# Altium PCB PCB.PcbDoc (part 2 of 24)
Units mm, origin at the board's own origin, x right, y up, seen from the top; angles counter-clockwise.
Board outline 100 x 160 mm, 10 copper layers (TOP_L1, L2, L3, L4, L5, L6, L7, L8, L9, BOTTOM_L10), stack 1.946 mm thick; 1358 components, 1149 nets, 6777 pads, 10914 vias.

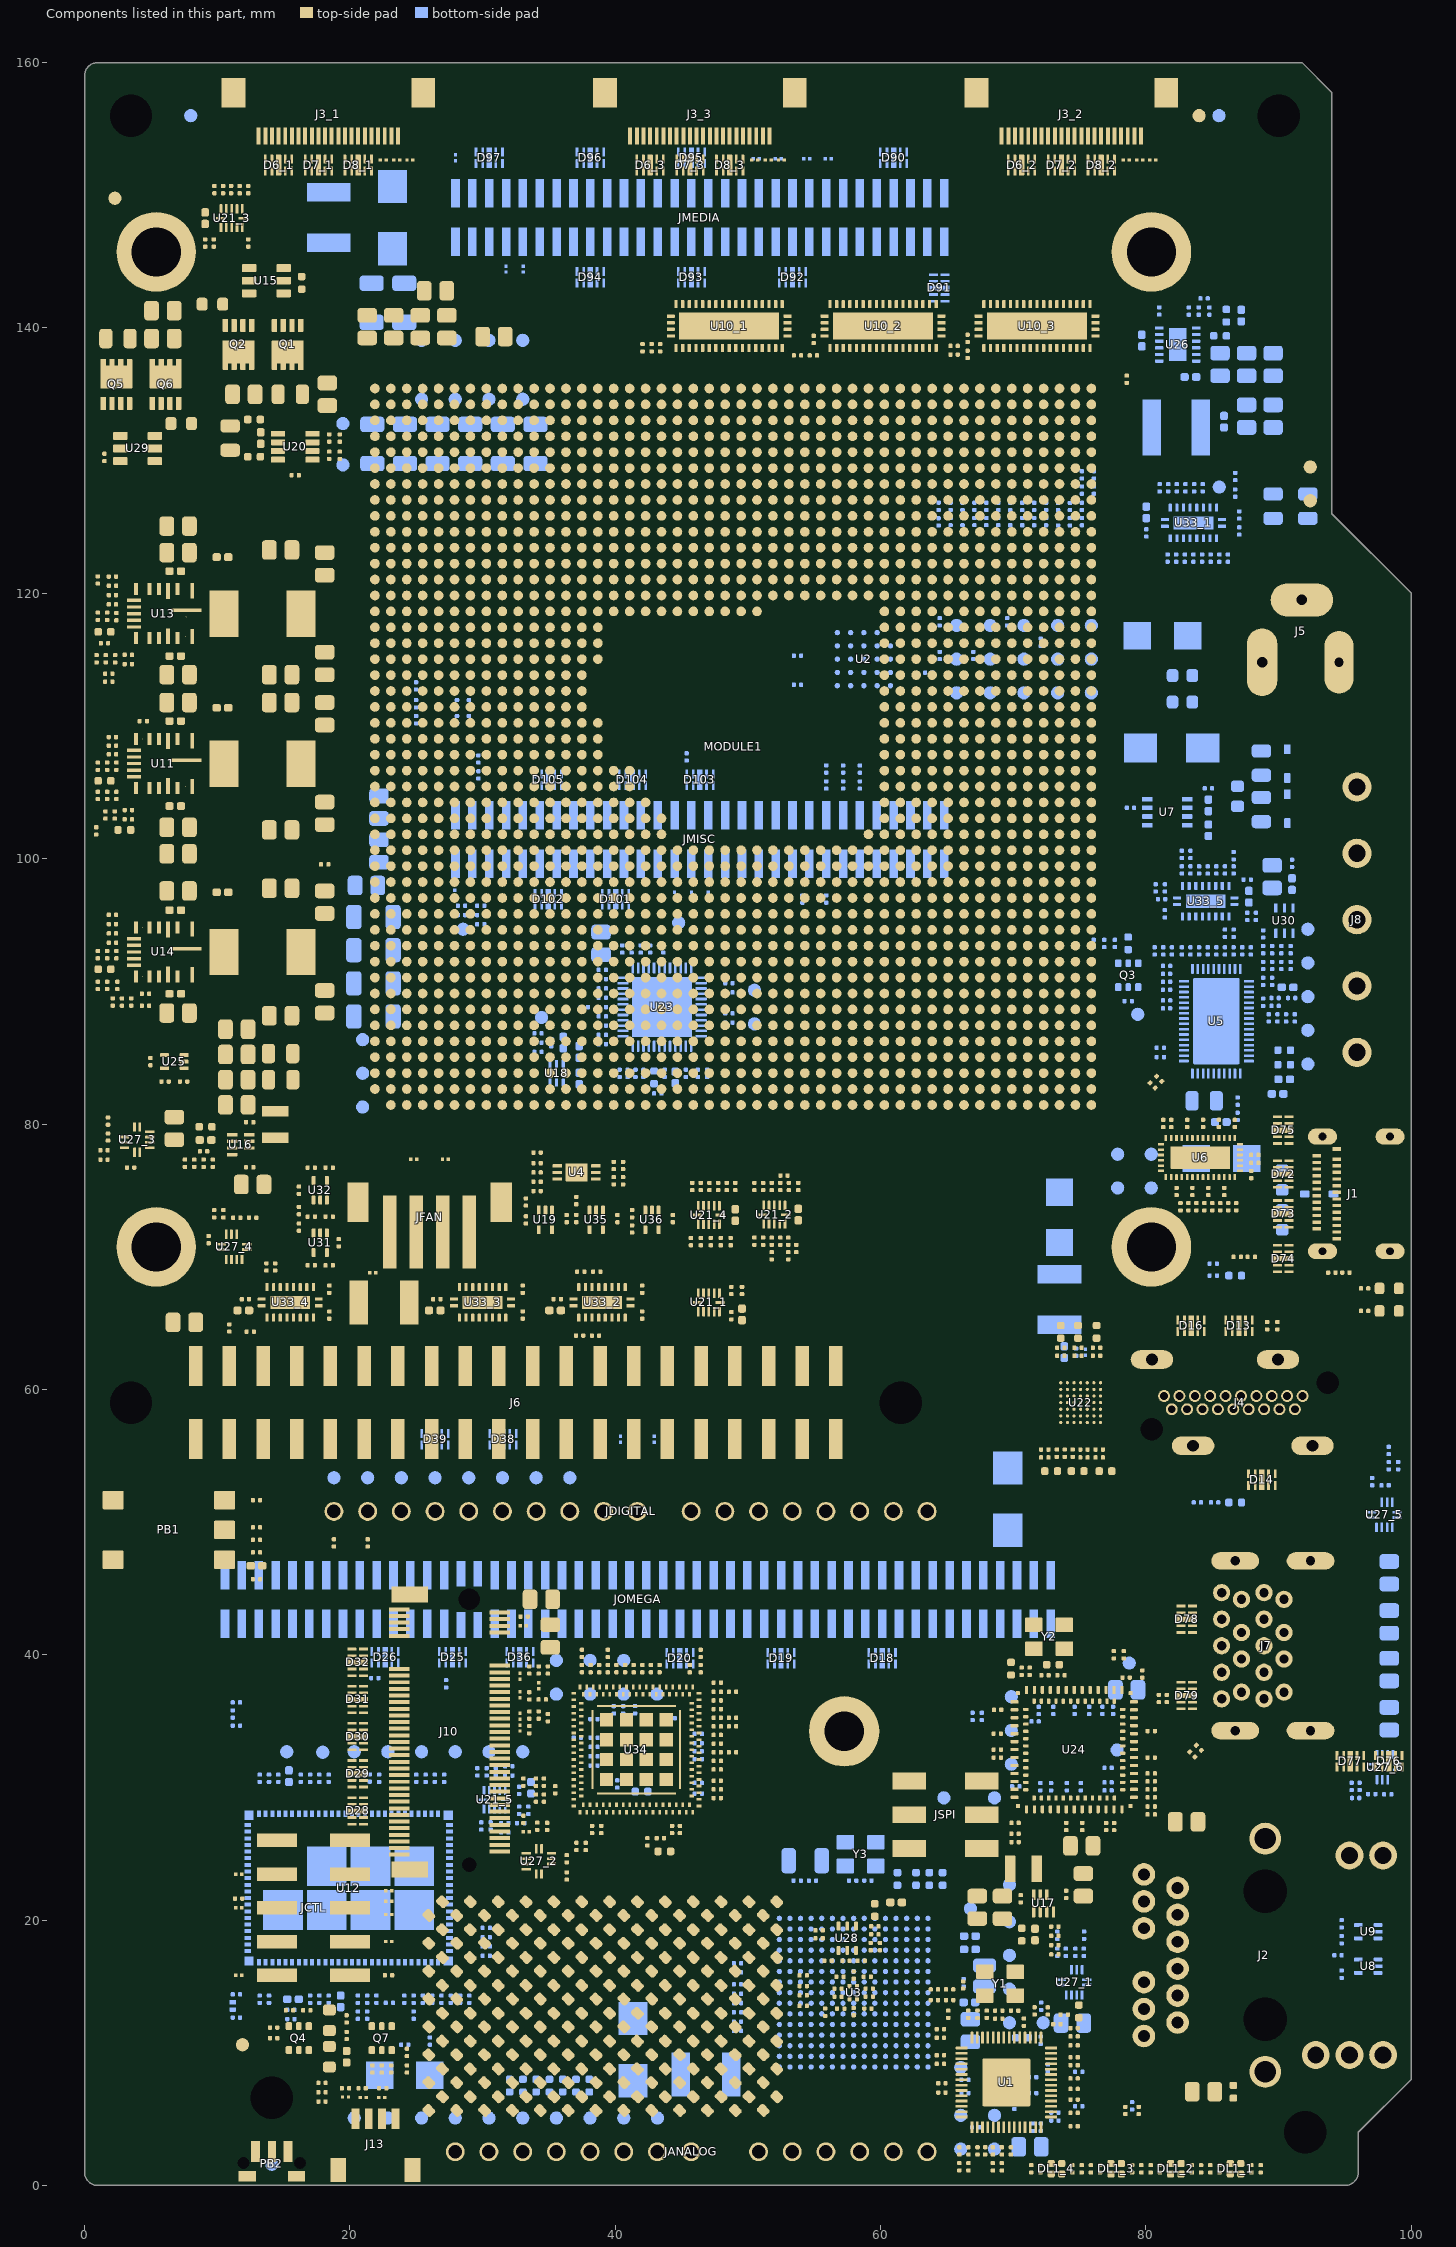
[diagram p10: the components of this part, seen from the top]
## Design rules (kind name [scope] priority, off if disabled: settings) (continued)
PolygonConnect [All] p14: thpad.connectstyle=Relief thpad.reliefconductorwidth=0.2 thpad.reliefentries=4 thpad.polygonreliefangle="90 Angle" thpad.airgapwidth=0.254 smdpad.connectstyle=Relief smdpad.reliefconductorwidth=0.15 smdpad.reliefentries=4 smdpad.polygonreliefangle="90 Angle" smdpad.airgapwidth=0.254 via.connectstyle=Direct via.reliefconductorwidth=0.254 via.reliefentries=4 via.polygonreliefangle="90 Angle" via.airgapwidth=0.254
ReturnPath ReturnPath_90Diff [All] p1: impedanceprofileid={E6B00C31-4C8E-439C-824F-D2B2CDC26F9C} _gaplimit=0
ReturnPath ReturnPath_100Diff [All] p2: impedanceprofileid={72B7EF18-E108-4503-8DFF-05138B0E1A69} _gaplimit=0
ReturnPath ReturnPath_85Diff [All] p3: impedanceprofileid={49CC0F8D-1F3C-4D86-8ACD-DA3CEB1E83F8} _gaplimit=0
ReturnPath ReturnPath_50R [All] p4: impedanceprofileid={A847A021-53BE-4886-9860-E88B412D36CD} _gaplimit=0
RoomDefinition TOP [InComponentClass('TOP')] p1: confinementstyle=ConfineIn formatcopy=TRUE lockcomponents=FALSE outline 96.248,1.5 98,1.5 98,5.9 96.248,5.9
RoomDefinition ADV7535BCBZ-RL [False vs False] p2: confinementstyle=ConfineIn formatcopy=TRUE lockcomponents=FALSE outline 72.676,61 77.075,61 77.075,57 72.676,57
RoutingVias uVIA_TOP-L1 [InDrillLayerPair('TOP_L1 - L2')] p1: holewidth=0.1 width=0.25 viastyle="Through Hole" minholewidth=0.1 minwidth=0.25 maxholewidth=0.1 maxwidth=0.25
RoutingVias uVIA_L9-BOTTOM [InDrillLayerPair('L9 - BOTTOM_L10')] p2: holewidth=0.1 width=0.25 viastyle="Through Hole" minholewidth=0.1 minwidth=0.25 maxholewidth=0.1 maxwidth=0.25
RoutingVias uVIA_L2-L3 [InDrillLayerPair('L2 - L3')] p3: holewidth=0.1 width=0.25 viastyle="Through Hole" minholewidth=0.1 minwidth=0.25 maxholewidth=0.1 maxwidth=0.25
RoutingVias uVIA_L8-L9 [InDrillLayerPair('L8 - L9')] p4: holewidth=0.1 width=0.25 viastyle="Through Hole" minholewidth=0.1 minwidth=0.25 maxholewidth=0.1 maxwidth=0.25
RoutingVias VIA_L3-L8 [InDrillLayerPair('L3 - L8')] p5: holewidth=0.2 width=0.4 viastyle="Through Hole" minholewidth=0.2 minwidth=0.4 maxholewidth=0.2 maxwidth=0.4
RoutingVias VIA_TOP-BOTTOM [InDrillLayerPair('TOP_L1 - BOTTOM_L10')] p6: holewidth=0.3 width=0.6 viastyle="Through Hole" minholewidth=0.3 minwidth=0.6 maxholewidth=0.3 maxwidth=0.6
SMDToCorner [All] p1: distance=39370
ShortCircuit ShortCircuit_ant [InNet('ANT0_29') vs InNet('GND')] p1: allowed=TRUE
ShortCircuit [All] p2: allowed=FALSE
SilkToSilkClearance [All] p1: silktosilkclearance=0.2
SilkToSolderMaskClearance [IsPad] p1: minsilkscreentomaskgap=0.15 clearancetoexposedcopper=FALSE
SolderMaskExpansion VIAtented [IsVia] p1: expansion=0.102 istentingtop=TRUE
SolderMaskExpansion [All] p2: expansion=0.05 istentingtop=FALSE
SupplyNets "Schematic Supply Nets_11" [InNet('CYPD_VDDIO')] p1: voltage=0.000
SupplyNets "Schematic Supply Nets_13" [InNet('+3V3_LIMITED')] p2: voltage=0.000
SupplyNets "Schematic Supply Nets_3" [InNet('+5V_LIMITED')] p3: voltage=0.000
SupplyNets "Schematic Supply Nets_12" [InNet('7V-24V')] p4: voltage=0.000
SupplyNets "Schematic Supply Nets_10" [InNet('+1.28V')] p5: voltage=0.000
SupplyNets "Schematic Supply Nets_9" [InNet('VBAT')] p6: voltage=0.000
SupplyNets "Schematic Supply Nets_8" [InNet('+5V')] p7: voltage=0.000
SupplyNets "Schematic Supply Nets_7" [InNet('SOM_VREG_MDPX3_1P8')] p8: voltage=0.000
SupplyNets "Schematic Supply Nets_6" [InNet('SOM_VCOIN')] p9: voltage=0.000
SupplyNets "Schematic Supply Nets_5" [InNet('+1V8')] p10: voltage=0.000
SupplyNets "Schematic Supply Nets_4" [InNet('SOM_VREG_S5S_SPX3_1P8')] p11: voltage=0.000
SupplyNets "Schematic Supply Nets_2" [InNet('+1V1')] p12: voltage=0.000
SupplyNets "Schematic Supply Nets_1" [InNet('+3V3')] p13: voltage=0.000
SupplyNets "Schematic Supply Nets" [InNet('GND')] p14: voltage=0.000
UnConnectedPin [All] p1:
UnRoutedNet [All] p1: checkbadconnections=TRUE
ViasUnderSMD [All] p1: allowed=TRUE
Width Width_50R [InNetClass('50R')] p1: maxlimit=0.254 minlimit=0.09 preferedwidth=0.254 toplayer_maxwidth=0.09 toplayer_prefwidth=0.09 bottomlayer_maxwidth=0.09 bottomlayer_prefwidth=0.09 impedanceprofiledriven=TRUE impedanceprofileid={A847A021-53BE-4886-9860-E88B412D36CD} impedanceprofilevalue=50.000000 minimp=50.000000 maximp=50.000000 favimp=50.000000
Width Width_ADV7535 [WithinRoom('ADV7535BCBZ-RL')] p2: maxlimit=20 minlimit=0.064 preferedwidth=0.127 midlayer1_minwidth=0.084 midlayer2_minwidth=0.084 midlayer3_minwidth=0.084 midlayer4_minwidth=0.084 midlayer5_minwidth=0.084 midlayer6_minwidth=0.084 midlayer7_minwidth=0.084 midlayer8_minwidth=0.084 bottomlayer_minwidth=0.084 minimp=50.000000 maximp=50.000000 favimp=50.000000
Width WIDTH_TMUX646ZECR [All] p3: maxlimit=5 minlimit=0.076 preferedwidth=0.127 midlayer1_minwidth=0.084 midlayer2_minwidth=0.084 midlayer3_minwidth=0.084 midlayer4_minwidth=0.084 midlayer5_minwidth=0.084 midlayer6_minwidth=0.084 midlayer7_minwidth=0.084 midlayer8_minwidth=0.084 bottomlayer_minwidth=0.084 minimp=50.000000 maximp=50.000000 favimp=50.000000
Width WIDTH_MIN [All] p4: maxlimit=5 minlimit=0.084 preferedwidth=0.127
20 further rules are at their usual default settings.

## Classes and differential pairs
differential pair class DIFF_MUXCAPS_USBC: USBC_SSRX1 USBC_SSRX2 USBC_SSTX1 USBC_SSTX2
net class HIGH_CLEARANCE: 7V-24V NetC76_1 NetC256_1 NetC256_2 NetC293_1 NetC302_2 NetC342_1 NetC351_1 NetC361_1 NetD4_C PA_VBUS
differential pair class TUSB_USB4_CAP: USB4_CAP_SSTX
differential pair class TUSB_USB3_CAP: USB3_CAP_SSTX
differential pair class TUSB_USB2_CAP: USB2_CAP_SSTX
differential pair class TUSB_USB1_CAP: USB1_CAP_SSTX
differential pair class TUSB_USB4: USB4_D USB4_SSRX USB4_SSTX_26
differential pair class TUSB_USB3: USB3_D USB3_SSRX USB3_SSTX_26
differential pair class TUSB_USB2: USB2_D USB2_SSRX USB2_SSTX_26
differential pair class TUSB_USB1: USB1_D USB1_SSRX USB1_SSTX_26
component class U_TRANSLATOR_4CH5: C172_5 C175_5 C220_5 R326_5 U21_5
net class 50R: ANT0_29 ANT0_PI_29 ANT1_29 ANT1_PI_29
differential pair class PCIE_USB_CAPS: TUSB_CAP_TX_26
differential pair class DIFF_PCIE_PET: PET_CAP_25
component class MODULE: TP32 TP93
net class MICROCONTROLLER_RGB: PC6 PD10 PD11 PG2 PG3 PG4 PG5 PG6 PG8 PK0 PK1 PK2
net class MICROCONTROLLER_MATRIX: PH2 PH3 PH4 PH5 PH6 PH7 PH9 PH10 PH13 PH14 PH15
component class MODULE_SAIL: TP1 TP30 TP61 TP62 TP63 TP64 TP65 TP66
component class U_LOAD_SWITCH_5V6: C179_6 C246_6 U27_6
component class U_LOAD_SWITCH_5V5: C179_5 C246_5 U27_5
component class U_TRANSLATOR_4CH4: C172_4 C175_4 C220_4 R326_4 U21_4
differential pair class DIFF_MUX_USBC: MUX_SSRX1_30 MUX_SSRX2_30 MUX_TX1_30 MUX_TX2_30
channel class TRANSLATOR_4CH: U_TRANSLATOR_4CH1 U_TRANSLATOR_4CH2 U_TRANSLATOR_4CH3 U_TRANSLATOR_4CH4 U_TRANSLATOR_4CH5
component class U_TRANSLATOR_4CH3: C172_3 C175_3 C220_3 R326_3 U21_3
component class U_TRANSLATOR_4CH2: C172_2 C175_2 C220_2 R326_2 U21_2
component class U_TRANSLATOR_4CH1: C172_1 C175_1 C220_1 R326_1 U21_1
differential pair class DIFF_PCIE_DOWN1: PCIE1_REFCLK0 PCIE1_RX0 PCIE1_TX0 PCIE1_TX0_25 PCIE1_TX0_CAP
differential pair class DIFF_MUX2_OUTA: A_CLK_3 A_LN0_3 A_LN1_3 A_LN2_3 A_LN3_3
differential pair class DIFF_PCIE_DOWN2: PCIE2_REFCLK0 PCIE2_RX0 PCIE2_TX0 PCIE2_TX0_25 PCIE2_TX0_CAP
differential pair class DIFF_MUX2_OUTB: B_CLK_3 B_LN0_3 B_LN1_3 B_LN2_3 B_LN3_3
differential pair class DIFF_MUX1_OUTB: B_CLK_1 B_LN0_1 B_LN1_1 B_LN2_1 B_LN3_1
differential pair class DIFF_MUX0_OUTB: B_CLK_2 B_LN0_2 B_LN1_2 B_LN2_2 B_LN3_2
differential pair class DIFF_MUX0_OUTA: A_CLK_2 A_LN0_2 A_LN1_2 A_LN2_2 A_LN3_2
differential pair class DIFF_MD_USB1: MD_USB1_2.0.HS_D_1
differential pair class DIFF_MD_USB0: MD_USB0_3.1.HS_D_1 MD_USB0_3.1.SS_RX_1 MD_USB0_3.1.SS_TX_1
differential pair class DIFF_MD_PCIE0: MD_PCIE0_2LANES.REFCLK_1 MD_PCIE0_2LANES.RX0_1 MD_PCIE0_2LANES.RX1_1 MD_PCIE0_2LANES.TX0_1 MD_PCIE0_2LANES.TX1_1
differential pair class DIFF_MD_DSI0: DSI0_CK DSI0_L0 DSI0_L1 DSI0_L2 DSI0_L3
differential pair class DIFF_MD_CSI2: CSI2_CK CSI2_L0 CSI2_L1 CSI2_L2 CSI2_L3
differential pair class DIFF_MD_CSI1: CSI1_CK CSI1_L0 CSI1_L1 CSI1_L2 CSI1_L3
differential pair class DIFF_MD_CSI0: CSI0_CK CSI0_L0 CSI0_L1 CSI0_L2 CSI0_L3
differential pair class DIFF_ETHPHY: ETH_PHY_TRX0 ETH_PHY_TRX1 ETH_PHY_TRX2 ETH_PHY_TRX3
net class NET_DIFF_USB: USBC_SSRX1_N USBC_SSRX1_P USBC_SSRX2_N USBC_SSRX2_P USBC_SSTX1_N USBC_SSTX1_P USBC_SSTX2_N USBC_SSTX2_P
net class NET_DIFF_USBC: MUX_SSRX1_30_N MUX_SSRX1_30_P MUX_SSRX2_30_N MUX_SSRX2_30_P MUX_TX1_30_N MUX_TX1_30_P MUX_TX2_30_N MUX_TX2_30_P
net class NET_DIFF_SGMII: MD_SGMII0.RX_1_N MD_SGMII0.RX_1_P MD_SGMII0.TX_1_N MD_SGMII0.TX_1_P
net class NET_DIFF_PCIE: MD_PCIE0_2LANES.REFCLK_1_N MD_PCIE0_2LANES.REFCLK_1_P MD_PCIE0_2LANES.RX0_1_N MD_PCIE0_2LANES.RX0_1_P MD_PCIE0_2LANES.RX1_1_N MD_PCIE0_2LANES.RX1_1_P MD_PCIE0_2LANES.TX0_1_N MD_PCIE0_2LANES.TX0_1_P MD_PCIE0_2LANES.TX1_1_N MD_PCIE0_2LANES.TX1_1_P MD_PCIE1_4LANES.REFCLK_1_N MD_PCIE1_4LANES.REFCLK_1_P MD_PCIE1_4LANES.RX0_1_N MD_PCIE1_4LANES.RX0_1_P MD_PCIE1_4LANES.RX1_1_N MD_PCIE1_4LANES.RX1_1_P MD_PCIE1_4LANES.RX2_1_N MD_PCIE1_4LANES.RX2_1_P MD_PCIE1_4LANES.RX3_1_N MD_PCIE1_4LANES.RX3_1_P MD_PCIE1_4LANES.TX0_1_N MD_PCIE1_4LANES.TX0_1_P MD_PCIE1_4LANES.TX1_1_N MD_PCIE1_4LANES.TX1_1_P MD_PCIE1_4LANES.TX2_1_N MD_PCIE1_4LANES.TX2_1_P MD_PCIE1_4LANES.TX3_1_N MD_PCIE1_4LANES.TX3_1_P
net class NET_DIFF_MD: EDP0_AUX_N EDP0_AUX_P EDP0_TX0_N EDP0_TX0_P EDP0_TX1_N EDP0_TX1_P EDP0_TX2_N EDP0_TX2_P EDP0_TX3_N EDP0_TX3_P
net class NET_DIFF_HDMI: HDMI_CLK_N HDMI_CLK_P HDMI_TX0_N HDMI_TX0_P HDMI_TX1_N HDMI_TX1_P HDMI_TX2_N HDMI_TX2_P
net class NET_DIFF_CSI_DSI: A_CLK_1_N A_CLK_1_P A_CLK_2_N A_CLK_2_P A_CLK_3_N A_CLK_3_P A_LN0_1_N A_LN0_1_P A_LN0_2_N A_LN0_2_P A_LN0_3_N A_LN0_3_P A_LN1_1_N A_LN1_1_P A_LN1_2_N A_LN1_2_P A_LN1_3_N A_LN1_3_P A_LN2_1_N A_LN2_1_P A_LN2_2_N A_LN2_2_P A_LN2_3_N A_LN2_3_P A_LN3_1_N A_LN3_1_P A_LN3_2_N A_LN3_2_P A_LN3_3_N A_LN3_3_P B_CLK_1_N B_CLK_1_P B_CLK_2_N B_CLK_2_P B_CLK_3_N B_CLK_3_P B_LN0_1_N B_LN0_1_P B_LN0_2_N B_LN0_2_P B_LN0_3_N B_LN0_3_P B_LN1_1_N B_LN1_1_P B_LN1_2_N B_LN1_2_P B_LN1_3_N B_LN1_3_P B_LN2_1_N B_LN2_1_P B_LN2_2_N B_LN2_2_P B_LN2_3_N B_LN2_3_P B_LN3_1_N B_LN3_1_P B_LN3_2_N B_LN3_2_P B_LN3_3_N B_LN3_3_P CSI0_CK_N CSI0_CK_P CSI0_L0_N CSI0_L0_P CSI0_L1_N CSI0_L1_P CSI0_L2_N CSI0_L2_P CSI0_L3_N CSI0_L3_P CSI1_CK_N CSI1_CK_P CSI1_L0_N CSI1_L0_P CSI1_L1_N CSI1_L1_P CSI1_L2_N CSI1_L2_P CSI1_L3_N CSI1_L3_P CSI2_CK_N CSI2_CK_P CSI2_L0_N CSI2_L0_P CSI2_L1_N CSI2_L1_P CSI2_L2_N CSI2_L2_P CSI2_L3_N CSI2_L3_P DSI0_CK_N DSI0_CK_P DSI0_L0_N DSI0_L0_P DSI0_L1_N DSI0_L1_P DSI0_L2_N DSI0_L2_P DSI0_L3_N DSI0_L3_P
net class DIFF_USB: MD_USB0_3.1.HS_D_1_N MD_USB0_3.1.HS_D_1_P MD_USB0_3.1.SS_RX_1_N MD_USB0_3.1.SS_RX_1_P MD_USB0_3.1.SS_TX_1_N MD_USB0_3.1.SS_TX_1_P MD_USB1_2.0.HS_D_1_N MD_USB1_2.0.HS_D_1_P
net class DIFF_ETHPHY: ETH_PHY_TRX0_N ETH_PHY_TRX0_P ETH_PHY_TRX1_N ETH_PHY_TRX1_P ETH_PHY_TRX2_N ETH_PHY_TRX2_P ETH_PHY_TRX3_N ETH_PHY_TRX3_P
net class NET_PCIE_UP: CLKREQ_N_3V3_24 MD_PCIE0_2LANES.REFCLK_1_N MD_PCIE0_2LANES.REFCLK_1_P MD_PCIE0_2LANES.RX0_1_N MD_PCIE0_2LANES.RX0_1_P MD_PCIE0_2LANES.RX1_1_N MD_PCIE0_2LANES.RX1_1_P MD_PCIE0_2LANES.TX0_1_N MD_PCIE0_2LANES.TX0_1_P MD_PCIE0_2LANES.TX1_1_N MD_PCIE0_2LANES.TX1_1_P RST_N_3V3_24
net class NET_3V3: +3V3
net class NET_1V8_SOM: SOM_VREG_MDPX3_1P8
net class NET_I2C_SYSTEM_3V3: MD_QUP1_SE4_I2C_3V3.SCL_1 MD_QUP1_SE4_I2C_3V3.SDA_1
net class NET_I2C_SYSTEM_1V8: MD_GPIO_45 MD_GPIO_46
component class T8CH_3: C173_3 C174_3 C176_3 R168_3 U33_3
component class T8CH_5: C173_5 C174_5 C176_5 R168_5 U33_5
component class T8CH_1: C173_1 C174_1 C176_1 R168_1 U33_1
differential pair class DIFF_HDMI: HDMI_CLK HDMI_TX0 HDMI_TX1 HDMI_TX2
differential pair class DIFF_MD_SGMII: MD_SGMII0.RX_1 MD_SGMII0.TX_1
differential pair class DIFF_MD_PCIE1: MD_PCIE1_4LANES.REFCLK_1 MD_PCIE1_4LANES.RX0_1 MD_PCIE1_4LANES.RX1_1 MD_PCIE1_4LANES.RX2_1 MD_PCIE1_4LANES.RX3_1 MD_PCIE1_4LANES.TX0_1 MD_PCIE1_4LANES.TX1_1 MD_PCIE1_4LANES.TX2_1 MD_PCIE1_4LANES.TX3_1
differential pair class DIFF_MD_EDP: EDP0_AUX EDP0_TX0 EDP0_TX1 EDP0_TX2 EDP0_TX3
channel class TRANSLATOR_8CH: T8CH_1 T8CH_2 T8CH_3 T8CH_4 T8CH_5
channel class MIPI_MUX: U_MIPI_MUX1 U_MIPI_MUX2 U_MIPI_MUX3
channel class MIPI_FLAT_22PIN: U_MIPI_FLAT_22PIN1 U_MIPI_FLAT_22PIN2 U_MIPI_FLAT_22PIN3
channel class LOAD_SWITCH_5V: U_LOAD_SWITCH_5V1 U_LOAD_SWITCH_5V2 U_LOAD_SWITCH_5V3 U_LOAD_SWITCH_5V4 U_LOAD_SWITCH_5V5 U_LOAD_SWITCH_5V6
channel class LED_RGB: U_LED_RGB1 U_LED_RGB2 U_LED_RGB3 U_LED_RGB4
net class NET_SOM_MD_GPIO_LPASS: I2S_DATA0 I2S_DATA1 I2S_SCK I2S_WS MD_LPASS_GPIO_110 MD_LPASS_GPIO_111 MD_LPASS_GPIO_112 MD_LPASS_GPIO_113 MD_LPASS_GPIO_115 MD_LPASS_GPIO_120 MD_LPASS_GPIO_121 MD_LPASS_GPIO_122 MD_LPASS_GPIO_123 MD_LPASS_GPIO_125 MD_LPASS_GPIO_126 MD_LPASS_GPIO_127 MD_LPASS_GPIO_129 MD_LPASS_GPIO_130 MD_LPASS_GPIO_131 MD_LPASS_GPIO_132 NetMODULE1_B31 NetMODULE1_D32 NetMODULE1_E29
net class NET_SOM_SAIL_QSPI0: NetMODULE1_BA29 NetMODULE1_BB28 NetMODULE1_BB29 NetMODULE1_BC28 NetMODULE1_BC29 NetMODULE1_BD28 NetMODULE1_BD29 NetMODULE1_BE28 NetMODULE1_BE29 NetMODULE1_BF28 NetMODULE1_BF29
net class NET_SOM_SAIL_IO: NetMODULE1_AK40 NetMODULE1_AK41 NetMODULE1_AL40 NetMODULE1_AT44 NetMODULE1_AT46 NetMODULE1_AU45 NetMODULE1_AV46 NetMODULE1_AY34 NetMODULE1_BA33 NetMODULE1_BA35 NetMODULE1_BA45 NetMODULE1_BA46 NetMODULE1_BB33 NetMODULE1_BB39 NetMODULE1_BC33 NetMODULE1_BC40 NetMODULE1_BD33 NetMODULE1_BD35 NetMODULE1_BD37 NetMODULE1_BD38 NetMODULE1_BD40 NetMODULE1_BE33 NetMODULE1_BE35 NetMODULE1_BE36 NetMODULE1_BE38 NetMODULE1_BF33 NetMODULE1_BF35 NetMODULE1_BF36 NetMODULE1_BF38 NetMODULE1_BF39 RTSS_IO_4 RTSS_IO_6 RTSS_IO_7 RTSS_IO_10 RTSS_IO_11 RTSS_IO_12 RTSS_IO_14 RTSS_IO_15 RTSS_IO_16 RTSS_IO_17 RTSS_IO_18 RTSS_IO_21 RTSS_IO_51 RTSS_IO_58_FORCE_USB_BOOT_SPX3_1P8_1
net class NET_SOM_SAIL_BOOT: RTSS_IO_4 RTSS_IO_6 RTSS_IO_7 RTSS_IO_10 RTSS_IO_11 RTSS_IO_12 RTSS_IO_14 RTSS_IO_15 RTSS_IO_16 RTSS_IO_17 RTSS_IO_18 RTSS_IO_21 RTSS_IO_51
net class NET_SOM_MD_USB1: MD_USB1_2.0.HS_D_1_N MD_USB1_2.0.HS_D_1_P
net class NET_SOM_MD_USB0: MD_USB0_3.1.HS_D_1_N MD_USB0_3.1.HS_D_1_P MD_USB0_3.1.SS_RX_1_N MD_USB0_3.1.SS_RX_1_P MD_USB0_3.1.SS_TX_1_N MD_USB0_3.1.SS_TX_1_P
net class NET_SOM_MD_SGMII0: GPIO_4 GPIO_5 GPIO_6 GPIO_50 MD_SGMII0.RX_1_N MD_SGMII0.RX_1_P MD_SGMII0.TX_1_N MD_SGMII0.TX_1_P
net class NET_SOM_MD_PCIE1: GPIO_21 GPIO_22 GPIO_23 MD_PCIE1_4LANES.REFCLK_1_N MD_PCIE1_4LANES.REFCLK_1_P MD_PCIE1_4LANES.RX0_1_N MD_PCIE1_4LANES.RX0_1_P MD_PCIE1_4LANES.RX1_1_N MD_PCIE1_4LANES.RX1_1_P MD_PCIE1_4LANES.RX2_1_N MD_PCIE1_4LANES.RX2_1_P MD_PCIE1_4LANES.RX3_1_N MD_PCIE1_4LANES.RX3_1_P MD_PCIE1_4LANES.TX0_1_N MD_PCIE1_4LANES.TX0_1_P MD_PCIE1_4LANES.TX1_1_N MD_PCIE1_4LANES.TX1_1_P MD_PCIE1_4LANES.TX2_1_N MD_PCIE1_4LANES.TX2_1_P MD_PCIE1_4LANES.TX3_1_N MD_PCIE1_4LANES.TX3_1_P
net class NET_SOM_MD_PCIE0: CLKREQ_N_1V8 GPIO_0 GPIO_2 MD_PCIE0_2LANES.REFCLK_1_N MD_PCIE0_2LANES.REFCLK_1_P MD_PCIE0_2LANES.RX0_1_N MD_PCIE0_2LANES.RX0_1_P MD_PCIE0_2LANES.RX1_1_N MD_PCIE0_2LANES.RX1_1_P MD_PCIE0_2LANES.TX0_1_N MD_PCIE0_2LANES.TX0_1_P MD_PCIE0_2LANES.TX1_1_N MD_PCIE0_2LANES.TX1_1_P
net class NET_SOM_MD_GPIO: CLKREQ_N_1V8 CTS_1V8 GPIO_0 GPIO_2 GPIO_4 GPIO_5 GPIO_6 GPIO_7 GPIO_8 GPIO_21 GPIO_22 GPIO_23 GPIO_50 GPIO_53 GPIO_66 GPIO_76 GPIO_91 GPIO_97 GPIO_98 GPIO_102 I2S_DATA0 I2S_DATA1 I2S_SCK I2S_WS MD_CCI_I2C0.SCL_1 MD_CCI_I2C0.SDA_1 MD_CCI_I2C2.SCL_1 MD_CCI_I2C2.SDA_1 MD_CCI_I2C3.SCL_1 MD_CCI_I2C3.SDA_1 MD_CCI_I2C4.SCL_1 MD_CCI_I2C4.SDA_1 MD_GPIO_3_1 MD_GPIO_10 MD_GPIO_11 MD_GPIO_12 MD_GPIO_13 MD_GPIO_14 MD_GPIO_15 MD_GPIO_16_1 MD_GPIO_17 MD_GPIO_18 MD_GPIO_19 MD_GPIO_20 MD_GPIO_24_1 MD_GPIO_25 MD_GPIO_26 MD_GPIO_27 MD_GPIO_28 MD_GPIO_29 MD_GPIO_30 MD_GPIO_33 MD_GPIO_34 MD_GPIO_35 MD_GPIO_36 MD_GPIO_37 MD_GPIO_38 MD_GPIO_39 MD_GPIO_40 MD_GPIO_41_1 MD_GPIO_42_1 MD_GPIO_43 MD_GPIO_44 MD_GPIO_45 MD_GPIO_46 MD_GPIO_47_1 MD_GPIO_48_1 MD_GPIO_49_1 MD_GPIO_51_1 MD_GPIO_52 MD_GPIO_54_1 MD_GPIO_55_1 MD_GPIO_56_1 MD_GPIO_63_1 MD_GPIO_64_1 MD_GPIO_65_1 MD_GPIO_67_1 MD_GPIO_68_1 MD_GPIO_69_1 MD_GPIO_70_1 MD_GPIO_71_1 MD_GPIO_73_1 MD_GPIO_74_1 MD_GPIO_75_1 MD_GPIO_77_1 MD_GPIO_78_1 MD_GPIO_79_1 MD_GPIO_80_1 MD_GPIO_81_1 MD_GPIO_82_1 MD_GPIO_83_1 MD_GPIO_85 MD_GPIO_86 MD_GPIO_87 MD_GPIO_88_1 MD_GPIO_89_1 MD_GPIO_90_1 MD_GPIO_92_1 MD_GPIO_93_1 MD_GPIO_94_1 MD_GPIO_95_1 MD_GPIO_96_1 MD_GPIO_99_2 MD_GPIO_100_1 MD_GPIO_101_1 MD_GPIO_103_1 MD_GPIO_104_1 MD_GPIO_105_1 MD_GPIO_106_1 MD_GPIO_107_1 MD_GPIO_108_1 MD_GPIO_109_1 MD_LPASS_GPIO_110 MD_LPASS_GPIO_111 MD_LPASS_GPIO_112 MD_LPASS_GPIO_113 MD_LPASS_GPIO_115 MD_LPASS_GPIO_120 MD_LPASS_GPIO_121 MD_LPASS_GPIO_122 MD_LPASS_GPIO_123 MD_LPASS_GPIO_125 MD_LPASS_GPIO_126 MD_LPASS_GPIO_127 MD_LPASS_GPIO_129 MD_LPASS_GPIO_130 MD_LPASS_GPIO_131 MD_LPASS_GPIO_132 NetMODULE1_B31 NetMODULE1_D32 NetMODULE1_E29
net class NET_SOM_MD_EDP0: EDP0_AUX_N EDP0_AUX_P EDP0_TX0_N EDP0_TX0_P EDP0_TX1_N EDP0_TX1_P EDP0_TX2_N EDP0_TX2_P EDP0_TX3_N EDP0_TX3_P
net class NET_SOM_MD_BOOT: GPIO_7 GPIO_8 GPIO_53 GPIO_66 GPIO_76 GPIO_91 GPIO_97 GPIO_98 GPIO_102
net class NET_HDMI: HDMI_CLK_N HDMI_CLK_P HDMI_TX0_N HDMI_TX0_P HDMI_TX1_N HDMI_TX1_P HDMI_TX2_N HDMI_TX2_P NetD16_1 NetD16_2 NetD16_4 NetD16_5
net class MICROCONTROLLER: BOOT0 MD_CCI_I2C3.SCL_1 MD_CCI_I2C3.SDA_1 MD_GPIO_42_1 MD_GPIO_47_1 MD_GPIO_63_1 MD_GPIO_69_1 MD_GPIO_70_1 MD_GPIO_71_1 MD_GPIO_78_1 MD_GPIO_92_1 MD_GPIO_95_1 MD_GPIO_96_1 NetC97_1 NetC105_1 NetC261_1 NetC264_1 NetR140_2 NetR151_2 NetR152_2 NetR153_2 NetR382_2 NetR383_2 NetR384_2 NetR385_2 NRST PA0 PA1 PA2 PA4 PA5 PA6 PA7 PA8 PA9 PA10 PA11 PA12 PA13 PA14 PA15_12 PB0 PB1 PB2 PB3 PB4 PB5 PB6 PB7 PB10 PB11 PB12 PB13 PB14 PB15 PC0 PC1 PC2 PC3 PC6 PC7 PC8 PC9 PC10 PC11 PC12 PD0 PD1 PD3 PD5 PD9 PD10 PD11 PD12 PD13 PD14 PD15 PE1 PE2 PE3 PE4 PE5 PE6 PE7 PE8 PE12 PE13 PE14 PE15 PF0 PF1 PF4 PF6 PF7 PF14 PG2 PG3 PG4 PG5 PG6 PG8 PG9 PG10 PG11 PG12 PG13 PG14 PG15 PH2 PH3 PH4 PH5 PH6 PH7 PH8 PH9 PH10 PH11 PH12 PH13 PH14 PH15 PI2 PI5 PI7 PI8 PI9 PI11 PK0 PK1 PK2 PK10 PK11 PK13
component class U_WIFI_BLE: C128 C129 C130 C131 C132 C133 C314 C328 C329 C330 C331 C332 C349 L9 R23 R24 R312 R313 R314 R316 R343 R344 R345 R347 R348 R353 R377 R378 R379 R380 R381 R388 R427 R428 R429 R438 R439 R440 R441 R442 R443 R444 R445 R446 R447 R448 R461 R462 R463 R464 R465 R466 R467 R469 R470 R471 U12
component class U_USB: C35 C37 C50 C51 C52 C53 C147 C171 R25 R26 R154 R182 R436 R437 R449 R450 R451 R452 R453 R454 R473 R474 TP2 TP3 TP4 TP5
component class U_USB_USBC: C343 C344 D1 D72 D73 D74 D75 J1
component class U_USB_USBA: D76 D77 D78 D79 J7
component class U_USB_PD_CONTROLLER: C40 C41 C42 C43 C44 C45 C46 C47 C48 C49 C84 C302 C303 C304 C308 C350 C351 C352 C353 C354 C355 C356 C357 C358 C359 C360 D4 D9 DL2 L10 R86 R87 R88 R89 R90 R91 R92 R99 R100 R101 R102 R103 R104 R106 R113 R114 R161 R172 R173 R178 R186 R187 R234 R235 R236 R237 R244 R246 R247 R271 R274 R275 R276 R324 R325 R330 R331 R332 R333 R334 R335 R367 R368 R369 R370 R398 R460 R498 R499 R500 R501 R502 R503 R504 R505 TP29 TP36 TP37 TP38 TP39 U5 U26 U30
component class U_USB_MUX: C54 C55 C56 C57 C58 C59 C60 R93 R94 R95 R96 R97 R98 R406 R407 R475 R476 U6
component class T8CH_2: C173_2 C174_2 C176_2 R168_2 U33_2
component class T8CH_4: C173_4 C174_4 C176_4 R168_4 U33_4
component class U_STM32: C63 C64 C65 C97 C105 C106 C107 C108 C259 C260 C261 C262 C263 C264 C265 C266 C267 C268 C269 C270 C272 C273 C275 C277 C279 C281 C282 C285 C286 C287 C288 C291 L6 L21 LOVE R181 R218 R351 R352 R371 R372 R373 R374 R375 R376 R382 R383 R384 R385 R434 R435 TP35 TP67 TP68 TP70 TP71 TP90 TP91 TP92 U3 Y3 Y4
component class MODULE_STRAPS_SAIL: R31 R32 R33 R34 R35 R36 R37 R38 R39 R40 R41 R42 R43 R44 R45 R46 R47 R48 R49 R50 R51 R52 R53 R54 R55 R56
component class MODULE_STRAPS_MD: R1 R2 R3 R4 R5 R12 R13 R14 R15 R16 R17 R18 R19 R20 R27 R28 R29 R30 R115 R116
component class MODULE_PWR: C38 C39 C83 C111 C115 C177 C178 C249 C250 C251 C252 R399 R400 TP33 TP34 TP88
component class MODULE_CONTROL: C94 C101 C257 C258 C278 R156 R157 R163 R180 R220 R222 R223 R402 R430 R431 R432 R489 TP69 U4 U19 U35 U36
component class MODULE_SAIL_FLASH: C1 C2 C3 R57 R58 R59 R60 R61 TP25 TP26 TP27 TP28 TP31 TP50 TP51 TP52 TP53 TP54 TP55 TP56 TP57 TP_FLASH_SAIL_1V8 TP_FLASH_SAIL_GND U2
component class U_QWIIC: C271 D80 D81 D82 J13 TP72 TP73
component class U_PUSHBUTTONS: C205 PB1 PB2 R401
component class U_POWER: C221 C222 C256 C292 C293 C294 C300 C301 C339 C340 D5 D22 D23 DL3 J5 J8 Q1 Q2 Q3 Q5 Q6 R21 R22 R105 R150 R212 R213 R214 R215 R229 R230 R231 R232 R233 R245 R248 R249 R265 R272 R273 R336 R337 R338 R339 R340 R341 R397 R472 R496 R497 TP60 TP74 TP75 TP76 TP77 TP78 TP79 TP80 TP81 TP82 TP84 U15 U20 U29
component class U_POWER_SOM: C75 C76 C77 C78 C79 C80 C81 C82 C85 C86 C87 C88 C89 C90 C91 C92 C93 C95 C140 C141 C142 C143 C144 C145 C148 C149 C312 C313 C315 C316 C317 C318 C319 C320 L3 L4 R117 R118 R119 R120 R121 R123 R124 R126 R127 R128 R132 R133 R238 R239 R240 R241 R354 R355 R357 R359 R360 R403 R404 R420 R421 R426 R480 U11 U13
component class U_POWER_DCDC_CARRIER: C96 C98 C99 C100 C102 C103 C104 C114 C116 C117 C118 C119 C120 C121 C122 C123 C124 C125 C126 C127 C137 C138 C139 C187 C201 C223 C255 C276 C311 C321 C334 C335 C336 C337 C345 L5 L7 L8 R107 R129 R130 R131 R134 R135 R137 R139 R141 R142 R144 R145 R146 R147 R148 R149 R217 R221 R242 R243 R356 R358 R405 TP83 TP85 TP86 U14 U16 U17 U18
component class U_PCIE: R315 R319 R320 R321 R322 R323 R327 R328 R329 R468
component class U_PCIE_USB: C113 C180 C181 C182 C183 C184 C185 C186 C188 C189 C190 C191 C192 C193 C194 C195 C196 C197 C198 C199 C200 C202 C203 C204 C206 C207 C208 C210 C211 C212 C213 C214 C215 C216 C218 C219 C280 C283 C284 C289 C290 C297 C298 C324 C325 L18 R189 R190 R191 R192 R193 R194 R318 TP6 TP7 TP8 TP9 TP10 TP11 TP12 U24 Y2
component class U_PCIE_PACKET_SWITCH: C228 C229 C230 C231 C232 C233 C234 C235 C236 C237 C238 C239 C240 C241 C242 C243 C244 C245 C299 C307 C309 C310 C322 C323 C326 C327 L19 L20 R6 R7 R8 R9 R10 R11 R136 R138 R143 R185 R209 R210 R211 R286 R287 R288 R289 R290 R291 R292 R293 R294 R295 R296 R297 R298 R299 R300 R301 R302 R303 R304 R305 R306 R307 R308 R309 R310 R311 TP13 TP14 TP15 TP16 TP17 TP18 TP19 TP20 TP21 TP22 TP23 TP24 U34
component class U_PCIE_NVME: C224 C225 C226 C227 D27 D28 D29 D30 D31 D32 D33 D34 D35 D40 D41 D42 H5 J10 R179 R183 R224 R225 R226 R414 R415 R416 R417 R418 R419 TP87
component class U_MIPI: R162 R165 R268 R386 R387 R389 R390 R391 R392 R393 R394 R395 R396
component class U_MIPI_MUX3: C69_3 U10_3
component class U_MIPI_MUX2: C69_2 U10_2
component class U_MIPI_MUX1: C69_1 U10_1
component class U_MIPI_FLAT_22PIN3: D6_3 D7_3 D8_3 D10_3 D11_3 D15_3 J3_3
component class U_MIPI_FLAT_22PIN2: D6_2 D7_2 D8_2 D10_2 D11_2 D15_2 J3_2
component class U_MIPI_FLAT_22PIN1: D6_1 D7_1 D8_1 D10_1 D11_1 D15_1 J3_1
component class U_MICROCONTROLLER: R140 R151 R152 R153 R184 R361 R362 R363 R364 R365 R366 R408 R409 R410 R411 R412
component class U_LOAD_SWITCH_5V4: C179_4 C246_4 U27_4
component class U_LOAD_SWITCH_5V3: C179_3 C246_3 U27_3
component class U_LOAD_SWITCH_5V2: C179_2 C246_2 U27_2
component class U_LOAD_SWITCH_5V1: C179_1 C246_1 U27_1
component class U_LED_RGB4: DL1_4 R205_4 R206_4 R207_4 R208_4
component class U_LED_RGB3: DL1_3 R205_3 R206_3 R207_3 R208_3
component class U_LED_RGB2: DL1_2 R205_2 R206_2 R207_2 R208_2
component class U_LED_RGB1: DL1_1 R205_1 R206_1 R207_1 R208_1
component class U_LED_MATRIX: LED1 LED2 LED3 LED4 LED5 LED6 LED7 LED8 LED9 LED10 LED11 LED12 LED13 LED14 LED15 LED16 LED17 LED18 LED19 LED20 LED21 LED22 LED23 LED24 LED25 LED26 LED27 LED28 LED29 LED30 LED31 LED32 LED33 LED34 LED35 LED36 LED37 LED38 LED39 LED40 LED41 LED42 LED43 LED44 LED45 LED46 LED47 LED48 LED49 LED50 LED51 LED52 LED53 LED54 LED55 LED56 LED57 LED58 LED59 LED60 LED61 LED62 LED63 LED64 LED65 LED66 LED67 LED68 LED69 LED70 LED71 LED72 LED73 LED74 LED75 LED76 LED77 LED78 LED79 LED80 LED81 LED82 LED83 LED84 LED85 LED86 LED87 LED88 LED89 LED90 LED91 LED92 LED93 LED94 LED95 LED96 LED97 LED98 LED99 LED100 LED101 LED102 LED103 LED104 R108 R195 R196 R197 R198 R199 R200 R201 R202 R203 R204
component class U_HEATSINK_FAN: C305 C306 D69 D70 D71 F1 H1 H2 H3 H4 JFAN R259 R260 R261 R262 R263 R264 R455 R456 U31 U32
component class U_HEADERS_UNO: D2 F2 JANALOG JDIGITAL JSPI
component class U_HEADERS_JMEDIA_JMISC: D43 D83 D84 D85 D86 D87 D88 D89 D90 D91 D92 D93 D94 D95 D96 D97 D98 D99 D100 D101 D102 D103 D104 D105 D106 F3 JMEDIA JMISC R508 R509
component class U_HEADERS_JHAT: J6 R122 R169 R170 R171 R422 R423 R424 R425
component class U_HEADERS_JCTL: C70 D61 D62 D63 D64 D65 D66 D67 JCTL Q4 R166 R317 R457 R458 R459 R486 TP58 TP59
component class U_HEADERS_JALFA_JBETA: D17 D18 D19 D20 D21 D24 D25 D26 D36 D37 D38 D39 JOMEGA
component class U_HDMI: R112 R269
component class U_HDMI_CONVERTER: C150 C151 C152 C153 C154 C155 C156 C157 C158 C159 C163 C164 L11 L12 L13 L14 L15 L16 R167 R227 R228 U22
component class U_HDMI_CONNECTOR: C71 C72 D3 D12 D13 D14 D16 F4 J4 R490 R491 R492 R493 R494 R495
component class U_ETH: C67 C68 R110 R111 TP43 TP44 TP45 TP46 TP47 TP48 TP49 U8 U9
component class U_ETH_RJ45: C66 J2 R109
component class U_ETH_PHY: C4 C5 C6 C7 C8 C9 C10 C11 C12 C13 C14 C15 C16 C17 C18 C19 C20 C21 C22 C23 C24 C25 C26 C27 C28 C29 C30 C31 C32 C33 C34 C36 C73 C74 C112 C247 L1 L2 R62 R63 R64 R65 R66 R67 R68 R69 R70 R71 R72 R73 R74 R75 R76 R77 R78 R79 R80 R81 R82 R83 R84 R85 R266 R267 R284 R285 R342 R413 U1 Y1
component class U_CAN_PHY: C61 C62 C341 C342 C361 R506 R507 U7
component class U_AUDIO_CODEC: C109 C110 C134 C135 C136 C146 C160 C161 C162 C165 C166 C167 C168 C169 C170 C209 C217 C248 C253 C254 C295 C296 L17 R270 R277 R278 R279 R280 R281 R282 R283 R481 TP89 TP94 TP95 U23
component class U_ANALOG_SWITCH: C274 U28
differential pair class DIFF_MUX1_OUTA: A_CLK_1 A_LN0_1 A_LN1_1 A_LN2_1 A_LN3_1
net class NET_SOM_MD_DSI0: DSI0_CK_N DSI0_CK_P DSI0_L0_N DSI0_L0_P DSI0_L1_N DSI0_L1_P DSI0_L2_N DSI0_L2_P DSI0_L3_N DSI0_L3_P
net class NET_SOM_MD_CSI2: CSI2_CK_N CSI2_CK_P CSI2_L0_N CSI2_L0_P CSI2_L1_N CSI2_L1_P CSI2_L2_N CSI2_L2_P CSI2_L3_N CSI2_L3_P
net class NET_SOM_MD_CSI1: CSI1_CK_N CSI1_CK_P CSI1_L0_N CSI1_L0_P CSI1_L1_N CSI1_L1_P CSI1_L2_N CSI1_L2_P CSI1_L3_N CSI1_L3_P
net class NET_SOM_MD_CSI0: CSI0_CK_N CSI0_CK_P CSI0_L0_N CSI0_L0_P CSI0_L1_N CSI0_L1_P CSI0_L2_N CSI0_L2_P CSI0_L3_N CSI0_L3_P
component class MODULE_GND: MODULE1 SOM1
component class TOP: C333 C338 C346 C347 C348 D44 Fiducial_1 Fiducial_2 Fiducial_3 Fiducial_4 Fiducial_5 Fiducial_6 Q7 R125 R155 R158 R159 R160 R164 R174 R175 R176 R177 R188 R216 R219 R250 R251 R252 R253 R254 R255 R256 R257 R258 R346 R349 R350 R433 R477 R478 R479 R482 R483 R484 R485 R487 R488 R510 R511 TP40 TP41 TP42 U25
differential pair USBC_SSTX2: +USBC_SSTX2_P -USBC_SSTX2_N
differential pair USBC_SSTX1: +USBC_SSTX1_P -USBC_SSTX1_N
differential pair USBC_SSRX2: +USBC_SSRX2_P -USBC_SSRX2_N
differential pair USBC_SSRX1: +USBC_SSRX1_P -USBC_SSRX1_N
differential pair USB4_CAP_SSTX: +USB4_CAP_SSTX_P -USB4_CAP_SSTX_N
differential pair USB3_CAP_SSTX: +USB3_CAP_SSTX_P -USB3_CAP_SSTX_N
differential pair USB2_CAP_SSTX: +USB2_CAP_SSTX_P -USB2_CAP_SSTX_N
differential pair USB1_CAP_SSTX: +USB1_CAP_SSTX_P -USB1_CAP_SSTX_N
differential pair USB4_SSTX_26: +USB4_SSTX_26_P -USB4_SSTX_26_N
differential pair USB4_SSRX: +USB4_SSRX_P -USB4_SSRX_N
differential pair USB4_D: +USB4_D_P -USB4_D_N
differential pair USB3_SSTX_26: +USB3_SSTX_26_P -USB3_SSTX_26_N
differential pair USB3_SSRX: +USB3_SSRX_P -USB3_SSRX_N
differential pair USB3_D: +USB3_D_P -USB3_D_N
differential pair USB2_SSTX_26: +USB2_SSTX_26_P -USB2_SSTX_26_N
differential pair USB2_SSRX: +USB2_SSRX_P -USB2_SSRX_N
differential pair USB2_D: +USB2_D_P -USB2_D_N
differential pair USB1_SSTX_26: +USB1_SSTX_26_P -USB1_SSTX_26_N
differential pair USB1_SSRX: +USB1_SSRX_P -USB1_SSRX_N
differential pair USB1_D: +USB1_D_P -USB1_D_N
differential pair TUSB_CAP_TX_26: +TUSB_CAP_TX_26_P -TUSB_CAP_TX_26_N
differential pair PET_CAP_25: +PET_CAP_25_P -PET_CAP_25_N
differential pair PCIE2_TX0_CAP: +PCIE2_TX0_CAP_P -PCIE2_TX0_CAP_N
differential pair PCIE2_TX0_25: +PCIE2_TX0_25_P -PCIE2_TX0_25_N
differential pair PCIE1_TX0_CAP: +PCIE1_TX0_CAP_P -PCIE1_TX0_CAP_N
differential pair PCIE1_TX0_25: +PCIE1_TX0_25_P -PCIE1_TX0_25_N
differential pair MUX_TX2_30: +MUX_TX2_30_P -MUX_TX2_30_N
differential pair MUX_TX1_30: +MUX_TX1_30_P -MUX_TX1_30_N
differential pair MUX_SSRX2_30: +MUX_SSRX2_30_P -MUX_SSRX2_30_N
differential pair MUX_SSRX1_30: +MUX_SSRX1_30_P -MUX_SSRX1_30_N
differential pair A_LN3_3: +A_LN3_3_P -A_LN3_3_N
differential pair A_LN2_3: +A_LN2_3_P -A_LN2_3_N
differential pair A_LN1_3: +A_LN1_3_P -A_LN1_3_N
differential pair A_LN0_3: +A_LN0_3_P -A_LN0_3_N
differential pair A_CLK_3: +A_CLK_3_P -A_CLK_3_N
differential pair B_LN3_3: +B_LN3_3_P -B_LN3_3_N
differential pair B_LN2_3: +B_LN2_3_P -B_LN2_3_N
differential pair B_LN1_3: +B_LN1_3_P -B_LN1_3_N
differential pair B_LN0_3: +B_LN0_3_P -B_LN0_3_N
differential pair B_CLK_3: +B_CLK_3_P -B_CLK_3_N
differential pair ETH_PHY_TRX0: +ETH_PHY_TRX0_P -ETH_PHY_TRX0_N
differential pair ETH_PHY_TRX3: +ETH_PHY_TRX3_P -ETH_PHY_TRX3_N
differential pair ETH_PHY_TRX2: +ETH_PHY_TRX2_P -ETH_PHY_TRX2_N
differential pair ETH_PHY_TRX1: +ETH_PHY_TRX1_P -ETH_PHY_TRX1_N
differential pair B_LN3_2: +A_LN3_2_P -A_LN3_2_N
differential pair B_LN3_1: +A_LN3_1_P -A_LN3_1_N
differential pair B_LN2_2: +A_LN2_2_P -A_LN2_2_N
differential pair B_LN2_1: +A_LN2_1_P -A_LN2_1_N
differential pair B_CLK_2: +A_CLK_2_P -A_CLK_2_N
differential pair B_CLK_1: +A_CLK_1_P -A_CLK_1_N
differential pair A_LN3_2: +B_LN2_1_P -B_LN2_1_N
differential pair A_LN3_1: +B_LN2_2_P -B_LN2_2_N
differential pair A_LN2_2: +B_CLK_1_P -B_CLK_1_N
differential pair A_LN2_1: +B_CLK_2_P -B_CLK_2_N
differential pair A_CLK_2: +B_LN3_1_P -B_LN3_1_N
differential pair A_CLK_1: +B_LN3_2_P -B_LN3_2_N
differential pair PCIE2_RX0: +PCIE2_RX0_P -PCIE2_RX0_N
differential pair PCIE2_REFCLK0: +PCIE2_REFCLK0_P -PCIE2_REFCLK0_N
differential pair PCIE1_RX0: +PCIE1_RX0_P -PCIE1_RX0_N
differential pair PCIE1_REFCLK0: +PCIE1_REFCLK0_P -PCIE1_REFCLK0_N
differential pair MD_USB1_2.0.HS_D_1: +MD_USB1_2.0.HS_D_1_P -MD_USB1_2.0.HS_D_1_N
differential pair MD_USB0_3.1.SS_TX_1: +MD_USB0_3.1.SS_TX_1_P -MD_USB0_3.1.SS_TX_1_N
differential pair MD_USB0_3.1.SS_RX_1: +MD_USB0_3.1.SS_RX_1_P -MD_USB0_3.1.SS_RX_1_N
differential pair MD_USB0_3.1.HS_D_1: +MD_USB0_3.1.HS_D_1_P -MD_USB0_3.1.HS_D_1_N
differential pair MD_SGMII0.TX_1: +MD_SGMII0.TX_1_P -MD_SGMII0.TX_1_N
differential pair MD_SGMII0.RX_1: +MD_SGMII0.RX_1_P -MD_SGMII0.RX_1_N
differential pair MD_PCIE1_4LANES.TX3_1: +MD_PCIE1_4LANES.TX3_1_P -MD_PCIE1_4LANES.TX3_1_N
differential pair MD_PCIE1_4LANES.TX2_1: +MD_PCIE1_4LANES.TX2_1_P -MD_PCIE1_4LANES.TX2_1_N
differential pair MD_PCIE1_4LANES.TX1_1: +MD_PCIE1_4LANES.TX1_1_P -MD_PCIE1_4LANES.TX1_1_N
differential pair MD_PCIE1_4LANES.TX0_1: +MD_PCIE1_4LANES.TX0_1_P -MD_PCIE1_4LANES.TX0_1_N
differential pair MD_PCIE1_4LANES.RX3_1: +MD_PCIE1_4LANES.RX3_1_P -MD_PCIE1_4LANES.RX3_1_N
differential pair MD_PCIE1_4LANES.RX2_1: +MD_PCIE1_4LANES.RX2_1_P -MD_PCIE1_4LANES.RX2_1_N
differential pair MD_PCIE1_4LANES.RX1_1: +MD_PCIE1_4LANES.RX1_1_P -MD_PCIE1_4LANES.RX1_1_N
differential pair MD_PCIE1_4LANES.RX0_1: +MD_PCIE1_4LANES.RX0_1_P -MD_PCIE1_4LANES.RX0_1_N
differential pair MD_PCIE1_4LANES.REFCLK_1: +MD_PCIE1_4LANES.REFCLK_1_P -MD_PCIE1_4LANES.REFCLK_1_N
differential pair MD_PCIE0_2LANES.TX1_1: +MD_PCIE0_2LANES.TX1_1_P -MD_PCIE0_2LANES.TX1_1_N
differential pair MD_PCIE0_2LANES.TX0_1: +MD_PCIE0_2LANES.TX0_1_P -MD_PCIE0_2LANES.TX0_1_N
differential pair MD_PCIE0_2LANES.RX1_1: +MD_PCIE0_2LANES.RX1_1_P -MD_PCIE0_2LANES.RX1_1_N
differential pair MD_PCIE0_2LANES.RX0_1: +MD_PCIE0_2LANES.RX0_1_P -MD_PCIE0_2LANES.RX0_1_N
differential pair MD_PCIE0_2LANES.REFCLK_1: +MD_PCIE0_2LANES.REFCLK_1_P -MD_PCIE0_2LANES.REFCLK_1_N
differential pair HDMI_TX2: +HDMI_TX2_P -HDMI_TX2_N
differential pair HDMI_TX1: +HDMI_TX1_P -HDMI_TX1_N
differential pair HDMI_TX0: +HDMI_TX0_P -HDMI_TX0_N
differential pair HDMI_CLK: +HDMI_CLK_P -HDMI_CLK_N
differential pair EDP0_TX3: +EDP0_TX3_P -EDP0_TX3_N
differential pair EDP0_TX2: +EDP0_TX2_P -EDP0_TX2_N
differential pair EDP0_TX1: +EDP0_TX1_P -EDP0_TX1_N
differential pair EDP0_TX0: +EDP0_TX0_P -EDP0_TX0_N
differential pair EDP0_AUX: +EDP0_AUX_P -EDP0_AUX_N
differential pair B_LN1_2: +A_LN1_2_P -A_LN1_2_N
differential pair B_LN1_1: +A_LN1_1_P -A_LN1_1_N
differential pair B_LN0_2: +A_LN0_2_P -A_LN0_2_N
differential pair B_LN0_1: +A_LN0_1_P -A_LN0_1_N
differential pair A_LN1_2: +B_LN1_1_P -B_LN1_1_N
differential pair A_LN1_1: +B_LN1_2_P -B_LN1_2_N
differential pair A_LN0_2: +B_LN0_1_P -B_LN0_1_N
differential pair A_LN0_1: +B_LN0_2_P -B_LN0_2_N
differential pair DSI0_L3: +DSI0_L3_P -DSI0_L3_N
differential pair DSI0_L2: +DSI0_L2_P -DSI0_L2_N
differential pair DSI0_L1: +DSI0_L1_P -DSI0_L1_N
differential pair DSI0_L0: +DSI0_L0_P -DSI0_L0_N
differential pair DSI0_CK: +DSI0_CK_P -DSI0_CK_N
differential pair CSI2_L3: +CSI2_L2_P -CSI2_L2_N
differential pair CSI2_L2: +CSI2_CK_P -CSI2_CK_N
differential pair CSI2_L1: +CSI2_L1_P -CSI2_L1_N
differential pair CSI2_L0: +CSI2_L0_P -CSI2_L0_N
differential pair CSI2_CK: +CSI2_L3_P -CSI2_L3_N
differential pair CSI1_L3: +CSI1_L3_P -CSI1_L3_N
differential pair CSI1_L2: +CSI1_L2_P -CSI1_L2_N
differential pair CSI1_L1: +CSI1_L1_P -CSI1_L1_N
differential pair CSI1_L0: +CSI1_L0_P -CSI1_L0_N
differential pair CSI1_CK: +CSI1_CK_P -CSI1_CK_N
differential pair CSI0_L3: +CSI0_L3_P -CSI0_L3_N
differential pair CSI0_L2: +CSI0_L2_P -CSI0_L2_N
differential pair CSI0_L1: +CSI0_L1_P -CSI0_L1_N
differential pair CSI0_L0: +CSI0_L0_P -CSI0_L0_N
differential pair CSI0_CK: +CSI0_CK_P -CSI0_CK_N

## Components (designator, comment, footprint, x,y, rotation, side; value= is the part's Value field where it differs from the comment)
C1 "CL03A104KP3NNNC" CAP-0201 53.731,113.101 r0 bottom value=100nF
C2 "CL03A104KP3NNNC" CAP-0201 63.628,114.024 r180 bottom value=100nF
C3 "CL03A104KP3NNNC" CAP-0201 53.731,115.301 r0 bottom value=100nF
C4 "CL03A104KP3NNNC" CAP-0201 78.948,5.999 r90 bottom value=100nF
C5 "CL03A104KP3NNNC" CAP-0201 74.931,5.97 r0 bottom value=100nF
C6 "CL03A104KP3NNNC" CAP-0201 74.931,8.559 r0 bottom value=100nF
C7 "CL03A104KP3NNNC" CAP-0201 72.1,13.5 r90 bottom value=100nF
C8 "CL03A104KP3NNNC" CAP-0201 74.582,7.274 r180 top value=100nF
C9 "GRM033R60J105MEA2D" CAP-0201 67.3,2.605 r90 top value=1µF
C10 "CL03A104KP3NNNC" CAP-0201 65.1,12.9 r270 top value=100nF
C11 "CL03A104KP3NNNC" CAP-0201 67.88,2.605 r90 top value=100nF
C12 "CL03A104KP3NNNC" CAP-0201 74.581,9.659 r180 top value=100nF
C13 "CL03A104KP3NNNC" CAP-0201 74.581,4.459 r180 top value=100nF
C14 "CL03A104KP3NNNC" CAP-0201 71.456,8.159 r0 bottom value=100nF
C15 "GRM033R60J105MEA2D" CAP-0201 71.456,6.959 r0 bottom value=1µF
C16 "CL03A104KP3NNNC" CAP-0201 74.581,11.859 r180 top value=100nF
C17 "CL03A104KP3NNNC" CAP-0201 74.581,10.559 r180 top value=100nF
C18 "CL03A104KP3NNNC" CAP-0201 73.131,4.892 r180 bottom value=100nF
C19 "CL03A104KP3NNNC" CAP-0201 74.581,11.234 r180 top value=100nF
C20 "CL03A104KP3NNNC" CAP-0201 70.8,12.3 r270 top value=100nF
C21 "CL03A104KP3NNNC" CAP-0201 73.281,12.159 r180 top value=100nF
C22 "CL03A104KP3NNNC" CAP-0201 73.838,12.877 r0 top value=100nF
C23 "GRM0335C1E120JA01J" CAP-0201 68.9,13.17 r180 top value=12pF
C24 "GRM0335C1E120JA01J" CAP-0201 70.1,13.17 r0 top value=12pF
C25 "CL03A104KP3NNNC" CAP-0201 72.054,10.938 r270 bottom value=100nF
C26 "CL03A104KP3NNNC" CAP-0201 66.356,6.963 r0 bottom value=100nF
C27 "CL03A104KP3NNNC" CAP-0201 72.604,8.838 r90 bottom value=100nF
C28 "CL03A104KP3NNNC" CAP-0201 73.131,5.492 r180 bottom value=100nF
C29 "CL03A104KP3NNNC" CAP-0201 71.481,4.389 r90 bottom value=100nF
C30 "CL03A104KP3NNNC" CAP-0201 72.081,4.389 r90 bottom value=100nF
C31 "CL03A104KP3NNNC" CAP-0201 67.156,4.384 r180 bottom value=100nF
C32 "CL03A104KP3NNNC" CAP-0201 70.081,6.034 r270 bottom value=100nF
C33 "CL03A104KP3NNNC" CAP-0201 68.9,12.57 r0 top value=100nF
C34 "CL03A104KP3NNNC" CAP-0201 66.356,7.959 r0 bottom value=100nF
C35 "C0805C476M9PAC7800" CAP-0805 98.336,38.875 r90 bottom value=47µF
C36 "CL03A104KP3NNNC" CAP-0201 73.321,17.568 r270 bottom value=100nF
C37 "C0805C476M9PAC7800" CAP-0805 98.336,35.175 r90 bottom value=47µF
C38 "C0805C476M9PAC7800" CAP-0805 25.3,140.1 r270 top value=47µF
C39 "C0805C476M9PAC7800" CAP-0805 23.3,140.1 r270 top value=47µF
C40 "CL05B391KB5NNNC" CAP-0402 89.918,82.267 r180 bottom value=390pF
C41 "CL05B391KB5NNNC" CAP-0402 90.418,83.367 r180 bottom value=390pF
C42 "GRM033R60J105MEA2D" CAP-0201 88.828,91.947 r90 bottom value=1µF
C43 "CL03A104KP3NNNC" CAP-0201 88.828,90.747 r270 bottom value=100nF
C44 "C1005A475M6R3NT" CAP-0402 90.668,90.297 r0 bottom value=4.7µF
C45 "CL03A104KP3NNNC" CAP-0201 89.503,90.747 r270 bottom value=100nF
C46 "CL03A104KP3NNNC" CAP-0201 89.728,88.897 r180 bottom value=100nF
C47 "CL03A104KP3NNNC" CAP-0201 91.213,87.997 r270 bottom value=100nF
C48 "GRM033R60J105MEA2D" CAP-0201 89.903,87.997 r270 bottom value=1µF
C49 "CL03A104KP3NNNC" CAP-0201 90.978,89.497 r180 bottom value=100nF
C50 "CL03A334KA3NRNC" CAP-0201 83.2,73.767 r270 top value=330nF
C51 "CL03A334KA3NRNC" CAP-0201 82.6,73.767 r270 top value=330nF
C52 "CL03A334KA3NRNC" CAP-0201 86.8,73.767 r270 top value=330nF
C53 "CL03A334KA3NRNC" CAP-0201 86.2,73.767 r270 top value=330nF
C54 "CL03A104KP3NNNC" CAP-0201 84.3,80.041 r270 top value=100nF
C55 "CL03A104KP3NNNC" CAP-0201 85.9,74.912 r90 top value=100nF
C56 "CL03A104KP3NNNC" CAP-0201 85.5,80.041 r270 top value=100nF
C57 "CL03A104KP3NNNC" CAP-0201 84.7,74.912 r90 top value=100nF
C58 "CL03A104KP3NNNC" CAP-0201 82.3,74.912 r90 top value=100nF
C59 "CL03A104KP3NNNC" CAP-0201 83.5,74.912 r90 top value=100nF
C60 "CL03A104KP3NNNC" CAP-0201 83.1,80.041 r270 top value=100nF
C61 "CL03A104KP3NNNC" CAP-0201 78.828,103.828 r0 bottom value=100nF
C62 "CL03A104KP3NNNC" CAP-0201 84.703,105.3 r180 bottom value=100nF
C63 "GRM033R60J105MEA2D" CAP-0201 55.363,18.629 r180 top value=1µF
C64 "C1005A475M6R3NT" CAP-0402 66.69,13.791 r0 bottom value=4.7µF
C65 "GRM033R60J105MEA2D" CAP-0201 54.163,15.029 r0 top value=1µF
C66 "FV21X472K102ECG" CAP-0805 84.334,7.06 r180 top value=4.7nF
C67 "CL03A104KP3NNNC" CAP-0201 94.466,17.344 r0 bottom value=100nF
C68 "CL03A104KP3NNNC" CAP-0201 94.741,19.719 r270 bottom value=100nF
C69_1 "CL03A104KP3NNNC" CAP-0201 43.382,138.511 r270 top value=100nF (schematic designator C69)
C69_2 "CL03A104KP3NNNC" CAP-0201 54.951,139.134 r270 top value=100nF (schematic designator C69)
C69_3 "CL03A104KP3NNNC" CAP-0201 66.551,139.209 r270 top value=100nF (schematic designator C69)
C70 "C1005A475M6R3NT" CAP-0402 19.75,9.7 r270 top value=4.7µF
C71 "CL03A104KP3NNNC" CAP-0201 74.737,62.804 r90 bottom value=100nF
C72 "C1005A475M6R3NT" CAP-0402 73.837,62.804 r90 bottom value=4.7µF
C73 "GRM21BR61H106ME43L" CAP-0805 71.254,2.913 r0 bottom value=10µF
C74 "GRM21BR61H106ME43L" CAP-0805 74.451,12.236 r0 bottom value=10µF
C75 "GRM155R61H104KE19D" CAP-0402 10.394,111.365 r0 top value=100nF
C76 "GRM21BR61H106ME43L" CAP-0805 7.05,100.365 r0 top value=10µF
C77 "GRM21BR61H106ME43L" CAP-0805 7.05,125.065 r0 top value=10µF
C78 "GRM21BR61H106ME43L" CAP-0805 7.05,123.065 r0 top value=10µF
C79 "GRM155R61H104KE19D" CAP-0402 6.835,121.665 r0 top value=100nF
C80 "GJM0335C0J330JB01J" CAP-0201 1,106.965 r270 top value=33pF
C81 "C0805C476M9PAC7800" CAP-0805 18.1,122.215 r270 top value=47µF
C82 "C0805C476M9PAC7800" CAP-0805 18.1,114.715 r90 top value=47µF
C83 "C0805C476M9PAC7800" CAP-0805 21.3,140.1 r270 top value=47µF
C84 "GRM155R61H104KE19D" CAP-0402 85.638,80.147 r180 bottom value=100nF
C85 "GRM033R60J105MEA2D" CAP-0201 2.1,107.865 r0 top value=1µF
C86 "GRM155R61H104KE19D" CAP-0402 10.394,122.731 r0 top value=100nF
C87 "GRM21BR61H106ME43L" CAP-0805 7.05,102.365 r0 top value=10µF
C88 "GRM21BR61H106ME43L" CAP-0805 7.05,111.765 r0 top value=10µF
C89 "GRM21BR61H106ME43L" CAP-0805 7.05,113.865 r0 top value=10µF
C90 "GRM155R61H104KE19D" CAP-0402 6.835,110.365 r0 top value=100nF
C91 "GJM0335C0J330JB01J" CAP-0201 1,118.265 r270 top value=33pF
C92 "GRM31CR61A107MEA8L" CAP-1206 24.094,141.892 r90 bottom value=100µF
C93 "GRM31CR61A107MEA8L" CAP-1206 21.635,141.892 r90 bottom value=100µF
C94 "CL03A104KP3NNNC" CAP-0201 36.332,72.873 r270 top value=100nF
C95 "GRM033R60J105MEA2D" CAP-0201 2.1,119.165 r0 top value=1µF
C96 "GRM155R61H104KE19D" CAP-0402 10.394,97.466 r0 top value=100nF
C97 "GRM0335C1E120JA01J" CAP-0201 53.713,22.975 r180 bottom locked value=12pF
C98 "GRM21BR61H106ME43L" CAP-0805 7.05,97.566 r0 top value=10µF
C99 "GRM21BR61H106ME43L" CAP-0805 7.05,88.366 r0 top value=10µF
C100 "GRM155R61H104KE19D" CAP-0402 6.835,96.116 r0 top value=100nF
C101 "CL03A104KP3NNNC" CAP-0201 40.162,72.873 r270 top value=100nF
C102 "GJM0335C0J330JB01J" CAP-0201 1,92.766 r270 top value=33pF
C103 "C0805C476M9PAC7800" CAP-0805 18.1,96.716 r270 top value=47µF
C104 "C0805C476M9PAC7800" CAP-0805 18.1,89.216 r90 top value=47µF
C105 "GRM0335C1E120JA01J" CAP-0201 54.863,22.975 r0 bottom locked value=12pF
C106 "GRM033R60J105MEA2D" CAP-0201 59.563,18.929 r0 top value=1µF
C107 "GRM033R60J105MEA2D" CAP-0201 59.25,18 r270 top value=1µF
C108 "GRM033R60J105MEA2D" CAP-0201 57.938,14.029 r180 top value=1µF
C109 "GRM033R60J105MEA2D" CAP-0201 43.723,83.816 r90 bottom value=1µF
C110 "GRM033R60J105MEA2D" CAP-0201 45.323,83.816 r90 bottom value=1µF
C111 "CL03A104KP3NNNC" CAP-0201 28.408,96.451 r0 bottom value=100nF
C112 "CL03A104KP3NNNC" CAP-0201 64.616,7 r180 top value=100nF
C113 "CL03A104KP3NNNC" CAP-0201 77.575,40 r90 top value=100nF
C114 "GRM033R60J105MEA2D" CAP-0201 2.1,93.666 r0 top value=1µF
C115 "C0805C476M9PAC7800" CAP-0805 30.85,139.35 r180 top value=47µF
C116 "C1005B103K500NT" CAP-0402 9.118,78.791 r180 top value=10nF
C117 "GRM21BR61H106ME43L" CAP-0805 12.668,75.441 r0 top value=10µF
C118 "CL03A104KP3NNNC" CAP-0201 12.443,76.741 r0 top value=100nF
C119 "CL03A104KP3NNNC" CAP-0201 12.443,80.141 r0 top value=100nF
C120 "C0805C476M9PAC7800" CAP-0805 11.468,83.341 r0 top value=47µF
C121 "GJM0335C0J330JB01J" CAP-0201 9.668,77.041 r90 top value=33pF
C122 "GRM21BR61H106ME43L" CAP-0805 75.281,22.659 r90 top value=10µF
C123 "CL03A104KP3NNNC" CAP-0201 73.981,21.934 r90 top value=100nF
C124 "CL03A104KP3NNNC" CAP-0201 70.556,21.609 r90 top value=100nF
C125 "C0805C476M9PAC7800" CAP-0805 67.281,20.959 r90 top value=47µF
C126 "GJM0335C0J330JB01J" CAP-0201 73.131,19.509 r180 top value=33pF
C127 "C1005B103K500NT" CAP-0402 71.631,18.909 r270 top value=10nF
C128 "CL03A104KP3NNNC" CAP-0201 14.6,30.685 r270 bottom value=100nF
C129 "CL03A104KP3NNNC" CAP-0201 15.55,13.234 r180 bottom value=100nF
C130 "CL03A104KP3NNNC" CAP-0201 13.9,30.685 r270 bottom value=100nF
C131 "CL03A104KP3NNNC" CAP-0201 15.55,12.534 r180 bottom value=100nF
C132 "C1005A475M6R3NT" CAP-0402 15.4,30.845 r90 bottom value=4.7µF
C133 "C1005A475M6R3NT" CAP-0402 15.71,14.034 r0 bottom value=4.7µF
C134 "CL03A104KP3NNNC" CAP-0201 43.201,82.3 r180 bottom value=100nF
C135 "GRM21BR61H106ME43L" CAP-0805 38.923,93.616 r90 bottom value=10µF
C136 "GRM033R60J105MEA2D" CAP-0201 40.323,83.816 r90 bottom value=1µF
C137 "C1005A475M6R3NT" CAP-0402 37.275,83.431 r270 bottom value=4.7µF
C138 "C1005B103K500NT" CAP-0402 36.075,86.131 r270 bottom value=10nF
C139 "C1005A475M6R3NT" CAP-0402 37.275,85.431 r90 bottom value=4.7µF
C140 "GRM31CR61A107MEA8L" CAP-1206 26.604,131.254 r270 bottom value=100µF
C141 "GRM31CR61A107MEA8L" CAP-1206 24.145,131.254 r270 bottom value=100µF
C142 "GRM31CR61A107MEA8L" CAP-1206 21.685,131.254 r270 bottom value=100µF
C143 "GRM31CR61A107MEA8L" CAP-1206 33.983,131.254 r270 bottom value=100µF
C144 "GRM0335C1H181JA01D" CAP-0201 2.1,109.165 r0 top value=180pF
C145 "GRM0335C1H181JA01D" CAP-0201 2.1,120.565 r0 top value=180pF
C146 "CL03A104KP3NNNC" CAP-0201 40.923,83.816 r90 bottom value=100nF
C147 "C0805C476M9PAC7800" CAP-0805 98.336,42.475 r270 bottom value=47µF
C148 "GRM31CR61A107MEA8L" CAP-1206 31.523,131.254 r270 bottom value=100µF
C149 "GRM31CR61A107MEA8L" CAP-1206 29.064,131.254 r270 bottom value=100µF
C150 "CL03A104KP3NNNC" CAP-0201 75.324,54.865 r0 top value=100nF
C151 "GRM033R60J105MEA2D" CAP-0201 75.324,55.465 r0 top value=1µF
C152 "CL03A104KP3NNNC" CAP-0201 74.875,62.535 r0 top value=100nF
C153 "GRM033R60J105MEA2D" CAP-0201 74.875,63.135 r0 top value=1µF
C154 "CL03A104KP3NNNC" CAP-0201 73.575,62.535 r180 top value=100nF
C155 "GRM033R60J105MEA2D" CAP-0201 73.575,63.135 r180 top value=1µF
C156 "CL03A104KP3NNNC" CAP-0201 76.474,54.865 r180 top value=100nF
C157 "GRM033R60J105MEA2D" CAP-0201 76.474,55.465 r180 top value=1µF
C158 "CL03A104KP3NNNC" CAP-0201 72.374,54.865 r180 top value=100nF
C159 "GRM033R60J105MEA2D" CAP-0201 72.374,55.465 r180 top value=1µF
C160 "GRM033R60J105MEA2D" CAP-0201 41.923,93.191 r270 bottom value=1µF
C161 "GRM033R60J105MEA2D" CAP-0201 41.223,93.191 r270 bottom value=1µF
C162 "GRM033R60J105MEA2D" CAP-0201 40.523,93.191 r90 bottom value=1µF
C163 "CL03A104KP3NNNC" CAP-0201 76.275,62.535 r0 top value=100nF
C164 "GRM033R60J105MEA2D" CAP-0201 76.275,63.135 r0 top value=1µF
C165 "CL03A104KP3NNNC" CAP-0201 48.563,90.616 r180 bottom value=100nF
C166 "CL03A104KP3NNNC" CAP-0201 48.563,89.916 r180 bottom value=100nF
C167 "GRM033R60J105MEA2D" CAP-0201 42.123,83.816 r90 bottom value=1µF
C168 "CL03A104KP3NNNC" CAP-0201 41.523,83.816 r90 bottom value=100nF
C169 "GRM033R60J105MEA2D" CAP-0201 39.023,86.016 r0 bottom value=1µF
C170 "CL03A104KP3NNNC" CAP-0201 39.023,91.616 r0 bottom value=100nF
C171 "C0805C476M9PAC7800" CAP-0805 98.336,46.175 r270 bottom value=47µF
C172_1 "CL03A104KP3NNNC" CAP-0201 48.75,67.45 r90 top value=100nF (schematic designator C172)
C172_2 "CL03A104KP3NNNC" CAP-0201 53.089,75.291 r270 top value=100nF (schematic designator C172)
C172_3 "CL03A104KP3NNNC" CAP-0201 9.736,146.398 r90 top value=100nF (schematic designator C172)
C172_4 "CL03A104KP3NNNC" CAP-0201 48.4,75.291 r270 top value=100nF (schematic designator C172)
C172_5 "CL03A104KP3NNNC" CAP-0201 32.75,28.27 r270 bottom value=100nF (schematic designator C172)
C173_1 "CL03A104KP3NNNC" CAP-0201 86.175,122.65 r90 bottom value=100nF (schematic designator C173)
C173_2 "CL03A104KP3NNNC" CAP-0201 42.026,67.55 r90 top value=100nF (schematic designator C173)
C173_3 "CL03A104KP3NNNC" CAP-0201 33.026,67.55 r90 top value=100nF (schematic designator C173)
C173_4 "CL03A104KP3NNNC" CAP-0201 18.45,67.55 r90 top value=100nF (schematic designator C173)
C173_5 "CL03A104KP3NNNC" CAP-0201 81.426,97.795 r90 bottom value=100nF (schematic designator C173)
C174_1 "CL03A104KP3NNNC" CAP-0201 86.725,128.8 r270 bottom value=100nF (schematic designator C174)
C174_2 "CL03A104KP3NNNC" CAP-0201 42.026,65.6 r270 top value=100nF (schematic designator C174)
C174_3 "CL03A104KP3NNNC" CAP-0201 33.026,65.6 r270 top value=100nF (schematic designator C174)
C174_4 "CL03A104KP3NNNC" CAP-0201 18.45,65.6 r270 top value=100nF (schematic designator C174)
C174_5 "CL03A104KP3NNNC" CAP-0201 81.426,95.845 r270 bottom value=100nF (schematic designator C174)
C175_1 "CL03A104KP3NNNC" CAP-0201 48.75,65.55 r270 top value=100nF (schematic designator C175)
C175_2 "CL03A104KP3NNNC" CAP-0201 53.039,71.165 r90 top value=100nF (schematic designator C175)
C175_3 "CL03A104KP3NNNC" CAP-0201 9.786,150.425 r270 top value=100nF (schematic designator C175)
C175_4 "CL03A104KP3NNNC" CAP-0201 48.7,71.137 r90 top value=100nF (schematic designator C175)
C175_5 "CL03A104KP3NNNC" CAP-0201 32.75,29.77 r90 bottom value=100nF (schematic designator C175)
C176_1 "C1005A475M6R3NT" CAP-0402 80.025,126.1 r90 bottom value=4.7µF (schematic designator C176)
C176_2 "C1005A475M6R3NT" CAP-0402 35.465,65.95 r180 top value=4.7µF (schematic designator C176)
C176_3 "C1005A475M6R3NT" CAP-0402 26.389,65.95 r180 top value=4.7µF (schematic designator C176)
C176_4 "C1005A475M6R3NT" CAP-0402 11.965,65.95 r180 top value=4.7µF (schematic designator C176)
C176_5 "C1005A475M6R3NT" CAP-0402 87.753,97.134 r270 bottom value=4.7µF (schematic designator C176)
C177 "C0805C476M9PAC7800" CAP-0805 26.45,142.8 r0 top value=47µF
C178 "C0805C476M9PAC7800" CAP-0805 27.3,140.1 r270 top value=47µF
C179_1 "CL03A104KP3NNNC" CAP-0201 74.681,17.568 r270 bottom value=100nF (schematic designator C179)
C179_2 "CL03A104KP3NNNC" CAP-0201 36.341,24.624 r90 top value=100nF (schematic designator C179)
C179_3 "CL03A104KP3NNNC" CAP-0201 1.765,79.019 r270 top value=100nF (schematic designator C179)
C179_4 "CL03A104KP3NNNC" CAP-0201 11.468,72.936 r180 top value=100nF (schematic designator C179)
C179_5 "CL03A104KP3NNNC" CAP-0201 98.023,52.771 r0 bottom value=100nF (schematic designator C179)
C179_6 "CL03A104KP3NNNC" CAP-0201 97.015,29.5 r0 bottom value=100nF (schematic designator C179)
C180 "CL03A104KP3NNNC" CAP-0201 76.991,27.049 r90 top value=100nF
C181 "CL03A104KP3NNNC" CAP-0201 77.141,29.774 r0 bottom value=100nF
C182 "CL03A104KP3NNNC" CAP-0201 74.041,30.049 r270 bottom value=100nF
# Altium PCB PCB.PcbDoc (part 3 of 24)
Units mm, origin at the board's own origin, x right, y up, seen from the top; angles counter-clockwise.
Board outline 100 x 160 mm, 10 copper layers (TOP_L1, L2, L3, L4, L5, L6, L7, L8, L9, BOTTOM_L10), stack 1.946 mm thick; 1358 components, 1149 nets, 6777 pads, 10914 vias.

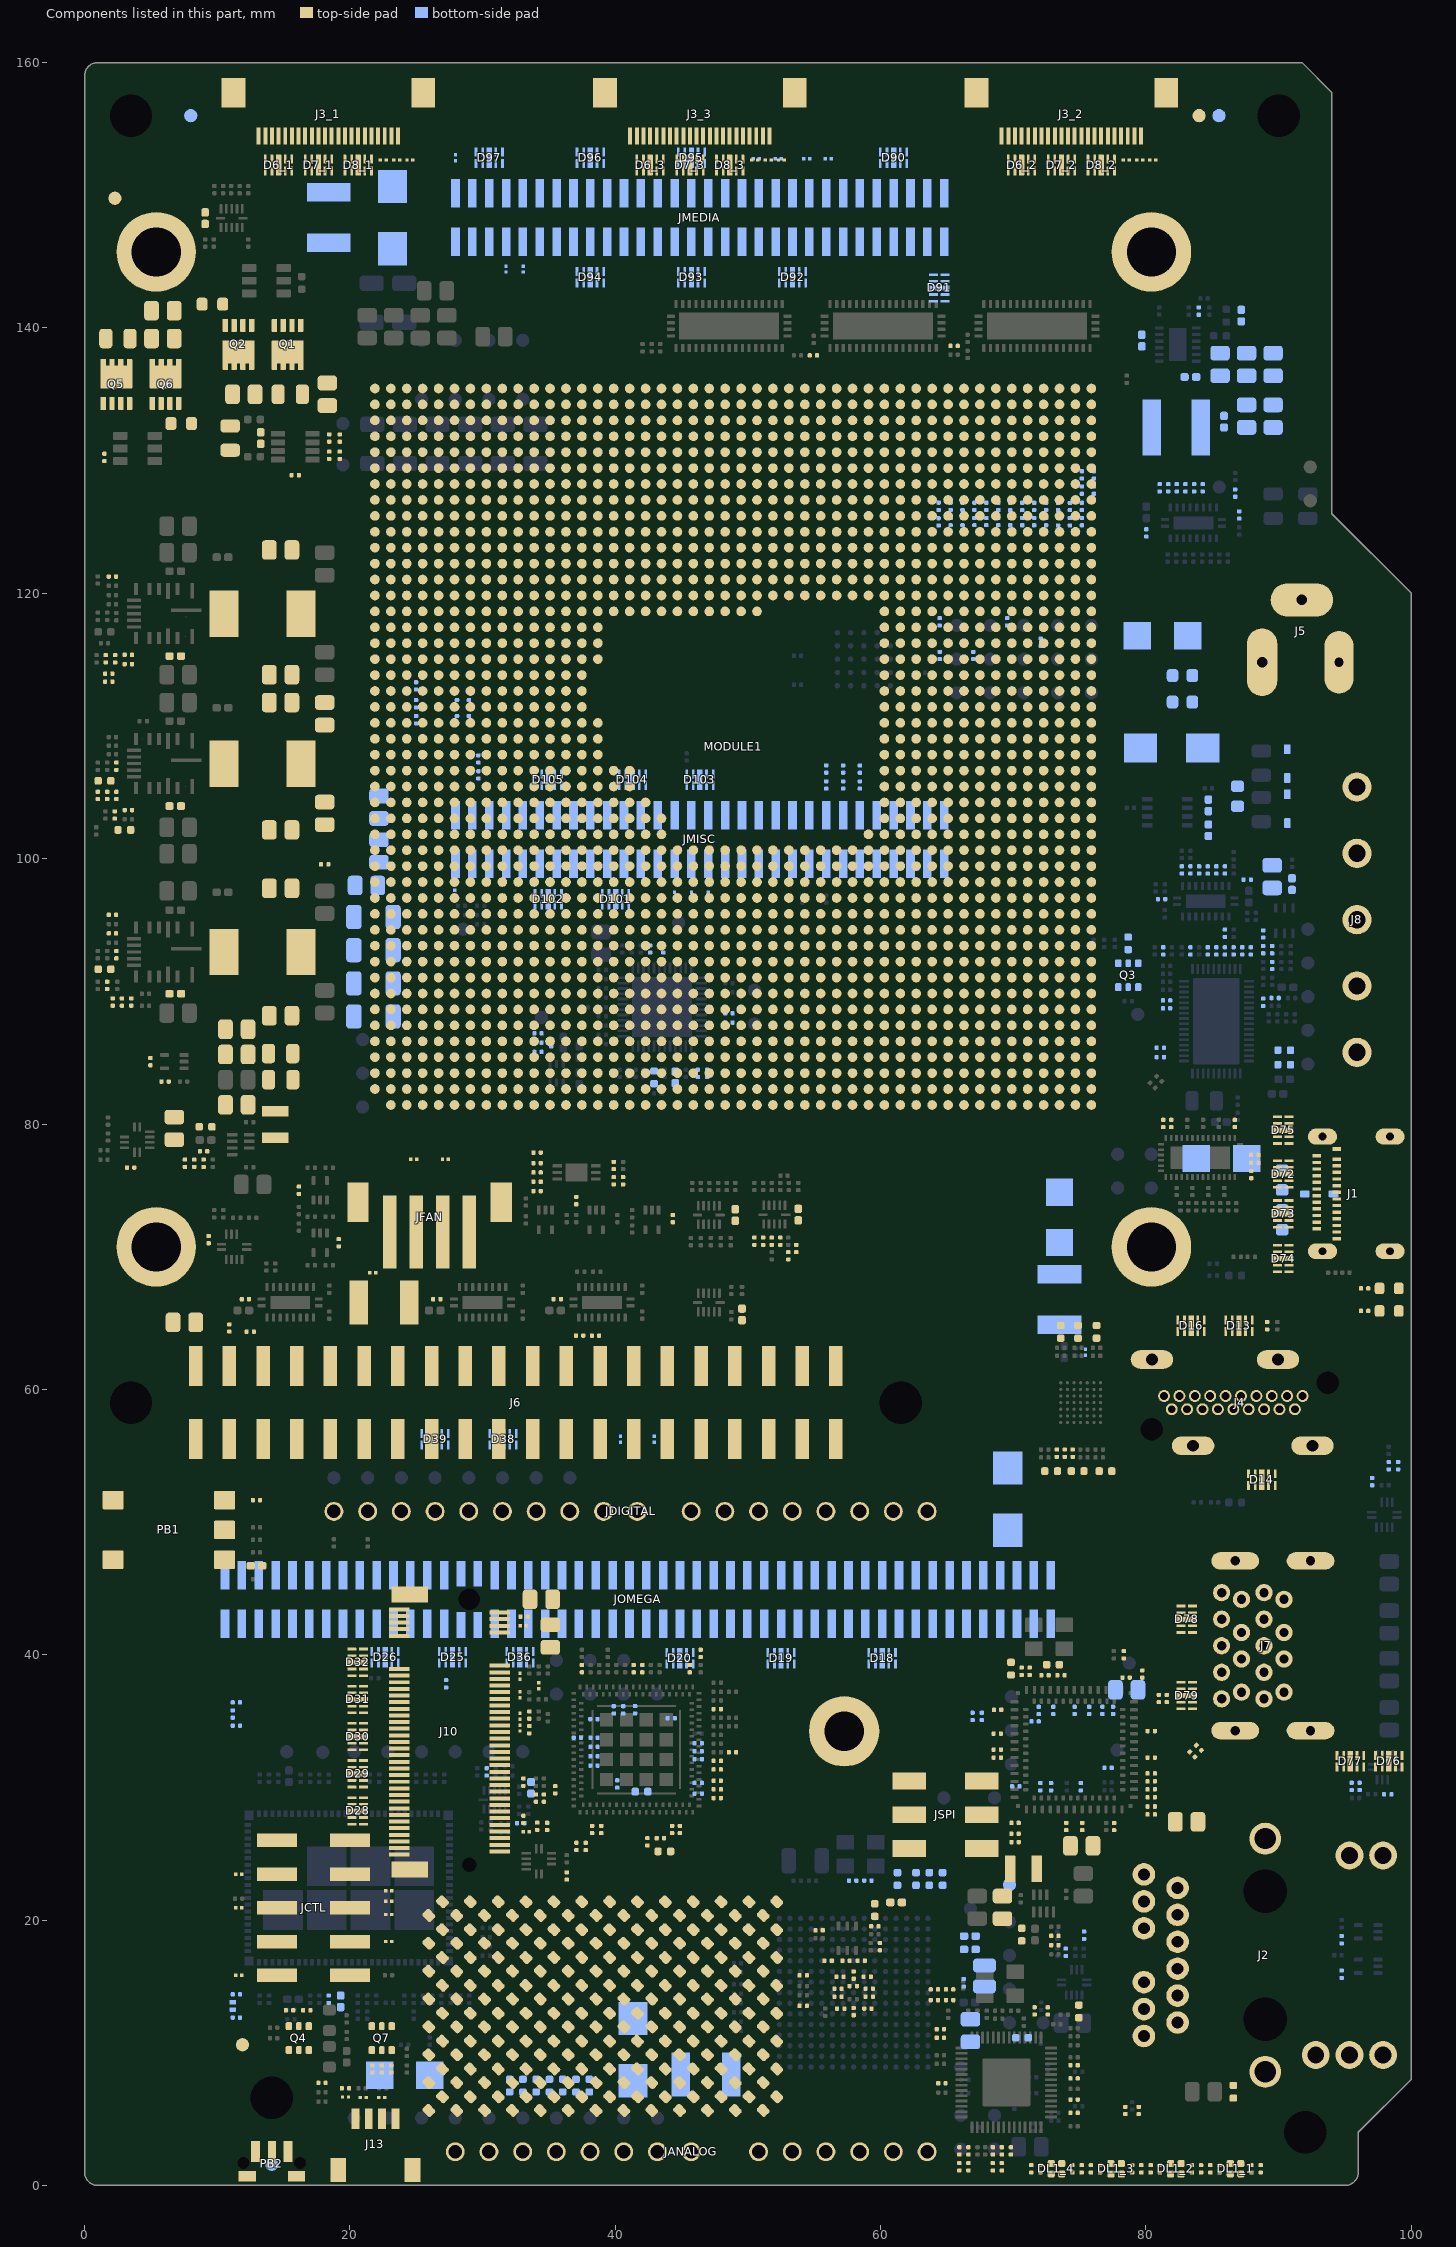
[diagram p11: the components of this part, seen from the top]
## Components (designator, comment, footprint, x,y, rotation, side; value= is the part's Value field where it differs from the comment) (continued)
C183 "CL03A104KP3NNNC" CAP-0201 75.091,30.049 r270 bottom value=100nF
C184 "CL03A104KP3NNNC" CAP-0201 80.391,29.249 r180 top value=100nF
C185 "CL03A104KP3NNNC" CAP-0201 80.391,34.249 r180 top value=100nF
C186 "CL03A104KP3NNNC" CAP-0201 79.724,38.542 r270 top value=100nF
C187 "C0805C476M9PAC7800" CAP-0805 11.468,81.441 r0 top value=47µF
C188 "CL03A104KP3NNNC" CAP-0201 80.391,31.049 r180 top value=100nF
C189 "CL03A104KP3NNNC" CAP-0201 80.391,32.249 r180 top value=100nF
C190 "CL03A104KP3NNNC" CAP-0201 72.841,30.049 r270 bottom value=100nF
C191 "CL03A104KP3NNNC" CAP-0201 74.616,35.799 r90 bottom value=100nF
C192 "CL03A104KP3NNNC" CAP-0201 71.916,35.799 r90 bottom value=100nF
C193 "CL03A104KP3NNNC" CAP-0201 78.5,38.275 r180 top value=100nF
C194 "CL03A104KP3NNNC" CAP-0201 75.716,35.799 r90 bottom value=100nF
C195 "CL03A104KP3NNNC" CAP-0201 68.816,35.849 r0 top value=100nF
C196 "CL03A104KP3NNNC" CAP-0201 70.191,30.074 r180 bottom value=100nF
C197 "CL03A104KP3NNNC" CAP-0201 72.041,30.049 r270 bottom value=100nF
C198 "CL03A104KP3NNNC" CAP-0201 68.791,34.049 r0 top value=100nF
C199 "CL03A104KP3NNNC" CAP-0201 68.791,32.849 r0 top value=100nF
C200 "GRM21BR61H106ME43L" CAP-0805 83.061,27.409 r180 top value=10µF
C201 "C0805C476M9PAC7800" CAP-0805 11.468,85.241 r0 top value=47µF
C202 "CL03A104KP3NNNC" CAP-0201 77.591,27.049 r90 top value=100nF
C203 "CL03A104KP3NNNC" CAP-0201 70.131,27.324 r180 top value=100nF
C204 "CL03A104KP3NNNC" CAP-0201 68.791,32.249 r0 top value=100nF
C205 "GRM033R60J105MEA2D" CAP-0201 17.892,7.724 r0 top value=1µF
C206 "CL03A104KP3NNNC" CAP-0201 80.391,30.449 r180 top value=100nF
C207 "CL03A104KP3NNNC" CAP-0201 75.191,27.049 r90 top value=100nF
C208 "GRM21BR61H106ME43L" CAP-0805 75.153,25.597 r0 top value=10µF
C209 "GRM033R60J105MEA2D" CAP-0201 48.563,87.649 r0 bottom value=1µF
C210 "CL03A104KP3NNNC" CAP-0201 73.991,27.049 r90 top value=100nF
C211 "CL03A104KP3NNNC" CAP-0201 77.141,31.474 r0 bottom value=100nF
C212 "CL03A104KP3NNNC" CAP-0201 77.516,35.799 r270 bottom value=100nF
C213 "CL03A104KP3NNNC" CAP-0201 70.626,38.749 r270 top value=100nF
C214 "CL03A104KP3NNNC" CAP-0201 71.641,34.974 r180 bottom value=100nF
C215 "CL03A104KP3NNNC" CAP-0201 73.016,35.799 r90 bottom value=100nF
C216 "GRM21BR61H106ME43L" CAP-0805 78.546,37.357 r180 bottom value=10µF
C217 "GRM033R60J105MEA2D" CAP-0201 48.563,88.343 r0 bottom value=1µF
C218 "GRM0335C1E120JA01J" CAP-0201 72.391,38.449 r0 top value=12pF
C219 "GRM0335C1E120JA01J" CAP-0201 73.591,38.449 r180 top value=12pF
C220_1 "C1005A475M6R3NT" CAP-0402 49.55,65.65 r270 top value=4.7µF (schematic designator C220)
C220_2 "C1005A475M6R3NT" CAP-0402 53.789,73.169 r270 top value=4.7µF (schematic designator C220)
C220_3 "C1005A475M6R3NT" CAP-0402 9.086,148.275 r90 top value=4.7µF (schematic designator C220)
C220_4 "C1005A475M6R3NT" CAP-0402 49.05,73.141 r270 top value=4.7µF (schematic designator C220)
C220_5 "C1005A475M6R3NT" CAP-0402 33.65,29.97 r90 bottom value=4.7µF (schematic designator C220)
C221 "C0805C476M9PAC7800" CAP-0805 7.52,65.05 r0 top value=47µF
C222 "C0805C476M9PAC7800" CAP-0805 6.765,79.669 r270 top value=47µF
C223 "C0805C476M9PAC7800" CAP-0805 14.775,88.166 r180 top value=47µF
C224 "CL03A104KP3NNNC" CAP-0201 33.127,42.875 r180 top value=100nF
C225 "CL03A104KP3NNNC" CAP-0201 33.078,27.59 r270 top value=100nF
C226 "C0805C476M9PAC7800" CAP-0805 34.426,44.175 r180 top value=47µF
C227 "C0805C476M9PAC7800" CAP-0805 35.103,41.405 r270 top value=47µF
C228 "CL03A104KP3NNNC" CAP-0201 40.591,35.844 r90 bottom value=100nF
C229 "CL03A104KP3NNNC" CAP-0201 39.891,35.844 r90 bottom value=100nF
C230 "CL03A104KP3NNNC" CAP-0201 37.145,33.755 r0 bottom value=100nF
C231 "CL03A104KP3NNNC" CAP-0201 45.614,38.949 r270 top value=100nF
C232 "CL03A104KP3NNNC" CAP-0201 46.255,29.532 r180 bottom value=100nF
C233 "CL03A104KP3NNNC" CAP-0201 46.255,30.332 r180 bottom value=100nF
C234 "CL03A104KP3NNNC" CAP-0201 46.255,32.132 r180 bottom value=100nF
C235 "CL03A104KP3NNNC" CAP-0201 38.396,32.349 r180 bottom value=100nF
C236 "CL03A104KP3NNNC" CAP-0201 38.396,31.649 r180 bottom value=100nF
C237 "CL03A104KP3NNNC" CAP-0201 38.396,33.749 r180 bottom value=100nF
C238 "CL03A104KP3NNNC" CAP-0201 38.396,33.049 r180 bottom value=100nF
C239 "CL03A104KP3NNNC" CAP-0201 42.423,25.9 r90 top value=100nF
C240 "CL03A104KP3NNNC" CAP-0201 44.217,35.218 r0 bottom value=100nF
C241 "CL03A104KP3NNNC" CAP-0201 47.686,30.499 r180 top value=100nF
C242 "CL03A104KP3NNNC" CAP-0201 38.386,35.149 r180 bottom value=100nF
C243 "CL03A104KP3NNNC" CAP-0201 41.486,35.849 r90 bottom value=100nF
C244 "CL03A104KP3NNNC" CAP-0201 47.686,31.349 r180 top value=100nF
C245 "CL03A104KP3NNNC" CAP-0201 40.144,30.259 r270 bottom value=100nF
C246_1 "GRM033R70J103KA01D" CAP-0201 75.328,18.852 r270 bottom value=10nF (schematic designator C246)
C246_2 "GRM033R70J103KA01D" CAP-0201 34.114,27.066 r270 top value=10nF (schematic designator C246)
C246_3 "GRM033R70J103KA01D" CAP-0201 3.465,76.719 r0 top value=10nF (schematic designator C246)
C246_4 "GRM033R70J103KA01D" CAP-0201 9.35,71.286 r270 top value=10nF (schematic designator C246)
C246_5 "GRM033R70J103KA01D" CAP-0201 98.998,54.246 r270 bottom value=10nF (schematic designator C246)
C246_6 "GRM033R70J103KA01D" CAP-0201 95.5,30.075 r90 bottom value=10nF (schematic designator C246)
C247 "CL03A104KP3NNNC" CAP-0201 64.616,7.7 r180 top value=100nF
C248 "CC0201GRNPO9BN100" CAP-0201 42.623,93.191 r270 bottom value=10pF
C249 "C0805C476M9PAC7800" CAP-0805 22.189,103.878 r90 bottom value=47µF
C250 "C0805C476M9PAC7800" CAP-0805 22.189,100.578 r90 bottom value=47µF
C251 "CL03A104KP3NNNC" CAP-0201 18.1,99.566 r0 top value=100nF
C252 "C0805C476M9PAC7800" CAP-0805 21.239,97.978 r180 bottom value=47µF
C253 "GRM033R60J105MEA2D" CAP-0201 46.923,83.816 r270 bottom value=1µF
C254 "GRM033R60J105MEA2D" CAP-0201 46.223,83.816 r270 bottom value=1µF
C255 "C0805C476M9PAC7800" CAP-0805 11.468,87.141 r0 top value=47µF
C256 "GRM21BR72E103KW03L" CAP-0805 12,135 r180 top value=10nF
C257 "CL03A104KP3NNNC" CAP-0201 40.582,75.724 r270 top value=100nF
C258 "CL03A104KP3NNNC" CAP-0201 34.107,77.849 r0 top value=100nF
C259 "C1005A475M6R3NT" CAP-0402 61.163,21.329 r0 top value=4.7µF
C260 "CL03A104KP3NNNC" CAP-0201 56.788,14.229 r180 top value=100nF
C261 "GRM0335C1E6R0CA01D" CAP-0201 59.038,22.974 r0 bottom locked value=6pF
C262 "CL03A104KP3NNNC" CAP-0201 59.138,14.229 r0 top value=100nF
C263 "CL03A104KP3NNNC" CAP-0201 56.988,13.329 r180 top value=100nF
C264 "GRM0335C1E6R0CA01D" CAP-0201 57.888,22.974 r180 bottom locked value=6pF
C265 "CL03A104KP3NNNC" CAP-0201 56.038,16.929 r0 top value=100nF
C266 "CL03A104KP3NNNC" CAP-0201 56.938,15.729 r180 top value=100nF
C267 "CL03A104KP3NNNC" CAP-0201 57.963,15.854 r90 top value=100nF
C268 "CL03A104KP3NNNC" CAP-0201 56.788,14.829 r180 top value=100nF
C269 "CL03A104KP3NNNC" CAP-0201 57.938,15.029 r180 top value=100nF
C270 "CL03A104KP3NNNC" CAP-0201 53.039,70.065 r90 top value=100nF
C271 "CL03A104KP3NNNC" CAP-0201 19.665,7.324 r0 top value=100nF
C272 "CL03A104KP3NNNC" CAP-0201 59.038,13.329 r0 top value=100nF
C273 "CL03A104KP3NNNC" CAP-0201 59.138,14.829 r0 top value=100nF
C274 "CL03A104KP3NNNC" CAP-0201 57.388,16.929 r0 top value=100nF
C275 "CL03A104KP3NNNC" CAP-0201 58.988,15.729 r0 top value=100nF
C276 "C0805C476M9PAC7800" CAP-0805 14.775,97.766 r180 top value=47µF
C277 "CL03A104KP3NNNC" CAP-0201 54.163,15.829 r0 top value=100nF
C278 "CL03A104KP3NNNC" CAP-0201 44.342,72.873 r270 top value=100nF
C279 "CL03A104KP3NNNC" CAP-0201 57.963,13.104 r270 top value=100nF
C280 "CL03A104KP3NNNC" CAP-0201 78.325,40 r90 top value=100nF
C281 "CL03A104KP3NNNC" CAP-0201 59.563,19.529 r0 top value=100nF
C282 "CL03A104KP3NNNC" CAP-0201 55.363,19.229 r180 top value=100nF
C283 "CL03A104KP3NNNC" CAP-0201 81.575,36.7 r90 top value=100nF
C284 "CL03A104KP3NNNC" CAP-0201 80.975,36.7 r90 top value=100nF
C285 "GRM033R71H221KA12D" CAP-0201 66.25,15.275 r270 bottom value=220pF
C286 "C1005A475M6R3NT" CAP-0402 66.725,17.791 r0 bottom value=4.7µF
C287 "C1005A475M6R3NT" CAP-0402 66.725,18.791 r0 bottom value=4.7µF
C288 "GRM21BR61H106ME43L" CAP-0805 66.768,11.671 r270 bottom value=10µF
C289 "CL03A104KP3NNNC" CAP-0201 67.625,35.347 r90 bottom value=100nF
C290 "CL03A104KP3NNNC" CAP-0201 66.925,35.347 r90 bottom value=100nF
C291 "CL03A104KP3NNNC" CAP-0201 59.95,18 r270 top value=100nF
C292 "GRM21BR61H106ME43L" CAP-0805 18.3,135 r90 top value=10µF
C293 "GRM21BR72E103KW03L" CAP-0805 5.9,139.2 r0 top value=10nF
C294 "GRM21BR61H106ME43L" CAP-0805 5.9,141.3 r180 top value=10µF
C295 "CC0201GRNPO9BN100" CAP-0201 43.623,93.191 r270 bottom value=10pF
C296 "C1005A475M6R3NT" CAP-0402 44.523,83.516 r270 bottom value=4.7µF
C297 "CL03A104KP3NNNC" CAP-0201 83.491,32.484 r315 top value=100nF
C298 "CL03A104KP3NNNC" CAP-0201 83.986,32.979 r315 top value=100nF
C299 "GRM033R60J224ME15D" CAP-0201 38.246,26.827 r90 top value=220nF
C300 "CL03A104KP3NNNC" CAP-0201 15.874,128.899 r180 top value=100nF
C301 "GRM155R61H104KE19D" CAP-0402 13.274,131.699 r270 top value=100nF
C302 "GRM21BR61H106ME43L" CAP-0805 89.505,98.645 r270 bottom value=10µF
C303 "GRM155R61H104KE19D" CAP-0402 91.005,98.08 r270 bottom value=100nF
C304 "GRM033R60J105MEA2D" CAP-0201 88.828,93.142 r90 bottom value=1µF
C305 "CL03A104KP3NNNC" CAP-0201 19.16,71.05 r270 top value=100nF
C306 "CL03A104KP3NNNC" CAP-0201 16.16,75.01 r90 top value=100nF
C307 "GRM033R60J224ME15D" CAP-0201 38.946,26.827 r90 top value=220nF
C308 "GRM033R60J105MEA2D" CAP-0201 88.828,94.322 r270 bottom value=1µF
C309 "CL03A104KP3NNNC" CAP-0201 34.623,29.191 r90 top value=100nF
C310 "CL03A104KP3NNNC" CAP-0201 34.023,29.191 r90 top value=100nF
C311 "C0805C476M9PAC7800" CAP-0805 69.181,20.959 r90 top value=47µF
C312 "C0805C476M9PAC7800" CAP-0805 18.1,103.415 r90 top value=47µF
C313 "C0805C476M9PAC7800" CAP-0805 14.775,102.165 r180 top value=47µF
C314 "CL03A104KP3NNNC" CAP-0201 11.442,34.651 r180 bottom value=100nF
C315 "C0805C476M9PAC7800" CAP-0805 14.775,113.865 r180 top value=47µF
C316 "C0805C476M9PAC7800" CAP-0805 14.775,123.265 r180 top value=47µF
C317 "C0805C476M9PAC7800" CAP-0805 14.775,111.765 r180 top value=47µF
C318 "C0805C476M9PAC7800" CAP-0805 18.1,110.915 r270 top value=47µF
C319 "GRM155R61H104KE19D" CAP-0402 6.835,115.265 r0 top value=100nF
C320 "GRM155R61H104KE19D" CAP-0402 6.835,103.965 r0 top value=100nF
C321 "GRM155R61H104KE19D" CAP-0402 6.835,89.816 r0 top value=100nF
C322 "GRM033R60J224ME15D" CAP-0201 70.135,25.881 r180 top value=220nF
C323 "GRM033R60J224ME15D" CAP-0201 70.131,26.51 r180 top value=220nF
C324 "CL03A104KP3NNNC" CAP-0201 37.775,25.55 r270 top value=100nF
C325 "CL03A104KP3NNNC" CAP-0201 37.075,25.55 r270 top value=100nF
C326 "GRM033R60J224ME15D" CAP-0201 44.875,26.827 r270 top value=220nF
C327 "GRM033R60J224ME15D" CAP-0201 44.275,26.827 r270 top value=220nF
C328 "CL03A104KP3NNNC" CAP-0201 11.442,36.401 r180 bottom value=100nF
C329 "CL03A104KP3NNNC" CAP-0201 11.442,14.401 r180 bottom value=100nF
C330 "CL03A104KP3NNNC" CAP-0201 11.442,12.651 r180 bottom value=100nF
C331 "CL03A104KP3NNNC" CAP-0201 18.4,14.035 r90 bottom value=100nF
C332 "C1005A475M6R3NT" CAP-0402 19.3,13.875 r270 bottom value=4.7µF
C333 "GRM155R61H104KE19D" CAP-0402 12.957,46.7 r0 top value=100nF
C334 "GRM31CR61A107MEA8L" CAP-1206 21.775,88.1 r0 bottom value=100µF
C335 "GRM31CR61A107MEA8L" CAP-1206 21.775,90.6 r0 bottom value=100µF
C336 "GRM31CR61A107MEA8L" CAP-1206 21.775,93.1 r0 bottom value=100µF
C337 "GRM31CR61A107MEA8L" CAP-1206 21.775,95.6 r0 bottom value=100µF
C338 "CL03A104KP3NNNC" CAP-0201 6.065,83.202 r0 top value=100nF
C339 "CL10B102KB8WPNC" CAP-0603 82.748,113.8 r180 bottom value=1nF
C340 "0603B103K500CT" CAP-0603 82.748,111.8 r180 bottom value=10nF
C341 "0603B104K500CT" CAP-0603 86.9,104.7 r270 bottom value=100nF
C342 "04025A4R7DAT2A" CAP-0402 84.703,102.143 r270 bottom value=4.7pF
C343 "CL10B102KB8WPNC" CAP-0603 90.265,72.779 r90 bottom value=1nF
C344 "0603B103K500CT" CAP-0603 90.265,75.779 r270 bottom value=10nF
C345 "GRM033R60J105MEA2D" CAP-0201 3.519,89.191 r90 top value=1µF
C346 "GRM033R60J105MEA2D" CAP-0201 21.7,8.775 r90 top value=1µF
C347 "GRM033R60J105MEA2D" CAP-0201 22.4,8.775 r90 top value=1µF
C348 "GRM033R60J105MEA2D" CAP-0201 23.1,8.775 r90 top value=1µF
C349 "GRM0335C1H4R0BA01D" CAP-0201 11.167,35.526 r270 bottom value=4pF
C350 "GRM155R61H104KE19D" CAP-0402 79.69,139.05 r270 bottom value=100nF
C351 "GRM155R61H104KE19D" CAP-0402 83.345,136.3 r180 bottom value=100nF
C352 "GRM21BR61H106ME43L" CAP-0805 85.58,137.25 r270 bottom value=10µF
C353 "GRM155R61H104KE19D" CAP-0402 87.18,140.925 r90 bottom value=100nF
C354 "GRM155R61H104KE19D" CAP-0402 85.88,132.935 r90 bottom value=100nF
C355 "C0805C476M9PAC7800" CAP-0805 87.58,133.35 r270 bottom value=47µF
C356 "GRM21BR61H106ME43L" CAP-0805 87.58,137.25 r270 bottom value=10µF
C357 "GRM21BR61H106ME43L" CAP-0805 89.58,137.25 r270 bottom value=10µF
C358 "CC0201JPNPO8BN220" CAP-0201 83.98,141.27 r270 bottom value=22pF
C359 "C0805C476M9PAC7800" CAP-0805 89.58,133.35 r270 bottom value=47µF
C360 "GRM033R60J105MEA2D" CAP-0201 88.828,89.175 r90 bottom value=1µF
C361 "04025A4R7DAT2A" CAP-0402 84.703,104.013 r90 bottom value=4.7pF
D1 "PJGBLC24C-AU_R1_000A1" "SOD323 NO POLARITY" 93.05,74.729 r0 bottom
D2 "SMBJ24CA" SMB_NOPOLARITY 41.332,10.236 r270 bottom
D3 "SX34_R1_00001" "SMA DO214AC" 73.484,72.969 r270 bottom
D4 "SX34_R1_00001" "SMA DO214AC" 85.7,77.4 r180 bottom
D5 "SMBJ24CA" SMB_NOPOLARITY 81.932,108.336 r0 bottom
D6_1 "RCLAMP0524PATCT" SLP2510P8 14.624,152.279 r90 top (schematic designator D6)
D6_2 "RCLAMP0524PATCT" SLP2510P8 70.624,152.279 r90 top (schematic designator D6)
D6_3 "RCLAMP0524PATCT" SLP2510P8 42.624,152.279 r90 top (schematic designator D6)
D7_1 "RCLAMP0524PATCT" SLP2510P8 17.624,152.279 r90 top (schematic designator D7)
D7_2 "RCLAMP0524PATCT" SLP2510P8 73.624,152.279 r90 top (schematic designator D7)
D7_3 "RCLAMP0524PATCT" SLP2510P8 45.624,152.279 r90 top (schematic designator D7)
D8_1 "RCLAMP0524PATCT" SLP2510P8 20.624,152.279 r90 top (schematic designator D8)
D8_2 "RCLAMP0524PATCT" SLP2510P8 76.624,152.279 r90 top (schematic designator D8)
D8_3 "RCLAMP0524PATCT" SLP2510P8 48.624,152.279 r90 top (schematic designator D8)
D9 "SX34_R1_00001" "SMA DO214AC" 81.232,116.8 r180 bottom
D10_1 "DF2B7ASL,L3F" DF2B7ASL,L3F 22.524,152.66 r0 top (schematic designator D10)
D10_2 "DF2B7ASL,L3F" DF2B7ASL,L3F 78.524,152.66 r0 top (schematic designator D10)
D10_3 "DF2B7ASL,L3F" DF2B7ASL,L3F 50.524,152.66 r0 top (schematic designator D10)
D11_1 "DF2B7ASL,L3F" DF2B7ASL,L3F 23.524,152.66 r180 top (schematic designator D11)
D11_2 "DF2B7ASL,L3F" DF2B7ASL,L3F 79.524,152.66 r180 top (schematic designator D11)
D11_3 "DF2B7ASL,L3F" DF2B7ASL,L3F 51.524,152.66 r180 top (schematic designator D11)
D12 "DF2B7ASL,L3F" DF2B7ASL,L3F 75.437,62.804 r90 bottom
D13 "RCLAMP0524PATCT" SLP2510P8 87.002,64.8 r270 top
D14 "RCLAMP0524PATCT" SLP2510P8 88.73,53.2 r270 top
D15_1 "DF2B7ASL,L3F" DF2B7ASL,L3F 24.524,152.66 r0 top (schematic designator D15)
D15_2 "DF2B7ASL,L3F" DF2B7ASL,L3F 80.524,152.66 r0 top (schematic designator D15)
D15_3 "DF2B7ASL,L3F" DF2B7ASL,L3F 52.524,152.66 r0 top (schematic designator D15)
D16 "RCLAMP0524PATCT" SLP2510P8 83.402,64.8 r270 top
D17 "DF2B7ASL,L3F" DF2B7ASL,L3F 42.926,56.238 r270 bottom
D18 "RCLAMP0524PATCT" SLP2510P8 60.116,39.725 r90 bottom
D19 "RCLAMP0524PATCT" SLP2510P8 52.496,39.725 r90 bottom
D20 "RCLAMP0524PATCT" SLP2510P8 44.866,39.725 r90 bottom
D21 "DF2B7ASL,L3F" DF2B7ASL,L3F 41.656,56.238 r270 bottom
D22 "PJGBLC24C-AU_R1_000A1" "SOD323 NO POLARITY" 90.65,103.765 r90 bottom
D23 "PJGBLC24C-AU_R1_000A1" "SOD323 NO POLARITY" 90.65,107.165 r270 bottom
D24 "DF2B7ASL,L3F" DF2B7ASL,L3F 40.386,56.238 r270 bottom
D25 "RCLAMP0524PATCT" SLP2510P8 27.731,39.811 r90 bottom
D26 "RCLAMP0524PATCT" SLP2510P8 22.651,39.811 r90 bottom
D27 "DF2B7ASL,L3F" DF2B7ASL,L3F 33.052,42.175 r180 top
D28 "RCLAMP0524PATCT" SLP2510P8 20.579,28.225 r180 top
D29 "RCLAMP0524PATCT" SLP2510P8 20.579,31.025 r180 top
D30 "RCLAMP0524PATCT" SLP2510P8 20.579,33.825 r180 top
D31 "RCLAMP0524PATCT" SLP2510P8 20.579,36.625 r180 top
D32 "RCLAMP0524PATCT" SLP2510P8 20.579,39.425 r180 top
D33 "DF2B7ASL,L3F" DF2B7ASL,L3F 32.824,38.375 r270 top
D34 "DF2B7ASL,L3F" DF2B7ASL,L3F 34.223,37.675 r90 top
D35 "DF2B7ASL,L3F" DF2B7ASL,L3F 32.824,36.975 r90 top
D36 "RCLAMP0524PATCT" SLP2510P8 32.806,39.812 r90 bottom
D37 "SMBJ24CA" SMB_NOPOLARITY 69.576,51.732 r270 bottom
D38 "RCLAMP0524PATCT" SLP2510P8 31.541,56.238 r90 bottom
D39 "RCLAMP0524PATCT" SLP2510P8 26.416,56.238 r90 bottom
D40 "DF2B7ASL,L3F" DF2B7ASL,L3F 33.276,26.664 r180 top
D41 "DF2B7ASL,L3F" DF2B7ASL,L3F 32.824,34.475 r90 top
D42 "DF2B7ASL,L3F" DF2B7ASL,L3F 32.824,35.375 r270 top
D43 "SMBJ24CA" SMB_NOPOLARITY 23.2,148.316 r270 bottom
D44 "SX34_R1_00001" "SMA DO214AC" 24.13,8.3 r180 bottom
D61 "DF2B7ASL,L3F" DF2B7ASL,L3F 11.61,23.461 r0 top
D62 "DF2B7ASL,L3F" DF2B7ASL,L3F 11.61,20.921 r0 top
D63 "DF2B7ASL,L3F" DF2B7ASL,L3F 11.61,15.841 r0 top
D64 "DF2B7ASL,L3F" DF2B7ASL,L3F 22.91,22.221 r180 top
D65 "DF2B7ASL,L3F" DF2B7ASL,L3F 22.91,21.421 r180 top
D66 "DF2B7ASL,L3F" DF2B7ASL,L3F 22.91,20.421 r180 top
D67 "DF2B7ASL,L3F" DF2B7ASL,L3F 22.91,18.381 r180 top
D69 "DF2B7ASL,L3F" DF2B7ASL,L3F 21.711,68.799 r180 top
D70 "DF2B7ASL,L3F" DF2B7ASL,L3F 24.8,77.35 r0 top
D71 "DF2B7ASL,L3F" DF2B7ASL,L3F 27.2,77.35 r180 top
D72 "RCLAMP0524PATCT" SLP2510P8 90.344,76.229 r180 top
D73 "RCLAMP0524PATCT" SLP2510P8 90.344,73.229 r180 top
D74 "RCLAMP0524PATCT" SLP2510P8 90.345,69.859 r180 top
D75 "RCLAMP0524PATCT" SLP2510P8 90.345,79.536 r180 top
D76 "RCLAMP0524PATCT" SLP2510P8 98.3,31.975 r90 top
D77 "RCLAMP0524PATCT" SLP2510P8 95.4,31.975 r90 top
D78 "RCLAMP0524PATCT" SLP2510P8 83.076,42.675 r180 top
D79 "RCLAMP0524PATCT" SLP2510P8 83.076,36.925 r180 top
D80 "DF2B7ASL,L3F" DF2B7ASL,L3F 22.391,6.624 r180 top
D81 "DF2B7ASL,L3F" DF2B7ASL,L3F 20.991,6.624 r0 top
D82 "DF2B7ASL,L3F" DF2B7ASL,L3F 19.665,6.669 r0 top
D83 "DF2B7ASL,L3F" DF2B7ASL,L3F 33.059,144.441 r90 bottom
D84 "DF2B7ASL,L3F" DF2B7ASL,L3F 31.759,144.441 r90 bottom
D85 "DF2B7ASL,L3F" DF2B7ASL,L3F 27.959,152.817 r270 bottom
D86 "DF2B7ASL,L3F" DF2B7ASL,L3F 56.049,152.752 r180 bottom
D87 "DF2B7ASL,L3F" DF2B7ASL,L3F 54.429,152.752 r0 bottom
D88 "DF2B7ASL,L3F" DF2B7ASL,L3F 52.289,152.752 r180 bottom
D89 "DF2B7ASL,L3F" DF2B7ASL,L3F 50.619,152.752 r0 bottom
D90 "RCLAMP0524PATCT" SLP2510P8 60.979,152.817 r270 bottom
D91 "RCLAMP0524PATCT" SLP2510P8 64.428,143.015 r180 bottom
D92 "RCLAMP0524PATCT" SLP2510P8 53.359,143.816 r90 bottom
D93 "RCLAMP0524PATCT" SLP2510P8 45.739,143.816 r90 bottom
D94 "RCLAMP0524PATCT" SLP2510P8 38.119,143.816 r90 bottom
D95 "RCLAMP0524PATCT" SLP2510P8 45.739,152.817 r90 bottom
D96 "RCLAMP0524PATCT" SLP2510P8 38.119,152.817 r90 bottom
D97 "RCLAMP0524PATCT" SLP2510P8 30.499,152.817 r90 bottom
D98 "DF2B7ASL,L3F" DF2B7ASL,L3F 47.009,97.229 r90 bottom
D99 "DF2B7ASL,L3F" DF2B7ASL,L3F 45.739,97.229 r90 bottom
D100 "DF2B7ASL,L3F" DF2B7ASL,L3F 44.469,97.229 r90 bottom
D101 "RCLAMP0524PATCT" SLP2510P8 40.024,96.953 r90 bottom
D102 "RCLAMP0524PATCT" SLP2510P8 34.944,96.953 r90 bottom
D103 "RCLAMP0524PATCT" SLP2510P8 46.374,105.954 r90 bottom
D104 "RCLAMP0524PATCT" SLP2510P8 41.294,105.954 r90 bottom
D105 "RCLAMP0524PATCT" SLP2510P8 34.944,105.954 r90 bottom
D106 "DF2B7ASL,L3F" DF2B7ASL,L3F 27.91,97.401 r90 bottom
DL1_1 "LTST-C28NBEGK-2A" SMLP34RGB2W 86.75,1.25 r90 top (schematic designator DL1)
DL1_2 "LTST-C28NBEGK-2A" SMLP34RGB2W 82.25,1.25 r90 top (schematic designator DL1)
DL1_3 "LTST-C28NBEGK-2A" SMLP34RGB2W 77.75,1.25 r90 top (schematic designator DL1)
DL1_4 "LTST-C28NBEGK-2A" SMLP34RGB2W 73.25,1.25 r90 top (schematic designator DL1)
DL2 "XHY-STB0603SR" LEDC1608X80N-AK 98.326,65.909 r180 top
DL3 "LTST-C190KGKT" LEDC1608X80N-AK 98.326,67.609 r180 top
F1 "MF-MSMF050-2-W2" 1812 22.56,66.55 r180 top
F2 "0ZCG0110CF2B" 1812 46.839,8.353 r180 bottom
F3 "MF-MSMF150/24X" 1812 18.4,148.316 r90 bottom
F4 "MF-MSMF050-2-W2" 1812 73.484,66.779 r90 bottom
Fiducial_1 "Fiducial mark 1mm with 2mm solder" "Fiducial mark 1mm with circle-Footprint-1" 11.9,10.6 r90 top
Fiducial_2 "Fiducial mark 1mm with 2mm solder" "Fiducial mark 1mm with circle-Footprint-1" 85.5,156 r90 bottom
Fiducial_3 "Fiducial mark 1mm with 2mm solder" "Fiducial mark 1mm with circle-Footprint-1" 2.286,149.775 r90 top
Fiducial_4 "Fiducial mark 1mm with 2mm solder" "Fiducial mark 1mm with circle-Footprint-1" 84,156 r90 top
Fiducial_5 "Fiducial mark 1mm with 2mm solder" "Fiducial mark 1mm with circle-Footprint-1" 8,156 r90 bottom
Fiducial_6 "Fiducial mark 1mm with 2mm solder" "Fiducial mark 1mm with circle-Footprint-1" 14.117,1.6 r90 bottom
H1 "9774050151R" 9774050151R 5.401,70.736 r0 top locked
H2 "9774050151R" 9774050151R 80.401,70.736 r0 top locked
H3 "9774050151R" 9774050151R 80.401,145.736 r0 top locked
H4 "9774050151R" 9774050151R 5.401,145.736 r0 top locked
H5 "9774040243R" 9774040243R 57.251,34.225 r0 top locked
J1 "CX90B2-24P" CX90B2-24P 95.302,74.729 r90 top
J2 "TRJT9010A98NL" TRJT9010A98NL 88.859,17.35 r270 top locked
J3_1 "TF31-22S-0.5SH(800)" TF31-22S-0.5SH(800) 18.374,156.1 r180 top (schematic designator J3)
J3_2 "TF31-22S-0.5SH(800)" TF31-22S-0.5SH(800) 74.374,156.1 r180 top (schematic designator J3)
J3_3 "TF31-22S-0.5SH(800)" TF31-22S-0.5SH(800) 46.374,156.1 r180 top (schematic designator J3)
J4 "19PF-P3-S297" 19PF-P3-S297 87.075,59 r90 top locked
J5 "SHDT-2014-TS" SHDT-2014-TS 94.548,114.8 r180 top locked
J6 "23TW-018" 23TW-018 32.5,59 r0 top locked
J7 "209B-DA12" 209B-DA12 92.4,40.675 r90 top locked
J8 "DG127-5.0-05P-13-00Z(H)" DG127-5.0-05P-13-00Z(H) 95.9,95.4 r270 top locked
J10 "MDT580M01001" MDT580M01001 27.505,34.175 r90 top locked
J13 "SM04B-SRSS-TB(LF)(SN)" SM04B-SRSS-TB(LF)(SN)-Footprint-1 21.917,3.087 r180 top
JANALOG "20TW-995" 1X14-CUSTOM 45.72,2.54 r0 top locked
JCTL "20TW-638" 20TW-638 17.26,20.921 r270 top locked
JDIGITAL "20TW-994" 1X18-CUSTOM 45.72,50.8 r180 top locked
JFAN "B4B-PH-SM4-TB(LF)(SN)" B4B-PH-SM4-TB(LF)(SN) 26,74.1 r180 top locked
JMEDIA "CSEC202-3002A001C1AF" CSEC202-3002A001C1AF 46.374,148.316 r180 bottom locked
JMISC "CSEC202-3002A001C1AF" CSEC202-3002A001C1AF 46.374,101.453 r180 bottom locked
JOMEGA "CSEC202-5002A001C1AF" CSEC202-5002A001C1AF 41.701,44.175 r180 bottom locked
JSPI "23TW-025" 23TW-025 64.897,27.94 r270 top locked
L1 "BLM15PX121SN1D" L-0402 74.94,13.115 r90 top value=120µH
L2 "BLM15PX121SN1D" L-0402 70.656,11.134 r180 bottom value=120µH
L3 "PMF63-561MT" PMF63 13.4,107.165 r0 top
L4 "PMF63-561MT" PMF63 13.4,118.465 r0 top
L5 "PMF63-561MT" PMF63 13.4,92.966 r0 top
L6 "BLM15PX121SN1D" L-0402 59.563,20.754 r270 top value=120µH
L7 "MPL-AT252012-1R0" "INDUCTOR 2520" 14.368,79.966 r90 top
L8 "MPL-AT252012-1R0" "INDUCTOR 2520" 70.756,23.859 r180 top
L9 "0201DS-0N6XKEW" "0201DS Coilcraft" 11.167,13.526 r270 bottom
L10 "SMNR5030-4R7MT" "Inductor 5030" 82.28,132.5 r90 bottom
L11 "BLM15PX121SN1D" L-0402 74.849,53.84 r0 top value=120µH
L12 "BLM15PX121SN1D" L-0402 74.875,64.335 r270 top value=120µH
L13 "BLM15PX121SN1D" L-0402 73.575,64.335 r270 top value=120µH
L14 "BLM15PX121SN1D" L-0402 76.949,53.84 r180 top value=120µH
L15 "BLM15PX121SN1D" L-0402 72.849,53.84 r180 top value=120µH
L16 "BLM15PX121SN1D" L-0402 76.275,64.335 r270 top value=120µH
L17 "BLM15PX121SN1D" L-0402 42.923,83.516 r90 bottom value=120µH
L18 "BLM15PX121SN1D" L-0402 69.826,38.949 r90 top value=120µH
L19 "BLM15PX121SN1D" L-0402 43.698,25.175 r180 top value=120µH
L20 "BLM15PX121SN1D" L-0402 41.979,29.686 r180 bottom value=120µH
L21 "LQM2MPN2R2NG0L" LQM2MPN2R2NG0L 67.825,15.791 r270 bottom
LED1 "LTST-C191TBKT-5A" LEDC1608X80N-AK 26.46,20.863 r225 top locked
LED2 "LTST-C191TBKT-5A" LEDC1608X80N-AK 28.56,20.863 r225 top locked
LED3 "LTST-C191TBKT-5A" LEDC1608X80N-AK 30.66,20.863 r225 top locked
LED4 "LTST-C191TBKT-5A" LEDC1608X80N-AK 32.76,20.863 r225 top locked
LED5 "LTST-C191TBKT-5A" LEDC1608X80N-AK 34.86,20.863 r225 top locked
LED6 "LTST-C191TBKT-5A" LEDC1608X80N-AK 36.96,20.863 r225 top locked
LED7 "LTST-C191TBKT-5A" LEDC1608X80N-AK 39.06,20.863 r225 top locked
LED8 "LTST-C191TBKT-5A" LEDC1608X80N-AK 41.16,20.863 r225 top locked
LED9 "LTST-C191TBKT-5A" LEDC1608X80N-AK 43.26,20.863 r225 top locked
LED10 "LTST-C191TBKT-5A" LEDC1608X80N-AK 45.36,20.863 r225 top locked
LED11 "LTST-C191TBKT-5A" LEDC1608X80N-AK 47.46,20.863 r225 top locked
LED12 "LTST-C191TBKT-5A" LEDC1608X80N-AK 49.56,20.863 r225 top locked
LED13 "LTST-C191TBKT-5A" LEDC1608X80N-AK 51.66,20.863 r225 top locked
LED14 "LTST-C191TBKT-5A" LEDC1608X80N-AK 26.46,18.763 r225 top locked
LED15 "LTST-C191TBKT-5A" LEDC1608X80N-AK 28.56,18.763 r225 top locked
LED16 "LTST-C191TBKT-5A" LEDC1608X80N-AK 30.66,18.763 r225 top locked
LED17 "LTST-C191TBKT-5A" LEDC1608X80N-AK 32.76,18.763 r225 top locked
LED18 "LTST-C191TBKT-5A" LEDC1608X80N-AK 34.86,18.763 r225 top locked
LED19 "LTST-C191TBKT-5A" LEDC1608X80N-AK 36.96,18.763 r225 top locked
LED20 "LTST-C191TBKT-5A" LEDC1608X80N-AK 39.06,18.763 r225 top locked
LED21 "LTST-C191TBKT-5A" LEDC1608X80N-AK 41.16,18.763 r225 top locked
LED22 "LTST-C191TBKT-5A" LEDC1608X80N-AK 43.26,18.763 r225 top locked
LED23 "LTST-C191TBKT-5A" LEDC1608X80N-AK 45.36,18.763 r225 top locked
LED24 "LTST-C191TBKT-5A" LEDC1608X80N-AK 47.46,18.763 r225 top locked
LED25 "LTST-C191TBKT-5A" LEDC1608X80N-AK 49.56,18.763 r225 top locked
LED26 "LTST-C191TBKT-5A" LEDC1608X80N-AK 51.66,18.763 r225 top locked
LED27 "LTST-C191TBKT-5A" LEDC1608X80N-AK 26.46,16.663 r225 top locked
LED28 "LTST-C191TBKT-5A" LEDC1608X80N-AK 28.56,16.663 r225 top locked
LED29 "LTST-C191TBKT-5A" LEDC1608X80N-AK 30.66,16.663 r225 top locked
LED30 "LTST-C191TBKT-5A" LEDC1608X80N-AK 32.76,16.663 r225 top locked
LED31 "LTST-C191TBKT-5A" LEDC1608X80N-AK 34.86,16.663 r225 top locked
LED32 "LTST-C191TBKT-5A" LEDC1608X80N-AK 36.96,16.663 r225 top locked
LED33 "LTST-C191TBKT-5A" LEDC1608X80N-AK 39.06,16.663 r225 top locked
LED34 "LTST-C191TBKT-5A" LEDC1608X80N-AK 41.16,16.663 r225 top locked
LED35 "LTST-C191TBKT-5A" LEDC1608X80N-AK 43.26,16.663 r225 top locked
LED36 "LTST-C191TBKT-5A" LEDC1608X80N-AK 45.36,16.663 r225 top locked
LED37 "LTST-C191TBKT-5A" LEDC1608X80N-AK 47.46,16.663 r225 top locked
LED38 "LTST-C191TBKT-5A" LEDC1608X80N-AK 49.56,16.663 r225 top locked
LED39 "LTST-C191TBKT-5A" LEDC1608X80N-AK 51.66,16.663 r225 top locked
LED40 "LTST-C191TBKT-5A" LEDC1608X80N-AK 26.46,14.563 r225 top locked
LED41 "LTST-C191TBKT-5A" LEDC1608X80N-AK 28.56,14.563 r225 top locked
LED42 "LTST-C191TBKT-5A" LEDC1608X80N-AK 30.66,14.563 r225 top locked
LED43 "LTST-C191TBKT-5A" LEDC1608X80N-AK 32.76,14.563 r225 top locked
LED44 "LTST-C191TBKT-5A" LEDC1608X80N-AK 34.86,14.563 r225 top locked
LED45 "LTST-C191TBKT-5A" LEDC1608X80N-AK 36.96,14.563 r225 top locked
LED46 "LTST-C191TBKT-5A" LEDC1608X80N-AK 39.06,14.563 r225 top locked
LED47 "LTST-C191TBKT-5A" LEDC1608X80N-AK 41.16,14.563 r225 top locked
LED48 "LTST-C191TBKT-5A" LEDC1608X80N-AK 43.26,14.563 r225 top locked
LED49 "LTST-C191TBKT-5A" LEDC1608X80N-AK 45.36,14.563 r225 top locked
LED50 "LTST-C191TBKT-5A" LEDC1608X80N-AK 47.46,14.563 r225 top locked
LED51 "LTST-C191TBKT-5A" LEDC1608X80N-AK 49.56,14.563 r225 top locked
LED52 "LTST-C191TBKT-5A" LEDC1608X80N-AK 51.66,14.563 r225 top locked
LED53 "LTST-C191TBKT-5A" LEDC1608X80N-AK 26.46,12.463 r225 top locked
LED54 "LTST-C191TBKT-5A" LEDC1608X80N-AK 28.56,12.463 r225 top locked
LED55 "LTST-C191TBKT-5A" LEDC1608X80N-AK 30.66,12.463 r225 top locked
LED56 "LTST-C191TBKT-5A" LEDC1608X80N-AK 32.76,12.463 r225 top locked
LED57 "LTST-C191TBKT-5A" LEDC1608X80N-AK 34.86,12.463 r225 top locked
LED58 "LTST-C191TBKT-5A" LEDC1608X80N-AK 36.96,12.463 r225 top locked
LED59 "LTST-C191TBKT-5A" LEDC1608X80N-AK 39.06,12.463 r225 top locked
LED60 "LTST-C191TBKT-5A" LEDC1608X80N-AK 41.16,12.463 r225 top locked
LED61 "LTST-C191TBKT-5A" LEDC1608X80N-AK 43.26,12.463 r225 top locked
LED62 "LTST-C191TBKT-5A" LEDC1608X80N-AK 45.36,12.463 r225 top locked
LED63 "LTST-C191TBKT-5A" LEDC1608X80N-AK 47.46,12.463 r225 top locked
LED64 "LTST-C191TBKT-5A" LEDC1608X80N-AK 49.56,12.463 r225 top locked
LED65 "LTST-C191TBKT-5A" LEDC1608X80N-AK 51.66,12.463 r225 top locked
LED66 "LTST-C191TBKT-5A" LEDC1608X80N-AK 26.46,10.363 r225 top locked
LED67 "LTST-C191TBKT-5A" LEDC1608X80N-AK 28.56,10.363 r225 top locked
LED68 "LTST-C191TBKT-5A" LEDC1608X80N-AK 30.66,10.363 r225 top locked
LED69 "LTST-C191TBKT-5A" LEDC1608X80N-AK 32.76,10.363 r225 top locked
LED70 "LTST-C191TBKT-5A" LEDC1608X80N-AK 34.86,10.363 r225 top locked
LED71 "LTST-C191TBKT-5A" LEDC1608X80N-AK 36.96,10.363 r225 top locked
LED72 "LTST-C191TBKT-5A" LEDC1608X80N-AK 39.06,10.363 r225 top locked
LED73 "LTST-C191TBKT-5A" LEDC1608X80N-AK 41.16,10.363 r225 top locked
LED74 "LTST-C191TBKT-5A" LEDC1608X80N-AK 43.26,10.363 r225 top locked
LED75 "LTST-C191TBKT-5A" LEDC1608X80N-AK 45.36,10.363 r225 top locked
LED76 "LTST-C191TBKT-5A" LEDC1608X80N-AK 47.46,10.363 r225 top locked
LED77 "LTST-C191TBKT-5A" LEDC1608X80N-AK 49.56,10.363 r225 top locked
LED78 "LTST-C191TBKT-5A" LEDC1608X80N-AK 51.66,10.363 r225 top locked
LED79 "LTST-C191TBKT-5A" LEDC1608X80N-AK 26.46,8.263 r225 top locked
LED80 "LTST-C191TBKT-5A" LEDC1608X80N-AK 28.56,8.263 r225 top locked
LED81 "LTST-C191TBKT-5A" LEDC1608X80N-AK 30.66,8.263 r225 top locked
LED82 "LTST-C191TBKT-5A" LEDC1608X80N-AK 32.76,8.263 r225 top locked
LED83 "LTST-C191TBKT-5A" LEDC1608X80N-AK 34.86,8.263 r225 top locked
LED84 "LTST-C191TBKT-5A" LEDC1608X80N-AK 36.96,8.263 r225 top locked
LED85 "LTST-C191TBKT-5A" LEDC1608X80N-AK 39.06,8.263 r225 top locked
LED86 "LTST-C191TBKT-5A" LEDC1608X80N-AK 41.16,8.263 r225 top locked
LED87 "LTST-C191TBKT-5A" LEDC1608X80N-AK 43.26,8.263 r225 top locked
LED88 "LTST-C191TBKT-5A" LEDC1608X80N-AK 45.36,8.263 r225 top locked
LED89 "LTST-C191TBKT-5A" LEDC1608X80N-AK 47.46,8.263 r225 top locked
LED90 "LTST-C191TBKT-5A" LEDC1608X80N-AK 49.56,8.263 r225 top locked
LED91 "LTST-C191TBKT-5A" LEDC1608X80N-AK 51.66,8.263 r225 top locked
LED92 "LTST-C191TBKT-5A" LEDC1608X80N-AK 26.46,6.163 r225 top locked
LED93 "LTST-C191TBKT-5A" LEDC1608X80N-AK 28.56,6.163 r225 top locked
LED94 "LTST-C191TBKT-5A" LEDC1608X80N-AK 30.66,6.163 r225 top locked
LED95 "LTST-C191TBKT-5A" LEDC1608X80N-AK 32.76,6.163 r225 top locked
LED96 "LTST-C191TBKT-5A" LEDC1608X80N-AK 34.86,6.163 r225 top locked
LED97 "LTST-C191TBKT-5A" LEDC1608X80N-AK 36.96,6.163 r225 top locked
LED98 "LTST-C191TBKT-5A" LEDC1608X80N-AK 39.06,6.163 r225 top locked
LED99 "LTST-C191TBKT-5A" LEDC1608X80N-AK 41.16,6.163 r225 top locked
LED100 "LTST-C191TBKT-5A" LEDC1608X80N-AK 43.26,6.163 r225 top locked
LED101 "LTST-C191TBKT-5A" LEDC1608X80N-AK 45.36,6.163 r225 top locked
LED102 "LTST-C191TBKT-5A" LEDC1608X80N-AK 47.46,6.163 r225 top locked
LED103 "LTST-C191TBKT-5A" LEDC1608X80N-AK 49.56,6.163 r225 top locked
LED104 "LTST-C191TBKT-5A" LEDC1608X80N-AK 51.66,6.163 r225 top locked
LOVE "Test point 1.00mm" TP-1.00MM 69.71,22.663 r90 bottom
MODULE1 "MODULE" MODULE 48.882,108.436 r180 top locked
PB1 "TS42031-160WWS027260" TS42 6.35,49.403 r0 top
PB2 "TL3340AF160QG" TL3340AF160QG-Footprint-1 14.117,1.624 r0 top
Q1 "SQS414CENW-T1_GE3" SQS414CENW-T1_GE3 15.3,138.758 r270 top
Q2 "SQS414CENW-T1_GE3" SQS414CENW-T1_GE3 11.6,138.758 r270 top
Q3 "2N7002DW-7-F" SOT363 78.657,91.215 r180 bottom
Q4 "2N7002DW-7-F" SOT363 16.15,11.1 r180 top
Q5 "SQS414CENW-T1_GE3" SQS414CENW-T1_GE3 2.4,135.742 r90 top
Q6 "SQS414CENW-T1_GE3" SQS414CENW-T1_GE3 6.1,135.742 r90 top
Q7 "2N7002DW-7-F" SOT363 22.4,11.1 r180 top
R1 "RC0201FR-07100RL" RES-0201 75.169,127.776 r90 bottom value=100
R2 "RC0201FR-07100RL" RES-0201 64.369,126.553 r270 bottom value=100
R3 "RC0201FR-07100RL" RES-0201 28.969,110.474 r90 bottom value=100
R4 "RC0201FR-07100RL" RES-0201 29.682,106.311 r90 bottom value=100
R5 "RC0201FR-07100RL" RES-0201 24.982,110.474 r90 bottom value=100
R6 "ERJ-1GNF5101C" RES-0201 47.686,29.199 r0 top value=5.1k
R7 "ERJ-1GNF5101C" RES-0201 47.686,31.999 r0 top value=5.1k
R8 "AC0201FR-07330RL" RES-0201 35.473,29.824 r90 top value=330
R9 "AC0201FR-07330RL" RES-0201 41.386,38.949 r270 top value=330
R10 "AC0201FR-07330RL" RES-0201 47.686,35.899 r180 top value=330
R11 "AC0201FR-07330RL" RES-0201 46.255,32.732 r180 bottom value=330
R12 "RC0201FR-07100RL" RES-0201 55.899,105.553 r90 bottom value=100
R13 "RC0201FR-07100RL" RES-0201 58.439,105.553 r90 bottom value=100
R14 "RC0201FR-07100RL" RES-0201 19.239,131.699 r270 top value=100
R15 "RC0201FR-07100RL" RES-0201 57.169,105.553 r90 bottom value=100
R16 "RC0201FR-0710KL" RES-0201 75.169,128.926 r270 bottom value=10k
R17 "RC0201FR-0710KL" RES-0201 64.369,125.381 r90 bottom value=10k
R18 "RC0201FR-0710KL" RES-0201 28.969,111.674 r270 bottom value=10k
R19 "RC0201FR-0710KL" RES-0201 29.682,107.511 r270 bottom value=10k
R20 "RC0201FR-0710KL" RES-0201 24.982,111.674 r270 bottom value=10k
R21 "RC0805FR-070RL" RES-0805 14.775,85.309 r0 top value=0
R22 "RC0805FR-070RL" RES-0805 14.783,83.341 r0 top value=0
R23 "RC0201FR-074K7L" RES-0201 32.875,27.307 r180 bottom value=4.7k
R24 "RC0201FR-0710KL" RES-0201 30.3,31.17 r270 bottom value=10k
R25 "RC0201FR-0724KL" RES-0201 96.1,30.075 r90 bottom value=24k
R26 "RC0201FR-0724KL" RES-0201 98.298,54.246 r270 bottom value=24k
R27 "RC0201FR-0710KL" RES-0201 55.899,106.753 r270 bottom value=10k
R28 "RC0201FR-0710KL" RES-0201 58.439,106.753 r270 bottom value=10k
R29 "RC0201FR-0710KL" RES-0201 19.239,130.399 r90 top value=10k
R30 "RC0201FR-0710KL" RES-0201 57.169,106.753 r270 bottom value=10k
R31 "RC0201FR-07100RL" RES-0201 76.069,128.926 r270 bottom value=100
R32 "RC0201FR-07100RL" RES-0201 67.069,126.553 r270 bottom value=100
R33 "RC0201FR-07100RL" RES-0201 67.969,126.553 r270 bottom value=100
R34 "RC0201FR-07100RL" RES-0201 72.469,126.548 r270 bottom value=100
R35 "RC0201FR-07100RL" RES-0201 71.569,126.548 r270 bottom value=100
R36 "RC0201FR-07100RL" RES-0201 69.769,126.548 r270 bottom value=100
R37 "RC0201FR-07100RL" RES-0201 65.269,126.553 r270 bottom value=100
R38 "RC0201FR-07100RL" RES-0201 68.869,126.553 r270 bottom value=100
R39 "RC0201FR-07100RL" RES-0201 70.669,126.548 r270 bottom value=100
R40 "RC0201FR-07100RL" RES-0201 75.169,126.548 r270 bottom value=100
R41 "RC0201FR-07100RL" RES-0201 73.369,126.543 r270 bottom value=100
R42 "RC0201FR-07100RL" RES-0201 66.169,126.553 r270 bottom value=100
R43 "RC0201FR-07100RL" RES-0201 74.269,126.543 r270 bottom value=100
R44 "RC0201FR-0710KL" RES-0201 76.069,127.776 r90 bottom value=10k
R45 "RC0201FR-0710KL" RES-0201 67.069,125.408 r90 bottom value=10k
R46 "RC0201FR-0710KL" RES-0201 67.969,125.408 r90 bottom value=10k
R47 "RC0201FR-0710KL" RES-0201 72.469,125.403 r90 bottom value=10k
R48 "RC0201FR-0710KL" RES-0201 71.569,125.403 r90 bottom value=10k
R49 "RC0201FR-0710KL" RES-0201 69.769,125.403 r90 bottom value=10k
R50 "RC0201FR-0710KL" RES-0201 65.269,125.408 r90 bottom value=10k
R51 "RC0201FR-0710KL" RES-0201 68.869,125.408 r90 bottom value=10k
R52 "RC0201FR-0710KL" RES-0201 70.669,125.403 r90 bottom value=10k
R53 "RC0201FR-0710KL" RES-0201 75.169,125.403 r90 bottom value=10k
R54 "RC0201FR-0710KL" RES-0201 73.369,125.398 r90 bottom value=10k
R55 "RC0201FR-0710KL" RES-0201 66.169,125.408 r90 bottom value=10k
R56 "RC0201FR-0710KL" RES-0201 74.269,125.398 r90 bottom value=10k
R57 "RC0201FR-074K7L" RES-0201 72.072,116.306 r90 bottom value=4.7k
R58 "RC0201FR-074K7L" RES-0201 69.532,117.851 r90 bottom value=4.7k
R59 "RC0201FR-074K7L" RES-0201 66.992,115.311 r90 bottom value=4.7k
R60 "RC0201FR-074K7L" RES-0201 64.452,117.851 r90 bottom value=4.7k
R61 "RC0201FR-074K7L" RES-0201 64.452,115.311 r90 bottom value=4.7k
R62 "RC0201FR-074K7L" RES-0201 64.05,14.77 r180 top value=4.7k
R63 "RC0201FR-074K7L" RES-0201 64.05,13.97 r180 top value=4.7k
R64 "RC0201FR-074K7L" RES-0201 65.94,2.605 r90 top value=4.7k
R65 "RC0201FR-074K7L" RES-0201 64.504,11.129 r180 top value=4.7k
R66 "RC0201FR-074K7L" RES-0201 69.14,1.405 r270 top value=4.7k
R67 "RC0201FR-074K7L" RES-0201 68.46,1.405 r270 top value=4.7k
R68 "RC0201FR-074K7L" RES-0201 66.62,1.405 r270 top value=4.7k
R69 "AC0201FR-0749R9L" RES-0201 79.448,5.649 r270 top value=49.9
R70 "AC0201FR-0749R9L" RES-0201 78.448,5.649 r270 top value=49.9
R71 "AC0201FR-0749R9L" RES-0201 74.581,5.47 r180 top value=49.9
R72 "AC0201FR-0749R9L" RES-0201 74.581,6.47 r180 top value=49.9
R73 "AC0201FR-0749R9L" RES-0201 74.581,8.059 r180 top value=49.9
R74 "AC0201FR-0749R9L" RES-0201 74.581,9.059 r180 top value=49.9
R75 "AC0201FR-0749R9L" RES-0201 72.6,13.15 r270 top value=49.9
R76 "AC0201FR-0749R9L" RES-0201 71.6,13.15 r270 top value=49.9
R77 "RC0201FR-074K7L" RES-0201 65.2,14.77 r180 top value=4.7k
R78 "RC0201FR-074K7L" RES-0201 65.2,13.97 r180 top value=4.7k
R79 "RC0201FR-074K7L" RES-0201 65.93,1.405 r90 top value=4.7k
R80 "RC0201FR-074K7L" RES-0201 64.504,11.775 r0 top value=4.7k
R81 "RC0201FR-074K7L" RES-0201 69.14,2.605 r270 top value=4.7k
R82 "RC0201FR-074K7L" RES-0201 68.46,2.605 r270 top value=4.7k
R83 "RC0201FR-074K7L" RES-0201 66.62,2.605 r270 top value=4.7k
R84 "RC0201FR-074K7L" RES-0201 69.82,2.605 r270 top value=4.7k
R85 "AC0201FR-07220KL" RES-0201 73.956,17.568 r270 bottom value=220k
R86 "CRCW02010000Z0ED" RES-0201 85.303,93.047 r270 bottom value=0
R87 "CRCW02010000Z0ED" RES-0201 85.953,93.047 r270 bottom value=0
R88 "RC0402FR-072ML" RES-0402 90.418,84.467 r180 bottom value=2M
R89 "RC0402FR-072ML" RES-0402 90.418,85.567 r180 bottom value=2M
R90 "RC0201FR-074K7L" RES-0201 89.728,89.497 r0 bottom value=4.7k
R91 "RC0201FR-071KL" RES-0201 81.078,85.047 r0 bottom value=1k
R92 "RC0201FR-071KL" RES-0201 81.078,85.747 r180 bottom value=1k
R93 "RC0201FR-074K7L" RES-0201 86.7,80.041 r270 top value=4.7k
R94 "CRCW02010000Z0ED" RES-0201 81.3,80.041 r270 top value=0
R95 "CRCW02010000Z0ED" RES-0201 87.925,76.19 r90 top value=0
R96 "RC0201FR-074K7L" RES-0201 81.9,80.041 r270 top value=4.7k
R97 "CRCW02010000Z0ED" RES-0201 88.2,77.065 r180 top value=0
R98 "CRCW02010000Z0ED" RES-0201 88.2,77.665 r180 top value=0
R99 "CRCW02010000Z0ED" RES-0201 81.303,93.047 r270 bottom value=0
R100 "CRCW02010000Z0ED" RES-0201 83.353,93.047 r270 bottom value=0
R101 "CRCW02010000Z0ED" RES-0201 84.653,93.047 r270 bottom value=0
R102 "CRCW02010000Z0ED" RES-0201 87.253,93.047 r270 bottom value=0
R103 "CRCW02010000Z0ED" RES-0201 87.903,93.047 r270 bottom value=0
R104 "CRCW02010000Z0ED" RES-0201 86.603,93.047 r270 bottom value=0
R105 "AC0201FR-07330RL" RES-0201 96.476,67.609 r180 top value=330
R106 "AC0201FR-07330RL" RES-0201 96.476,65.909 r180 top value=330
R107 "RC0201FR-0724KL" RES-0201 8.968,77.041 r90 top value=24k
R108 "RC0402FR-0710RL" RES-0402 63.665,23.1 r270 bottom value=10
R109 "RC0402FR-072ML" RES-0402 86.584,7.06 r90 top value=2M
R110 "AC0201FR-07330RL" RES-0201 94.741,15.919 r90 bottom value=330
R111 "AC0201FR-07330RL" RES-0201 94.741,18.519 r90 bottom value=330
R112 "RC0201FR-0710KL" RES-0201 89.127,64.8 r90 top value=10k
R113 "CRCW02010000Z0ED" RES-0201 81.549,88.712 r0 bottom value=0
R114 "CRCW02010000Z0ED" RES-0201 81.549,89.312 r0 bottom value=0
R115 "RC0201FR-07100RL" RES-0201 28.069,110.474 r90 bottom value=100
R116 "RC0201FR-0710KL" RES-0201 28.069,111.674 r270 bottom value=10k
R117 "CRCW0402100KFKEDC" RES-0402 3,102.165 r0 top value=100k
R118 "CRCW0402100KFKEDC" RES-0402 1.5,105.865 r0 top value=100k
R119 "RC0201FR-0724KL" RES-0201 3.3,103.665 r0 top value=24k
R120 "RC0201FR-0722K1L" RES-0201 2.4,106.965 r270 top value=22.1k
R121 "RC0201FR-0710KL" RES-0201 1.7,104.765 r90 top value=10k
R122 "RC0201FR-0710KL" RES-0201 38.51,64.05 r0 top value=10k
R123 "RC0201FR-0724KL" RES-0201 3.3,115.365 r0 top value=24k
R124 "RC0201FR-071KL" RES-0201 1.825,113.34 r0 top value=1k
R125 "CRCW02010000Z0ED" RES-0201 24.982,113.024 r90 bottom value=0
R126 "CRCW02010000Z0ED" RES-0201 2.1,121.265 r0 top value=0
R127 "RC0201FR-0710KL" RES-0201 2.4,104.765 r90 top value=10k
R128 "RC0201FR-07100RL" RES-0201 1.825,113.94 r180 top value=100
R129 "CRCW0402100KFKEDC" RES-0402 1.5,91.666 r0 top value=100k
R130 "RC0201FR-07100KL" RES-0201 2.819,89.191 r270 top value=100k
R131 "RC0201FR-0713K7L" RES-0201 2.4,92.766 r270 top value=13.7k
R132 "RC0201FR-0724KL" RES-0201 3.3,114.665 r0 top value=24k
R133 "CRCW02010000Z0ED" RES-0201 2.275,103.291 r270 top value=0
R134 "RC0201FR-0724KL" RES-0201 35.175,86.131 r270 bottom value=24k
R135 "RC0201FR-0710KL" RES-0201 1.7,90.447 r90 top value=10k
R136 "ERJ-1GNF5101C" RES-0201 42.036,38.949 r270 top value=5.1k
R137 "CRCW02010000Z0ED" RES-0201 2.119,89.191 r90 top value=0
R138 "ERJ-1GNF5101C" RES-0201 46.255,33.332 r0 bottom value=5.1k
R139 "RC0201FR-0724KL" RES-0201 34.175,86.831 r0 bottom value=24k
R140 "CRCW02010000Z0ED" RES-0201 52.439,71.165 r90 top value=0
R141 "RC0201FR-0724KL" RES-0201 8.268,77.041 r270 top value=24k
R142 "RC0201FR-0724KL" RES-0201 7.568,77.041 r270 top value=24k
R143 "CRCW02010000Z0ED" RES-0201 47.686,29.849 r0 top value=0
R144 "RC0201FR-0724KL" RES-0201 73.131,18.809 r180 top value=24k
R145 "RC0201FR-0718KL" RES-0201 73.131,18.109 r0 top value=18k
R146 "CRCW0402100KFKEDC" RES-0402 9.118,79.791 r180 top value=100k
R147 "CRCW0402100KFKEDC" RES-0402 70.631,18.909 r270 top value=100k
R148 "RC0201FR-0724KL" RES-0201 34.175,86.131 r0 bottom value=24k
R149 "RC0201FR-071KL" RES-0201 34.175,85.431 r0 bottom value=1k
R150 "RC0201FR-0710KL" RES-0201 8.968,77.941 r180 top value=10k
R151 "CRCW02010000Z0ED" RES-0201 51.789,71.165 r90 top value=0
R152 "CRCW02010000Z0ED" RES-0201 51.139,71.165 r90 top value=0
R153 "CRCW02010000Z0ED" RES-0201 50.489,71.165 r90 top value=0
R154 "RC0201FR-0710KL" RES-0201 97.048,53.046 r270 bottom value=10k
R155 "RC0201FR-0710KL" RES-0201 87.025,125.9 r270 bottom value=10k
R156 "RC0201FR-07100KL" RES-0201 34.107,74.949 r0 top value=100k
R157 "RC0201FR-07100KL" RES-0201 34.107,76.349 r0 top value=100k
R158 "RC0201FR-0710KL" RES-0201 86.725,127.55 r270 bottom value=10k
R159 "RC0201FR-0710KL" RES-0201 84.275,127.95 r270 bottom value=10k
R160 "RC0201FR-0710KL" RES-0201 83.625,127.95 r270 bottom value=10k
R161 "CRCW02010000Z0ED" RES-0201 84.003,99.149 r270 bottom value=0
R162 "RC0201FR-071KL" RES-0201 54.931,137.926 r0 top value=1k
R163 "CRCW02010000Z0ED" RES-0201 37.062,74.227 r90 top value=0
R164 "RC0201FR-0710KL" RES-0201 82.975,127.95 r270 bottom value=10k
R165 "RC0201FR-071KL" RES-0201 65.537,138.641 r0 top value=1k
R166 "RC0201FR-071KL" RES-0201 16.75,13.2 r180 top value=1k
R167 "RC0201FR-071KL" RES-0201 74.475,55.19 r90 top value=1k
R168_1 "RC0201FR-0710KL" RES-0201 80.025,124.55 r270 bottom value=10k (schematic designator R168)
R168_2 "RC0201FR-0710KL" RES-0201 35.625,66.8 r180 top value=10k (schematic designator R168)
R168_3 "RC0201FR-0710KL" RES-0201 26.549,66.8 r180 top value=10k (schematic designator R168)
R168_4 "RC0201FR-0710KL" RES-0201 12.125,66.8 r180 top value=10k (schematic designator R168)
R168_5 "RC0201FR-0710KL" RES-0201 87.628,98.419 r0 bottom value=10k (schematic designator R168)
R169 "RC0201FR-0710KL" RES-0201 12.485,64.35 r0 top value=10k
R170 "RC0201FR-0710KL" RES-0201 10.91,64.625 r90 top value=10k
R171 "RC0201FR-0710KL" RES-0201 37.31,64.05 r180 top value=10k
R172 "RC0201FR-0710KL" RES-0201 85.953,99.149 r270 bottom value=10k
R173 "RC0201FR-0710KL" RES-0201 85.953,94.372 r270 bottom value=10k
R174 "CRCW02010000Z0ED" RES-0201 15.45,13.2 r0 top value=0
R175 "RC0201FR-0710KL" RES-0201 82.325,127.95 r270 bottom value=10k
R176 "RC0201FR-0710KL" RES-0201 81.675,127.95 r270 bottom value=10k
R177 "RC0201FR-0710KL" RES-0201 81.025,127.95 r270 bottom value=10k
R178 "CRCW02010000Z0ED" RES-0201 84.653,99.149 r270 bottom value=0
R179 "RC0201FR-0710KL" RES-0201 36.341,23.324 r270 top value=10k
R180 "RC0201FR-07100KL" RES-0201 34.107,75.649 r0 top value=100k
R181 "RC0201FR-07100KL" RES-0201 53.639,70.615 r90 top value=100k
R182 "RC0201FR-0710KL" RES-0201 98.225,29.475 r0 bottom value=10k
R183 "RC0201FR-0718KL" RES-0201 34.86,27.056 r270 top value=18k
R184 "RC0201FR-0710KL" RES-0201 58.538,16.929 r0 top value=10k
R185 "RC0201FR-071K43L" RES-0201 43.398,26.175 r180 top value=1.43k
R186 "CRCW02010000Z0ED" RES-0201 81.176,96.947 r0 bottom value=0
R187 "CRCW02010000Z0ED" RES-0201 85.303,99.149 r270 bottom value=0
R188 "CRCW02010000Z0ED" RES-0201 12.957,51.649 r0 top value=0
R189 "CRCW02010000Z0ED" RES-0201 80.391,29.849 r180 top value=0
R190 "RC0201FR-079K09L" RES-0201 71.226,38.749 r270 top value=9.09k
R191 "RC0201FR-0710KL" RES-0201 80.391,27.959 r0 top value=10k
R192 "CRCW02010000Z0ED" RES-0201 80.391,28.559 r0 top value=0
R193 "RC0201FR-074K7L" RES-0201 76.716,35.799 r270 bottom value=4.7k
R194 "RC0402FR-072ML" RES-0402 72.991,39.249 r180 top value=2M
R195 "RC0402FR-0710RL" RES-0402 62.665,23.1 r270 bottom value=10
R196 "RC0402FR-0710RL" RES-0402 64.665,23.1 r270 bottom value=10
R197 "RC0402FR-0710RL" RES-0402 61.265,23.1 r270 bottom value=10
R198 "RC0402FR-0710RL" RES-0402 37.039,7.523 r270 bottom value=10
R199 "RC0402FR-0710RL" RES-0402 36.039,7.523 r270 bottom value=10
R200 "RC0402FR-0710RL" RES-0402 32.039,7.523 r270 bottom value=10
R201 "RC0402FR-0710RL" RES-0402 38.039,7.523 r270 bottom value=10
R202 "RC0402FR-0710RL" RES-0402 35.039,7.523 r270 bottom value=10
R203 "RC0402FR-0710RL" RES-0402 34.039,7.523 r270 bottom value=10
R204 "RC0402FR-0710RL" RES-0402 33.039,7.523 r90 bottom value=10
R205_1 "RC0201FR-071KL" RES-0201 84.85,1.25 r90 top value=1k (schematic designator R205)
R205_2 "RC0201FR-071KL" RES-0201 80.35,1.25 r90 top value=1k (schematic designator R205)
R205_3 "RC0201FR-071KL" RES-0201 75.85,1.25 r90 top value=1k (schematic designator R205)
R205_4 "RC0201FR-071KL" RES-0201 71.35,1.25 r90 top value=1k (schematic designator R205)
R206_1 "RC0201FR-071KL" RES-0201 87.95,1.25 r90 top value=1k (schematic designator R206)
R206_2 "RC0201FR-071KL" RES-0201 83.45,1.25 r90 top value=1k (schematic designator R206)
R206_3 "RC0201FR-071KL" RES-0201 78.95,1.25 r90 top value=1k (schematic designator R206)
R206_4 "RC0201FR-071KL" RES-0201 74.45,1.25 r90 top value=1k (schematic designator R206)
R207_1 "AC0201FR-07330RL" RES-0201 85.55,1.25 r270 top value=330 (schematic designator R207)
R207_2 "AC0201FR-07330RL" RES-0201 81.05,1.25 r270 top value=330 (schematic designator R207)
R207_3 "AC0201FR-07330RL" RES-0201 76.55,1.25 r270 top value=330 (schematic designator R207)
R207_4 "AC0201FR-07330RL" RES-0201 72.05,1.25 r270 top value=330 (schematic designator R207)
R208_1 "AC0201FR-07330RL" RES-0201 88.65,1.25 r270 top value=330 (schematic designator R208)
R208_2 "AC0201FR-07330RL" RES-0201 84.15,1.25 r270 top value=330 (schematic designator R208)
R208_3 "AC0201FR-07330RL" RES-0201 79.65,1.25 r270 top value=330 (schematic designator R208)
R208_4 "AC0201FR-07330RL" RES-0201 75.15,1.25 r270 top value=330 (schematic designator R208)
R209 "AC0201FR-07330RL" RES-0201 37.486,38.949 r90 top value=330
R210 "ERJ-1GNF5101C" RES-0201 46.436,40.099 r90 top value=5.1k
R211 "ERJ-1GNF5101C" RES-0201 48.836,32.649 r0 top value=5.1k
R212 "RC0805FR-07100RL" RES-0805 15.5,135 r0 top value=100
R213 "RC0805FR-07100RL" RES-0805 2.515,139.2 r180 top value=100
R214 "CRCW060310R0FKEAC" RES-0603 7.283,132.793 r0 top value=10
R215 "RC0201FR-074K7L" RES-0201 1.5,130.24 r90 top value=4.7k
R216 "CRCW02010000Z0ED" RES-0201 4.965,84.702 r270 top value=0
R217 "RC0201FR-0710KL" RES-0201 2.1,94.366 r180 top value=10k
R218 "CRCW02010000Z0ED" RES-0201 54.163,13.529 r0 top value=0
R219 "CRCW02010000Z0ED" RES-0201 27.244,37.81 r90 bottom value=0
R220 "RC0201FR-07100KL" RES-0201 34.107,77.049 r0 top value=100k
R221 "CRCW02010000Z0ED" RES-0201 2.1,95.766 r0 top value=0
R222 "AC0201FR-07220KL" RES-0201 39.882,76.874 r90 top value=220k
R223 "AC0201FR-07220KL" RES-0201 39.882,75.724 r90 top value=220k
R224 "CRCW02010000Z0ED" RES-0201 33.078,30.391 r270 top value=0
R225 "CRCW02010000Z0ED" RES-0201 33.523,34.35 r90 top value=0
R226 "CRCW02010000Z0ED" RES-0201 33.523,35.45 r270 top value=0
R227 "CRCW02010000Z0ED" RES-0201 73.275,55.19 r270 top value=0
R228 "CRCW02010000Z0ED" RES-0201 73.875,55.19 r270 top value=0
R229 "PMR10EZPFV2L00" RES-0805 10.974,131.699 r270 top value=2m
R230 "CRCW0402100KFKEDC" RES-0402 78.657,93.615 r270 bottom value=100k
R231 "CRCW060310R0FKEAC" RES-0603 9.633,141.793 r180 top value=10
R232 "CRCW02010000Z0ED" RES-0201 18.439,130.399 r90 top value=0
R233 "RC0201FR-074K7L" RES-0201 18.439,131.699 r270 top value=4.7k
R234 "RC0201FR-0724KL" RES-0201 89.503,93.142 r90 bottom value=24k
R235 "CRCW02010000Z0ED" RES-0201 82.703,99.149 r270 bottom value=0
R236 "RC0201FR-0724KL" RES-0201 89.503,91.947 r90 bottom value=24k
R237 "CRCW02010000Z0ED" RES-0201 83.353,99.149 r270 bottom value=0
R238 "RC0201FR-0710KL" RES-0201 1,104.765 r270 top value=10k
R239 "RC0201FR-0710KL" RES-0201 2.3,115.065 r90 top value=10k
R240 "RC0201FR-0710KL" RES-0201 1.6,115.065 r90 top value=10k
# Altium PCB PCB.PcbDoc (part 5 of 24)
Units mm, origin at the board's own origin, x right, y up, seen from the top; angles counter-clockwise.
Board outline 100 x 160 mm, 10 copper layers (TOP_L1, L2, L3, L4, L5, L6, L7, L8, L9, BOTTOM_L10), stack 1.946 mm thick; 1358 components, 1149 nets, 6777 pads, 10914 vias.

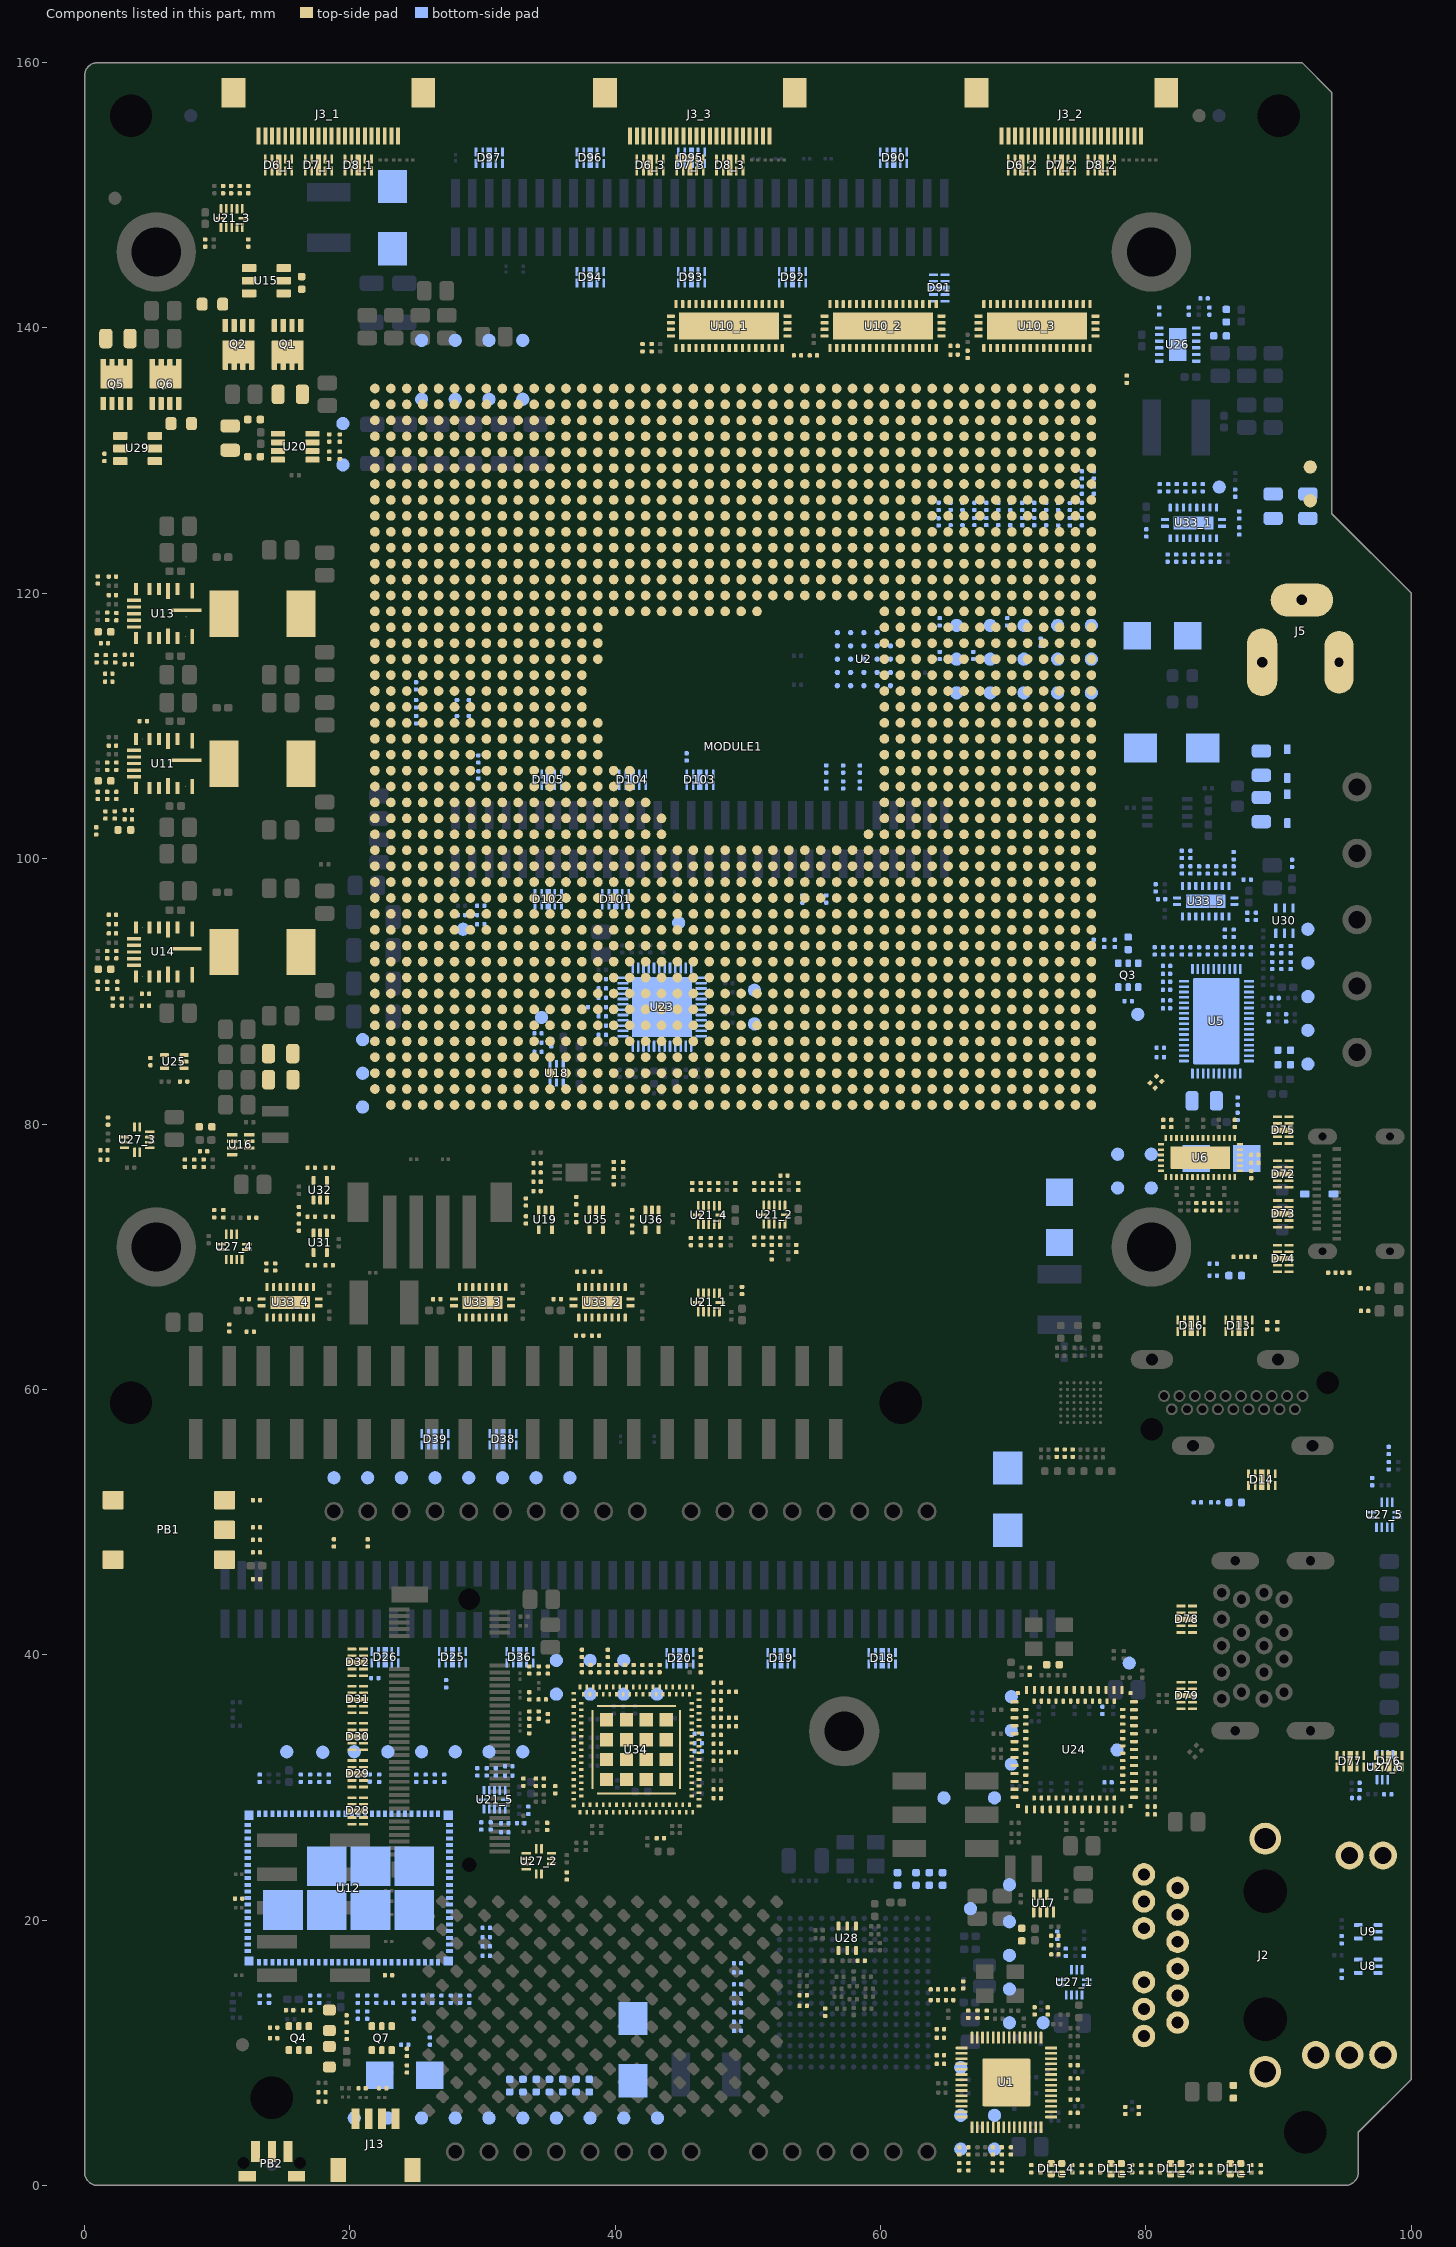
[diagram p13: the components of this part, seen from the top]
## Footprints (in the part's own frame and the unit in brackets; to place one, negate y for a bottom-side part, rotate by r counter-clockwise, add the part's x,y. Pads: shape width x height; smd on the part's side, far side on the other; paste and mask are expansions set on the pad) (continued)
MODULE [mm] "BGA, 57,50x57,50mmx0,50mm, Pitch 1,20mm"
  round 0.73 smd paste-0.1 mask-0.1: A2(27,25.8) A3(27,24.6) A4(27,23.4) A5(27,22.2) A6(27,21) A7(27,19.8) A8(27,18.6) A9(27,17.4) A10(27,16.2) A11(27,15) A12(27,13.8) A13(27,12.6) A14(27,11.4) A15(27,10.2) A16(27,9) A17(27,7.8) A18(27,6.6) A19(27,5.4) A20(27,4.2) A21(27,3) A22(27,1.8) A23(27,0.6) A24(27,-0.6) A25(27,-1.8) A26(27,-3) A27(27,-4.2) A28(27,-5.4) A29(27,-6.6) A30(27,-7.8) A31(27,-9) A32(27,-10.2) A33(27,-11.4) A34(27,-12.6) A35(27,-13.8) A36(27,-15) A37(27,-16.2) A38(27,-17.4) A39(27,-18.6) A40(27,-19.8) A41(27,-21) A42(27,-22.2) A43(27,-23.4) A44(27,-24.6) A45(27,-25.8) A46(27,-27) AA1(3,27) AA2(3,25.8) AA3(3,24.6) AA4(3,23.4) AA5(3,22.2) AA6(3,21) AA7(3,19.8) AA8(3,18.6) AA9(3,17.4) AA10(3,16.2) AA11(3,15) AA12(3,13.8) AA13(3,12.6) AA14(3,11.4) AA15(3,10.2) AA16(3,9) AA17(3,7.8) AA32(3,-10.2) AA33(3,-11.4) AA34(3,-12.6) AA35(3,-13.8) AA36(3,-15) AA37(3,-16.2) AA38(3,-17.4) AA39(3,-18.6) AA40(3,-19.8) AA41(3,-21) AA42(3,-22.2) AA43(3,-23.4) AA44(3,-24.6) AA45(3,-25.8) AA46(3,-27) AB1(1.8,27) AB2(1.8,25.8) AB3(1.8,24.6) AB4(1.8,23.4) AB5(1.8,22.2) AB6(1.8,21) AB7(1.8,19.8) AB8(1.8,18.6) AB9(1.8,17.4) AB10(1.8,16.2) AB11(1.8,15) AB12(1.8,13.8) AB13(1.8,12.6) AB14(1.8,11.4) AB15(1.8,10.2) AB16(1.8,9) AB17(1.8,7.8) AB32(1.8,-10.2) AB33(1.8,-11.4) AB34(1.8,-12.6) AB35(1.8,-13.8) AB36(1.8,-15) AB37(1.8,-16.2) AB38(1.8,-17.4) AB39(1.8,-18.6) AB40(1.8,-19.8) AB41(1.8,-21) AB42(1.8,-22.2) AB43(1.8,-23.4) AB44(1.8,-24.6) AB45(1.8,-25.8) AB46(1.8,-27) AC1(0.6,27) AC2(0.6,25.8) AC3(0.6,24.6) AC4(0.6,23.4) AC5(0.6,22.2) AC6(0.6,21) AC7(0.6,19.8) AC8(0.6,18.6) AC9(0.6,17.4) AC10(0.6,16.2) AC11(0.6,15) AC12(0.6,13.8) AC13(0.6,12.6) AC14(0.6,11.4) AC15(0.6,10.2) AC16(0.6,9) AC17(0.6,7.8) AC32(0.6,-10.2) AC33(0.6,-11.4) AC34(0.6,-12.6) AC35(0.6,-13.8) AC36(0.6,-15) AC37(0.6,-16.2) AC38(0.6,-17.4) AC39(0.6,-18.6) AC40(0.6,-19.8) AC41(0.6,-21) AC42(0.6,-22.2) AC43(0.6,-23.4) AC44(0.6,-24.6) AC45(0.6,-25.8) AC46(0.6,-27) AD1(-0.6,27) AD2(-0.6,25.8) AD3(-0.6,24.6) AD4(-0.6,23.4) AD5(-0.6,22.2) AD6(-0.6,21) AD7(-0.6,19.8) AD8(-0.6,18.6) AD9(-0.6,17.4) AD10(-0.6,16.2) AD11(-0.6,15) AD12(-0.6,13.8) AD13(-0.6,12.6) AD14(-0.6,11.4) AD15(-0.6,10.2) AD16(-0.6,9) AD17(-0.6,7.8) AD32(-0.6,-10.2) AD33(-0.6,-11.4) AD34(-0.6,-12.6) AD35(-0.6,-13.8) AD36(-0.6,-15) AD37(-0.6,-16.2) AD38(-0.6,-17.4) AD39(-0.6,-18.6) AD40(-0.6,-19.8) AD41(-0.6,-21) AD42(-0.6,-22.2) AD43(-0.6,-23.4) AD44(-0.6,-24.6) AD45(-0.6,-25.8) AD46(-0.6,-27) AE1(-1.8,27) AE2(-1.8,25.8) AE3(-1.8,24.6) AE4(-1.8,23.4) AE5(-1.8,22.2) AE6(-1.8,21) AE7(-1.8,19.8) AE8(-1.8,18.6) AE9(-1.8,17.4) AE10(-1.8,16.2) AE11(-1.8,15) AE12(-1.8,13.8) AE13(-1.8,12.6) AE14(-1.8,11.4) AE15(-1.8,10.2) AE16(-1.8,9) AE17(-1.8,7.8) AE32(-1.8,-10.2) AE33(-1.8,-11.4) AE34(-1.8,-12.6) AE35(-1.8,-13.8) AE36(-1.8,-15) AE37(-1.8,-16.2) AE38(-1.8,-17.4) AE39(-1.8,-18.6) AE40(-1.8,-19.8) AE41(-1.8,-21) AE42(-1.8,-22.2) AE43(-1.8,-23.4) AE44(-1.8,-24.6) AE45(-1.8,-25.8) AE46(-1.8,-27) AF1(-3,27) AF2(-3,25.8) AF3(-3,24.6) AF4(-3,23.4) AF5(-3,22.2) AF6(-3,21) AF7(-3,19.8) AF8(-3,18.6) AF9(-3,17.4) AF10(-3,16.2) AF11(-3,15) AF12(-3,13.8) AF13(-3,12.6) AF14(-3,11.4) AF15(-3,10.2) AF16(-3,9) AF17(-3,7.8) AF33(-3,-11.4) AF34(-3,-12.6) AF35(-3,-13.8) AF36(-3,-15) AF37(-3,-16.2) AF38(-3,-17.4) AF39(-3,-18.6) AF40(-3,-19.8) AF41(-3,-21) AF42(-3,-22.2) AF43(-3,-23.4) AF44(-3,-24.6) AF45(-3,-25.8) AF46(-3,-27) AG1(-4.2,27) AG2(-4.2,25.8) AG3(-4.2,24.6) AG4(-4.2,23.4) AG5(-4.2,22.2) AG6(-4.2,21) AG7(-4.2,19.8) AG8(-4.2,18.6) AG9(-4.2,17.4) AG10(-4.2,16.2) AG11(-4.2,15) AG12(-4.2,13.8) AG13(-4.2,12.6) AG14(-4.2,11.4) AG15(-4.2,10.2) AG16(-4.2,9) AG17(-4.2,7.8) AG33(-4.2,-11.4) AG34(-4.2,-12.6) AG35(-4.2,-13.8) AG36(-4.2,-15) AG37(-4.2,-16.2) AG38(-4.2,-17.4) AG39(-4.2,-18.6) AG40(-4.2,-19.8) AG41(-4.2,-21) AG42(-4.2,-22.2) AG43(-4.2,-23.4) AG44(-4.2,-24.6) AG45(-4.2,-25.8) AG46(-4.2,-27) AH1(-5.4,27) AH2(-5.4,25.8) AH3(-5.4,24.6) AH4(-5.4,23.4) AH5(-5.4,22.2) AH6(-5.4,21) AH7(-5.4,19.8) AH8(-5.4,18.6) AH9(-5.4,17.4) AH10(-5.4,16.2) AH11(-5.4,15) AH12(-5.4,13.8) AH13(-5.4,12.6) AH14(-5.4,11.4) AH15(-5.4,10.2) AH16(-5.4,9) AH17(-5.4,7.8) AH33(-5.4,-11.4) AH34(-5.4,-12.6) AH35(-5.4,-13.8) AH36(-5.4,-15) AH37(-5.4,-16.2) AH38(-5.4,-17.4) AH39(-5.4,-18.6) AH40(-5.4,-19.8) AH41(-5.4,-21) AH42(-5.4,-22.2) AH43(-5.4,-23.4) AH44(-5.4,-24.6) AH45(-5.4,-25.8) AH46(-5.4,-27) AJ1(-6.6,27) AJ2(-6.6,25.8) AJ3(-6.6,24.6) AJ4(-6.6,23.4) AJ5(-6.6,22.2) AJ6(-6.6,21) AJ7(-6.6,19.8) AJ8(-6.6,18.6) AJ9(-6.6,17.4) AJ10(-6.6,16.2) AJ11(-6.6,15) AJ12(-6.6,13.8) AJ13(-6.6,12.6) AJ14(-6.6,11.4) AJ15(-6.6,10.2) AJ16(-6.6,9) AJ17(-6.6,7.8) AJ33(-6.6,-11.4) AJ34(-6.6,-12.6) AJ35(-6.6,-13.8) AJ36(-6.6,-15) AJ37(-6.6,-16.2) AJ38(-6.6,-17.4) AJ39(-6.6,-18.6) AJ40(-6.6,-19.8) AJ41(-6.6,-21) AJ42(-6.6,-22.2) AJ43(-6.6,-23.4) AJ44(-6.6,-24.6) AJ45(-6.6,-25.8) AJ46(-6.6,-27) AK1(-7.8,27) AK2(-7.8,25.8) AK3(-7.8,24.6) AK4(-7.8,23.4) AK5(-7.8,22.2) AK6(-7.8,21) AK7(-7.8,19.8) AK8(-7.8,18.6) AK9(-7.8,17.4) AK10(-7.8,16.2) AK11(-7.8,15) AK12(-7.8,13.8) AK13(-7.8,12.6) AK14(-7.8,11.4) AK15(-7.8,10.2) AK16(-7.8,9) AK17(-7.8,7.8) AK33(-7.8,-11.4) AK34(-7.8,-12.6) AK35(-7.8,-13.8) AK36(-7.8,-15) AK37(-7.8,-16.2) AK38(-7.8,-17.4) AK39(-7.8,-18.6) AK40(-7.8,-19.8) AK41(-7.8,-21) AK42(-7.8,-22.2) AK43(-7.8,-23.4) AK44(-7.8,-24.6) AK45(-7.8,-25.8) AK46(-7.8,-27) AL1(-9,27) AL2(-9,25.8) AL3(-9,24.6) AL4(-9,23.4) AL5(-9,22.2) AL6(-9,21) AL7(-9,19.8) AL8(-9,18.6) AL9(-9,17.4) AL10(-9,16.2) AL11(-9,15) AL12(-9,13.8) AL13(-9,12.6) AL14(-9,11.4) AL15(-9,10.2) AL16(-9,9) AL17(-9,7.8) AL33(-9,-11.4) AL34(-9,-12.6) AL35(-9,-13.8) AL36(-9,-15) AL37(-9,-16.2) AL38(-9,-17.4) AL39(-9,-18.6) AL40(-9,-19.8) AL41(-9,-21) AL42(-9,-22.2) AL43(-9,-23.4) AL44(-9,-24.6) AL45(-9,-25.8) AL46(-9,-27) AM1(-10.2,27) AM2(-10.2,25.8) AM3(-10.2,24.6) AM4(-10.2,23.4) AM5(-10.2,22.2) AM6(-10.2,21) AM7(-10.2,19.8) AM8(-10.2,18.6) AM9(-10.2,17.4) AM10(-10.2,16.2) AM11(-10.2,15) AM12(-10.2,13.8) AM13(-10.2,12.6) AM14(-10.2,11.4) AM15(-10.2,10.2) AM16(-10.2,9) AM17(-10.2,7.8) AM18(-10.2,6.6) AM33(-10.2,-11.4) AM34(-10.2,-12.6) AM35(-10.2,-13.8) AM36(-10.2,-15) AM37(-10.2,-16.2) AM38(-10.2,-17.4) AM39(-10.2,-18.6) AM40(-10.2,-19.8) AM41(-10.2,-21) AM42(-10.2,-22.2) AM43(-10.2,-23.4) AM44(-10.2,-24.6) AM45(-10.2,-25.8) AM46(-10.2,-27) AN1(-11.4,27) AN2(-11.4,25.8) AN3(-11.4,24.6) AN4(-11.4,23.4) AN5(-11.4,22.2) AN6(-11.4,21) AN7(-11.4,19.8) AN8(-11.4,18.6) AN9(-11.4,17.4) AN10(-11.4,16.2) AN11(-11.4,15) AN12(-11.4,13.8) AN13(-11.4,12.6) AN14(-11.4,11.4) AN15(-11.4,10.2) AN16(-11.4,9) AN17(-11.4,7.8) AN18(-11.4,6.6) AN19(-11.4,5.4) AN20(-11.4,4.2) AN21(-11.4,3) AN22(-11.4,1.8) AN23(-11.4,0.6) AN24(-11.4,-0.6) AN25(-11.4,-1.8) AN26(-11.4,-3) AN27(-11.4,-4.2) AN28(-11.4,-5.4) AN29(-11.4,-6.6) AN30(-11.4,-7.8) AN31(-11.4,-9) AN32(-11.4,-10.2) AN33(-11.4,-11.4) AN34(-11.4,-12.6) AN35(-11.4,-13.8) AN36(-11.4,-15) AN37(-11.4,-16.2) AN38(-11.4,-17.4) AN39(-11.4,-18.6) AN40(-11.4,-19.8) AN41(-11.4,-21) AN42(-11.4,-22.2) AN43(-11.4,-23.4) AN44(-11.4,-24.6) AN45(-11.4,-25.8) AN46(-11.4,-27) AP1(-12.6,27) AP2(-12.6,25.8) AP3(-12.6,24.6) AP4(-12.6,23.4) AP5(-12.6,22.2) AP6(-12.6,21) AP7(-12.6,19.8) AP8(-12.6,18.6) AP9(-12.6,17.4) AP10(-12.6,16.2) AP11(-12.6,15) AP12(-12.6,13.8) AP13(-12.6,12.6) AP14(-12.6,11.4) AP15(-12.6,10.2) AP16(-12.6,9) AP17(-12.6,7.8) AP18(-12.6,6.6) AP19(-12.6,5.4) AP20(-12.6,4.2) AP21(-12.6,3) AP22(-12.6,1.8) AP23(-12.6,0.6) AP24(-12.6,-0.6) AP25(-12.6,-1.8) AP26(-12.6,-3) AP27(-12.6,-4.2) AP28(-12.6,-5.4) AP29(-12.6,-6.6) AP30(-12.6,-7.8) AP31(-12.6,-9) AP32(-12.6,-10.2) AP33(-12.6,-11.4) AP34(-12.6,-12.6) AP35(-12.6,-13.8) AP36(-12.6,-15) AP37(-12.6,-16.2) AP38(-12.6,-17.4) AP39(-12.6,-18.6) AP40(-12.6,-19.8) AP41(-12.6,-21) AP42(-12.6,-22.2) AP43(-12.6,-23.4) AP44(-12.6,-24.6) AP45(-12.6,-25.8) AP46(-12.6,-27) AR1(-13.8,27) AR2(-13.8,25.8) AR3(-13.8,24.6) AR4(-13.8,23.4) AR5(-13.8,22.2) AR6(-13.8,21) AR7(-13.8,19.8) AR8(-13.8,18.6) AR9(-13.8,17.4) AR10(-13.8,16.2) AR11(-13.8,15) AR12(-13.8,13.8) AR13(-13.8,12.6) AR14(-13.8,11.4) AR15(-13.8,10.2) AR16(-13.8,9) AR17(-13.8,7.8) AR18(-13.8,6.6) AR19(-13.8,5.4) AR20(-13.8,4.2) AR21(-13.8,3) AR22(-13.8,1.8) AR23(-13.8,0.6) AR24(-13.8,-0.6) AR25(-13.8,-1.8) AR26(-13.8,-3) AR27(-13.8,-4.2) AR28(-13.8,-5.4) AR29(-13.8,-6.6) AR30(-13.8,-7.8) AR31(-13.8,-9) AR32(-13.8,-10.2) AR33(-13.8,-11.4) AR34(-13.8,-12.6) AR35(-13.8,-13.8) AR36(-13.8,-15) AR37(-13.8,-16.2) AR38(-13.8,-17.4) AR39(-13.8,-18.6) AR40(-13.8,-19.8) AR41(-13.8,-21) AR42(-13.8,-22.2) AR43(-13.8,-23.4) AR44(-13.8,-24.6) AR45(-13.8,-25.8) AR46(-13.8,-27) AT1(-15,27) AT2(-15,25.8) AT3(-15,24.6) AT4(-15,23.4) AT5(-15,22.2) AT6(-15,21) AT7(-15,19.8) AT8(-15,18.6) AT9(-15,17.4) AT10(-15,16.2) AT11(-15,15) AT12(-15,13.8) AT13(-15,12.6) AT14(-15,11.4) AT15(-15,10.2) AT16(-15,9) AT17(-15,7.8) AT18(-15,6.6) AT19(-15,5.4) AT20(-15,4.2) AT21(-15,3) AT22(-15,1.8) AT23(-15,0.6) AT24(-15,-0.6) AT25(-15,-1.8) AT26(-15,-3) AT27(-15,-4.2) AT28(-15,-5.4) AT29(-15,-6.6) AT30(-15,-7.8) AT31(-15,-9) AT32(-15,-10.2) AT33(-15,-11.4) AT34(-15,-12.6) AT35(-15,-13.8) AT36(-15,-15) AT37(-15,-16.2) AT38(-15,-17.4) AT39(-15,-18.6) AT40(-15,-19.8) AT41(-15,-21) AT42(-15,-22.2) AT43(-15,-23.4) AT44(-15,-24.6) AT45(-15,-25.8) AT46(-15,-27) AU1(-16.2,27) AU2(-16.2,25.8) AU3(-16.2,24.6) AU4(-16.2,23.4) AU5(-16.2,22.2) AU6(-16.2,21) AU7(-16.2,19.8) AU8(-16.2,18.6) AU9(-16.2,17.4) AU10(-16.2,16.2) AU11(-16.2,15) AU12(-16.2,13.8) AU13(-16.2,12.6) AU14(-16.2,11.4) AU15(-16.2,10.2) AU16(-16.2,9) AU17(-16.2,7.8) AU18(-16.2,6.6) AU19(-16.2,5.4) AU20(-16.2,4.2) AU21(-16.2,3) AU22(-16.2,1.8) AU23(-16.2,0.6) AU24(-16.2,-0.6) AU25(-16.2,-1.8) AU26(-16.2,-3) AU27(-16.2,-4.2) AU28(-16.2,-5.4) AU29(-16.2,-6.6) AU30(-16.2,-7.8) AU31(-16.2,-9) AU32(-16.2,-10.2) AU33(-16.2,-11.4) AU34(-16.2,-12.6) AU35(-16.2,-13.8) AU36(-16.2,-15) AU37(-16.2,-16.2) AU38(-16.2,-17.4) AU39(-16.2,-18.6) AU40(-16.2,-19.8) AU41(-16.2,-21) AU42(-16.2,-22.2) AU43(-16.2,-23.4) AU44(-16.2,-24.6) AU45(-16.2,-25.8) AU46(-16.2,-27) AV1(-17.4,27) AV2(-17.4,25.8) AV3(-17.4,24.6) AV4(-17.4,23.4) AV5(-17.4,22.2) AV6(-17.4,21) AV7(-17.4,19.8) AV8(-17.4,18.6) AV9(-17.4,17.4) AV10(-17.4,16.2) AV11(-17.4,15) AV12(-17.4,13.8) AV13(-17.4,12.6) AV14(-17.4,11.4) AV15(-17.4,10.2) AV16(-17.4,9) AV17(-17.4,7.8) AV18(-17.4,6.6) AV19(-17.4,5.4) AV20(-17.4,4.2) AV21(-17.4,3) AV22(-17.4,1.8) AV23(-17.4,0.6) AV24(-17.4,-0.6) AV25(-17.4,-1.8) AV26(-17.4,-3) AV27(-17.4,-4.2) AV28(-17.4,-5.4) AV29(-17.4,-6.6) AV30(-17.4,-7.8) AV31(-17.4,-9) AV32(-17.4,-10.2) AV33(-17.4,-11.4) AV34(-17.4,-12.6) AV35(-17.4,-13.8) AV36(-17.4,-15) AV37(-17.4,-16.2) AV38(-17.4,-17.4) AV39(-17.4,-18.6) AV40(-17.4,-19.8) AV41(-17.4,-21) AV42(-17.4,-22.2) AV43(-17.4,-23.4) AV44(-17.4,-24.6) AV45(-17.4,-25.8) AV46(-17.4,-27) AW1(-18.6,27) AW2(-18.6,25.8) AW3(-18.6,24.6) AW4(-18.6,23.4) AW5(-18.6,22.2) AW6(-18.6,21) AW7(-18.6,19.8) AW8(-18.6,18.6) AW9(-18.6,17.4) AW10(-18.6,16.2) AW11(-18.6,15) AW12(-18.6,13.8) AW13(-18.6,12.6) AW14(-18.6,11.4) AW15(-18.6,10.2) AW16(-18.6,9) AW17(-18.6,7.8) AW18(-18.6,6.6) AW19(-18.6,5.4) AW20(-18.6,4.2) AW21(-18.6,3) AW22(-18.6,1.8) AW23(-18.6,0.6) AW24(-18.6,-0.6) AW25(-18.6,-1.8) AW26(-18.6,-3) AW27(-18.6,-4.2) AW28(-18.6,-5.4) AW29(-18.6,-6.6) AW30(-18.6,-7.8) AW31(-18.6,-9) AW32(-18.6,-10.2) AW33(-18.6,-11.4) AW34(-18.6,-12.6) AW35(-18.6,-13.8) AW36(-18.6,-15) AW37(-18.6,-16.2) AW38(-18.6,-17.4) AW39(-18.6,-18.6) AW40(-18.6,-19.8) AW41(-18.6,-21) AW42(-18.6,-22.2) AW43(-18.6,-23.4) AW44(-18.6,-24.6) AW45(-18.6,-25.8) AW46(-18.6,-27) AY1(-19.8,27) AY2(-19.8,25.8) AY3(-19.8,24.6) AY4(-19.8,23.4) AY5(-19.8,22.2) AY6(-19.8,21) AY7(-19.8,19.8) AY8(-19.8,18.6) AY9(-19.8,17.4) AY10(-19.8,16.2) AY11(-19.8,15) AY12(-19.8,13.8) AY13(-19.8,12.6) AY14(-19.8,11.4) AY15(-19.8,10.2) AY16(-19.8,9) AY17(-19.8,7.8) AY18(-19.8,6.6) AY19(-19.8,5.4) AY20(-19.8,4.2) AY21(-19.8,3) AY22(-19.8,1.8) AY23(-19.8,0.6) AY24(-19.8,-0.6) AY25(-19.8,-1.8) AY26(-19.8,-3) AY27(-19.8,-4.2) AY28(-19.8,-5.4) AY29(-19.8,-6.6) AY30(-19.8,-7.8) AY31(-19.8,-9) AY32(-19.8,-10.2) AY33(-19.8,-11.4) AY34(-19.8,-12.6) AY35(-19.8,-13.8) AY36(-19.8,-15) AY37(-19.8,-16.2) AY38(-19.8,-17.4) AY39(-19.8,-18.6) AY40(-19.8,-19.8) AY41(-19.8,-21) AY42(-19.8,-22.2) AY43(-19.8,-23.4) AY44(-19.8,-24.6) AY45(-19.8,-25.8) AY46(-19.8,-27) B1(25.8,27) B2(25.8,25.8) B3(25.8,24.6) B4(25.8,23.4) B5(25.8,22.2) B6(25.8,21) B7(25.8,19.8) B8(25.8,18.6) B9(25.8,17.4) B10(25.8,16.2) B11(25.8,15) B12(25.8,13.8) B13(25.8,12.6) B14(25.8,11.4) B15(25.8,10.2) B16(25.8,9) B17(25.8,7.8) B18(25.8,6.6) B19(25.8,5.4) B20(25.8,4.2) B21(25.8,3) B22(25.8,1.8) B23(25.8,0.6) B24(25.8,-0.6) B25(25.8,-1.8) B26(25.8,-3) B27(25.8,-4.2) B28(25.8,-5.4) B29(25.8,-6.6) B30(25.8,-7.8) B31(25.8,-9) B32(25.8,-10.2) B33(25.8,-11.4) B34(25.8,-12.6) B35(25.8,-13.8) B36(25.8,-15) B37(25.8,-16.2) B38(25.8,-17.4) B39(25.8,-18.6) B40(25.8,-19.8) B41(25.8,-21) B42(25.8,-22.2) B43(25.8,-23.4) B44(25.8,-24.6) B45(25.8,-25.8) B46(25.8,-27) BA1(-21,27) BA2(-21,25.8) BA3(-21,24.6) BA4(-21,23.4) BA5(-21,22.2) BA6(-21,21) BA7(-21,19.8) BA8(-21,18.6) BA9(-21,17.4) BA10(-21,16.2) BA11(-21,15) BA12(-21,13.8) BA13(-21,12.6) BA14(-21,11.4) BA15(-21,10.2) BA16(-21,9) BA17(-21,7.8) BA18(-21,6.6) BA19(-21,5.4) BA20(-21,4.2) BA21(-21,3) BA22(-21,1.8) BA23(-21,0.6) BA24(-21,-0.6) BA25(-21,-1.8) BA26(-21,-3) BA27(-21,-4.2) BA28(-21,-5.4) BA29(-21,-6.6) BA30(-21,-7.8) BA31(-21,-9) BA32(-21,-10.2) BA33(-21,-11.4) BA34(-21,-12.6) BA35(-21,-13.8) BA36(-21,-15) BA37(-21,-16.2) BA38(-21,-17.4) BA39(-21,-18.6) BA40(-21,-19.8) BA41(-21,-21) BA42(-21,-22.2) BA43(-21,-23.4) BA44(-21,-24.6) BA45(-21,-25.8) BA46(-21,-27) BB1(-22.2,27) BB2(-22.2,25.8) BB3(-22.2,24.6) BB4(-22.2,23.4) BB5(-22.2,22.2) BB6(-22.2,21) BB7(-22.2,19.8) BB8(-22.2,18.6) BB9(-22.2,17.4) BB10(-22.2,16.2) BB11(-22.2,15) BB12(-22.2,13.8) BB13(-22.2,12.6) BB14(-22.2,11.4) BB15(-22.2,10.2) BB16(-22.2,9) BB17(-22.2,7.8) BB18(-22.2,6.6) BB19(-22.2,5.4) BB20(-22.2,4.2) BB21(-22.2,3) BB22(-22.2,1.8) BB23(-22.2,0.6) BB24(-22.2,-0.6) BB25(-22.2,-1.8) BB26(-22.2,-3) BB27(-22.2,-4.2) BB28(-22.2,-5.4) BB29(-22.2,-6.6) BB30(-22.2,-7.8) BB31(-22.2,-9) BB32(-22.2,-10.2) BB33(-22.2,-11.4) BB34(-22.2,-12.6) BB35(-22.2,-13.8) BB36(-22.2,-15) BB37(-22.2,-16.2) BB38(-22.2,-17.4) BB39(-22.2,-18.6) BB40(-22.2,-19.8) BB41(-22.2,-21) BB42(-22.2,-22.2) BB43(-22.2,-23.4) BB44(-22.2,-24.6) BB45(-22.2,-25.8) BB46(-22.2,-27) BC1(-23.4,27) BC2(-23.4,25.8) BC3(-23.4,24.6) BC4(-23.4,23.4) BC5(-23.4,22.2) BC6(-23.4,21) BC7(-23.4,19.8) BC8(-23.4,18.6) BC9(-23.4,17.4) BC10(-23.4,16.2) BC11(-23.4,15) BC12(-23.4,13.8) BC13(-23.4,12.6) BC14(-23.4,11.4) BC15(-23.4,10.2) BC16(-23.4,9) BC17(-23.4,7.8) BC18(-23.4,6.6) BC19(-23.4,5.4) BC20(-23.4,4.2) BC21(-23.4,3) BC22(-23.4,1.8) BC23(-23.4,0.6) BC24(-23.4,-0.6) BC25(-23.4,-1.8) BC26(-23.4,-3) BC27(-23.4,-4.2) BC28(-23.4,-5.4) BC29(-23.4,-6.6) BC30(-23.4,-7.8) BC31(-23.4,-9) BC32(-23.4,-10.2) BC33(-23.4,-11.4) BC34(-23.4,-12.6) BC35(-23.4,-13.8) BC36(-23.4,-15) BC37(-23.4,-16.2) BC38(-23.4,-17.4) BC39(-23.4,-18.6) BC40(-23.4,-19.8) BC41(-23.4,-21) BC42(-23.4,-22.2) BC43(-23.4,-23.4) BC44(-23.4,-24.6) BC45(-23.4,-25.8) BC46(-23.4,-27) BD1(-24.6,27) BD2(-24.6,25.8) BD3(-24.6,24.6) BD4(-24.6,23.4) BD5(-24.6,22.2) BD6(-24.6,21) BD7(-24.6,19.8) BD8(-24.6,18.6) BD9(-24.6,17.4) BD10(-24.6,16.2) BD11(-24.6,15) BD12(-24.6,13.8) BD13(-24.6,12.6) BD14(-24.6,11.4) BD15(-24.6,10.2) BD16(-24.6,9) BD17(-24.6,7.8) BD18(-24.6,6.6) BD19(-24.6,5.4) BD20(-24.6,4.2) BD21(-24.6,3) BD22(-24.6,1.8) BD23(-24.6,0.6) BD24(-24.6,-0.6) BD25(-24.6,-1.8) BD26(-24.6,-3) BD27(-24.6,-4.2) BD28(-24.6,-5.4) BD29(-24.6,-6.6) BD30(-24.6,-7.8) BD31(-24.6,-9) BD32(-24.6,-10.2) BD33(-24.6,-11.4) BD34(-24.6,-12.6) BD35(-24.6,-13.8) BD36(-24.6,-15) BD37(-24.6,-16.2) BD38(-24.6,-17.4) BD39(-24.6,-18.6) BD40(-24.6,-19.8) BD41(-24.6,-21) BD42(-24.6,-22.2) BD43(-24.6,-23.4) BD44(-24.6,-24.6) BD45(-24.6,-25.8) BD46(-24.6,-27) BE1(-25.8,27) BE2(-25.8,25.8) BE3(-25.8,24.6) BE4(-25.8,23.4) BE5(-25.8,22.2) BE6(-25.8,21) BE7(-25.8,19.8) BE8(-25.8,18.6) BE9(-25.8,17.4) BE10(-25.8,16.2) BE11(-25.8,15) BE12(-25.8,13.8) BE13(-25.8,12.6) BE14(-25.8,11.4) BE15(-25.8,10.2) BE16(-25.8,9) BE17(-25.8,7.8) BE18(-25.8,6.6) BE19(-25.8,5.4) BE20(-25.8,4.2) BE21(-25.8,3) BE22(-25.8,1.8) BE23(-25.8,0.6) BE24(-25.8,-0.6) BE25(-25.8,-1.8) BE26(-25.8,-3) BE27(-25.8,-4.2) BE28(-25.8,-5.4) BE29(-25.8,-6.6) BE30(-25.8,-7.8) BE31(-25.8,-9) BE32(-25.8,-10.2) BE33(-25.8,-11.4) BE34(-25.8,-12.6) BE35(-25.8,-13.8) BE36(-25.8,-15) BE37(-25.8,-16.2) BE38(-25.8,-17.4) BE39(-25.8,-18.6) BE40(-25.8,-19.8) BE41(-25.8,-21) BE42(-25.8,-22.2) BE43(-25.8,-23.4) BE44(-25.8,-24.6) BE45(-25.8,-25.8) BE46(-25.8,-27) BF1(-27,27) BF2(-27,25.8) BF3(-27,24.6) BF4(-27,23.4) BF5(-27,22.2) BF6(-27,21) BF7(-27,19.8) BF8(-27,18.6) BF9(-27,17.4) BF10(-27,16.2) BF11(-27,15) BF12(-27,13.8) BF13(-27,12.6) BF14(-27,11.4) BF15(-27,10.2) BF16(-27,9) BF17(-27,7.8) BF18(-27,6.6) BF19(-27,5.4) BF20(-27,4.2) BF21(-27,3) BF22(-27,1.8) BF23(-27,0.6) BF24(-27,-0.6) BF25(-27,-1.8) BF26(-27,-3) BF27(-27,-4.2) BF28(-27,-5.4) BF29(-27,-6.6) BF30(-27,-7.8) BF31(-27,-9) BF32(-27,-10.2) BF33(-27,-11.4) BF34(-27,-12.6) BF35(-27,-13.8) BF36(-27,-15) BF37(-27,-16.2) BF38(-27,-17.4) BF39(-27,-18.6) BF40(-27,-19.8) BF41(-27,-21) BF42(-27,-22.2) BF43(-27,-23.4) BF44(-27,-24.6) BF45(-27,-25.8) BF46(-27,-27) C1(24.6,27) C2(24.6,25.8) C3(24.6,24.6) C4(24.6,23.4) C5(24.6,22.2) C6(24.6,21) C7(24.6,19.8) C8(24.6,18.6) C9(24.6,17.4) C10(24.6,16.2) C11(24.6,15) C12(24.6,13.8) C13(24.6,12.6) C14(24.6,11.4) C15(24.6,10.2) C16(24.6,9) C17(24.6,7.8) C18(24.6,6.6) C19(24.6,5.4) C20(24.6,4.2) C21(24.6,3) C22(24.6,1.8) C23(24.6,0.6) C24(24.6,-0.6) C25(24.6,-1.8) C26(24.6,-3) C27(24.6,-4.2) C28(24.6,-5.4) C29(24.6,-6.6) C30(24.6,-7.8) C31(24.6,-9) C32(24.6,-10.2) C33(24.6,-11.4) C34(24.6,-12.6) C35(24.6,-13.8) C36(24.6,-15) C37(24.6,-16.2) C38(24.6,-17.4) C39(24.6,-18.6) C40(24.6,-19.8) C41(24.6,-21) C42(24.6,-22.2) C43(24.6,-23.4) C44(24.6,-24.6) C45(24.6,-25.8) C46(24.6,-27) D1(23.4,27) D2(23.4,25.8) D3(23.4,24.6) D4(23.4,23.4) D5(23.4,22.2) D6(23.4,21) D7(23.4,19.8) D8(23.4,18.6) D9(23.4,17.4) D10(23.4,16.2) D11(23.4,15) D12(23.4,13.8) D13(23.4,12.6) D14(23.4,11.4) D15(23.4,10.2) D16(23.4,9) D17(23.4,7.8) D18(23.4,6.6) D19(23.4,5.4) D20(23.4,4.2) D21(23.4,3) D22(23.4,1.8) D23(23.4,0.6) D24(23.4,-0.6) D25(23.4,-1.8) D26(23.4,-3) D27(23.4,-4.2) D28(23.4,-5.4) D29(23.4,-6.6) D30(23.4,-7.8) D31(23.4,-9) D32(23.4,-10.2) D33(23.4,-11.4) D34(23.4,-12.6) D35(23.4,-13.8) D36(23.4,-15) D37(23.4,-16.2) D38(23.4,-17.4) D39(23.4,-18.6) D40(23.4,-19.8) D41(23.4,-21) D42(23.4,-22.2) D43(23.4,-23.4) D44(23.4,-24.6) D45(23.4,-25.8) D46(23.4,-27) E1(22.2,27) E2(22.2,25.8) E3(22.2,24.6) E4(22.2,23.4) E5(22.2,22.2) E6(22.2,21) E7(22.2,19.8) E8(22.2,18.6) E9(22.2,17.4) E10(22.2,16.2) E11(22.2,15) E12(22.2,13.8) E13(22.2,12.6) E14(22.2,11.4) E15(22.2,10.2) E16(22.2,9) E17(22.2,7.8) E18(22.2,6.6) E19(22.2,5.4) E20(22.2,4.2) E21(22.2,3) E22(22.2,1.8) E23(22.2,0.6) E24(22.2,-0.6) E25(22.2,-1.8) E26(22.2,-3) E27(22.2,-4.2) E28(22.2,-5.4) E29(22.2,-6.6) E30(22.2,-7.8) E31(22.2,-9) E32(22.2,-10.2) E33(22.2,-11.4) E34(22.2,-12.6) E35(22.2,-13.8) E36(22.2,-15) E37(22.2,-16.2) E38(22.2,-17.4) E39(22.2,-18.6) E40(22.2,-19.8) E41(22.2,-21) E42(22.2,-22.2) E43(22.2,-23.4) E44(22.2,-24.6) E45(22.2,-25.8) E46(22.2,-27) F1(21,27) F2(21,25.8) F3(21,24.6) F4(21,23.4) F5(21,22.2) F6(21,21) F7(21,19.8) F8(21,18.6) F9(21,17.4) F10(21,16.2) F11(21,15) F12(21,13.8) F13(21,12.6) F14(21,11.4) F15(21,10.2) F16(21,9) F17(21,7.8) F18(21,6.6) F19(21,5.4) F20(21,4.2) F21(21,3) F22(21,1.8) F23(21,0.6) F24(21,-0.6) F25(21,-1.8) F26(21,-3) F27(21,-4.2) F28(21,-5.4) F29(21,-6.6) F30(21,-7.8) F31(21,-9) F32(21,-10.2) F33(21,-11.4) F34(21,-12.6) F35(21,-13.8) F36(21,-15) F37(21,-16.2) F38(21,-17.4) F39(21,-18.6) F40(21,-19.8) F41(21,-21) F42(21,-22.2) F43(21,-23.4) F44(21,-24.6) F45(21,-25.8) F46(21,-27) G1(19.8,27) G2(19.8,25.8) G3(19.8,24.6) G4(19.8,23.4) G5(19.8,22.2) G6(19.8,21) G7(19.8,19.8) G8(19.8,18.6) G9(19.8,17.4) G10(19.8,16.2) G11(19.8,15) G12(19.8,13.8) G13(19.8,12.6) G14(19.8,11.4) G15(19.8,10.2) G16(19.8,9) G17(19.8,7.8) G18(19.8,6.6) G19(19.8,5.4) G20(19.8,4.2) G21(19.8,3) G22(19.8,1.8) G23(19.8,0.6) G24(19.8,-0.6) G25(19.8,-1.8) G26(19.8,-3) G27(19.8,-4.2) G28(19.8,-5.4) G29(19.8,-6.6) G30(19.8,-7.8) G31(19.8,-9) G32(19.8,-10.2) G33(19.8,-11.4) G34(19.8,-12.6) G35(19.8,-13.8) G36(19.8,-15) G37(19.8,-16.2) G38(19.8,-17.4) G39(19.8,-18.6) G40(19.8,-19.8) G41(19.8,-21) G42(19.8,-22.2) G43(19.8,-23.4) G44(19.8,-24.6) G45(19.8,-25.8) G46(19.8,-27) H1(18.6,27) H2(18.6,25.8) H3(18.6,24.6) H4(18.6,23.4) H5(18.6,22.2) H6(18.6,21) H7(18.6,19.8) H8(18.6,18.6) H9(18.6,17.4) H10(18.6,16.2) H11(18.6,15) H12(18.6,13.8) H13(18.6,12.6) H14(18.6,11.4) H15(18.6,10.2) H16(18.6,9) H17(18.6,7.8) H18(18.6,6.6) H19(18.6,5.4) H20(18.6,4.2) H21(18.6,3) H22(18.6,1.8) H23(18.6,0.6) H24(18.6,-0.6) H25(18.6,-1.8) H26(18.6,-3) H27(18.6,-4.2) H28(18.6,-5.4) H29(18.6,-6.6) H30(18.6,-7.8) H31(18.6,-9) H32(18.6,-10.2) H33(18.6,-11.4) H34(18.6,-12.6) H35(18.6,-13.8) H36(18.6,-15) H37(18.6,-16.2) H38(18.6,-17.4) H39(18.6,-18.6) H40(18.6,-19.8) H41(18.6,-21) H42(18.6,-22.2) H43(18.6,-23.4) H44(18.6,-24.6) H45(18.6,-25.8) H46(18.6,-27) J1(17.4,27) J2(17.4,25.8) J3(17.4,24.6) J4(17.4,23.4) J5(17.4,22.2) J6(17.4,21) J7(17.4,19.8) J8(17.4,18.6) J9(17.4,17.4) J10(17.4,16.2) J11(17.4,15) J12(17.4,13.8) J13(17.4,12.6) J14(17.4,11.4) J15(17.4,10.2) J16(17.4,9) J17(17.4,7.8) J18(17.4,6.6) J19(17.4,5.4) J20(17.4,4.2) J21(17.4,3) J22(17.4,1.8) J23(17.4,0.6) J24(17.4,-0.6) J25(17.4,-1.8) J26(17.4,-3) J27(17.4,-4.2) J28(17.4,-5.4) J29(17.4,-6.6) J30(17.4,-7.8) J31(17.4,-9) J32(17.4,-10.2) J33(17.4,-11.4) J34(17.4,-12.6) J35(17.4,-13.8) J36(17.4,-15) J37(17.4,-16.2) J38(17.4,-17.4) J39(17.4,-18.6) J40(17.4,-19.8) J41(17.4,-21) J42(17.4,-22.2) J43(17.4,-23.4) J44(17.4,-24.6) J45(17.4,-25.8) J46(17.4,-27) K1(16.2,27) K2(16.2,25.8) K3(16.2,24.6) K4(16.2,23.4) K5(16.2,22.2) K6(16.2,21) K7(16.2,19.8) K8(16.2,18.6) K9(16.2,17.4) K10(16.2,16.2) K11(16.2,15) K12(16.2,13.8) K13(16.2,12.6) K14(16.2,11.4) K15(16.2,10.2) K16(16.2,9) K17(16.2,7.8) K18(16.2,6.6) K19(16.2,5.4) K20(16.2,4.2) K21(16.2,3) K22(16.2,1.8) K23(16.2,0.6) K24(16.2,-0.6) K25(16.2,-1.8) K26(16.2,-3) K27(16.2,-4.2) K28(16.2,-5.4) K29(16.2,-6.6) K30(16.2,-7.8) K31(16.2,-9) K32(16.2,-10.2) K33(16.2,-11.4) K34(16.2,-12.6) K35(16.2,-13.8) K36(16.2,-15) K37(16.2,-16.2) K38(16.2,-17.4) K39(16.2,-18.6) K40(16.2,-19.8) K41(16.2,-21) K42(16.2,-22.2) K43(16.2,-23.4) K44(16.2,-24.6) K45(16.2,-25.8) K46(16.2,-27) L1(15,27) L2(15,25.8) L3(15,24.6) L4(15,23.4) L5(15,22.2) L6(15,21) L7(15,19.8) L8(15,18.6) L9(15,17.4) L10(15,16.2) L11(15,15) L12(15,13.8) L13(15,12.6) L14(15,11.4) L15(15,10.2) L16(15,9) L17(15,7.8) L18(15,6.6) L19(15,5.4) L20(15,4.2) L21(15,3) L22(15,1.8) L23(15,0.6) L24(15,-0.6) L25(15,-1.8) L26(15,-3) L27(15,-4.2) L28(15,-5.4) L29(15,-6.6) L30(15,-7.8) L31(15,-9) L32(15,-10.2) L33(15,-11.4) L34(15,-12.6) L35(15,-13.8) L36(15,-15) L37(15,-16.2) L38(15,-17.4) L39(15,-18.6) L40(15,-19.8) L41(15,-21) L42(15,-22.2) L43(15,-23.4) L44(15,-24.6) L45(15,-25.8) L46(15,-27) M1(13.8,27) M2(13.8,25.8) M3(13.8,24.6) M4(13.8,23.4) M5(13.8,22.2) M6(13.8,21) M7(13.8,19.8) M8(13.8,18.6) M9(13.8,17.4) M10(13.8,16.2) M11(13.8,15) M12(13.8,13.8) M13(13.8,12.6) M14(13.8,11.4) M15(13.8,10.2) M16(13.8,9) M17(13.8,7.8) M18(13.8,6.6) M19(13.8,5.4) M20(13.8,4.2) M21(13.8,3) M22(13.8,1.8) M23(13.8,0.6) M24(13.8,-0.6) M25(13.8,-1.8) M26(13.8,-3) M27(13.8,-4.2) M28(13.8,-5.4) M29(13.8,-6.6) M30(13.8,-7.8) M31(13.8,-9) M32(13.8,-10.2) M33(13.8,-11.4) M34(13.8,-12.6) M35(13.8,-13.8) M36(13.8,-15) M37(13.8,-16.2) M38(13.8,-17.4) M39(13.8,-18.6) M40(13.8,-19.8) M41(13.8,-21) M42(13.8,-22.2) M43(13.8,-23.4) M44(13.8,-24.6) M45(13.8,-25.8) M46(13.8,-27) N1(12.6,27) N2(12.6,25.8) N3(12.6,24.6) N4(12.6,23.4) N5(12.6,22.2) N6(12.6,21) N7(12.6,19.8) N8(12.6,18.6) N9(12.6,17.4) N10(12.6,16.2) N11(12.6,15) N12(12.6,13.8) N13(12.6,12.6) N14(12.6,11.4) N15(12.6,10.2) N16(12.6,9) N17(12.6,7.8) N18(12.6,6.6) N19(12.6,5.4) N20(12.6,4.2) N21(12.6,3) N22(12.6,1.8) N23(12.6,0.6) N24(12.6,-0.6) N25(12.6,-1.8) N26(12.6,-3) N27(12.6,-4.2) N28(12.6,-5.4) N29(12.6,-6.6) N30(12.6,-7.8) N31(12.6,-9) N32(12.6,-10.2) N33(12.6,-11.4) N34(12.6,-12.6) N35(12.6,-13.8) N36(12.6,-15) N37(12.6,-16.2) N38(12.6,-17.4) N39(12.6,-18.6) N40(12.6,-19.8) N41(12.6,-21) N42(12.6,-22.2) N43(12.6,-23.4) N44(12.6,-24.6) N45(12.6,-25.8) N46(12.6,-27) P1(11.4,27) P2(11.4,25.8) P3(11.4,24.6) P4(11.4,23.4) P5(11.4,22.2) P6(11.4,21) P7(11.4,19.8) P8(11.4,18.6) P9(11.4,17.4) P10(11.4,16.2) P11(11.4,15) P12(11.4,13.8) P13(11.4,12.6) P14(11.4,11.4) P15(11.4,10.2) P16(11.4,9) P17(11.4,7.8) P18(11.4,6.6) P19(11.4,5.4) P20(11.4,4.2) P21(11.4,3) P22(11.4,1.8) P23(11.4,0.6) P24(11.4,-0.6) P25(11.4,-1.8) P26(11.4,-3) P27(11.4,-4.2) P28(11.4,-5.4) P29(11.4,-6.6) P30(11.4,-7.8) P31(11.4,-9) P32(11.4,-10.2) P33(11.4,-11.4) P34(11.4,-12.6) P35(11.4,-13.8) P36(11.4,-15) P37(11.4,-16.2) P38(11.4,-17.4) P39(11.4,-18.6) P40(11.4,-19.8) P41(11.4,-21) P42(11.4,-22.2) P43(11.4,-23.4) P44(11.4,-24.6) P45(11.4,-25.8) P46(11.4,-27) R1(10.2,27) R2(10.2,25.8) R3(10.2,24.6) R4(10.2,23.4) R5(10.2,22.2) R6(10.2,21) R7(10.2,19.8) R8(10.2,18.6) R9(10.2,17.4) R10(10.2,16.2) R11(10.2,15) R12(10.2,13.8) R13(10.2,12.6) R14(10.2,11.4) R15(10.2,10.2) R16(10.2,9) R17(10.2,7.8) R18(10.2,6.6) R19(10.2,5.4) R20(10.2,4.2) R21(10.2,3) R22(10.2,1.8) R23(10.2,0.6) R24(10.2,-0.6) R25(10.2,-1.8) R29(10.2,-6.6) R30(10.2,-7.8) R31(10.2,-9) R32(10.2,-10.2) R33(10.2,-11.4) R34(10.2,-12.6) R35(10.2,-13.8) R36(10.2,-15) R37(10.2,-16.2) R38(10.2,-17.4) R39(10.2,-18.6) R40(10.2,-19.8) R41(10.2,-21) R42(10.2,-22.2) R43(10.2,-23.4) R44(10.2,-24.6) R45(10.2,-25.8) R46(10.2,-27) T1(9,27) T2(9,25.8) T3(9,24.6) T4(9,23.4) T5(9,22.2) T6(9,21) T7(9,19.8) T8(9,18.6) T9(9,17.4) T10(9,16.2) T11(9,15) T12(9,13.8) T13(9,12.6) T14(9,11.4) T15(9,10.2) T16(9,9) T17(9,7.8) T18(9,6.6) T19(9,5.4) T20(9,4.2) T21(9,3) T22(9,1.8) T32(9,-10.2) T33(9,-11.4) T34(9,-12.6) T35(9,-13.8) T36(9,-15) T37(9,-16.2) T38(9,-17.4) T39(9,-18.6) T40(9,-19.8) T41(9,-21) T42(9,-22.2) T43(9,-23.4) T44(9,-24.6) T45(9,-25.8) T46(9,-27) U1(7.8,27) U2(7.8,25.8) U3(7.8,24.6) U4(7.8,23.4) U5(7.8,22.2) U6(7.8,21) U7(7.8,19.8) U8(7.8,18.6) U9(7.8,17.4) U10(7.8,16.2) U11(7.8,15) U12(7.8,13.8) U13(7.8,12.6) U14(7.8,11.4) U15(7.8,10.2) U16(7.8,9) U17(7.8,7.8) U18(7.8,6.6) U19(7.8,5.4) U20(7.8,4.2) U21(7.8,3) U22(7.8,1.8) U32(7.8,-10.2) U33(7.8,-11.4) U34(7.8,-12.6) U35(7.8,-13.8) U36(7.8,-15) U37(7.8,-16.2) U38(7.8,-17.4) U39(7.8,-18.6) U40(7.8,-19.8) U41(7.8,-21) U42(7.8,-22.2) U43(7.8,-23.4) U44(7.8,-24.6) U45(7.8,-25.8) U46(7.8,-27) V1(6.6,27) V2(6.6,25.8) V3(6.6,24.6) V4(6.6,23.4) V5(6.6,22.2) V6(6.6,21) V7(6.6,19.8) V8(6.6,18.6) V9(6.6,17.4) V10(6.6,16.2) V11(6.6,15) V12(6.6,13.8) V13(6.6,12.6) V14(6.6,11.4) V15(6.6,10.2) V16(6.6,9) V17(6.6,7.8) V18(6.6,6.6) V19(6.6,5.4) V20(6.6,4.2) V32(6.6,-10.2) V33(6.6,-11.4) V34(6.6,-12.6) V35(6.6,-13.8) V36(6.6,-15) V37(6.6,-16.2) V38(6.6,-17.4) V39(6.6,-18.6) V40(6.6,-19.8) V41(6.6,-21) V42(6.6,-22.2) V43(6.6,-23.4) V44(6.6,-24.6) V45(6.6,-25.8) V46(6.6,-27) W1(5.4,27) W2(5.4,25.8) W3(5.4,24.6) W4(5.4,23.4) W5(5.4,22.2) W6(5.4,21) W7(5.4,19.8) W8(5.4,18.6) W9(5.4,17.4) W10(5.4,16.2) W11(5.4,15) W12(5.4,13.8) W13(5.4,12.6) W14(5.4,11.4) W15(5.4,10.2) W16(5.4,9) W17(5.4,7.8) W18(5.4,6.6) W19(5.4,5.4) W32(5.4,-10.2) W33(5.4,-11.4) W34(5.4,-12.6) W35(5.4,-13.8) W36(5.4,-15) W37(5.4,-16.2) W38(5.4,-17.4) W39(5.4,-18.6) W40(5.4,-19.8) W41(5.4,-21) W42(5.4,-22.2) W43(5.4,-23.4) W44(5.4,-24.6) W45(5.4,-25.8) W46(5.4,-27) Y1(4.2,27) Y2(4.2,25.8) Y3(4.2,24.6) Y4(4.2,23.4) Y5(4.2,22.2) Y6(4.2,21) Y7(4.2,19.8) Y8(4.2,18.6) Y9(4.2,17.4) Y10(4.2,16.2) Y11(4.2,15) Y12(4.2,13.8) Y13(4.2,12.6) Y14(4.2,11.4) Y15(4.2,10.2) Y16(4.2,9) Y17(4.2,7.8) Y32(4.2,-10.2) Y33(4.2,-11.4) Y34(4.2,-12.6) Y35(4.2,-13.8) Y36(4.2,-15) Y37(4.2,-16.2) Y38(4.2,-17.4) Y39(4.2,-18.6) Y40(4.2,-19.8) Y41(4.2,-21) Y42(4.2,-22.2) Y43(4.2,-23.4) Y44(4.2,-24.6) Y45(4.2,-25.8) Y46(4.2,-27)
  silkscreen extent -28.75,-28.75 29.36,29.36, body extent -28.75,-28.75 28.75,28.75, height 1.5
MPQ4371GVE-1001-AECC901-Z [mm]
  rect 0.9x0.3 smd paste-2539.97 mask+0.05: 1(-1.85,2.125) 18(1.85,2.125)
  round 0.025 smd paste-2539.97 mask+0.05: 2(-1.85,1.625) 7(-1.725,-1.625) 9(-0.25,-1.65) 12(1.725,-1.625) 17(1.85,1.625)
  rect 0.9x0.3 smd paste-0.036 mask+0.05: 3(-1.85,1.1) 4(-1.85,0.4) 6(-1.85,-1) 13(1.85,-1) 15(1.85,0.4) 16(1.85,1.1)
  rect 1.2x0.3 smd paste-0.038 mask+0.05: 5(-1.7,-0.3) 14(1.7,-0.3)
  rect 1.15x0.25 smd paste-2539.97 mask+0.05: 8(-1.725,-2.125) 11(1.725,-2.125)
  rect 0.25x2.3 smd paste-2539.97 mask+0.05: 10(0.25,-1.65)
  rect 0.25x1.05 smd paste-0.032 mask+0.05: 19(1,2.275) 20(0.5,2.275) 21(0,2.275) 22(-0.5,2.275) 23(-1,2.275)
  silkscreen extent -2.21,2.62 -2.11,2.72, body extent -2,-2.5 2,2.5, height 1.02
"MPS QFN8 pitch 0.5mm 1.5x2x1mm" [mm]
  round 0.025 smd mask+0.05: 1(-0.6,0.75)
  rrect25% 0.8x0.25 smd mask+0.05: 2(-0.65,0.25) 3(-0.65,-0.25) 4(-0.65,-0.75) 5(0.65,-0.75) 6(0.65,-0.25) 7(0.65,0.25) 8(0.65,0.75)
  silkscreen extent -1.07,1.22 -0.97,1.32, body extent -0.8,-1.05 0.8,1.05, height 1
"MPS QFN12 2x2mm pitch 0.4mm" [mm]
  round 0.025 smd mask+0.05: 1(-0.95,0.6)
  rrect25% 0.7x0.2 smd mask+0.05: 2(-0.95,0.2) 3(-0.95,-0.2) 4(-0.95,-0.6) 7(0.95,-0.6) 8(0.95,-0.2) 9(0.95,0.2) 10(0.95,0.6)
  rrect25% 0.2x0.7 smd mask+0.05: 5(-0.2,-0.95) 6(0.2,-0.95) 11(0.2,0.95) 12(-0.2,0.95)
  silkscreen extent -1.19,1.09 -1.09,1.19, body extent -1,-1 1,1, height 1
"MPS QNF6 2x2mm 6pin pitch 0.65mm thermal pad" [mm]
  rrect25% 0.7x0.25 smd mask+0.05: 1(-0.95,0.65) 2(-0.95,0) 3(-0.95,-0.65) 4(0.95,-0.65) 5(0.95,0) 6(0.95,0.65)
  round 0.025 smd paste-10 mask+0.05: 7(0,0)
  silkscreen extent -1.73,0.81 -1.63,0.91, body extent -1,-1 1,1, height 0.8
MX25UW25345GXDI00-TR [mm]
  round 0.4 smd mask+0.05: A2(-1,2) A3(0,2) A4(1,2) A5(2,2) B1(-2,1) B2(-1,1) B3(0,1) B4(1,1) B5(2,1) C1(-2,0) C2(-1,0) C3(0,0) C4(1,0) C5(2,0) D1(-2,-1) D2(-1,-1) D3(0,-1) D4(1,-1) D5(2,-1) E1(-2,-2) E2(-1,-2) E3(0,-2) E4(1,-2) E5(2,-2)
  silkscreen extent -3.48,-4 3,4.49, body extent -3,-4 3,4, height 1.2
NFA725B [mm]
  rect 0.5x0.3 smd mask+0.05: 1(-5.6,6.75) 2(-5.6,6.25) 3(-5.6,5.75) 4(-5.6,5.25) 5(-5.6,4.75) 6(-5.6,4.25) 7(-5.6,3.75) 8(-5.6,3.25) 9(-5.6,2.75) 10(-5.6,2.25) 11(-5.6,1.75) 12(-5.6,1.25) 13(-5.6,0.75) 14(-5.6,0.25) 15(-5.6,-0.25) 16(-5.6,-0.75) 17(-5.6,-1.25) 18(-5.6,-1.75) 19(-5.6,-2.25) 20(-5.6,-2.75) 21(-5.6,-3.25) 22(-5.6,-3.75) 23(-5.6,-4.25) 24(-5.6,-4.75) 25(-5.6,-5.25) 26(-5.6,-5.75) 27(-5.6,-6.25) 28(-5.6,-6.75) 49(5.6,-6.75) 50(5.6,-6.25) 51(5.6,-5.75) 52(5.6,-5.25) 53(5.6,-4.75) 54(5.6,-4.25) 55(5.6,-3.75) 56(5.6,-3.25) 57(5.6,-2.75) 58(5.6,-2.25) 59(5.6,-1.75) 60(5.6,-1.25) 61(5.6,-0.75) 62(5.6,-0.25) 63(5.6,0.25) 64(5.6,0.75) 65(5.6,1.25) 66(5.6,1.75) 67(5.6,2.25) 68(5.6,2.75) 69(5.6,3.25) 70(5.6,3.75) 71(5.6,4.25) 72(5.6,4.75) 73(5.6,5.25) 74(5.6,5.75) 75(5.6,6.25) 76(5.6,6.75)
  rect 0.3x0.5 smd mask+0.05: 29(-4.75,-7.6) 30(-4.25,-7.6) 31(-3.75,-7.6) 32(-3.25,-7.6) 33(-2.75,-7.6) 34(-2.25,-7.6) 35(-1.75,-7.6) 36(-1.25,-7.6) 37(-0.75,-7.6) 38(-0.25,-7.6) 39(0.25,-7.6) 40(0.75,-7.6) 41(1.25,-7.6) 42(1.75,-7.6) 43(2.25,-7.6) 44(2.75,-7.6) 45(3.25,-7.6) 46(3.75,-7.6) 47(4.25,-7.6) 48(4.75,-7.6) 77(4.75,7.6) 78(4.25,7.6) 79(3.75,7.6) 80(3.25,7.6) 81(2.75,7.6) 82(2.25,7.6) 83(1.75,7.6) 84(1.25,7.6) 85(0.75,7.6) 86(0.25,7.6) 87(-0.25,7.6) 88(-0.75,7.6) 89(-1.25,7.6) 90(-1.75,7.6) 91(-2.25,7.6) 92(-2.75,7.6) 93(-3.25,7.6) 94(-3.75,7.6) 95(-4.25,7.6) 96(-4.75,7.6)
  round 0.025 smd paste-2539.97 mask+0.05: 97(-1.65,4.95)
  rect 3x3 smd paste-2539.97 mask+0.05: 98(-1.65,1.65) 99(-1.65,-1.65) 100(-1.65,-4.95) 101(1.65,-4.95) 102(1.65,-1.65) 103(1.65,1.65) 104(1.65,4.95)
  rect 0.7x0.7 smd mask+0.05: 105(-5.5,7.5) 106(-5.5,-7.5) 107(5.5,-7.5) 108(5.5,7.5)
  body extent -7.07,-8.88 7.07,8.88, height 1.8
PI7C9X2G304EV-Footprint-1 [mm]
  rect 0.2x0.35 smd mask+0.05: A1(-4.25,4.72) A3(-3.75,4.72) A5(-3.25,4.72) A7(-2.75,4.72) A9(-2.25,4.72) A11(-1.75,4.72) A13(-1.25,4.72) A15(-0.75,4.72) A17(-0.25,4.72) A19(0.25,4.72) A21(0.75,4.72) A23(1.25,4.72) A25(1.75,4.72) A27(2.25,4.72) A29(2.75,4.72) A31(3.25,4.72) A33(3.75,4.72) A35(4.25,4.72) AP2(-4,-4.17) AP4(-3.5,-4.17) AP6(-3,-4.17) AP8(-2.5,-4.17) AP10(-2,-4.17) AP12(-1.5,-4.17) AP14(-1,-4.17) AP16(-0.5,-4.17) AP18(0,-4.17) AP20(0.5,-4.17) AP22(1,-4.17) AP24(1.5,-4.17) AP26(2,-4.17) AP28(2.5,-4.17) AP30(3,-4.17) AP32(3.5,-4.17) AP34(4,-4.17) AR1(4.25,-4.72) AR3(3.75,-4.72) AR5(3.25,-4.72) AR7(2.75,-4.72) AR9(2.25,-4.72) AR11(1.75,-4.72) AR13(1.25,-4.72) AR15(0.75,-4.72) AR17(0.25,-4.72) AR19(-0.25,-4.72) AR21(-0.75,-4.72) AR23(-1.25,-4.72) AR25(-1.75,-4.72) AR27(-2.25,-4.72) AR29(-2.75,-4.72) AR31(-3.25,-4.72) AR33(-3.75,-4.72) AR35(-4.25,-4.72) B2(-4,4.17) B4(-3.5,4.17) B6(-3,4.17) B8(-2.5,4.17) B10(-2,4.17) B12(-1.5,4.17) B14(-1,4.17) B16(-0.5,4.17) B18(0,4.17) B20(0.5,4.17) B22(1,4.17) B24(1.5,4.17) B26(2,4.17) B28(2.5,4.17) B30(3,4.17) B32(3.5,4.17) B34(4,4.17)
  rect 0.35x0.2 smd mask+0.05: AA1(-4.72,-0.75) AA35(4.72,-0.75) AB2(-4.17,-1) AB34(4.17,-1) AC1(-4.72,-1.25) AC35(4.72,-1.25) AD2(-4.17,-1.5) AD34(4.17,-1.5) AE1(-4.72,-1.75) AE35(4.72,-1.75) AF2(-4.17,-2) AF34(4.17,-2) AG1(-4.72,-2.25) AG35(4.72,-2.25) AH2(-4.17,-2.5) AH34(4.17,-2.5) AJ1(-4.72,-2.75) AJ35(4.72,-2.75) AK2(-4.17,-3) AK34(4.17,-3) AL1(-4.72,-3.25) AL35(4.72,-3.25) AM2(-4.17,-3.5) AM34(4.17,-3.5) AN1(-4.72,-3.75) AN35(4.72,-3.75) AP1(-4.72,-4.25) AP35(4.72,-4.25) B1(-4.72,4.25) B35(4.72,4.25) C1(-4.72,3.75) C35(4.72,3.75) D2(-4.17,3.5) D34(4.17,3.5) E1(-4.72,3.25) E35(4.72,3.25) F2(-4.17,3) F34(4.17,3) G1(-4.72,2.75) G35(4.72,2.75) H2(-4.17,2.5) H34(4.17,2.5) J1(-4.72,2.25) J35(4.72,2.25) K2(-4.17,2) K34(4.17,2) L1(-4.72,1.75) L35(4.72,1.75) M2(-4.17,1.5) M34(4.17,1.5) N1(-4.72,1.25) N35(4.72,1.25) P2(-4.17,1) P34(4.17,1) R1(-4.72,0.75) R35(4.72,0.75) T2(-4.17,0.5) T34(4.17,0.5) U1(-4.72,0.25) U35(4.72,0.25) V2(-4.17,0) V34(4.17,0) W1(-4.72,-0.25) W35(4.72,-0.25) Y2(-4.17,-0.5) Y34(4.17,-0.5)
  rect 5.95x0.15 smd mask+0.05: B(0,-3.3) T(0,3.3)
  rect 1x1 smd paste-0.113 mask+0.05: GND(-2.25,2.25) GND(-2.25,-0.75) GND(-2.25,0.75) GND(-2.25,-2.25) GND(-0.75,2.25) GND(-0.75,0.75) GND(-0.75,-0.75) GND(-0.75,-2.25) GND(0.75,2.25) GND(0.75,0.75) GND(0.75,-0.75) GND(0.75,-2.25) GND(2.25,2.25) GND(2.25,-0.75) GND(2.25,0.75) GND(2.25,-2.25)
  rect 0.15x5.95 smd mask+0.05: L(-3.3,0) R(3.3,0)
  silkscreen extent -5.05,4.95 -4.95,5.05, body extent -5,-5 5,5, height 0.87
PMF63 [mm] "PMF63 K-WELL"
  rect 2.2x3.5 smd paste-0.142 mask+0.05: 1(-2.9,0) 2(2.9,0)
  body extent -3.45,-3.45 3.45,3.45, height 3.05
QFN50P250X450X100_HS-21N [mm] "QFN, 20-Leads, Body 2,50x4,50mm, Pitch 0,50mm, Thermal Pad 1,00x3,00mm, IPC Medium Density"
  rrect25% 0.24x0.6 smd mask+0.05: 1(-0.25,2.15) 10(-0.25,-2.15) 11(0.25,-2.15) 20(0.25,2.15)
  rrect25% 0.6x0.24 smd mask+0.05: 2(-1.15,1.75) 3(-1.15,1.25) 4(-1.15,0.75) 5(-1.15,0.25) 6(-1.15,-0.25) 7(-1.15,-0.75) 8(-1.15,-1.25) 9(-1.15,-1.75) 12(1.15,-1.75) 13(1.15,-1.25) 14(1.15,-0.75) 15(1.15,-0.25) 16(1.15,0.25) 17(1.15,0.75) 18(1.15,1.25) 19(1.15,1.75)
  rrect5% 1x3 smd paste-1 mask+0.05: 21(0,0)
  silkscreen extent -1.61,2.25 -1.51,2.35, body extent -1.35,-2.35 1.35,2.35, height 1
"QFN52 pitch 0.4mm, 5x8mm" [mm]
  rrect25% 0.75x0.2 smd mask+0.05: 1(-2.45,3) 2(-2.45,2.6) 3(-2.45,2.2) 4(-2.45,1.8) 5(-2.45,1.4) 6(-2.45,1) 7(-2.45,0.6) 8(-2.45,0.2) 9(-2.45,-0.2) 10(-2.45,-0.6) 11(-2.45,-1) 12(-2.45,-1.4) 13(-2.45,-1.8) 14(-2.45,-2.2) 15(-2.45,-2.6) 16(-2.45,-3) 27(2.45,-3) 28(2.45,-2.6) 29(2.45,-2.2) 30(2.45,-1.8) 31(2.45,-1.4) 32(2.45,-1) 33(2.45,-0.6) 34(2.45,-0.2) 35(2.45,0.2) 36(2.45,0.6) 37(2.45,1) 38(2.45,1.4) 39(2.45,1.8) 40(2.45,2.2) 41(2.45,2.6) 42(2.45,3)
  rrect25% 0.2x0.75 smd mask+0.05: 17(-1.8,-3.95) 18(-1.4,-3.95) 19(-1,-3.95) 20(-0.6,-3.95) 21(-0.2,-3.95) 22(0.2,-3.95) 23(0.6,-3.95) 24(1,-3.95) 25(1.4,-3.95) 26(1.8,-3.95) 43(1.8,3.95) 44(1.4,3.95) 45(1,3.95) 46(0.6,3.95) 47(0.2,3.95) 48(-0.2,3.95) 49(-0.6,3.95) 50(-1,3.95) 51(-1.4,3.95) 52(-1.8,3.95)
  rrect5% 3.5x6.5 smd paste-1.75 mask+0.05: 53(0,0)
  silkscreen extent -2.84,4.27 -2.74,4.37, body extent -2.5,-4 2.5,4, height 0.9
QFN127P600-8N [mm]
  rrect50% 0.85x0.2 smd mask+0.05: 1(-2.95,2.2) 2(-2.95,1.8) 3(-2.95,1.4) 4(-2.95,1) 5(-2.95,0.6) 6(-2.95,0.2) 7(-2.95,-0.2) 8(-2.95,-0.6) 9(-2.95,-1) 10(-2.95,-1.4) 11(-2.95,-1.8) 12(-2.95,-2.2) 25(2.95,-2.2) 26(2.95,-1.8) 27(2.95,-1.4) 28(2.95,-1) 29(2.95,-0.6) 30(2.95,-0.2) 31(2.95,0.2) 32(2.95,0.6) 33(2.95,1) 34(2.95,1.4) 35(2.95,1.8) 36(2.95,2.2)
  rrect50% 0.2x0.85 smd mask+0.05: 13(-2.2,-2.95) 14(-1.8,-2.95) 15(-1.4,-2.95) 16(-1,-2.95) 17(-0.6,-2.95) 18(-0.2,-2.95) 19(0.2,-2.95) 20(0.6,-2.95) 21(1,-2.95) 22(1.4,-2.95) 23(1.8,-2.95) 24(2.2,-2.95) 37(2.2,2.95) 38(1.8,2.95) 39(1.4,2.95) 40(1,2.95) 41(0.6,2.95) 42(0.2,2.95) 43(-0.2,2.95) 44(-0.6,2.95) 45(-1,2.95) 46(-1.4,2.95) 47(-1.8,2.95) 48(-2.2,2.95)
  rect 4.5x4.5 smd paste-2539.97 mask+0.05: 49(0,0)
  silkscreen extent -3.1,3 -3,3.1, body extent -3.05,-3.05 3.05,3.05, height 0.75
"Qualcomm QCA8081 56 MQFN 7x7mm pitch 0.4mm" [mm]
  rrect25% 0.9x0.2 smd mask+0.05: 1(-3.375,2.6) 2(-3.375,2.2) 3(-3.375,1.8) 4(-3.375,1.4) 5(-3.375,1) 6(-3.375,0.6) 7(-3.375,0.2) 8(-3.375,-0.2) 9(-3.375,-0.6) 10(-3.375,-1) 11(-3.375,-1.4) 12(-3.375,-1.8) 13(-3.375,-2.2) 14(-3.375,-2.6) 29(3.375,-2.6) 30(3.375,-2.2) 31(3.375,-1.8) 32(3.375,-1.4) 33(3.375,-1) 34(3.375,-0.6) 35(3.375,-0.2) 36(3.375,0.2) 37(3.375,0.6) 38(3.375,1) 39(3.375,1.4) 40(3.375,1.8) 41(3.375,2.2) 42(3.375,2.6)
  rrect25% 0.2x0.9 smd mask+0.05: 15(-2.6,-3.375) 16(-2.2,-3.375) 17(-1.8,-3.375) 18(-1.4,-3.375) 19(-1,-3.375) 20(-0.6,-3.375) 21(-0.2,-3.375) 22(0.2,-3.375) 23(0.6,-3.375) 24(1,-3.375) 25(1.4,-3.375) 26(1.8,-3.375) 27(2.2,-3.375) 28(2.6,-3.375) 43(2.6,3.375) 44(2.2,3.375) 45(1.8,3.375) 46(1.4,3.375) 47(1,3.375) 48(0.6,3.375) 49(0.2,3.375) 50(-0.2,3.375) 51(-0.6,3.375) 52(-1,3.375) 53(-1.4,3.375) 54(-1.8,3.375) 55(-2.2,3.375) 56(-2.6,3.375)
  rrect5% 3.6x3.6 smd paste-1.8 mask+0.05: 57(0,0)
  silkscreen extent -3.73,3.63 -3.63,3.73, body extent -3.5,-3.5 3.5,3.5, height 0.9
RES-0201 [mm] "Chip Resistor, 2-Leads, Body 0201 (in) 0603 (mm) IPC Medium Density"
  rrect52% 0.31x0.34 smd mask+0.05: 1(-0.275,0) 2(0.275,0)
  body extent -0.3,-0.15 0.3,0.15, height 0.24
RES-0402 [mm] "Chip Resistor, 2-Leads, Body  0402 (in) 1005 (mm), IPC Medium Density"
  rrect51% 0.55x0.58 smd mask+0.05: 1(-0.475,0) 2(0.475,0)
  body extent -0.5,-0.25 0.5,0.25, height 0.34
RES-0603 [mm] "Chip Resistor - Body 0603 imperial,1.6x0.8mm, IPC High Density"
  rrect51% 0.82x0.97 smd mask+0.05: 1(-0.775,0) 2(0.775,0)
  body extent -0.8,-0.4 0.8,0.4, height 0.43
RES-0805 [mm] "Chip Resistor - Body 0805 imperial, 2.0x1.2mm, IPC Medium Density"
  rrect51% 0.99x1.47 smd mask+0.05: 1(-0.915,0) 2(0.915,0)
  body extent -1,-0.62 1,0.63, height 0.58
SHDT-2014-TS [mm]
  oval 2.3x5.1 hole 0.8 slot 3.6 at 90 deg: 1(5.8,0)
  oval 4.7x2.5 hole 0.8 slot 3.2 at 0 deg: 2(2.8,-4.7)
  oval 2.2x4.7 hole 0.7 slot 3.2 at 90 deg: 3(0,0)
  body extent -7.8,-4.85 6.6,4.55, height 1.4
SLP2510P8 [mm]
  rrect10% 0.675x0.2 smd paste+0 mask+0.05: 1(-0.437,1) 2(-0.437,0.5) 4(-0.437,-0.5) 5(-0.437,-1) 6(0.437,-1) 7(0.437,-0.5) 9(0.437,0.5) 10(0.437,1)
  rrect10% 0.904x0.4 smd paste-0.061 mask+0.05: 3(-0.323,0) 8(0.324,0)
  silkscreen extent -0.68,1.35 -0.59,1.45, body extent -0.5,-1.25 0.5,1.25, height 0.65
SM04B-SRSS-TB(LF)(SN)-Footprint-1 [mm]
  rect 0.6x1.55 smd mask+0.05: 1(1.5,-1.937) 2(0.5,-1.937) 3(-0.5,-1.937) 4(-1.5,-1.937)
  rect 1.2x1.8 smd mask+0.05: FIX(-2.8,1.938) FIX(2.8,1.938)
  body extent -3,-2.15 3,2.8, height 2.98
"SMA DO214AC" [mm]
  rect 2.07x2.06 smd mask+0: A(-1.9,0) C(1.9,0)
  silkscreen extent -0.46,-0.76 0.46,0.76, body extent -2.6,-1.3 2.6,1.3, height 2.4
SMB_NOPOLARITY [mm]
  rect 2.5x2.2 smd: 1(-2.35,0) 2(2.35,0)
  body extent -2.55,-1.97 2.55,1.97, height 2.62
SMLP34RGB2W [mm]
  rrect52% 0.54x0.54 smd mask+0.05: 1(-0.395,-0.395) 2(-0.395,0.395) 3(0.395,0.395) 4(0.395,-0.395)
  silkscreen extent -1.08,-0.45 -0.98,-0.35, body extent -0.5,-0.5 0.5,0.5, height 0.2
"SOD323 NO POLARITY" [mm] "Molded Diode, 2-Leads, Body 1,70x1,25mm, IPC High Density"
  rrect25% 0.73x0.5 smd mask+0.05: 1(-1.085,0) 2(1.085,0)
  body extent -1.12,-0.67 1.12,0.67, height 1.1
"SOT23-6 PITCH 0.95" [mm] "SOT23, 6-Leads, Body 2,90x2,80mm, Pitch 0,95mm, IPC Medium Density"
  rrect25% 1.1x0.6 smd mask+0.05: 1(-1.3,0.95) 2(-1.3,0) 3(-1.3,-0.95) 4(1.3,-0.95) 5(1.3,0) 6(1.3,0.95)
  silkscreen extent -1.7,1.6 -1.6,1.7, body extent -1.39,-1.55 1.39,1.55, height 1.45
SOT363 [mm]
  rrect50% 0.5x0.6 smd mask+0.05: 1(-0.75,-0.9) 3(0.75,-0.9) 4(0.75,0.9) 6(-0.75,0.9)
  rrect50% 0.4x0.6 smd mask+0.05: 2(0,-0.9) 5(0,0.9)
  silkscreen extent -1.39,-0.95 -1.29,-0.85, body extent -1.05,-1.15 1.05,1.15, height 1
SOT563 [mm] "SOT 6-Pin FL DRL0006A SOT563"
  rrect50% 0.6x0.25 smd mask+0.05: 1(-0.7,0.5) 2(-0.7,0) 3(-0.7,-0.5) 4(0.7,-0.5) 5(0.7,0) 6(0.7,0.5)
  silkscreen extent -0.94,0.97 -0.84,1.07, body extent -0.8,-0.85 0.8,0.85, height 0.6
SQS414CENW-T1_GE3 [mm]
  rrect5% 1.725x2.389 smd paste-0.163 mask+0.05: D(0.558,0)
  rrect25% 0.99x0.405 smd paste-0.063 mask+0.05: D(1.435,0.992) D(1.435,-0.992) D(1.435,-0.332) D(1.435,0.332)
  rrect25% 0.99x0.405 smd paste-0.015 mask+0.05: G(-1.435,-0.992) S(-1.435,-0.332) S(-1.435,0.332) S(-1.435,0.992)
  silkscreen extent -1.95,1.6 -1.86,1.7, body extent -1.65,-1.65 1.65,1.65, height 1.06
TF31-22S-0.5SH(800) [mm]
  rect 0.3x1.3 smd mask+0.05: 1(5.25,1.625) 2(4.75,1.625) 3(4.25,1.625) 4(3.75,1.625) 5(3.25,1.625) 6(2.75,1.625) 7(2.25,1.625) 8(1.75,1.625) 9(1.25,1.625) 10(0.75,1.625) 11(0.25,1.625) 12(-0.25,1.625) 13(-0.75,1.625) 14(-1.25,1.625) 15(-1.75,1.625) 16(-2.25,1.625) 17(-2.75,1.625) 18(-3.25,1.625) 19(-3.75,1.625) 20(-4.25,1.625) 21(-4.75,1.625) 22(-5.25,1.625)
  rect 1.8x2.2 smd mask+0.05: FIX(-7.15,-1.625) FIX(7.15,-1.625)
  body extent -7.65,-3.83 7.65,1.92, height 2
"TI DDF SOT23-THIN 8 pin 1.6x2.9x1.1 mm heigth" [mm] "SOT23, 8-Leads, Body 2,95x1.65mm, Pitch 0,65mm, IPC Medium Density"
  rrect25% 1.05x0.45 smd mask+0.05: 1(-1.3,0.975) 2(-1.3,0.325) 3(-1.3,-0.325) 4(-1.3,-0.975) 5(1.3,-0.975) 6(1.3,-0.325) 7(1.3,0.325) 8(1.3,0.975)
  silkscreen extent -1.45,1.47 -1.35,1.57, body extent -1.4,-1.45 1.4,1.45, height 1.1
"TI DRL DRL0005A" [mm]
  rrect50% 0.67x0.3 smd mask+0.05: 1(-0.74,0.5) 2(-0.74,0) 3(-0.74,-0.5) 4(0.74,-0.5) 5(0.74,0.5)
  silkscreen extent -0.96,0.9 -0.86,1, body extent -0.8,-0.85 0.8,0.85, height 0.6
"TI QWFN40 RET0040A Pitch 0.4mm 3x6mm" [mm]
  rrect25% 0.45x0.2 smd mask+0.05: 1(-1.475,2.6) 2(-1.475,2.2) 3(-1.475,1.8) 4(-1.475,1.4) 5(-1.475,1) 6(-1.475,0.6) 7(-1.475,0.2) 8(-1.475,-0.2) 9(-1.475,-0.6) 10(-1.475,-1) 11(-1.475,-1.4) 12(-1.475,-1.8) 13(-1.475,-2.2) 14(-1.475,-2.6) 21(1.475,-2.6) 22(1.475,-2.2) 23(1.475,-1.8) 24(1.475,-1.4) 25(1.475,-1) 26(1.475,-0.6) 27(1.475,-0.2) 28(1.475,0.2) 29(1.475,0.6) 30(1.475,1) 31(1.475,1.4) 32(1.475,1.8) 33(1.475,2.2) 34(1.475,2.6)
  rrect25% 0.2x0.45 smd mask+0.05: 15(-1,-2.975) 16(-0.6,-2.975) 17(-0.2,-2.975) 18(0.2,-2.975) 19(0.6,-2.975) 20(1,-2.975) 35(1,2.975) 36(0.6,2.975) 37(0.2,2.975) 38(-0.2,2.975) 39(-0.6,2.975) 40(-1,2.975)
  rrect5% 1.7x4.5 smd paste-0.85 mask+0.05: 41(0,0)
  silkscreen extent -1.7,3.13 -1.6,3.22, body extent -1.55,-3.05 1.55,3.05, height 0.8
"TI RKM S-PWQFN-N100 Double row 9x9mm pitch 0.6mm" [mm] "Double Row QFN, 100-Leads, Body 9,00x9,00mm, Pitch 0,60mm, Thermal Pad 5,60x5,60mm, IPC Medium Density"
  rrect50% 0.25x0.6 smd mask+0.05: A1(3.6,4.5) A2(3,4.5) A3(2.4,4.5) A4(1.8,4.5) A5(1.2,4.5) A6(0.6,4.5) A7(0,4.5) A8(-0.6,4.5) A9(-1.2,4.5) A10(-1.8,4.5) A11(-2.4,4.5) A12(-3,4.5) A13(-3.6,4.5) A27(-3.6,-4.5) A28(-3,-4.5) A29(-2.4,-4.5) A30(-1.8,-4.5) A31(-1.2,-4.5) A32(-0.6,-4.5) A33(0,-4.5) A34(0.6,-4.5) A35(1.2,-4.5) A36(1.8,-4.5) A37(2.4,-4.5) A38(3,-4.5) A39(3.6,-4.5)
  rrect50% 0.6x0.25 smd mask+0.05: A14(-4.5,3.6) A15(-4.5,3) A16(-4.5,2.4) A17(-4.5,1.8) A18(-4.5,1.2) A19(-4.5,0.6) A20(-4.5,0) A21(-4.5,-0.6) A22(-4.5,-1.2) A23(-4.5,-1.8) A24(-4.5,-2.4) A25(-4.5,-3) A26(-4.5,-3.6) A40(4.5,-3.6) A41(4.5,-3) A42(4.5,-2.4) A43(4.5,-1.8) A44(4.5,-1.2) A45(4.5,-0.6) A46(4.5,0) A47(4.5,0.6) A48(4.5,1.2) A49(4.5,1.8) A50(4.5,2.4) A51(4.5,3) A52(4.5,3.6)
  round 0.025 smd paste-2539.97 mask+0.05: A53(0,0)
  rrect50% 0.25x0.4 smd mask+0.05: B1(3.025,3.65) B2(2.475,3.65) B3(1.925,3.65) B4(1.375,3.65) B5(0.825,3.65) B6(0.275,3.65) B7(-0.275,3.65) B8(-0.825,3.65) B9(-1.375,3.65) B10(-1.925,3.65) B11(-2.475,3.65) B12(-3.025,3.65) B25(-3.025,-3.65) B26(-2.475,-3.65) B27(-1.925,-3.65) B28(-1.375,-3.65) B29(-0.825,-3.65) B30(-0.275,-3.65) B31(0.275,-3.65) B32(0.825,-3.65) B33(1.375,-3.65) B34(1.925,-3.65) B35(2.475,-3.65) B36(3.025,-3.65)
  rrect50% 0.4x0.25 smd mask+0.05: B13(-3.65,3.025) B14(-3.65,2.475) B15(-3.65,1.925) B16(-3.65,1.375) B17(-3.65,0.825) B18(-3.65,0.275) B19(-3.65,-0.275) B20(-3.65,-0.825) B21(-3.65,-1.375) B22(-3.65,-1.925) B23(-3.65,-2.475) B24(-3.65,-3.025) B37(3.65,-3.025) B38(3.65,-2.475) B39(3.65,-1.925) B40(3.65,-1.375) B41(3.65,-0.825) B42(3.65,-0.275) B43(3.65,0.275) B44(3.65,0.825) B45(3.65,1.375) B46(3.65,1.925) B47(3.65,2.475) B48(3.65,3.025)
  rrect25% 0.3x0.3 smd mask+0.05: C1(4.25,4.25) C2(-4.25,4.25) C3(-4.25,-4.25) C4(4.25,-4.25)
  silkscreen extent 4.45,4.45 4.55,4.55, body extent -4.58,-4.57 4.57,4.57, height 0.83
"TI RUA0042A WQFN 42 pin pitch 0.5mm 3.5x9mm" [mm]
  rrect25% 0.6x0.25 smd mask+0.05: 1(-1.65,4) 2(-1.65,3.5) 3(-1.65,3) 4(-1.65,2.5) 5(-1.65,2) 6(-1.65,1.5) 7(-1.65,1) 8(-1.65,0.5) 9(-1.65,0) 10(-1.65,-0.5) 11(-1.65,-1) 12(-1.65,-1.5) 13(-1.65,-2) 14(-1.65,-2.5) 15(-1.65,-3) 16(-1.65,-3.5) 17(-1.65,-4) 22(1.65,-4) 23(1.65,-3.5) 24(1.65,-3) 25(1.65,-2.5) 26(1.65,-2) 27(1.65,-1.5) 28(1.65,-1) 29(1.65,-0.5) 30(1.65,0) 31(1.65,0.5) 32(1.65,1) 33(1.65,1.5) 34(1.65,2) 35(1.65,2.5) 36(1.65,3) 37(1.65,3.5) 38(1.65,4)
  rrect25% 0.25x0.6 smd mask+0.05: 18(-0.75,-4.4) 19(-0.25,-4.4) 20(0.25,-4.4) 21(0.75,-4.4) 39(0.75,4.4) 40(0.25,4.4) 41(-0.25,4.4) 42(-0.75,4.4)
  rrect5% 2.05x7.55 smd paste-2539.97 mask+0.05: 43(0,0)
  silkscreen extent -1.95,4.65 -1.86,4.75, body extent -1.75,-4.5 1.75,4.5, height 0.8
"TI RUT RUT0012A UQFN 2x1.7x0.55mm 12 pins 0.4mm pitch" [mm]
  rrect25% 0.7x0.2 smd mask+0.05: 1(-0.7,0.8) 2(-0.7,0.4) 3(-0.7,0) 4(-0.7,-0.4) 5(-0.7,-0.8) 7(0.7,-0.8) 8(0.7,-0.4) 9(0.7,0) 10(0.7,0.4) 11(0.7,0.8)
  rrect25% 0.2x0.7 smd mask+0.05: 6(0,-0.85) 12(0,0.85)
  silkscreen extent -1.32,1.1 -1.22,1.2, body extent -0.9,-1.05 0.9,1.05, height 0.55
TL3340AF160QG-Footprint-1 [mm]
  rect 0.68x1.6 smd mask+0.05: 1(-1.225,0.925) 3(1.225,0.925)
  rect 0.6x1.6 smd mask+0.05: 2(0,0.925)
  rect 1.3x0.8 smd mask+0.05: MNT(-1.85,-0.925) MNT(1.85,-0.925)
  round 0.5 hole 0.9 unplated: NC1(-2.125,0.075) NC2(2.125,0.075)
  body extent -2.25,-1.98 2.25,1.69, height 3.3
TP-1.00MM [mm]
  rrect100% 1x1 smd paste-2.54: X(0,0)
TRJT9010A98NL [mm]
  round 1.7 hole 0.89 mask+0.1: 1(-5.075,-6.475) 2(-3.045,-6.475) 3(-1.015,-6.475) 4(1.015,-6.475) 5(3.045,-6.475) 6(5.075,-6.475) 7(-6.09,-9.015) 8(-4.06,-9.015) 9(-2.03,-9.015) 10(2.03,-9.015) 11(4.06,-9.015) 12(6.09,-9.015)
  round 2.1 hole 1.27 mask+0.1: 13(-7.52,6.475) 14(-7.52,9.015) 15(7.52,3.935) 16(7.52,6.475) 17(7.52,9.015)
  round 2 hole 3.25 unplated mask+0.1: NC(-4.825,0.125) NC(4.825,0.125)
  round 2.4 hole 1.6 mask+0.1: SH1(-8.79,0.125) SH2(8.79,0.125)
  body extent -11.31,-10.86 11.29,13.34, height 13.9
TS42 [mm]
  rrect15% 1.6x1.4 smd: 1(4.2,-2.25) 2(-4.2,-2.25) 3(4.2,2.25) 4(-4.2,2.25)
  rrect15% 1.6x1.4 smd paste+0: 5(4.2,0)
  body extent -4.1,-3.25 4.1,3.25, height 2.6
TSOP65P210X110-6N [mm] "TSOP, 6-Leads, Body 2,00x1,25mm, Pitch 0,65mm, IPC Medium Density"
  rrect50% 0.66x0.3 smd mask+0.05: 1(-0.92,0.65) 2(-0.92,0) 3(-0.92,-0.65) 4(0.92,-0.65) 5(0.92,0) 6(0.92,0.65)
  silkscreen extent -1.19,1.09 -1.09,1.19, body extent -1.05,-1.1 1.05,1.1, height 1.1
"WSON8 TI DDR 3x3mm 12 pins pitch 0.5mm" [mm]
  rrect25% 0.62x0.25 smd mask+0.05: 1(-1.39,1.25) 2(-1.39,0.75) 3(-1.39,0.25) 4(-1.39,-0.25) 5(-1.39,-0.75) 6(-1.39,-1.25) 7(1.39,-1.25) 8(1.39,-0.75) 9(1.39,-0.25) 10(1.39,0.25) 11(1.39,0.75) 12(1.39,1.25)
  rect 1.3x2.5 smd paste-2539.97 mask+0.05: 13(0,0)
  silkscreen extent -1.7,1.73 -1.6,1.83, body extent -1.51,-1.5 1.51,1.5, height 0.8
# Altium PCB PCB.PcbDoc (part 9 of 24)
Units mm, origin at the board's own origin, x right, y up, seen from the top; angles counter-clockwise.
Board outline 100 x 160 mm, 10 copper layers (TOP_L1, L2, L3, L4, L5, L6, L7, L8, L9, BOTTOM_L10), stack 1.946 mm thick; 1358 components, 1149 nets, 6777 pads, 10914 vias.

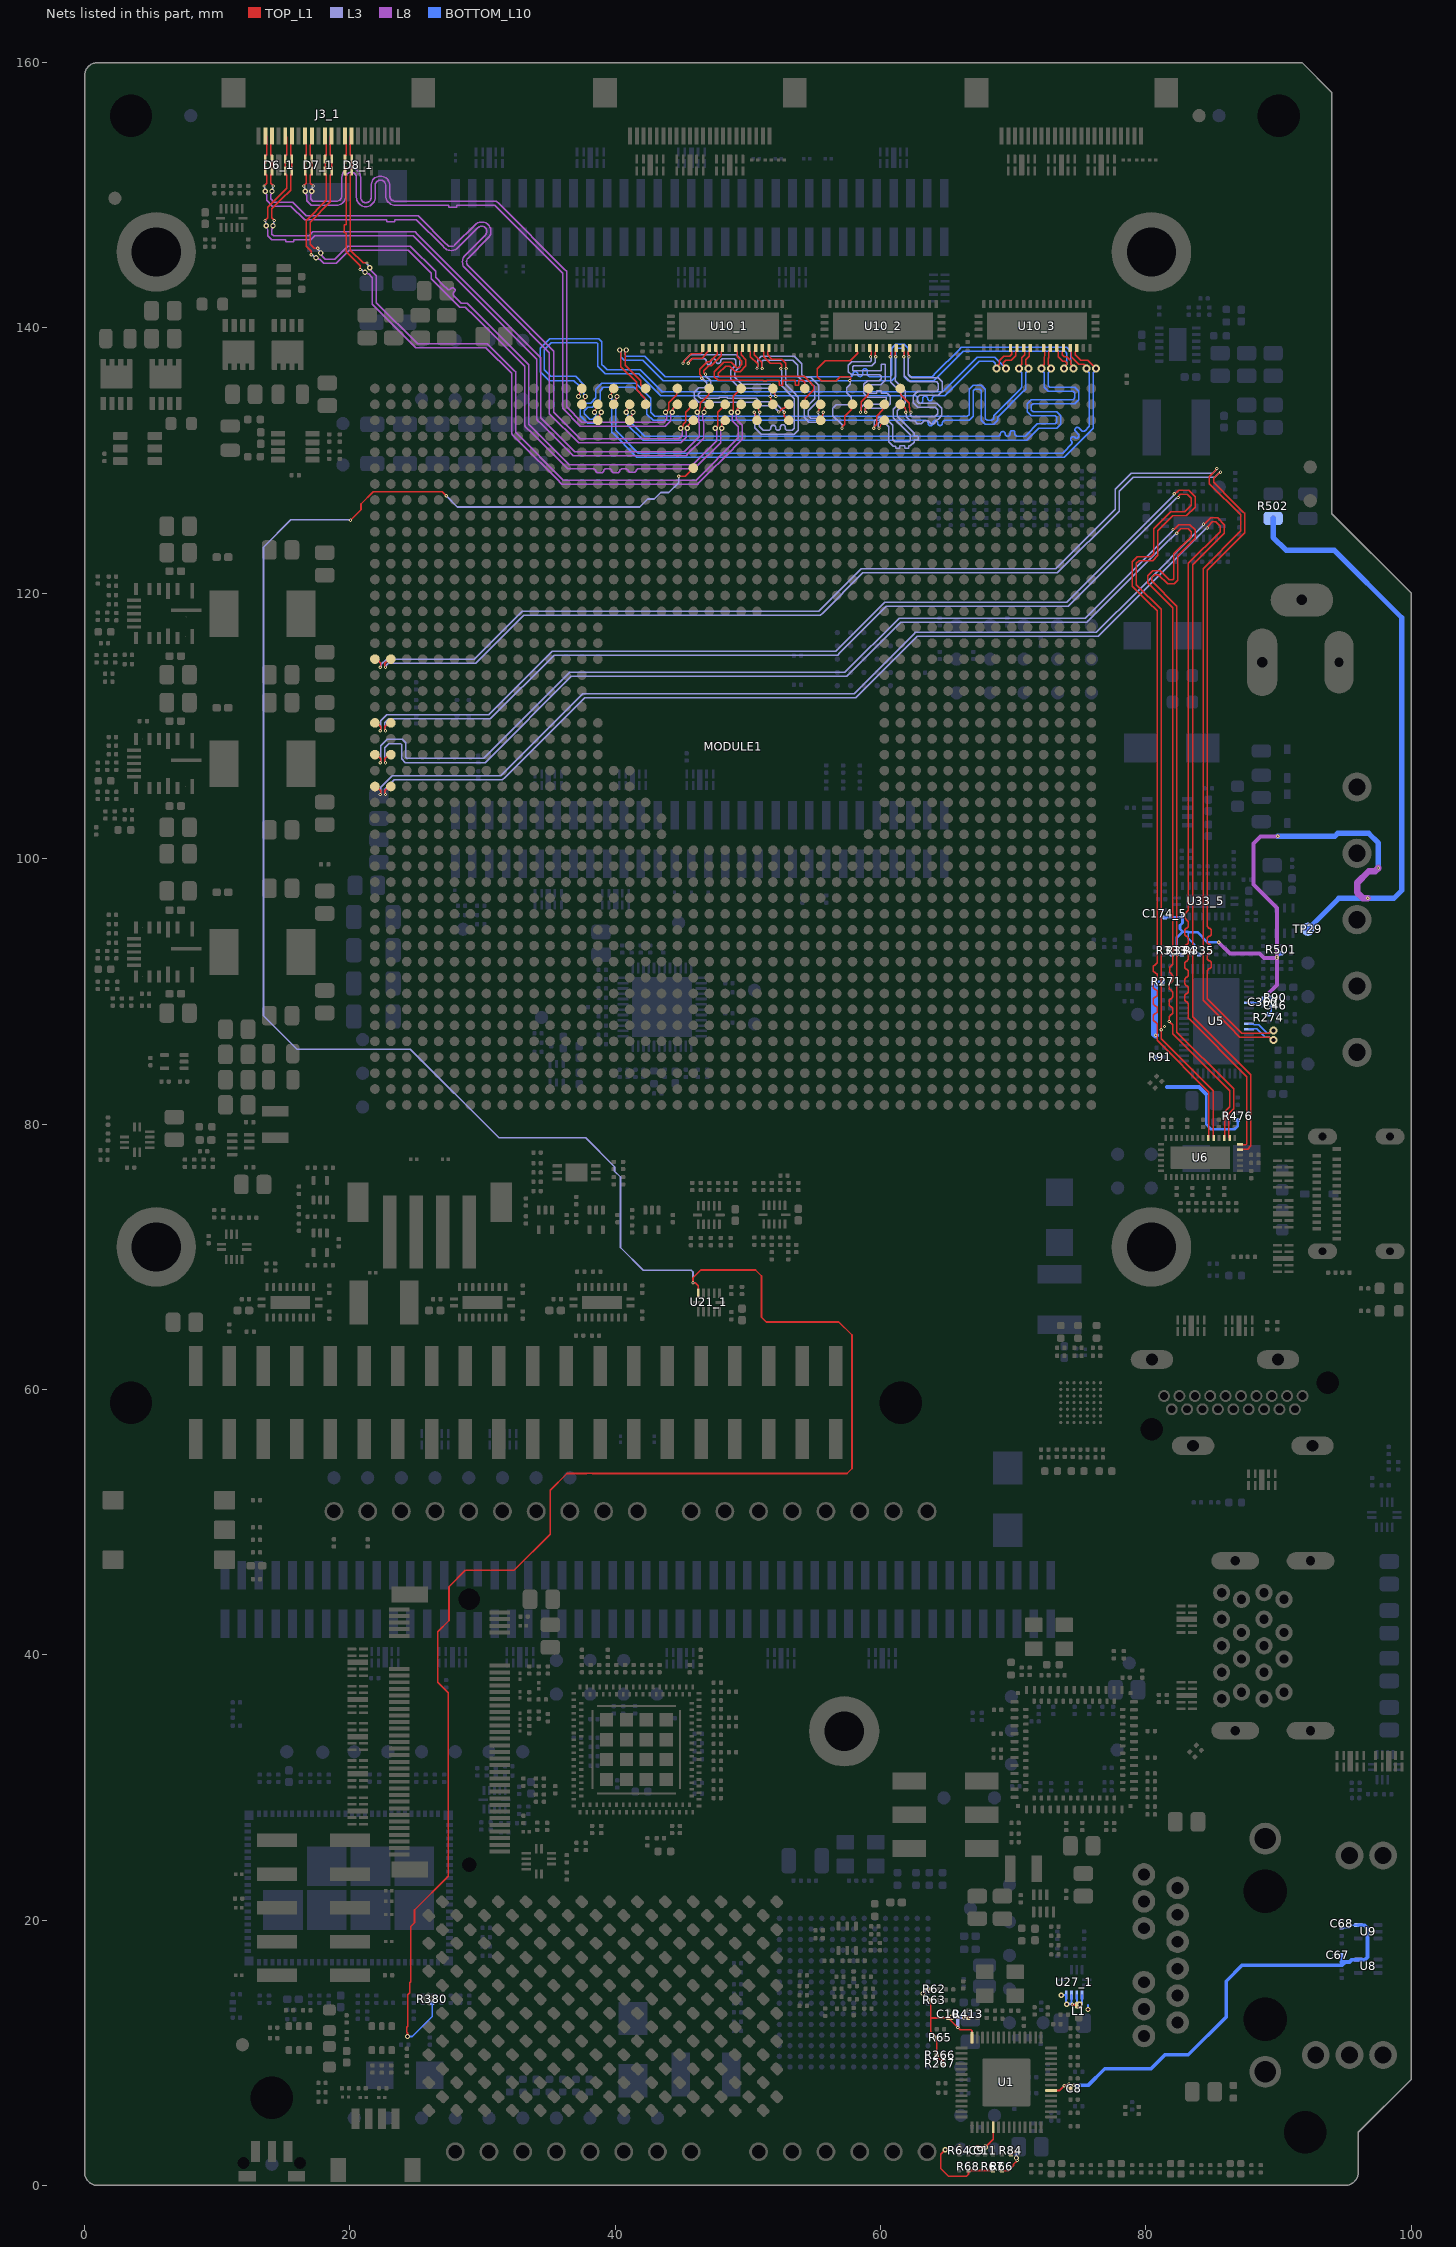
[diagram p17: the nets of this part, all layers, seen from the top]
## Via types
v1: diameter 0.25, hole 0.1, TOP_L1 to L2, tented both sides, 3439 vias
v2: diameter 0.25, hole 0.1, L2 to L3, tented both sides, 2256 vias
v3: diameter 0.25, hole 0.1, L9 to BOTTOM_L10, tented both sides, 1685 vias
v4: diameter 0.25, hole 0.1, L8 to L9, tented both sides, 1675 vias
v5: diameter 0.4, hole 0.2, L3 to L8, tented both sides, 1251 vias
v6: diameter 0.6, hole 0.3, TOP_L1 to BOTTOM_L10, tented both sides, 600 vias
v7: diameter 0.24, hole 0.1, TOP_L1 to L2, tented both sides, 8 vias

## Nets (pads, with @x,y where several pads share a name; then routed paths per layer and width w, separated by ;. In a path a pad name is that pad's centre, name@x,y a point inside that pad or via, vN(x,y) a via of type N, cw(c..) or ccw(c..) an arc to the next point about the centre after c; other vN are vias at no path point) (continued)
CSI0_L0_P: MODULE1.AL45 U10_2.5 | length 15
  TOP_L1 w0.109: v2(57.082,132.436) 57.109,132.463 57.109,132.548 57.288,132.726 57.288,133.333 57.772,133.817 57.772,134.126 MODULE1.AL45@57.882,134.236 ; v2(57.682,136.036) 57.709,136.063 57.709,136.15 57.73,136.17 57.73,136.273 57.666,136.337 56.943,136.337 56.637,136.031 55.509,136.031 55.234,136.306 55.234,136.927 55.831,137.524 57.694,137.524 58.261,138.091 58.261,138.182 58.253,138.19 58.253,138.421 U10_2.5@58.182,138.491
  L3 w0.104: v2(57.082,132.436) 57.099,132.453 57.099,132.685 56.401,133.383 56.401,133.945 56.671,134.215 57.638,134.215 57.73,134.307 57.755,134.332 57.766,134.343 57.766,134.791 57.452,135.105 57.452,135.487 57.722,135.757 57.722,135.893 57.71,135.905 57.71,136.008 v2(57.682,136.036)
  other v1: 57.082,132.436 57.682,136.036
CSI0_L1_N: MODULE1.AM45 U10_2.8 | length 14.9
  TOP_L1 w0.109: v1(58.882,133.636) 58.882,133.674 58.834,133.722 58.834,133.925 59.082,134.172 MODULE1.AM45@59.082,134.236 ; v2(59.632,137.836) 59.605,137.863 59.605,137.95 59.585,137.97 59.585,138.218 59.639,138.273 U10_2.8@59.674,138.273
  L3 w0.104: v1(58.882,133.636) 58.85,133.668 58.85,133.752 58.834,133.768 58.834,133.9 58.884,133.949 60.334,133.949 60.337,133.952 60.395,133.952 60.729,134.286 60.729,134.344 60.729,134.775 60.729,134.851 60.499,135.081 60.047,135.081 60.047,135.258 59.723,135.258 59.723,135.081 59.156,135.081 59.049,135.189 59.049,135.629 59.145,135.725 60.022,135.725 60.337,136.041 60.337,136.482 60.337,137.217 60.293,137.261 60.085,137.261 60.038,137.214 60.038,136.759 57.931,136.759 57.881,136.81 57.881,137.057 57.966,137.142 59.326,137.142 59.591,137.407 59.591,137.704 59.6,137.713 59.6,137.804 v2(59.632,137.836)
  other v1: 59.632,137.836
  other v2: 58.882,133.636
CSI0_L1_P: MODULE1.AM46 U10_2.7 | length 15
  TOP_L1 w0.109: v1(58.482,133.636) 58.509,133.663 58.509,133.75 58.53,133.77 58.53,134.418 59.082,134.971 MODULE1.AM46@59.082,135.436 ; U10_2.7@59.182,138.491 59.182,138.316 59.28,138.218 59.28,137.97 59.259,137.95 59.259,137.863 v1(59.232,137.836)
  L3 w0.104: v1(58.482,133.636) 58.514,133.668 58.514,133.752 58.53,133.768 58.53,134.026 58.757,134.254 60.266,134.254 60.425,134.413 60.425,134.725 60.376,134.773 59.033,134.773 58.744,135.062 58.744,135.756 59.018,136.03 59.895,136.03 60.032,136.167 60.032,136.356 59.934,136.454 57.805,136.454 57.576,136.684 57.576,137.183 57.84,137.447 59.2,137.447 59.287,137.533 59.287,137.737 59.232,137.791 v1(59.232,137.836)
  other v2: 58.482,133.636 59.232,137.836
CSI0_L2_N: MODULE1.AN44 U10_2.11 | length 14.9
  TOP_L1 w0.086: v1(59.882,132.436) 59.882,132.48 59.949,132.547 59.949,132.557 59.992,132.6 59.992,132.698 60.282,132.988 MODULE1.AN44@60.282,133.036
  TOP_L1 w0.109: v1(61.132,137.836) 61.105,137.863 61.105,137.95 61.085,137.97 61.085,138.218 61.139,138.273 U10_2.11@61.174,138.273
  L3 w0.104: v1(59.882,132.436) 59.85,132.468 59.85,132.552 59.834,132.568 59.834,132.827 59.933,132.926 60.246,132.926 60.62,132.552 60.62,131.438 60.96,131.098 61.134,131.098 61.134,130.917 61.429,130.917 61.429,131.107 61.814,131.107 61.814,130.931 62.109,130.931 62.109,131.107 62.249,131.107 62.529,131.388 62.529,131.528 62.845,131.528 62.845,131.823 62.529,131.823 62.529,132.069 61.711,132.887 61.252,133.346 61.252,133.749 61.674,134.171 ; v1(61.132,137.836) 61.1,137.804 61.1,137.72 61.085,137.704 61.085,136.018 61.625,135.478 61.853,135.25 61.853,134.35 61.674,134.171
  other v2: 59.882,132.436 61.132,137.836
CSI0_L2_P: MODULE1.AN45 U10_2.10 | length 15.1
  TOP_L1 w0.109: v1(59.482,132.436) 59.509,132.463 59.509,132.548 59.688,132.726 59.688,133.333 60.172,133.817 60.172,134.126 MODULE1.AN45@60.282,134.236 ; U10_2.10@60.682,138.491 60.682,138.316 60.78,138.218 60.78,137.97 60.759,137.95 60.759,137.863 v2(60.732,137.836)
  L3 w0.104: v1(59.482,132.436) 59.514,132.468 59.514,132.552 59.53,132.568 59.53,132.953 59.807,133.231 60.372,133.231 60.924,132.678 60.924,131.565 61.077,131.412 62.123,131.412 62.224,131.514 62.224,131.942 61.388,132.779 60.97,133.197 60.947,133.22 60.947,133.875 60.97,133.897 61.548,134.476 61.548,135.124 61.499,135.173 60.78,135.892 60.78,137.704 60.764,137.72 60.764,137.804 v2(60.732,137.836)
  other v1: 60.732,137.836
  other v2: 59.482,132.436
CSI0_L3_N: MODULE1.AP45 U10_2.13 | length 14.9
  TOP_L1 w0.109: MODULE1.AP45@61.482,134.236 61.576,134.236 61.858,133.954 61.858,133.895 61.904,133.848 61.904,133.658 v2(61.882,133.636) ; v2(62.132,137.836) 62.105,137.863 62.105,137.95 62.085,137.97 62.085,138.218 62.139,138.273 U10_2.13@62.174,138.273
  L3 w0.104: v2(61.882,133.636) 61.914,133.604 61.914,133.52 61.93,133.504 61.93,133.288 62.229,132.989 62.564,132.989 62.761,132.791 63.072,132.791 63.27,132.989 63.605,132.989 63.798,132.796 64.001,132.796 64.194,132.989 64.373,133.167 64.618,133.413 64.618,133.945 64.422,134.141 ; v2(62.132,137.836) 62.1,137.804 62.1,137.72 62.085,137.704 62.085,136.513 62.357,136.241 64.354,136.241 64.533,136.062 64.661,135.934 64.661,135.238 64.561,135.138 64.359,134.936 62.932,134.936 62.775,134.779 62.775,134.472 62.926,134.322 64.241,134.322 64.422,134.141
  other v1: 61.882,133.636 62.132,137.836
CSI0_L3_P: MODULE1.AP46 U10_2.12 | length 15
  TOP_L1 w0.109: MODULE1.AP46@61.482,135.436 61.526,135.393 61.526,134.971 62.162,134.334 62.162,134.021 62.209,133.974 62.209,133.747 62.282,133.674 v1(62.282,133.636) ; U10_2.12@61.682,138.491 61.682,138.316 61.78,138.218 61.78,137.97 61.759,137.95 61.759,137.863 v1(61.732,137.836)
  L3 w0.104: v1(61.732,137.836) 61.764,137.804 61.764,137.72 61.78,137.704 61.78,136.387 62.23,135.936 64.228,135.936 64.356,135.807 64.356,135.365 64.256,135.264 64.233,135.241 62.806,135.241 62.47,134.905 62.47,134.346 62.799,134.017 64.115,134.017 64.118,134.014 64.314,133.818 64.314,133.539 64.068,133.294 62.355,133.294 62.234,133.414 62.234,133.504 62.25,133.52 62.25,133.604 v1(62.282,133.636)
  other v2: 62.282,133.636 61.732,137.836
CSI1_CK_N: MODULE1.AE44 U10_1.15 | length 13.1
  TOP_L1 w0.109: v1(50.482,133.636) 50.534,133.48 MODULE1.AE44@50.682,133.036 ; U10_1.15@51.582,138.491 51.582,138.316 51.485,138.218 51.485,137.963 51.807,137.641 52.545,137.641 52.834,137.351 52.834,137.07 52.855,137.05 52.855,136.963 v2(52.882,136.936)
  L3 w0.104: v1(50.482,133.636) 50.51,133.608 50.51,133.505 50.53,133.485 50.53,132.469 50.708,132.291 51.018,131.981 53.487,131.981 53.808,132.302 53.808,134.776 53.719,134.866 53.481,135.103 52.834,135.75 52.834,136.785 52.854,136.805 52.854,136.908 v2(52.882,136.936)
  other v1: 52.882,136.936
  other v2: 50.482,133.636
CSI1_CK_P: MODULE1.AE45 U10_1.14 | length 13
  TOP_L1 w0.109: MODULE1.AE45@50.682,134.236 50.83,133.792 v1(50.882,133.636) ; U10_1.14@51.082,138.491 51.082,138.316 51.18,138.218 51.18,137.837 51.68,137.336 52.419,137.336 52.53,137.225 52.53,137.07 52.509,137.05 52.509,136.963 v2(52.482,136.936)
  L3 w0.104: v1(50.882,133.636) 50.854,133.608 50.854,133.505 50.834,133.485 50.834,132.596 51.144,132.286 51.213,132.286 51.548,132.286 ccw(c51.548,132.465) 51.727,132.465 51.727,132.478 cw(c51.907,132.478) 52.086,132.478 52.086,132.465 ccw(c52.265,132.465) 52.444,132.465 52.444,132.522 cw(c52.623,132.522) 52.802,132.522 52.802,132.465 ccw(c52.981,132.465) 52.981,132.286 53.361,132.286 53.391,132.316 53.503,132.428 53.503,134.65 52.53,135.624 52.53,136.785 52.51,136.805 52.51,136.908 v2(52.482,136.936)
  other v1: 52.482,136.936
  other v2: 50.882,133.636
CSI1_L0_N: MODULE1.AF45 U10_1.6 | length 13.1
  TOP_L1 w0.109: v1(45.508,137.328) 45.508,137.366 45.578,137.436 45.578,137.467 45.843,137.731 46.542,137.731 46.817,138.006 46.817,138.05 47.082,138.316 U10_1.6@47.082,138.491 ; v1(51.682,134.836) 51.734,134.68 MODULE1.AF45@51.882,134.236
  L3 w0.104: v1(45.508,137.328) 45.508,137.367 45.581,137.44 45.581,137.473 45.781,137.673 46.278,137.673 46.688,137.673 cw(c46.688,137.494) 46.867,137.494 46.867,137.418 ccw(c47.046,137.418) 47.225,137.418 47.225,137.494 cw(c47.404,137.494) 47.583,137.494 ccw(c47.762,137.494) 47.942,137.494 cw(c48.121,137.494) 48.121,137.673 48.661,137.673 48.977,137.673 49.068,137.581 49.068,137.203 48.69,136.825 48.69,136.141 49.388,135.443 51.545,135.443 51.73,135.258 51.73,134.987 51.71,134.967 51.71,134.864 v1(51.682,134.836)
  other v2: 51.682,134.836 45.508,137.328
CSI1_L0_P: MODULE1.AF46 U10_1.5 | length 13.1
  TOP_L1 w0.109: v1(45.108,137.328) 45.108,137.366 45.203,137.461 45.203,137.522 45.717,138.036 46.416,138.036 46.512,138.132 46.512,138.42 U10_1.5@46.582,138.491 ; MODULE1.AF46@51.882,135.436 52.03,134.992 v2(52.082,134.836)
  L3 w0.104: v1(45.108,137.328) 45.108,137.367 45.203,137.462 45.203,137.526 45.655,137.978 49.103,137.978 49.373,137.708 49.373,137.077 48.994,136.699 48.994,136.267 49.514,135.747 51.671,135.747 52.034,135.384 52.034,134.987 52.054,134.967 52.054,134.864 v2(52.082,134.836)
  other v1: 52.082,134.836
  other v2: 45.108,137.328
CSI1_L1_N: MODULE1.AG44 U10_1.8 | length 13.1
  TOP_L1 w0.109: v2(46.798,136.502) 46.792,136.502 46.658,136.636 46.658,136.757 47.048,137.148 47.232,137.148 47.985,137.901 47.985,138.218 48.082,138.316 U10_1.8@48.082,138.491 ; v1(52.74,133.635) 52.74,133.357 MODULE1.AG44@53.082,133.015
  L3 w0.104: v2(46.798,136.502) 46.826,136.474 46.826,136.375 47.188,136.012 47.188,135.545 46.822,135.179 46.429,135.179 46.266,135.015 46.266,134.854 46.43,134.689 47.696,134.689 47.835,134.689 47.835,134.761 48.447,134.761 48.447,134.689 49.112,134.689 50.611,134.689 50.849,134.451 51.975,134.451 52.667,133.759 52.667,133.748 52.74,133.675 v1(52.74,133.635)
  other v1: 46.798,136.502
  other v2: 52.74,133.635
CSI1_L1_P: MODULE1.AG45 U10_1.7 | length 13.1
  TOP_L1 w0.109: v2(46.515,136.219) 46.488,136.246 46.488,136.375 46.353,136.51 46.353,136.884 46.922,137.453 47.105,137.453 47.68,138.027 47.68,138.218 47.582,138.316 U10_1.7@47.582,138.491 ; v2(52.325,133.658) 52.607,133.94 52.72,133.94 52.992,134.212 MODULE1.AG45@52.992,134.283
  L3 w0.104: v2(46.515,136.219) 46.551,136.219 46.883,135.886 46.883,135.672 46.696,135.484 46.303,135.484 45.961,135.142 45.961,134.728 46.304,134.384 50.484,134.384 50.723,134.146 51.849,134.146 52.325,133.67 v2(52.325,133.658)
  other v1: 52.325,133.658 46.515,136.219
CSI1_L2_N: MODULE1.AH45 U10_1.11 | length 13.5
  TOP_L1 w0.109: U10_1.11@49.582,138.491 49.582,138.316 49.485,138.218 49.485,137.963 49.85,137.597 49.85,137.139 49.42,136.709 49.032,136.709 48.853,136.888 48.631,137.11 48.307,137.11 47.775,136.578 47.775,136.442 47.871,136.346 54.247,136.346 54.605,135.988 54.605,135.98 54.962,135.622 54.962,135.338 54.326,134.701 54.326,134.279 MODULE1.AH45@54.282,134.236
CSI1_L2_P: MODULE1.AH46 U10_1.10 | length 13.5
  TOP_L1 w0.109: U10_1.10@49.082,138.491 49.082,138.316 49.18,138.218 49.18,137.837 49.546,137.471 49.546,137.266 49.294,137.014 49.158,137.014 48.757,137.415 48.181,137.415 47.47,136.704 47.47,136.316 47.745,136.041 51.161,136.041 51.161,136.027 51.432,136.027 51.432,136.041 52.363,136.041 52.363,135.673 52.611,135.673 52.611,136.041 53.561,136.041 53.561,135.673 53.832,135.673 53.832,136.041 54.121,136.041 54.261,135.901 54.261,135.551 54.376,135.436 MODULE1.AH46@54.282,135.436
CSI1_L3_N: MODULE1.AJ44 U10_1.13 | length 13.1
  TOP_L1 w0.109: U10_1.13@50.582,138.491 50.582,138.316 50.485,138.218 50.485,137.962 51.034,137.412 51.034,137.07 51.055,137.05 51.055,136.963 v2(51.082,136.936) ; MODULE1.AJ44@55.482,133.036 55.63,133.48 v2(55.682,133.636)
  L3 w0.104: v2(51.082,136.936) 51.054,136.964 51.054,137.067 51.034,137.087 51.034,137.449 51.144,137.559 53.377,137.559 53.758,137.178 53.758,136.356 54.143,135.971 54.614,135.971 54.784,135.801 55.028,135.557 55.028,134.659 54.235,133.866 54.235,133.265 54.416,133.084 54.595,132.906 55.364,132.906 55.634,133.176 55.634,133.485 55.654,133.505 55.654,133.608 v2(55.682,133.636)
  other v1: 55.682,133.636 51.082,136.936
CSI1_L3_P: MODULE1.AJ45 U10_1.12 | length 13.1
  TOP_L1 w0.109: U10_1.12@50.082,138.491 50.082,138.316 50.18,138.218 50.18,137.836 50.73,137.286 50.73,137.07 50.709,137.05 50.709,136.963 v2(50.682,136.936) ; v1(55.282,133.636) 55.334,133.792 MODULE1.AJ45@55.482,134.236
  L3 w0.104: v2(50.682,136.936) 50.71,136.964 50.71,137.067 50.73,137.087 50.73,137.575 51.018,137.864 53.503,137.864 54.062,137.304 54.062,136.483 54.269,136.276 54.74,136.276 55.333,135.683 55.333,134.533 54.54,133.74 54.54,133.392 54.721,133.211 55.238,133.211 55.33,133.302 55.33,133.485 55.31,133.505 55.31,133.608 v1(55.282,133.636)
  other v1: 50.682,136.936
  other v2: 55.282,133.636
CSI2_CK_N: D7_1.1 D7_1.10 J3_1.8 MODULE1.Y45 | length 54.6
  TOP_L1 w0.109: v2(16.524,150.7) 16.722,150.898 16.722,151.506 16.624,151.604 16.624,152.954 16.722,153.052 16.722,153.816 16.72,153.818 16.72,154.38 J3_1.8@16.624,154.475 ; v5(44.282,133.636) 44.282,133.674 44.336,133.728 44.336,133.925 44.647,134.236 MODULE1.Y45@44.682,134.236
  L3 w0.104: v2(16.524,150.7) 16.524,150.661 16.585,150.6 16.585,150.339 v5(16.624,150.3)
  L8 w0.104: v5(16.624,150.3) 16.681,150.243 16.681,150.071 16.738,150.014 16.738,149.598 17.078,149.257 18.791,149.257 18.995,149.257 ccw(c18.995,149.96) 19.698,149.96 19.698,151.343 cw(c20.096,151.343) 20.096,151.741 cw(c20.096,151.343) 20.494,151.343 20.494,149.847 ccw(c21.197,149.847) 21.197,149.144 ccw(c21.197,149.847) 21.9,149.847 21.9,150.738 cw(c22.298,150.738) 22.298,151.136 cw(c22.298,150.738) 22.696,150.738 22.696,149.96 ccw(c23.399,149.96) 23.399,149.257 26.391,149.257 26.772,149.257 27.436,149.257 27.436,149.1 28.048,149.1 28.048,149.257 29.2,149.257 30.905,149.257 36.028,144.134 36.028,133.932 37.363,132.597 43.775,132.597 44.184,133.007 44.184,133.458 44.282,133.556 v5(44.282,133.636)
  other v1: 44.282,133.636 16.524,150.7
  other v2: 44.282,133.636
CSI2_CK_P: D7_1.2 D7_1.9 J3_1.9 MODULE1.Y46 | length 54.7
  TOP_L1 w0.109: J3_1.9@17.124,154.475 17.029,154.38 17.029,153.818 17.027,153.816 17.027,153.052 17.124,152.954 17.124,151.604 17.027,151.506 17.027,150.898 v1(17.224,150.7) ; v5(43.782,133.636) 44.027,133.881 44.027,134.359 44.639,134.971 44.639,135.393 MODULE1.Y46@44.682,135.436
  L3 w0.104: v5(17.124,150.3) 17.164,150.339 17.164,150.6 17.224,150.661 v1(17.224,150.7)
  L8 w0.104: v5(17.124,150.3) 17.068,150.243 17.068,150.055 17.042,150.03 17.042,149.724 17.205,149.562 18.791,149.562 18.995,149.562 ccw(c18.995,149.96) 19.393,149.96 19.393,151.343 cw(c20.096,151.343) 20.096,152.046 cw(c20.096,151.343) 20.799,151.343 20.799,149.847 ccw(c21.197,149.847) 21.197,149.449 ccw(c21.197,149.847) 21.595,149.847 21.595,150.738 cw(c22.298,150.738) 22.298,151.441 cw(c22.298,150.738) 23.001,150.738 23.001,149.96 ccw(c23.399,149.96) 23.399,149.562 26.391,149.562 31.031,149.562 31.21,149.383 36.155,144.439 36.333,144.26 36.333,134.058 37.489,132.902 43.648,132.902 43.88,133.134 43.88,133.458 43.782,133.556 v5(43.782,133.636)
  other v1: 43.782,133.636
  other v2: 43.782,133.636 17.224,150.7
CSI2_L0_N: D6_1.1 D6_1.10 J3_1.2 MODULE1.AA44 | length 54.6
  TOP_L1 w0.109: v1(13.524,150.7) 13.722,150.898 13.722,151.506 13.624,151.604 D6_1.1@13.624,151.842 D6_1.10@13.624,152.717 13.624,152.954 13.722,153.052 13.722,153.661 13.722,153.768 13.72,153.77 13.72,154.38 J3_1.2@13.624,154.475 ; v1(45.432,132.436) 45.443,132.447 45.443,132.615 45.864,133.036 MODULE1.AA44@45.882,133.036
  L3 w0.104: v1(13.524,150.7) 13.524,150.661 13.585,150.6 13.585,150.339 v5(13.624,150.3)
  L8 w0.104: v5(13.624,150.3) 13.681,150.243 13.681,150.071 13.722,150.03 13.722,149.611 14.149,149.184 15.556,149.184 16.578,148.162 22.104,148.162 22.768,148.162 22.768,147.993 23.38,147.993 23.38,148.162 23.87,148.162 25.005,148.162 26.983,146.183 27.127,146.039 ccw(c27.625,146.536) 28.122,146.039 29.646,147.563 cw(c29.928,147.282) 30.209,147.563 cw(c29.928,147.282) 30.209,147 28.686,145.477 ccw(c29.182,144.979) 28.686,144.481 32.028,141.139 35.038,138.128 35.038,133.522 37.23,131.331 44.711,131.331 44.918,131.331 45.334,131.747 45.334,132.258 45.432,132.356 v1(45.432,132.436)
  other v2: 45.432,132.436 13.524,150.7
  other v5: 45.432,132.436
CSI2_L0_P: D6_1.2 D6_1.9 J3_1.3 MODULE1.AA45 | length 54.7
  TOP_L1 w0.109: J3_1.3@14.124,154.475 14.029,154.38 14.029,153.818 14.027,153.816 14.027,153.673 14.027,153.052 14.124,152.954 D6_1.9@14.124,152.717 D6_1.2@14.124,151.842 14.124,151.604 14.027,151.506 14.027,150.898 v1(14.224,150.7) ; v1(44.932,132.436) 45.138,132.642 45.138,132.742 45.309,132.912 45.309,133.663 MODULE1.AA45@45.882,134.236
  L3 w0.104: v5(14.124,150.3) 14.164,150.339 14.164,150.6 14.224,150.661 v1(14.224,150.7)
  L8 w0.104: v5(14.124,150.3) 14.068,150.243 14.068,150.071 14.027,150.03 14.027,149.738 14.275,149.489 15.682,149.489 16.705,148.466 25.131,148.466 25.31,148.288 27.199,146.399 27.343,146.254 ccw(c27.625,146.536) 27.906,146.254 29.431,147.779 cw(c29.928,147.282) 30.425,147.779 cw(c29.928,147.282) 30.425,146.785 28.9,145.26 ccw(c29.182,144.979) 28.9,144.697 32.243,141.354 35.165,138.433 35.343,138.254 35.343,133.649 37.356,131.636 44.792,131.636 45.03,131.874 45.03,132.258 44.932,132.356 v1(44.932,132.436)
  other v2: 44.932,132.436 14.224,150.7
  other v5: 44.932,132.436
CSI2_L1_N: D6_1.4 D6_1.7 J3_1.5 MODULE1.AB45 | length 54.7
  TOP_L1 w0.109: v1(13.602,148.102) 13.8,148.3 13.8,149.1 15.222,150.522 15.222,151.506 15.124,151.604 D6_1.4@15.124,151.842 D6_1.7@15.124,152.717 15.124,152.954 15.222,153.052 15.222,153.816 15.22,153.818 15.22,154.38 J3_1.5@15.124,154.475 ; v2(46.682,133.636) 46.66,133.658 46.66,133.848 46.706,133.895 46.706,133.954 46.988,134.236 MODULE1.AB45@47.082,134.236
  L3 w0.104: v1(13.602,148.102) 13.602,148.062 13.663,148.002 13.663,147.741 v5(13.702,147.702)
  L8 w0.104: v5(13.702,147.702) 13.759,147.645 13.759,147.473 13.816,147.416 13.816,146.934 14.116,146.633 14.502,146.633 15.167,146.633 15.167,146.503 15.779,146.503 15.779,146.633 16.243,146.633 17.044,146.633 17.34,146.93 24.782,146.93 34.077,137.634 34.077,133.11 34.167,133.021 34.42,132.767 36.647,130.54 36.826,130.361 45.338,130.361 45.517,130.54 46.651,131.674 46.651,132.967 46.584,133.034 46.584,133.458 46.682,133.556 v2(46.682,133.636)
  other v1: 46.682,133.636
  other v2: 13.602,148.102
  other v5: 46.682,133.636
CSI2_L1_P: D6_1.5 D6_1.6 J3_1.6 MODULE1.AB46 | length 54.7
  TOP_L1 w0.109: v1(14.302,148.102) 14.105,148.3 14.105,148.974 14.816,149.684 15.527,150.396 15.527,151.506 15.624,151.604 15.624,152.954 15.527,153.052 15.527,153.816 15.529,153.818 15.529,154.38 J3_1.6@15.624,154.475 ; v1(46.182,133.636) 46.355,133.809 46.355,133.974 46.402,134.021 46.402,134.334 47.039,134.971 47.039,135.393 MODULE1.AB46@47.082,135.436
  L3 w0.104: v5(14.202,147.702) 14.242,147.741 14.242,148.002 14.302,148.062 v1(14.302,148.102)
  L8 w0.104: v5(14.202,147.702) 14.146,147.645 14.146,147.457 14.12,147.432 14.12,147.06 14.242,146.938 16.917,146.938 17.214,147.235 24.908,147.235 25.087,147.056 34.204,137.939 34.382,137.761 34.382,133.236 36.952,130.666 45.212,130.666 46.346,131.8 46.346,132.841 46.28,132.907 46.28,133.458 46.182,133.556 v1(46.182,133.636)
  other v2: 46.182,133.636 14.302,148.102
  other v5: 46.182,133.636
CSI2_L2_N: D7_1.4 D7_1.7 J3_1.11 MODULE1.AC44 | length 54.7
  TOP_L1 w0.109: v1(17.085,145.504) 17.084,145.784 16.695,146.174 16.695,148.095 18.222,149.622 18.222,151.506 18.124,151.604 D7_1.4@18.124,151.842 D7_1.7@18.124,152.717 18.124,152.954 18.222,153.052 18.222,153.816 18.22,153.818 18.22,154.38 J3_1.11@18.124,154.475 ; v1(48.032,132.436) 48.01,132.458 48.01,132.725 48.282,132.997 MODULE1.AC44@48.282,133.036
  L3 w0.104: v1(17.085,145.504) 17.113,145.477 17.199,145.477 17.383,145.292 v5(17.439,145.292)
  L8 w0.104: v5(17.439,145.292) 17.519,145.292 17.64,145.171 17.721,145.171 18.015,144.876 18.976,144.876 19.964,145.864 24.41,145.864 26.145,144.129 26.145,143.695 28.266,141.575 28.7,141.575 29.437,140.837 33.177,137.097 33.177,132.61 33.267,132.521 33.7,132.087 36.227,129.56 36.405,129.382 37.729,129.382 38.393,129.382 38.516,129.259 38.516,129.196 38.638,129.074 39.005,129.074 39.128,129.196 39.128,129.259 39.25,129.382 39.618,129.382 39.74,129.259 39.74,129.196 39.862,129.074 40.23,129.074 40.352,129.196 40.352,129.259 40.475,129.382 40.842,129.382 40.964,129.259 40.964,129.235 41.087,129.112 41.454,129.112 41.576,129.235 41.576,129.259 41.699,129.382 44.336,129.382 45.959,129.382 46.137,129.56 47.745,131.168 47.934,131.357 47.934,132.258 48.032,132.356 v1(48.032,132.436)
  other v2: 48.032,132.436 17.085,145.504
  other v5: 48.032,132.436
CSI2_L2_P: D7_1.5 D7_1.6 J3_1.12 MODULE1.AC45 | length 54.6
  TOP_L1 w0.109: v1(17.58,145.999) 17.3,146 17,146.3 17,147.969 18.527,149.496 18.527,151.506 18.624,151.604 D7_1.5@18.624,151.842 D7_1.6@18.624,152.717 18.624,152.954 18.527,153.052 18.527,153.816 18.529,153.818 18.529,154.38 J3_1.12@18.624,154.475 ; v1(47.532,132.436) 47.705,132.609 47.705,133.659 MODULE1.AC45@48.282,134.236
  L3 w0.104: v1(17.58,145.999) 17.608,145.972 17.608,145.886 17.792,145.702 v5(17.792,145.646)
  L8 w0.104: v5(17.792,145.646) 17.792,145.566 17.925,145.433 17.925,145.397 18.141,145.181 18.85,145.181 19.838,146.169 24.536,146.169 26.45,144.255 26.45,143.822 27.002,143.27 27.038,143.233 27.332,142.94 ccw(c27.459,143.066) 27.585,142.94 27.616,142.97 cw(c27.743,142.844) 27.869,142.97 cw(c27.743,142.844) 27.869,142.717 27.839,142.686 ccw(c27.965,142.56) 27.839,142.433 28.092,142.18 28.129,142.143 28.392,141.879 28.826,141.879 33.304,137.402 33.482,137.223 33.482,132.736 36.531,129.687 45.833,129.687 47.44,131.294 47.63,131.484 47.63,132.258 47.532,132.356 v1(47.532,132.436)
  other v2: 47.532,132.436 17.58,145.999
  other v5: 47.532,132.436
CSI2_L3_N: D8_1.1 D8_1.10 J3_1.14 MODULE1.AD45 | length 54.7
  TOP_L1 w0.109: J3_1.14@19.624,154.475 19.72,154.38 19.72,153.818 19.722,153.816 19.722,153.052 19.624,152.954 19.624,151.604 19.722,151.506 19.722,148.466 19.722,147.794 19.564,147.794 19.564,147.177 19.722,147.177 19.722,146.358 19.722,145.747 20.784,144.684 v1(20.785,144.404) ; v2(49.232,133.636) 49.21,133.658 49.21,133.925 49.482,134.197 MODULE1.AD45@49.482,134.236
  L3 w0.104: v1(20.785,144.404) 20.813,144.377 20.899,144.377 21.083,144.192 v5(21.139,144.192)
  L8 w0.104: v5(21.139,144.192) 21.219,144.192 21.34,144.071 21.421,144.071 21.695,143.796 21.695,141.79 24.974,138.511 27.1,138.511 30.237,138.511 32.177,136.57 32.177,132.01 32.267,131.921 32.863,131.324 35.686,128.501 35.867,128.321 35.956,128.231 46.213,128.231 46.302,128.321 46.483,128.501 48.856,130.874 48.945,130.964 49.587,131.605 49.587,132.662 49.134,133.115 49.134,133.458 49.232,133.556 v2(49.232,133.636)
  other v1: 49.232,133.636
  other v2: 20.785,144.404
  other v5: 49.232,133.636
CSI2_L3_P: D8_1.2 D8_1.9 J3_1.15 MODULE1.AD46 | length 54.7
  TOP_L1 w0.109: J3_1.15@20.124,154.475 20.029,154.38 20.029,153.818 20.027,153.816 20.027,153.052 20.124,152.954 D8_1.9@20.124,152.717 D8_1.2@20.124,151.842 20.124,151.604 20.027,151.506 20.027,145.873 21,144.9 v2(21.28,144.899) ; v5(48.732,133.636) 48.905,133.809 48.905,134.859 MODULE1.AD46@49.482,135.436
  L3 w0.104: v2(21.28,144.899) 21.308,144.872 21.308,144.786 21.492,144.602 v5(21.492,144.546)
  L8 w0.104: v5(21.492,144.546) 21.492,144.466 21.625,144.333 21.625,144.297 22,143.922 22,141.916 25.1,138.816 27.1,138.816 30.363,138.816 32.393,136.786 32.482,136.697 32.482,132.136 36.082,128.536 46.086,128.536 49.282,131.732 49.282,132.536 48.83,132.988 48.83,133.458 48.732,133.556 v5(48.732,133.636)
  other v1: 48.732,133.636 21.28,144.899
  other v2: 48.732,133.636
CTS_1V8: MODULE1.AA41 R380.1 U21_1.5 | length 219.2
  TOP_L1 w0.127: v1(20.045,125.502) 20.83,126.287 20.83,126.731 21.755,127.657 26.948,127.657 v1(27.258,127.347) ; v3(24.335,11.224) 24.335,11.51 24.277,11.569 24.277,11.914 24.347,11.984 24.347,14.375 24.506,14.534 24.506,15.264 24.59,15.348 24.59,19.52 24.864,19.794 24.864,20.759 27.4,23.295 27.4,37.126 26.61,37.916 26.61,41.724 27.462,42.576 27.462,45.126 28.698,46.362 32.369,46.362 35.09,49.083 35.09,52.391 36.354,53.656 37.842,53.656 37.863,53.677 38.247,53.677 38.269,53.656 57.459,53.656 57.841,54.037 57.841,64.092 56.854,65.079 51.382,65.079 51.014,65.447 51.014,68.544 50.564,68.994 46.432,68.994 45.851,68.413 v2(45.851,68.03) 45.855,68.025 46.039,68.025 46.25,67.814 U21_1.5@46.25,67.25 ; v2(44.778,128.822) 45.268,128.822 MODULE1.AA41@45.882,129.436
  L3 w0.127: v1(20.045,125.502) 20.022,125.525 19.935,125.525 19.923,125.537 15.541,125.537 13.481,123.477 13.481,88.164 16.008,85.638 24.558,85.638 31.237,78.958 37.761,78.958 39.942,76.778 39.942,76.451 40.393,76 40.393,70.693 42.112,68.974 45.719,68.974 45.851,68.841 v2(45.851,68.03) ; v1(27.258,127.347) 28.096,126.508 41.855,126.508 42.457,127.111 42.942,127.111 43.429,127.598 44.041,127.598 44.778,128.335 v2(44.778,128.822)
  BOTTOM_L10 w0.127: v3(24.335,11.224) 24.692,11.224 26.2,12.732 R380.1@26.2,13.76
  other v1: 24.335,11.224 45.851,68.03 44.778,128.822
  other v2: 24.335,11.224 20.045,125.502 27.258,127.347
  other v4: 24.335,11.224
  other v5: 24.335,11.224
CYPD_VDDIO: C46.2 C174_5.2 C360.2 R90.1 R91.1 R271.2 R274.2 R333.1 R334.1 R335.1 R476.2 R501.1 R502.2 TP29.X U5.31 U33_5.19 | length 102.8
  L8 w0.3: v4(85.483,93.688) 86.316,92.855 88.545,92.855 88.898,92.502 v4(89.867,92.502) ; v3(89.102,89.723) 89.867,90.488 v4(89.867,92.502) ; v4(89.931,101.69) 89.895,101.654 88.632,101.654 88.105,101.127 88.105,98.036 89.867,96.274 v4(89.867,92.502)
  L8 w0.5: v4(96.702,97.019) 96.351,97.019 95.911,97.458 95.911,98.172 96.789,99.05 97.261,99.05 v4(97.511,99.3)
  BOTTOM_L10 w0.1: R333.1@81.962,92.772 v4(82.053,92.772) 82.071,92.79 82.099,92.762 v3(82.373,92.762) 82.657,92.762 82.685,92.79 R334.1@82.703,92.772 ; 83.173,94.462 83.173,94.013 83.673,93.512 83.673,93.102 R335.1@84.003,92.772
  BOTTOM_L10 w0.127: U5.31@87.753,89.147 87.756,89.15 88.528,89.15 v3(89.102,89.723) 89.171,89.723 R90.1@89.447,89.447 ; R274.2@89.253,88.272 89.451,88.471 C46.2@89.451,88.823 ; C46.2@89.447,88.853 R90.1@89.447,89.441 ; C46.2@89.453,88.823 89.453,88.847 C46.2@89.453,88.853
  BOTTOM_L10 w0.15: v3(89.867,92.602) 89.886,92.621 89.942,92.621 90.188,92.867 R501.1@90.203,92.867
  BOTTOM_L10 w0.2: 80.644,90.632 80.723,90.712 R271.2@81.274,90.712 ; C174_5.2@81.426,95.57 U33_5.19@82.696,95.57 ; v3(82.373,92.762) 82.377,92.766 82.329,92.814 82.329,94.055 82.751,94.477 82.78,94.477 ; U33_5.19@82.753,95.645 82.753,95.161 82.559,94.967 82.559,94.698 82.78,94.477 ; 84.533,82.251 84.533,79.984 84.914,79.604 86.685,79.604 86.903,79.822 R476.2@86.903,80.297 ; v4(85.483,93.688) 84.642,93.688 83.868,94.462 83.173,94.462 83.157,94.477 82.78,94.477
  BOTTOM_L10 w0.3: 81.581,82.779 84.006,82.779 84.533,82.251
  BOTTOM_L10 w0.4: R502.2@89.58,125.65 89.58,124.22 90.55,123.25 94.18,123.25 99.274,118.156 99.274,97.614 98.679,97.019 v4(96.702,97.019) 94.539,97.019 TP29.X@92.2,94.68 ; v4(89.931,101.69) 94.23,101.69 94.445,101.904 96.788,101.904 97.511,101.181 v4(97.511,99.3)
  BOTTOM_L10 w0.5: 80.644,90.632 80.644,86.77 v4(80.731,86.683)
  other v3: 80.731,86.683 81.144,87.097 81.396,87.348 81.758,87.727 82.053,92.772 85.483,93.688 96.702,97.019 97.511,99.3 89.931,101.69
  other v4: 81.144,87.097 81.396,87.348 81.758,87.727 89.102,89.723 82.373,92.762
DSI0_CK_N: MODULE1.T46 U10_3.15 | length 48.5
  TOP_L1 w0.109: v4(39.632,134.836) 39.684,134.992 MODULE1.T46@39.832,135.436 ; U10_3.15@74.782,138.491 74.782,138.316 74.685,138.218 74.685,137.963 75.075,137.573 75.595,137.573 76.12,137.048 76.232,137.048 v6(76.232,136.936)
  BOTTOM_L10 w0.109: v4(39.632,134.836) 39.632,134.799 39.73,134.702 39.73,132.149 39.908,131.971 41.443,130.436 41.622,130.257 73.834,130.257 76.035,132.457 76.035,133.977 76.035,136.627 76.232,136.824 v6(76.232,136.936)
  other v1: 39.632,134.836
  other v2: 39.632,134.836
  other v3: 39.632,134.836
  other v5: 39.632,134.836
DSI0_CK_P: MODULE1.T45 U10_3.14 | length 48.6
  TOP_L1 w0.109: MODULE1.T45@39.932,134.236 40.08,134.68 v2(40.132,134.836) ; U10_3.14@74.282,138.491 74.282,138.316 74.38,138.218 74.38,137.837 74.949,137.268 75.299,137.268 75.532,137.034 v6(75.532,136.936)
  BOTTOM_L10 w0.109: v2(40.132,134.836) 40.132,134.799 40.034,134.702 40.034,132.275 41.748,130.562 73.708,130.562 73.821,130.675 74.378,131.232 ccw(c74.249,131.36) 74.378,131.489 cw(c74.506,131.617) 74.378,131.745 cw(c74.506,131.617) 74.635,131.745 ccw(c74.763,131.874) 74.891,131.745 ccw(c74.763,131.874) 74.891,132.002 74.698,132.196 cw(c74.826,132.324) 74.698,132.453 cw(c74.826,132.324) 74.955,132.453 75.148,132.259 ccw(c75.277,132.387) 75.405,132.259 75.701,132.555 75.73,132.584 75.73,136.627 75.532,136.824 v6(75.532,136.936)
  other v1: 40.132,134.836
  other v3: 40.132,134.836
  other v4: 40.132,134.836
  other v5: 40.132,134.836
DSI0_L0_N: MODULE1.P46 U10_3.6 | length 48.5
  TOP_L1 w0.109: v2(37.232,134.836) 37.284,134.992 MODULE1.P46@37.432,135.436 ; v6(69.432,136.936) 69.432,137.048 69.235,137.245 69.235,137.394 69.417,137.577 69.86,137.577 70.185,137.901 70.185,138.218 70.282,138.316 U10_3.6@70.282,138.491
  BOTTOM_L10 w0.109: v2(37.232,134.836) 37.232,134.873 37.33,134.97 37.33,135.588 37.282,135.636 36.882,136.036 35.011,136.036 34.833,136.215 34.336,136.711 34.336,138.486 34.855,139.005 35.05,139.2 38.74,139.2 38.982,138.957 38.982,137.236 39.082,137.136 39.377,136.841 41.877,136.841 42.056,136.662 43.539,135.179 64.69,135.179 67.293,137.782 68.616,137.782 69.432,136.966 v6(69.432,136.936)
  other v1: 37.232,134.836
  other v3: 37.232,134.836
  other v4: 37.232,134.836
  other v5: 37.232,134.836
DSI0_L0_P: MODULE1.P45 U10_3.5 | length 48.5
  TOP_L1 w0.109: MODULE1.P45@37.532,134.236 37.68,134.68 v4(37.732,134.836) ; v6(68.732,136.936) 68.732,137.048 68.93,137.245 68.93,137.521 69.291,137.882 69.734,137.882 69.88,138.027 69.88,138.218 69.782,138.316 U10_3.5@69.782,138.491
  BOTTOM_L10 w0.109: v4(37.732,134.836) 37.732,134.873 37.634,134.97 37.634,135.715 37.008,136.341 35.138,136.341 34.641,136.837 34.641,138.359 35.16,138.878 35.177,138.895 38.613,138.895 38.677,138.831 38.677,137.11 38.856,136.931 39.251,136.536 41.751,136.536 43.413,134.874 62.209,134.874 62.627,134.874 cw(c62.627,134.693) 62.809,134.693 62.809,134.498 ccw(c62.991,134.498) 63.172,134.498 63.172,134.693 cw(c63.354,134.693) 63.535,134.693 ccw(c63.717,134.693) 63.899,134.693 cw(c64.08,134.693) 64.08,134.874 64.806,134.874 64.816,134.874 67.419,137.477 68.489,137.477 68.638,137.329 68.638,137.03 v6(68.732,136.936)
  other v1: 37.732,134.836
  other v2: 37.732,134.836
  other v3: 37.732,134.836
  other v5: 37.732,134.836
DSI0_L1_N: MODULE1.R45 U10_3.8 | length 48.5
  TOP_L1 w0.109: v4(38.432,133.636) 38.484,133.792 MODULE1.R45@38.632,134.236 ; v6(71.132,136.936) 71.132,137.048 70.935,137.245 70.935,137.615 71.185,137.865 71.185,138.218 71.282,138.316 U10_3.8@71.282,138.491
  BOTTOM_L10 w0.109: v4(38.432,133.636) 38.432,133.599 38.53,133.502 38.53,133.338 38.298,133.106 38.066,133.106 37.652,133.52 37.652,133.752 37.935,134.034 38.267,134.034 38.848,134.615 38.848,135.267 39.109,135.528 41.413,135.528 42.377,134.563 42.377,133.51 42.856,133.031 62.971,133.031 63.389,133.031 cw(c63.389,132.85) 63.571,132.85 63.571,132.81 ccw(c63.752,132.81) 63.934,132.81 63.934,132.85 cw(c64.116,132.85) 64.297,132.85 64.297,132.824 ccw(c64.479,132.824) 64.66,132.824 64.66,132.85 cw(c64.842,132.85) 64.842,133.031 65.943,133.031 66.399,133.031 66.669,133.031 66.971,133.333 66.971,135.248 67.094,135.371 67.465,135.371 67.588,135.248 67.588,133.025 67.89,132.723 68.513,132.723 68.815,133.025 68.815,133.269 70.727,135.181 70.756,135.21 70.782,135.236 70.935,135.388 70.935,136.281 70.935,136.627 71.132,136.824 v6(71.132,136.936)
  other v1: 38.432,133.636
  other v2: 38.432,133.636
  other v3: 38.432,133.636
  other v5: 38.432,133.636
DSI0_L1_P: MODULE1.R44 U10_3.7 | length 48.6
  TOP_L1 w0.109: MODULE1.R44@38.732,133.036 38.88,133.48 v2(38.932,133.636) ; v6(70.432,136.936) 70.432,137.048 70.63,137.245 70.63,137.741 70.88,137.991 70.88,138.218 70.782,138.316 U10_3.7@70.782,138.491
  BOTTOM_L10 w0.109: v2(38.932,133.636) 38.932,133.599 38.834,133.502 38.834,133.212 38.424,132.801 37.94,132.801 37.348,133.394 37.348,133.878 37.808,134.339 38.141,134.339 38.544,134.741 38.544,135.393 38.983,135.832 41.539,135.832 42.682,134.69 42.682,133.636 42.782,133.536 42.982,133.336 66.399,133.336 66.542,133.336 66.666,133.46 66.666,135.374 66.968,135.676 67.591,135.676 67.893,135.374 67.893,133.151 68.016,133.028 68.387,133.028 68.51,133.151 68.51,133.395 70.512,135.397 70.63,135.515 70.63,135.731 70.63,136.627 70.432,136.824 v6(70.432,136.936)
  other v1: 38.932,133.636
  other v3: 38.932,133.636
  other v4: 38.932,133.636
  other v5: 38.932,133.636
DSI0_L2_N: MODULE1.U45 U10_3.11 | length 48.6
  TOP_L1 w0.109: v4(40.832,133.636) 40.884,133.792 MODULE1.U45@41.032,134.236 ; U10_3.11@72.782,138.491 72.782,138.316 72.685,138.218 72.685,137.765 72.635,137.715 72.635,137.245 72.832,137.048 v6(72.832,136.936)
  BOTTOM_L10 w0.109: v4(40.832,133.636) 40.832,133.599 40.93,133.502 40.93,132.708 41.108,132.529 41.928,131.71 42.106,131.531 71.008,131.531 71.403,131.926 71.932,132.455 73.282,132.455 73.584,132.757 73.584,133.38 73.282,133.682 71.491,133.682 71.368,133.806 71.368,134.176 71.491,134.299 74.645,134.299 74.947,134.601 74.947,135.224 74.645,135.526 72.758,135.526 72.635,135.65 72.635,135.793 72.635,136.627 72.832,136.824 v6(72.832,136.936)
  other v1: 40.832,133.636
  other v2: 40.832,133.636
  other v3: 40.832,133.636
  other v5: 40.832,133.636
DSI0_L2_P: MODULE1.U44 U10_3.10 | length 48.5
  TOP_L1 w0.109: MODULE1.U44@41.132,133.036 41.28,133.48 v2(41.332,133.636) ; v6(72.132,136.936) 72.132,137.048 72.33,137.245 72.33,137.841 72.38,137.891 72.38,138.218 72.282,138.316 U10_3.10@72.282,138.491
  BOTTOM_L10 w0.109: v2(41.332,133.636) 41.332,133.599 41.234,133.502 41.234,132.834 42.233,131.836 68.526,131.836 68.843,131.836 ccw(c68.843,132.018) 69.025,132.018 cw(c69.207,132.018) 69.388,132.018 ccw(c69.57,132.018) 69.751,132.018 69.751,132.083 cw(c69.933,132.083) 70.115,132.083 70.115,132.018 ccw(c70.296,132.018) 70.296,131.836 70.714,131.836 70.882,131.836 71.009,131.962 71.806,132.76 73.156,132.76 73.279,132.884 73.279,133.254 73.156,133.377 71.365,133.377 71.063,133.679 71.063,134.302 71.365,134.604 74.519,134.604 74.643,134.728 74.643,135.098 74.519,135.221 72.632,135.221 72.33,135.523 72.33,135.793 72.33,136.627 72.132,136.824 v6(72.132,136.936)
  other v1: 41.332,133.636
  other v3: 41.332,133.636
  other v4: 41.332,133.636
  other v5: 41.332,133.636
DSI0_L3_N: MODULE1.V46 U10_3.13 | length 48.4
  TOP_L1 w0.109: v1@40.824,138.293 40.824,138.291 40.735,138.202 40.735,137.197 41.906,136.025 41.906,135.718 42.188,135.436 MODULE1.V46@42.282,135.436 ; U10_3.13@73.782,138.491 73.782,138.316 73.685,138.218 73.685,137.963 73.835,137.813 74.042,137.813 74.335,137.521 74.335,137.245 74.532,137.048 v6(74.532,136.936)
  BOTTOM_L10 w0.109: v2(40.832,138.336) 40.832,138.299 40.735,138.202 40.735,137.943 40.798,137.879 42.208,137.879 42.386,137.7 43.75,136.336 57.015,136.336 57.727,136.336 ccw(c57.727,136.518) 57.909,136.518 cw(c58.09,136.518) 58.272,136.518 ccw(c58.454,136.518) 58.635,136.518 58.635,136.743 cw(c58.817,136.743) 58.998,136.743 58.998,136.518 ccw(c59.18,136.518) 59.18,136.336 59.598,136.336 60.578,136.336 60.722,136.336 60.845,136.46 60.845,138.485 61.147,138.787 61.77,138.787 62.072,138.485 62.072,136.46 62.195,136.336 62.984,136.336 63.895,136.336 64.204,136.645 65.843,138.285 66.089,138.531 74.028,138.531 74.335,138.224 74.335,137.245 74.532,137.048 v6(74.532,136.936)
  other v1: 40.832,138.336
  other v3: 40.832,138.336
  other v4: 40.832,138.336
  other v5: 40.832,138.336
DSI0_L3_P: MODULE1.V45 U10_3.12 | length 48.5
  TOP_L1 w0.109: v4(40.332,138.336) 40.332,138.299 40.43,138.202 40.43,137.07 41.602,135.898 41.602,135.338 42.239,134.701 42.239,134.279 MODULE1.V45@42.282,134.236 ; U10_3.12@73.282,138.491 73.282,138.316 73.38,138.218 73.38,137.837 73.709,137.508 73.916,137.508 74.03,137.394 74.03,137.245 73.832,137.048 v6(73.832,136.936)
  BOTTOM_L10 w0.109: v4(40.332,138.336) 40.332,138.299 40.43,138.202 40.43,137.816 40.672,137.574 42.081,137.574 43.624,136.031 60.578,136.031 60.848,136.031 61.15,136.333 61.15,138.359 61.273,138.482 61.644,138.482 61.767,138.359 61.767,136.333 62.069,136.031 62.984,136.031 64.021,136.031 66.216,138.226 73.902,138.226 74.03,138.098 74.03,137.245 73.832,137.048 v6(73.832,136.936)
  other v1: 40.332,138.336
  other v2: 40.332,138.336
  other v3: 40.332,138.336
  other v5: 40.332,138.336
DVDD18: C8.2 C9.2 C10.2 C11.2 C67.2 C68.2 L1.2 R62.2 R63.2 R64.2 R65.2 R66.2 R67.2 R68.2 R84.2 R266.2 R267.2 R413.2 U1.6 U1.28 U1.47 U8.5 U9.5 U27_1.7 U27_1.8 U27_1.9 U27_1.10 | length 63.5
  TOP_L1 w0.127: v1(63.469,14.789) 63.487,14.77 R62.2@63.775,14.77 ; R63.2@63.775,13.97 63.775,12.626 ; R267.2@64.779,9.163 64.728,9.214 64.728,9.405 64.654,9.48 64.469,9.48 64.31,9.639 64.31,9.732 R266.2@64.229,9.813 R65.2@64.229,11.129 64.229,11.144 63.775,11.598 63.775,12.626 ; v5(64.864,2.698) 64.525,2.359 64.525,1.279 65.115,0.689 66.465,0.689 66.62,0.843 R68.2@66.62,1.13 R67.2@68.46,1.13 ; C10.2@65.1,12.616 65.115,12.616 65.242,12.489 65.242,12.474 v1(65.814,11.902) 65.992,11.724 66.807,11.724 66.881,11.649 U1.28@66.881,11.134 ; C10.2@65.1,12.625 63.776,12.625 63.775,12.626 ; v2(66.258,12.64) 66.273,12.625 R413.2@66.6,12.625 ; C9.2@67.3,2.88 v1(67.88,2.88) ; v5(67.886,2.88) 67.986,2.981 67.986,2.987 68.481,3.481 U1.47@68.481,4.384 ; R66.2@69.14,1.13 69.657,1.13 70.016,1.489 70.016,1.591 70.291,1.865 v2(70.291,1.884) ; R84.2@69.82,2.33 69.844,2.33 70.039,2.524 70.127,2.524 v1(70.15,2.548)
  TOP_L1 w0.15: U1.6@72.856,7.159 73.485,7.159 v1(73.844,7.518) 74.03,7.518 74.182,7.366 74.227,7.366 74.307,7.286 C8.2@74.307,7.274 ; v1(74.439,13.651) 74.466,13.651 74.527,13.59 L1.2@74.94,13.59
  L3 w0.127: v5(63.196,14.464) 63.196,14.49 63.469,14.763 v1(63.469,14.789) ; v1(70.15,2.548) 70.15,2.515 70.234,2.431 v5(70.234,2.072) 70.267,2.038 70.267,1.907 v2(70.291,1.884) ; v1(67.88,2.88) v5(67.886,2.88) v1(67.88,2.88)
  L3 w0.15: v1(73.844,7.518) 74.178,7.518 v5(74.199,7.539) ; v1(74.439,13.651) 74.446,13.644 75.008,13.644 v4(75.015,13.637)
  L3 w0.25: v5(65.369,12.673) 65.814,12.673 ; v1(65.814,11.902) 65.814,12.673 ; v2(66.258,12.64) 66.225,12.673 65.814,12.673
  L8 w0.15: v5(74.199,7.539) v4(74.564,7.539)
  BOTTOM_L10 w0.127: 94.718,16.844 94.741,16.867 C67.2@94.741,17.344 ; C68.2@94.741,19.444 95.346,19.444 95.521,19.619 U9.5@96.001,19.619
  BOTTOM_L10 w0.15: v4(73.617,14.343) 73.965,14.343 U27_1.10@73.981,14.359 ; U27_1.10@73.981,14.359 73.98,13.72 74.019,13.681 v4(74.019,13.654) 74.09,13.726 74.281,13.726 ; 74.281,13.636 74.289,13.628 ; 74.381,13.636 U27_1.9@74.381,14.359 ; 74.781,13.636 U27_1.8@74.781,14.359 ; v3@74.981,13.637 v4(75.015,13.637) ; 75.181,13.636 U27_1.7@75.181,14.359 ; v5(75.625,13.256) 75.625,13.262 75.629,13.266 75.629,13.594
  BOTTOM_L10 w0.28: v4(74.564,7.539) 75.636,7.539 76.891,8.794 80.383,8.794 81.433,9.844 83.191,9.844 86.041,12.694 86.041,15.394 87.236,16.589 94.777,16.589 95.032,16.844 ; 94.718,16.844 95.032,16.844 ; U9.5@96.001,19.619 96.442,19.619 96.688,19.373 96.688,17.203 96.504,17.019 U8.5@96.001,17.019 95.521,17.019 95.346,16.844 95.032,16.844
  other v1: 70.291,1.884 64.864,2.698 65.94,2.88 66.258,12.64
  other v2: 70.15,2.548 64.864,2.698 65.94,2.88 67.88,2.88 73.844,7.518 65.814,11.902 74.439,13.651 63.469,14.789
  other v3: 74.564,7.539 75.625,13.256 75.015,13.637 74.019,13.654 73.617,14.343
  other v4: 75.625,13.256
  other v5: 65.94,2.88 75.015,13.637 74.019,13.654 73.617,14.343
EDP0_AUX_N: MODULE1.B29 U5.35 | length 122.3
  TOP_L1 w0.109: v2(22.682,114.436) 22.655,114.463 22.655,114.55 22.634,114.57 22.634,114.725 22.946,115.036 MODULE1.B29@23.082,115.036 ; v2(85.619,129.119) 85.581,129.119 85.52,129.058 85.491,129.058 85.09,128.657 85.09,128.377 86.628,126.839 87.347,126.12 87.436,126.031 87.436,124.57 84.607,121.741 84.607,95.59 84.607,94.894 84.73,94.771 84.798,94.771 84.922,94.647 84.922,94.277 84.798,94.153 84.73,94.153 84.607,94.03 84.607,93.66 84.73,93.536 84.798,93.536 84.922,93.413 84.922,93.042 84.798,92.919 84.73,92.919 84.607,92.795 84.607,92.425 84.73,92.302 84.798,92.302 84.922,92.178 84.922,91.808 84.798,91.684 84.73,91.684 84.607,91.561 84.607,90.889 84.607,89.453 87.211,86.849 89.304,86.849 89.501,87.047 v6(89.613,87.047)
  L3 w0.104: v2(22.682,114.436) 22.682,114.476 22.741,114.534 22.741,114.567 22.887,114.713 29.49,114.713 33.108,118.331 55.451,118.331 55.63,118.51 58.65,121.529 73.327,121.529 77.995,126.198 77.995,127.703 79.029,128.736 85.169,128.736 85.491,129.058 85.519,129.058 85.58,129.119 v2(85.619,129.119)
  BOTTOM_L10 w0.109: U5.35@87.753,87.547 87.798,87.502 88.135,87.502 88.137,87.499 88.483,87.499 88.572,87.41 88.721,87.261 89.133,86.849 89.304,86.849 89.501,87.047 v6(89.613,87.047)
  other v1: 22.682,114.436 85.619,129.119
EDP0_AUX_P: MODULE1.A29 U5.36 | length 122.3
  TOP_L1 w0.109: MODULE1.A29@21.882,115.036 22.019,115.036 22.33,114.725 22.33,114.57 22.309,114.55 22.309,114.463 v1(22.282,114.436) ; v1(85.336,129.402) 85.336,129.364 85.275,129.302 85.275,129.273 84.785,128.783 84.785,128.251 87.132,125.905 87.132,124.697 84.302,121.867 84.302,89.327 86.297,87.331 87.084,86.545 89.304,86.545 89.501,86.347 v6(89.613,86.347)
  L3 w0.104: v1(22.282,114.436) 22.282,114.476 22.377,114.571 22.377,114.634 22.761,115.018 29.364,115.018 32.982,118.636 55.325,118.636 58.523,121.834 73.2,121.834 77.69,126.324 77.69,127.829 78.903,129.041 85.043,129.041 85.275,129.273 85.275,129.301 85.336,129.362 v1(85.336,129.402)
  BOTTOM_L10 w0.109: U5.36@87.753,87.147 87.798,87.192 88.135,87.192 88.137,87.195 88.356,87.195 89.006,86.545 89.304,86.545 89.501,86.347 v6(89.613,86.347)
  other v2: 22.282,114.436 85.336,129.402
EDP0_TX0_N: MODULE1.B21 U6.40 | length 124.2
  TOP_L1 w0.109: v1(22.682,104.836) 22.655,104.863 22.655,104.95 22.634,104.97 22.634,105.125 22.946,105.436 MODULE1.B21@23.082,105.436 ; v2(84.619,124.919) 84.619,124.957 84.681,125.018 84.681,125.048 85.012,125.379 85.268,125.379 85.592,125.055 85.592,124.657 83.202,122.267 83.202,100.087 83.202,96.108 83.079,95.985 83.076,95.985 82.953,95.861 82.953,95.491 83.076,95.368 83.079,95.368 83.202,95.244 83.202,94.874 83.079,94.75 83.052,94.75 82.928,94.627 82.928,94.257 83.052,94.133 83.079,94.133 83.202,94.01 83.202,93.639 83.079,93.516 83.052,93.516 82.928,93.392 82.928,93.022 83.052,92.899 83.079,92.899 83.202,92.775 83.202,92.405 83.079,92.281 83.052,92.281 82.928,92.158 82.928,91.788 83.052,91.664 83.079,91.664 83.202,91.541 83.202,91.17 83.079,91.047 83.052,91.047 82.928,90.924 82.928,90.553 83.052,90.43 83.079,90.43 83.202,90.306 83.202,89.936 83.079,89.813 83.052,89.813 82.928,89.689 82.928,89.319 83.052,89.195 83.079,89.195 83.202,89.072 83.202,89.017 83.202,87.966 83.291,87.877 87.595,83.573 87.595,78.481 87.531,78.417 87.309,78.417 87.307,78.42 87.12,78.42 U6.40@87.075,78.465
  L3 w0.104: v1(22.682,104.836) 22.654,104.864 22.654,104.95 22.634,104.97 22.634,105.245 23.325,105.936 31.488,105.936 31.666,106.115 37.688,112.136 58.133,112.136 58.222,112.225 62.75,116.753 76.386,116.753 79.564,119.931 84.491,124.858 84.519,124.858 84.58,124.919 v2(84.619,124.919)
  other v1: 84.619,124.919
  other v2: 22.682,104.836
EDP0_TX0_P: MODULE1.A21 U6.39 | length 124.2
  TOP_L1 w0.109: MODULE1.A21@21.882,105.436 22.019,105.436 22.33,105.125 22.33,104.97 22.309,104.95 22.309,104.863 v1(22.282,104.836) ; v2(84.336,125.202) 84.374,125.202 84.436,125.263 84.465,125.263 84.885,125.683 85.394,125.683 85.897,125.181 85.897,124.531 83.507,122.141 83.507,88.093 87.9,83.699 87.9,78.355 87.658,78.113 87.309,78.113 87.307,78.11 87.12,78.11 U6.39@87.075,78.065
  L3 w0.104: v1(22.282,104.836) 22.31,104.864 22.31,104.95 22.33,104.97 22.33,105.372 23.199,106.241 31.362,106.241 37.562,112.441 58.007,112.441 62.534,116.968 62.624,117.058 76.26,117.058 79.437,120.235 84.275,125.073 84.275,125.101 84.336,125.162 v2(84.336,125.202)
  other v1: 84.336,125.202
  other v2: 22.282,104.836
EDP0_TX1_N: MODULE1.B23 U6.3 | length 124.2
  TOP_L1 w0.109: v1(22.682,107.236) 22.655,107.263 22.655,107.35 22.634,107.37 22.634,107.525 22.946,107.836 MODULE1.B23@23.082,107.836 ; v2(82.319,124.519) 82.319,124.557 82.381,124.618 82.381,124.648 82.601,124.868 83.19,124.868 83.412,124.645 83.412,124.277 82.102,122.967 82.102,121.113 82.02,121.032 81.748,121.032 81.068,121.712 80.515,121.712 80.137,121.333 80.137,120.801 81.602,119.336 82.032,118.907 82.032,96.512 82.032,92.047 81.908,91.924 81.785,91.8 81.785,91.43 81.908,91.307 82.032,91.183 82.032,90.813 81.908,90.689 81.89,90.689 81.767,90.566 81.767,90.196 81.89,90.072 81.908,90.072 82.032,89.949 82.032,89.578 81.908,89.455 81.882,89.455 81.758,89.331 81.758,88.961 81.882,88.838 81.908,88.838 82.032,88.714 82.032,88.344 81.908,88.22 81.882,88.22 81.758,88.097 81.758,87.727 81.882,87.603 81.908,87.603 82.032,87.48 82.032,87.425 82.032,86.807 86.321,82.517 86.321,81.286 85.946,80.911 85.946,79.173 85.945,79.172 85.945,78.985 U6.3@85.9,78.94
  L3 w0.104: v1(22.682,107.236) 22.654,107.264 22.654,107.35 22.634,107.37 22.634,108.373 22.938,108.677 23.827,108.677 23.888,108.616 23.888,107.512 24.156,107.244 30.195,107.244 30.373,107.422 36.682,113.731 57.432,113.731 57.611,113.91 61.515,117.813 75.547,117.813 81.469,123.736 82.191,124.458 82.219,124.458 82.28,124.519 v2(82.319,124.519)
  other v1: 82.319,124.519
  other v2: 22.682,107.236
EDP0_TX1_P: MODULE1.A23 U6.2 | length 124.3
  TOP_L1 w0.109: MODULE1.A23@21.882,107.836 22.019,107.836 22.33,107.525 22.33,107.37 22.309,107.35 22.309,107.263 v2(22.282,107.236) ; v2(82.036,124.802) 82.074,124.802 82.136,124.863 82.165,124.863 82.475,125.173 83.316,125.173 83.717,124.771 83.717,124.151 82.407,122.841 82.407,120.987 82.146,120.727 81.622,120.727 80.941,121.407 80.641,121.407 80.441,121.207 80.441,120.928 82.336,119.033 82.336,86.933 86.252,83.017 86.626,82.643 86.626,81.16 86.251,80.785 86.251,79.175 86.255,79.172 86.255,78.985 U6.2@86.3,78.94
  L3 w0.104: v2(22.282,107.236) 22.31,107.264 22.31,107.35 22.33,107.37 22.33,108.5 22.812,108.982 23.953,108.982 24.193,108.742 24.193,107.638 24.283,107.548 30.069,107.548 36.556,114.036 57.306,114.036 61.388,118.118 75.42,118.118 81.343,124.041 81.975,124.673 81.975,124.701 82.036,124.762 v2(82.036,124.802)
  other v1: 22.282,107.236 82.036,124.802
EDP0_TX2_N: MODULE1.B25 U6.6 | length 124.3
  TOP_L1 w0.109: v2(22.682,109.636) 22.655,109.663 22.655,109.75 22.634,109.77 22.634,109.925 22.946,110.236 MODULE1.B25@23.082,110.236 ; v2(82.419,127.219) 82.419,127.257 82.481,127.318 82.481,127.348 82.59,127.457 83.095,127.457 83.394,127.157 83.394,126.628 82.907,126.141 81.876,126.141 80.588,124.853 80.588,122.982 80.369,122.763 79.356,122.763 78.978,122.385 78.978,120.529 80.187,119.321 80.832,118.676 80.832,96.049 80.832,92.138 80.708,92.015 80.68,92.015 80.557,91.892 80.557,91.521 80.68,91.398 80.708,91.398 80.832,91.274 80.832,90.904 80.708,90.781 80.678,90.781 80.555,90.657 80.555,90.287 80.678,90.163 80.708,90.163 80.832,90.04 80.832,89.67 80.708,89.546 80.678,89.546 80.555,89.423 80.555,89.052 80.678,88.929 80.708,88.929 80.832,88.805 80.832,88.435 80.708,88.312 80.678,88.312 80.555,88.188 80.555,87.818 80.678,87.694 80.708,87.694 80.832,87.571 80.832,87.516 80.832,86.31 84.748,82.394 84.748,79.908 84.748,79.174 84.745,79.172 84.745,78.985 U6.6@84.7,78.94
  L3 w0.104: v2(22.682,109.636) 22.654,109.664 22.654,109.75 22.634,109.77 22.634,110.26 22.911,110.536 30.582,110.536 35.382,115.336 56.756,115.336 56.935,115.515 60.436,119.016 74.149,119.016 79.869,124.736 82.291,127.158 82.319,127.158 82.38,127.219 v2(82.419,127.219)
  other v1: 22.682,109.636 82.419,127.219
EDP0_TX2_P: MODULE1.A25 U6.5 | length 124.2
  TOP_L1 w0.109: MODULE1.A25@21.882,110.236 22.019,110.236 22.33,109.925 22.33,109.77 22.309,109.75 22.309,109.663 v2(22.282,109.636) ; v2(82.136,127.502) 82.174,127.502 82.236,127.563 82.265,127.563 82.464,127.762 83.221,127.762 83.699,127.283 83.699,126.502 83.033,125.836 82.002,125.836 80.892,124.726 80.892,122.855 80.495,122.458 79.482,122.458 79.282,122.258 79.282,120.656 81.136,118.802 81.136,86.436 85.052,82.52 85.052,79.782 85.052,79.174 85.055,79.172 85.055,78.985 U6.5@85.1,78.94
  L3 w0.104: v2(22.282,109.636) 22.31,109.664 22.31,109.75 22.33,109.77 22.33,110.386 22.784,110.841 30.456,110.841 35.256,115.641 56.63,115.641 60.31,119.32 74.022,119.32 79.743,125.041 82.075,127.373 82.075,127.401 82.136,127.462 v2(82.136,127.502)
  other v1: 22.282,109.636 82.136,127.502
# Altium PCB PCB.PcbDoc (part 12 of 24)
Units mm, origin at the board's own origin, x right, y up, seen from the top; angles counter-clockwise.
Board outline 100 x 160 mm, 10 copper layers (TOP_L1, L2, L3, L4, L5, L6, L7, L8, L9, BOTTOM_L10), stack 1.946 mm thick; 1358 components, 1149 nets, 6777 pads, 10914 vias.

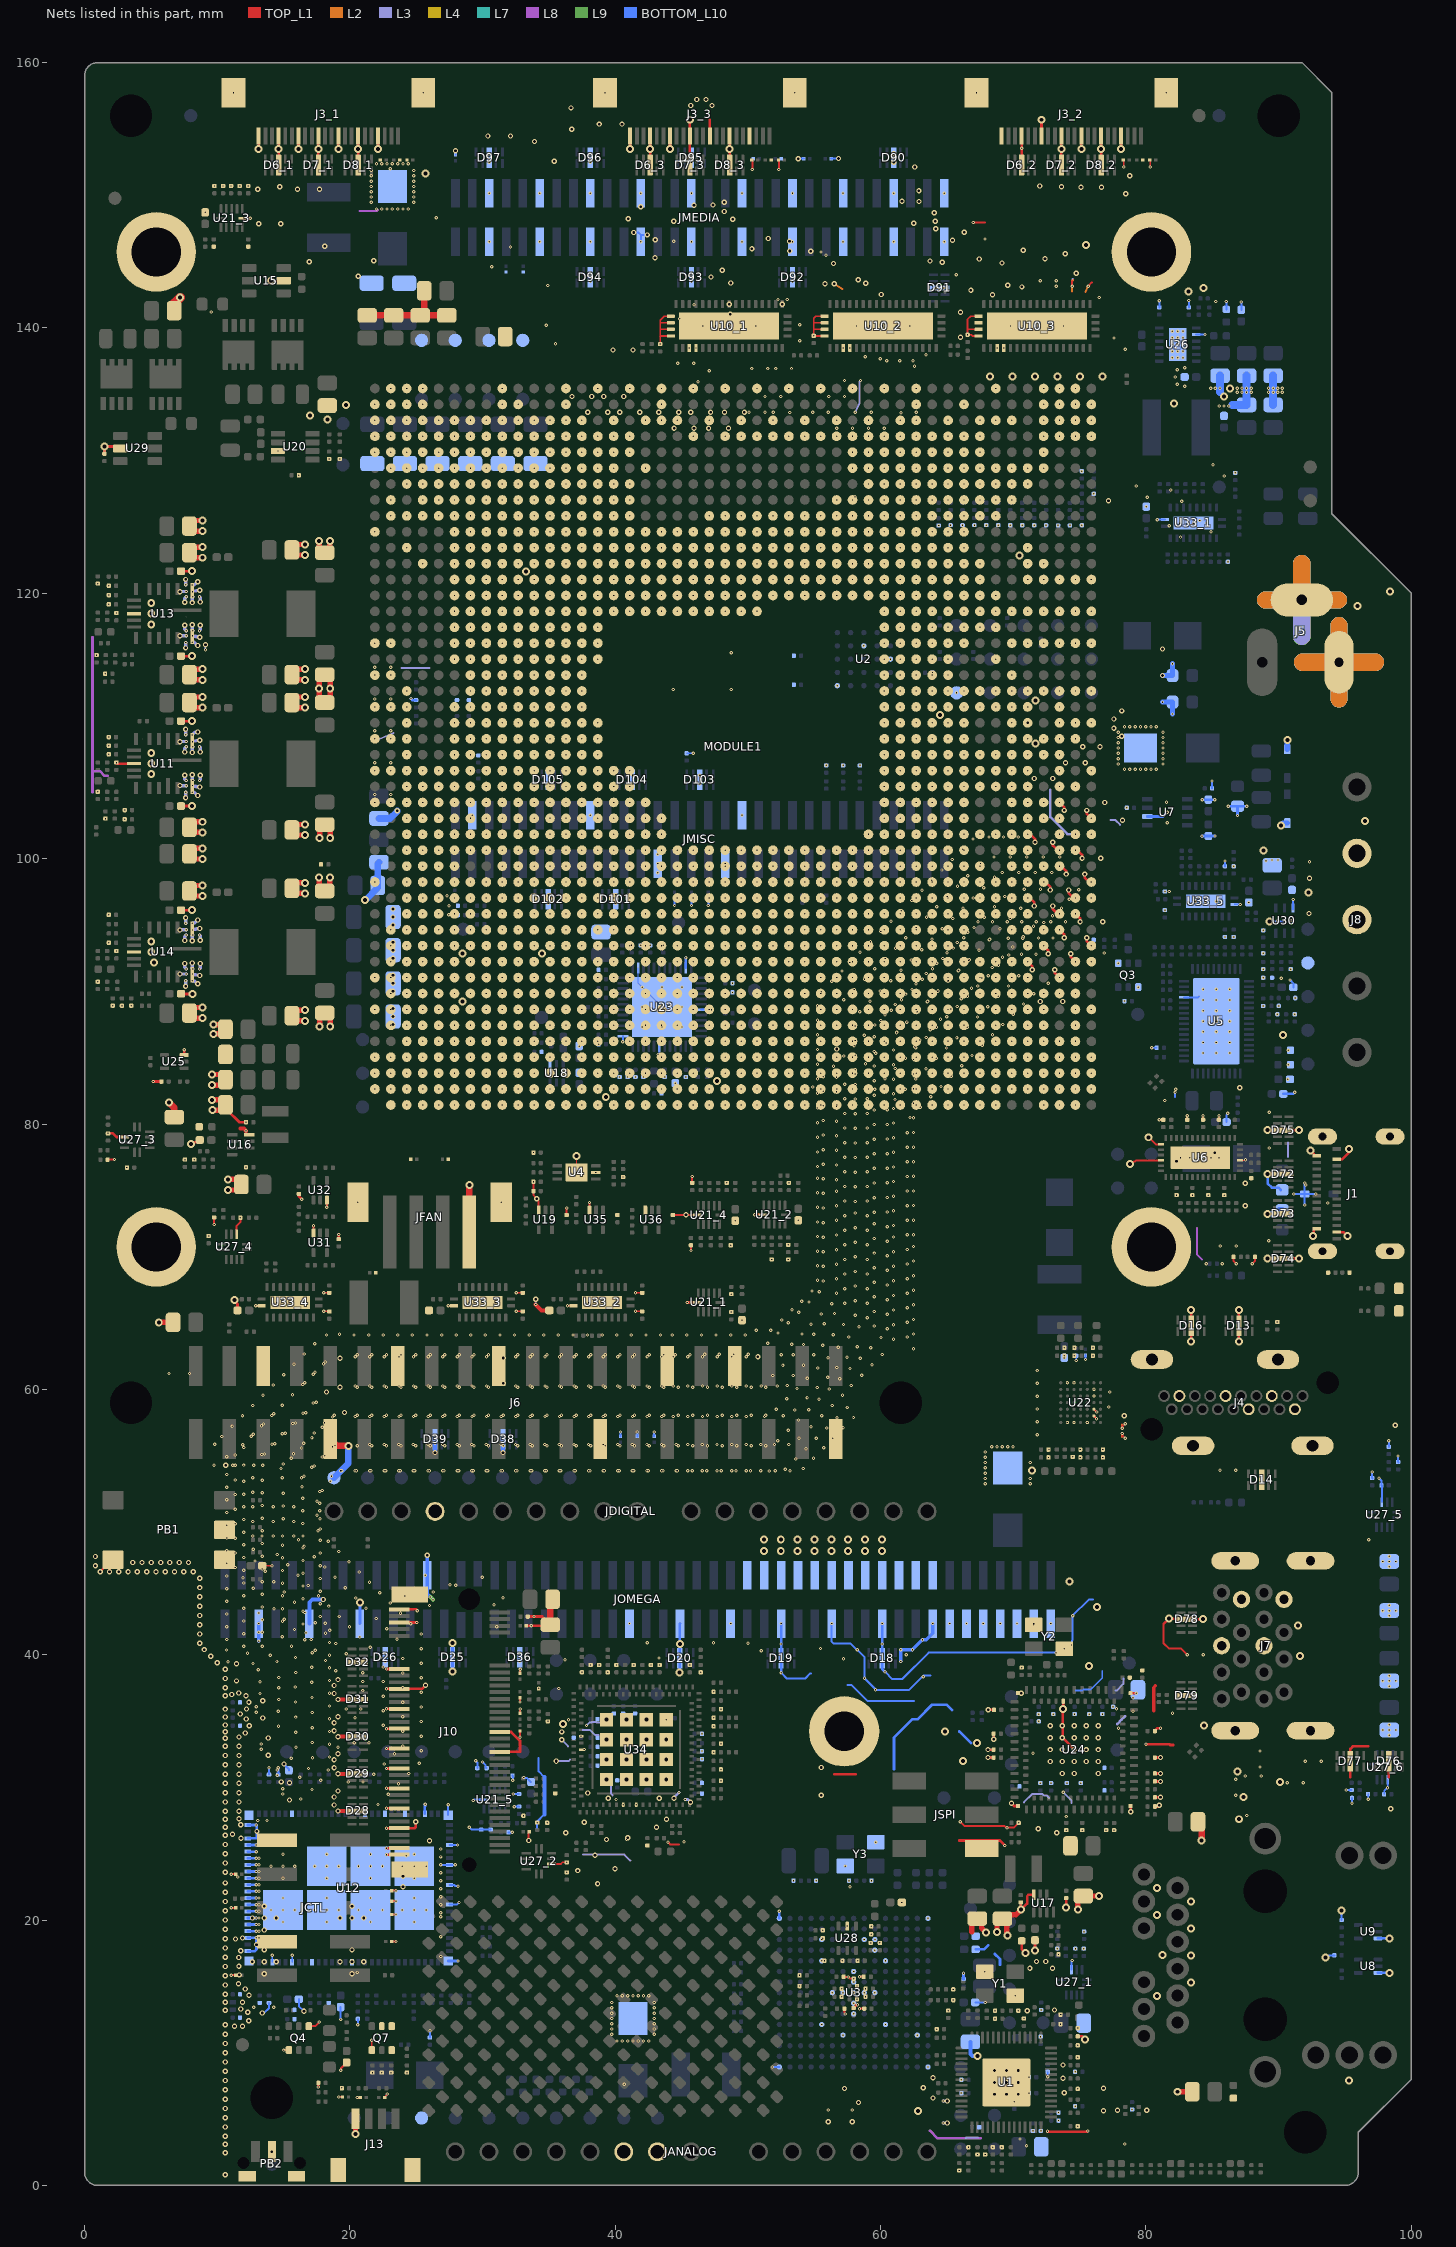
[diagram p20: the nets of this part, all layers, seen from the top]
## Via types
v1: diameter 0.25, hole 0.1, TOP_L1 to L2, tented both sides, 3439 vias
v2: diameter 0.25, hole 0.1, L2 to L3, tented both sides, 2256 vias
v3: diameter 0.25, hole 0.1, L9 to BOTTOM_L10, tented both sides, 1685 vias
v4: diameter 0.25, hole 0.1, L8 to L9, tented both sides, 1675 vias
v5: diameter 0.4, hole 0.2, L3 to L8, tented both sides, 1251 vias
v6: diameter 0.6, hole 0.3, TOP_L1 to BOTTOM_L10, tented both sides, 600 vias
v7: diameter 0.24, hole 0.1, TOP_L1 to L2, tented both sides, 8 vias

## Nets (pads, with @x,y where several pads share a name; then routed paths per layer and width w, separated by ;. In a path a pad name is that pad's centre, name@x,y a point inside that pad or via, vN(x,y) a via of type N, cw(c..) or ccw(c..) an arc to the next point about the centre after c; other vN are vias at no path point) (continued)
GND: (continued)
  BOTTOM_L10 w0.15: v5(13.4,13) 13.419,13.019 13.554,13.019 13.9,13.365 R316.1@13.9,13.76 ; C130.1@13.9,30.96 v3(13.9,31.476) ; C128.1@14.6,30.96 v3(14.6,31.476) ; v3(15.025,31.763) 15.4,31.387 C132.2@15.4,31.28 ; C133.2@16.145,14.034 16.145,13.514 v5(16.54,13.119) ; v3(19.3,12.512) C332.2@19.3,13.44 ; v3(20.6,12.108) R468.1@20.6,12.56 ; R511.1@26.03,11.15 v3(26.03,11.65) ; v3(26.849,24.16) U12.35@27.5,24.16 v3(27.94,24.16) ; U12.106@27.4,27.91 v3(27.4,28.695) ; U12.41@27.5,21.16 28.065,21.16 v3(28.227,21.322) ; U12.38@27.5,22.66 27.85,22.66 27.931,22.579 28.13,22.579 v3(28.149,22.56) ; U12.32@27.5,25.66 v3(28.11,25.66) ; v3(29,26.995) 29.175,26.82 R429.1@29.9,26.82 R461.1@30.6,26.82 ; v3(29.283,29.015) 29.338,29.07 U21_5.6@30.05,29.07 ; v3(29.489,32.009) 29.489,31.982 29.6,31.871 R428.1@29.6,31.445 ; v3(29.997,31.913) 30.211,31.7 30.211,31.525 30.291,31.445 R24.1@30.3,31.445 ; R466.1@31.95,26.607 v3(32.245,26.607) ; R467.1@32.25,30.895 32.275,30.87 v3(32.275,30.542) ; v3(32.3,29.495) C175_5.1@32.75,29.495 ; v3(32.393,28.539) 32.396,28.542 32.747,28.542 C172_5.1@32.75,28.545 ; v3(33.111,30.744) 33.13,30.725 33.314,30.725 33.634,30.405 C220_5.2@33.65,30.405 ; 34.098,26.974 34.098,27.412 34.647,27.96 ; 34.215,32.234 34.215,31.21 34.647,30.778 ; D24.1@40.386,56.438 D24.1@40.386,56.463 v3(40.386,56.791) ; v3(40.573,86.192) U23.37@40.573,86.616 ; v2(41.403,147.193) 41.747,147.193 JMEDIA.37@41.929,147.011 ; D21.1@41.656,56.438 D21.1@41.656,56.463 v3(41.656,56.791) ; v3(41.929,146.492) JMEDIA.37@41.929,147.011 ; v2(42.409,147.011) JMEDIA.37@41.929,147.011 ; D17.1@42.926,56.438 v3(42.926,56.791) ; v3(44.469,96.473) D100.1@44.469,97.004 D100.1@44.469,97.029 ; v3(45.739,96.473) D99.1@45.739,97.004 D99.1@45.739,97.029 ; U23.19@46.473,88.616 v3(47.251,88.616) ; v3(47.009,96.473) D98.1@47.009,97.004 D98.1@47.009,97.029 ; v3(51.839,8.929) U3.A15@52.363,8.929 ; v3(52.496,38.649) 52.942,38.203 54.3,38.203 54.697,38.6 54.763,38.6 ; v3(53.782,152.752) D87.1@54.204,152.752 D87.1@54.229,152.752 ; D86.1@56.249,152.752 56.812,152.752 v3(56.825,152.765) ; v3(56.306,42.35) 56.306,40.994 56.441,40.859 57.712,40.859 58.211,40.36 58.239,40.36 58.789,39.811 v3(58.789,38.218) 58.789,38.206 59.615,37.379 v4(59.615,37.367) 59.634,37.348 62.146,37.348 63.248,38.45 63.75,38.45 ; 57.5,37.7 57.818,37.7 59.012,36.506 62.527,36.506 ; v3(60.333,38.705) 60.879,38.159 61.611,38.159 63.616,40.164 73.82,40.164 v4(74.384,40.727) 74.403,40.747 74.403,40.817 74.417,40.832 74.417,41.057 74.477,41.116 v4(74.477,42.931) ; U27_1.2@74.381,16.259 74.381,16.888 v3(74.444,16.951) ; v3@74.458,42.921 75.687,44.15 76,44.15 ; v3(80.429,85.747) R92.2@80.803,85.747 ; v3(80.85,125.55) U33_1.11@81.425,125.55 ; R499.1@81,141.55 v3(81,142.047) ; v3(82.193,82.383) 82.193,82.032 82.203,82.022 ; U5.13@82.853,89.547 83.935,89.547 U5.53@84.003,89.615 ; R500.1@83.23,141.545 v3(83.23,142.07) ; U26.8@83.78,139.5 v3(84.45,139.5) ; C62.1@84.978,105.3 v4(84.978,105.852) ; R172.1@85.953,99.424 v3(85.953,99.824) ; R460.1@86.05,141.4 v4(86.05,141.998) ; C84.1@86.073,80.147 86.073,80.69 86.173,80.79 v3(86.173,80.817) ; C353.2@87.18,141.36 v3(87.18,141.958) ; v6(89.3,95.25) 90.359,95.25 U30.7@90.433,95.323 ; v3(90.853,90.853) 91.103,90.603 C44.2@91.103,90.297 ; U30.3@91.083,96.168 91.083,96.919 v3(91.088,96.924) ; v3(91.135,74.729) D1.1@91.965,74.729 ; v3(91.965,73.899) D1.1@91.965,74.729 ; v3(91.965,75.559) D1.1@91.965,74.729 ; v3(92.795,74.729) D1.1@91.965,74.729 ; v6(93.521,17.18) 93.643,17.18 93.806,17.344 C67.1@94.191,17.344 ; C68.1@94.741,19.994 v6(94.741,20.726) ; v3(97.048,53.773) R154.1@97.048,53.321 R154.1@97.071,53.298 ; v3(97.563,53.289) 97.748,53.104 C179_5.1@97.748,52.771 97.771,52.748 U27_5.2@97.771,51.496 ; v3(98.298,56.123) R474.1@98.298,55.671 R474.1@98.321,55.648 ; v3(98.998,54.973) C246_5.1@98.998,54.521 C246_5.1@99.021,54.498
  BOTTOM_L10 w0.2: U12.77@12.3,17.66 12.837,17.66 12.958,17.781 v3(12.958,18.152) 12.954,18.156 12.954,18.656 v3(12.95,18.66) U12.79@12.3,18.66 ; U12.80@12.3,19.16 v3(12.95,19.16) ; U12.81@12.3,19.66 v3(12.95,19.66) ; U12.82@12.3,20.16 v3(12.95,20.16) ; U12.83@12.3,20.66 v3(12.95,20.66) ; U12.84@12.3,21.16 v3(12.95,21.16) ; U12.85@12.3,21.66 v3(12.95,21.66) ; U12.86@12.3,22.16 v3(12.95,22.16) ; U12.87@12.3,22.66 v3(12.95,22.66) ; U12.88@12.3,23.16 v3(12.95,23.16) ; U12.89@12.3,23.66 v3(12.95,23.66) ; U12.90@12.3,24.16 v3(12.95,24.16) ; U12.91@12.3,24.66 v3(12.95,24.66) ; U12.92@12.3,25.16 v3(12.95,25.16) ; U12.93@12.3,25.66 v3(12.95,25.66) ; U12.94@12.3,26.16 12.95,26.16 12.988,26.198 v3(12.988,26.682) 12.988,27.108 12.95,27.146 v3(12.95,27.16) U12.96@12.3,27.16 ; JOMEGA.84@20.746,42.35 20.754,42.358 v6(20.754,43.931) ; v4(24.6,112.065) 24.6,112.054 24.705,111.949 R20.1@24.982,111.949 ; U12.26@25.65,28.01 25.65,28.559 25.662,28.571 25.662,28.733 25.682,28.733 v3(25.685,28.735) ; U12.107@27.4,16.91 v3(28.147,16.91) ; v6(27.731,38.735) D25.3@27.731,39.488 ; D25.8@27.731,40.135 v6(27.731,40.888) ; v6(44.853,38.662) 44.86,38.669 44.86,39.395 D20.3@44.866,39.402 ; D20.8@44.866,40.049 v6(44.866,40.802) 44.866,42.34 JOMEGA.46@44.876,42.35 ; U23.11@45.323,91.766 v3(45.323,92.523) ; U3.A1@52.363,20.129 v3(52.363,20.659) ; v3(52.496,38.649) D19.3@52.496,39.402 ; D19.8@52.496,40.049 v3(52.496,40.802) v3(52.496,42.35) ; v3(57.338,24.068) Y3.2@57.338,24.074 ; v3(59.626,25.874) Y3.4@59.638,25.874 ; D18.3@60.116,39.402 60.116,38.921 v3(60.333,38.705) ; D18.8@60.116,40.049 v3(60.116,40.802) v3(60.116,42.35) ; 61.003,31.356 61.003,33.753 62.377,35.127 62.777,35.127 63.89,36.24 64.967,36.24 65.38,35.827 ; 65.931,34.217 66.806,33.342 ; C285.1@66.25,15.55 v3(66.25,16) ; C286.2@67.16,17.791 67.791,17.791 68.1,18.1 ; 68.6,17.457 68.995,17.062 68.995,16.625 ; U7.2@80.103,103.178 81.278,103.178 v3(81.603,103.503) ; v4(84.223,101.699) 84.227,101.704 84.694,101.704 C342.2@84.7,101.71 ; v3(84.233,104.448) C361.2@84.703,104.448 ; C342.2@84.703,101.708 84.706,101.705 85.201,101.705 v4(85.204,101.702) ; C361.2@84.709,104.444 v3(85.179,104.444) ; v4(86.2,103.95) C341.2@86.9,103.95 ; v3(86.9,103.25) C341.2@86.9,103.95 ; v4(87.6,103.95) C341.2@86.9,103.95 ; v6(89.167,76.229) 89.167,75.533 89.5,75.2 89.994,75.2 C344.2@90.165,75.029 ; C40.1@90.353,82.267 91.067,82.267 v3(91.2,82.4) ; U8.3@97.481,16.019 v6(98.341,16.019) ; U9.3@97.481,18.619 v6(98.341,18.619)
  BOTTOM_L10 w0.25: v3(61.521,39.494) 61.521,40.37 v4(61.526,40.375) v3(62.399,40.375) v4(63.148,41.124) 63.45,41.124 63.926,41.6 v3(63.926,42.35)
  BOTTOM_L10 w0.3: v3(13.126,41.026) v3(13.126,41.688) v3(13.126,42.35) ; JOMEGA.90@16.936,42.35 16.936,43.936 17.16,44.16 v3(17.978,44.16) ; v2(25.826,47.498) JOMEGA.75@25.826,46 25.826,44.584 v3(26.062,44.349) ; v4(26.416,55.234) v3(26.416,55.915) ; v4(31.541,55.234) v3(31.541,55.915) ; 34.647,27.96 34.647,30.778 ; C288.2@66.768,10.821 66.768,9.898 66.907,9.759 v6(67.311,9.759)
  BOTTOM_L10 w0.4: v3(81.248,111.8) C340.2@81.998,111.8 v3(81.998,110.902) ; v5(81.248,113.8) C339.2@81.998,113.8 v3(81.998,114.698) ; v6(89.167,73.229) 89.735,73.229 90.035,73.529 C343.2@90.265,73.529 ; v6(90.159,102.506) 90.333,102.68 D22.1@90.65,102.68 ; D23.1@90.65,108.25 v6@90.65,108.95
  BOTTOM_L10 w0.5: TP30.X@18.796,53.34 19.882,54.426 v6(19.882,55.741) ; v6(21.135,96.87) 21.162,96.87 22.089,97.798 C252.1@22.089,97.978 22.089,99.628 C250.1@22.189,99.728 ; C249.1@22.189,103.028 23.029,103.028 23.573,103.572 v5(23.573,103.603)
  BOTTOM_L10 w0.6: 85.58,135.17 v3(85.58,135.45) C352.2@85.58,136.4 ; 86.5,134.2 C355.1@87.58,134.2 v3(87.58,135.15) v4(87.58,135.45) C356.2@87.58,136.4 ; C359.1@89.58,134.2 v3(89.58,135.15) v4(89.58,135.45) C357.2@89.58,136.4
  BOTTOM_L10 w1.3: 89,119.5 J5.2@91.748,119.5 ; J5.2@91.748,120.534 J5.2@91.748,119.5 ; 94.496,119.5 J5.2@91.748,119.5 ; 94.548,117.548 J5.3@94.548,114.8 96.337,114.8
  other v1: 10.6,0.8 65.93,1.13 67.3,2.33 67.88,2.33 10.6,2.452 14.117,2.549 66.62,2.88 68.46,2.88 69.14,2.88 71,3 10.6,3.102 78.406,3.118 70.5,3.5 10.6,3.702 72.581,4.077 75.61,4.098 10.6,4.402 74.856,4.459 10.6,5.102 76.798,5.62 77.848,5.674 80.048,5.674 56.062,5.679 57.862,5.679 10.6,5.802 10.6,6.502 68.581,6.859 69.481,6.859 70.381,6.859 73.848,6.974 10.6,7.202 74.857,7.274 76.798,7.32 19.39,7.369 17.617,7.423 68.581,7.759 69.481,7.759 70.381,7.759 10.6,7.902 73.748,8.074 21.7,8.5 22.4,8.5 23.1,8.5 24.3,8.5 10.6,8.602 68.581,8.659 69.481,8.659 70.381,8.659 73.748,9.074 10.6,9.302 74.856,9.659 10.6,10.002 74.856,10.559 10.6,10.702 10.6,11.402 64.229,11.775 74.856,11.859 11.3,12 11.9,12 10.6,12.102 73.556,12.159 12.367,12.413 68.625,12.57 70.8,12.575 73.563,12.877 12.293,13.052 65.1,13.175 68.625,13.17 70.375,13.17 71.048,13.174 10.6,13.2 73.1,13.225 11.762,13.3 10.6,13.8 11.901,13.801 65.475,13.97 58.213,14.029 57.063,14.229 58.863,14.229 70.15,14.3 12.397,14.327 10.6,14.4 65.475,14.77 12.1,14.8 57.063,14.829 58.863,14.829 53.888,15.029 58.213,15.029 10.6,15.1 11.6,15.2 10.6,15.8 53.888,15.829 67.85,16.1 71.25,16.375 72.95,16.375 10.6,16.5 11.632,16.525 71.75,16.875 72.45,16.875 55.763,16.929 57.113,16.929 58.263,16.929 11.628,17.175 10.6,17.2 73.406,17.409 11.776,17.689 10.6,17.9 59.25,18.275 59.935,18.295 11.373,18.578 10.6,18.6 55.638,18.629 11.902,18.65 59.288,18.929 55.638,19.229 10.6,19.3 59.288,19.529 57.483,19.549 10.6,20 10.6,20.7 61.598,21.329 10.6,21.4 10.6,22.1 38.665,22.744 10.6,22.8 10.6,23.601 36.341,23.599 37.179,23.729 39.975,23.875 10.6,24.301 38.465,24.889 10.6,25.001 10.6,25.701 43.972,25.867 45.173,25.913 26,25.98 33.469,26 39.341,26.074 11.789,26.167 40.94,26.203 10.6,26.401 11.144,26.459 36.275,26.575 73.269,26.575 73.991,26.774 75.191,26.774 76.991,26.774 77.591,26.774 71.875,26.875 69.53,26.961 10.6,27.001 11.777,27.176 34.114,27.341 34.86,27.331 37.67,27.373 24.961,27.403 66,27.415 10.6,27.6 11.64,27.634 73.991,27.799 33.078,27.865 87.6,27.875 78.841,28.174 10.6,28.201 11.64,28.201 19.106,28.225 81.009,28.643 18.806,28.675 40.591,28.679 41.591,28.679 69.862,28.795 10.6,28.901 11.64,28.901 15.443,29.052 40.06,29.081 45.27,29.089 81.091,29.249 18.806,29.275 55.52,29.403 86.766,29.408 14.943,29.502 10.6,29.601 11.64,29.601 44.802,29.611 19.106,29.725 14.943,29.902 10.6,30.301 11.64,30.301 15.443,30.352 90.64,30.349 91.84,30.349 14.825,30.413 81.091,30.449 47.961,30.499 86.766,30.608 87.482,30.86 88.682,30.86 14.525,30.913 10.6,31.001 11.64,31.001 19.106,31.025 73.691,31.049 74.591,31.049 76.391,31.049 81.091,31.049 14.525,31.313 47.961,31.349 18.806,31.475 55.52,31.503 88.597,31.542 10.6,31.701 11.64,31.701 15.025,31.763 35.56,31.881 72.791,31.949 73.691,31.949 74.591,31.949 75.491,31.949 76.391,31.949 92,31.975 93.2,31.975 18.806,32.075 81.091,32.249 98.3,32.299 10.6,32.401 11.64,32.401 13.849,32.425 19.106,32.525 47.411,32.649 88.597,32.742 68.091,32.849 72.791,32.849 73.691,32.849 74.591,32.849 75.491,32.849 76.391,32.849 13.327,32.875 10.6,33.101 11.64,33.101 13.327,33.275 47.961,33.299 10.6,33.701 13.849,33.725 72.791,33.749 73.691,33.749 74.591,33.749 75.491,33.749 76.391,33.749 11.64,33.801 19.106,33.825 37.421,33.849 12.1,34.101 10.6,34.201 35.96,34.181 18.806,34.275 47.411,34.599 12.417,34.651 72.791,34.649 73.691,34.649 74.591,34.649 75.491,34.649 76.391,34.649 10.6,34.701 18.806,34.875 34.923,34.975 36.471,35.099 43.841,35.099 12.185,35.149 13.427,35.225 47.411,35.249 10.6,35.301 19.106,35.325 11.733,35.535 12.927,35.675 68.116,35.849 10.6,35.901 47.961,35.899 12.202,35.909 12.927,36.075 12.386,36.422 13.427,36.525 19.106,36.625 10.6,36.901 12.165,36.901 82.752,36.925 83.399,36.925 11.097,37.004 18.806,37.075 70.605,37.085 11.613,37.11 47.411,37.199 34.223,37.475 10.6,37.501 18.806,37.675 25.7,37.7 11.45,38.024 19.106,38.125 10.6,38.201 37.486,38.674 39.436,38.674 46.436,38.674 10.6,38.901 70.626,39.024 38.136,39.224 38.786,39.224 40.086,39.224 41.386,39.224 42.686,39.224 43.336,39.224 45.614,39.224 11.45,39.324 10.005,39.396 9.51,39.891 83.104,40.004 84.304,40.004 9.015,40.386 73.842,40.449 8.674,40.859 8.674,41.559 71.541,42.249 8.674,42.259 25.025,42.425 8.674,42.959 25.082,43.323 8.674,43.659 8.674,44.359 8.674,45.059 8.674,45.759 1.179,46.254 1.879,46.254 2.579,46.254 3.279,46.254 3.979,46.254 4.679,46.254 5.379,46.254 6.079,46.254 6.779,46.254 7.479,46.254 8.179,46.254 0.817,46.7 3.629,46.954 4.329,46.954 5.029,46.954 5.729,46.954 6.429,46.954 7.129,46.954 7.829,46.954 0.817,47.4 14.223,48.946 15.766,48.946 16.391,52.649 14.891,53.349 85.575,53.9 86.775,53.9 9.75,54.269 11.16,54.269 12.74,54.269 72.649,54.865 75.049,54.865 76.749,54.865 74.475,54.915 72.694,55.465 75.049,55.465 76.749,55.465 71.8,56.586 78.201,56.669 78.201,57.069 75.575,57.5 71.8,57.552 19.596,58.25 71.8,58.517 77.199,58.671 71.8,59.483 76.075,59.5 18.23,59.796 77.275,59.8 76.075,60 71.8,60.449 31.557,60.467 71.8,61.414 31.557,62.365 73.85,62.535 74.6,62.535 76,62.535 73.85,63.135 74.6,63.135 76,63.135 89.902,65.075 49.55,65.215 48.75,65.825 14.5,66.55 15.5,66.55 16.5,66.55 29,66.55 30,66.55 31,66.55 38,66.55 39,66.55 40,66.55 45.431,66.551 48.75,67.175 84.552,69.463 85.752,69.463 86.804,69.463 51.789,69.79 53.039,69.79 85.604,70.799 86.805,70.799 48.7,70.862 53.039,70.89 89.255,71.199 9.35,71.561 49.05,72.706 53.789,72.734 45.325,73.165 87.482,73.836 93.705,74.045 20.6,74.1 31.4,74.1 34.086,74.376 82.3,74.637 83.5,74.637 84.7,74.637 85.9,74.637 92.04,75.405 87.482,75.536 48.4,75.566 53.089,75.566 40.582,75.999 38.532,76.349 3.19,76.719 12.168,76.741 7.568,77.316 8.268,77.316 82.6,77.465 83.3,77.465 84.1,77.465 84.9,77.465 85.5,77.465 33.832,77.849 89.283,78.186 89.283,80.88 24.282,81.436 25.482,81.436 26.682,81.436 27.882,81.436 29.082,81.436 30.282,81.436 31.482,81.436 32.682,81.436 33.882,81.436 35.082,81.436 36.282,81.436 37.482,81.436 38.682,81.436 39.882,81.436 41.082,81.436 42.282,81.436 43.482,81.436 44.682,81.436 45.882,81.436 47.082,81.436 48.282,81.436 49.482,81.436 50.682,81.436 51.882,81.436 53.082,81.436 54.282,81.436 55.482,81.436 56.682,81.436 57.882,81.436 59.082,81.436 60.282,81.436 61.482,81.436 62.682,81.436 63.882,81.436 65.082,81.436 66.282,81.436 67.482,81.436 68.682,81.436 72.282,81.436 73.482,81.436 74.682,81.436 81.402,81.767 21.882,82.636 23.082,82.636 24.282,82.636 25.482,82.636 26.682,82.636 27.882,82.636 29.082,82.636 30.282,82.636 31.482,82.636 32.682,82.636 33.882,82.636 35.082,82.636 36.282,82.636 37.482,82.636 38.682,82.636 39.882,82.636 41.082,82.636 42.282,82.636 43.482,82.636 44.682,82.636 45.882,82.636 47.082,82.636 48.282,82.636 49.482,82.636 50.682,82.636 51.882,82.636 53.082,82.636 54.282,82.636 55.482,82.636 56.682,82.636 57.882,82.636 59.082,82.636 60.282,82.636 61.482,82.636 62.682,82.636 63.882,82.636 65.082,82.636 66.282,82.636 67.482,82.636 68.682,82.636 69.882,82.636 71.082,82.636 72.282,82.636 73.482,82.636 74.682,82.636 75.882,82.636 82.25,82.615 5.184,83.202 21.882,83.836 23.082,83.836 24.282,83.836 25.482,83.836 26.682,83.836 27.882,83.836 29.082,83.836 30.282,83.836 31.482,83.836 32.682,83.836 33.882,83.836 35.082,83.836 36.282,83.836 37.482,83.836 38.682,83.836 39.882,83.836 41.082,83.836 42.282,83.836 43.482,83.836 44.682,83.836 45.882,83.836 47.082,83.836 48.282,83.836 49.482,83.836 50.682,83.836 51.882,83.836 53.082,83.836 54.282,83.836 55.482,83.836 56.682,83.836 57.882,83.836 59.082,83.836 60.282,83.836 61.482,83.836 62.682,83.836 63.882,83.836 65.082,83.836 66.282,83.836 67.482,83.836 68.682,83.836 69.882,83.836 71.082,83.836 72.282,83.836 73.482,83.836 74.682,83.836 75.882,83.836 21.882,85.036 23.082,85.036 24.282,85.036 25.482,85.036 26.682,85.036 27.882,85.036 29.082,85.036 30.282,85.036 31.482,85.036 32.682,85.036 33.882,85.036 35.082,85.036 36.282,85.036 37.482,85.036 38.682,85.036 39.882,85.036 41.082,85.036 42.282,85.036 43.482,85.036 44.682,85.036 45.882,85.036 47.082,85.036 48.282,85.036 49.482,85.036 50.682,85.036 51.882,85.036 53.082,85.036 54.282,85.036 55.482,85.036 56.682,85.036 57.882,85.036 59.082,85.036 60.282,85.036 61.482,85.036 62.682,85.036 63.882,85.036 65.082,85.036 66.282,85.036 67.482,85.036 68.682,85.036 69.882,85.036 71.082,85.036 72.282,85.036 73.482,85.036 74.682,85.036 75.882,85.036 24.282,86.236 25.482,86.236 26.682,86.236 27.882,86.236 29.082,86.236 30.282,86.236 31.482,86.236 32.682,86.236 33.882,86.236 35.082,86.236 36.282,86.236 37.482,86.236 38.682,86.236 39.882,86.236 41.082,86.236 42.282,86.236 43.482,86.236 44.682,86.236 45.882,86.236 47.082,86.236 48.282,86.236 49.482,86.236 50.682,86.236 51.882,86.236 53.082,86.236 54.282,86.236 55.482,86.236 56.682,86.236 57.882,86.236 59.082,86.236 60.282,86.236 61.482,86.236 62.682,86.236 63.882,86.236 65.082,86.236 66.282,86.236 67.482,86.236 68.682,86.236 69.882,86.236 71.082,86.236 72.282,86.236 73.482,86.236 74.682,86.236 23.082,87.436 24.282,87.436 25.482,87.436 26.682,87.436 27.882,87.436 29.082,87.436 30.282,87.436 31.482,87.436 32.682,87.436 33.882,87.436 35.082,87.436 36.282,87.436 37.482,87.436 38.682,87.436 39.882,87.436 41.082,87.436 42.282,87.436 43.482,87.436 44.682,87.436 45.882,87.436 47.082,87.436 48.282,87.436 49.482,87.436 50.682,87.436 51.882,87.436 53.082,87.436 54.282,87.436 55.482,87.436 56.682,87.436 57.882,87.436 59.082,87.436 60.282,87.436 61.482,87.436 62.682,87.436 63.882,87.436 65.082,87.436 66.282,87.436 67.482,87.436 68.682,87.436 69.882,87.436 71.082,87.436 72.282,87.436 74.682,87.436 21.882,88.636 23.082,88.636 24.282,88.636 25.482,88.636 26.682,88.636 27.882,88.636 29.082,88.636 30.282,88.636 31.482,88.636 32.682,88.636 33.882,88.636 35.082,88.636 36.282,88.636 37.482,88.636 38.682,88.636 39.882,88.636 41.082,88.636 42.282,88.636 43.482,88.636 44.682,88.636 45.882,88.636 47.082,88.636 48.282,88.636 49.482,88.636 50.682,88.636 51.882,88.636 53.082,88.636 54.282,88.636 55.482,88.636 56.682,88.636 57.882,88.636 59.082,88.636 60.282,88.636 61.482,88.636 62.682,88.636 63.882,88.636 65.082,88.636 66.282,88.636 67.482,88.636 68.682,88.636 69.882,88.636 71.082,88.636 72.282,88.636 74.682,88.636 75.882,88.636 2.119,88.916 2.819,88.916 3.519,88.916 72.032,89.236 73.732,89.236 23.082,89.836 24.282,89.836 25.482,89.836 26.682,89.836 27.882,89.836 29.082,89.836 30.282,89.836 31.482,89.836 32.682,89.836 33.882,89.836 35.082,89.836 36.282,89.836 37.482,89.836 38.682,89.836 39.882,89.836 41.082,89.836 42.282,89.836 43.482,89.836 44.682,89.836 45.882,89.836 47.082,89.836 48.282,89.836 49.482,89.836 50.682,89.836 51.882,89.836 53.082,89.836 54.282,89.836 55.482,89.836 56.682,89.836 57.882,89.836 59.082,89.836 60.282,89.836 61.482,89.836 62.682,89.836 63.882,89.836 65.082,89.836 66.282,89.836 67.482,89.836 68.682,89.836 69.882,89.836 71.082,89.836 72.282,89.836 73.482,89.836 74.682,89.836 1,90.722 21.882,91.036 23.082,91.036 24.282,91.036 25.482,91.036 26.682,91.036 27.882,91.036 29.082,91.036 30.282,91.036 31.482,91.036 32.682,91.036 33.882,91.036 35.082,91.036 36.282,91.036 37.482,91.036 38.682,91.036 39.882,91.036 41.082,91.036 42.282,91.036 43.482,91.036 44.682,91.036 45.882,91.036 47.082,91.036 48.282,91.036 49.482,91.036 50.682,91.036 51.882,91.036 53.082,91.036 54.282,91.036 55.482,91.036 56.682,91.036 57.882,91.036 59.082,91.036 60.282,91.036 61.482,91.036 62.682,91.036 63.882,91.036 65.082,91.036 66.282,91.036 67.482,91.036 68.682,91.036 69.882,91.036 71.082,91.036 74.682,91.036 7.651,91.299 71.432,91.636 73.132,91.636 8.662,91.685 23.082,92.236 24.282,92.236 25.482,92.236 26.682,92.236 27.882,92.236 29.082,92.236 30.282,92.236 31.482,92.236 32.682,92.236 33.882,92.236 35.082,92.236 36.282,92.236 37.482,92.236 38.682,92.236 39.882,92.236 41.082,92.236 42.282,92.236 43.482,92.236 44.682,92.236 45.882,92.236 47.082,92.236 48.282,92.236 49.482,92.236 50.682,92.236 51.882,92.236 53.082,92.236 54.282,92.236 55.482,92.236 56.682,92.236 57.882,92.236 59.082,92.236 60.282,92.236 61.482,92.236 62.682,92.236 63.882,92.236 65.082,92.236 66.282,92.236 67.482,92.236 68.682,92.236 69.882,92.236 75.882,92.236 72.632,92.836 2.4,93.041 23.082,93.436 24.282,93.436 25.482,93.436 26.682,93.436 27.882,93.436 29.082,93.436 30.282,93.436 31.482,93.436 32.682,93.436 33.882,93.436 35.082,93.436 36.282,93.436 37.482,93.436 38.682,93.436 39.882,93.436 41.082,93.436 42.282,93.436 43.482,93.436 44.682,93.436 45.882,93.436 47.082,93.436 48.282,93.436 49.482,93.436 50.682,93.436 51.882,93.436 53.082,93.436 54.282,93.436 55.482,93.436 56.682,93.436 57.882,93.436 59.082,93.436 60.282,93.436 61.482,93.436 62.682,93.436 63.882,93.436 65.082,93.436 66.282,93.436 71.082,93.436 1.825,93.666 75.532,94.036 8.162,94.246 23.082,94.636 24.282,94.636 25.482,94.636 26.682,94.636 27.882,94.636 29.082,94.636 30.282,94.636 31.482,94.636 32.682,94.636 33.882,94.636 35.082,94.636 36.282,94.636 37.482,94.636 38.682,94.636 39.882,94.636 41.082,94.636 42.282,94.636 43.482,94.636 44.682,94.636 45.882,94.636 47.082,94.636 48.282,94.636 49.482,94.636 50.682,94.636 51.882,94.636 53.082,94.636 54.282,94.636 55.482,94.636 56.682,94.636 57.882,94.636 59.082,94.636 60.282,94.636 61.482,94.636 62.682,94.636 63.882,94.636 65.082,94.636 66.282,94.636 69.882,94.636 71.082,94.636 72.282,94.636 7.614,95.134 75.032,95.236 76.732,95.236 1.825,95.766 24.282,95.836 25.482,95.836 26.682,95.836 27.882,95.836 29.082,95.836 30.282,95.836 31.482,95.836 32.682,95.836 33.882,95.836 35.082,95.836 36.282,95.836 37.482,95.836 38.682,95.836 39.882,95.836 41.082,95.836 42.282,95.836 43.482,95.836 44.682,95.836 45.882,95.836 47.082,95.836 48.282,95.836 49.482,95.836 50.682,95.836 51.882,95.836 53.082,95.836 54.282,95.836 55.482,95.836 56.682,95.836 57.882,95.836 59.082,95.836 60.282,95.836 61.482,95.836 62.682,95.836 63.882,95.836 65.082,95.836 66.282,95.836 67.482,95.836 68.682,95.836 69.882,95.836 71.082,95.836 73.482,95.836 92.289,95.868 71.582,96.436 72.982,96.436 24.282,97.036 25.482,97.036 26.682,97.036 27.882,97.036 29.082,97.036 30.282,97.036 31.482,97.036 32.682,97.036 33.882,97.036 35.082,97.036 36.282,97.036 37.482,97.036 38.682,97.036 39.882,97.036 41.082,97.036 42.282,97.036 43.482,97.036 44.682,97.036 45.882,97.036 47.082,97.036 48.282,97.036 49.482,97.036 50.682,97.036 51.882,97.036 53.082,97.036 54.282,97.036 55.482,97.036 56.682,97.036 57.882,97.036 59.082,97.036 60.282,97.036 61.482,97.036 62.682,97.036 63.882,97.036 65.082,97.036 66.282,97.036 67.482,97.036 68.682,97.036 69.882,97.036 71.082,97.036 74.682,97.036 75.882,97.036 72.782,97.636 74.182,97.636 21.882,98.236 24.282,98.236 25.482,98.236 26.682,98.236 27.882,98.236 29.082,98.236 30.282,98.236 31.482,98.236 32.682,98.236 33.882,98.236 35.082,98.236 36.282,98.236 37.482,98.236 38.682,98.236 39.882,98.236 41.082,98.236 42.282,98.236 43.482,98.236 44.682,98.236 45.882,98.236 47.082,98.236 48.282,98.236 49.482,98.236 50.682,98.236 51.882,98.236 53.082,98.236 54.282,98.236 55.482,98.236 56.682,98.236 57.882,98.236 59.082,98.236 60.282,98.236 61.482,98.236 62.682,98.236 63.882,98.236 65.082,98.236 66.282,98.236 67.482,98.236 68.682,98.236 69.882,98.236 71.082,98.236 72.282,98.236 75.882,98.236 92.328,98.528 73.982,98.836 24.282,99.436 25.482,99.436 26.682,99.436 27.882,99.436 31.482,99.436 32.682,99.436 33.882,99.436 35.082,99.436 36.282,99.436 37.482,99.436 38.682,99.436 39.882,99.436 41.082,99.436 42.282,99.436 43.482,99.436 44.682,99.436 45.882,99.436 47.082,99.436 48.282,99.436 49.482,99.436 50.682,99.436 51.882,99.436 53.082,99.436 54.282,99.436 55.482,99.436 56.682,99.436 57.882,99.436 59.082,99.436 60.282,99.436 61.482,99.436 62.682,99.436 63.882,99.436 65.082,99.436 66.282,99.436 67.482,99.436 69.882,99.436 71.082,99.436 72.282,99.436 73.482,99.436 75.182,100.036 76.582,100.036 24.282,100.636 25.482,100.636 26.682,100.636 27.882,100.636 29.082,100.636 30.282,100.636 31.482,100.636 32.682,100.636 33.882,100.636 35.082,100.636 36.282,100.636 37.482,100.636 38.682,100.636 39.882,100.636 41.082,100.636 42.282,100.636 43.482,100.636 44.682,100.636 45.882,100.636 47.082,100.636 48.282,100.636 49.482,100.636 50.682,100.636 51.882,100.636 53.082,100.636 54.282,100.636 55.482,100.636 56.682,100.636 57.882,100.636 59.082,100.636 60.282,100.636 61.482,100.636 62.682,100.636 63.882,100.636 65.082,100.636 66.282,100.636 69.882,100.636 71.082,100.636 73.482,100.636 74.682,100.636 71.632,101.236 72.982,101.236 24.282,101.836 25.482,101.836 26.682,101.836 27.882,101.836 29.082,101.836 30.282,101.836 31.482,101.836 32.682,101.836 33.882,101.836 35.082,101.836 36.282,101.836 37.482,101.836 38.682,101.836 39.882,101.836 41.082,101.836 42.282,101.836 43.482,101.836 59.082,101.836 60.282,101.836 61.482,101.836 62.682,101.836 63.882,101.836 65.082,101.836 66.282,101.836 67.482,101.836 68.682,101.836 69.882,101.836 71.082,101.836 73.482,101.836 74.682,101.836 75.882,101.836 78.226,102.892 3.025,102.965 1.575,103.016 24.282,103.036 25.482,103.036 26.682,103.036 27.882,103.036 29.082,103.036 30.282,103.036 31.482,103.036 32.682,103.036 33.882,103.036 35.082,103.036 36.282,103.036 37.482,103.036 38.682,103.036 39.882,103.036 41.082,103.036 42.282,103.036 43.482,103.036 60.282,103.036 61.482,103.036 62.682,103.036 63.882,103.036 65.082,103.036 66.282,103.036 69.882,103.036 71.082,103.036 72.282,103.036 73.482,103.036 23.573,103.603 73.832,103.636 3.025,103.665 21.882,104.236 23.082,104.236 24.282,104.236 25.482,104.236 26.682,104.236 27.882,104.236 29.082,104.236 30.282,104.236 31.482,104.236 32.682,104.236 33.882,104.236 35.082,104.236 36.282,104.236 37.482,104.236 38.682,104.236 39.882,104.236 41.082,104.236 42.282,104.236 60.282,104.236 61.482,104.236 62.682,104.236 63.882,104.236 65.082,104.236 66.282,104.236 69.882,104.236 71.082,104.236 72.282,104.236 76.882,104.235 21.882,104.836 23.082,104.836 7.614,104.996 8.127,105.005 1,105.04 24.282,105.436 25.482,105.436 26.682,105.436 27.882,105.436 29.082,105.436 30.282,105.436 31.482,105.436 32.682,105.436 33.882,105.436 35.082,105.436 36.282,105.436 37.482,105.436 38.682,105.436 39.882,105.436 41.082,105.436 60.282,105.436 61.482,105.436 62.682,105.436 63.882,105.436 65.082,105.436 66.282,105.436 67.482,105.436 68.682,105.436 69.882,105.436 71.082,105.436 73.482,105.436 74.682,105.436 7.651,105.499 8.129,105.507 8.162,105.885 71.582,106.036 72.982,106.036 21.882,106.636 23.082,106.636 24.282,106.636 25.482,106.636 26.682,106.636 27.882,106.636 29.082,106.636 30.282,106.636 31.482,106.636 32.682,106.636 33.882,106.636 35.082,106.636 36.282,106.636 37.482,106.636 38.682,106.636 39.882,106.636 41.082,106.636 60.282,106.636 61.482,106.636 62.682,106.636 63.882,106.636 65.082,106.636 66.282,106.636 67.482,106.636 68.682,106.636 69.882,106.636 71.082,106.636 73.482,106.636 75.882,106.636 21.882,107.236 23.082,107.236 73.932,107.236 75.432,107.236 24.282,107.836 27.882,107.836 29.082,107.836 30.282,107.836 31.482,107.836 32.682,107.836 33.882,107.836 35.082,107.836 36.282,107.836 37.482,107.836 38.682,107.836 60.282,107.836 61.482,107.836 62.682,107.836 63.882,107.836 65.082,107.836 66.282,107.836 67.482,107.836 68.682,107.836 69.882,107.836 71.082,107.836 72.282,107.836 73.482,107.836 1.825,107.865 8.162,108.445 75.232,108.436 76.532,108.436 1.825,108.515 8.129,108.823 21.882,109.036 23.082,109.036 24.282,109.036 27.882,109.036 29.082,109.036 30.282,109.036 31.482,109.036 32.682,109.036 33.882,109.036 35.082,109.036 36.282,109.036 37.482,109.036 38.682,109.036 60.282,109.036 61.482,109.036 62.682,109.036 63.882,109.036 65.082,109.036 66.282,109.036 69.882,109.036 71.082,109.036 72.282,109.036 73.482,109.036 74.682,109.036 1.825,109.165 78.182,109.235 7.614,109.334 21.882,109.636 23.082,109.636 24.282,110.236 27.882,110.236 29.082,110.236 30.282,110.236 31.482,110.236 32.682,110.236 33.882,110.236 35.082,110.236 36.282,110.236 37.482,110.236 38.682,110.236 60.282,110.236 61.482,110.236 62.682,110.236 63.882,110.236 65.082,110.236 66.282,110.236 69.882,110.236 71.082,110.236 73.482,110.236 74.682,110.236 75.882,110.236 78.182,111.135 21.882,111.436 23.082,111.436 24.282,111.436 27.882,111.436 29.082,111.436 30.282,111.436 31.482,111.436 32.682,111.436 33.882,111.436 35.082,111.436 36.282,111.436 37.482,111.436 60.282,111.436 61.482,111.436 62.682,111.436 63.882,111.436 65.082,111.436 66.282,111.436 67.482,111.436 68.682,111.436 69.882,111.436 71.082,111.436 73.482,111.436 21.882,112.036 23.082,112.036 24.282,112.636 29.082,112.636 30.282,112.636 31.482,112.636 32.682,112.636 33.882,112.636 35.082,112.636 36.282,112.636 37.482,112.636 60.282,112.636 61.482,112.636 62.682,112.636 63.882,112.636 65.082,112.636 66.282,112.636 67.482,112.636 68.682,112.636 69.882,112.636 71.082,112.636 72.282,112.636 73.482,112.636 74.682,112.636 75.882,112.636 21.882,113.836 23.082,113.836 29.082,113.836 30.282,113.836 31.482,113.836 32.682,113.836 33.882,113.836 35.082,113.836 36.282,113.836 37.482,113.836 60.282,113.836 61.482,113.836 62.682,113.836 63.882,113.836 65.082,113.836 69.882,113.836 1.55,113.94 21.882,114.436 23.082,114.436 27.882,115.036 29.082,115.036 30.282,115.036 31.482,115.036 32.682,115.036 33.882,115.036 35.082,115.036 36.282,115.036 37.482,115.036 38.682,115.036 60.282,115.036 61.482,115.036 62.682,115.036 63.882,115.036 65.082,115.036 68.682,115.036 0.9,115.34 9.11,115.75 21.882,116.236 23.082,116.236 27.882,116.236 29.082,116.236 30.282,116.236 31.482,116.236 32.682,116.236 33.882,116.236 35.082,116.236 36.282,116.236 37.482,116.236 38.682,116.236 60.282,116.236 61.482,116.236 62.682,116.236 63.882,116.236 65.082,116.236 66.282,116.236 69.882,116.236 71.082,116.236 72.282,116.236 73.482,116.236 74.682,116.236 75.882,116.236 8.129,116.807 8.162,117.185 27.882,117.436 29.082,117.436 30.282,117.436 31.482,117.436 32.682,117.436 33.882,117.436 35.082,117.436 36.282,117.436 37.482,117.436 38.682,117.436 60.282,117.436 61.482,117.436 62.682,117.436 63.882,117.436 65.082,117.436 66.282,117.436 67.482,117.436 68.682,117.436 2.4,118.515 27.882,118.636 29.082,118.636 30.282,118.636 31.482,118.636 32.682,118.636 33.882,118.636 35.082,118.636 36.282,118.636 37.482,118.636 38.682,118.636 39.882,118.636 41.082,118.636 42.282,118.636 43.482,118.636 44.682,118.636 45.882,118.636 47.082,118.636 48.282,118.636 49.482,118.636 50.682,118.636 60.282,118.636 61.482,118.636 62.682,118.636 63.882,118.636 65.082,118.636 66.282,118.636 67.482,118.636 68.682,118.636 69.882,118.636 71.082,118.636 72.282,118.636 73.482,118.636 74.682,118.636 75.882,118.636 1.825,119.165 7.662,119.745 8.162,119.745 27.882,119.836 29.082,119.836 30.282,119.836 31.482,119.836 32.682,119.836 33.882,119.836 35.082,119.836 36.282,119.836 37.482,119.836 38.682,119.836 39.882,119.836 41.082,119.836 42.282,119.836 43.482,119.836 44.682,119.836 45.882,119.836 47.082,119.836 48.282,119.836 49.482,119.836 50.682,119.836 51.882,119.836 53.082,119.836 54.282,119.836 55.482,119.836 56.682,119.836 57.882,119.836 59.082,119.836 60.282,119.836 61.482,119.836 62.682,119.836 63.882,119.836 65.082,119.836 66.282,119.836 67.482,119.836 68.682,119.836 1.825,119.865 7.651,120.131 1.825,120.565 7.614,120.634 1,120.728 27.882,121.036 29.082,121.036 30.282,121.036 31.482,121.036 32.682,121.036 33.882,121.036 35.082,121.036 36.282,121.036 37.482,121.036 38.682,121.036 39.882,121.036 41.082,121.036 42.282,121.036 43.482,121.036 44.682,121.036 45.882,121.036 47.082,121.036 48.282,121.036 49.482,121.036 50.682,121.036 51.882,121.036 53.082,121.036 54.282,121.036 55.482,121.036 56.682,121.036 57.882,121.036 59.082,121.036 60.282,121.036 61.482,121.036 62.682,121.036 63.882,121.036 65.082,121.036 66.282,121.036 67.482,121.036 71.082,121.036 72.282,121.036 73.482,121.036 74.682,121.036 75.882,121.036 25.482,122.236 27.882,122.236 29.082,122.236 30.282,122.236 31.482,122.236 32.682,122.236 33.882,122.236 35.082,122.236 36.282,122.236 37.482,122.236 38.682,122.236 39.882,122.236 41.082,122.236 42.282,122.236 43.482,122.236 44.682,122.236 45.882,122.236 47.082,122.236 48.282,122.236 49.482,122.236 50.682,122.236 51.882,122.236 53.082,122.236 54.282,122.236 55.482,122.236 56.682,122.236 57.882,122.236 59.082,122.236 60.282,122.236 61.482,122.236 62.682,122.236 63.882,122.236 65.082,122.236 66.282,122.236 67.482,122.236 71.082,122.236 72.282,122.236 24.282,123.436 27.882,123.436 29.082,123.436 30.282,123.436 31.482,123.436 32.682,123.436 33.882,123.436 35.082,123.436 36.282,123.436 37.482,123.436 38.682,123.436 39.882,123.436 41.082,123.436 42.282,123.436 43.482,123.436 44.682,123.436 45.882,123.436 47.082,123.436 48.282,123.436 49.482,123.436 50.682,123.436 51.882,123.436 53.082,123.436 54.282,123.436 55.482,123.436 56.682,123.436 57.882,123.436 59.082,123.436 60.282,123.436 61.482,123.436 62.682,123.436 63.882,123.436 65.082,123.436 66.282,123.436 71.082,123.436 82.602,124.236 21.882,124.636 27.882,124.636 29.082,124.636 30.282,124.636 31.482,124.636 32.682,124.636 33.882,124.636 35.082,124.636 36.282,124.636 37.482,124.636 38.682,124.636 39.882,124.636 41.082,124.636 42.282,124.636 43.482,124.636 44.682,124.636 45.882,124.636 47.082,124.636 48.282,124.636 49.482,124.636 50.682,124.636 51.882,124.636 53.082,124.636 54.282,124.636 55.482,124.636 56.682,124.636 57.882,124.636 59.082,124.636 60.282,124.636 61.482,124.636 62.682,124.636 63.882,124.636 65.082,124.636 66.282,124.636 84.902,124.636 81.754,125.085 84.054,125.485 23.082,125.836 24.282,125.836 25.482,125.836 26.682,125.836 27.882,125.836 29.082,125.836 30.282,125.836 31.482,125.836 32.682,125.836 33.882,125.836 35.082,125.836 36.282,125.836 37.482,125.836 38.682,125.836 39.882,125.836 41.082,125.836 47.082,125.836 48.282,125.836 49.482,125.836 50.682,125.836 51.882,125.836 53.082,125.836 54.282,125.836 55.482,125.836 56.682,125.836 57.882,125.836 59.082,125.836 60.282,125.836 61.482,125.836 62.682,125.836 63.882,125.836 65.082,125.836 66.282,125.836 67.482,125.836 68.682,125.836 82.702,126.936 23.082,127.036 25.482,127.036 26.682,127.036 27.882,127.036 29.082,127.036 30.282,127.036 31.482,127.036 32.682,127.036 33.882,127.036 35.082,127.036 36.282,127.036 37.482,127.036 38.682,127.036 39.882,127.036 41.082,127.036 56.682,127.036 57.882,127.036 59.082,127.036 60.282,127.036 61.482,127.036 62.682,127.036 63.882,127.036 65.082,127.036 66.282,127.036 67.482,127.036 68.682,127.036 69.882,127.036 80.102,127.236 81.854,127.785 79.254,128.085 24.282,128.236 25.482,128.236 26.682,128.236 27.882,128.236 29.082,128.236 30.282,128.236 31.482,128.236 32.682,128.236 33.882,128.236 35.082,128.236 36.282,128.236 37.482,128.236 38.682,128.236 39.882,128.236 41.082,128.236 59.082,128.236 60.282,128.236 61.482,128.236 62.682,128.236 63.882,128.236 65.082,128.236 66.282,128.236 67.482,128.236 68.682,128.236 69.882,128.236 71.082,128.236 85.902,128.836 16.149,128.899 23.082,129.436 24.282,129.436 25.482,129.436 26.682,129.436 27.882,129.436 29.082,129.436 30.282,129.436 31.482,129.436 32.682,129.436 33.882,129.436 35.082,129.436 36.282,129.436 37.482,129.436 38.682,129.436 39.882,129.436 42.282,129.436 57.882,129.436 59.082,129.436 60.282,129.436 61.482,129.436 62.682,129.436 63.882,129.436 65.082,129.436 66.282,129.436 67.482,129.436 68.682,129.436 69.882,129.436 71.082,129.436 72.282,129.436 85.054,129.685 18.439,130.124 19.239,130.124 21.882,130.636 23.082,130.636 24.282,130.636 25.482,130.636 26.682,130.636 27.882,130.636 29.082,130.636 30.282,130.636 31.482,130.636 32.682,130.636 33.882,130.636 35.082,130.636 36.282,130.636 37.482,130.636 38.682,130.636 39.882,130.636 41.082,130.636 57.882,130.636 59.082,130.636 60.282,130.636 61.482,130.636 62.682,130.636 63.882,130.636 65.082,130.636 66.282,130.636 67.482,130.636 72.282,130.636 14.574,130.724 21.882,131.836 23.082,131.836 24.282,131.836 25.482,131.836 26.682,131.836 27.882,131.836 29.082,131.836 30.282,131.836 31.482,131.836 32.682,131.836 33.882,131.836 35.082,131.836 36.282,131.836 37.482,131.836 38.682,131.836 39.882,131.836 41.082,131.836 45.882,131.836 48.282,131.836 49.482,131.836 50.682,131.836 51.882,131.836 53.082,131.836 54.282,131.836 55.482,131.836 56.682,131.836 57.882,131.836 59.082,131.836 60.282,131.836 61.482,131.836 62.682,131.836 63.882,131.836 65.082,131.836 66.282,131.836 67.482,131.836 72.282,131.836 73.482,131.836 74.682,131.836 75.882,131.836 44.432,132.436 45.932,132.436 47.032,132.436 48.532,132.436 56.682,132.436 57.882,132.436 59.082,132.436 60.282,132.436 21.882,133.036 23.082,133.036 24.282,133.036 25.482,133.036 26.682,133.036 27.882,133.036 29.082,133.036 30.282,133.036 31.482,133.036 32.682,133.036 33.882,133.036 35.082,133.036 36.282,133.036 37.482,133.036 39.882,133.036 42.282,133.036 43.482,133.036 44.682,133.036 47.082,133.036 49.482,133.036 51.882,133.036 54.282,133.036 56.682,133.036 59.082,133.036 61.482,133.036 62.682,133.036 65.082,133.036 67.482,133.036 68.682,133.036 69.882,133.036 72.282,133.036 73.482,133.036 74.682,133.036 75.882,133.036 37.932,133.636 39.432,133.636 40.332,133.636 41.832,133.636 43.282,133.636 44.782,133.636 45.682,133.636 47.182,133.636 48.232,133.636 49.732,133.636 50.082,133.636 51.282,133.636 53.156,133.627 54.882,133.636 56.059,133.636 59.282,133.636 61.531,133.619 51.91,133.642 62.681,133.654 21.882,134.236 23.082,134.236 24.282,134.236 25.482,134.236 31.482,134.236 32.682,134.236 36.282,134.236 43.482,134.236 62.682,134.236 66.282,134.236 72.282,134.236 73.482,134.236 74.682,134.236 75.882,134.236 36.732,134.836 38.232,134.836 39.132,134.836 40.632,134.836 51.282,134.836 52.482,134.836 56.082,134.836 57.282,134.836 23.082,135.436 24.282,135.436 25.482,135.436 31.482,135.436 36.282,135.436 38.682,135.436 41.082,135.436 43.482,135.436 45.882,135.436 48.282,135.436 50.682,135.436 53.082,135.436 55.482,135.436 57.882,135.436 60.282,135.436 62.682,135.436 68.682,135.436 72.282,135.436 73.482,135.436 74.682,135.436 46.232,135.936 57.282,136.036 58.482,136.036 47.081,136.785 50.282,136.936 51.482,136.936 52.082,136.936 53.282,136.936 62.556,137.113 44.708,137.328 45.906,137.33 60.449,137.523 61.432,137.536 62.432,137.536 59.982,137.686 58.832,137.836 63.422,137.979 39.832,138.336 41.332,138.336 78.442,138.392 45.582,138.491 46.082,138.491 68.782,138.491 69.282,138.491 53.904,139.041 77.593,139.241 66.021,139.291 46.582,140.141 47.582,140.141 48.582,140.141 49.582,140.141 50.582,140.141 58.182,140.141 59.182,140.141 60.182,140.141 61.182,140.141 62.182,140.141 69.782,140.141 70.782,140.141 71.782,140.141 72.782,140.141 73.782,140.141 53.904,140.24 9.553,141.203 66.021,141.191 76.485,142.3 68.43,142.504 60.05,142.515 64.845,142.713 66.804,142.84 70.648,143.092 73.236,143.149 74.436,143.149 75.636,143.149 69.572,143.21 55.804,143.34 56.504,143.34 58.873,143.359 48.703,143.383 72.036,143.549 73.236,143.549 58.304,143.64 47.21,143.844 20.625,143.891 65.7,144 74.74,144.117 48.061,144.35 56.446,144.859 69.143,144.897 64.648,144.95 16.925,144.991 63.716,145.04 21.794,145.06 67.443,145.197 72.393,145.206 42.995,145.282 55.887,145.469 73.908,145.58 55.505,145.726 54.741,145.783 53.158,145.797 70.747,145.858 50.297,145.969 18.094,146.16 44.394,146.526 53.13,146.526 65.413,146.608 43.023,146.643 67.861,146.701 51.538,146.738 42.409,147.011 41.403,147.193 66.312,147.201 64.143,147.482 13.126,147.852 14.779,147.852 62.506,147.89 44.398,148.032 64.121,148.036 48.855,148.201 40.985,148.228 64.035,148.679 9.086,148.71 48.215,148.775 41.926,149.131 45.938,149.258 47.363,149.261 48.215,149.471 62.889,149.526 61.611,149.544 78.463,150.113 62.884,150.343 13.048,150.45 16.048,150.45 17.701,150.45 75.1,150.6 76.649,150.6 14.701,150.65 73.628,150.651 9.786,150.7 10.436,150.7 11.036,150.7 11.686,150.7 12.336,150.7 72,150.7 78.768,151.474 23.031,151.987 62.567,152.133 35.395,152.57 53.782,152.752 27.959,153.366 33.911,154.056 30.4,154.465 32.1,154.465 36.728,154.977 38.8,155.365 40.5,155.365 36.659,156.584 45.689,156.765 47.289,156.765 46.139,157.215 46.839,157.215 11.224,157.725 25.524,157.725 39.224,157.725 53.524,157.725 67.224,157.725 81.524,157.725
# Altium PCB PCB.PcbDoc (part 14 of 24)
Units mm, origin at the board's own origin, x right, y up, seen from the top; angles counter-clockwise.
Board outline 100 x 160 mm, 10 copper layers (TOP_L1, L2, L3, L4, L5, L6, L7, L8, L9, BOTTOM_L10), stack 1.946 mm thick; 1358 components, 1149 nets, 6777 pads, 10914 vias.

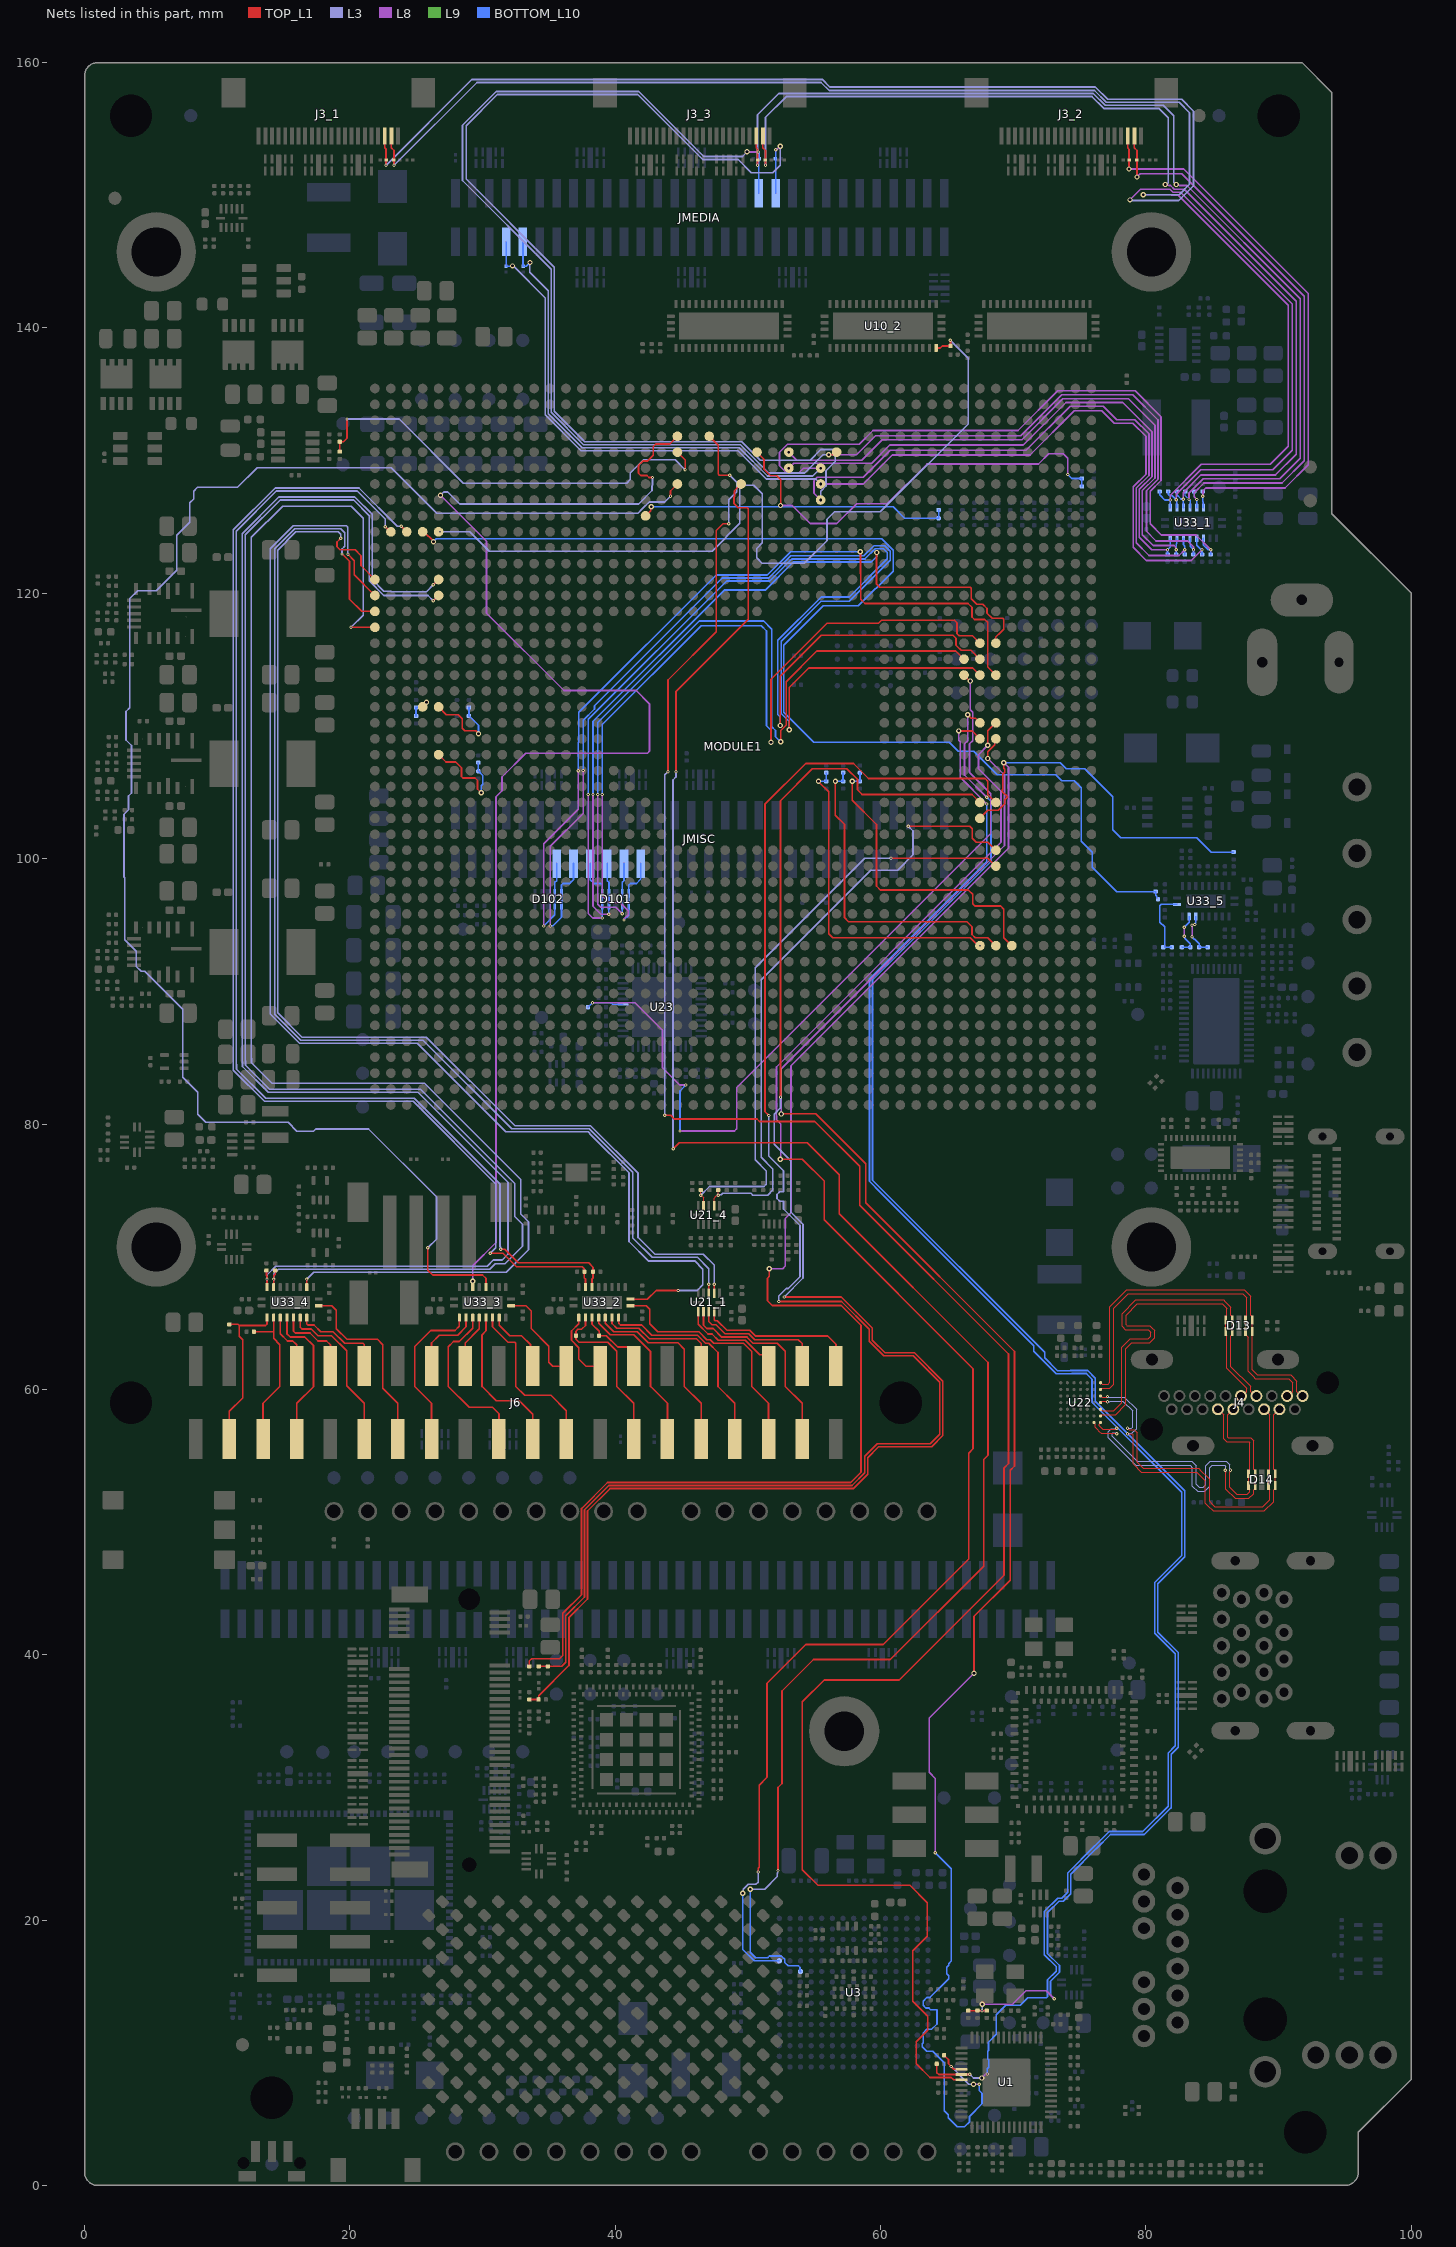
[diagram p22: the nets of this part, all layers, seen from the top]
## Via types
v1: diameter 0.25, hole 0.1, TOP_L1 to L2, tented both sides, 3439 vias
v2: diameter 0.25, hole 0.1, L2 to L3, tented both sides, 2256 vias
v3: diameter 0.25, hole 0.1, L9 to BOTTOM_L10, tented both sides, 1685 vias
v4: diameter 0.25, hole 0.1, L8 to L9, tented both sides, 1675 vias
v5: diameter 0.4, hole 0.2, L3 to L8, tented both sides, 1251 vias
v6: diameter 0.6, hole 0.3, TOP_L1 to BOTTOM_L10, tented both sides, 600 vias
v7: diameter 0.24, hole 0.1, TOP_L1 to L2, tented both sides, 8 vias

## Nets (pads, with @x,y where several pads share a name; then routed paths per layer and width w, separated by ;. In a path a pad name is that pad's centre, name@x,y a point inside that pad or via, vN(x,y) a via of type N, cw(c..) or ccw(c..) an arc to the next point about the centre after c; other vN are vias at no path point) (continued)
GPIO_0: MODULE1.AY17 R319.2 U21_4.2 | length 47.3
  TOP_L1 w0.084: U21_4.2@47.45,73.841 47.45,74.399 47.628,74.577 47.64,74.577 47.705,74.641 v1(47.75,74.641) R319.2@47.75,75.016
  TOP_L1 w0.127: v2(62.082,102.436) 66.728,102.436 66.91,102.253 66.91,101.544 67.217,101.237 68.081,101.237 MODULE1.AY17@68.682,100.636
  L3 w0.127: v1(47.75,74.641) 47.774,74.665 47.974,74.665 48.092,74.784 50.224,74.784 50.366,74.641 51.484,74.641 51.868,75.026 51.868,76.609 50.995,77.482 50.995,90.882 59.249,99.136 61.282,99.136 62.435,100.289 62.435,102.083 v2(62.082,102.436)
  other v1: 62.082,102.436
  other v2: 47.75,74.641
GPIO_2: MODULE1.AY16 R321.2 U21_4.4 | length 45
  TOP_L1 w0.084: R321.2@46.45,75.016 v2(46.45,74.641) 46.65,74.441 U21_4.4@46.65,73.841
  TOP_L1 w0.127: v1(60.782,100.036) 68.082,100.036 MODULE1.AY16@68.682,99.436
  L3 w0.127: v2(46.45,74.641) 47.1,75.291 51.214,75.291 51.373,75.45 51.373,76.462 50.541,77.294 50.541,91.777 58.8,100.036 v1(60.782,100.036)
  other v1: 46.45,74.641
  other v2: 60.782,100.036
GPIO_4: MODULE1.AW25 R284.1 R285.1 R413.1 | length 129.6
  TOP_L1 w0.127: v5(66.569,110.836) 66.835,110.57 67.148,110.57 MODULE1.AW25@67.482,110.236 ; R413.1@66.6,13.175 R284.1@67.3,13.175 v1(67.643,13.175) R285.1@68,13.175
  L3 w0.127: v1(67.643,13.175) 67.65,13.182 67.65,13.646 v5(67.657,13.653)
  L8 w0.127: v5(66.569,110.836) 66.569,108.895 66.322,108.649 66.322,106.308 v4(68.005,104.625) ; v5(67.657,13.653) 69.933,13.653 70.954,14.675 72.473,14.675 v4(73.073,14.075)
  BOTTOM_L10 w0.127: v4(68.005,104.625) 68.323,104.306 68.323,99.783 59.39,90.85 59.39,75.768 72.372,62.786 72.372,62.371 73.33,61.413 74.304,61.413 74.305,61.415 75.609,61.415 76.177,60.847 76.177,59.111 82.929,52.358 82.929,47.389 80.889,45.348 80.889,41.704 82.43,40.162 82.43,33.033 81.894,32.496 81.894,28.478 81.752,28.336 79.86,26.444 77.33,26.444 76.251,25.366 76.235,25.366 74.323,23.454 74.323,21.994 73.755,21.426 73.737,21.426 73.733,21.423 73.447,21.423 72.57,20.546 72.57,17.486 73.475,16.581 73.475,16.069 72.803,15.397 72.803,14.345 v4(73.073,14.075)
  other v1: 66.569,110.836
  other v2: 67.643,13.175 66.569,110.836
  other v3: 73.073,14.075 68.005,104.625
GPIO_5: MODULE1.AY24 R266.1 U1.33 | length 137.6
  TOP_L1 w0.127: v2(52.506,80.753) 52.521,80.768 55.101,80.768 58.874,76.996 58.874,74.065 70.086,62.853 70.086,54.219 69.758,53.892 69.758,45.616 67.035,42.892 v5(67.035,38.598) ; R266.1@64.779,9.813 64.779,9.807 64.88,9.707 64.885,9.707 65.034,9.558 ; 65.038,9.558 65.112,9.484 65.112,9.16 65.513,8.759 U1.33@66.106,8.759 ; v5(68.082,107.549) 68.082,108.055 68.607,108.58 68.607,108.961 MODULE1.AY24@68.682,109.036
  L3 w0.127: v1(65.313,8.959) 66.643,7.629 v5(66.995,7.629)
  L8 w0.127: v2(52.506,80.753) 52.506,84.16 69.333,100.987 69.333,106.299 v5(68.082,107.549) ; v3(64.123,25.075) 64.123,30.675 63.661,31.137 63.661,35.225 v5(67.035,38.598) ; v5(66.995,7.629) v3(67.441,7.629)
  BOTTOM_L10 w0.127: v3(64.123,25.075) 65.323,23.875 65.323,16.915 65.126,16.717 65.126,16.599 64.975,16.447 64.975,15.959 65.126,15.808 65.126,15.578 63.714,14.165 63.486,14.165 63.2,13.88 63.2,13.578 63.413,13.365 63.641,13.365 63.756,13.25 64.242,13.25 64.242,12.171 63.837,11.766 63.486,11.766 63.2,11.48 63.2,10.751 63.136,10.687 63.136,10.442 63.471,10.107 63.935,10.107 64.784,9.258 64.784,5.639 65.091,5.333 65.091,5.091 65.765,4.417 66.315,4.417 66.703,4.805 66.703,5.203 67.644,6.144 67.644,6.951 67.441,7.155 v3(67.441,7.629)
  other v1: 67.035,38.598 52.506,80.753 68.082,107.549
  other v2: 65.313,8.959 67.035,38.598 68.082,107.549
  other v4: 67.441,7.629 64.123,25.075
  other v5: 52.506,80.753
GPIO_6: MODULE1.AW24 R267.1 U1.34 | length 134.8
  TOP_L1 w0.127: R267.1@64.229,9.163 64.229,8.501 64.371,8.359 U1.34@66.106,8.359 66.111,8.364 66.702,8.364 v2(66.715,8.376) ; v5(65.876,109.628) 66.89,109.628 MODULE1.AW24@67.482,109.036
  L3 w0.127: v2(66.715,8.376) 67,8.091 v5(67.611,8.091)
  L8 w0.127: v5(65.876,109.628) 65.876,108.932 65.988,108.819 65.988,106.141 v3(68.005,104.125) ; v5(67.611,8.091) 67.611,8.143 67.679,8.143 67.928,8.392 v3(68.032,8.392)
  BOTTOM_L10 w0.127: v3(68.005,104.125) 68.005,99.786 59.163,90.944 59.163,75.674 59.972,74.865 71.543,63.294 71.543,62.879 73.236,61.186 74.398,61.186 74.4,61.188 75.515,61.188 75.93,60.773 75.93,59.026 82.702,52.254 82.702,47.483 80.662,45.442 80.662,41.61 82.203,40.068 82.203,33.127 81.667,32.59 81.667,28.572 79.766,26.671 77.236,26.671 76.157,25.593 76.141,25.593 74.096,23.548 74.096,22.088 73.661,21.653 73.356,21.653 72.343,20.64 72.343,17.392 73.239,16.496 73.239,16.154 72.576,15.491 72.576,14.209 72.501,14.134 71.08,14.134 70.532,13.586 69.435,13.586 68.723,12.874 68.723,11.395 68.123,10.796 68.123,10.168 68.082,10.127 68.082,9.532 68.144,9.469 68.144,8.918 68.032,8.806 v3(68.032,8.392)
  other v1: 66.715,8.376 65.876,109.628
  other v2: 65.876,109.628
  other v4: 68.032,8.392 68.005,104.125
GPIO_7: MODULE1.BA11 R13.2 R28.2 | length 23.6
  TOP_L1 w0.127: v3(57.861,105.835) 57.861,104.4 59.682,102.579 59.682,97.936 59.982,97.636 66.61,97.636 66.932,97.315 66.932,96.596 67.091,96.436 69.042,96.436 69.282,96.196 69.282,94.036 MODULE1.BA11@69.882,93.436
  BOTTOM_L10 w0.127: v3(57.861,105.835) 57.869,105.828 R13.2@58.439,105.828 R28.2@58.439,106.478
  other v1: 57.861,105.835
  other v2: 57.861,105.835
  other v4: 57.861,105.835
  other v5: 57.861,105.835
GPIO_8: MODULE1.AY11 R15.2 R30.2 | length 24.4
  TOP_L1 w0.127: v1@56.586,105.83 v4(56.591,105.835) ; v1@56.586,105.835 56.586,103.275 57.282,102.579 57.282,95.536 57.582,95.236 66.513,95.236 66.882,94.867 66.882,94.28 67.126,94.036 68.082,94.036 MODULE1.AY11@68.682,93.436
  BOTTOM_L10 w0.127: v4(56.591,105.835) 56.599,105.828 R15.2@57.169,105.828 R30.2@57.169,106.478
  other v1: 56.591,105.835
  other v2: 56.591,105.835
  other v3: 56.591,105.835
  other v5: 56.591,105.835
GPIO_21: MODULE1.AW19 R414.1 R417.2 | length 132
  TOP_L1 w0.1: MODULE1.AW19@67.482,103.036 68.081,103.635 68.882,103.635 69.367,104.12 69.367,104.449 69.567,104.65 69.182,105.035 69.182,105.208 69.197,105.223 69.197,106.35 69.367,106.52 69.367,106.735 69.282,106.82 v4(69.282,107.235)
  TOP_L1 w0.127: R417.2@33.523,39.125 33.523,39.521 33.698,39.696 35.801,39.696 36.05,39.946 36.05,43.114 37.451,44.515 37.451,51.014 39.411,52.975 57.741,52.975 58.522,53.755 58.522,64.833 57.031,66.325 51.831,66.325 51.468,66.688 51.468,68.376 51.612,68.52 v5(51.612,69.097)
  L8 w0.127: v5(51.612,69.097) 52.609,69.097 52.814,69.303 52.814,72.875 53.239,73.3 53.239,84.393 69.633,100.787 69.633,106.884 v4(69.282,107.235)
  BOTTOM_L10 w0.1: v4(69.282,107.235) 73.544,107.235 73.994,106.785 75.396,106.785 77.503,104.678 77.503,102.178 78.089,101.592 83.807,101.592 84.901,100.497 R414.1@86.603,100.497
  other v1: 51.612,69.097 69.282,107.235
  other v2: 51.612,69.097 69.282,107.235
  other v3: 69.282,107.235
  other v5: 69.282,107.235
GPIO_22: MODULE1.AY20 R415.1 R418.2 | length 123.7
  TOP_L1 w0.127: R418.2@34.223,39.125 R415.1@34.923,39.125 35.959,39.125 36.277,39.443 36.277,42.947 37.678,44.347 37.678,50.92 39.505,52.748 57.835,52.748 58.795,53.707 58.795,54.947 59.746,55.898 63.746,55.898 64.465,56.617 64.465,60.525 62.463,62.527 60.236,62.527 59.145,63.618 59.145,64.531 57.052,66.625 v1(52.323,66.625) ; v2(51.573,80.647) 51.277,80.943 51.277,104.096 54.346,107.165 57.953,107.165 59.082,106.036 67.882,106.036 68.082,105.836 68.082,104.836 MODULE1.AY20@68.682,104.236
  L3 w0.127: v2(51.573,80.647) 51.573,77.593 52.68,76.486 52.68,74.896 52.405,74.896 52.192,74.683 52.192,74.382 52.405,74.169 52.68,74.169 52.68,73.589 53.924,72.345 53.924,68.485 53.038,67.598 52.889,67.598 52.323,67.033 v1(52.323,66.625)
  other v1: 51.573,80.647
  other v2: 52.323,66.625
GPIO_23: MODULE1.AW20 R416.1 R419.2 | length 122.2
  TOP_L1 w0.127: R419.2@33.523,36.625 R416.1@34.223,36.625 34.223,36.909 36.504,39.19 36.504,42.797 37.905,44.198 37.905,50.826 39.6,52.521 57.929,52.521 59.022,53.613 59.022,54.853 59.84,55.671 63.84,55.671 64.692,56.523 64.692,60.619 62.557,62.754 60.33,62.754 59.372,63.712 59.372,64.625 57.033,66.964 v1(52.725,66.964) ; v1(52.453,82.017) 52.453,104.372 54.853,106.772 57.453,106.772 58.253,105.972 58.253,105.184 58.601,104.836 66.882,104.836 MODULE1.AW20@67.482,104.236
  L3 w0.127: v1(52.453,82.017) 52.453,81.214 51.971,80.733 51.971,78.478 53.223,77.227 53.223,73.367 54.151,72.439 54.151,68.391 v1(52.725,66.964)
  other v2: 52.725,66.964 52.453,82.017
GPIO_50: MODULE1.AB43 U1.35 | length 166.5
  TOP_L1 w0.127: v1(43.736,80.656) 44.175,80.656 44.456,80.375 50.686,80.375 50.871,80.19 55.037,80.19 58.42,76.808 58.42,74.083 58.42,73.877 69.632,62.665 69.632,54.407 69.304,54.08 69.304,46.007 61.393,38.095 55.739,38.095 54.1,36.456 54.1,23.798 55.278,22.62 62.21,22.62 63.523,21.307 63.523,18.777 62.423,17.677 62.423,13.876 63.548,12.751 63.548,11.699 62.684,10.835 62.684,9.172 63.724,8.132 65.328,8.132 65.501,7.959 U1.35@66.106,7.959 ; v1(43.969,106.549) 43.969,113.469 47.611,117.111 47.611,124.736 48.116,125.241 v2(48.551,125.241) ; MODULE1.AB43@47.082,131.836 47.755,131.163 47.755,130.856 47.754,130.855 47.754,130.317 47.759,130.311 47.759,129.66 47.754,129.655 47.754,128.987 47.833,128.908 v1(48.625,128.908)
  L3 w0.127: v1(43.736,80.656) 43.736,106.316 v1(43.969,106.549) ; v2(48.551,125.241) 48.551,127.04 49.161,127.651 49.161,128.372 v1(48.625,128.908)
  other v1: 48.551,125.241
  other v2: 43.736,80.656 43.969,106.549 48.625,128.908
GPIO_53: MODULE1.AW11 R12.2 R27.2 | length 24.8
  TOP_L1 w0.127: v2(55.321,105.835) 55.321,105.804 56.082,105.043 56.082,94.336 56.382,94.036 66.744,94.036 67.344,93.436 v1(67.482,93.436)
  BOTTOM_L10 w0.127: v2(55.321,105.835) 55.329,105.828 R12.2@55.899,105.828 R27.2@55.899,106.478
  other v1: 55.321,105.835
  other v3: 55.321,105.835
  other v4: 55.321,105.835
  other v5: 55.321,105.835
GPIO_66: MODULE1.Y42 R14.2 R29.2 | length 33.2
  TOP_L1 w0.127: R29.2@19.239,130.674 R14.2@19.239,131.424 19.509,131.424 19.782,131.697 v1(19.782,133.136) ; MODULE1.Y42@44.682,130.636 45.271,130.047 45.271,129.33 v2(45.261,129.32)
  L3 w0.127: v1(19.782,133.136) 23.706,133.136 28.547,128.295 40.859,128.295 41.135,128.571 41.135,129.062 42.141,130.068 44.511,130.068 45.258,129.32 v2(45.261,129.32)
  other v1: 45.261,129.32
  other v2: 19.782,133.136
GPIO_76: MODULE1.V38 R2.2 R17.2 | length 23.6
  TOP_L1 w0.127: MODULE1.V38@42.286,125.775 42.286,125.84 42.666,126.22 42.666,126.485 v3(42.702,126.52)
  BOTTOM_L10 w0.127: v3(42.702,126.52) 60.938,126.52 61.802,125.656 R17.2@64.369,125.656 R2.2@64.369,126.278
  other v1: 42.702,126.52
  other v2: 42.702,126.52
  other v4: 42.702,126.52
  other v5: 42.702,126.52
GPIO_91: MODULE1.AE42 R1.2 R16.2 | length 32.6
  TOP_L1 w0.127: MODULE1.AE42@50.682,130.636 51.211,130.108 51.211,129.348 51.699,128.859 52.177,128.859 52.476,128.56 52.476,126.64 v5(52.454,126.619)
  L8 w0.127: v5(52.454,126.619) 53.34,126.619 54.702,125.256 56.702,125.256 58.202,126.756 60.502,126.756 63.488,129.742 71.902,129.742 72.675,130.515 73.755,130.515 74.102,130.168 v3(74.102,128.956)
  BOTTOM_L10 w0.127: v3(74.102,128.956) 74.407,128.651 R16.2@75.169,128.651 R1.2@75.169,128.051
  other v1: 52.454,126.619
  other v2: 52.454,126.619
  other v4: 74.102,128.956
GPIO_97: MODULE1.E26 R3.2 R18.2 | length 6.5
  TOP_L1 w0.127: MODULE1.E26@26.682,111.436 27.269,110.849 28.169,110.849 28.469,110.549 28.469,109.823 28.657,109.636 29.476,109.636 v5(29.687,109.425)
  BOTTOM_L10 w0.127: R3.2@28.969,110.749 R18.2@28.969,111.399 ; R3.2@28.984,110.749 29.687,110.046 v5(29.687,109.425)
  other v1: 29.687,109.425
  other v2: 29.687,109.425
  other v3: 29.687,109.425
  other v4: 29.687,109.425
GPIO_98: MODULE1.E23 R4.2 R19.2 | length 7.6
  TOP_L1 w0.127: MODULE1.E23@26.682,107.836 27.24,107.279 27.987,107.279 28.411,106.855 28.411,106.189 28.522,106.077 29.425,106.077 29.611,105.892 29.611,105.254 v4(29.9,104.965)
  BOTTOM_L10 w0.127: R19.2@29.656,107.209 29.682,107.183 R4.2@29.682,106.586 29.697,106.586 30.016,106.268 30.016,105.598 29.9,105.482 v4(29.9,104.965)
  other v1: 29.9,104.965
  other v2: 29.9,104.965
  other v3: 29.9,104.965
  other v5: 29.9,104.965
GPIO_102: MODULE1.D26 R5.2 R20.2 | length 2.1
  TOP_L1 w0.127: MODULE1.D26@25.482,111.436 25.475,111.443 25.766,111.734 v5(25.766,111.795)
  BOTTOM_L10 w0.127: R5.2@24.982,110.749 R20.2@24.982,111.399 25.401,111.399 25.766,111.764 v5(25.766,111.795)
  other v1: 25.766,111.795
  other v2: 25.766,111.795
  other v3: 25.766,111.795
  other v4: 25.766,111.795
HDMI_CLK_N: D14.5 D14.6 J4.12 U22.B7 | length 27.5
  TOP_L1 w0.086: U22.B7@76.075,57.5 76.075,57.47 76.173,57.373 76.173,57.139 76.311,57 76.45,56.861 76.629,56.682 77.787,56.682 v1@77.801,56.669 ; J4.12@85.42,58.5 85.848,58.072 85.848,56.274 86.077,56.045 87.777,56.045 87.828,55.995 87.828,53.973 87.73,53.875 D14.5@87.73,53.789 ; v2(86.375,53.9) 86.344,53.869 86.344,53.784 86.327,53.768 86.327,52.611 86.857,52.082 87.634,52.082 87.828,52.276 87.828,52.427 87.73,52.525 D14.6@87.73,52.763 D14.5@87.73,53.638
  L3 w0.084: v1(77.801,56.664) 77.769,56.696 77.684,56.696 77.669,56.711 77.504,56.711 77.455,56.662 77.455,56.479 79.35,54.583 83.448,54.583 83.8,54.231 83.8,52.833 84.013,52.62 84.308,52.62 84.495,52.807 84.495,54.226 84.852,54.583 86.048,54.583 86.327,54.304 86.327,54.032 86.343,54.016 86.343,53.932 v2(86.375,53.9)
  other v1: 86.375,53.9
  other v2: 77.801,56.664
HDMI_CLK_P: D14.4 D14.7 J4.10 U22.A7 | length 28.5
  TOP_L1 w0.086: U22.A7@76.575,57.5 76.575,57.47 76.477,57.373 76.477,57.265 76.742,57 76.755,56.987 77.675,56.987 77.757,57.069 v1@77.801,57.069 ; v2(85.975,53.9) 86.006,53.869 86.006,53.784 86.023,53.768 86.023,52.485 86.73,51.777 87.76,51.777 88.133,52.149 88.133,52.427 88.23,52.525 D14.7@88.23,52.763 D14.4@88.23,53.638 ; J4.10@86.58,58.5 86.152,58.072 86.152,56.401 86.203,56.35 87.904,56.35 88.133,56.121 88.133,53.973 88.191,53.915 D14.4@88.23,53.915
  L3 w0.084: v1(77.801,57.064) 77.769,57.032 77.684,57.032 77.669,57.016 77.378,57.016 77.15,56.789 77.15,56.353 79.224,54.278 83.322,54.278 83.495,54.105 83.495,52.706 83.887,52.315 84.434,52.315 84.8,52.681 84.8,54.1 84.978,54.278 85.922,54.278 86.023,54.177 86.023,54.032 86.007,54.016 86.007,53.932 v2(85.975,53.9)
  other v1: 85.975,53.9
  other v2: 77.801,57.064
HDMI_TX0_N: D13.5 D13.6 J4.9 U22.A6 | length 28.2
  TOP_L1 w0.086: U22.A6@76.575,58 76.605,58 76.702,58.098 77.701,58.098 78.48,58.876 78.48,63.055 78.925,63.5 80.27,63.5 80.465,63.695 80.655,63.884 80.655,64.446 80.481,64.619 80.295,64.805 78.561,64.805 78.5,64.866 78.5,65.58 79.359,66.439 85.736,66.439 86.075,66.1 86.1,66.075 86.1,65.572 86.002,65.475 D13.5@86.002,65.237 D13.6@86.002,64.362 86.002,64.125 86.1,64.027 86.1,61.588 87.588,60.1 87.588,60.018 87.588,59.82 87.267,59.5 J4.9@87.16,59.5
HDMI_TX0_P: D13.4 D13.7 J4.7 U22.A5 | length 28.7
  TOP_L1 w0.086: U22.A5@76.575,58.5 76.605,58.5 76.702,58.402 77.075,58.402 77.575,58.402 78.175,59.002 78.175,63.181 78.799,63.805 80.144,63.805 80.161,63.821 80.35,64.011 80.35,64.319 80.176,64.493 80.169,64.5 78.434,64.5 78.195,64.739 78.195,65.706 79.233,66.743 85.863,66.743 85.952,66.654 86.405,66.201 86.405,65.572 86.502,65.475 D13.4@86.502,65.237 D13.7@86.502,64.362 86.502,64.125 86.405,64.027 86.405,61.714 87.892,60.226 87.892,59.892 87.892,59.82 88.213,59.5 J4.7@88.32,59.5
HDMI_TX1_N: D14.2 D14.9 J4.6 U22.A4 | length 27.2
  TOP_L1 w0.086: U22.A4@76.575,59 76.605,59 76.702,59.098 76.966,59.098 76.982,59.081 77.067,59.081 v1@77.099,59.05 ; v1@78.601,57.069 78.638,57.069 78.733,56.974 79.108,56.974 79.337,56.745 79.337,54.505 79.787,54.055 83.963,54.055 84.141,53.876 84.61,53.407 84.789,53.228 84.789,51.55 84.989,51.35 85.2,51.139 88.802,51.139 89.328,51.666 89.328,52.427 89.23,52.525 D14.9@89.23,52.763 D14.2@89.23,53.638 89.23,53.875 89.328,53.973 89.328,55.971 89.328,58.072 J4.6@88.9,58.5
  L3 w0.084: v1(77.099,59.055) 77.111,59.067 77.259,59.067 77.295,59.103 78.253,59.103 78.983,58.373 78.983,57.155 78.891,57.064 v1(78.601,57.064)
  other v2: 78.601,57.064 77.099,59.055
HDMI_TX1_P: D14.1 D14.10 J4.4 U22.A3 | length 28.7
  TOP_L1 w0.086: U22.A3@76.575,59.5 76.605,59.5 76.702,59.402 76.966,59.402 76.982,59.419 77.067,59.419 v1@77.099,59.45 ; v1@78.601,56.669 78.981,56.669 79.032,56.618 79.032,54.379 79.661,53.75 83.836,53.75 84.484,53.102 84.484,51.424 84.663,51.245 85.074,50.834 88.928,50.834 89.633,51.539 89.633,52.427 89.73,52.525 D14.10@89.73,52.763 D14.1@89.73,53.638 89.73,53.875 89.633,53.973 89.633,55.988 89.632,58.072 J4.4@90.06,58.5
  L3 w0.084: v2(77.099,59.455) 77.13,59.423 77.215,59.423 77.231,59.408 78.379,59.408 79.288,58.499 79.288,57.029 78.934,56.676 78.601,56.676 v1(78.601,56.664)
  other v1: 77.099,59.455
  other v2: 78.601,56.664
HDMI_TX2_N: D13.2 D13.9 J4.3 U22.A2 | length 28.1
  TOP_L1 w0.086: U22.A2@76.575,60 76.605,60 76.702,60.098 77.075,60.098 77.276,60.098 77.575,60.396 77.575,66.102 78.679,67.206 87.297,67.206 87.6,66.903 87.6,65.572 87.502,65.475 D13.2@87.502,65.237 87.502,64.125 87.698,63.93 87.698,61.349 88.069,60.979 88.247,60.8 90.768,60.8 91.068,60.5 91.068,60.018 91.068,59.82 90.747,59.5 J4.3@90.64,59.5
HDMI_TX2_P: D13.1 D13.10 J4.1 U22.A1 | length 28.5
  TOP_L1 w0.086: U22.A1@76.575,60.5 76.605,60.5 76.702,60.402 77.075,60.402 77.15,60.402 77.27,60.523 77.27,66.228 78.553,67.511 87.423,67.511 87.905,67.029 87.905,65.572 88.002,65.475 D13.1@88.002,65.237 88.002,61.476 88.373,61.105 90.894,61.105 91.372,60.626 91.372,59.892 91.372,59.82 91.693,59.5 J4.1@91.8,59.5
I2C1_IRQ_33: R99.1 R333.2 U33_5.20 | length 5.2
  BOTTOM_L10 w0.1: R333.2@81.953,93.322 81.403,93.322 81.403,94.856 81.053,95.206 81.053,96.436 81.162,96.545 U33_5.20@82.353,96.545
I2C1_SCL_33: R100.1 R334.2 U33_5.18 | length 3.3
  L8 w0.1: v4(82.886,94.152) v4@82.885,94.832
  BOTTOM_L10 w0.1: R334.2@82.703,93.322 R100.1@83.353,93.322 83.325,93.35 83.325,93.577 82.915,93.987 82.915,94.124 v4(82.886,94.152) ; v4(82.884,94.833) 83.253,95.201 U33_5.18@83.253,95.645
  other v3: 82.886,94.152 82.884,94.833
I2C1_SDA_33: R101.1 R335.2 U33_5.17 | length 3.4
  L8 w0.1: v4(83.465,94.109) 83.469,94.113 v4(83.469,94.981)
  L9 w0.127: v4(83.469,94.981) 83.503,94.981 83.541,95.019 83.655,95.019 v3(83.679,95.043)
  BOTTOM_L10 w0.1: v4(83.465,94.109) 83.655,93.919 83.661,93.919 84.003,93.577 R335.2@84.003,93.322 R101.1@84.653,93.322 ; v3(83.679,95.043) 83.679,95.083 83.753,95.157 U33_5.17@83.753,95.645
  other v3: 83.465,94.109
I2S_DATA0: MODULE1.A32 U21_1.3 | length 94.1
  TOP_L1 w0.127: v2(19.402,122.956) 19.422,122.956 19.969,122.409 19.969,119.549 20.882,118.636 MODULE1.A32@21.882,118.636 ; U21_1.3@47.05,67.25 v1(47.05,67.92)
  L3 w0.127: v2(19.402,122.956) 19.402,123.337 19.602,123.537 19.602,124.557 19.302,124.856 15.834,124.856 14.326,123.348 14.326,88.283 16.29,86.319 25.512,86.319 32.191,79.639 38.043,79.639 38.293,79.39 41.326,76.357 41.326,71.412 42.788,69.95 46.2,69.95 47.05,69.099 v1(47.05,67.92)
  other v1: 19.402,122.956
  other v2: 47.05,67.92
I2S_DATA1: MODULE1.A34 U21_1.2 | length 91.4
  TOP_L1 w0.127: v1(19.313,124.156) 19.025,123.868 19.025,123.502 19.246,123.281 20.388,123.281 20.829,122.84 20.829,122.089 MODULE1.A34@21.882,121.036 ; U21_1.2@47.45,67.25 v2(47.45,67.92)
  L3 w0.127: v1(19.313,124.156) 19.313,124.441 19.125,124.629 15.928,124.629 14.553,123.254 14.553,88.377 16.384,86.546 25.757,86.546 32.436,79.866 38.137,79.866 38.28,79.724 41.718,76.285 41.718,71.451 42.993,70.177 46.641,70.177 47.45,69.368 v2(47.45,67.92)
  other v1: 47.45,67.92
  other v2: 19.313,124.156
I2S_SCK: MODULE1.A31 U33_4.3 | length 107.5
  TOP_L1 w0.127: U33_4.3@16.75,67.7 v1(16.75,68.311) ; v2(20.082,117.436) MODULE1.A31@21.882,117.436
  L3 w0.127: v1(16.75,68.311) 17.27,68.831 31.772,68.831 33.457,70.515 33.457,72.633 32.878,73.212 32.878,75.813 25.615,83.075 14.123,83.075 12.578,84.62 12.578,84.953 12.573,84.957 12.573,85.591 12.573,86.198 12.573,86.777 12.573,124.216 14.928,126.572 20.087,126.572 20.992,125.666 20.992,118.346 v2(20.082,117.436)
  other v1: 20.082,117.436
  other v2: 16.75,68.311
I2S_WS: MODULE1.A33 U33_2.1 | length 98.3
  TOP_L1 w0.127: v2(19.85,122.936) 20.33,122.456 20.33,121.388 MODULE1.A33@21.882,119.836 ; U33_2.1@41.15,66.8 42.42,66.8 43.076,67.456 44.727,67.456 v2(44.739,67.444)
  L3 w0.127: v2(19.85,122.936) 19.829,122.957 19.829,124.99 19.735,125.083 15.729,125.083 14.002,123.356 14.002,88.285 16.196,86.092 25.067,86.092 31.746,79.412 37.949,79.412 38.199,79.163 41.032,76.33 41.032,71.144 42.495,69.681 45.977,69.681 46.602,69.056 46.602,67.884 46.162,67.444 v2(44.739,67.444)
  other v1: 44.739,67.444 19.85,122.936
JHAT_GPIO_0_20: J6.27 R171.2 U33_2.13 | length 12.7
  TOP_L1 w0.127: U33_2.13@37.75,65.4 37.75,64.813 37.459,64.522 37.181,64.522 37.035,64.375 37.035,63.772 37.265,63.542 39.442,63.542 40.12,62.864 40.12,60.22 41.39,58.95 J6.27@41.39,56.25
JHAT_GPIO_1_20: J6.28 R122.2 U33_2.14 | length 5.7
  TOP_L1 w0.127: U33_2.14@38.25,65.4 38.25,64.91 38.785,64.375 R122.2@38.785,64.05 39.315,64.05 40.179,63.187 40.943,63.187 41.39,62.74 J6.28@41.39,61.75
JHAT_GPIO_2_20: J6.3 R170.2 U33_4.12 | length 12.5
  TOP_L1 w0.127: J6.3@10.91,56.25 10.91,58.35 11.91,59.35 11.91,63.73 11.647,63.993 11.647,64.813 ; R170.2@10.91,64.9 11.56,64.9 11.647,64.813 ; U33_4.12@13.75,65.4 13.75,64.93 13.633,64.813 11.647,64.813
JHAT_GPIO_3_20: J6.5 R169.2 U33_4.13 | length 11.4
  TOP_L1 w0.127: R169.2@12.76,64.35 14.22,64.35 14.249,64.379 ; J6.5@13.45,56.25 13.45,58.95 14.72,60.22 14.72,63.371 14.25,63.841 U33_4.13@14.25,65.4
JHAT_GPIO_4_20: J6.7 U33_4.15 | length 11.2
  TOP_L1 w0.127: U33_4.15@15.25,65.4 15.25,64.19 15.49,63.95 16.59,63.95 17.26,63.28 17.26,60.22 15.99,58.95 J6.7@15.99,56.25
JHAT_GPIO_5_20: J6.29 U33_2.15 | length 12
  TOP_L1 w0.127: U33_2.15@38.75,65.1 38.75,64.984 39.63,64.104 41.388,64.104 42.66,62.832 42.66,60.22 43.93,58.95 J6.29@43.93,56.25
JHAT_GPIO_6_20: J6.31 U33_2.16 | length 14.5
  TOP_L1 w0.127: U33_2.16@39.25,65.4 39.25,64.977 39.876,64.351 41.653,64.351 42.496,63.507 44.726,63.507 45.2,63.034 45.2,60.22 46.47,58.95 J6.31@46.47,56.25
JHAT_GPIO_7_20: J6.26 U33_2.12 | length 5.1
  TOP_L1 w0.127: U33_2.12@37.25,65.1 37.25,64.954 36.696,64.4 36.696,63.699 37.25,63.145 37.25,62.29 37.79,61.75 J6.26@38.85,61.75
JHAT_GPIO_8_20: J6.24 U33_3.20 | length 7.5
  TOP_L1 w0.127: U33_3.20@32.15,66.3 33.27,66.3 33.66,65.91 33.66,64.584 34.99,63.254 34.99,62.05 35.29,61.75 J6.24@36.31,61.75
JHAT_GPIO_9_20: J6.21 U33_3.16 | length 11.9
  TOP_L1 w0.127: U33_3.16@30.25,65.4 30.25,64.407 29.96,64.117 29.96,60.22 31.03,59.15 32.75,59.15 33.77,58.13 J6.21@33.77,56.25
JHAT_GPIO_10_20: J6.19 U33_3.14 | length 12.8
  TOP_L1 w0.127: U33_3.14@29.25,65.4 29.25,64.617 28.243,63.61 27.81,63.61 27.42,63.22 27.42,60.22 28.99,58.65 30.75,58.65 31.23,58.17 J6.19@31.23,56.25
JHAT_GPIO_11_20: J6.23 U33_3.17 | length 12.9
  TOP_L1 w0.127: U33_3.17@30.75,65.4 30.75,64.709 31.915,63.544 32.426,63.544 32.5,63.47 32.5,60.22 33.17,59.55 35.15,59.55 36.31,58.39 J6.23@36.31,56.25
JHAT_GPIO_12_20: J6.32 U33_2.17 | length 9.5
  TOP_L1 w0.127: U33_2.17@39.75,65.4 39.75,64.959 40.099,64.61 41.769,64.61 42.576,63.803 46.117,63.803 46.47,63.45 J6.32@46.47,61.75
JHAT_GPIO_13_20: J6.33 U33_2.18 | length 15.9
  TOP_L1 w0.127: U33_2.18@40.25,65.4 40.25,64.995 40.389,64.856 41.982,64.856 42.754,64.084 46.201,64.084 46.803,63.482 47.034,63.482 47.74,62.776 47.74,60.22 49.01,58.95 J6.33@49.01,56.25
JHAT_GPIO_14_20: J6.8 U33_4.14 | length 4.4
  TOP_L1 w0.127: U33_4.14@14.75,65.4 14.75,64.19 15.29,63.65 15.69,63.65 15.99,63.35 J6.8@15.99,61.75
JHAT_GPIO_15_20: J6.10 U33_4.16 | length 5.8
  TOP_L1 w0.127: U33_4.16@15.75,65.4 15.75,64.39 15.89,64.25 16.99,64.25 17.59,63.65 18.23,63.65 18.53,63.35 J6.10@18.53,61.75
JHAT_GPIO_16_20: J6.36 U21_1.7 | length 7.8
  TOP_L1 w0.127: U21_1.7@46.25,65.85 46.25,64.917 46.989,64.178 47.289,64.178 47.76,63.707 49.787,63.707 50.884,62.61 51.103,62.61 51.55,62.164 J6.36@51.55,61.75
JHAT_GPIO_17_20: J6.11 U33_4.17 | length 12.2
  TOP_L1 w0.127: U33_4.17@16.25,65.4 16.25,64.69 16.39,64.55 17.09,64.55 17.59,64.05 18.607,64.05 19.75,62.907 19.75,60.27 21.07,58.95 J6.11@21.07,56.25
JHAT_GPIO_18_20: J6.12 U33_4.18 | length 7.1
  TOP_L1 w0.127: U33_4.18@16.75,65.4 16.75,64.924 16.824,64.85 17.29,64.85 17.79,64.35 18.728,64.35 19.6,63.478 20.971,63.478 21.07,63.379 J6.12@21.07,61.75
JHAT_GPIO_19_20: J6.35 U33_2.20 | length 18.3
  TOP_L1 w0.127: U33_2.20@41.15,66.3 42.34,66.3 42.59,66.05 42.59,64.95 43.19,64.35 46.303,64.35 46.904,63.749 47.148,63.749 47.426,63.471 49.659,63.471 50.28,62.85 50.28,60.22 51.55,58.95 J6.35@51.55,56.25
JHAT_GPIO_20_20: J6.38 U21_1.9 | length 10.2
  TOP_L1 w0.127: U21_1.9@47.05,65.85 47.05,65.117 47.289,64.878 47.589,64.878 48.272,64.195 50.048,64.195 50.505,63.738 53.802,63.738 54.09,63.45 J6.38@54.09,61.75
JHAT_GPIO_21_20: J6.40 U21_1.10 | length 12.2
  TOP_L1 w0.127: U21_1.10@47.45,65.85 47.45,65.252 47.524,65.178 47.689,65.178 48.417,64.45 50.136,64.45 50.559,64.028 55.989,64.028 56.63,63.387 J6.40@56.63,61.75
JHAT_GPIO_22_20: J6.15 U33_3.12 | length 12.1
  TOP_L1 w0.127: J6.15@26.15,56.25 26.15,58.95 24.88,60.22 24.88,63.23 26.081,64.431 27.914,64.431 28.25,64.766 U33_3.12@28.25,65.4
JHAT_GPIO_23_20: J6.16 U33_3.13 | length 5.5
  TOP_L1 w0.127: J6.16@26.15,61.75 26.15,63.5 26.737,64.087 28.127,64.087 28.75,64.71 U33_3.13@28.75,65.4
JHAT_GPIO_24_20: J6.18 U33_3.15 | length 4.1
  TOP_L1 w0.127: J6.18@28.69,61.75 28.69,63.496 29.75,64.556 U33_3.15@29.75,65.4
JHAT_GPIO_25_20: J6.22 U33_3.18 | length 5.2
  TOP_L1 w0.127: U33_3.18@31.25,65.4 31.25,64.835 32.035,64.05 32.932,64.05 33.616,63.366 33.616,61.904 J6.22@33.77,61.75
JHAT_GPIO_26_20: J6.37 U21_1.8 | length 15.1
  TOP_L1 w0.127: U21_1.8@46.65,65.85 46.65,64.838 46.9,64.588 47.379,64.588 48.027,63.94 49.922,63.94 50.376,63.486 52.216,63.486 52.82,62.881 52.82,60.22 54.09,58.95 J6.37@54.09,56.25
JHAT_GPIO_27_20: J6.13 U33_4.20 | length 14.4
  TOP_L1 w0.127: U33_4.20@17.65,66.3 18.64,66.3 18.976,65.964 18.976,64.564 19.774,63.766 22.074,63.766 22.476,63.364 22.476,60.084 23.61,58.95 J6.13@23.61,56.25
MD_CCI_I2C0.SCL_1: D83.2 JMEDIA.51 MODULE1.AJ41 R252.2 U33_1.4 | length 88.5
  L3 w0.127: v3(33.573,144.933) 33.555,144.915 33.555,144.202 34.947,142.81 34.947,133.541 37.512,130.976 49.347,130.976 51.478,128.846 54.892,128.846 v1(55.482,129.436)
  L8 w0.127: v1(55.482,129.436) 54.182,129.436 53.819,129.073 52.932,129.073 52.382,129.622 52.382,130.636 52.982,131.236 58.382,131.236 59.418,132.272 70.353,132.272 73.337,135.256 79.184,135.256 81.13,133.31 81.13,128.506 80.321,127.698 80.321,125.23 81.158,124.393 83.77,124.393 v3(84.875,123.288)
  BOTTOM_L10 w0.127: JMEDIA.51@33.039,146.492 33.039,144.661 33.319,144.661 33.319,144.679 v3(33.573,144.933) ; U33_1.4@84.325,124.15 84.325,123.644 84.681,123.288 v3(84.875,123.288) R252.2@84.875,122.925
  other v2: 55.482,129.436
  other v4: 84.875,123.288 33.573,144.933
  other v5: 55.482,129.436 33.573,144.933
MD_CCI_I2C0.SDA_1: D84.2 JMEDIA.53 MODULE1.AJ40 R253.2 U33_1.5 | length 81.3
  L3 w0.127: v5(32.254,144.675) 32.299,144.675 34.72,142.255 34.72,133.447 37.418,130.749 49.253,130.749 51.384,128.619 54.986,128.619 54.99,128.623 55.095,128.623 v5(55.482,128.236)
  L8 w0.127: v5(55.482,128.236) 58.682,128.236 60.869,130.423 71.251,130.423 74.591,133.763 76.677,133.763 77.614,132.826 79.014,132.826 79.995,131.845 79.995,128.976 79.044,128.026 79.044,123.461 80.029,122.477 83.414,122.477 v3(84.225,123.288)
  BOTTOM_L10 w0.109: D84.2@31.759,144.641 31.776,144.658 32.237,144.658 v5(32.254,144.675) ; D84.2@31.769,144.651 JMEDIA.53@31.769,146.492
  BOTTOM_L10 w0.127: U33_1.5@83.825,124.15 83.825,123.624 84.099,123.35 84.13,123.35 84.192,123.288 v3(84.225,123.288) R253.2@84.225,122.925
  other v1: 55.482,128.236
  other v2: 55.482,128.236
  other v3: 32.254,144.675
  other v4: 84.225,123.288 32.254,144.675
MD_CCI_I2C0_3V3.SCL_1: D10_2.2 J3_2.20 R159.2 U33_1.17 | length 43.2
  TOP_L1 w0.127: J3_2.20@78.624,154.475 78.624,153.575 78.724,153.475 v5(78.724,151.982)
  L8 w0.127: v5(78.724,151.982) 82.835,151.982 92.226,142.591 92.226,129.686 90.474,127.934 84.505,127.934 84.299,127.727 84.299,127.335 v3(84.275,127.312)
  BOTTOM_L10 w0.086: v3(84.275,127.312) R159.2@84.275,127.675
  BOTTOM_L10 w0.127: v3(84.275,127.312) 84.275,126.902 84.325,126.852 U33_1.17@84.325,126.45
  other v1: 78.724,151.982
  other v2: 78.724,151.982
  other v4: 84.275,127.312
MD_CCI_I2C0_3V3.SDA_1: D11_2.2 J3_2.21 R160.2 U33_1.16 | length 43.3
  TOP_L1 w0.127: J3_2.21@79.124,154.475 79.124,153.575 79.324,153.375 v5(79.324,151.382)
  L8 w0.127: v5(79.324,151.382) 79.556,151.614 82.703,151.614 91.926,142.391 91.926,129.986 90.256,128.316 84.367,128.316 83.625,127.574 83.625,127.272 v3(83.831,127.066)
  BOTTOM_L10 w0.086: R160.2@83.625,127.675 83.625,127.272 v3(83.831,127.066)
  BOTTOM_L10 w0.127: U33_1.16@83.825,126.45 83.828,126.453 83.828,127.063 v3(83.831,127.066)
  other v1: 79.324,151.382
  other v2: 79.324,151.382
  other v4: 83.831,127.066
MD_CCI_I2C2.SCL_1: D89.2 JMEDIA.24 MODULE1.AK42 R254.2 U33_1.6 | length 118.9
  TOP_L1 w0.127: v2(56.082,130.435) 56.481,130.435 MODULE1.AK42@56.682,130.636
  L3 w0.127: v5(49.932,153.269) 49.583,152.92 46.68,152.92 41.776,157.824 31.022,157.824 28.487,155.289 28.487,151.113 35.174,144.426 35.174,133.635 37.606,131.203 49.441,131.203 51.572,129.073 54.29,129.073 55.652,130.435 v2(56.082,130.435)
  L8 w0.127: v5(49.932,153.269) 49.935,153.266 50.773,153.266 v4(50.776,153.263) ; v2(56.082,130.435) 58.181,130.435 59.618,131.872 70.553,131.872 73.637,134.956 79.007,134.956 80.903,133.061 80.903,128.6 80.035,127.732 80.035,124.665 80.754,123.946 83.146,123.946 83.575,123.516 v3(83.575,123.288)
  BOTTOM_L10 w0.127: v4(50.776,153.263) 50.776,153.23 50.826,153.18 50.826,152.759 50.819,152.752 JMEDIA.24@50.819,150.141 ; U33_1.6@83.325,124.15 83.325,123.538 v3(83.575,123.288) R254.2@83.575,122.925
  other v1: 56.082,130.435
  other v3: 50.776,153.263
  other v4: 83.575,123.288
  other v5: 56.082,130.435
MD_CCI_I2C2.SDA_1: D88.2 JMEDIA.22 MODULE1.AJ39 R255.2 U33_1.7 | length 128.2
  L3 w0.127: v5(52.43,153.699) 52.43,152.264 51.865,151.698 50.26,151.698 49.265,152.693 46.586,152.693 41.682,157.597 31.116,157.597 28.759,155.24 28.759,151.226 35.401,144.584 35.401,133.729 37.7,131.43 49.536,131.43 50.93,130.035 54.682,130.035 55.482,130.835 56.508,130.835 56.582,130.761 56.582,129.935 55.882,129.235 55.882,128.093 55.482,127.693 v1(55.482,127.036)
  L8 w0.127: v4(52.102,153.441) 52.172,153.441 v5(52.43,153.699) ; v1(55.482,127.036) 54.982,127.536 54.982,128.485 55.233,128.736 58.682,128.736 60.718,130.772 70.953,130.772 74.281,134.1 76.772,134.1 77.787,133.084 79.156,133.084 80.222,132.018 80.222,128.882 79.271,127.932 79.271,123.806 80.228,122.85 82.487,122.85 v3(82.925,123.288)
  BOTTOM_L10 w0.127: JMEDIA.22@52.089,150.141 52.089,152.752 52.102,152.765 v4(52.102,153.441) ; U33_1.7@82.825,124.15 82.825,123.651 82.925,123.551 v3(82.925,123.288) R255.2@82.925,122.925
  other v2: 55.482,127.036
  other v3: 52.102,153.441
  other v4: 82.925,123.288
  other v5: 55.482,127.036
MD_CCI_I2C2_3V3.SCL_1: D10_3.2 J3_3.20 R164.2 U33_1.15 | length 80.3
  TOP_L1 w0.127: J3_3.20@50.624,154.475 50.624,153.575 50.724,153.475 v1(50.724,152.262)
  L3 w0.127: v1(50.724,152.262) 50.724,156.077 52.311,157.664 76.025,157.664 76.917,156.772 81.311,156.772 82.082,156.001 82.082,150.959 82.229,150.813 v5(82.282,150.813)
  L8 w0.127: v5(82.282,150.813) 82.334,150.76 82.505,150.76 82.53,150.735 83.09,150.735 91.626,142.199 91.626,130.186 90.081,128.641 84.304,128.641 83.247,127.584 v3(83.247,127.076)
  BOTTOM_L10 w0.084: R164.2@82.975,127.675 82.975,127.348 v3(83.247,127.076)
  BOTTOM_L10 w0.127: v3(83.247,127.076) 83.247,127.043 83.325,126.965 U33_1.15@83.325,126.45
  other v2: 50.724,152.262
  other v4: 83.247,127.076
MD_CCI_I2C2_3V3.SDA_1: D11_3.2 J3_3.21 R175.2 U33_1.14 | length 79.5
  TOP_L1 w0.127: J3_3.21@51.124,154.475 51.124,153.575 51.324,153.375 v2(51.324,152.262)
  L3 w0.127: v2(51.324,152.262) 51.324,155.877 52.884,157.437 75.931,157.437 76.823,156.545 80.972,156.545 81.682,155.835 81.682,150.96 81.672,150.949 81.668,150.949 81.531,150.813 v5(81.458,150.813)
  L8 w0.127: v5(81.458,150.813) 81.51,150.76 81.681,150.76 81.706,150.735 81.845,150.735 82.132,150.449 82.876,150.449 91.326,141.999 91.326,130.486 89.762,128.922 84.151,128.922 82.8,127.572 v3(82.8,127.083)
  BOTTOM_L10 w0.127: R175.2@82.325,127.675 82.325,127.42 82.638,127.107 82.777,127.107 82.813,127.071 82.813,126.462 U33_1.14@82.825,126.45
  other v1: 51.324,152.262
  other v4: 82.8,127.083
MD_CCI_I2C3.SCL_1: MODULE1.AD40 U3.C6 | length 146.7
  TOP_L1 w0.127: v1(44.363,78.129) 44.819,78.585 54.472,78.585 56.885,76.172 56.885,73.448 56.885,73.241 68.097,62.029 68.097,55.043 67.769,54.716 67.769,46.673 60.73,39.634 54.937,39.634 52.565,37.262 52.565,30.289 52.264,29.987 v2(52.264,23.729) ; v1(44.569,106.549) 44.569,112.592 50.011,118.033 50.011,126.374 49.936,126.448 49.266,126.448 48.954,126.76 48.954,127.255 48.99,127.291 48.99,127.731 49.161,127.903 49.161,127.915 MODULE1.AD40@49.482,128.236
  L3 w0.127: v1(44.363,78.129) 44.353,78.139 44.353,105.933 44.569,106.149 v1(44.569,106.549) ; v4(50.163,22.329) 51.263,22.329 52.212,23.278 52.212,23.548 52.24,23.577 52.24,23.705 v2(52.264,23.729)
  BOTTOM_L10 w0.127: v4(50.163,22.329) 50.163,17.583 50.59,17.156 51.49,17.156 51.627,17.292 52.514,17.292 52.772,17.034 52.772,16.806 53.031,16.547 53.807,16.547 53.926,16.429 53.926,16.167 U3.C6@53.963,16.129
  other v1: 52.264,23.729
  other v2: 44.363,78.129 44.569,106.549
  other v3: 50.163,22.329
  other v5: 50.163,22.329
MD_CCI_I2C3.SDA_1: MODULE1.AY25 U3.A5 | length 121.9
  TOP_L1 w0.127: v1(50.763,23.629) 50.763,23.908 50.839,23.984 50.839,30.167 51.43,30.759 51.43,37.844 54.358,40.772 60.19,40.772 66.634,47.216 66.634,55.186 66.962,55.513 66.962,61.559 55.75,72.771 55.75,72.978 55.75,75.702 54.098,77.353 v5(52.444,77.353) ; v2(68.082,108.536) 68.082,109.636 MODULE1.AY25@68.682,110.236
  L3 w0.127: v5(49.608,22.026) 49.647,22.065 49.647,22.326 50.013,22.692 50.593,22.692 50.763,22.862 v1(50.763,23.629)
  L8 w0.127: v5(52.444,77.353) 52.471,77.381 52.471,80.001 52.144,80.328 52.144,80.6 52.142,80.603 52.142,80.904 52.144,80.906 52.144,84.298 69.075,101.229 69.075,105.079 67.372,106.783 67.372,107.825 v2(68.082,108.536)
  BOTTOM_L10 w0.127: v5(49.608,22.026) 49.608,17.785 50.463,16.929 U3.A5@52.363,16.929
  other v1: 52.444,77.353 68.082,108.536
  other v2: 50.763,23.629 52.444,77.353
  other v3: 49.608,22.026
  other v4: 49.608,22.026
  other v5: 68.082,108.536
MD_CCI_I2C4.SCL_1: MODULE1.AG42 R256.2 U33_1.8 | length 43.6
  L8 w0.127: v5(53.082,130.636) 53.682,130.036 58.582,130.036 60.118,131.572 70.653,131.572 73.737,134.656 78.684,134.656 80.676,132.664 80.676,128.694 79.725,127.743 79.725,124.413 80.539,123.599 82.112,123.599 82.251,123.46 82.251,123.312 v4(82.275,123.288)
  BOTTOM_L10 w0.127: R256.2@82.275,122.925 v4(82.275,123.288) 82.275,123.698 82.325,123.748 U33_1.8@82.325,124.15
  other v1: 53.082,130.636
  other v2: 53.082,130.636
  other v3: 82.275,123.288
MD_CCI_I2C4.SDA_1: MODULE1.AG41 R257.2 U33_1.9 | length 42.5
  L8 w0.127: v5(53.082,129.436) 53.455,129.809 59.321,129.809 60.684,131.172 70.753,131.172 73.964,134.383 78.241,134.383 80.449,132.175 80.449,128.788 79.498,127.838 79.498,124.216 80.426,123.288 v4(81.625,123.288)
  BOTTOM_L10 w0.127: R257.2@81.625,122.925 v4(81.625,123.288) 81.825,123.488 U33_1.9@81.825,124.15
  other v1: 53.082,129.436
  other v2: 53.082,129.436
  other v3: 81.625,123.288
MD_CCI_I2C4_3V3.SCL_1: D10_1.2 J3_1.20 R176.2 U33_1.13 | length 117
  TOP_L1 w0.127: J3_1.20@22.624,154.475 22.624,153.575 22.724,153.475 v2(22.724,152.257)
  L3 w0.127: v2(22.724,152.257) 29.199,158.732 55.598,158.732 56.166,158.163 76.168,158.163 77.105,157.226 82.691,157.226 83.582,156.335 83.582,150.711 82.474,149.602 78.838,149.602 v5(78.791,149.649)
  L8 w0.127: v5(78.791,149.649) 79.591,150.449 81.81,150.449 82.037,150.222 82.603,150.222 91.026,141.799 91.026,130.786 89.562,129.322 84.131,129.322 82.275,127.467 v3(82.275,127.05)
  BOTTOM_L10 w0.127: R176.2@81.675,127.675 81.675,127.463 81.787,127.351 81.974,127.351 v3(82.275,127.05) 82.275,127.017 82.325,126.967 U33_1.13@82.325,126.45
  other v1: 22.724,152.257
  other v4: 82.275,127.05
MD_CCI_I2C4_3V3.SDA_1: D11_1.2 J3_1.21 R177.2 U33_1.12 | length 112.6
  TOP_L1 w0.127: J3_1.21@23.124,154.475 23.124,153.575 23.324,153.375 v2(23.324,152.257)
  L3 w0.127: v2(23.324,152.257) 29.572,158.505 55.504,158.505 56.118,157.891 76.119,157.891 77.011,156.999 82.494,156.999 83.282,156.211 83.282,150.835 82.496,150.049 v5(79.791,150.049)
  L8 w0.127: v5(79.791,150.049) 81.889,150.049 81.943,149.995 82.43,149.995 90.726,141.699 90.726,131.086 89.362,129.722 84.176,129.722 81.823,127.37 v3(81.823,127.026)
  BOTTOM_L10 w0.127: R177.2@81.025,127.675 81.025,127.42 81.419,127.026 v3(81.823,127.026) U33_1.12@81.824,126.451
  other v1: 23.324,152.257
  other v4: 81.823,127.026
MD_GPIO_3_1: MODULE1.D37 R186.1 R330.2 | length 90.6
  TOP_L1 w0.1: MODULE1.D37@25.482,124.636 25.581,124.636 26.3,123.918 v5(26.3,123.885)
  BOTTOM_L10 w0.1: v5(26.3,123.885) 26.521,124.106 60.095,124.106 60.949,123.252 60.949,121.669 58.323,119.043 55.682,119.043 52.714,116.075 52.714,112.567 52.714,111.026 54.954,108.786 56.495,108.786 65.154,108.786 65.832,108.108 67,108.108 68.797,106.311 73.207,106.311 73.637,105.881 74.588,105.881 75.127,105.342 75.127,101.31 75.963,100.474 75.963,99.337 77.78,97.52 R330.2@80.726,97.52 80.726,97.249 80.82,97.155 80.82,97.065 R186.1@80.866,97.018
  other v1: 26.3,123.885
  other v2: 26.3,123.885
  other v3: 26.3,123.885
  other v4: 26.3,123.885
MD_GPIO_10: D101.1 D101.10 JMISC.37 MODULE1.AW30 | length 68.8
  TOP_L1 w0.127: v3(51.731,108.774) 51.731,113.512 55.955,117.736 59.835,117.736 60.063,117.965 65.563,117.965 65.754,117.774 65.754,116.96 65.913,116.801 66.918,116.801 MODULE1.AW30@67.482,116.236
  L8 w0.127: v4(39.026,104.829) 39.026,97.212 39.567,96.672 40.368,96.672 40.974,96.066 40.974,95.771 40.661,95.458 v3(40.661,95.382)
  BOTTOM_L10 w0.127: v4(39.026,104.829) 39.026,110.115 46.467,117.556 51.005,117.556 51.402,117.159 51.402,110.015 51.731,109.686 v3(51.731,108.774) ; v3(40.661,95.382) 41.024,95.745 D101.1@41.024,96.516 D101.10@41.024,97.391 41.024,98.009 41.144,98.129 41.597,98.129 41.929,98.462 JMISC.37@41.929,99.629
  other v1: 51.731,108.774
  other v2: 51.731,108.774
  other v3: 39.026,104.829
  other v4: 40.661,95.382 51.731,108.774
  other v5: 51.731,108.774
MD_GPIO_11: D101.2 D101.9 JMISC.39 MODULE1.AV29 | length 64.3
  TOP_L1 w0.127: v2(52.463,108.807) 52.463,109.655 52.875,110.068 52.875,113.329 55.195,115.649 65.669,115.649 MODULE1.AV29@66.282,115.036
  L8 w0.127: v4(38.673,104.829) 38.673,96.566 38.909,96.329 40.039,96.329 v4(40.527,95.842)
  BOTTOM_L10 w0.127: v4(38.673,104.829) 38.673,110.261 46.321,117.91 51.193,117.91 51.802,117.3 51.802,109.936 52.08,109.658 52.08,109.19 v2(52.463,108.807) ; v4(40.527,95.842) 40.527,96.513 D101.2@40.524,96.516 D101.9@40.524,97.391 40.524,98.209 40.659,98.344 JMISC.39@40.659,99.629
  other v1: 52.463,108.807
  other v3: 40.527,95.842 38.673,104.829 52.463,108.807
  other v4: 52.463,108.807
  other v5: 52.463,108.807
MD_GPIO_12: D101.4 D101.7 JMISC.41 MODULE1.AY30 | length 61.9
  TOP_L1 w0.127: v2(59.711,123.077) 59.694,123.06 59.694,120.671 59.921,120.444 66.758,120.444 66.832,120.369 66.832,119.586 67.254,119.165 67.701,119.165 68.011,118.855 68.011,118.508 68.411,118.108 68.901,118.108 68.904,118.11 69.208,118.11 69.282,118.036 69.282,117.289 68.901,116.908 68.881,116.908 68.682,116.708 MODULE1.AY30@68.682,116.236
  L8 w0.127: v4(38.323,104.829) 38.323,96.416 38.921,95.818 39.129,95.818 39.137,95.81 v3(39.518,95.81)
  BOTTOM_L10 w0.127: v4(38.323,104.829) 38.323,110.35 48.214,120.241 51.29,120.241 53.414,122.364 59.303,122.364 59.711,122.773 v2(59.711,123.077) ; JMISC.41@39.389,99.629 39.389,98.344 39.524,98.209 D101.4@39.524,96.516 39.518,96.509 v3(39.518,95.81)
  other v1: 59.711,123.077
  other v3: 38.323,104.829 59.711,123.077
  other v4: 39.518,95.81 59.711,123.077
  other v5: 59.711,123.077
MD_GPIO_13: D101.5 D101.6 JMISC.43 MODULE1.AW29 | length 87.4
  TOP_L1 w0.127: v1(52.433,110.034) 52.433,113.747 55.522,116.836 65.459,116.836 65.682,116.613 65.682,116.089 65.754,116.017 66.063,115.708 66.501,115.708 66.811,115.708 MODULE1.AW29@67.482,115.036
  L8 w0.127: v4(37.973,104.829) 37.973,95.866 38.309,95.529 v3(39.009,95.529)
  BOTTOM_L10 w0.127: v4(37.973,104.829) 37.973,110.5 48.397,120.924 51.652,120.924 53.319,122.591 58.818,122.591 59.592,123.366 60.212,123.366 60.509,123.069 60.509,122.593 57.634,119.718 55.513,119.718 52.256,116.461 52.256,110.861 52.433,110.684 v1(52.433,110.034) ; JMISC.43@38.119,99.629 38.119,98.409 38.237,98.292 38.242,98.292 38.404,98.129 38.904,98.129 39.024,98.009 D101.6@39.024,97.391 D101.5@39.024,96.516 39.024,95.544 v3(39.009,95.529)
  other v2: 52.433,110.034
  other v3: 37.973,104.829 52.433,110.034
  other v4: 39.009,95.529 52.433,110.034
  other v5: 52.433,110.034
MD_GPIO_14: D102.2 D102.9 JMISC.47 MODULE1.AY28 | length 67.1
  TOP_L1 w0.127: v2(58.466,123.138) 58.482,123.122 58.482,121.477 58.502,121.456 58.502,119.556 58.822,119.236 66.582,119.236 66.882,118.936 66.882,118.216 67.08,118.019 67.857,118.019 68.069,117.807 68.069,117.596 68.069,114.449 MODULE1.AY28@68.682,113.836
  L8 w0.127: v3(34.609,94.929) 34.609,101.129 37.209,103.729 v3(37.209,106.629)
  BOTTOM_L10 w0.127: v3(34.609,94.929) 35.444,95.764 D102.2@35.444,96.516 D102.9@35.444,97.391 35.444,98.209 35.579,98.344 JMISC.47@35.579,99.629 ; v3(37.209,106.629) 37.209,108.74 37.252,108.782 37.252,111.024 47.605,121.378 51.464,121.378 53.224,123.138 v2(58.466,123.138)
  other v1: 58.466,123.138
  other v3: 58.466,123.138
  other v4: 34.609,94.929 37.209,106.629 58.466,123.138
  other v5: 58.466,123.138
MD_GPIO_15: D102.1 D102.10 JMISC.45 MODULE1.AW28 | length 88
  TOP_L1 w0.127: v2(53.102,109.724) 53.102,112.899 54.576,114.373 66.945,114.373 MODULE1.AW28@67.482,113.836
  L8 w0.127: v3(35.109,94.929) 35.109,100.929 37.586,103.406 v3(37.586,106.637)
  BOTTOM_L10 w0.127: v3(35.109,94.929) 35.133,94.953 35.31,94.953 35.944,95.587 35.944,98.009 36.064,98.129 36.564,98.129 36.727,98.292 36.732,98.292 36.849,98.409 JMISC.45@36.849,99.629 ; v3(37.586,106.637) 37.586,110.434 38.433,111.281 38.433,111.526 48.058,121.151 51.558,121.151 53.225,122.818 58.724,122.818 59.498,123.593 60.306,123.593 60.736,123.164 60.736,122.489 57.639,119.393 55.509,119.393 52.501,116.385 52.501,110.938 53.102,110.336 v2(53.102,109.724)
  other v1: 53.102,109.724
  other v3: 53.102,109.724
  other v4: 35.109,94.929 37.586,106.637 53.102,109.724
  other v5: 53.102,109.724
MD_GPIO_16_1: MODULE1.AV28 R270.1 U23.43 | length 65.3
  TOP_L1 w0.127: MODULE1.AV28@66.282,113.836 66.728,113.39 v5(66.744,113.39)
  L8 w0.127: v4(38.284,89.15) 40.762,89.15 41.485,89.15 43.557,87.079 43.557,84.247 44.866,82.937 v4(45.322,82.937) ; v4(44.877,79.468) 48.98,79.468 49.147,79.635 49.147,82.752 68.294,101.899 68.294,104.898 66.691,106.501 66.691,108.646 66.932,108.887 66.932,111.032 66.744,111.221 v5(66.744,113.39)
  BOTTOM_L10 w0.127: R270.1@37.95,88.816 v4(38.284,89.15) 39.65,89.15 39.784,89.016 U23.43@40.573,89.016 ; v4(44.877,79.468) 44.877,82.492 v4(45.322,82.937)
  other v1: 66.744,113.39
  other v2: 66.744,113.39
  other v3: 44.877,79.468 45.322,82.937 38.284,89.15
MD_GPIO_17: MODULE1.E34 R423.2 U33_4.9 | length 111.7
  TOP_L1 w0.127: R423.2@13.71,68.95 13.71,68.587 13.75,68.547 v1(13.75,68.311) U33_4.9@13.75,67.7 ; v1(26.282,120.636) MODULE1.E34@26.682,121.036
  L3 w0.127: v1(13.75,68.311) 13.75,68.622 14.413,69.285 30.343,69.285 30.808,69.749 31.469,69.749 31.916,70.196 31.916,75.604 25.126,82.394 13.841,82.394 11.897,84.338 11.897,84.67 11.892,84.675 11.892,85.309 11.892,85.916 11.892,86.461 11.892,124.499 14.646,127.253 20.369,127.253 21.673,125.948 21.673,121.035 22.554,120.155 22.855,120.155 22.862,120.161 23.068,120.161 23.103,120.127 25.773,120.127 v1(26.282,120.636)
  other v2: 13.75,68.311 26.282,120.636
MD_GPIO_18: MODULE1.E33 R422.2 U33_4.8 | length 112.1
  TOP_L1 w0.127: U33_4.8@14.25,67.7 v1(14.25,68.311) 14.25,68.555 14.36,68.665 R422.2@14.36,68.95 ; v1(26.282,119.436) MODULE1.E33@26.682,119.836
  L3 w0.127: v1(14.25,68.311) 14.25,68.698 14.61,69.058 30.539,69.058 30.95,69.468 31.688,69.468 33.003,70.782 33.003,72.445 32.424,73.024 32.424,75.521 25.324,82.621 13.935,82.621 12.124,84.432 12.124,84.764 12.119,84.769 12.119,85.403 12.119,86.01 12.119,86.555 12.119,124.405 14.74,127.026 20.275,127.026 21.446,125.854 21.446,120.941 22.553,119.835 25.883,119.835 v1(26.282,119.436)
  other v2: 14.25,68.311 26.282,119.436
MD_GPIO_19: MODULE1.C37 R425.2 U33_2.8 | length 94.2
  TOP_L1 w0.127: v2(23.862,125.042) 23.869,125.042 24.275,124.636 MODULE1.C37@24.282,124.636 ; v2(30.569,70.249) 31.535,70.249 32.553,69.231 37.52,69.231 37.669,69.082 37.669,68.392 37.75,68.311 U33_2.8@37.75,67.7
  L3 w0.127: v2(23.862,125.042) 23.575,125.042 20.683,127.934 14.364,127.934 11.211,124.781 11.211,86.179 11.211,85.634 11.211,85.026 11.211,84.393 11.216,84.388 11.216,84.056 13.559,81.713 24.762,81.713 30.997,75.478 30.997,70.677 v2(30.569,70.249)
  other v1: 30.569,70.249 23.862,125.042
MD_GPIO_20: MODULE1.B37 R424.2 U33_2.7 | length 92.5
  TOP_L1 w0.127: v2(22.661,125.01) 22.684,125.01 23.058,124.636 MODULE1.B37@23.082,124.636 ; v1(31.369,70.549) 31.659,70.549 32.678,69.531 37.988,69.531 38.325,69.193 R424.2@38.325,68.87 38.325,68.386 38.25,68.311 U33_2.7@38.25,67.7
  L3 w0.127: v2(22.661,125.01) 22.661,125.603 20.557,127.707 14.458,127.707 11.438,124.687 11.438,86.273 11.438,85.728 11.438,85.121 11.438,84.487 11.443,84.482 11.443,84.15 13.653,81.94 24.856,81.94 31.304,75.493 31.304,70.794 31.346,70.752 31.346,70.572 v1(31.369,70.549)
  other v1: 22.661,125.01
  other v2: 31.369,70.549
MD_GPIO_24_1: MODULE1.E37 R165.1 U10_2.17 | length 64.3
  TOP_L1 w0.127: MODULE1.E37@26.682,124.636 26.777,124.636 v1(26.791,124.65) ; U10_2.17@64.182,138.491 64.498,138.491 64.648,138.641 65.255,138.641 v1(65.255,139.075) 65.259,139.071 65.259,138.645 R165.1@65.262,138.641
  L3 w0.127: v1(26.791,124.65) 29.034,124.65 30.504,123.18 47.3,123.18 49.388,125.268 49.388,128.061 49.462,128.135 50.447,128.135 51.082,127.5 51.082,123.801 50.653,123.372 50.653,122.672 51.053,122.272 54.253,122.272 55.953,123.972 55.953,125.572 56.516,126.135 59.982,126.135 66.611,132.764 66.611,137.719 v1(65.255,139.075)
  other v2: 26.791,124.65 65.255,139.075
MD_GPIO_25: MODULE1.Y40 U33_3.5 | length 124.3
  TOP_L1 w0.127: v2(25.876,70.672) 25.876,68.986 26.24,68.622 29.996,68.622 30.25,68.368 U33_3.5@30.25,67.7 ; v2(44.156,127.31) 44.156,127.71 MODULE1.Y40@44.682,128.236
  L3 w0.127: v2(25.876,70.672) 26.523,71.319 26.523,74.505 21.399,79.628 17.417,79.628 17.249,79.461 16.002,79.461 15.338,80.124 9.138,80.124 8.532,80.729 8.532,82.394 7.408,83.518 7.408,88.564 7.405,88.567 7.405,88.644 4.545,91.505 4.467,91.505 4.267,91.505 3.898,91.873 3.898,92.074 3.898,93.023 3.021,93.9 3.021,98.555 2.966,98.61 2.966,103.336 3.314,103.684 3.314,104.718 3.54,104.944 3.54,108.525 3.123,108.941 3.123,111.095 3.412,111.383 3.412,119.61 4.002,120.2 5.4,120.2 6.947,121.747 6.947,124.374 7.926,125.353 7.926,126.817 8.221,127.111 8.221,127.691 8.514,127.985 11.529,127.985 13.003,129.459 23.118,129.459 26.546,126.031 41.707,126.031 42.042,126.365 42.042,126.374 42.552,126.884 43.731,126.884 v2(44.156,127.31)
  other v1: 25.876,70.672 44.156,127.31
MD_GPIO_26: MODULE1.Y43 U33_3.7 | length 104.1
  TOP_L1 w0.127: U33_3.7@29.25,67.7 v5(29.25,68.147) ; v2(42.81,128.725) 42.54,128.725 42.393,128.873 41.93,128.873 41.754,129.049 41.754,129.655 42.063,129.965 42.414,129.965 42.86,130.411 42.86,131.06 43.05,131.25 44.096,131.25 MODULE1.Y43@44.682,131.836
  L3 w0.127: v5(26.825,127.391) 27.069,127.635 27.377,127.635 28.277,126.735 41.761,126.735 42.769,127.744 42.769,128.092 42.81,128.133 v2(42.81,128.725)
  L8 w0.127: v5(26.825,127.391) 30.288,123.927 ; v5(29.25,68.147) 29.25,69.309 31.01,71.068 31.01,104.658 31.463,105.112 31.463,106.157 33.256,107.949 42.423,107.949 42.572,108.098 42.572,111.67 41.572,112.67 36.133,112.67 30.295,118.508 30.295,123.934
  other v1: 29.25,68.147 42.81,128.725
  other v2: 29.25,68.147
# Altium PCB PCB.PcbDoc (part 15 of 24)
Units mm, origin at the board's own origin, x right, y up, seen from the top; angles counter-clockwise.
Board outline 100 x 160 mm, 10 copper layers (TOP_L1, L2, L3, L4, L5, L6, L7, L8, L9, BOTTOM_L10), stack 1.946 mm thick; 1358 components, 1149 nets, 6777 pads, 10914 vias.

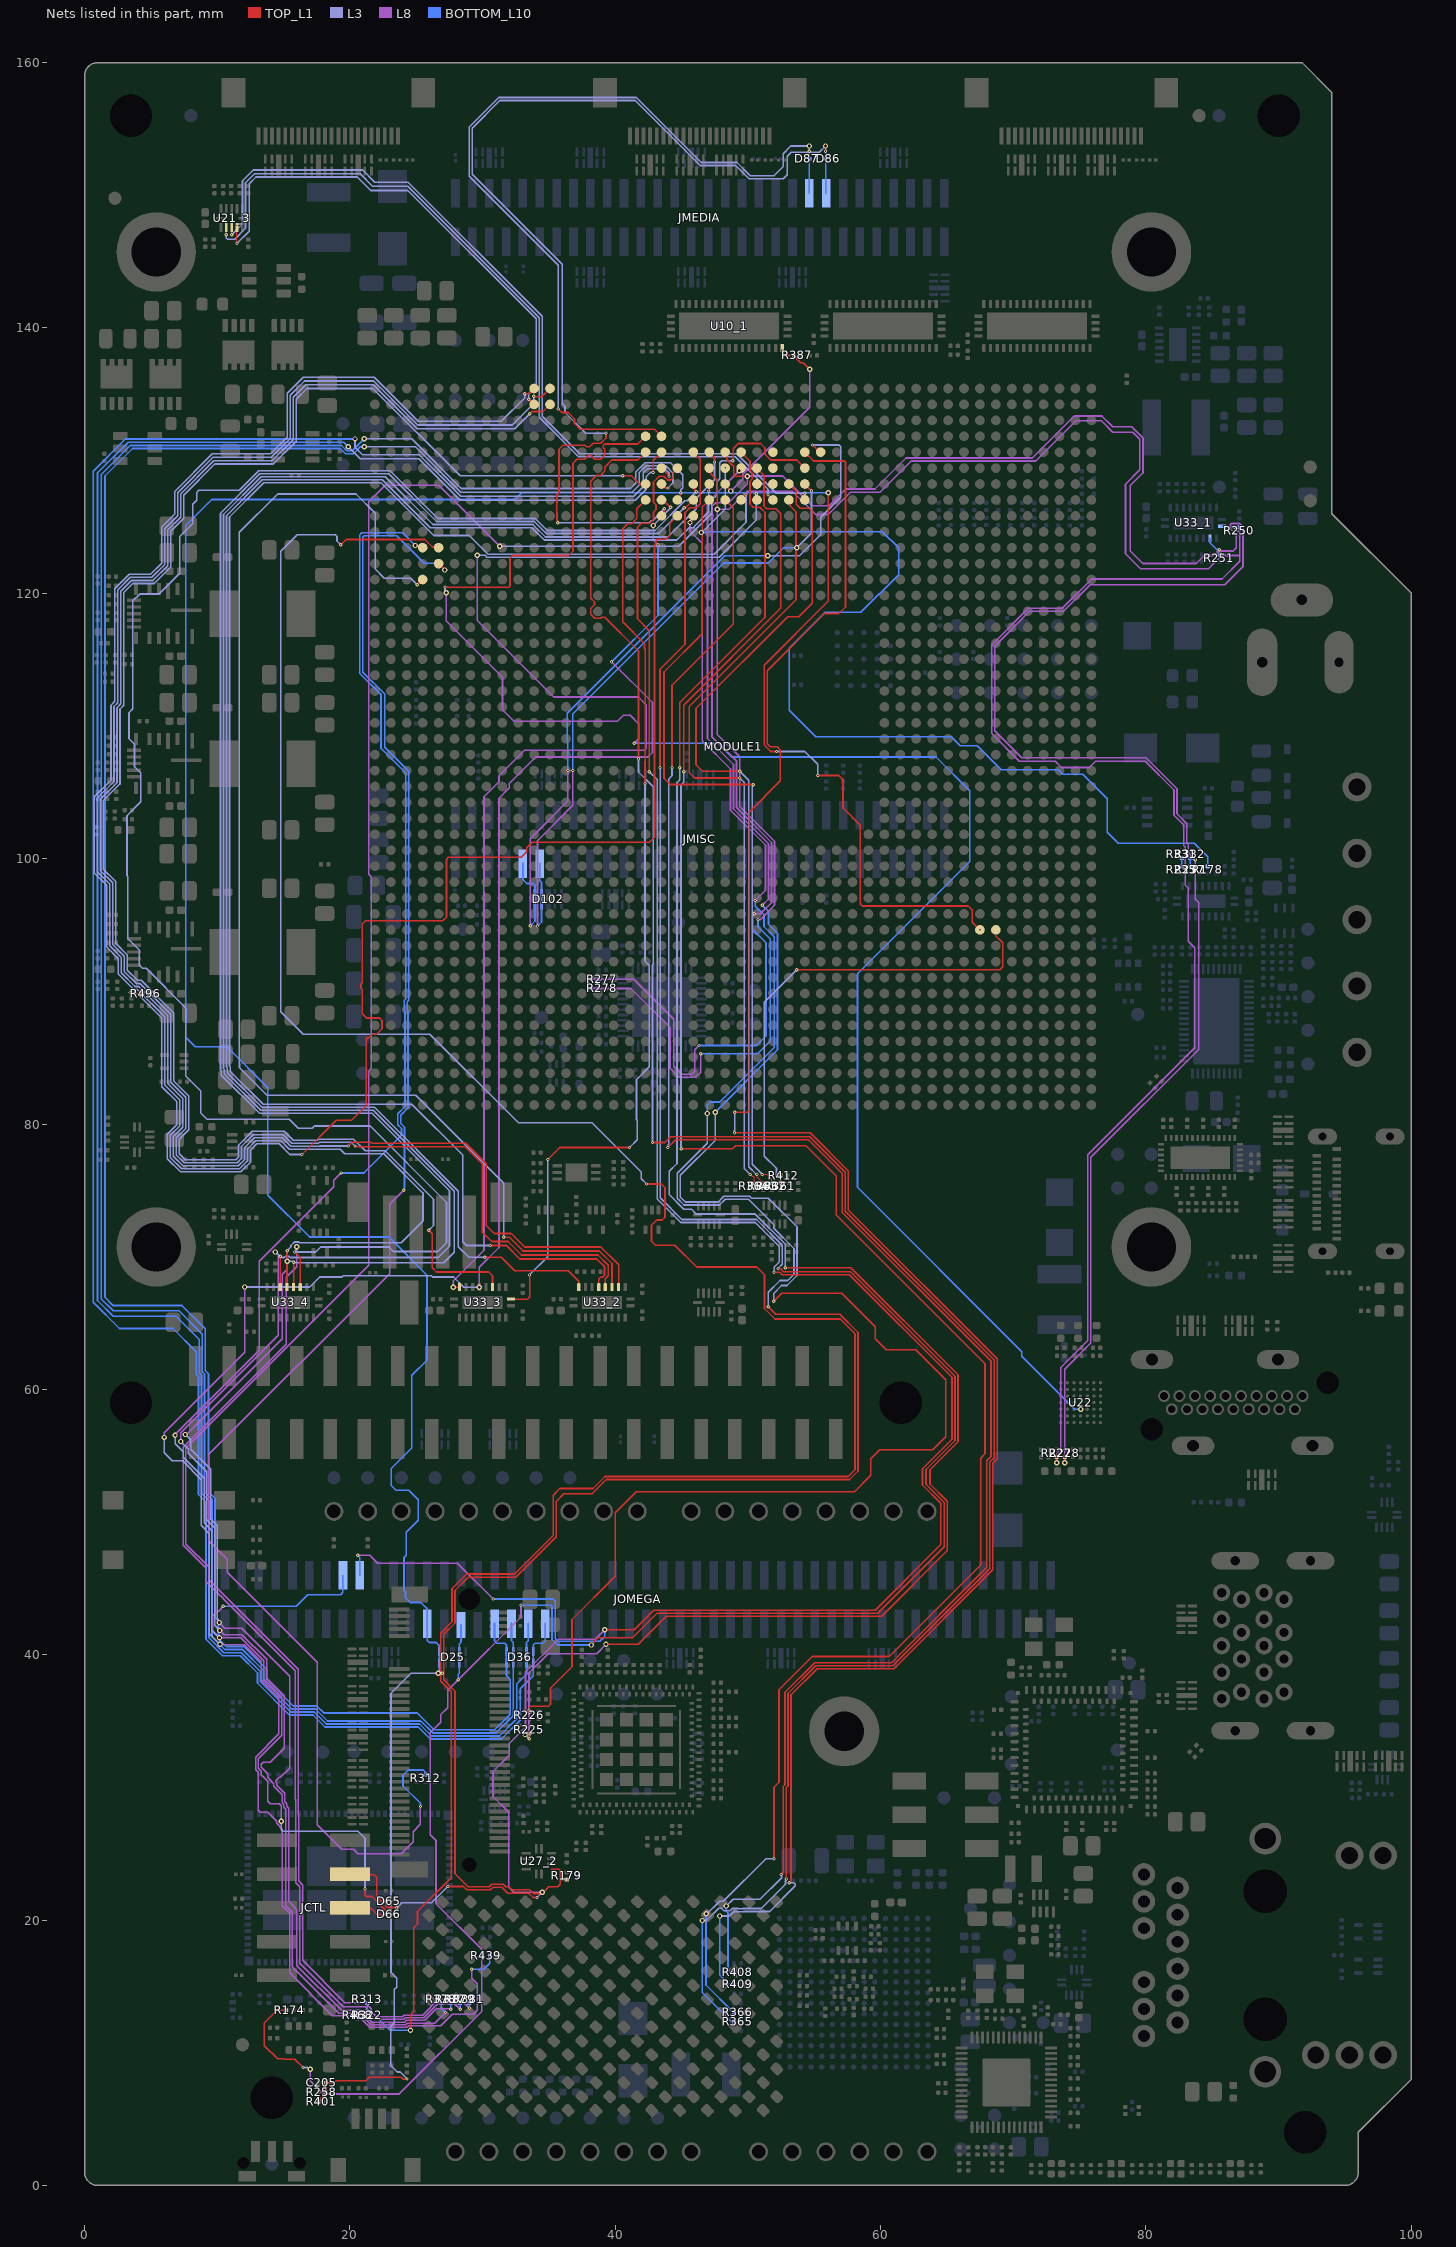
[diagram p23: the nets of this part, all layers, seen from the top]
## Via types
v1: diameter 0.25, hole 0.1, TOP_L1 to L2, tented both sides, 3439 vias
v2: diameter 0.25, hole 0.1, L2 to L3, tented both sides, 2256 vias
v3: diameter 0.25, hole 0.1, L9 to BOTTOM_L10, tented both sides, 1685 vias
v4: diameter 0.25, hole 0.1, L8 to L9, tented both sides, 1675 vias
v5: diameter 0.4, hole 0.2, L3 to L8, tented both sides, 1251 vias
v6: diameter 0.6, hole 0.3, TOP_L1 to BOTTOM_L10, tented both sides, 600 vias
v7: diameter 0.24, hole 0.1, TOP_L1 to L2, tented both sides, 8 vias

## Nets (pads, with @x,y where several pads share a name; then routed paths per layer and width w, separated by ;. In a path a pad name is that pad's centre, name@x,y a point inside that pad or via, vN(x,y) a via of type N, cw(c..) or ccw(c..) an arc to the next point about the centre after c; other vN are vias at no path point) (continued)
MD_GPIO_27: MODULE1.V40 U33_3.4 | length 133.2
  TOP_L1 w0.127: v2(25.944,71.981) 26.196,71.729 26.196,69.173 26.52,68.849 30.469,68.849 30.75,68.568 U33_3.4@30.75,67.7 ; v2(40.569,128.849) 41.217,128.849 41.611,128.455 41.611,128.435 41.81,128.236 MODULE1.V40@42.282,128.236
  L3 w0.127: v2@25.936,71.99 26.296,72.35 26.296,74.323 22.637,77.982 21.146,77.982 20.272,78.856 17.607,78.856 17.531,78.78 15.72,78.78 15.056,79.443 12.643,79.443 11.6,78.4 11.6,77.5 11.4,77.3 7.6,77.3 7.142,77.758 7.142,78.858 7.851,79.567 7.851,82.112 6.727,83.236 6.727,88.282 6.724,88.285 6.724,88.362 4.263,90.824 3.985,90.824 3.217,91.591 3.217,92.741 2.34,93.618 2.34,98.273 1.416,99.197 1.416,104.379 2.669,105.632 2.669,111.283 2.958,111.571 2.958,120.063 3.638,120.744 5.256,120.744 6.493,121.98 6.493,124.672 7.47,125.65 7.47,127.389 9.823,129.742 14.223,129.742 15.953,131.472 15.953,134.631 16.758,135.436 21.727,135.436 28.314,128.849 v2(40.569,128.849)
  other v1: 25.944,71.981 40.569,128.849
MD_GPIO_28: MODULE1.V39 U33_3.1 | length 70.1
  TOP_L1 w0.127: U33_3.1@32.15,66.8 33.381,66.8 33.553,66.972 33.553,68.608 v2(33.535,68.626) ; v2(34.898,77.32) 35.81,78.233 v2(41.066,78.233) ; v2(42.24,105.64) 42.24,107.279 42.27,107.309 42.27,115.772 42.202,115.84 42.202,116.198 40.554,117.846 40.554,124.855 40.942,125.243 41.236,125.243 41.625,125.631 41.625,126.379 MODULE1.V39@42.282,127.036
  L3 w0.127: v2(33.535,68.626) 34.898,69.988 v2(34.898,77.32) ; v2(41.066,78.233) 41.652,78.818 41.652,80.288 41.596,80.343 41.596,83.346 42.553,84.303 42.553,91.959 42.24,92.272 v2(42.24,105.64)
  other v1: 33.535,68.626 34.898,77.32 41.066,78.233 42.24,105.64
MD_GPIO_29: MODULE1.AD41 R226.1 | length 145.5
  TOP_L1 w0.127: R226.1@33.523,35.725 33.523,36.025 33.623,36.125 34.969,36.125 35.118,36.273 35.118,37.483 36.731,39.096 36.731,42.65 39.991,45.91 39.991,50.693 41.591,52.294 58.023,52.294 59.249,53.519 59.249,54.759 59.934,55.444 63.934,55.444 64.919,56.429 64.919,60.713 62.651,62.981 60.424,62.981 59.599,63.806 59.599,64.719 57.066,67.253 52.543,67.253 51.931,66.641 v2(51.931,66.633) ; v5(49.337,129.227) 49.482,129.372 MODULE1.AD41@49.482,129.436
  L3 w0.127: v4(47.523,80.891) 47.523,78.75 44.898,76.126 44.898,74.499 45.273,74.124 47.754,74.124 48.186,74.557 50.13,74.557 50.272,74.414 51.534,74.414 53.697,72.251 53.697,68.579 52.944,67.825 52.526,67.825 51.931,67.231 v2(51.931,66.633)
  L8 w0.127: v5(49.337,129.227) 46.953,126.843 46.953,109.055 48.915,107.092 48.915,103.746 51.542,101.119 51.542,96.953 v3(51.088,96.498)
  BOTTOM_L10 w0.127: v4(47.523,80.891) 52.225,85.593 52.225,94.383 51.548,95.06 51.548,96.038 v3(51.088,96.498)
  other v1: 51.931,66.633 49.337,129.227
  other v2: 49.337,129.227
  other v3: 47.523,80.891
  other v4: 51.088,96.498
  other v5: 47.523,80.891
MD_GPIO_30: MODULE1.AD42 R225.1 | length 144.2
  TOP_L1 w0.127: v1(33.523,33.658) R225.1@33.523,34.075 ; v2(39.3,40.78) 41.729,40.78 43.851,42.902 60.073,42.902 65.027,47.857 65.027,51.561 63.716,52.872 63.716,53.943 65.827,56.053 65.827,61.089 57.758,69.158 v2(52.801,69.158) ; v2(44.869,106.849) 44.869,111.773 51.282,118.186 51.282,125.983 51.282,126.086 51.003,126.365 50.88,126.488 50.393,126.488 50.154,126.727 50.154,128.455 50.318,128.62 50.318,129.052 50.154,129.217 50.154,129.965 MODULE1.AD42@49.482,130.636
  L3 w0.127: v5(33.2,33.98) v1(33.523,33.658) ; v2(44.869,106.849) 44.869,105.949 44.653,105.733 44.653,77.019 44.063,76.429 44.063,74.692 45.172,73.583 45.739,73.583 46.112,73.21 50.552,73.21 52.81,70.953 52.81,69.166 v2(52.801,69.158)
  L8 w0.127: v5(33.2,33.98) 33.5,34.28 33.5,38.637 34.943,40.08 38.6,40.08 v2(39.3,40.78)
  other v1: 39.3,40.78 52.801,69.158 44.869,106.849
  other v2: 33.523,33.658
  other v5: 39.3,40.78
MD_GPIO_33: MODULE1.AE40
MD_GPIO_34: MODULE1.AF42
MD_GPIO_35: MODULE1.AF41
MD_GPIO_36: MODULE1.AF40
MD_GPIO_37: D36.4 D36.7 JOMEGA.66 MODULE1.Y39 | length 178.2
  TOP_L1 w0.127: MODULE1.Y39@44.682,127.036 44.682,127.199 44.915,127.432 44.915,127.556 v2(44.938,127.58)
  L3 w0.127: v5(21.072,131.643) 24.654,131.643 28.401,127.895 41.147,127.895 41.535,128.283 41.535,129.141 42.235,129.841 44.167,129.841 45.082,128.925 45.082,127.959 44.938,127.815 v2(44.938,127.58)
  BOTTOM_L10 w0.127: v5(21.072,131.643) 20.176,130.748 19.763,130.748 19.367,131.143 3.439,131.143 1.255,128.958 1.255,66.814 2.155,65.914 7.112,65.914 8.865,64.161 8.865,61.328 9.039,61.153 9.039,52.263 9.606,51.696 9.606,41.361 10.581,40.386 11.405,40.386 11.911,40.386 13.482,38.815 13.482,38.309 13.482,38.058 15.626,35.913 17.402,35.913 18.309,35.006 25.336,35.006 26.237,34.105 31.009,34.105 32.306,35.402 D36.4@32.306,39.374 D36.7@32.306,40.249 32.306,40.924 32.171,41.059 JOMEGA.66@32.171,42.349
  other v1: 44.938,127.58
  other v3: 21.072,131.643
  other v4: 21.072,131.643
MD_GPIO_38: D36.5 D36.6 JOMEGA.68 MODULE1.W40 | length 176.6
  TOP_L1 w0.127: MODULE1.W40@43.482,128.236 43.777,127.942 v1(43.976,127.942)
  L3 w0.127: v5(21.082,131.036) 24.939,131.036 28.363,127.612 41.264,127.612 41.818,128.165 41.818,129.103 42.329,129.614 43.797,129.614 44.343,129.068 44.343,128.308 v1(43.976,127.942)
  BOTTOM_L10 w0.127: v5(21.082,131.036) 20.786,131.036 20.27,130.521 19.669,130.521 19.28,130.91 3.606,130.91 1.538,128.841 1.538,66.931 2.155,66.314 7.339,66.314 9.092,64.561 9.092,61.422 9.338,61.176 9.338,52.285 9.833,51.79 9.833,42.824 10.087,42.57 10.087,41.201 10.675,40.613 11.499,40.613 12.005,40.613 13.709,38.909 13.709,38.403 13.709,38.152 15.72,36.14 17.497,36.14 18.023,35.613 25.05,35.613 26.331,34.332 30.896,34.332 32.079,35.516 32.079,38.137 31.806,38.41 D36.5@31.806,39.374 D36.6@31.806,40.249 31.806,40.724 31.659,40.871 31.059,40.871 30.901,41.029 JOMEGA.68@30.901,42.349
  other v2: 43.976,127.942
  other v3: 21.082,131.036
  other v4: 21.082,131.036
MD_GPIO_39: D36.1 D36.10 JOMEGA.62 MODULE1.W41 | length 179.4
  TOP_L1 w0.127: MODULE1.W41@43.482,129.436 43.482,129.418 44.054,128.846 v1(44.054,128.828)
  L3 w0.127: v3(20.382,131.636) 20.382,131.002 20.941,130.443 25.211,130.443 28.342,127.312 41.389,127.312 42.118,128.041 42.118,129.082 42.423,129.387 43.703,129.387 44.054,129.035 v1(44.054,128.828)
  BOTTOM_L10 w0.127: v3(20.382,131.636) 3.081,131.636 0.653,129.208 0.653,66.565 2.631,64.587 6.658,64.587 8.411,62.834 8.411,61.14 8.585,60.965 8.585,52.075 9.152,51.508 9.152,41.173 10.393,39.932 11.723,39.932 13.028,38.627 13.028,37.87 15.438,35.459 17.214,35.459 18.121,34.552 25.148,34.552 26.049,33.651 31.419,33.651 32.83,35.062 32.83,37.433 33.806,38.41 D36.1@33.806,39.374 D36.10@33.806,40.249 33.806,40.724 33.954,40.871 34.554,40.871 34.711,41.029 JOMEGA.62@34.711,42.349
  other v2: 44.054,128.828
  other v4: 20.382,131.636
  other v5: 20.382,131.636
MD_GPIO_40: D36.2 D36.9 JOMEGA.64 MODULE1.W42 | length 176.7
  TOP_L1 w0.127: v2(42.868,129.098) 42.868,130.022 MODULE1.W42@43.482,130.636
  L3 w0.127: v3(19.882,131.036) 20.782,130.136 25.197,130.136 28.321,127.012 41.513,127.012 42.345,127.844 42.345,128.803 42.64,129.098 v2(42.868,129.098)
  BOTTOM_L10 w0.127: v3(19.882,131.036) 19.534,131.384 3.28,131.384 0.972,129.076 0.972,66.697 2.155,65.514 6.885,65.514 8.638,63.761 8.638,61.234 8.812,61.059 8.812,52.169 9.379,51.602 9.379,41.267 10.487,40.159 11.311,40.159 11.817,40.159 13.255,38.721 13.255,38.215 13.255,37.964 15.532,35.686 17.308,35.686 18.215,34.779 25.242,34.779 26.143,33.878 31.275,33.878 32.576,35.179 32.576,37.793 33.306,38.523 D36.2@33.306,39.374 D36.9@33.306,40.249 33.306,40.924 33.441,41.059 JOMEGA.64@33.441,42.349
  other v1: 42.868,129.098
  other v4: 19.882,131.036
  other v5: 19.882,131.036
MD_GPIO_41_1: MODULE1.AC40 R387.1 U10_1.17 | length 15.4
  TOP_L1 w0.109: MODULE1.AC40@48.282,128.236 48.282,128.162 48.701,127.743 v5(48.701,127.705) ; U10_1.17@52.582,138.491 52.582,138.02 52.646,137.956 53.427,137.956 R387.1@53.456,137.926 ; R387.1@53.456,137.911 53.99,137.378 54.166,137.378 v5(54.661,136.883)
  L8 w0.109: v5(48.701,127.705) 49.596,128.599 49.596,128.969 54.661,134.034 v5(54.661,136.883)
  other v1: 48.701,127.705 54.661,136.883
  other v2: 48.701,127.705 54.661,136.883
MD_GPIO_42_1: MODULE1.AC39 R408.2 | length 143.7
  TOP_L1 w0.127: v1(43.963,78.229) 44.546,78.812 54.566,78.812 57.112,76.266 57.112,73.542 57.112,73.335 68.324,62.123 68.324,54.949 67.996,54.622 67.996,46.579 60.82,39.403 55.027,39.403 52.792,37.168 52.792,30.195 52.667,30.069 52.667,23.596 v2(52.5,23.429) ; v1(44.269,106.849) 44.269,113.078 48.882,117.691 48.882,126.436 MODULE1.AC39@48.282,127.036
  L3 w0.127: v1(43.963,78.229) 43.987,78.253 43.987,78.432 44.025,78.47 44.025,106.004 44.269,106.249 v1(44.269,106.849) ; v5(48.375,21.055) 48.896,21.577 50.911,21.577 52.536,23.202 52.536,23.307 52.524,23.318 52.524,23.405 v2(52.5,23.429)
  BOTTOM_L10 w0.127: v5(48.375,21.055) 48.375,20.655 48.501,20.529 48.501,16.198 48.65,16.049 R408.2@48.936,16.049
  other v1: 52.5,23.429
  other v2: 43.963,78.229 44.269,106.849
  other v3: 48.375,21.055
  other v4: 48.375,21.055
MD_GPIO_43: D65.2 JCTL.4 JOMEGA.83 MODULE1.Y41 | length 200.7
  TOP_L1 w0.127: JCTL.4@20.01,23.461 20.05,23.421 21.81,23.421 22.01,23.221 22.01,21.808 22.397,21.421 22.71,21.421 22.71,21.05 22.812,20.948 23.512,20.948 v1(23.531,20.929) ; v1(27.373,22.525) 28.559,22.525 28.809,22.275 30.584,22.275 30.789,22.48 31.45,22.48 31.902,22.029 33.47,22.029 33.799,21.7 v2(34.1,21.7) ; v2(39.202,41.886) 41.424,41.886 42.895,43.356 59.584,43.356 64.529,48.302 64.529,51.417 63.152,52.794 63.152,54.02 65.373,56.241 65.373,60.901 57.631,68.642 52.588,68.642 52.413,68.817 51.978,68.817 v2(51.964,68.831) ; v2(42.569,106.549) 42.569,117.182 41.674,118.077 41.674,124.977 41.969,125.273 42.578,125.273 42.878,125.573 42.878,126.111 43.066,126.299 43.066,126.671 42.878,126.859 42.878,128.385 43.314,128.82 43.658,128.82 43.766,128.713 43.766,128.709 43.935,128.54 44.174,128.54 44.37,128.736 44.37,129.09 44.682,129.402 MODULE1.Y41@44.682,129.436
  L3 w0.127: v1(23.531,20.929) 23.905,21.302 26.151,21.302 v1(27.373,22.525) ; v2(34.1,21.7) 34.102,21.7 34.494,22.092 v5(34.496,22.092) ; v2(42.569,106.549) 43.153,105.965 43.153,74.346 44.925,72.575 50.546,72.575 52.356,70.765 52.356,69.604 51.976,69.223 51.976,68.843 v2(51.964,68.831)
  L8 w0.127: v3(20.6,47.5) 21.502,47.5 22.102,46.9 28.1,46.9 v4(30.8,44.2) ; v5(34.496,22.092) 32.358,22.092 31.971,22.479 31.971,28.122 30.783,29.31 30.783,31.195 32.009,32.42 32.009,33.303 33.234,34.528 33.234,38.692 35.717,41.175 38.491,41.175 v2(39.202,41.886)
  BOTTOM_L10 w0.127: v3(20.6,47.5) 20.6,47.475 20.746,47.328 JOMEGA.83@20.746,46 ; v4(30.8,44.2) 35.3,44.2 35.465,44.035 35.465,41.241 35.683,41.022 38.83,41.022 39.015,41.208 39.057,41.208 39.202,41.353 v2(39.202,41.886)
  other v1: 34.1,21.7 39.202,41.886 51.964,68.831 42.569,106.549
  other v2: 23.531,20.929 27.373,22.525
  other v3: 39.202,41.886 30.8,44.2
  other v4: 39.202,41.886 20.6,47.5
  other v5: 39.202,41.886
MD_GPIO_44: D66.2 JCTL.6 JOMEGA.85 MODULE1.D36 | length 148.7
  TOP_L1 w0.127: JCTL.6@20.01,20.921 20.054,20.877 21.602,20.877 22.058,20.421 22.71,20.421 22.71,20.695 21.635,21.77 21.23,21.77 21.137,21.863 v2(21.137,22.36) ; v2(24.925,123.607) 24.958,123.607 25.019,123.546 25.372,123.546 MODULE1.D36@25.482,123.436
  L3 w0.1: v5(6.821,56.543) 6.821,56.053 6.832,56.043 6.832,55.885 7.424,55.293 7.424,54.886 9.005,53.306 9.005,49.934 9.593,49.346 9.593,41.859 v5(10.167,41.285)
  L3 w0.127: v5(14.826,27.444) 14.826,26.815 14.946,26.695 20.605,26.695 21.137,26.163 v2(21.137,22.36)
  L8 w0.1: v5(6.821,56.543) 6.821,56.6 13.162,62.941 13.162,69.643 18.789,75.27 18.789,75.747 v4(19.355,76.314) ; v4(10.458,43.65) 10.45,43.65 10.275,43.475 10.275,43.431 10.129,43.285 10.034,43.285 9.679,42.93 9.679,41.774 v5(10.167,41.285) 11.788,41.285 13.516,39.557 13.516,38.147 14.852,36.812 14.852,33.923 13.172,32.243 13.172,32.241 13.1,32.168 13.1,31.428 13.303,31.225 13.303,30.95 13.803,30.45 13.803,28.96 14.008,28.754 14.679,28.754 14.826,28.608 v5(14.826,27.444)
  BOTTOM_L10 w0.1: v4(10.458,43.65) 15.945,43.65 16.822,44.527 19.292,44.527 19.476,44.712 JOMEGA.85@19.476,46
  BOTTOM_L10 w0.127: v4(19.355,76.314) 21.062,76.314 23.891,79.143 23.891,79.655 23.598,79.949 23.598,80.761 24.154,81.318 24.154,88.45 24.092,88.512 24.092,89.315 24.201,89.423 24.201,106.454 22.348,108.307 22.348,112.351 20.739,113.96 20.739,124.393 20.902,124.556 23.976,124.556 v2(24.925,123.607)
  other v1: 21.137,22.36 24.925,123.607
  other v3: 10.458,43.65 19.355,76.314 24.925,123.607
  other v4: 24.925,123.607
  other v5: 24.925,123.607
MD_GPIO_45: MODULE1.AC42 R228.2 R237.1 R251.2 R277.1 R332.2 U33_1.3 | length 230.9
  TOP_L1 w0.1: MODULE1.AC42@48.282,130.636 48.403,130.515 48.403,130.088 48.585,129.906 48.585,129.885 48.746,129.724 48.767,129.724 48.916,129.574 48.916,128.942 49.022,128.837 49.936,128.837 v5(49.95,128.822) ; v5(73.875,54.476) R228.2@73.875,54.915
  L8 w0.127: v3(38.146,90.916) 41.388,90.916 44.415,87.888 44.415,84.343 45.015,83.743 45.767,83.743 45.988,83.965 45.988,84.552 46.001,84.564 46.001,84.865 45.988,84.877 45.988,85.606 v4(46.306,85.923) ; v4(50.483,95.854) 50.501,95.836 50.929,95.836 51.769,96.677 51.769,101.213 49.142,103.84 49.142,107.331 47.282,109.191 47.282,126.536 47.582,126.836 48.535,126.836 49.939,128.241 49.939,128.811 v5(49.95,128.822) 49.965,128.836 52.622,128.836 54.854,126.604 56.13,126.604 57.382,127.856 59.575,127.856 61.915,130.196 71.424,130.196 74.592,133.363 76.677,133.363 77.483,132.557 78.929,132.557 79.768,131.718 79.768,129.07 78.817,128.119 78.817,123.189 79.756,122.25 83.79,122.25 84.39,122.85 85.087,122.85 v3(85.525,123.288) 85.558,123.288 85.654,123.193 86.566,123.193 86.796,123.423 86.796,124.424 86.373,124.847 86.373,125.212 86.425,125.264 87.076,125.264 87.317,125.023 87.317,122.036 85.927,120.646 75.794,120.646 73.784,118.635 71.221,118.635 68.59,116.004 68.59,109.645 70.627,107.608 79.996,107.608 82.335,105.269 82.335,103.377 83.08,102.632 83.08,101.2 83.185,101.096 83.185,100.454 v4(83.723,99.916) 83.723,96.941 83.968,96.696 83.968,85.62 75.837,77.49 75.837,63.49 73.875,61.528 v5(73.875,54.476)
  BOTTOM_L10 w0.1: R237.1@83.353,99.424 R332.2@83.353,99.916 ; R332.2@83.353,99.947 83.651,99.947 83.682,99.916 v4(83.723,99.916)
  BOTTOM_L10 w0.127: v3(38.146,90.916) R277.1@38.748,90.916 ; v4(46.306,85.923) 50.641,85.923 51.354,86.636 51.354,93.661 50.335,94.679 50.335,95.706 v4(50.483,95.854) ; U33_1.3@84.825,124.15 84.825,123.809 85.339,123.295 85.519,123.295 v3(85.525,123.288) R251.2@85.525,122.925
  other v1: 73.875,54.476 49.95,128.822
  other v2: 73.875,54.476 49.95,128.822
  other v3: 46.306,85.923 50.483,95.854 83.723,99.916
  other v4: 38.146,90.916 85.525,123.288
MD_GPIO_46: MODULE1.AB41 R227.2 R235.1 R250.2 R278.1 R331.2 U33_1.1 | length 226.9
  TOP_L1 w0.1: MODULE1.AB41@47.082,129.436 47.196,129.322 47.196,129.022 47.686,128.532 47.686,126.34 v2(47.682,126.336) ; v5(73.275,54.476) R227.2@73.275,54.915
  L8 w0.127: v3(38.146,90.216) 41.188,90.216 44.123,87.281 44.123,84.196 44.803,83.516 46.043,83.516 46.432,83.905 v4(46.432,85.295) ; v3(50.759,95.397) 50.915,95.397 51.996,96.479 51.996,101.307 49.369,103.934 49.369,107.669 47.682,109.357 v2(47.682,126.336) 48.567,126.336 49.905,127.675 53.36,127.675 55.102,125.933 56.055,125.933 57.727,127.605 59.951,127.605 62.315,129.969 71.697,129.969 74.726,132.998 76.642,132.998 77.495,132.145 78.995,132.145 79.541,131.599 79.541,129.301 78.457,128.217 78.457,122.982 79.589,121.85 84.716,121.85 85.717,122.851 87.07,122.851 ; v5(73.275,54.476) 73.275,55.111 73.582,55.418 73.582,61.649 75.61,63.678 75.61,77.678 83.669,85.736 83.669,93.282 83.181,93.771 83.181,93.985 83.177,93.989 83.177,97.792 82.958,98.011 v3(82.958,99.299) ; v4@82.957,99.301 82.958,99.302 82.958,100.883 82.853,100.988 82.853,102.538 82.108,103.283 82.108,105.175 79.947,107.336 76.195,107.336 75.731,106.873 73.629,106.873 73.15,107.351 70.442,107.351 68.363,109.43 68.363,116.098 71.127,118.862 73.69,118.862 75.906,121.078 85.725,121.078 87.07,122.423 87.07,122.851 ; v3(86.662,124.975) 87.07,124.567 87.07,122.851
  BOTTOM_L10 w0.1: R331.2@82.703,99.947 R235.1@82.703,99.424 82.789,99.338 82.879,99.338 82.917,99.299 v3(82.958,99.299)
  BOTTOM_L10 w0.127: v3(38.146,90.216) R278.1@38.748,90.216 ; v4(46.432,85.295) 50.716,85.295 51.672,86.251 51.672,93.946 50.759,94.859 v3(50.759,95.397) ; U33_1.1@85.725,125.05 86.334,125.05 86.409,124.975 v3(86.662,124.975) R250.2@87.025,124.975
  other v1: 73.275,54.476 47.682,126.336
  other v2: 73.275,54.476
  other v3: 46.432,85.295
  other v4: 38.146,90.216 50.759,95.397 82.958,99.299 86.662,124.975
  other v5: 47.682,126.336
MD_GPIO_47_1: MODULE1.AB39 R362.2 | length 60.2
  TOP_L1 w0.084: v1(51.071,76.199) 51.411,76.199 51.789,75.821 R362.2@51.789,75.566
  TOP_L1 w0.127: MODULE1.AB39@47.082,127.036 46.554,126.508 46.554,116.957 43.669,114.073 43.669,106.063 44.147,105.585 50.376,105.585 v2(50.386,105.575)
  L3 w0.127: v2(50.386,105.575) 50.386,105.541 50.314,105.469 50.314,76.964 51.071,76.207 v1(51.071,76.199)
  other v1: 50.386,105.575
  other v2: 51.071,76.199
MD_GPIO_48_1: MODULE1.AC41 R178.1 | length 76.6
  TOP_L1 w0.1: MODULE1.AC41@48.282,129.436 v1(48.282,129.459)
  L3 w0.127: v3(46.478,124.581) 46.512,124.581 48.282,126.352 v1(48.282,129.459)
  BOTTOM_L10 w0.1: v3(46.478,124.581) 46.739,124.581 46.803,124.645 60.122,124.645 61.349,123.418 61.349,121.416 58.489,118.556 55.819,118.556 53.114,115.851 53.114,111.192 55.12,109.186 65.319,109.186 65.997,108.508 67.29,108.508 69.087,106.711 73.373,106.711 73.726,106.358 75.219,106.358 77.076,104.501 77.076,102.001 77.912,101.165 83.63,101.165 84.653,100.142 R178.1@84.653,99.424
  other v2: 48.282,129.459
  other v4: 46.478,124.581
  other v5: 46.478,124.581
MD_GPIO_49_1: MODULE1.Y38 R496.2 | length 102.7
  TOP_L1 w0.127: v2(3.419,89.916) 3.519,89.816 R496.2@4.319,89.816 ; v1(16.376,77.707) 16.384,77.707 18.964,80.287 20.113,80.287 20.957,81.131 21.226,81.4 21.226,86.476 21.374,86.476 21.663,86.765 22.006,86.765 22.411,87.169 22.411,87.809 22.237,87.983 21.257,87.983 20.94,88.3 20.94,90.146 20.837,90.249 20.837,90.551 20.94,90.654 20.94,95.077 21.17,95.308 27.008,95.308 27.274,95.574 27.274,99.959 27.423,100.108 32.901,100.108 33.318,100.524 33.318,100.819 33.735,101.236 42.582,101.236 42.954,101.608 42.954,123.655 43.062,123.764 43.062,123.966 43.169,124.073 43.803,124.073 44.107,124.376 44.107,125.261 MODULE1.Y38@44.682,125.836
  L3 w0.127: v2(3.419,89.916) 3.887,89.916 5.816,87.986 5.816,86.818 5.819,86.816 5.819,82.816 6.943,81.691 6.943,79.943 6.234,79.234 6.234,77.382 7.224,76.392 11.776,76.392 12.508,77.124 12.508,78.024 12.984,78.5 14.678,78.5 15.471,77.707 v1(16.376,77.707)
  other v1: 3.419,89.916
  other v2: 16.376,77.707
MD_GPIO_51_1: MODULE1.AA38 R179.2 U27_2.1 | length 161.6
  TOP_L1 w0.127: 33.661,22.16 33.529,22.291 32.185,22.291 31.974,22.502 31.749,22.502 31.544,22.707 30.695,22.707 30.49,22.502 28.903,22.502 27.923,23.482 27.923,37.244 27.064,38.104 27.064,41.536 27.916,42.388 27.916,44.837 28.916,45.837 32.486,45.837 35.544,48.895 35.544,51.545 36.123,52.125 38.241,52.125 39.317,53.202 57.647,53.202 58.295,53.849 58.295,64.28 56.918,65.656 52.092,65.656 v2(51.529,66.219) ; 33.662,22.16 33.821,22.001 34.493,22.001 34.995,22.502 35.654,22.502 35.84,22.689 35.84,23.049 ; U27_2.1@35.191,23.824 35.728,23.824 35.84,23.712 35.84,23.049 ; R179.2@36.341,23.049 35.84,23.049 ; v2(45.629,125.336) 45.882,125.589 MODULE1.AA38@45.882,125.836
  L3 w0.127: v5(46.923,80.791) 46.923,78.55 44.671,76.299 44.671,74.405 45.179,73.897 47.848,73.897 48.281,74.33 50.036,74.33 51.943,72.423 51.943,72.141 53.47,70.613 53.47,68.673 53.004,68.207 52.419,68.207 51.523,67.311 51.523,66.225 v2(51.529,66.219)
  L8 w0.127: v2(45.629,125.336) 45.629,124.689 46.553,123.765 46.553,108.889 48.688,106.754 48.688,103.652 51.315,101.025 51.315,97.612 v3(50.546,96.842)
  BOTTOM_L10 w0.127: v5(46.923,80.791) 46.923,81.401 47.177,81.654 47.876,81.654 51.99,85.769 51.99,94.105 51.206,94.889 51.206,95.763 50.546,96.423 v3(50.546,96.842)
  other v1: 51.529,66.219 45.629,125.336
  other v3: 46.923,80.791
  other v4: 46.923,80.791 50.546,96.842
  other v5: 45.629,125.336
MD_GPIO_52: D25.2 D25.9 JOMEGA.72 MODULE1.AA42 R174.1 | length 203.2
  TOP_L1 w0.127: R174.1@15.175,13.2 14.508,13.2 13.551,12.244 13.551,10.539 14.55,9.541 15.03,9.541 15.061,9.51 15.844,9.51 v2(16.469,8.885) ; v2(38.196,40.728) 38.458,40.99 38.458,41.04 38.696,41.278 41.295,41.278 43.146,43.129 59.781,43.129 64.8,48.148 64.8,51.467 63.413,52.855 63.413,53.96 65.6,56.147 65.6,60.995 57.725,68.869 52.682,68.869 52.469,69.082 52.289,69.082 v1(52.266,69.105) ; v1(43.369,106.849) 43.369,114.273 45.25,116.154 45.25,126.082 45.604,126.436 46.109,126.436 46.411,126.738 46.411,130.108 MODULE1.AA42@45.882,130.636
  L3 w0.127: v2(16.469,8.885) 16.803,8.885 16.925,8.763 v5(16.999,8.763) ; v1(43.369,106.849) 43.38,106.838 43.38,74.44 45.019,72.802 50.64,72.802 52.583,70.859 52.583,69.423 v1(52.266,69.105)
  L8 w0.127: v5(16.999,8.763) 16.999,7.877 17.979,6.897 23.715,6.897 29.925,13.107 29.925,17.803 26.48,21.249 26.48,26.014 26.064,26.43 26.064,34.138 26.837,34.911 26.837,35.488 27.362,36.013 27.362,37.313 v4(28.162,38.113) 32.891,42.843 v3(32.891,43.72)
  BOTTOM_L10 w0.127: v4(28.162,38.113) 28.162,38.51 28.231,38.58 D25.2@28.231,39.374 D25.9@28.231,40.249 28.231,40.794 28.366,40.929 JOMEGA.72@28.366,42.251 ; v3(32.891,43.72) 35.151,43.72 35.236,43.636 35.236,41.149 35.656,40.728 v2(38.196,40.728)
  other v1: 16.469,8.885 38.196,40.728
  other v2: 52.266,69.105 43.369,106.849
  other v3: 28.162,38.113 38.196,40.728
  other v4: 38.196,40.728 32.891,43.72
  other v5: 38.196,40.728
MD_GPIO_54_1: MODULE1.E35 R312.1 | length 132.7
  TOP_L1 w0.127: MODULE1.E35@26.682,122.236 27.15,121.768 v1(27.15,121.75)
  L8 w0.1: v3(24.062,75.013) 22.995,73.946 22.995,68.727 9.377,55.109 9.377,48.575 10.759,47.194 10.759,46.229 17.54,39.448 17.54,27.18 19.394,25.326 20.271,25.326 20.584,25.013 23.863,25.013 24.762,25.912 24.762,26.662 25.315,27.215 v4(25.315,28.558)
  BOTTOM_L10 w0.127: v3(24.062,75.013) 24.085,75.037 24.085,75.216 24.118,75.249 24.118,79.749 23.825,80.043 23.825,80.667 24.381,81.224 24.381,88.544 24.319,88.606 24.319,89.221 24.428,89.329 24.428,106.58 22.612,108.396 22.612,112.408 20.966,114.054 20.966,124.22 21.075,124.329 23.53,124.329 25.593,122.266 26.635,122.266 v1(27.15,121.75) ; v4(25.315,28.558) 25.315,28.795 24,30.11 24,30.91 24.4,31.31 25.518,31.31 25.7,31.128 R312.1@25.7,30.96
  other v2: 27.15,121.75
  other v3: 25.315,28.558 27.15,121.75
  other v4: 24.062,75.013 27.15,121.75
  other v5: 27.15,121.75
MD_GPIO_55_1: MODULE1.E36 R313.1 R322.1 R468.2 | length 193.7
  TOP_L1 w0.127: v2(19.313,123.656) 19.713,124.056 25.647,124.056 26.217,123.486 26.632,123.486 MODULE1.E36@26.682,123.436 ; v3(24.565,11.688) 24.574,11.697 24.574,12.878 24.8,13.104 24.8,15.237 24.817,15.254 24.817,19.426 25.091,19.7 25.091,20.665 27.627,23.201 27.627,37.22 26.837,38.01 26.837,41.63 27.689,42.482 27.689,44.967 28.811,46.089 32.417,46.089 35.317,48.989 35.317,52.018 35.823,52.525 38.32,52.525 39.223,53.429 57.553,53.429 58.068,53.943 58.068,64.186 56.948,65.306 52.034,65.306 51.241,66.099 51.241,68.638 50.658,69.221 46.129,69.221 44.485,70.865 43.025,70.865 42.725,71.165 42.725,72.365 43.125,72.765 43.525,72.765 43.742,72.982 43.742,75.183 43.453,75.472 v2(42.353,75.472)
  L3 w0.127: v2(19.313,123.656) 19.025,123.945 19.025,124.276 18.898,124.402 16.022,124.402 14.78,123.16 14.78,88.471 16.478,86.773 26.021,86.773 32.7,80.093 38.231,80.093 38.254,80.071 41.945,76.379 41.945,75.88 v2(42.353,75.472)
  BOTTOM_L10 w0.127: R468.2@20.6,13.11 R322.1@21.3,13.11 ; R313.1@21.3,13.76 R322.1@21.3,13.11 ; v3(24.565,11.688) 23.022,11.688 21.6,13.11 R322.1@21.3,13.11
  other v1: 24.565,11.688 42.353,75.472 19.313,123.656
  other v2: 24.565,11.688
  other v4: 24.565,11.688
  other v5: 24.565,11.688
MD_GPIO_56_1: MODULE1.W39 R439.1 | length 175.1
  TOP_L1 w0.127: MODULE1.W39@43.482,127.036 43.55,126.968 43.65,126.968 44.138,126.48 v2(44.172,126.48)
  L3 w0.1: v5(6,56.378) 6,55.206 6.604,54.601 7.388,54.601 8.784,53.205 8.784,49.743 9.393,49.134 9.393,41.564 10.171,40.787 v5(10.207,40.787)
  L3 w0.127: v5(12.062,67.713) 16.962,67.713 17.723,68.474 19.402,68.474 19.498,68.57 26.126,68.57 26.222,68.474 27.801,68.474 28.575,67.7 v5(29.75,67.7) ; v5(42.862,125.113) 44.148,126.399 44.148,126.457 v2(44.172,126.48)
  L8 w0.1: v5(6,56.378) 6,56.736 12.062,62.798 v5(12.062,67.713) ; v5(10.207,40.787) 10.241,40.752 12.038,40.752 13.316,39.474 13.316,38.064 14.652,36.729 14.652,34.033 12.9,32.281 12.9,31.345 13.103,31.142 13.103,28.261 13.246,28.119 13.803,28.119 14.476,27.446 14.476,27.288 14.905,26.859 14.905,21.073 15.462,20.516 15.462,16.013 18.684,12.791 20.619,12.791 21.5,11.91 24.292,11.91 24.42,12.038 26.828,12.038 27.7,12.91 29.312,12.91 29.6,13.198 29.6,15.21 29.185,15.625 v4(29.185,16.294)
  L8 w0.127: v5(29.75,67.7) 29.75,69.201 31.237,70.688 31.237,104.563 32.014,105.34 32.014,105.662 34.016,107.664 42.46,107.664 42.799,108.004 42.799,111.767 v3(39.72,114.847) ; v5(42.862,125.113) 42.862,124.02 v4(43.217,123.665)
  BOTTOM_L10 w0.1: v4(29.185,16.294) 30.081,16.294 30.55,16.763 R439.1@30.55,17.31
  BOTTOM_L10 w0.127: v3(39.72,114.847) 39.74,114.847 43.217,118.323 v4(43.217,123.665)
  other v1: 44.172,126.48
  other v3: 29.185,16.294 43.217,123.665
  other v4: 39.72,114.847
MD_GPIO_63_1: MODULE1.AH42 R409.2 | length 150.7
  TOP_L1 w0.127: v2(48.985,79.337) 48.988,79.335 54.685,79.335 57.566,76.454 57.566,73.73 57.566,73.523 68.778,62.311 68.778,54.761 68.45,54.434 68.45,46.391 61.008,38.949 55.54,38.949 55.215,38.949 53.246,36.98 53.246,22.982 53.121,22.857 v1(53.121,22.824) ; v1@49.01,80.885 49.939,80.885 50.087,81.033 50.087,103.506 52.442,105.861 52.442,108.192 52.21,108.423 51.674,108.423 51.443,108.655 51.443,114.162 55.753,118.472 56.853,118.472 57.353,118.972 57.353,129.898 57.279,129.972 54.946,129.972 MODULE1.AH42@54.282,130.636
  L3 w0.127: v3(47.866,20.308) 48.598,20.308 48.928,20.639 49.174,20.639 49.189,20.623 49.678,20.623 49.694,20.639 51.625,20.639 53.569,22.583 53.569,22.688 53.433,22.824 v1(53.121,22.824) ; v2(48.985,79.337) 48.985,79.523 49.006,79.544 v1(49.006,80.881)
  BOTTOM_L10 w0.127: v3(47.866,20.308) 47.866,15.857 48.574,15.149 R409.2@48.936,15.149
  other v1: 48.985,79.337
  other v2: 53.121,22.824 49.006,80.881
  other v4: 47.866,20.308
  other v5: 47.866,20.308
MD_GPIO_64_1: MODULE1.AF39 U21_3.2 | length 60.9
  TOP_L1 w0.084: v1@10.686,147.009 U21_3.2@10.686,147.575
  TOP_L1 w0.127: v2(51.512,127.42) 51.512,127.406 MODULE1.AF39@51.882,127.036
  L3 w0.127: v2(10.686,147.019) 10.686,146.787 10.777,146.696 11.308,146.696 12.127,147.515 12.127,150.938 12.811,151.621 20.767,151.621 21.706,150.682 24.36,150.682 34.266,140.777 34.266,133.259 37.23,130.295 49.05,130.295 51.512,127.833 v2(51.512,127.42)
  other v1: 51.512,127.42 10.686,147.019
MD_GPIO_65_1: MODULE1.AH41 R381.1 | length 177.1
  TOP_L1 w0.127: v2(48.86,129.999) 48.882,130.021 48.882,130.901 49.266,131.285 50.946,131.285 51.282,130.949 51.282,130.489 51.722,130.049 53.669,130.049 MODULE1.AH41@54.282,129.436
  L3 w0.127: v5(31.292,123.545) 44.779,123.545 47.278,126.045 47.278,127.029 47.686,127.436 47.686,128.431 47.884,128.629 47.884,129.85 48.033,129.999 v2(48.86,129.999)
  L8 w0.1: v4(29.007,13.342) 28.314,14.035 26.675,14.035 25.478,12.838 24.089,12.838 23.961,12.71 21.99,12.71 21.595,13.105 21.595,13.315 21.2,13.71 21.13,13.78 19.624,13.78 16.447,16.957 16.447,22.636 16.124,22.959 16.124,27.981 16.105,28 16.105,38.903 9.359,45.649 9.359,46.614 7.631,48.341 7.631,55.572 21.406,69.347 21.406,83.99 21.623,84.207 21.623,98.622 21.406,98.839 21.406,115.157 21.406,126.885 22.67,128.149 26.688,128.149 v5(31.292,123.545)
  BOTTOM_L10 w0.1: R381.1@29,13.76 29.007,13.753 v4(29.007,13.342)
  other v1: 48.86,129.999
  other v3: 29.007,13.342
MD_GPIO_67_1: D86.2 JMEDIA.16 MODULE1.W38 | length 82.5
  TOP_L1 w0.127: v2(35.665,125.317) 35.665,125.468 35.593,125.54 35.593,125.6 35.611,125.617 35.611,126.055 35.593,126.072 35.593,126.8 35.611,126.817 35.611,127.255 35.593,127.272 35.593,127.415 35.754,127.576 35.754,130.855 36.063,131.165 37.701,131.165 37.825,131.04 38.059,131.04 38.327,131.308 38.901,131.308 39.301,131.708 v1(39.301,132.06) ; MODULE1.W38@43.482,125.836 43.698,126.051 v2(43.698,126.361)
  L3 w0.127: v2(35.665,125.317) 42.551,125.317 42.711,125.477 42.813,125.477 v2(43.698,126.361) ; v1(39.301,132.06) 37.767,132.06 36.204,133.624 36.204,134.095 36.01,134.289 36.01,144.789 29.213,151.586 29.213,155.052 31.304,157.143 41.494,157.143 46.397,152.239 49.077,152.239 50.072,151.244 52.663,151.244 52.959,151.54 52.959,152.94 53.259,153.24 55.379,153.24 v5(55.849,153.71)
  L8 w0.109: v3(55.849,153.31) v5(55.849,153.71)
  BOTTOM_L10 w0.109: v3(55.849,153.31) 55.849,152.752 55.849,150.191 JMEDIA.16@55.899,150.141
  other v1: 35.665,125.317 43.698,126.361
  other v2: 39.301,132.06
  other v4: 55.849,153.31
MD_GPIO_68_1: D87.2 JMEDIA.18 MODULE1.W43 | length 66.9
  TOP_L1 w0.127: v1(35.699,133.89) 35.966,133.624 36.442,133.624 36.93,133.135 36.93,132.794 37.359,132.365 42.954,132.365 MODULE1.W43@43.482,131.836
  L3 w0.127: v1(35.699,133.89) 35.699,144.722 28.986,151.435 28.986,155.146 31.21,157.37 41.588,157.37 46.491,152.466 49.171,152.466 50.166,151.471 51.959,151.471 52.657,152.17 52.657,153.138 53.229,153.71 v5(54.629,153.71)
  L8 w0.109: v4(54.629,153.31) v5(54.629,153.71)
  BOTTOM_L10 w0.109: JMEDIA.18@54.629,150.141 54.629,151.865 54.629,152.752 v4(54.629,153.31)
  other v2: 35.699,133.89
  other v3: 54.629,153.31
MD_GPIO_69_1: MODULE1.V42 R365.2 | length 158.2
  TOP_L1 w0.127: v1(41.754,107.523) 41.754,115.646 39.202,118.198 38.992,118.198 38.901,118.108 38.463,118.108 38.154,118.417 38.154,118.855 38.429,119.131 38.429,119.341 38.154,119.617 38.154,128.455 38.606,128.908 38.901,128.908 39.211,129.217 39.211,129.512 39.743,130.045 41.691,130.045 MODULE1.V42@42.282,130.636 ; v1(42.8,78.6) 43.734,78.6 44.173,79.039 54.66,79.039 57.339,76.36 57.339,73.636 57.339,73.429 68.551,62.217 68.551,54.855 68.223,54.528 68.223,46.485 60.914,39.176 55.121,39.176 53.019,37.074 53.019,30.101 52.894,29.975 v1(52.894,23.096)
  L3 w0.127: v1(41.754,107.523) 41.754,106.534 42.863,105.425 42.863,92.061 42.8,91.997 v1(42.8,78.6) ; v5(46.547,19.969) 46.877,19.969 47.79,20.882 48.001,20.882 48.191,20.692 48.643,20.692 48.816,20.866 49.268,20.866 49.283,20.85 49.584,20.85 49.6,20.866 51,20.866 52.833,22.698 52.833,22.943 52.871,22.981 52.871,23.073 v1(52.894,23.096)
  BOTTOM_L10 w0.127: v5(46.547,19.969) 46.547,14.542 48.741,12.349 48.838,12.349 R365.2@48.936,12.349
  other v2: 52.894,23.096 42.8,78.6 41.754,107.523
  other v3: 46.547,19.969
  other v4: 46.547,19.969
MD_GPIO_70_1: MODULE1.AG40 R363.2 | length 61.7
  TOP_L1 w0.084: v1(50.671,76.199) 50.703,76.167 50.703,75.987 51.124,75.566 R363.2@51.139,75.566
  TOP_L1 w0.127: v2(49.374,106.589) 46.572,106.589 46.082,107.079 46.082,111.336 52.989,118.243 53.824,118.243 54.839,119.258 54.839,126.199 54.639,126.399 53.939,126.399 53.627,126.711 53.627,127.691 MODULE1.AG40@53.082,128.236
  L3 w0.127: v2(49.374,106.589) 50.053,105.911 50.053,76.79 50.644,76.199 v1(50.671,76.199)
  other v1: 49.374,106.589
  other v2: 50.671,76.199
MD_GPIO_71_1: MODULE1.AG39 R364.2 | length 59.1
  TOP_L1 w0.084: v1(50.171,76.199) 50.189,76.199 50.339,76.049 50.384,76.049 50.489,75.944 R364.2@50.489,75.566
  TOP_L1 w0.127: v1(49.386,106.075) 45.986,106.075 45.569,106.492 45.569,111.473 53.619,119.523 53.619,126.15 53.173,126.596 53.173,126.945 MODULE1.AG39@53.082,127.036
  L3 w0.127: v1(49.386,106.075) 49.719,105.742 49.719,76.651 v1(50.171,76.199)
  other v2: 50.171,76.199 49.386,106.075
MD_GPIO_73_1: D102.4 D102.7 JMISC.49 MODULE1.AH40 | length 49.5
  TOP_L1 w0.127: MODULE1.AH40@54.282,128.236 v1(54.782,127.736)
  L3 w0.127: v5(53.682,123.436) 54.782,124.536 v1(54.782,127.736)
  L8 w0.127: v3(34.136,94.917) 34.136,101.356 36.803,104.023 v4(36.803,106.643)
  BOTTOM_L10 w0.127: v3(34.136,94.917) 34.444,95.225 D102.4@34.444,96.516 D102.7@34.444,97.391 34.444,98.209 34.309,98.344 JMISC.49@34.309,99.629 ; v4(36.803,106.643) 36.803,110.897 48.184,122.278 51.524,122.278 52.682,123.436 v5(53.682,123.436)
  other v2: 54.782,127.736
  other v3: 36.803,106.643 53.682,123.436
  other v4: 34.136,94.917 53.682,123.436
MD_GPIO_74_1: D102.5 D102.6 JMISC.51 MODULE1.AJ42 | length 57.7
  TOP_L1 w0.127: v1(54.87,131.178) 55.412,130.636 MODULE1.AJ42@55.482,130.636
  L3 w0.127: v3(51.482,122.836) 53.882,122.836 55.482,124.436 55.482,125.736 56.982,127.236 56.982,131.036 56.835,131.183 54.876,131.183 v1(54.87,131.178)
  L8 w0.127: v4(33.588,94.939) 33.588,101.508 36.427,104.347 v4(36.427,106.649)
  BOTTOM_L10 w0.127: JMISC.51@33.039,99.629 33.039,98.409 33.157,98.292 33.162,98.292 33.324,98.129 33.824,98.129 33.944,98.009 D102.6@33.944,97.391 33.944,95.294 v4(33.588,94.939) ; v4(36.427,106.649) 36.427,108.802 36.377,108.851 36.377,110.97 48.243,122.836 v3(51.482,122.836)
  other v2: 54.87,131.178
  other v3: 33.588,94.939 36.427,106.649
  other v4: 51.482,122.836
  other v5: 51.482,122.836
MD_GPIO_75_1: MODULE1.AH39 U21_3.3 | length 62.7
  TOP_L1 w0.084: v1(11.086,147.019) U21_3.3@11.086,147.575
  TOP_L1 w0.127: MODULE1.AH39@54.282,127.036 v2(54.282,127.535)
  L3 w0.127: v1(11.086,147.019) 11.9,147.833 11.9,151.1 12.701,151.901 20.967,151.901 21.881,150.987 24.376,150.987 34.493,140.871 34.493,133.353 37.324,130.522 49.144,130.522 52.131,127.535 v2(54.282,127.535)
  other v1: 54.282,127.535
  other v2: 11.086,147.019
MD_GPIO_77_1: MODULE1.D34 U33_2.4 | length 99.2
  TOP_L1 w0.127: v2(25.082,120.636) MODULE1.D34@25.482,121.036 ; v2(31.592,71.453) 32.028,71.453 33.05,70.431 38.799,70.431 39.75,69.48 U33_2.4@39.75,67.7
  L3 w0.127: v2(25.082,120.636) 24.582,121.136 22.592,121.136 21.9,121.827 21.9,126.042 20.463,127.48 14.552,127.48 11.665,124.593 11.665,86.367 11.665,85.822 11.665,85.215 11.665,84.581 11.67,84.576 11.67,84.244 13.747,82.167 24.95,82.167 31.592,75.525 v2(31.592,71.453)
  other v1: 31.592,71.453 25.082,120.636
MD_GPIO_78_1: MODULE1.AY12 R361.2 R412.2 | length 36.4
  TOP_L1 w0.084: R361.2@52.439,75.566 R412.2@52.439,76.116
  TOP_L1 w0.127: v1(52.157,76.111) 52.159,76.114 52.437,76.114 R412.2@52.439,76.116 ; v2(53.682,91.636) 68.982,91.636 69.211,91.865 69.211,93.655 68.901,93.965 68.881,93.965 68.682,94.164 MODULE1.AY12@68.682,94.636
  L3 w0.127: v1(52.157,76.111) 52.157,76.641 51.222,77.576 51.222,89.176 v2(53.682,91.636)
  other v1: 53.682,91.636
  other v2: 52.157,76.111
MD_GPIO_79_1: C205.2 D25.5 D25.6 JOMEGA.76 MODULE1.AW12 R258.1 R401.1 | length 244.6
  TOP_L1 w0.127: R401.1@17.617,6.324 17.617,6.339 17.956,6.678 17.956,6.813 R258.1@18.167,7.024 C205.2@18.167,7.724 18.802,7.724 18.976,7.897 21.211,7.897 21.458,8.145 23.868,8.145 23.989,8.025 v1(24.307,8.025) ; v1(52.153,108.072) 51.704,108.072 51.216,108.561 51.216,114.585 56.045,119.414 v4(56.045,127.568) ; v1(55.253,106.272) 56.85,106.272 57.169,105.953 57.169,103.823 58.464,102.528 58.464,96.592 58.621,96.436 66.596,96.436 66.902,96.13 66.902,95.216 v1(67.482,94.636)
  L3 w0.127: v1(24.307,8.025) 23.786,8.546 23.568,8.546 23.07,9.043 23.07,11.968 23.35,12.248 23.35,14.775 23.523,14.948 23.523,15.625 23.093,16.054 23.093,37.095 24.599,38.6 v5(26.65,38.6) ; v1(52.153,108.072) 54.288,108.072 55.253,107.107 v1(55.253,106.272)
  L8 w0.127: v5(26.65,38.6) v4(26.95,38.6)
  BOTTOM_L10 w0.127: D25.5@26.731,39.374 26.731,38.819 v4(26.95,38.6) ; D25.5@26.734,39.374 26.734,40.246 D25.6@26.731,40.249 26.731,40.682 26.497,40.916 25.975,40.916 25.826,41.065 JOMEGA.76@25.826,42.35 25.826,43.456 25.342,43.94 24.547,43.94 24.192,44.296 24.192,44.733 24.068,44.857 24.068,47.306 24.25,47.489 24.25,49.231 25.15,50.131 25.15,51.677 24.42,52.407 23.47,52.407 23.119,52.758 23.119,54.035 24.661,55.577 24.661,61.061 25.806,62.206 25.806,68.599 22.915,71.49 16.951,71.49 13.806,74.635 13.806,82.739 10.732,85.813 8.351,85.813 7.628,86.536 7.628,125.108 9.587,127.067 32.451,127.067 32.951,127.568 v4(56.045,127.568)
  other v1: 56.045,127.568
  other v2: 24.307,8.025 55.253,106.272 52.153,108.072 56.045,127.568
  other v3: 26.95,38.6 56.045,127.568
  other v5: 56.045,127.568
MD_GPIO_80_1: MODULE1.M45 U33_2.5 | length 134.8
  TOP_L1 w0.127: v1(20.38,78.34) 20.404,78.316 20.493,78.316 20.516,78.294 28.67,78.294 29.98,76.985 29.98,71.849 30.68,71.149 31.908,71.149 32.926,70.131 38.699,70.131 39.469,69.361 39.469,68.568 39.25,68.349 U33_2.5@39.25,67.7 ; v1(33.559,133.54) 33.727,133.708 34.554,133.708 MODULE1.M45@35.082,134.236
  L3 w0.127: v1(20.38,78.34) 20.091,78.629 17.701,78.629 17.625,78.553 15.626,78.553 14.986,79.192 12.713,79.192 11.827,78.306 11.827,77.406 11.494,77.073 7.506,77.073 6.915,77.664 6.915,78.952 7.624,79.661 7.624,82.018 6.5,83.142 6.5,88.188 6.497,88.191 6.497,88.268 4.169,90.597 3.891,90.597 2.99,91.497 2.99,92.647 2.113,93.524 2.113,98.179 1.189,99.103 1.189,104.473 2.442,105.726 2.442,111.377 2.731,111.665 2.731,120.157 3.544,120.971 5.162,120.971 6.266,122.074 6.266,124.766 7.243,125.744 7.243,127.483 9.741,129.981 14.129,129.981 15.726,131.578 15.726,134.785 16.664,135.723 21.761,135.723 25.081,132.403 32.422,132.403 v1(33.559,133.54)
  other v2: 20.38,78.34 33.559,133.54
MD_GPIO_81_1: MODULE1.M46 U33_2.3 | length 136.8
  TOP_L1 w0.127: v1(19.88,78.34) 20.169,78.629 21.583,78.629 21.661,78.551 28.734,78.551 30.28,77.006 30.28,72.347 30.878,71.749 32.156,71.749 33.175,70.731 38.899,70.731 40.25,69.38 U33_2.3@40.25,67.7 ; v1(33.859,134.84) 33.876,134.823 34.469,134.823 MODULE1.M46@35.082,135.436
  L3 w0.127: v1(19.88,78.34) 17.734,78.34 17.719,78.326 15.531,78.326 14.902,78.956 12.798,78.956 12.054,78.212 12.054,77.312 11.588,76.846 7.412,76.846 6.688,77.57 6.688,79.046 7.397,79.755 7.397,81.924 6.273,83.048 6.273,88.094 6.27,88.096 6.27,88.174 4.075,90.37 3.797,90.37 2.763,91.403 2.763,92.553 1.886,93.43 1.886,98.085 0.962,99.009 0.962,104.567 2.215,105.821 2.215,111.471 2.504,111.759 2.504,120.251 3.45,121.198 5.068,121.198 6.039,122.168 6.039,124.86 7.016,125.838 7.016,127.577 9.683,130.244 14.071,130.244 15.499,131.672 15.499,134.93 16.57,136.002 21.803,136.002 25.124,132.681 32.233,132.681 33.859,134.307 v1(33.859,134.84)
  other v2: 19.88,78.34 33.859,134.84
MD_GPIO_82_1: MODULE1.L45 U21_3.4 | length 39.2
  TOP_L1 w0.084: v2(11.486,146.375) U21_3.4@11.486,147.575
  TOP_L1 w0.127: v2(33.477,134.623) 33.486,134.623 33.873,134.236 MODULE1.L45@33.882,134.236
  L3 w0.127: v2(11.486,146.375) 12.4,147.288 12.4,150.856 12.919,151.375 20.548,151.375 21.559,150.364 24.357,150.364 34.038,140.683 34.038,135.592 33.477,135.031 v2(33.477,134.623)
  other v1: 33.477,134.623 11.486,146.375
MD_GPIO_83_1: MODULE1.L46 U33_4.6 | length 130.5
  TOP_L1 w0.127: U33_4.6@15.25,67.7 15.26,67.71 15.26,70.439 v1(15.269,70.449) ; v2(33.171,135.036) 33.482,135.036 MODULE1.L46@33.882,135.436
  L3 w0.127: v1(15.269,70.449) 15.562,70.742 15.562,70.843 15.832,71.112 16.133,71.112 16.195,71.05 23.87,71.05 25.5,72.68 25.5,74.798 22.548,77.75 19.607,77.75 19.258,78.099 15.437,78.099 14.808,78.729 12.892,78.729 12.281,78.118 12.281,77.218 11.682,76.619 7.318,76.619 6.461,77.476 6.461,79.14 7.17,79.849 7.17,81.811 6.046,82.936 6.046,88 6.043,88.002 6.043,88.08 3.981,90.143 3.703,90.143 2.536,91.309 2.536,92.459 1.659,93.336 1.659,97.991 0.735,98.915 0.735,104.661 1.988,105.915 1.988,111.565 2.277,111.853 2.277,120.345 3.356,121.425 4.974,121.425 5.812,122.262 5.812,125.002 6.789,125.979 6.789,127.671 9.63,130.512 14.019,130.512 15.272,131.766 15.272,135.084 16.476,136.289 21.837,136.289 25.158,132.968 31.414,132.968 33.171,134.725 v2(33.171,135.036)
  other v1: 33.171,135.036
  other v2: 15.269,70.449
MD_GPIO_85: MODULE1.AA40 R379.1 U33_4.4 | length 211.2
  TOP_L1 w0.127: v2(15.842,70.347) 16.25,69.938 U33_4.4@16.25,67.7 ; MODULE1.AA40@45.882,128.236 45.997,128.121 45.997,127.774 46.091,127.68 v2(46.091,127.646)
  L3 w0.127: v5(15.982,70.749) 15.93,70.697 15.93,70.468 15.842,70.38 v2(15.842,70.347) 17.425,70.347 17.811,70.732 22.94,70.732 23.289,70.384 26.604,70.384 27.277,71.056 27.277,74.089 21.51,79.855 17.323,79.855 17.155,79.688 16.096,79.688 15.432,80.351 9.232,80.351 8.759,80.823 8.759,82.488 7.635,83.612 7.635,88.658 7.632,88.661 7.632,88.738 4.639,91.732 4.562,91.732 4.361,91.732 4.125,91.967 4.125,92.168 4.125,93.117 3.254,93.987 3.254,98.643 3.193,98.704 3.193,103.242 4.239,104.288 4.239,106.452 3.767,106.923 3.767,108.619 3.35,109.035 3.35,111 3.639,111.289 3.639,119.426 4.153,119.94 5.6,119.94 7.174,121.514 7.174,124.28 8.153,125.259 8.153,126.723 8.448,127.017 8.448,127.597 8.608,127.758 11.645,127.758 13.119,129.232 23.024,129.232 26.618,125.638 33.979,125.638 34.884,124.733 42.999,124.733 45.232,126.966 45.411,126.966 v2(46.091,127.646)
  L8 w0.1: v5(15.982,70.749) 15.982,69.249 15.182,68.449 15.182,63.406 7.431,55.655 7.431,48.259 9.137,46.552 9.137,45.546 10.259,44.424 10.297,44.424 10.458,44.263 10.458,44.225 15.876,38.807 15.876,29.114 15.905,29.085 15.905,27.917 15.924,27.898 15.924,22.821 16.22,22.525 16.22,16.76 19.5,13.48 21.147,13.48 21.269,13.359 21.269,13.092 21.851,12.51 24.044,12.51 24.172,12.638 25.561,12.638 26.633,13.71 27.88,13.71 v3(28.306,13.284)
  BOTTOM_L10 w0.1: R379.1@28.3,13.76 28.306,13.754 v3(28.306,13.284)
  other v1: 15.842,70.347 46.091,127.646
  other v4: 28.306,13.284
MD_GPIO_86: MODULE1.AA39 R378.1 U33_4.7 | length 200.8
  TOP_L1 w0.127: U33_4.7@14.75,67.7 v1(14.75,70.03) ; v1(45.205,126.446) 45.229,126.469 45.315,126.469 MODULE1.AA39@45.882,127.036
  L3 w0.1: v5(7.243,56.067) 7.8,55.51 7.8,55.2 9.223,53.777 9.223,50.155 9.793,49.585 9.793,42.216 v5(10.187,41.823)
  L3 w0.127: v5@14.406,70.349 14.726,70.03 14.783,70.03 14.878,69.935 15.055,69.935 15.132,70.012 15.433,70.012 15.509,69.935 26.655,69.935 27.504,70.783 27.504,74.965 21.664,80.805 13.183,80.805 10.308,83.68 10.308,84.012 10.24,84.081 10.24,126.032 13.213,129.005 22.93,129.005 26.524,125.411 33.885,125.411 34.79,124.506 43.266,124.506 v1(45.205,126.446)
  L8 w0.1: v5(7.243,56.067) 7.243,56.583 7.248,56.588 7.248,56.744 14.582,64.078 14.582,70.149 v5(14.382,70.349) ; v5(10.187,41.823) 10.51,41.5 11.856,41.5 13.716,39.64 13.716,38.23 15.052,36.894 15.052,32.94 14.011,31.9 13.461,31.9 13.3,31.739 13.3,31.511 13.787,31.023 13.787,30.748 14.275,30.261 14.275,30.078 14.893,29.46 14.893,28.824 15.026,28.691 15.026,28.489 15.176,28.339 15.176,21.085 15.662,20.599 15.662,16.469 19.14,12.991 20.719,12.991 21.6,12.11 24.209,12.11 24.338,12.238 26.41,12.238 v4(27.199,13.027)
  BOTTOM_L10 w0.1: R378.1@26.9,13.76 26.9,13.326 v4(27.199,13.027)
  other v2: 14.75,70.03 45.205,126.446
  other v3: 27.199,13.027
MD_GPIO_87: MODULE1.AB42 R377.1 U33_4.5 | length 202.9
  TOP_L1 w0.127: U33_4.5@15.75,67.7 15.756,67.706 15.756,69.559 15.762,69.565 v2(15.762,69.573) ; MODULE1.AB42@47.082,130.636 47.471,130.248 v1(47.471,129.892)
  L3 w0.1: v5(7.598,56.599) 8,56.198 8,55.5 9.507,53.993 9.507,50.22 9.993,49.734 9.993,42.749 10.092,42.65 10.092,42.479 v5(10.15,42.422)
  L3 w0.127: v5(15.282,69.648) 15.282,69.572 15.356,69.572 15.433,69.649 15.644,69.649 15.728,69.565 v2@15.762,69.565 ; v2(15.762,69.573) v2@15.762,69.565 ; v1(47.471,129.892) 47.471,128.537 46.097,127.163 46.097,126.374 43.963,124.24 34.735,124.24 33.791,125.184 26.255,125.184 22.662,128.778 13.307,128.778 10.467,125.938 10.467,84.175 10.535,84.106 10.535,83.774 13.277,81.032 21.758,81.032 27.854,74.936 27.854,70.334 27.069,69.549 15.777,69.549 v2@15.762,69.565
  L8 w0.1: v5@7.711,56.626 14.882,63.797 14.882,68.667 15.282,69.067 v5(15.282,69.648) ; v5(10.15,42.422) 10.572,42 11.832,42 15.452,38.381 15.452,31.456 14.758,30.763 14.68,30.763 14.409,30.492 14.409,30.409 14.475,30.344 14.475,30.161 15.093,29.543 15.093,28.907 15.226,28.774 15.226,28.571 15.376,28.421 15.376,21.401 15.993,20.784 15.993,16.562 19.364,13.191 20.802,13.191 21.683,12.31 24.126,12.31 24.255,12.438 25.644,12.438 26.516,13.31 27.562,13.31 v4(27.602,13.27)
  BOTTOM_L10 w0.1: R377.1@27.6,13.76 27.602,13.758 v4(27.602,13.27)
  other v1: 15.762,69.573
  other v2: 47.471,129.892
  other v3: 27.602,13.27
MD_GPIO_88_1: MODULE1.AB40 U33_2.9 | length 120.3
  TOP_L1 w0.127: v1(30.169,69.949) 31.411,69.949 32.429,68.931 36.46,68.931 37.25,68.14 U33_2.9@37.25,67.7 ; v1(47.051,127.71) 47.082,127.741 MODULE1.AB40@47.082,128.236
  L3 w0.127: v1(30.169,69.949) 28.969,69.949 28.172,70.747 28.172,74.939 21.852,81.259 13.371,81.259 10.762,83.868 10.762,84.2 10.694,84.269 10.694,125.844 13.401,128.551 22.44,128.551 26.052,124.939 33.715,124.939 34.641,124.013 44.644,124.013 45.569,124.939 45.851,124.939 47.051,126.139 v1(47.051,127.71)
  other v2: 30.169,69.949 47.051,127.71
MD_GPIO_89_1: MODULE1.AD39 U33_2.6 | length 127.7
  TOP_L1 w0.127: v2(30.569,70.849) 31.783,70.849 32.802,69.831 38.599,69.831 39.193,69.236 39.193,68.614 39.023,68.443 38.882,68.443 38.75,68.311 U33_2.6@38.75,67.7 ; MODULE1.AD39@49.482,127.036 49.829,127.383 49.829,127.448 v2(49.853,127.472)
  L3 w0.127: v2(30.569,70.849) 28.769,70.849 28.491,71.127 28.491,77.663 24.668,81.486 13.465,81.486 10.989,83.962 10.989,84.294 10.921,84.363 10.921,125.749 13.495,128.324 22.346,128.324 26.308,124.362 29.002,124.362 30.41,122.953 47.463,122.953 49.853,125.343 v2(49.853,127.472)
  other v1: 30.569,70.849 49.853,127.472
MD_GPIO_90_1: MODULE1.AE39 U33_3.9 | length 100.7
  TOP_L1 w0.127: v2(27.789,67.7) U33_3.9@28.25,67.7 ; v1(50.624,127.504) 50.648,127.48 50.648,127.07 MODULE1.AE39@50.682,127.036
  L3 w0.127: v5(29.602,122.856) 30.186,122.856 30.316,122.726 47.824,122.726 50.624,125.526 v1(50.624,127.504)
  L8 w0.127: v2(27.789,67.7) 27.789,68.169 30.104,70.484 30.104,97.482 30.086,97.5 30.086,98.262 30.104,98.281 30.104,104.655 31.236,105.787 31.236,106.251 33.162,108.176 42.196,108.176 42.345,108.325 42.345,111.576 41.744,112.177 35.368,112.177 29.602,117.943 v5(29.602,122.856)
  other v1: 27.789,67.7
  other v2: 50.624,127.504
  other v5: 27.789,67.7
MD_GPIO_92_1: MODULE1.AE41 R366.2 | length 149.5
  TOP_L1 w0.127: v1(44.963,78.129) 48.839,78.129 49.067,78.358 54.378,78.358 56.658,76.078 56.658,73.354 56.658,73.147 67.87,61.935 67.87,55.137 67.542,54.81 67.542,46.767 60.639,39.864 54.846,39.864 52.338,37.356 52.338,30.383 51.964,30.008 v2(51.964,24.629) ; v2(45.169,106.549) 45.169,111.573 52.482,118.886 52.482,125.983 52.087,126.378 51.412,126.378 51.211,126.58 51.211,128.908 MODULE1.AE41@50.682,129.436
  L3 w0.127: v1(44.963,78.129) 44.953,78.139 44.953,105.533 45.169,105.749 v2(45.169,106.549) ; v5(46.863,20.469) 46.917,20.469 47.867,21.419 48.145,21.419 51.355,24.629 v2(51.964,24.629)
  BOTTOM_L10 w0.127: v5(46.863,20.469) 46.84,20.446 46.84,15.108 48.9,13.049 R366.2@48.936,13.049
  other v1: 51.964,24.629 45.169,106.549
  other v2: 44.963,78.129
  other v3: 46.863,20.469
  other v4: 46.863,20.469
MD_GPIO_93_1: MODULE1.V43 U22.D5 | length 133.6
  TOP_L1 w0.127: v1(27.169,120.449) 31.995,120.449 32.069,120.523 32.069,122.649 32.269,122.849 36.468,122.849 36.811,123.192 36.811,129.811 37.108,130.108 37.701,130.108 38.003,130.41 38.161,130.41 38.463,130.108 38.901,130.108 39.211,130.417 39.211,130.855 39.085,130.981 39.085,131.138 39.196,131.25 41.696,131.25 MODULE1.V43@42.282,131.836
  L3 w0.127: v1(27.169,120.449) 27.169,120.225 27.27,120.124 v5(27.27,120.05)
  L8 w0.127: v5(27.27,120.05) 27.27,117.91 31.501,113.68 31.501,111.219 32.37,110.35 40.17,110.35 40.624,110.804 41.116,110.804 41.77,110.15 41.77,109.039 v3(41.423,108.692)
  BOTTOM_L10 w0.127: v3(41.423,108.692) 47.756,108.692 48.783,107.665 64.174,107.665 66.723,105.116 66.723,99.788 58.255,91.32 58.255,75.223 70.635,62.843 70.635,62.503 72.676,60.462 74.638,58.5 v4(75.075,58.5)
  other v1: 75.075,58.5
  other v2: 75.075,58.5 27.169,120.449
  other v3: 75.075,58.5
  other v4: 41.423,108.692
  other v5: 75.075,58.5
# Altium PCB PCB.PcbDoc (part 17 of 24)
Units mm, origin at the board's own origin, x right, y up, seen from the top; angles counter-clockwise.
Board outline 100 x 160 mm, 10 copper layers (TOP_L1, L2, L3, L4, L5, L6, L7, L8, L9, BOTTOM_L10), stack 1.946 mm thick; 1358 components, 1149 nets, 6777 pads, 10914 vias.

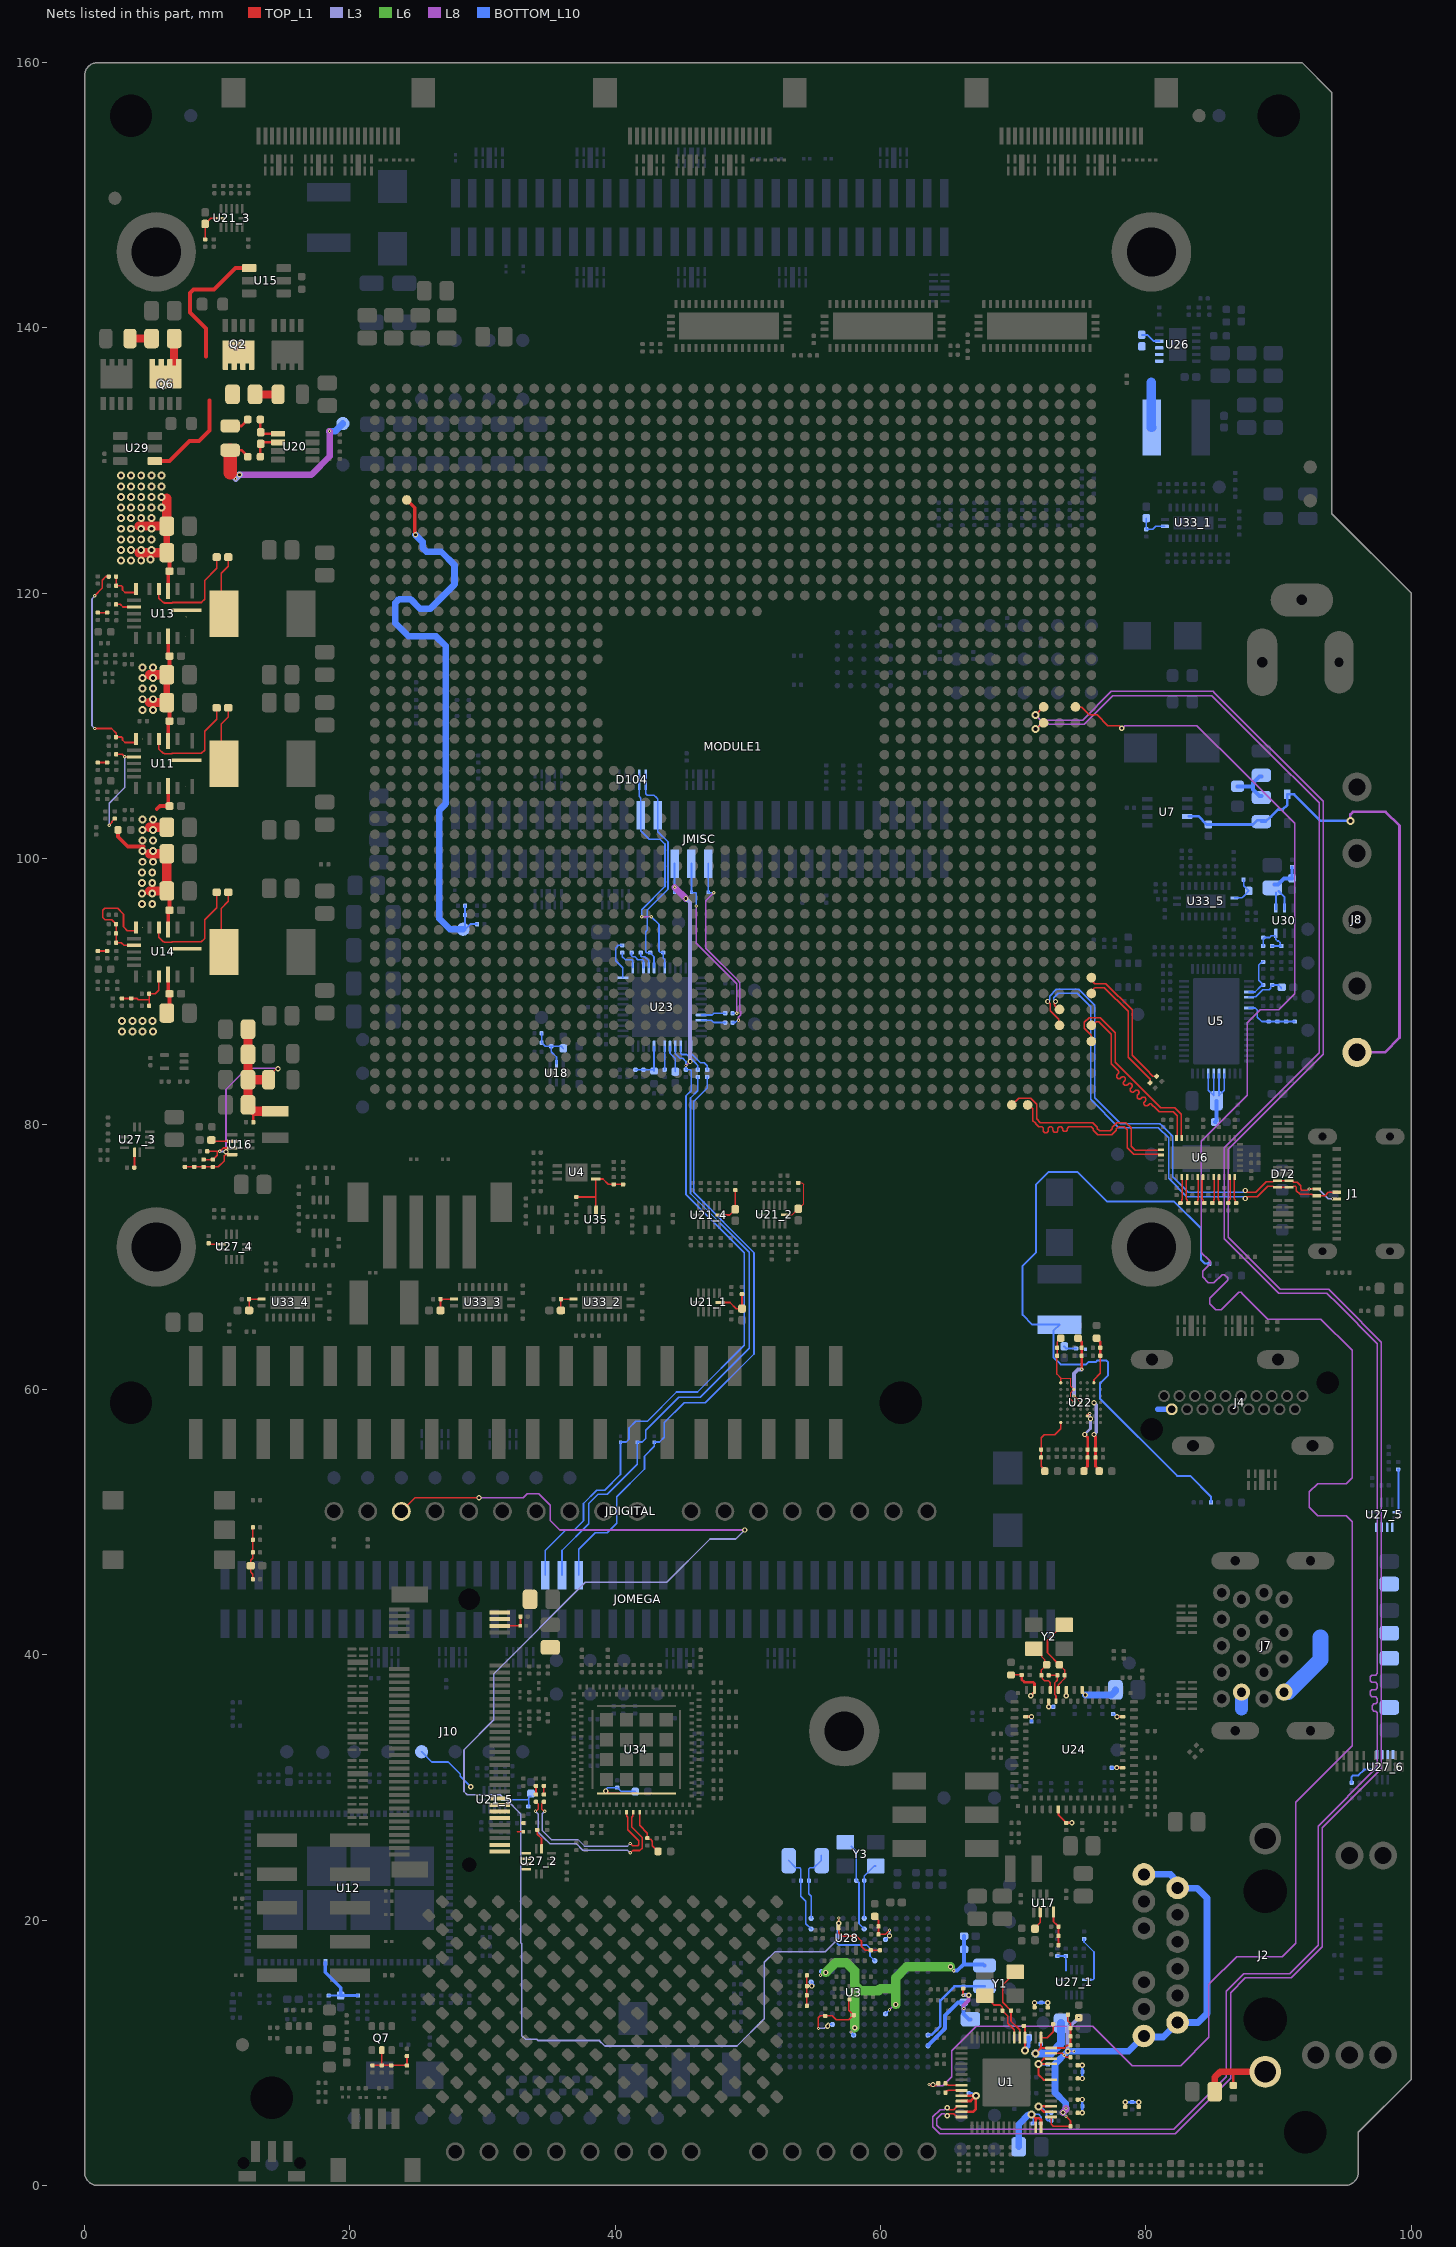
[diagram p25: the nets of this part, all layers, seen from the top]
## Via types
v1: diameter 0.25, hole 0.1, TOP_L1 to L2, tented both sides, 3439 vias
v2: diameter 0.25, hole 0.1, L2 to L3, tented both sides, 2256 vias
v3: diameter 0.25, hole 0.1, L9 to BOTTOM_L10, tented both sides, 1685 vias
v4: diameter 0.25, hole 0.1, L8 to L9, tented both sides, 1675 vias
v5: diameter 0.4, hole 0.2, L3 to L8, tented both sides, 1251 vias
v6: diameter 0.6, hole 0.3, TOP_L1 to BOTTOM_L10, tented both sides, 600 vias
v7: diameter 0.24, hole 0.1, TOP_L1 to L2, tented both sides, 8 vias

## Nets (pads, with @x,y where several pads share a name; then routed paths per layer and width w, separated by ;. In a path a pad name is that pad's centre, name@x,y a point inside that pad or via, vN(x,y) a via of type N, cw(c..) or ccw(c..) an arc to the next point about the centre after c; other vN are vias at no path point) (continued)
MD_SGMII0.RX_1_P: C247.2 MODULE1.BE26 | length 167.6
  TOP_L1 w0.109: v1(63.65,7.612) 63.688,7.612 63.791,7.508 64.151,7.508 64.327,7.685 64.341,7.685 C247.2@64.341,7.7 ; MODULE1.BE26@74.682,111.436 74.726,111.393 75.147,111.393 75.709,110.831 76.318,110.831 77.116,110.033 77.984,110.033 v5(78.182,109.835)
  L3 w0.104: v1(63.65,7.612) 63.656,7.606 63.936,7.606 v5(63.942,7.6)
  L8 w0.104: v5(63.942,7.6) 63.999,7.543 64.171,7.543 64.212,7.502 64.677,7.502 65.373,8.198 65.373,10.132 67.22,11.979 76.004,11.979 78.958,9.025 82.601,9.025 84.732,11.157 84.732,15.141 84.822,15.23 86.828,17.236 90.282,17.236 91.301,18.255 91.301,28.876 95.551,33.126 95.551,49.88 95.551,50.021 95.098,50.474 92.935,50.474 92.303,51.106 92.303,52.265 92.935,52.896 95.098,52.896 95.551,53.349 95.551,54.103 95.551,62.933 93.184,65.3 89.185,65.3 87.27,67.215 87.17,67.315 86.997,67.315 85.683,66.001 85.257,66.001 84.819,66.439 84.819,66.865 86.176,68.222 86.176,68.395 85.916,68.654 85.743,68.654 85.123,68.034 84.697,68.034 84.259,68.473 84.259,68.898 84.836,69.475 84.836,69.649 84.496,69.988 84.396,70.088 84.256,70.229 84.166,70.318 84.166,78.696 87.62,82.15 87.62,87.641 88.606,88.627 90.01,88.627 91.217,89.834 91.217,102.658 87.186,106.689 83.842,110.033 78.391,110.033 78.193,109.835 v5(78.182,109.835)
  other v1: 78.182,109.835
  other v2: 63.65,7.612 78.182,109.835
MD_SGMII0.TX_1_N: MODULE1.BC25 U1.42 | length 167.6
  TOP_L1 w0.109: v5(65.017,5.259) 65.165,5.407 65.504,5.407 65.607,5.304 65.611,5.304 65.756,5.159 U1.42@66.106,5.159 ; v6(71.682,109.756) 71.742,109.756 72.222,110.236 MODULE1.BC25@72.282,110.236
  L8 w0.104: v5(65.017,5.259) 64.937,5.259 64.79,5.407 64.607,5.407 64.24,5.04 64.24,4.54 64.34,4.44 64.564,4.216 82.092,4.216 86.066,8.191 86.066,14.651 87.362,15.947 90.816,15.947 92.977,18.108 92.977,27.08 97.442,31.545 97.442,33.928 97.442,35.611 97.307,35.747 97.175,35.747 97.039,35.883 97.039,36.154 97.175,36.289 97.307,36.289 97.442,36.425 97.442,36.696 97.307,36.831 97.032,36.831 96.897,36.967 96.897,37.238 97.032,37.373 97.307,37.373 97.442,37.509 97.442,37.78 97.307,37.916 97.032,37.916 96.897,38.051 96.897,38.322 97.032,38.458 97.307,38.458 97.442,38.593 97.442,39.187 97.442,63.442 94.48,66.404 93.633,67.251 89.993,67.251 85.981,71.263 85.892,71.352 85.892,78.224 86.071,78.403 93.044,85.376 93.044,104.197 88.958,108.283 84.945,112.296 77.5,112.296 75.526,110.322 75.348,110.144 72.07,110.144 v6(71.682,109.756)
  other v1: 65.017,5.259
  other v2: 65.017,5.259
MD_SGMII0.TX_1_P: MODULE1.BC26 U1.40 | length 167.6
  TOP_L1 w0.109: v1(65.017,5.859) 65.165,5.711 65.504,5.711 65.607,5.814 65.611,5.814 65.756,5.959 U1.40@66.106,5.959 ; v6(71.682,110.836) MODULE1.BC26@72.282,111.436
  L8 w0.104: v1(65.017,5.859) 64.937,5.859 64.79,5.711 64.48,5.711 63.935,5.166 63.935,4.414 64.114,4.235 64.438,3.911 82.218,3.911 86.371,8.064 86.371,14.525 87.488,15.642 90.942,15.642 93.282,17.982 93.282,26.954 97.747,31.419 97.747,63.568 94.785,66.53 93.759,67.556 90.119,67.556 86.197,71.478 86.197,78.098 93.349,85.25 93.349,104.323 85.16,112.512 85.071,112.601 77.374,112.601 75.221,110.448 72.07,110.448 v6(71.682,110.836)
  other v2: 65.017,5.859
  other v5: 65.017,5.859
MD_USB0_3.1.HS_D_1_N: D72.2 D72.9 J1.A7 J1.B7 MODULE1.BD6 | length 38.2
  TOP_L1 w0.109: v1(72.582,89.236) 72.595,89.236 72.768,89.063 72.768,88.885 72.802,88.851 72.802,88.538 73.439,87.901 73.439,87.479 MODULE1.BD6@73.482,87.436 ; v2(87.482,74.986) 87.63,74.838 88.265,74.838 89.058,75.631 89.572,75.631 89.669,75.729 D72.9@89.907,75.729 D72.2@90.782,75.729 91.019,75.729 91.153,75.596 91.409,75.596 91.648,75.357 91.648,75.102 91.744,75.006 92.165,75.006 92.263,75.104 J1.A7@92.876,75.104
  L3 w0.104: v2(92.301,75.104) 92.996,75.104 93.746,74.354 v2(94.051,74.354)
  BOTTOM_L10 w0.109: v1(72.582,89.236) 72.73,89.384 72.73,89.623 73.247,90.141 74.929,90.141 76.123,88.947 76.123,81.995 78.084,80.034 81.051,80.034 81.23,79.855 81.825,79.26 82.004,79.081 82.004,76.024 83.189,74.838 87.334,74.838 v2(87.482,74.986)
  other v1: 94.051,74.354 87.482,74.986 92.301,75.104
  other v2: 72.582,89.236
  other v3: 87.482,74.986 72.582,89.236
  other v4: 87.482,74.986 72.582,89.236
  other v5: 87.482,74.986 72.582,89.236
MD_USB0_3.1.HS_D_1_P: D72.1 D72.10 J1.A6 J1.B6 MODULE1.BD7 | length 35.6
  TOP_L1 w0.109: v5(73.182,89.236) 73.182,89.211 73.073,89.102 73.073,89.011 73.106,88.978 73.106,88.918 73.388,88.636 MODULE1.BD7@73.482,88.636 ; v2(87.482,74.386) 87.63,74.534 88.392,74.534 89.185,75.327 89.572,75.327 89.669,75.229 D72.10@89.907,75.229 ; D72.10@89.907,75.229 D72.1@90.782,75.229 ; D72.1@91.093,75.291 91.283,75.291 91.343,75.231 91.343,74.972 91.613,74.702 92.51,74.702 92.537,74.674 92.806,74.674 J1.A6@92.876,74.604 93.5,74.604 93.755,74.859 J1.B6@94.372,74.859
  BOTTOM_L10 w0.109: v5(73.182,89.236) 73.034,89.384 73.034,89.497 73.374,89.836 74.803,89.836 75.818,88.821 75.818,81.869 77.958,79.729 80.925,79.729 81.699,78.955 81.699,75.898 83.063,74.534 87.334,74.534 v2(87.482,74.386)
  other v1: 87.482,74.386 73.182,89.236
  other v2: 73.182,89.236
  other v3: 87.482,74.386 73.182,89.236
  other v4: 87.482,74.386 73.182,89.236
  other v5: 87.482,74.386
MD_USB0_3.1.SS_RX_1_N: MODULE1.BB1 U6.17 | length 15.2
  TOP_L1 w0.109: MODULE1.BB1@71.082,81.436 71.176,81.436 71.458,81.154 71.458,80.258 71.482,80.234 71.636,80.08 71.735,79.981 71.913,79.803 72.082,79.803 cw(c72.082,79.621) 72.263,79.621 72.263,79.518 ccw(c72.445,79.518) 72.627,79.518 72.627,79.621 cw(c72.808,79.621) 72.99,79.621 72.99,79.547 ccw(c73.171,79.547) 73.353,79.547 73.353,79.621 cw(c73.535,79.621) 73.716,79.621 ccw(c73.898,79.621) 74.079,79.621 cw(c74.261,79.621) 74.261,79.803 74.794,79.803 75.081,79.803 75.864,79.803 76.033,79.634 76.033,79.522 76.38,79.175 77.42,79.175 77.767,79.522 77.767,79.634 77.936,79.803 78.08,79.803 78.354,79.803 78.577,79.579 78.577,78.201 79.066,77.713 80.891,77.713 80.893,77.71 81.08,77.71 U6.17@81.125,77.665
MD_USB0_3.1.SS_RX_1_P: MODULE1.BA1 U6.16 | length 15.2
  TOP_L1 w0.109: MODULE1.BA1@69.882,81.436 70.402,81.956 71.297,81.956 71.762,81.49 71.762,80.384 72.039,80.107 75.081,80.107 75.99,80.107 76.337,79.76 76.337,79.649 76.506,79.48 77.294,79.48 77.463,79.649 77.463,79.76 77.81,80.107 78.08,80.107 78.48,80.107 78.882,79.705 78.882,78.328 79.192,78.017 80.891,78.017 80.893,78.02 81.08,78.02 U6.16@81.125,78.065
MD_USB0_3.1.SS_TX_1_N: MODULE1.BF6 U6.12 | length 15.2
  TOP_L1 w0.109: MODULE1.BF6@75.882,87.436 75.997,87.436 76.256,87.696 76.444,87.696 77.377,86.762 77.377,84.541 77.588,84.33 77.627,84.291 77.884,84.035 cw(c77.755,83.906) 77.884,83.778 77.836,83.73 ccw(c77.965,83.602) 77.836,83.473 ccw(c77.965,83.602) 78.093,83.473 78.14,83.521 cw(c78.269,83.392) 78.397,83.521 cw(c78.269,83.392) 78.397,83.264 78.35,83.217 ccw(c78.478,83.088) 78.35,82.96 ccw(c78.478,83.088) 78.607,82.96 78.654,83.007 cw(c78.783,82.879) 78.911,83.007 cw(c78.783,82.879) 78.911,82.75 78.864,82.703 ccw(c78.992,82.574) 78.864,82.446 ccw(c78.992,82.575) 79.12,82.446 79.168,82.493 cw(c79.296,82.365) 79.425,82.493 cw(c79.296,82.365) 79.425,82.237 79.377,82.189 ccw(c79.506,82.061) 79.377,81.932 ccw(c79.506,82.061) 79.634,81.932 79.681,81.98 cw(c79.81,81.851) 79.938,81.98 cw(c79.81,81.851) 79.938,81.723 79.895,81.679 ccw(c80.023,81.551) 79.895,81.422 ccw(c80.023,81.551) 80.151,81.422 80.195,81.466 cw(c80.324,81.338) 80.452,81.466 80.72,81.198 80.759,81.159 80.996,80.922 82.047,80.922 82.348,80.621 82.348,79.174 82.345,79.172 82.345,78.985 U6.12@82.3,78.94
MD_USB0_3.1.SS_TX_1_P: MODULE1.BF5 U6.11 | length 15.2
  TOP_L1 w0.109: MODULE1.BF5@75.882,86.236 75.882,86.701 75.362,87.221 75.362,87.651 75.712,88.001 76.57,88.001 77.682,86.889 77.682,84.667 81.122,81.227 82.173,81.227 82.652,80.748 82.652,79.174 82.655,79.172 82.655,78.985 U6.11@82.7,78.94
MD_USB1_2.0.HS_D_1_N: MODULE1.BF8 R383.1 | length 9.9
  TOP_L1 w0.109: MODULE1.BF8@75.882,89.836 75.882,90.004 76.059,90.181 76.059,90.22 76.123,90.284 76.34,90.284 76.85,90.284 78.65,88.484 78.65,85.04 79.704,83.986 80.306,83.384 R383.1@80.305,83.105
MD_USB1_2.0.HS_D_1_P: MODULE1.BF9 R382.1 | length 10.1
  TOP_L1 w0.109: MODULE1.BF9@75.882,91.036 75.882,90.868 76.059,90.691 76.059,90.652 76.123,90.588 76.214,90.588 76.976,90.588 78.955,88.61 78.955,85.166 80.009,84.112 80.521,83.599 R382.1@80.8,83.6
MIC_IN5_IN6.BIAS_1: C110.2 D24.2 D100.2 JMISC.33 JOMEGA.61 U23.28 | length 67.6
  L3 w0.3: v5(45.323,96.997) 45.637,96.683 v5(45.637,84.715)
  L8 w0.127: v3(45.323,84.403) 45.635,84.715 v5(45.637,84.715)
  L8 w0.5: v3(44.474,97.846) v5(45.323,96.997)
  BOTTOM_L10 w0.127: JOMEGA.61@34.716,46 34.716,47.86 36.256,49.4 36.9,49.4 37.6,50.1 37.6,51.4 38.6,52.4 39.2,52.4 40.386,53.586 40.386,56.038 40.825,56.038 41.034,56.247 41.034,57.086 41.554,57.606 42.424,57.606 44.618,59.8 46.199,59.8 49.723,63.325 49.723,70.304 45.323,74.705 45.323,82.116 45.723,82.516 45.723,84.016 45.648,84.091 C110.2@45.323,84.091 v3(45.323,84.403) 45.323,84.715 45.073,84.965 44.871,84.965 44.523,85.313 U23.28@44.523,85.866 ; D100.2@44.469,97.429 JMISC.33@44.469,99.629
  other v4: 45.323,84.403 44.474,97.846
MIC_IN5_IN6.INN_1: C254.2 D21.2 JOMEGA.59 | length 47
  BOTTOM_L10 w0.127: JOMEGA.59@35.986,46 35.986,47.854 38,49.867 38,51.4 38.7,52.1 39.4,52.1 41.656,54.356 41.656,56.038 42.038,56.038 42.3,56.3 42.3,56.91 44.79,59.4 46.4,59.4 50.089,63.089 50.089,70.343 45.669,74.763 45.669,81.962 46.223,82.516 C254.2@46.223,83.541
MIC_IN5_IN6.INP_1: C253.2 D17.2 JOMEGA.57 | length 47
  BOTTOM_L10 w0.127: JOMEGA.57@37.256,46 37.256,47.956 38.5,49.2 39.4,49.2 40.1,49.9 40.1,51.9 42.197,53.997 42.197,54.97 42.926,55.699 42.926,56.038 43.338,56.038 43.7,56.4 43.7,57.5 45.2,59 46.785,59 50.456,62.671 50.456,70.297 45.904,74.849 45.904,81.697 46.923,82.716 C253.2@46.923,83.541
MUX_SSRX1_30_N: C51.1 U6.24 | length 2
  TOP_L1 w0.109: C51.1@82.6,74.087 82.69,74.177 82.69,74.288 82.748,74.345 82.748,75.765 ; U6.24@82.7,75.99 82.745,75.945 82.745,75.758
MUX_SSRX1_30_P: C50.1 U6.25 | length 2
  TOP_L1 w0.109: U6.25@83.1,75.99 83.055,75.945 83.055,75.758 83.052,75.756 83.052,75.638 83.052,74.345 83.11,74.288 83.11,74.177 C50.1@83.2,74.087
MUX_SSRX2_30_N: C53.1 U6.33 | length 2
  TOP_L1 w0.109: C53.1@86.2,74.087 86.29,74.177 86.29,74.288 86.348,74.345 86.348,74.548 86.348,75.765 ; U6.33@86.3,75.99 86.345,75.945 86.345,75.758
MUX_SSRX2_30_P: C52.1 U6.34 | length 2
  TOP_L1 w0.109: U6.34@86.7,75.99 86.655,75.945 86.655,75.758 86.652,75.756 86.652,75.638 86.652,74.548 86.652,74.345 86.71,74.288 86.71,74.177 C52.1@86.8,74.087
MUX_TX1_30_N: R452.2 U6.27 | length 2
  TOP_L1 w0.109: R452.2@83.8,74.087 83.89,74.177 83.89,74.288 83.948,74.345 83.948,74.801 83.948,75.765 ; U6.27@83.9,75.99 83.945,75.945 83.945,75.758
MUX_TX1_30_P: R451.2 U6.28 | length 2
  TOP_L1 w0.109: U6.28@84.3,75.99 84.255,75.945 84.255,75.758 84.252,75.756 84.252,75.638 84.252,75.13 84.252,74.497 84.252,74.345 84.31,74.288 84.31,74.177 R451.2@84.4,74.087
MUX_TX2_30_N: R454.2 U6.30 | length 2
  TOP_L1 w0.109: R454.2@85,74.042 85.099,74.14 85.099,74.297 85.148,74.345 85.148,75.765 ; U6.30@85.1,75.99 85.145,75.945 85.145,75.758
MUX_TX2_30_P: R453.2 U6.31 | length 2
  TOP_L1 w0.109: U6.31@85.5,75.99 85.455,75.945 85.455,75.758 85.452,75.756 85.452,75.638 85.452,74.548 85.452,74.345 85.501,74.297 85.501,74.14 R453.2@85.599,74.042
NetC4_2: C4.2 R69.1 R70.1 | length 1.7
  TOP_L1 w0.15: R70.1@78.448,5.924 v3(78.448,6.274) ; R69.1@79.448,5.924 v1(79.448,6.274)
  BOTTOM_L10 w0.2: v3(78.448,6.274) C4.2@78.948,6.274 v1(79.448,6.274)
  other v1: 78.448,6.274
  other v2: 78.448,6.274 79.448,6.274
  other v3: 79.448,6.274
  other v4: 78.448,6.274 79.448,6.274
  other v5: 78.448,6.274 79.448,6.274
NetC5_2: C5.2 R71.1 R72.1 | length 1.7
  TOP_L1 w0.15: R71.1@74.856,5.47 v1(75.206,5.47) ; R72.1@74.856,6.47 v1(75.206,6.47)
  BOTTOM_L10 w0.2: v1(75.206,5.47) v1(75.206,6.47)
  other v2: 75.206,5.47 75.206,6.47
  other v3: 75.206,5.47 75.206,6.47
  other v4: 75.206,5.47 75.206,6.47
  other v5: 75.206,5.47 75.206,6.47
NetC6_2: C6.2 R73.1 R74.1 | length 1.7
  TOP_L1 w0.15: R73.1@74.856,8.059 v1(75.206,8.059) ; R74.1@74.856,9.059 v1(75.206,9.059)
  BOTTOM_L10 w0.2: v1(75.206,8.059) v1(75.206,9.059)
  other v2: 75.206,8.059 75.206,9.059
  other v3: 75.206,8.059 75.206,9.059
  other v4: 75.206,8.059 75.206,9.059
  other v5: 75.206,8.059 75.206,9.059
NetC7_2: C7.2 R75.1 R76.1 | length 1.7
  TOP_L1 w0.15: R76.1@71.6,13.425 v1(71.6,13.775) ; R75.1@72.6,13.425 v1(72.6,13.775)
  BOTTOM_L10 w0.2: v1(71.6,13.775) v1(72.6,13.775)
  other v2: 71.6,13.775 72.6,13.775
  other v3: 71.6,13.775 72.6,13.775
  other v4: 71.6,13.775 72.6,13.775
  other v5: 71.6,13.775 72.6,13.775
NetC12_2: C12.2 C13.2 J2.1 J2.6 J2.7 J2.12 L1.1 U1.1 U1.13 | length 40.4
  TOP_L1 w0.127: U1.1@72.856,5.159 72.856,4.624 73.021,4.459 C13.2@74.306,4.459 74.306,4.885 v2(73.973,5.218) ; U1.13@72.856,9.959 73.681,9.959 v1(73.831,9.809) 73.981,9.659 C12.2@74.306,9.659 ; L1.1@74.94,12.64 L1.1@74.949,12.631
  L3 w0.127: v5(73.74,5.491) 73.74,5.471 73.973,5.238 v2(73.973,5.218) ; v1(73.831,9.809) v5(74.1,10.108)
  L3 w0.3: v5(74.1,10.108) 74.1,11.808 v1(74.942,12.651)
  L8 w0.127: v5(74.1,10.108) v4@74.58,10.108
  L8 w0.5: v5(73.74,5.491) 73.973,5.725 v3(73.973,5.818)
  BOTTOM_L10 w0.5: v3(73.973,5.818) 73.948,5.843 73.948,6.189 73.145,6.992 73.145,9.152 74.101,10.108 v4(74.58,10.108) ; v3@74.55,10.108 78.692,10.108 J2.12@79.844,11.26 79.913,11.191 81.3,11.191 J2.6@82.384,12.275 83.917,12.275 84.6,12.958 84.6,21.658 83.85,22.408 82.401,22.408 J2.1@82.384,22.425 82.283,22.526 82.283,23.001 81.844,23.44 J2.7@79.844,23.44
  other v1: 73.973,5.218
  other v2: 73.831,9.809 74.942,12.651
  other v3: 74.58,10.108
  other v4: 73.973,5.818
NetC16_2: C16.2 C17.2 C18.2 C19.2 C20.2 C21.2 C22.2 C25.2 C26.2 C27.2 C28.2 C29.2 C30.2 C73.1 C74.1 L2.1 U1.2 U1.3 U1.8 U1.11 U1.12 U1.14 U1.15 U1.18 U1.38 U1.39 U1.41 U1.55 U1.56 | length 36.5
  TOP_L1 w0.127: C20.2@70.8,12.025 70.881,11.944 U1.18@70.881,11.134 ; v6(71.881,9.159) 72.281,9.559 U1.12@72.856,9.559 ; U1.15@72.081,11.134 72.556,11.134 73.006,11.584 C21.2@73.006,12.159 ; U1.14@72.856,10.359 73.859,10.359 74.059,10.559 C17.2@74.306,10.559 ; C22.2@74.113,12.877 74.113,12.396 74.306,12.203 C16.2@74.306,11.859 C19.2@74.306,11.234 C17.2@74.306,10.559 ; C17.2@74.306,10.553 C17.2@74.306,10.559
  TOP_L1 w0.15: v6(70.881,10.159) U1.18@70.881,11.134 ; v6(71.681,9.959) 72.081,10.359 ; U1.15@72.081,11.134 72.081,10.359 ; U1.8@72.856,7.959 72.281,7.959 71.881,8.359 v6(71.881,9.159) U1.11@72.856,9.159 ; U1.14@72.856,10.359 72.081,10.359
  TOP_L1 w0.2: U1.41@66.106,5.559 66.981,5.559 67.181,5.759 v6(67.181,6.759) ; U1.39@66.106,6.359 66.781,6.359 v6(67.181,6.759) ; U1.38@66.106,6.759 v6(67.181,6.759) ; v6(71.381,5.359) 71.681,5.059 ; U1.55@71.681,4.384 71.681,5.059 ; U1.56@72.081,4.384 72.081,4.944 71.966,5.059 71.681,5.059 ; U1.2@72.856,5.559 72.281,5.559 v6(71.881,5.959) U1.3@72.856,5.959
  BOTTOM_L10 w0.127: C26.2@66.631,6.963 66.893,6.963 67.097,6.759 v6(67.181,6.759) ; C29.2@71.481,4.664 71.501,4.684 71.501,5.193 71.467,5.226 71.467,5.273 v6(71.381,5.359) 71.905,5.359 72.081,5.183 C30.2@72.081,4.664 ; v6(71.881,5.959) 71.989,5.959 72.182,5.767 72.22,5.767 72.495,5.492 ; v6(71.881,9.159) 71.881,9.113 C27.2@72.604,9.113 ; C18.2@72.856,4.892 72.559,4.892 72.495,4.956 72.495,5.492 ; C28.2@72.856,5.492 72.495,5.492
  BOTTOM_L10 w0.15: C25.2@72.054,10.663 72.054,10.061 72.156,9.959
  BOTTOM_L10 w0.3: v6(70.881,10.159) 70.881,10.225 71.131,10.475 L2.1@71.131,11.134
  BOTTOM_L10 w0.5: C73.1@70.404,2.913 70.404,4.589 71.155,5.34 71.362,5.34 v6(71.381,5.359)
  BOTTOM_L10 w0.6: v6(71.681,9.959) 72.054,9.959 72.859,9.959 73.601,10.701 C74.1@73.601,12.236
NetC23_1: C23.1 U1.20 Y1.3 | length 4.4
  TOP_L1 w0.127: Y1.3@67.85,14.3 67.95,14.3 68.436,13.814 68.436,13.714 68.55,13.6 69.022,13.6 69.175,13.447 C23.1@69.175,13.17 69.581,12.764 69.581,12.222 70.081,11.723 U1.20@70.081,11.134
NetC24_1: C24.1 U1.19 Y1.1 | length 5.7
  TOP_L1 w0.127: C24.1@69.825,13.17 69.2,13.795 69.2,15.1 69.664,15.564 69.664,15.613 69.95,15.9 Y1.1@70,15.9 ; C24.1@69.825,13.176 69.825,12.378 70.481,11.722 U1.19@70.481,11.134
NetC35_2: C35.2 C37.2 J7.10 U27_6.7 U27_6.8 U27_6.9 U27_6.10 | length 1.3
  BOTTOM_L10 w1: 87.198,35.901 87.2,35.903 J7.10@87.2,37.175
NetC36_2: C36.2 R85.2 U27_1.1 | length 1.8
  BOTTOM_L10 w0.127: C36.2@73.321,17.293 R85.2@73.956,17.293 73.956,17.026 73.966,17.015 73.966,16.715 73.966,16.181
NetC42_2: C42.2 C43.2 U5.29 | length 3.3
  BOTTOM_L10 w0.127: U5.29@87.753,89.947 88.21,89.947 88.654,90.391 88.723,90.391 88.735,90.404 C43.2@88.735,90.472 ; C43.2@88.828,90.472 88.822,90.472 88.779,90.515 88.732,90.562 88.732,90.609 88.494,90.846 88.494,91.978 88.707,92.191 88.747,92.191 C42.2@88.828,92.272
NetC44_1: C44.1 C45.2 U5.30 | length 3.1
  BOTTOM_L10 w0.127: U5.30@87.753,89.547 87.789,89.584 88.263,89.584 88.791,90.112 89.29,90.112 89.407,90.228 89.407,90.382 89.497,90.472 89.986,90.472 90.183,90.275 C44.1@90.183,90.197
NetC47_2: C47.2 C48.2 R274.1 R275.2 U5.32 | length 4.2
  BOTTOM_L10 w0.127: U5.32@87.753,88.747 88.244,88.747 88.394,88.598 88.394,88.057 88.729,87.722 R274.1@89.253,87.722 C48.2@89.903,87.722 R275.2@90.553,87.722 C47.2@91.213,87.722
NetC64_1: C64.1 C288.1 R434.2 U3.R13 | length 8.2
  TOP_L1 w0.15: R434.2@66.213,14.829 66.213,14.364 v2(66.232,14.345)
  L3 w0.3: v2(66.232,14.345) 66.241,14.336 v5(66.644,14.336)
  L8 w0.3: v3(66.255,13.335) 66.255,13.571 66.613,13.929 66.613,14.304 v5(66.644,14.336)
  BOTTOM_L10 w0.3: U3.R13@63.563,10.529 63.563,10.547 64.855,11.84 64.855,12.806 65.84,13.791 C64.1@66.255,13.791 66.255,13.355 66.255,12.918 66.653,12.521 C288.1@66.768,12.521
  other v1: 66.232,14.345
  other v4: 66.255,13.335
NetC65_2: C65.2 C277.2 R218.2 R351.2 U3.D7 | length 3.2
  TOP_L1 w0.127: R218.2@54.438,13.529 R351.2@54.438,14.329 C65.2@54.438,15.029 C277.2@54.438,15.829 ; C65.2@54.439,15.028 v1@54.802,15.028
  BOTTOM_L10 w0.127: U3.D7@54.763,15.329 54.978,15.114 54.944,15.08 54.855,15.08 v3(54.803,15.027)
  other v1: 54.803,15.027
  other v2: 54.803,15.027
  other v4: 54.803,15.027
  other v5: 54.803,15.027
NetC66_1: C66.1 J2.SH2 R109.2 | length 6.1
  TOP_L1 w0.2: R109.2@86.584,7.535 86.584,8.56
  TOP_L1 w0.5: C66.1@85.184,7.06 85.184,8.16 85.584,8.56 86.584,8.56 J2.SH2@88.984,8.56
NetC71_2: C71.2 C72.2 D12.2 F4.1 J4.18 R493.2 R494.2 | length 55.1
  BOTTOM_L10 w0.15: C72.2@73.837,63.239 73.997,63.079 C71.2@74.737,63.079 ; R493.2@84.795,69.475 84.445,69.475 84.145,69.775 84.145,72.135 82.105,74.175 77.045,74.175 74.845,76.375 72.645,76.375 71.7,75.43 71.7,70.3 70.7,69.3 70.7,65.607 71.428,64.879 F4.1@73.484,64.879 73.045,64.44 73.045,62.397 73.563,61.879 74.111,61.879 74.113,61.881 75.486,61.881 75.681,62.075 76.245,62.075 76.345,62.175 77.013,62.175 77.145,62.043 77.145,61.075 76.545,60.475 76.545,59.275 82.345,53.475 83.345,53.475 84.895,51.925 R494.2@84.895,51.475
  BOTTOM_L10 w0.4: 80.886,58.5 J4.18@81.94,58.5
NetC75_1: C75.1 U11.15 | length 8
  TOP_L1 w0.127: U11.15@5.6,109.015 5.6,108.265 5.928,107.937 5.983,107.937 6.024,107.896 6.576,107.896 6.617,107.937 8.806,107.937 9.046,108.178 9.046,109.598 9.959,110.51 C75.1@9.959,111.365
NetC75_2: C75.2 L3.1 U11.9 U11.10 | length 4.5
  TOP_L1 w0.127: L3.1@10.5,107.165 10.294,107.372 10.294,110.145 10.829,110.68 C75.2@10.829,111.365
NetC76_1: C76.1 C77.1 C78.1 C79.1 C87.1 C88.1 C89.1 C90.1 C98.1 C99.1 C100.1 C319.1 C320.1 C321.1 R117.1 R229.2 R273.2 TP60.X U11.5 U11.14 U13.5 U13.14 U14.5 U14.14 | length 55.2
  TOP_L1 w0.2: R229.2@10.974,130.784 11.814,130.784 R273.2@12.299,130.299
  TOP_L1 w0.28: R117.1@2.525,102.165 2.525,101.644 3.255,100.914 4.455,100.914 ; 5.43,103.716 5.68,103.965 C320.1@6.4,103.965 6.3,103.965 U11.5@6.3,105.465 ; C99.1@6.2,88.366 6.4,88.366 C321.1@6.4,89.816 ; C98.1@6.2,97.566 6.4,97.566 C100.1@6.4,96.116 ; C88.1@6.2,111.765 6.4,111.765 C90.1@6.4,110.365 6.3,110.365 U11.14@6.3,108.865 ; C89.1@6.2,113.865 6.4,114.065 C319.1@6.4,115.265 6.3,115.265 U13.5@6.3,116.765 ; C78.1@6.2,123.065 6.4,123.065 6.4,121.665 6.3,121.665 U13.14@6.3,120.165 ; U14.5@6.3,91.266 6.3,89.766 C321.1@6.4,89.766 ; U14.14@6.3,94.666 6.3,96.166 C100.1@6.4,96.166
  TOP_L1 w0.5: C88.1@6.2,111.765 C89.1@6.2,113.865 ; C78.1@6.2,123.065 C77.1@6.2,125.165
  TOP_L1 w0.7: v6@4.1,123.065 C78.1@6.2,123.065 ; v6@4.1,125.065 C77.1@6.2,125.065 6.2,127.165 ; 4.9,111.765 C88.1@6.2,111.765 ; 4.9,113.865 C89.1@6.2,113.865 ; v6@4.9,97.566 C98.1@6.2,97.566 6.2,98.865 ; 4.901,100.365 C76.1@6.2,100.365 6.2,99.065 ; 4.901,102.365 C87.1@6.2,102.365
  TOP_L1 w1: 10.974,129.065 R229.2@10.974,130.784
  L3 w0.5: v2(11.38,128.64) v5(11.68,128.94)
  L8 w0.5: v5(11.68,128.94) 17.094,128.94 18.48,130.326 18.48,132.18 v4(18.459,132.202)
  BOTTOM_L10 w0.5: v4(18.459,132.202) 18.877,132.202 TP60.X@19.469,132.793
  other v1: 11.38,128.64
  other v3: 18.459,132.202
  other v6: 2.83,86.966 3.6,86.966 4.37,86.966 5.14,86.966 2.83,87.766 3.6,87.766 4.37,87.766 5.122,87.747 4.33,96.566 5.1,96.566 4.33,97.366 5.1,97.366 4.33,98.166 5.1,98.166 4.33,98.966 5.1,98.966 4.37,99.765 5.14,99.765 4.37,100.565 5.14,100.565 4.37,101.365 5.14,101.365 4.37,102.165 5.14,102.165 4.37,102.965 5.14,102.965 4.37,111.215 5.14,111.215 4.37,112.015 5.14,112.015 4.37,112.815 5.14,112.815 4.37,113.615 5.14,113.615 4.37,114.415 5.14,114.415 2.73,122.465 3.5,122.465 4.27,122.465 4.953,122.552 2.73,123.265 3.5,123.265 4.27,123.265 5.04,123.265 2.73,124.065 3.5,124.065 4.27,124.065 5.04,124.065 2.73,124.865 3.5,124.865 4.27,124.865 5.04,124.865 2.73,125.665 3.5,125.665 4.27,125.665 5.04,125.665 2.73,126.465 3.5,126.465 4.27,126.465 5.04,126.465 5.81,126.465 2.73,127.265 3.5,127.265 4.27,127.265 5.04,127.265 5.81,127.265 2.73,128.065 3.5,128.065 4.27,128.065 5.04,128.065 5.81,128.065 2.73,128.865 3.5,128.865 4.27,128.865 5.04,128.865 5.81,128.865
NetC80_1: C80.1 R403.2 | length 0.7
  TOP_L1 w0.127: C80.1@1,107.24 R403.2@1.7,107.24
NetC84_2: C84.2 R276.1 U5.46 U5.47 U5.48 U5.49 | length 8.6
  BOTTOM_L10 w0.127: U5.49@84.703,83.797 84.703,82.547 85.103,82.147 U5.48@85.103,83.797 ; C84.2@85.303,80.037 C84.2@85.303,80.147 ; R276.1@85.503,82.147 85.903,82.547 U5.46@85.903,83.797 ; R276.1@85.503,82.247 U5.47@85.503,83.797
  BOTTOM_L10 w0.3: C84.2@85.203,80.147 85.303,80.247 R276.1@85.303,81.747
NetC85_2: C85.2 R133.2 U11.20 | length 7.8
  TOP_L1 w0.127: v1(1.85,102.518) 2.064,102.732 2.064,102.804 R133.2@2.275,103.016 ; C85.2@2.375,107.865 2.834,107.865 v2(3.025,107.674) ; v1@3.028,107.677 3.036,107.669 3.721,107.669 U11.20@3.725,107.665
  L3 w0.127: v1(1.85,102.518) 1.85,104.186 3.032,105.367 3.032,107.667 v2(3.025,107.674)
  other v1: 3.025,107.674
  other v2: 1.85,102.518
NetC86_1: C86.1 U13.15 | length 8
  TOP_L1 w0.127: U13.15@5.6,120.381 5.6,119.631 5.928,119.303 5.983,119.303 6.024,119.262 6.576,119.262 6.617,119.303 8.806,119.303 9.046,119.544 9.046,120.964 9.959,121.876 C86.1@9.959,122.731
NetC86_2: C86.2 L4.1 U13.9 U13.10 | length 4.5
  TOP_L1 w0.127: L4.1@10.294,118.737 10.294,121.511 10.829,122.046 C86.2@10.829,122.731 ; L4.1@10.329,118.737 L4.1@10.535,118.531
NetC91_1: C91.1 R421.2 | length 0.7
  TOP_L1 w0.127: C91.1@1,118.54 R421.2@1.7,118.54
NetC95_2: C95.2 U13.20 | length 1.4
  TOP_L1 w0.127: C95.2@2.375,119.165 2.7,119.165 2.9,118.965 U13.20@3.725,118.965
NetC96_1: C96.1 U14.15 | length 8.3
  TOP_L1 w0.127: U14.15@5.6,94.816 5.6,94.066 5.928,93.738 5.983,93.738 6.024,93.696 6.576,93.696 6.617,93.738 8.806,93.738 9.046,93.978 9.046,95.398 9.959,96.311 C96.1@9.959,97.466
NetC96_2: C96.2 L5.1 U14.9 U14.10 | length 5
  TOP_L1 w0.127: L5.1@10.294,93.472 10.294,96.246 10.829,96.781 C96.2@10.829,97.466
  TOP_L1 w0.2: L5.1@10.5,92.966 L5.1@11.07,93.536
NetC97_1: C97.1 U3.D2 Y4.2 | length 6
  BOTTOM_L10 w0.127: Y4.2@53.063,24.486 53.609,23.94 53.893,23.94 53.988,23.845 53.988,23.375 C97.1@53.988,22.975 53.988,22.6 53.988,21.804 54.363,21.429 54.363,21.229 54.363,19.729 U3.D2@54.763,19.329
NetC102_1: C102.1 R405.2 | length 0.7
  TOP_L1 w0.127: C102.1@1,93.041 R405.2@1.7,93.041
NetC105_1: C105.1 U3.D1 Y4.1 | length 5.4
  BOTTOM_L10 w0.127: C105.1@54.625,23.012 C105.1@54.588,23.049 ; U3.D1@54.763,20.129 54.763,21.379 54.763,21.802 54.588,21.977 54.588,22.55 C105.1@54.588,22.975 C105.1@54.588,23.049 ; Y4.1@55.513,24.875 55.513,24.486 54.967,23.94 54.684,23.94 54.588,23.845 54.588,23.375 C105.1@54.588,23.049
NetC106_2: C106.2 C281.2 L6.2 U3.L3 | length 3.2
  TOP_L1 w0.127: L6.2@59.563,20.279 59.563,20.268 59.838,19.993 C281.2@59.838,19.529 C106.2@59.838,18.929 60.363,18.929 v1(60.663,19.229)
  L3 w0.127: v4(60.663,18.829) v1(60.663,19.229)
  BOTTOM_L10 w0.127: U3.L3@60.363,18.529 v4(60.663,18.829)
  other v2: 60.663,18.829 60.663,19.229
  other v3: 60.663,18.829
  other v5: 60.663,18.829
NetC107_2: C107.2 C291.2 JDIGITAL.16 U3.K5 U28.3 | length 125
  TOP_L1 w0.127: JDIGITAL.16@23.876,50.8 24.901,51.825 v5(29.723,51.825) ; v2(56.833,20.149) U28.3@56.833,19.549 56.833,19.042 57.083,18.792 58.183,18.792 58.55,18.425 58.55,18.025 58.85,17.725 C107.2@59.25,17.725 C291.2@59.95,17.725
  L3 w0.127: v5(49.764,49.405) 49.085,48.725 47.143,48.725 43.872,45.454 37.746,45.454 30.838,38.546 30.838,35.087 28.591,32.839 28.591,29.688 28.84,29.439 31.324,29.439 31.663,29.1 31.769,29.1 32.879,27.99 32.879,18.298 32.954,18.223 32.954,11.289 33.237,11.006 34.093,11.006 34.183,10.916 38.803,10.916 39.213,10.506 49.168,10.506 51.232,12.57 51.232,16.811 52.037,17.616 55.823,17.616 56.833,18.626 v4(56.833,19.749) v2(56.833,20.149)
  L8 w0.127: v5(29.723,51.825) 33.06,51.825 33.36,52.125 34.223,52.125 35.09,51.258 35.09,50.119 35.804,49.405 v5(49.764,49.405)
  BOTTOM_L10 w0.127: v4(56.833,19.749) 56.833,19.716 56.744,19.626 56.744,18.199 56.818,18.125 58.954,18.125 59.2,17.88 59.2,17.292 U3.K5@59.563,16.929
  other v1: 56.833,20.149 29.723,51.825
  other v2: 56.833,19.749 29.723,51.825
  other v3: 56.833,19.749
  other v5: 56.833,19.749
NetC108_2: C108.2 C279.2 R435.2 U3.F11 | length 6.4
  TOP_L1 w0.1: v2(55.313,11.829) 55.313,12.629 55.463,12.779 R435.2@55.813,12.779 56.363,12.779 56.662,12.48 57.599,12.48 57.948,12.829 C279.2@57.963,12.829 57.604,13.189 57.604,13.969 C108.2@57.663,14.029
  L3 w0.1: v2(55.313,11.829) 55.75,11.829 55.92,11.999 v5(56.001,11.999)
  L8 w0.1: v5@55.994,11.992 55.987,11.999 v5(56.001,11.999) 56.001,12.105 v3(56.053,12.157)
  BOTTOM_L10 w0.1: v3(56.053,12.157) 56.067,12.143 56.349,12.143 U3.F11@56.363,12.129
  other v1: 55.313,11.829
  other v4: 56.053,12.157
NetC109_2: C109.2 U23.30 | length 1.8
  BOTTOM_L10 w0.127: C109.2@43.723,84.091 U23.30@43.723,85.866
NetC111_2: C111.2 MODULE1.C39 R399.2 R400.2 TP34.X | length 46.1
  TOP_L1 w0.25: MODULE1.C39@24.282,127.036 24.882,126.436 24.882,124.461 v4(24.938,124.405)
  BOTTOM_L10 w0.15: C111.2@28.683,96.451 R400.2@28.683,95.751 28.683,94.829 TP34.X@28.529,94.676 28.701,94.676 29.081,95.057 R399.2@29.577,95.057
  BOTTOM_L10 w0.5: v4(24.938,124.405) 25.475,123.868 25.475,123.428 25.768,123.135 26.882,123.135 27.882,122.135 27.882,120.671 26.035,118.824 25.294,118.824 24.557,119.561 23.704,119.561 23.42,119.277 23.42,117.765 24.429,116.756 26.497,116.756 27.209,116.044 27.209,104.129 26.742,103.661 26.742,95.466 27.532,94.676 TP34.X@28.529,94.676
  other v1: 24.938,124.405
  other v2: 24.938,124.405
  other v3: 24.938,124.405
  other v5: 24.938,124.405
NetC112_1: C112.1 U1.37 | length 2.2
  TOP_L1 w0.109: C112.1@64.891,7.019 64.99,7.118 65.046,7.118 65.088,7.159 U1.37@66.106,7.159 65.155,7.159
NetC114_2: C114.2 R217.1 R358.2 U14.17 U14.18 U14.20 | length 8.6
  TOP_L1 w0.127: U14.20@3.725,93.466 2.976,93.466 2.776,93.666 C114.2@2.375,93.666 R217.1@2.375,94.366 R358.2@2.375,95.066 2.042,95.399 1.542,95.399 1.375,95.566 1.375,96.117 1.524,96.266 2.488,96.266 2.933,95.821 2.933,94.858 3.228,94.562 3.789,94.562 3.875,94.649 U14.18@3.875,94.816
NetC116_1: C116.1 U16.6 | length 1.7
  TOP_L1 w0.127: C116.1@9.553,78.791 9.553,78.691 U16.6@11.118,78.691
NetC119_2: C119.2 C120.2 C121.2 C187.2 C201.2 C255.2 L7.2 R22.1 R107.2 R150.1 U16.7 | length 25.4
  TOP_L1 w0.127: R107.2@8.968,77.316 C121.2@9.668,77.316 9.993,77.641 9.993,77.941 ; R150.1@9.243,77.941 9.993,77.941 ; U16.7@11.118,78.191 10.443,78.191 v2(10.193,77.941) 9.993,77.941 ; R22.1@13.868,83.341 13.868,83.581 14.432,84.145 14.555,84.145 v1(14.578,84.169)
  TOP_L1 w0.2: C187.2@12.318,81.441 12.718,81.041 C119.2@12.718,80.141
  TOP_L1 w0.7: C255.2@12.318,87.141 C120.2@12.318,83.341 ; R22.1@13.868,83.341 C120.2@12.318,83.341 ; L7.2@14.368,80.966 12.793,80.966 C187.2@12.318,81.441 C120.2@12.318,83.341
  L3 w0.127: v2(10.193,77.941) 10.207,77.927 10.641,77.927 v5(10.655,77.914)
  L8 w0.127: v5(10.655,77.914) 10.655,82.614 12.247,84.205 14.542,84.205 v1(14.578,84.169)
  other v1: 10.193,77.941
  other v2: 14.578,84.169
  other v5: 14.578,84.169
NetC121_1: C121.1 R107.1 R141.2 R142.2 U16.8 | length 4.1
  TOP_L1 w0.127: R142.2@7.607,76.766 R141.2@8.268,76.766 R107.1@8.968,76.766 10.081,76.766 10.532,77.217 10.532,77.606 10.618,77.691 U16.8@11.118,77.691
NetC126_1: C126.1 R144.1 R145.2 U17.8 | length 2.7
  TOP_L1 w0.127: U17.8@73.031,20.609 73.031,19.884 73.299,19.615 73.305,19.615 73.406,19.515 R144.1@73.406,18.809 R145.2@73.406,18.109
NetC127_1: C127.1 U17.6 | length 1.4
  TOP_L1 w0.127: C127.1@71.614,19.399 72.031,19.816 U17.6@72.031,20.609
NetC138_2: C138.2 R134.2 R139.2 R148.2 U18.2 | length 4
  BOTTOM_L10 w0.127: R139.2@34.45,86.831 R148.2@34.45,86.131 34.725,85.856 R134.2@35.175,85.856 ; U18.2@35.575,84.531 35.575,85.053 35.175,85.453 R134.2@35.175,85.856 ; C138.2@36.075,85.696 35.915,85.856 R134.2@35.175,85.856
NetC144_2: C144.2 R126.1 U11.17 U11.18 | length 16
  TOP_L1 w0.127: v1(0.762,119.807) 0.762,119.823 1.333,120.395 1.333,120.995 1.604,121.265 R126.1@1.825,121.265 ; v1(0.771,109.807) 2.028,109.807 2.375,109.46 C144.2@2.375,109.165 2.779,109.165 2.853,109.091 2.853,108.945 3.044,108.754 U11.18@3.875,108.754
  L3 w0.127: v2@0.766,119.802 0.564,119.6 0.564,110.014 v1(0.771,109.807)
  other v2: 0.771,109.807 0.762,119.807
NetC145_2: C145.2 R126.2 U13.17 U13.18 | length 2.6
  TOP_L1 w0.127: R126.2@2.375,121.265 C145.2@2.375,120.565 2.779,120.565 2.853,120.491 2.853,120.245 3.044,120.054 U13.18@3.875,120.054
NetC147_2: C147.2 C171.2 J7.1 U27_5.7 U27_5.8 U27_5.9 U27_5.10 | length 5.5
  BOTTOM_L10 w1.2: J7.1@90.4,37.175 90.419,37.194 90.714,37.194 93.161,39.641 93.161,41.313
NetC150_2: C150.2 C151.2 L11.2 U22.C6 | length 5
  TOP_L1 w0.2: L11.2@75.324,53.94 75.387,53.94 75.474,54.027 75.474,54.09 75.596,54.212 C150.2@75.596,54.862 ; v5(75.375,56.6) 75.608,56.367 C151.2@75.608,55.475 ; U22.C6@75.575,58 75.575,58.007 v7(75.753,58.184) ; C150.2@75.599,54.865 C151.2@75.599,55.465
  L3 w0.2: v2@75.375,56.593 75.816,57.035 75.816,57.84 75.753,57.904 v7(75.753,58.184)
  other v1: 75.375,56.6
  other v2: 75.375,56.6 75.753,58.184
  other v5: 75.816,57.786
NetC152_2: C152.2 C153.2 L12.2 U22.D4 U22.E3 | length 5.6
  TOP_L1 w0.064: v2(74.575,59.5) U22.D4@75.075,59
  TOP_L1 w0.2: L12.2@74.875,63.86 74.875,63.853 75.15,63.578 C153.2@75.15,63.135 C152.2@75.15,62.535 v2(75.15,61.508)
  L3 w0.3: v2(74.575,59.5) 74.575,61.2 74.883,61.508 v2(75.15,61.508)
  other v1: 75.15,61.508
  other v7: 74.575,59.5
NetC154_2: C154.2 C155.2 L13.2 U22.E2 U22.E4 U22.G1 | length 6.4
  TOP_L1 w0.064: 74.277,60.85 74.326,60.801 74.326,60.249 U22.E2@74.575,60 ; U22.E2@74.572,59.997 74.329,59.754 74.329,59.246 v7(74.575,59)
  TOP_L1 w0.084: 73.575,60.864 73.589,60.85 74.277,60.85
  TOP_L1 w0.117: C154.2@73.289,62.489 73.289,61.15 73.575,60.864 U22.G1@73.575,60.5 ; C154.2@73.3,62.535 C155.2@73.3,63.135 73.3,63.575 73.575,63.85 L13.2@73.575,63.86
NetC156_2: C156.2 C157.2 L14.2 U22.B4 | length 5.4
  TOP_L1 w0.2: v5(76.075,56.6) 76.075,56.546 76.199,56.422 C157.2@76.199,55.465 C156.2@76.199,54.865 76.199,54.215 76.324,54.09 76.324,54.027 76.41,53.94 L14.2@76.474,53.94
  L3 w0.3: v5(76.075,56.6) 76.25,56.775 76.25,57 76.25,58.825 v5(76.075,59)
  other v1: 76.075,56.6 76.075,59
  other v2: 76.075,56.6 76.075,59
NetC158_2: C158.2 C159.2 L15.2 U22.G7 | length 4.8
  TOP_L1 w0.127: L15.2@72.374,53.94 72.33,53.94 72.175,54.096 72.175,54.139 72.099,54.215 C158.2@72.099,54.865 C159.2@72.099,55.465 72.099,56.346 72.326,56.573 73.113,56.573 73.575,57.035 U22.G7@73.575,57.5
NetC160_2: C160.2 U23.4 | length 1.5
  BOTTOM_L10 w0.127: C160.2@41.923,92.916 41.923,92.69 41.997,92.616 42.229,92.616 42.523,92.322 U23.4@42.523,91.766
NetC161_2: C161.2 U23.3 | length 1.8
  BOTTOM_L10 w0.127: C161.2@41.223,92.916 41.223,92.672 41.297,92.597 41.491,92.597 41.698,92.391 41.866,92.391 41.867,92.389 42.046,92.389 42.123,92.312 U23.3@42.123,91.766
NetC162_1: C162.1 U23.1 | length 1.8
  BOTTOM_L10 w0.127: C162.1@40.523,92.916 40.523,92.616 40.766,92.372 41.248,92.372 41.323,92.298 U23.1@41.323,91.766
NetC162_2: C162.2 U23.48 | length 3.1
  BOTTOM_L10 w0.127: C162.2@40.523,93.466 40.221,93.466 40.023,93.267 40.023,92.316 40.573,91.766 U23.48@40.573,91.016
NetC163_2: C163.2 C164.2 L16.2 U22.B1 | length 3.8
  TOP_L1 w0.127: U22.B1@76.075,60.5 76.075,60.73 76.55,61.205 76.55,62.705
  TOP_L1 w0.2: L16.2@76.275,63.86 76.275,63.853 76.55,63.578 C164.2@76.55,63.135 76.55,62.705 C163.2@76.55,62.535
NetC167_2: C167.2 C168.2 L17.2 U23.32 | length 3.3
  BOTTOM_L10 w0.127: C168.2@41.523,84.091 42.823,84.091 L17.2@42.923,83.991 U23.32@42.923,85.866
NetC176_1_1: C176_1.1 R168_1.1 U33_1.10 | length 2.3
  BOTTOM_L10 w0.127: C176_1.1@80.025,125.665 R168_1.1@80.025,124.825 80.506,124.825 80.731,125.05 U33_1.10@81.425,125.05
NetC176_2_1: C176_2.1 R168_2.1 U33_2.10 | length 1.8
  TOP_L1 w0.127: C176_2.1@35.9,65.95 R168_2.1@35.9,66.8 U33_2.10@36.85,66.8
NetC176_3_1: C176_3.1 R168_3.1 U33_3.10 | length 1.8
  TOP_L1 w0.127: C176_3.1@26.824,65.95 R168_3.1@26.824,66.8 ; R168_3.1@26.9,66.8 U33_3.10@27.85,66.8
NetC176_4_1: C176_4.1 R168_4.1 U33_4.10 | length 1.8
  TOP_L1 w0.127: C176_4.1@12.4,65.95 R168_4.1@12.4,66.8 U33_4.10@13.35,66.8
NetC176_5_1: C176_5.1 R168_5.1 U33_5.10 | length 2.3
  BOTTOM_L10 w0.1: U33_5.10@86.653,97.045 87.224,97.045 87.313,97.134 ; 87.329,97.145 C176_5.1@87.753,97.569
  BOTTOM_L10 w0.127: R168_5.1@87.361,98.393 87.361,97.961 C176_5.1@87.753,97.569
NetC209_1: C209.1 U23.21 | length 1.9
  BOTTOM_L10 w0.127: U23.21@46.473,87.816 47.244,87.816 47.41,87.649 C209.1@48.288,87.649
NetC209_2: C209.2 D98.2 JMISC.29 | length 14.1
  L8 w0.127: v3(47.409,97.429) 46.81,96.83 46.81,93.258 49.282,90.785 49.282,90.765 49.39,90.657 49.39,88.527 49.451,88.466 49.451,88.227 49.282,88.058 v4(49.282,87.829)
  BOTTOM_L10 w0.127: JMISC.29@47.009,99.629 47.009,97.429 v3(47.409,97.429) ; C209.2@48.838,87.649 49.041,87.649 49.221,87.829 v4(49.282,87.829)
  other v3: 49.282,87.829
  other v4: 47.409,97.429
NetC210_2: C210.2 C211.2 C212.2 C213.2 C214.2 C215.2 C216.2 L18.1 U24.A19 U24.A21 U24.A25 U24.A44 U24.B4 U24.B11 U24.B22 U24.B26 | length 11.7
  TOP_L1 w0.1: L18.1@69.826,38.474 C213.2@70.626,38.474
  TOP_L1 w0.15: U24.A44@73.391,28.349 73.391,27.924 C210.2@73.991,27.324
  TOP_L1 w0.2: C213.2@70.626,38.474 70.626,38.135 70.83,37.932 71.474,37.932 71.591,37.815 U24.A25@71.591,37.349 U24.A25@71.591,37.255 ; U24.B26@70.941,35.324 v3(71.366,35.324) ; v2(71.317,36.905) 71.589,37.177 U24.A25@71.589,37.349 ; v2(72.666,36.074) U24.B22@72.666,36.499 ; v1(73.979,36.914) 73.985,36.92 73.985,37.343 U24.A21@73.991,37.349 ; C210.2@73.991,27.324 v1(74.416,27.324) ; U24.A19@75.191,37.349 75.191,37.174 75.398,36.968 75.425,36.968 v3(75.434,36.958) ; v5(77.801,31.493) 77.82,31.474 U24.B4@78.241,31.474 ; v1(77.816,35.324) U24.B11@78.241,35.324
  BOTTOM_L10 w0.15: C212.2@77.516,35.524 77.603,35.438 77.664,35.438 77.778,35.324 v1(77.816,35.324)
  BOTTOM_L10 w0.2: C214.2@71.366,34.974 v3(71.366,35.324) ; v2(72.666,36.074) C215.2@73.016,36.074 ; C211.2@77.416,31.474 77.783,31.474 v5(77.801,31.493)
  BOTTOM_L10 w0.5: v3(75.434,36.958) 77.391,36.958 77.696,37.263 C216.2@77.696,37.357
  other v1: 77.801,31.493 71.366,35.324 72.666,36.074 71.317,36.905 75.434,36.958
  other v2: 74.416,27.324 77.801,31.493 71.366,35.324 77.816,35.324 73.979,36.914 75.434,36.958
  other v3: 77.801,31.493 77.816,35.324 72.666,36.074
  other v4: 77.801,31.493 71.366,35.324 77.816,35.324 72.666,36.074 75.434,36.958
  other v5: 74.416,27.324 71.366,35.324 77.816,35.324 72.666,36.074 71.317,36.905 73.979,36.914 75.434,36.958
NetC217_1: C217.1 U23.20 | length 1.9
  BOTTOM_L10 w0.127: U23.20@46.473,88.216 47.305,88.216 47.43,88.342 48.286,88.342 C217.1@48.288,88.343
NetC217_2: C217.2 D99.2 JMISC.31 | length 13.2
  L8 w0.127: v4(46.109,96.429) 46.109,93.617 49.163,90.563 v4(49.163,88.346)
  BOTTOM_L10 w0.127: JMISC.31@45.739,99.629 45.739,97.429 46.109,97.429 v4(46.109,96.429) ; C217.2@48.838,88.343 49.16,88.343 v4(49.163,88.346)
  other v3: 49.163,88.346 46.109,96.429
NetC218_1: C218.1 R194.2 U24.A23 Y2.1 | length 4.2
  TOP_L1 w0.117: Y2.1@71.541,40.449 71.641,40.449 72.132,39.957 72.132,39.858 72.38,39.61 72.38,39.385 R194.2@72.516,39.249 72.116,38.849 C218.1@72.116,38.449 72.174,38.391 72.174,38.215 72.355,38.034 72.646,38.034 72.791,37.889 U24.A23@72.791,37.349
NetC218_2: C218.2 C219.2 U24.B21 | length 2.7
  TOP_L1 w0.117: C218.2@72.666,38.449 C219.2@73.316,38.449 73.316,38.067 73.108,37.859 73.108,37.02 73.216,36.912 U24.B21@73.216,36.499
NetC219_1: C219.1 R194.1 U24.A22 Y2.3 | length 6.2
  TOP_L1 w0.117: Y2.3@73.25,41.757 72.575,41.081 72.575,40.141 R194.1@73.466,39.249 73.866,38.849 73.866,38.198 73.391,37.723 U24.A22@73.391,37.349 ; Y2.3@73.25,41.757 73.742,42.249 Y2.3@73.842,42.249
NetC220_1_1: C220_1.1 R326_1.1 U21_1.12 | length 2.9
  TOP_L1 w0.127: U21_1.12@47.9,66.55 48.651,66.55 49.116,66.085 C220_1.1@49.55,66.085 R326_1.1@49.55,67.175
NetC220_2_1: C220_2.1 R326_2.1 U21_2.12 | length 3.6
  TOP_L1 w0.084: U21_2.12@52.839,73.169 53.354,73.169 C220_2.1@53.789,73.604 54.189,74.004 54.189,75.442 54.065,75.566 R326_2.1@53.789,75.566
NetC220_3_1: C220_3.1 R326_3.1 U21_3.12 | length 2.4
  TOP_L1 w0.127: R326_3.1@9.086,146.8 C220_3.1@9.086,147.84 9.521,148.275 U21_3.12@10.236,148.275
NetC220_4_1: C220_4.1 R326_4.1 U21_4.12 | length 2.8
  TOP_L1 w0.127: U21_4.12@47.9,73.141 48.615,73.141 C220_4.1@49.05,73.576 R326_4.1@49.05,75.016
NetC220_5_1: C220_5.1 R326_5.1 U21_5.12 | length 2.7
  BOTTOM_L10 w0.122: R326_5.1@33.45,28.545 33.477,28.572 33.477,29.162
  BOTTOM_L10 w0.127: U21_5.12@31.75,29.07 33.385,29.07 33.477,29.162 33.477,29.29 33.522,29.335 C220_5.1@33.65,29.335
NetC224_2: C224.2 C225.2 C226.2 C227.2 D27.2 D40.2 J10.2 J10.4 J10.12 J10.14 J10.16 J10.18 J10.70 J10.72 J10.74 TP87.X U27_2.7 U27_2.8 U27_2.9 U27_2.10 | length 7.6
  TOP_L1 w0.127: J10.70@31.276,42.175 32.852,42.175 C224.2@32.852,42.875 ; 32.622,26.664 D40.2@33.076,26.664
  BOTTOM_L10 w0.127: TP87.X@25.4,32.68 26.17,31.91 27.403,31.91 28.303,31.01 28.303,30.849 v3(29.11,30.042)
  other v1: 29.11,30.042
  other v2: 29.11,30.042
  other v4: 29.11,30.042
  other v5: 29.11,30.042
NetC239_2: C239.2 L19.2 U34.A17 | length 3.6
  TOP_L1 w0.1: U34.A17@41.841,28.129 41.841,27.136 42.423,26.553 C239.2@42.423,26.175 42.51,26.089 42.66,26.089 42.796,25.953 42.796,25.608 43.223,25.18 L19.2@43.223,25.175
NetC245_2: C245.2 L20.2 U34.T | length 5
  TOP_L1 w0.127: v5(39.289,29.729) 39.336,29.729 39.429,29.636 39.429,29.549 U34.T@41.591,29.549
  BOTTOM_L10 w0.127: v5(39.289,29.729) 39.336,29.729 39.336,29.891 39.429,29.984 40.15,29.984 40.25,29.883 40.25,29.878 40.442,29.686 L20.2@41.504,29.686
  other v1: 39.289,29.729
  other v2: 39.289,29.729
  other v3: 39.289,29.729
  other v4: 39.289,29.729
NetC246_1_2: C246_1.2 U27_1.5 | length 3.6
  BOTTOM_L10 w0.127: C246_1.2@75.328,18.577 75.328,18.348 76.079,17.597 76.079,15.583 76.004,15.509 U27_1.5@75.831,15.509
NetC246_2_2: C246_2.2 U27_2.5 | length 1.6
  TOP_L1 w0.127: C246_2.2@34.114,26.791 34.114,26.478 34.441,26.151 U27_2.5@34.441,25.374
NetC246_3_2: C246_3.2 U27_3.5 | length 1.2
  TOP_L1 w0.127: C246_3.2@3.74,76.719 3.765,76.744 U27_3.5@3.765,77.869
NetC246_4_2: C246_4.2 U27_4.5 | length 1
  TOP_L1 w0.127: C246_4.2@9.35,71.011 9.425,70.936 U27_4.5@10.318,70.936
NetC246_5_2: C246_5.2 U27_5.5 | length 3.3
  BOTTOM_L10 w0.15: U27_5.5@98.921,50.746 99.004,50.746 99.029,50.771 99.029,53.939 C246_5.2@98.998,53.971
NetC246_6_2: C246_6.2 U27_6.5 | length 2.2
  BOTTOM_L10 w0.15: C246_6.2@95.5,30.35 95.5,30.8 95.6,30.9 96,30.9 96.435,31.335 U27_6.5@97.065,31.335
NetC247_1: C247.1 U1.36 | length 1.3
  TOP_L1 w0.109: C247.1@64.891,7.7 64.99,7.6 65.046,7.6 65.088,7.559 U1.36@66.106,7.559
NetC248_2: C248.2 D104.1 D104.10 JMISC.36 U23.5 | length 16.7
  BOTTOM_L10 w0.127: D104.10@42.294,106.391 D104.1@42.294,105.516 42.294,104.898 42.414,104.778 42.914,104.778 43.077,104.615 43.082,104.615 43.199,104.498 43.199,103.278 43.199,102.039 43.967,101.272 43.967,97.687 42.409,96.129 42.409,94.622 42.285,94.498 42.285,92.99 42.359,92.916 C248.2@42.623,92.916 42.923,92.616 U23.5@42.923,91.766
NetC253_1: C253.1 U23.25 | length 2.4
  BOTTOM_L10 w0.127: U23.25@45.723,85.866 45.723,85.316 46.423,84.616 46.706,84.616 46.923,84.399 C253.1@46.923,84.091
NetC254_1: C254.1 U23.27 | length 2.5
  BOTTOM_L10 w0.127: U23.27@44.923,85.866 44.923,85.337 45.017,85.243 45.396,85.243 46.023,84.616 46.023,84.61 46.223,84.41 C254.1@46.223,84.091
NetC256_1: C256.1 R212.1 | length 1.7
  TOP_L1 w0.6: C256.1@12.95,135 R212.1@14.685,135
NetC256_2: C256.2 C293.2 Q2.D Q6.D R229.1 R272.2 U15.4 U29.4 | length 22.5
  TOP_L1 w0.2: R229.1@10.974,132.614 11.814,132.614 R272.2@12.299,133.099
  TOP_L1 w0.3: U29.4@5.3,129.965 6.4,129.965 7.9,131.465 8.614,131.465 9.415,132.266 9.415,134.52 ; 9.137,137.844 9.137,139.964 7.955,141.146 7.955,142.627 8.218,142.89 9.769,142.89 11.386,144.508 U15.4@12.4,144.508
  TOP_L1 w0.6: Q6.D@6.1,136.3 6.75,136.95 C293.2@6.75,139.2
NetC257_2: C257.2 R163.2 R223.1 U4.4 U35.2 | length 6
  TOP_L1 w0.127: R163.2@37.062,74.502 38.508,74.502 38.532,74.526 ; U35.2@38.562,73.513 38.532,73.543 38.532,74.526 ; C257.2@40.582,75.449 R223.1@39.882,75.449 39.471,75.449 39.071,75.849 U4.4@38.532,75.849 38.532,74.526
NetC261_1: C261.1 U3.J1 Y3.1 | length 4.4
  BOTTOM_L10 w0.127: U3.J1@58.763,20.129 58.763,21.679 58.763,23.324 59.513,24.074 Y3.1@59.638,24.074
NetC264_1: C264.1 U3.J2 Y3.3 | length 6.6
  BOTTOM_L10 w0.127: Y3.3@57.793,25.567 58.163,25.197 58.163,23.374 58.163,23.024 58.363,22.824 58.363,21.329 58.363,19.729 U3.J2@58.763,19.329
NetC285_2: C285.2 L21.2 U3.R12 | length 6.9
  BOTTOM_L10 w0.2: U3.R12@63.563,11.329 63.601,11.367 63.863,11.367 64.505,12.01 64.505,13.941 65.571,15.006 C285.2@66.244,15.006 ; C285.2@66.25,15 C285.2@66.244,15.006 ; L21.2@67.825,15.006 C285.2@66.244,15.006
NetC286_1: C286.1 C287.1 L21.1 U3.E6 U3.H12 U3.L10 | length 24.2
  L6 w0.7: v5(55.87,16.05) 56.599,16.779 57.432,16.779 58.048,16.163 58.048,15.125 58.494,14.679 59.832,14.679 59.98,14.827 61.129,14.827 ; v5(58.041,11.886) 58.041,14.779 ; v5(61.129,13.63) 61.129,14.827 ; v5(65.263,16.475) 61.977,16.475 61.129,15.627 61.129,14.827
  L8 w0.127: v3(60.67,13.236) 61.065,13.63 v5(61.129,13.63)
  L8 w0.2: v3(55.47,15.85) 55.632,16.012 55.832,16.012 v5(55.87,16.05) ; v3(57.763,11.558) 58.041,11.836 v5(58.041,11.886) ; v5(65.263,16.475) 65.263,16.449 65.516,16.197 v4(65.516,16.183)
  BOTTOM_L10 w0.127: U3.L10@60.363,12.929 v3(60.67,13.236)
  BOTTOM_L10 w0.2: v3(55.47,15.85) 55.47,15.864 55.525,15.919 55.525,16.091 U3.E6@55.563,16.129 ; v3@57.763,11.558 57.754,11.55 57.748,11.544 U3.H12@57.963,11.329
  BOTTOM_L10 w0.3: v4(65.516,16.183) 65.772,16.183 66.282,16.692 ; C286.1@66.282,17.782 66.282,16.692 ; C286.1@66.29,17.791 C287.1@66.29,18.791 ; L21.1@67.825,16.576 67.734,16.667 66.307,16.667 66.282,16.692
  other v3: 65.516,16.183
  other v4: 57.763,11.558 60.67,13.236 55.47,15.85
NetC293_1: C293.1 R213.1 | length 1.6
  TOP_L1 w0.6: R213.1@3.43,139.2 C293.1@5.05,139.2
NetC295_2: C295.2 D104.2 D104.9 JMISC.38 U23.7 | length 17.9
  L8 w0.127: v4@42,95.63 v4@42.711,95.63
  BOTTOM_L10 w0.127: D104.9@41.794,106.391 D104.2@41.794,105.516 41.794,104.698 41.929,104.563 41.929,103.278 41.929,102.103 42.561,101.471 43.373,101.471 43.74,101.104 43.74,97.903 41.998,96.161 41.998,95.631 v3(42,95.629) ; v3(42.712,95.631) 43.289,95.053 43.289,93.024 43.364,92.95 43.589,92.95 C295.2@43.623,92.916 43.623,92.516 43.723,92.416 U23.7@43.723,91.766
  other v4: 42,95.629 42.712,95.631
NetC296_1: C296.1 U23.29 | length 2.1
  BOTTOM_L10 w0.127: U23.29@44.123,85.866 44.123,85.337 44.523,84.937 C296.1@44.523,83.951
NetC301_1: C301.1 R272.1 U20.1 | length 2.3
  TOP_L1 w0.2: C301.1@13.249,132.134 R272.1@13.249,133.099 ; C301.1@13.274,132.024 U20.1@14.574,132.024
NetC301_2: C301.2 R273.1 U20.2 | length 2.4
  TOP_L1 w0.2: R273.1@13.249,130.299 13.249,131.264 C301.2@13.274,131.264 13.274,131.374 U20.2@14.574,131.374
NetC302_2: C302.2 C303.1 R504.1 U30.1 U30.2 | length 5.2
  BOTTOM_L10 w0.15: U30.1@89.783,96.168 C302.2@89.783,97.467 ; C302.2@89.988,97.562 90.433,97.117 U30.2@90.433,96.168
  BOTTOM_L10 w0.2: C303.1@91.005,98.515 R504.1@91.005,99.37
  BOTTOM_L10 w0.3: C302.2@89.692,98.045 89.945,98.045 90.415,98.515 C303.1@91.005,98.515
NetC304_2: C304.2 C308.2 R234.2 R501.2 U30.6 | length 3.3
  BOTTOM_L10 w0.127: C304.2@88.828,93.417 88.828,93.957 88.92,94.05 89.306,94.05 89.45,94.194 89.721,94.194 89.721,94.149 89.783,94.087 89.783,93.923 89.912,93.794 89.981,93.794 90.11,93.665 90.11,93.507 R501.2@90.2,93.417 ; R234.2@89.453,93.417 R234.2@89.503,93.417 R501.2@90.2,93.417 ; R501.2@90.203,93.417 R501.2@90.2,93.417
NetC309_1: C309.1 U34.A21 | length 13.2
  TOP_L1 w0.122: C309.1@34.623,28.916 34.618,28.916 34.514,28.811 34.514,28.8 34.464,28.75 34.464,28.377 34.645,28.196 v1(34.681,28.196) ; U34.A21@40.841,28.129 40.864,28.107 40.864,27.829 40.939,27.753 40.939,26.811 41.775,25.975 41.775,25.675 41.701,25.601 41.313,25.601 41.141,25.773 v2(41.132,25.773)
  L3 w0.117: 34.928,26.322 35.18,26.07 37.18,26.07 37.675,25.575 40.928,25.575 41.126,25.773 v2(41.132,25.773)
  L3 w0.122: v1(34.681,28.196) 34.498,28.013 34.498,26.752 34.928,26.322
  other v1: 41.132,25.773
  other v2: 34.681,28.196
NetC309_2: C309.2 R291.1 | length 0.6
  TOP_L1 w0.117: C309.2@34.623,29.466 R291.1@34.623,30.116
NetC310_1: C310.1 U34.A19 | length 14.3
  TOP_L1 w0.122: v1(33.981,28.196) 34.017,28.196 34.197,28.377 34.197,28.741 34.132,28.807 34.132,28.811 34.027,28.916 C310.1@34.023,28.916 ; v1(41.132,25.073) 41.141,25.073 41.313,25.244 41.848,25.244 42.027,25.423 42.027,26.227 41.244,27.01 41.244,27.753 41.319,27.829 41.319,28.107 U34.A19@41.341,28.129
  L3 w0.117: 34.647,26.172 35.054,25.765 37.054,25.765 37.549,25.27 40.928,25.27 41.126,25.073 v1(41.132,25.073)
  L3 w0.122: v1(33.981,28.196) 34.195,27.982 34.195,26.624 34.647,26.172
  other v2: 41.132,25.073 33.981,28.196
NetC310_2: C310.2 R292.1 | length 0.6
  TOP_L1 w0.117: C310.2@34.023,29.466 R292.1@34.023,30.116
NetC331_2: C331.2 C332.1 R314.2 U12.66 | length 5.2
  BOTTOM_L10 w0.15: C331.2@18.4,14.31 C332.1@19.3,14.31
  BOTTOM_L10 w0.2: C332.1@19.3,14.31 R314.2@20.6,14.31
  BOTTOM_L10 w0.25: U12.66@18.15,16.81 18.15,16.06 19.3,14.91 C332.1@19.3,14.31
NetC333_1: C333.1 R477.2 R478.1 R479.1 R482.1 | length 4
  TOP_L1 w0.127: R482.1@12.682,45.7 12.682,46.074 12.522,46.234 12.522,47.112 12.682,47.272 R478.1@12.682,47.709 R479.1@12.682,49.597
NetC341_1: C341.1 R506.1 R507.2 | length 3.3
  BOTTOM_L10 w0.3: C341.1@86.9,105.45 88.049,105.45 ; R506.1@88.7,104.715 88.543,104.715 88.049,105.208 88.049,105.45 ; R507.2@88.7,106.185 88.543,106.185 88.049,105.692 88.049,105.45
NetC342_1: C342.1 D22.2 J8.5 R506.2 U7.7 | length 39.3
  L8 w0.2: v6(95.4,102.85) 95.4,103.327 95.603,103.53 98.064,103.53 99.107,102.487 99.107,86.507 98,85.4 J8.5@95.9,85.4
  BOTTOM_L10 w0.2: U7.7@83.238,103.2 83.949,103.2 84.571,102.578 88.07,102.578 88.392,102.9 R506.2@88.7,102.9 ; R506.2@88.7,102.785 89.023,102.785 89.418,103.18 89.43,103.18 89.95,103.7 90.3,103.7 90.65,104.05 D22.2@90.65,104.85 91.15,104.85 93.15,102.85 v6(95.4,102.85) ; R506.2@88.7,102.885 R506.2@88.935,102.885
NetC345_2: C345.2 R130.1 R496.1 R497.1 U14.4 | length 4.9
  TOP_L1 w0.127: R130.1@2.819,89.466 3.939,89.466 4.039,89.366 4.869,89.366 ; R497.1@4.869,88.916 4.869,89.366 ; U14.4@5.6,91.116 5.6,90.081 5.335,89.816 R496.1@4.869,89.816 4.869,89.366
NetC346_2: C346.2 C347.2 C348.2 Q7.5 R483.2 R485.2 | length 4.3
  TOP_L1 w0.127: C346.2@21.7,9.05 C347.2@22.4,9.05 ; Q7.5@22.4,10.2 C347.2@22.4,9.05 ; R485.2@24.3,9.65 R483.2@24.3,9.05 C348.2@23.1,9.05 C347.2@22.4,9.05
NetC350_1: C350.1 U26.4 | length 1.5
  BOTTOM_L10 w0.15: C350.1@79.69,139.485 80.095,139.485 80.58,139 U26.4@81,139
NetC350_2: C350.2 L10.1 U26.1 U26.2 U26.3 | length 3.4
  BOTTOM_L10 w0.7: 80.4,135.9 80.4,132.5 L10.1@80.43,132.5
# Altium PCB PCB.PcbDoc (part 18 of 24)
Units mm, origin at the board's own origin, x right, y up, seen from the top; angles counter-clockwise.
Board outline 100 x 160 mm, 10 copper layers (TOP_L1, L2, L3, L4, L5, L6, L7, L8, L9, BOTTOM_L10), stack 1.946 mm thick; 1358 components, 1149 nets, 6777 pads, 10914 vias.

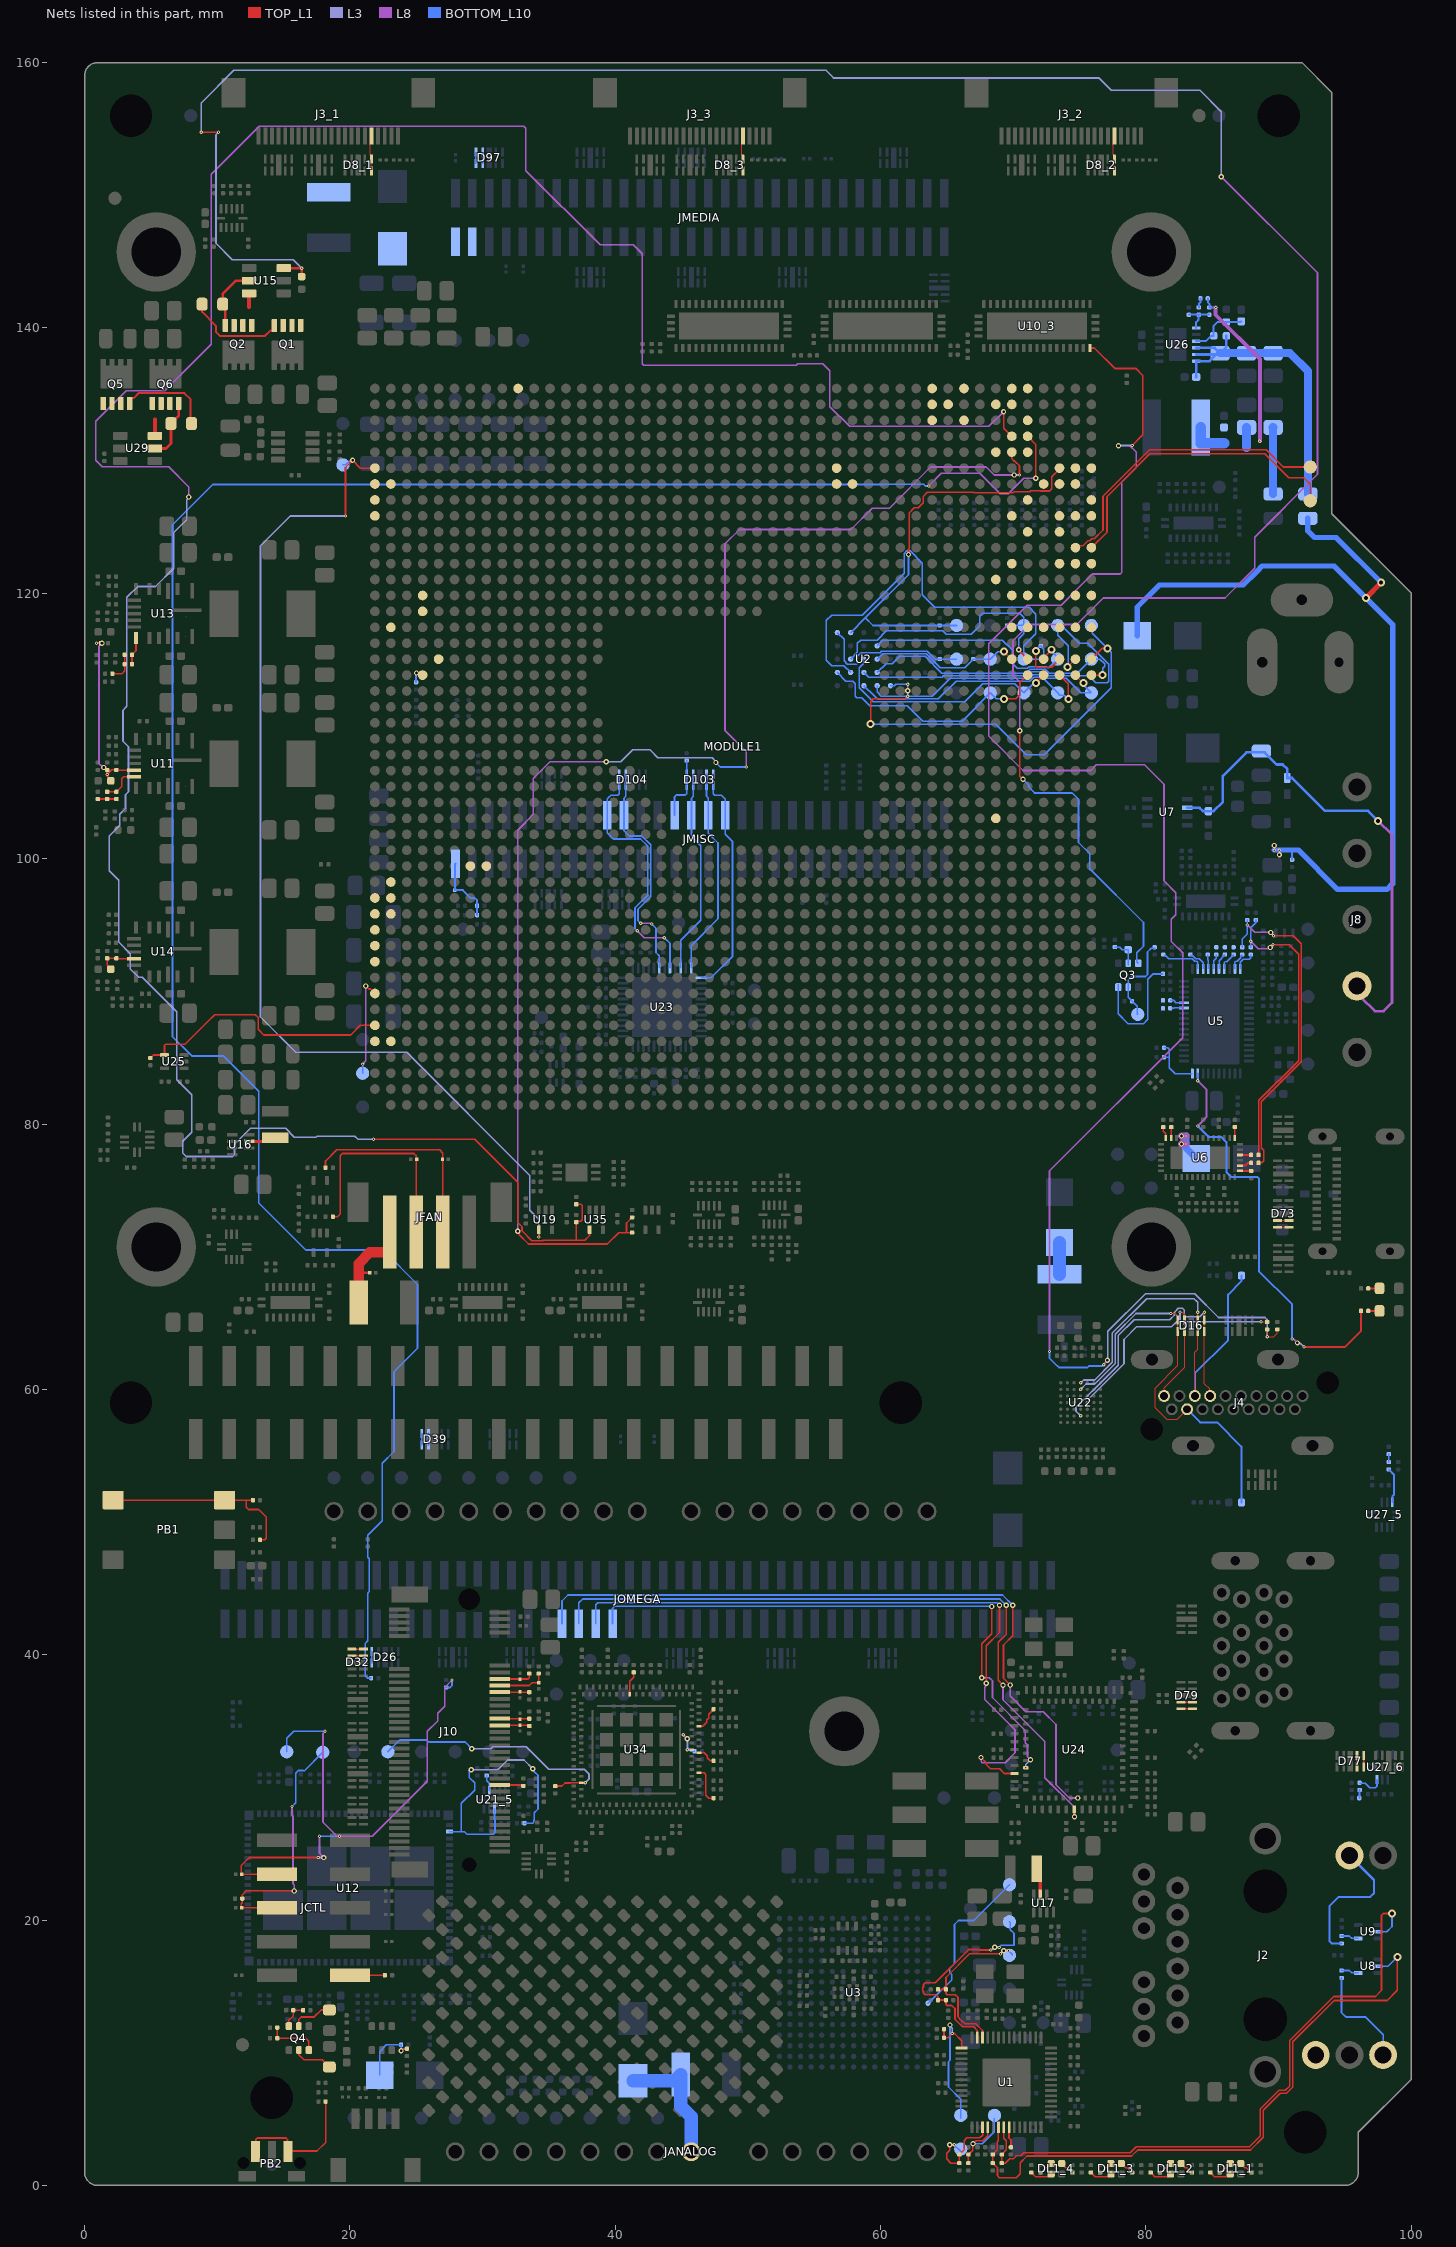
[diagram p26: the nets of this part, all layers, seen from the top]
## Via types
v1: diameter 0.25, hole 0.1, TOP_L1 to L2, tented both sides, 3439 vias
v2: diameter 0.25, hole 0.1, L2 to L3, tented both sides, 2256 vias
v3: diameter 0.25, hole 0.1, L9 to BOTTOM_L10, tented both sides, 1685 vias
v4: diameter 0.25, hole 0.1, L8 to L9, tented both sides, 1675 vias
v5: diameter 0.4, hole 0.2, L3 to L8, tented both sides, 1251 vias
v6: diameter 0.6, hole 0.3, TOP_L1 to BOTTOM_L10, tented both sides, 600 vias
v7: diameter 0.24, hole 0.1, TOP_L1 to L2, tented both sides, 8 vias

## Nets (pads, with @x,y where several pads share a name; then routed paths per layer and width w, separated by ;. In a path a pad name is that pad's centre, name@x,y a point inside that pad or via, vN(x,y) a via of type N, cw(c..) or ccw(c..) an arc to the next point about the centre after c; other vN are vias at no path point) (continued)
NetC351_1: C351.1 C352.1 C356.1 C357.1 R398.2 R505.1 U26.10 U26.11 U26.12 | length 24.6
  BOTTOM_L10 w0.2: C351.1@83.78,136.3 U26.12@83.78,137.5 84.8,137.5 C352.1@85.4,138.1 ; U26.11@83.78,138 C352.1@85.4,138 ; U26.10@83.78,138.5 85.18,138.5 C352.1@85.58,138.1 86.055,138.575 R398.2@86.055,139.4
  BOTTOM_L10 w0.6: C352.1@85.58,138.1 C356.1@87.58,138.1 90.85,138.1 92.2,136.75 R505.1@92.2,127.48
NetC353_1: C353.1 R398.1 R460.2 U26.9 | length 4.5
  BOTTOM_L10 w0.15: U26.9@83.78,139 84.506,139 84.906,139.4 R398.1@85.105,139.4 85.105,140.155 85.4,140.45 87.14,140.45 C353.1@87.18,140.49
NetC354_1: C354.1 C355.2 C359.2 L10.2 R498.2 R502.1 R503.2 | length 22.5
  L8 w0.3: v3(85.255,141.545) 85.255,140.995 88.58,137.67 v3(88.58,131.47)
  BOTTOM_L10 w0.15: R503.2@84.655,142.22 84.655,141.932 84.78,141.807 R498.2@84.78,141.545 v3(85.255,141.545)
  BOTTOM_L10 w0.6: R502.1@89.58,127.48 89.58,131.38 ; 89.58,131 C359.2@89.58,132.5
  BOTTOM_L10 w0.7: 87.58,131 C355.2@87.58,132.5
  BOTTOM_L10 w0.8: L10.2@84.13,132.5 84.13,131.3 85.88,131.3
  other v4: 88.58,131.47 85.255,141.545
NetC358_1: C358.1 R503.1 | length 0.7
  BOTTOM_L10 w0.15: C358.1@83.98,141.545 83.98,141.807 84.105,141.932 R503.1@84.105,142.22
NetC358_2: C358.2 R498.1 R500.2 U26.7 | length 2.6
  BOTTOM_L10 w0.15: R500.2@83.23,140.995 R498.1@84.755,140.995 ; U26.7@83.78,140 83.78,140.44 83.975,140.635 83.975,140.99 C358.2@83.98,140.995
NetC361_1: C361.1 D23.2 J8.4 R507.1 U7.6 | length 38.2
  L8 w0.2: J8.4@95.9,90.4 96.21,90.09 96.21,89.549 97.253,88.506 97.905,88.506 98.544,89.145 98.544,101.806 v6(97.5,102.85)
  BOTTOM_L10 w0.2: U7.6@83.103,103.828 84.041,103.828 84.291,103.578 85.092,103.578 85.795,104.282 85.795,106.231 87.579,108.015 88.935,108.015 89.85,107.1 90.3,107.1 90.65,106.75 D23.2@90.65,106.08 91.02,106.08 93.5,103.6 96.75,103.6 v6(97.5,102.85)
NetD2_2: D2.2 F2.2 JANALOG.8 | length 9.9
  BOTTOM_L10 w1: D2.2@41.332,7.886 44.472,7.886 F2.2@44.939,8.353 44.939,5.956 45.72,5.175 JANALOG.8@45.72,2.54
NetD3_C: D3.C F4.2 | length 2.4
  BOTTOM_L10 w0.15: D3.C@73.484,71.069 D3.C@73.484,71.074
  BOTTOM_L10 w1: F4.2@73.484,68.679 D3.C@73.484,71.069
NetD4_C: D4.C D9.C R504.2 R505.2 | length 68.3
  TOP_L1 w0.4: v6(96.58,119.65) v6(97.73,120.8)
  L8 w0.2: v4(89.655,100.645) v5(89.655,100.995) ; v5(90.055,100.295) v3(90.055,100.645)
  L8 w0.5: v5(82.671,78.491) v3(83.021,78.491) ; v5(82.671,79.091) v4(83.021,79.091)
  BOTTOM_L10 w0.15: R504.2@91.005,99.92 91.005,100.545 91.105,100.645
  BOTTOM_L10 w0.4: D9.C@79.332,116.8 79.332,118.949 81.005,120.622 87.328,120.622 88.355,121.648 88.757,122.05 94.18,122.05 v6(96.58,119.65) 98.59,117.64 98.59,98.118 98.16,97.688 94.442,97.688 91.485,100.645 91.105,100.645 v3(90.055,100.645) v4(89.655,100.645) ; R505.2@92.2,125.65 92.2,124.7 92.7,124.2 94.33,124.2 v6(97.73,120.8)
  BOTTOM_L10 w0.5: v4(83.021,79.091) 83.021,78.179 D4.C@83.8,77.4
  other v3: 83.021,79.091 89.655,100.645
  other v4: 83.021,78.491 90.055,100.645
NetD8_1_5: D8_1.5 D8_1.6 J3_1.18 | length 2.7
  TOP_L1 w0.086: D8_1.5@21.624,151.842 D8_1.6@21.624,152.717 21.624,152.954 21.527,153.052 21.527,153.556 21.527,154.377 J3_1.18@21.624,154.475
NetD8_2_5: D8_2.5 D8_2.6 J3_2.18 | length 2.4
  TOP_L1 w0.086: D8_2.6@77.576,153.003 77.527,153.052 77.527,153.556 77.527,154.377 J3_2.18@77.624,154.475 ; D8_2.5@77.624,151.842 D8_2.6@77.624,152.717
NetD8_3_5: D8_3.5 D8_3.6 J3_3.18 | length 2.7
  TOP_L1 w0.086: D8_3.5@49.624,151.842 D8_3.6@49.624,152.717 49.624,152.954 49.527,153.052 49.527,153.556 49.527,154.377 J3_3.18@49.624,154.475
NetD16_1: D16.1 D16.10 J4.13 U22.D6 | length 22.1
  TOP_L1 w0.086: v1(84.402,65.807) D16.10@84.402,64.362 84.402,60.437 84.789,60.05 84.789,59.551 J4.13@84.84,59.5
  L3 w0.127: v2(75.075,58) 74.728,58.347 74.728,58.646 77.075,60.994 77.909,61.828 77.909,64.055 79.108,65.254 81.796,65.254 82.142,65.599 82.142,65.808 82.437,66.103 82.754,66.103 82.872,65.986 82.872,65.589 82.996,65.464 84.06,65.464 v1(84.402,65.807)
  other v2: 84.402,65.807
  other v7: 75.075,58
NetD16_2: D16.2 D16.9 J4.15 R490.2 U22.D1 | length 30.5
  TOP_L1 w0.086: J4.15@83.68,59.5 83.68,62.783 83.902,63.005 D16.9@83.902,64.362 D16.2@83.902,65.237 v2(83.902,65.807)
  L3 w0.127: v1(75.075,60.5) 75.095,60.5 75.304,60.709 76.125,60.709 77.455,62.039 77.455,64.243 80.044,66.832 83.624,66.832 83.902,66.554 v2(83.902,65.807)
  BOTTOM_L10 w0.15: J4.15@83.68,59.5 83.68,61.204 86.19,63.713 86.19,67.145 87.195,68.15 R490.2@87.195,68.575
  other v1: 83.902,65.807
  other v2: 75.075,60.5
NetD16_4: D16.4 D16.7 J4.19 R112.2 U22.C4 | length 25.2
  TOP_L1 w0.086: J4.19@81.36,59.5 81.36,60.121 82.902,61.663 D16.7@82.902,64.362 D16.4@82.902,65.237 82.902,65.636 82.734,65.804 82.567,65.804 v1(82.557,65.815) ; v1(88.668,65.104) 88.682,65.089 89.113,65.089 R112.2@89.127,65.075
  L3 w0.127: v2(75.575,59) 75.575,59.033 75.703,59.161 75.703,59.3 77.075,60.673 78.336,61.934 78.336,63.761 79.287,64.712 81.918,64.712 82.306,65.1 82.631,65.1 ; v1(82.557,65.815) 82.557,65.174 82.631,65.1 ; v1(88.668,65.104) 88.664,65.1 82.631,65.1
  other v1: 75.575,59
  other v2: 88.668,65.104 82.557,65.815
NetD16_5: D16.5 D16.6 J4.16 R491.2 U22.D2 | length 31.2
  TOP_L1 w0.086: v2(81.854,65.719) 82.148,65.719 82.402,65.465 D16.6@82.402,64.362 82.402,61.803 80.693,60.093 80.693,58.631 81.574,57.75 82.35,57.75 J4.16@83.1,58.5
  L3 w0.127: v1(75.075,60) 75.475,60.4 76.137,60.4 77.682,61.945 77.682,64.149 79.252,65.719 v2(81.854,65.719)
  BOTTOM_L10 w0.15: J4.16@83.1,58.5 83.1,58.495 84.086,57.509 85.364,57.509 87.195,55.678 R491.2@87.195,51.475
  other v1: 81.854,65.719
  other v2: 75.075,60
NetD26_5: D26.5 D26.6 | length 0.9
  BOTTOM_L10 w0.127: D26.5@21.651,39.374 D26.6@21.651,40.249
NetD32_4: D32.4 D32.7 | length 1.1
  TOP_L1 w0.122: D32.7@20.141,39.925 D32.4@21.016,39.925 D32.4@21.254,39.925
NetD32_5: D32.5 D32.6 | length 1.1
  TOP_L1 w0.122: D32.6@20.141,40.425 D32.5@21.016,40.425 D32.5@21.254,40.425
NetD33_2: D33.2 J10.54 R417.1 | length 2.6
  TOP_L1 w0.127: J10.54@31.276,38.175 32.824,38.175 33.448,38.175 33.523,38.25 R417.1@33.523,38.575
NetD34_2: D34.2 J10.52 R418.1 | length 3.7
  TOP_L1 w0.127: J10.52@31.276,37.675 33.523,37.675 33.723,37.875 34.223,37.875 R418.1@34.223,38.575
NetD35_2: D35.2 J10.50 R419.1 | length 2.2
  TOP_L1 w0.127: J10.50@31.276,37.175 32.824,37.175 R419.1@33.523,37.175
NetD39_4: D39.4 D39.7 | length 0.9
  BOTTOM_L10 w0.127: D39.4@25.916,55.8 D39.7@25.916,56.675
NetD39_5: D39.5 D39.6 | length 0.9
  BOTTOM_L10 w0.127: D39.5@25.416,55.8 D39.6@25.416,56.675
NetD41_2: D41.2 J10.40 R225.2 | length 2.2
  TOP_L1 w0.127: J10.40@31.276,34.675 32.824,34.675 R225.2@33.523,34.675
NetD42_2: D42.2 J10.42 R226.2 | length 2.2
  TOP_L1 w0.127: J10.42@31.276,35.175 32.824,35.175 R226.2@33.523,35.175
NetD43_2: D43.2 F3.2 JMEDIA.57 JMEDIA.59
NetD44_C: D44.C R485.1 R510.2 | length 4.6
  TOP_L1 w0.109: v2(23.856,10.149) 23.873,10.149 24.023,10.3 R485.1@24.3,10.3
  BOTTOM_L10 w0.109: D44.C@22.23,8.3 22.23,10.077 22.753,10.6 R510.2@23.855,10.6 ; v2(23.856,10.149) R510.2@23.855,10.6
  other v1: 23.856,10.149
  other v3: 23.856,10.149
  other v4: 23.856,10.149
  other v5: 23.856,10.149
NetD61_2: D61.2 JCTL.3 R219.1 TP58.X | length 43.5
  TOP_L1 w0.127: JCTL.3@14.51,23.461 11.81,23.461 11.81,24.109 12.422,24.721 v1(17.61,24.721)
  L3 w0.127: v1(17.61,24.721) 17.616,24.715 18.028,24.715 v5(18.035,24.709)
  L8 w0.127: v4(17.7,26.31) 17.7,25.043 v5(18.035,24.709) ; v4(18.122,34.225) 18.122,34.216 17.968,34.061 17.968,27.37 19.004,26.334 19.186,26.334 v3(19.209,26.31) 21.68,26.31 25.837,30.468 25.837,34.232 26.61,35.005 26.61,35.582 27.135,36.107 27.135,37.531 v3(27.698,38.095)
  BOTTOM_L10 w0.127: TP58.X@15.24,32.68 15.24,33.693 15.772,34.225 v4(18.122,34.225) ; v4(17.7,26.31) v3(19.209,26.31) ; R219.1@27.244,37.535 27.553,37.535 27.698,37.68 v3(27.698,38.095)
  other v2: 17.61,24.721
  other v3: 17.7,26.31 18.122,34.225
  other v4: 19.209,26.31 27.698,38.095
NetD62_2: D62.2 JCTL.5 R433.1 TP59.X | length 19.5
  TOP_L1 w0.127: JCTL.5@14.51,20.921 11.81,20.921 11.81,21.238 11.885,21.313 R433.1@11.885,21.621 11.885,21.891 12.197,22.203 15.792,22.203 v5(15.8,22.195)
  L8 w0.127: v3(15.63,28.556) 15.63,27.89 15.71,27.81 15.71,22.732 15.8,22.642 v5(15.8,22.195)
  BOTTOM_L10 w0.127: v3(15.63,28.556) 15.905,28.831 15.905,31.074 16.109,31.279 16.491,31.279 16.504,31.265 16.573,31.265 TP59.X@17.952,32.644
  other v1: 15.8,22.195
  other v2: 15.8,22.195
  other v4: 15.63,28.556
NetD69_2: D69.2 F1.2 JFAN.1 | length 7.9
  TOP_L1 w0.2: 20.66,68.81 20.671,68.799 D69.2@21.511,68.799
  TOP_L1 w0.8: F1.2@20.66,66.55 20.66,68.81 20.66,69.478 21.506,70.324 22.9,70.324 23,70.424 JFAN.1@23,71.85
NetD70_2: D70.2 JFAN.2 R259.1 | length 16.6
  TOP_L1 w0.127: R259.1@18.76,73.02 19.06,73.02 19.26,73.22 19.26,77.61 19.429,77.778 24.832,77.778 25,77.61 25,77.35 JFAN.2@25,71.85
NetD71_2: D71.2 JFAN.3 R260.1 | length 15.7
  TOP_L1 w0.127: R260.1@18.16,76.71 18.16,77.205 19.007,78.051 26.757,78.051 27,77.808 27,77.35 JFAN.3@27,71.85
NetD73_1: D73.1 D73.10 | length 0.9
  TOP_L1 w0.086: D73.10@89.907,72.229 D73.1@90.782,72.229
NetD73_2: D73.2 D73.9 | length 0.9
  TOP_L1 w0.086: D73.9@89.907,72.729 D73.2@90.782,72.729
NetD77_4: D77.4 D77.7 | length 0.9
  TOP_L1 w0.109: D77.4@95.9,31.537 D77.7@95.9,32.412
NetD77_5: D77.5 D77.6 | length 0.9
  TOP_L1 w0.109: D77.5@96.4,31.537 D77.6@96.4,32.412
NetD79_1: D79.1 D79.10 | length 0.9
  TOP_L1 w0.109: D79.10@82.638,35.925 D79.1@83.513,35.925
NetD79_2: D79.2 D79.9 | length 0.9
  TOP_L1 w0.109: D79.9@82.638,36.425 D79.2@83.513,36.425
NetD97_4: D97.4 D97.7 | length 0.9
  BOTTOM_L10 w0.109: D97.4@29.999,152.379 D97.7@29.999,153.254
NetD97_5: D97.5 D97.6 | length 0.9
  BOTTOM_L10 w0.109: D97.5@29.499,152.379 D97.6@29.499,153.254
NetD103_1: D103.1 D103.10 JMISC.28 U23.13 | length 17.7
  BOTTOM_L10 w0.127: U23.13@46.473,91.016 47.212,91.016 48.841,92.645 48.841,101.275 48.279,101.837 48.279,103.278 48.279,104.498 48.162,104.615 48.157,104.615 47.994,104.778 47.494,104.778 47.374,104.898 D103.1@47.374,105.516 D103.10@47.374,106.391
NetD103_2: D103.2 D103.9 JMISC.30 U23.12 | length 15.8
  BOTTOM_L10 w0.127: U23.12@45.723,91.766 45.723,93.442 47.741,95.46 47.741,101.175 47.009,101.907 47.009,103.278 47.009,104.563 46.874,104.698 D103.2@46.874,105.516 D103.9@46.874,106.391
NetD103_4: D103.4 D103.7 JMISC.32 U23.10 | length 15.6
  BOTTOM_L10 w0.127: U23.10@44.923,91.766 44.923,93.842 46.441,95.36 46.441,100.975 45.739,101.677 45.739,103.278 45.739,104.563 45.874,104.698 D103.7@45.874,106.391
NetD103_5: D103.5 D103.6 JMISC.34 R481.2 | length 4.9
  BOTTOM_L10 w0.127: JMISC.34@44.469,103.278 44.469,104.667 44.603,104.802 45.278,104.802 45.374,104.898 D103.5@45.374,105.516 D103.6@45.374,106.391 R481.2@45.374,107.392
NetD104_4: D104.4 D104.7 JMISC.40 U23.6 | length 17.6
  L8 w0.127: v4(41.909,95.129) 42.662,95.129 42.72,95.072 v4(42.753,95.072)
  BOTTOM_L10 w0.127: D104.7@40.794,106.391 D104.4@40.794,105.516 40.794,104.698 40.659,104.563 40.659,103.278 40.659,102.103 41.049,101.713 41.798,101.713 41.998,101.713 42.667,101.044 42.667,97.152 41.711,96.195 41.711,95.327 v4(41.909,95.129) ; v4(42.753,95.072) 43.062,94.763 43.062,92.93 43.323,92.67 U23.6@43.323,91.766
  other v3: 42.753,95.072 41.909,95.129
NetD104_5: D104.5 D104.6 JMISC.42 U23.8 | length 20.1
  L8 w0.127: v4(41.653,94.572) 42.175,94.05 v3(43.685,94.05)
  BOTTOM_L10 w0.127: D104.6@40.294,106.391 D104.5@40.294,105.516 40.294,104.898 40.174,104.778 39.674,104.778 39.512,104.615 39.507,104.615 39.389,104.498 39.389,103.278 39.389,101.949 39.853,101.486 41.904,101.486 42.44,100.949 42.44,97.246 41.484,96.289 41.484,94.741 v4(41.653,94.572) ; v3(43.685,94.05) 44.123,93.612 U23.8@44.123,91.766
  other v3: 41.653,94.572
  other v4: 43.685,94.05
NetD106_2: D106.2 JMISC.59 R508.1 R509.1 | length 5.1
  BOTTOM_L10 w0.15: JMISC.59@27.959,99.629 27.91,99.58 D106.2@27.91,97.626 28.508,97.626 29.083,97.051 29.383,97.051 29.583,96.851 R509.1@29.583,96.451 R508.1@29.583,95.751
NetDL1_1_2: DL1_1.2 R205_1.1 | length 1.2
  TOP_L1 w0.127: R205_1.1@84.957,0.868 85.169,0.656 DL1_1.2@86.115,0.656
NetDL1_1_3: DL1_1.3 R207_1.2 | length 1.1
  TOP_L1 w0.127: R207_1.2@85.565,0.975 85.927,1.337 86.047,1.337 DL1_1.3@86.355,1.645
NetDL1_1_4: DL1_1.4 R206_1.1 | length 1.1
  TOP_L1 w0.127: DL1_1.4@87.145,1.645 87.453,1.337 87.573,1.337 R206_1.1@87.935,0.975
NetDL1_2_2: DL1_2.2 R205_2.1 | length 1.2
  TOP_L1 w0.127: R205_2.1@80.457,0.868 80.669,0.656 DL1_2.2@81.615,0.656
NetDL1_2_3: DL1_2.3 R207_2.2 | length 1.1
  TOP_L1 w0.127: R207_2.2@81.065,0.975 81.427,1.337 81.547,1.337 DL1_2.3@81.855,1.645
NetDL1_2_4: DL1_2.4 R206_2.1 | length 1.1
  TOP_L1 w0.127: DL1_2.4@82.645,1.645 82.953,1.337 83.073,1.337 R206_2.1@83.435,0.975
NetDL1_3_2: DL1_3.2 R205_3.1 | length 1.6
  TOP_L1 w0.127: R205_3.1@75.957,0.868 76.169,0.656 77.157,0.656 DL1_3.2@77.355,0.855
NetDL1_3_3: DL1_3.3 R207_3.2 | length 1.1
  TOP_L1 w0.127: R207_3.2@76.565,0.975 76.927,1.337 77.047,1.337 DL1_3.3@77.355,1.645
NetDL1_3_4: DL1_3.4 R206_3.1 | length 1.1
  TOP_L1 w0.127: DL1_3.4@78.145,1.645 78.453,1.337 78.573,1.337 R206_3.1@78.935,0.975
NetDL1_4_2: DL1_4.2 R205_4.1 | length 1.7
  TOP_L1 w0.127: R205_4.1@71.35,0.975 71.356,0.975 71.457,0.874 71.457,0.868 71.669,0.656 72.615,0.656 72.813,0.855 DL1_4.2@72.855,0.855
NetDL1_4_3: DL1_4.3 R207_4.2 | length 1.1
  TOP_L1 w0.127: R207_4.2@72.05,0.975 72.065,0.975 72.427,1.337 72.547,1.337 DL1_4.3@72.855,1.645
NetDL1_4_4: DL1_4.4 R206_4.1 | length 1.1
  TOP_L1 w0.127: DL1_4.4@73.645,1.645 73.953,1.337 74.073,1.337 74.435,0.975 R206_4.1@74.45,0.975
NetDL2_A: DL2.A R106.1 | length 0.8
  TOP_L1 w0.15: R106.1@96.851,65.909 DL2.A@97.601,65.909
NetDL3_A: DL3.A R105.1 | length 0.7
  TOP_L1 w0.15: R105.1@96.851,67.609 DL3.A@97.601,67.609
NetJ2_13: J2.13 R111.1 | length 11
  BOTTOM_L10 w0.156: R111.1@94.741,18.244 93.993,18.244 93.844,18.393 93.844,21.072 94.52,21.747 96.91,21.747 97.186,22.023 97.186,23.018 J2.13@95.334,24.87
NetJ2_15: J2.15
NetJ2_17: J2.17 R110.1 | length 8
  BOTTOM_L10 w0.127: R110.1@94.741,15.644 94.741,13.009 95.05,12.7 96.52,12.7 97.874,11.346 J2.17@97.874,9.83
NetJ10_22: J10.22 R224.2 | length 1.8
  TOP_L1 w0.127: J10.22@31.276,30.175 33.019,30.175 R224.2@33.078,30.116
NetJCTL_10: JCTL.10 R486.2 | length 2.6
  TOP_L1 w0.127: JCTL.10@20.01,15.841 R486.2@22.635,15.841
NetJOMEGA_54: JOMEGA.54 U24.B33 | length 44.3
  TOP_L1 w0.127: v2(67.613,38.264) 67.613,40.819 68.363,41.569 v1(68.363,43.629) ; U24.B33@70.941,31.474 v2(70.942,31.476)
  L3 w0.127: v2(70.942,31.476) 70.942,31.723 v5(71.297,32.078)
  L8 w0.127: v2(67.613,38.264) 68.195,38.264 68.429,38.03 68.429,36.769 70.904,34.294 70.904,33.372 71.067,33.208 71.067,32.308 v5(71.297,32.078)
  BOTTOM_L10 w0.127: JOMEGA.54@39.796,42.35 39.796,43.501 39.945,43.65 68.342,43.65 v1(68.363,43.629)
  other v1: 70.942,31.476 67.613,38.264
  other v2: 68.363,43.629
  other v3: 68.363,43.629
  other v4: 68.363,43.629
  other v5: 67.613,38.264 68.363,43.629
NetJOMEGA_56: JOMEGA.56 U24.A36 | length 50.8
  TOP_L1 w0.127: v5(67.57,32.247) 67.952,31.864 67.952,31.727 68.285,31.395 68.965,31.395 69.31,31.049 U24.A36@70.091,31.049 ; v1(67.969,37.839) 67.969,40.675 68.963,41.669 v2(68.963,43.729)
  L8 w0.127: v5(67.57,32.247) 67.572,32.244 67.572,31.947 67.653,31.866 69.38,31.866 70.129,32.616 70.129,34.35 67.852,36.628 67.852,37.554 67.917,37.62 67.917,37.787 v1(67.969,37.839)
  BOTTOM_L10 w0.127: JOMEGA.56@38.526,42.35 38.526,43.754 38.69,43.917 68.775,43.917 v2(68.963,43.729)
  other v1: 67.57,32.247 68.963,43.729
  other v2: 67.57,32.247 67.969,37.839
  other v3: 68.963,43.729
  other v4: 68.963,43.729
  other v5: 67.969,37.839 68.963,43.729
NetJOMEGA_58: JOMEGA.58 U24.A46 | length 53.2
  TOP_L1 w0.127: v1(69.225,37.709) 68.863,38.071 68.863,40.928 69.463,41.528 v5(69.463,43.729) ; U24.A46@74.591,28.349 74.591,27.802 v5(74.607,27.786)
  L8 w0.127: v1(69.225,37.709) 69.225,36.615 72.378,33.461 72.378,30.727 74.607,28.499 v5(74.607,27.786)
  BOTTOM_L10 w0.127: JOMEGA.58@37.256,42.35 37.256,43.922 37.537,44.203 68.989,44.203 v5(69.463,43.729)
  other v1: 74.607,27.786 69.463,43.729
  other v2: 74.607,27.786 69.225,37.709 69.463,43.729
  other v3: 69.463,43.729
  other v4: 69.463,43.729
  other v5: 69.225,37.709
NetJOMEGA_60: JOMEGA.60 U24.B43 | length 54.5
  TOP_L1 w0.127: v1(69.759,37.719) 69.263,38.215 69.263,40.729 69.963,41.429 v3(69.963,43.729)
  L8 w0.127: v1(69.759,37.719) 69.759,36.885 70.933,35.711 72.244,35.711 73.221,34.734 73.221,30.206 74.227,29.199 v5(74.866,29.199)
  BOTTOM_L10 w0.127: JOMEGA.60@35.986,42.35 35.986,44.052 36.437,44.503 69.189,44.503 v3(69.963,43.729)
  other v1: 74.866,29.199 69.963,43.729
  other v2: 74.866,29.199 69.759,37.719 69.963,43.729
  other v4: 69.963,43.729
  other v5: 69.759,37.719 69.963,43.729
NetL7_1: L7.1 U16.3 | length 2.1
  TOP_L1 w0.2: L7.1@14.093,78.691 L7.1@14.368,78.966
  TOP_L1 w0.23: U16.3@12.418,78.691 L7.1@14.093,78.691
NetL8_1: L8.1 U17.3 | length 2.1
  TOP_L1 w0.25: L8.1@71.756,23.859 72.031,23.584 U17.3@72.031,21.909
NetLOVE_X: LOVE.X U3.R9 | length 12.3
  BOTTOM_L10 w0.127: U3.R9@63.563,13.729 63.778,13.944 63.813,13.944 65.353,15.484 65.353,15.902 65.202,16.053 65.202,16.353 65.568,16.719 65.568,19.663 65.868,19.963 67.01,19.963 LOVE.X@69.71,22.663
NetMODULE1_A5: MODULE1.A5
NetMODULE1_A6: MODULE1.A6 R216.1 U25.4 | length 20.2
  TOP_L1 w0.127: R216.1@4.965,84.977 4.971,84.977 5.071,85.077 5.071,85.083 5.19,85.202 U25.4@6.025,85.202 6.025,85.926 6.099,86 7.564,86 9.263,87.699 9.263,87.706 9.799,88.241 12.868,88.241 13.078,88.031 13.078,87.141 13.505,86.714 20.055,86.714 20.778,87.436 MODULE1.A6@21.882,87.436
NetMODULE1_A8: MODULE1.A8 TP33.X | length 7.6
  TOP_L1 w0.127: v1(21.2,90.4) 21.43,90.17 21.548,90.17 MODULE1.A8@21.882,89.836
  L8 w0.127: v4(20.96,84.516) 21.2,84.756 v1(21.2,90.4)
  BOTTOM_L10 w0.127: TP33.X@20.955,83.82 20.96,83.825 v4(20.96,84.516)
  other v2: 21.2,90.4
  other v3: 20.96,84.516
  other v5: 21.2,90.4
NetMODULE1_A10: MODULE1.A10
NetMODULE1_A11: MODULE1.A11
NetMODULE1_A12: MODULE1.A12
NetMODULE1_A13: MODULE1.A13
NetMODULE1_A14: MODULE1.A14
NetMODULE1_A38: MODULE1.A38
NetMODULE1_A39: MODULE1.A39
NetMODULE1_A40: MODULE1.A40
NetMODULE1_A41: MODULE1.A41 TP69.X U19.4 | length 80.8
  TOP_L1 w0.127: v1(19.669,125.826) 19.669,129.489 v3(20.2,130.02) 20.784,129.436 MODULE1.A41@21.882,129.436 ; U19.4@34.225,72.04 U19.4@34.232,72.033 34.229,72.03 34.229,71.492 v1(34.226,71.489)
  L3 w0.127: v1(19.669,125.826) 15.509,125.826 13.254,123.571 13.254,88.07 15.914,85.411 24.271,85.411 33.559,76.123 33.559,73.494 34.226,72.827 v1(34.226,71.489)
  BOTTOM_L10 w0.127: TP69.X@19.473,129.68 19.689,129.68 20.005,129.996 20.176,129.996 v3(20.2,130.02)
  other v1: 20.2,130.02
  other v2: 34.226,71.489 19.669,125.826 20.2,130.02
  other v4: 20.2,130.02
  other v5: 20.2,130.02
NetMODULE1_AK40: MODULE1.AK40
NetMODULE1_AK41: MODULE1.AK41
NetMODULE1_AL40: MODULE1.AL40
NetMODULE1_AT44: MODULE1.AT44
NetMODULE1_AT45: MODULE1.AT45
NetMODULE1_AT46: MODULE1.AT46
NetMODULE1_AU45: MODULE1.AU45
NetMODULE1_AV44: MODULE1.AV44
NetMODULE1_AV46: MODULE1.AV46
NetMODULE1_AY19: MODULE1.AY19
NetMODULE1_AY34: MODULE1.AY34
NetMODULE1_AY42: MODULE1.AY42
NetMODULE1_AY45: MODULE1.AY45
NetMODULE1_B5: MODULE1.B5
NetMODULE1_B13: MODULE1.B13
NetMODULE1_B14: MODULE1.B14
NetMODULE1_B15: MODULE1.B15
NetMODULE1_B31: MODULE1.B31
NetMODULE1_B40: MODULE1.B40
NetMODULE1_BA29: MODULE1.BA29 R59.1 TP27.X U2.C2 | length 11.5
  TOP_L1 w0.086: v6(69.283,115.602) 69.299,115.602 69.865,115.036 MODULE1.BA29@69.882,115.036
  BOTTOM_L10 w0.1: U2.C2@59.737,115.036 60.145,115.444 63.44,115.444 64.498,114.386 66.327,114.386 66.977,115.036 TP27.X@68.262,115.036 68.828,115.602 v6(69.283,115.602)
NetMODULE1_BA31: MODULE1.BA31
NetMODULE1_BA33: MODULE1.BA33
NetMODULE1_BA35: MODULE1.BA35
NetMODULE1_BA38: MODULE1.BA38
NetMODULE1_BA42: MODULE1.BA42 R430.1 R432.2 | length 107.2
  TOP_L1 w0.127: v5(32.639,71.92) 32.639,71.886 32.765,71.761 32.765,71.655 33.462,70.958 39.398,70.958 40.253,71.813 40.841,71.813 ; 40.841,71.81 40.841,71.813 ; R430.1@41.262,71.813 40.841,71.813 ; R432.2@41.262,72.963 40.841,72.542 40.841,71.813 ; MODULE1.BA42@69.882,130.636 69.882,130.164 70.081,129.965 70.101,129.965 70.462,129.604 v2(70.462,128.913)
  L3 w0.127: v5(39.31,107.301) 40.41,107.301 41.31,108.201 42.61,108.201 43.21,107.601 47.299,107.601 47.584,107.316 v3(47.584,107.245) ; v5(70.062,128.913) v2(70.462,128.913)
  L8 w0.127: v5(32.639,71.92) 32.639,102.143 33.817,103.321 33.817,106.037 35.084,107.304 39.307,107.304 v5(39.31,107.301) ; v3(49.862,106.913) 49.862,108.074 48.262,109.674 48.262,123.713 49.362,124.813 57.762,124.813 59.362,126.413 60.662,126.413 63.763,129.515 67.964,129.515 68.566,128.913 v5(70.062,128.913)
  BOTTOM_L10 w0.127: v3(47.584,107.245) 47.916,106.913 v3(49.862,106.913)
  other v1: 32.639,71.92 70.462,128.913
  other v2: 32.639,71.92
  other v4: 49.862,106.913 47.584,107.245
  other v5: 47.584,107.245
NetMODULE1_BA43: MODULE1.BA43 R163.1 R431.2 U35.4 | length 214.8
  TOP_L1 w0.109: v5(69.267,133.682) 69.267,132.451 MODULE1.BA43@69.882,131.836
  TOP_L1 w0.127: v1(21.78,78.84) 29.414,78.84 32.647,75.607 32.647,72.565 32.963,72.249 32.963,71.948 33.71,71.2 34.523,71.2 34.563,71.24 37.062,71.24 ; R163.1@37.062,73.952 37.409,73.952 37.498,73.862 37.498,72.772 37.387,72.661 37.124,72.661 R431.2@37.062,72.598 37.062,71.24 ; U35.4@38.062,72.033 38.062,71.598 37.704,71.24 37.062,71.24
  L3 w0.127: v5(7.857,127.262) 7.857,127.188 7.699,127.03 7.699,125.557 6.72,124.578 6.72,121.886 5.35,120.517 3.998,120.517 3.185,119.704 3.185,111.477 2.896,111.189 2.896,108.847 3.313,108.431 3.313,105.038 3.087,104.812 3.087,103.779 2.659,103.35 2.659,102.512 1.85,101.703 1.85,99.084 2.567,98.367 2.567,93.712 3.444,92.835 3.444,91.685 4.079,91.051 4.357,91.051 6.951,88.456 6.951,88.379 6.954,88.376 6.954,83.33 8.078,82.206 8.078,79.378 7.411,78.711 7.411,77.811 7.671,77.55 11.15,77.55 11.3,77.7 11.3,78.47 12.5,79.67 15.15,79.67 15.814,79.007 17.437,79.007 17.513,79.083 20.367,79.083 20.609,78.84 v1(21.78,78.84)
  L8 w0.109: 0.844,132.963 3.131,135.25 6.031,135.25 9.553,138.772 9.553,151.572 13.182,155.201 33.11,155.201 33.256,155.055 33.256,151.864 38.848,146.272 41.353,146.272 42.036,145.589 42.036,137.31 42.157,137.189 53.633,137.189 53.763,137.318 55.625,137.318 56.153,136.79 56.153,134.072 57.653,132.572 68.157,132.572 v5(69.267,133.682)
  L8 w0.127: 0.844,132.963 0.844,130.025 1.332,129.536 6.332,129.536 7.857,128.012 v5(7.857,127.262)
  other v1: 69.267,133.682
  other v2: 21.78,78.84 69.267,133.682
NetMODULE1_BA45: MODULE1.BA45
NetMODULE1_BA46: MODULE1.BA46
NetMODULE1_BB28: MODULE1.BB28 TP54.X U2.D5 | length 18.7
  TOP_L1 w0.1: v6(69.282,112.036) 70.182,112.036 70.501,112.355 70.501,113.255 MODULE1.BB28@71.082,113.836
  BOTTOM_L10 w0.1: U2.D5@56.737,114.036 57.387,113.386 57.882,113.386 58.087,113.181 58.087,112.258 58.204,112.141 58.577,112.141 59.193,111.525 62.013,111.525 63.165,110.373 66.139,110.373 TP54.X@68.262,112.496 68.722,112.036 v6(69.282,112.036)
NetMODULE1_BB29: MODULE1.BB29 R58.1 TP52.X U2.C4 | length 20.4
  TOP_L1 w0.1: v1@70.442,115.676 MODULE1.BB29@71.082,115.036
  BOTTOM_L10 w0.1: U2.C4@57.737,115.036 58.242,115.541 58.242,116.236 58.485,116.479 59.752,116.479 60.432,117.16 64.694,117.16 64.928,116.926 66.84,116.926 67.472,117.559 67.472,118.263 67.71,118.501 70.487,118.501 70.802,118.186 TP52.X@70.802,117.576 ; R58.1@69.532,117.576 TP52.X@70.802,117.576 ; v3(70.41,115.733) 70.41,116.574 70.802,116.966 TP52.X@70.802,117.576
  other v1: 70.41,115.733
  other v2: 70.41,115.733
  other v4: 70.41,115.733
  other v5: 70.41,115.733
NetMODULE1_BB31: MODULE1.BB31
NetMODULE1_BB33: MODULE1.BB33
NetMODULE1_BB37: MODULE1.BB37
NetMODULE1_BB39: MODULE1.BB39
NetMODULE1_BB42: MODULE1.BB42
NetMODULE1_BB43: MODULE1.BB43 R488.1 | length 172.8
  TOP_L1 w0.127: MODULE1.BB43@71.082,131.836 71.702,131.216 71.702,128.685 v5(71.682,128.665)
  L8 w0.127: v3(63.615,128.088) 64.569,129.042 67.462,129.042 69.011,127.493 69.62,127.493 70.792,128.665 v5(71.682,128.665)
  BOTTOM_L10 w0.127: R488.1@21.564,38.243 21.302,38.243 21.302,38.258 21.145,38.414 21.145,40.845 21.343,41.043 21.343,44.644 21.462,44.763 21.462,47.237 21.343,47.356 21.343,49.003 22.438,50.098 22.438,54.438 23.316,55.316 23.316,61.316 25.092,63.092 25.092,67.906 22.5,70.498 16.678,70.498 13.125,74.051 13.125,82.457 10.45,85.132 8.069,85.132 6.632,86.569 6.632,125.165 9.671,128.204 60.31,128.204 60.323,128.216 63.246,128.216 63.374,128.088 v3(63.615,128.088)
  other v1: 71.682,128.665
  other v2: 71.682,128.665
  other v4: 63.615,128.088
NetMODULE1_BB44: MODULE1.BB44
NetMODULE1_BB46: MODULE1.BB46
NetMODULE1_BC28: MODULE1.BC28 TP31.X U2.C3 | length 18
  TOP_L1 w0.1: v6(71.713,113.226) 71.713,113.267 MODULE1.BC28@72.282,113.836
  BOTTOM_L10 w0.1: U2.C3@58.737,115.036 58.737,114.732 58.387,114.382 58.387,112.891 59.442,111.836 66.342,111.836 67.692,113.186 70.112,113.186 TP31.X@70.802,112.496 71.532,113.226 v6(71.713,113.226)
NetMODULE1_BC29: MODULE1.BC29 TP28.X U2.B2 | length 17.5
  TOP_L1 w0.1: MODULE1.BC29@72.282,115.036 72.282,115.14 v6(72.888,115.746)
  BOTTOM_L10 w0.1: U2.B2@59.737,116.036 60.177,116.476 69.162,116.476 69.902,115.736 69.902,114.736 70.302,114.336 71.055,114.336 71.195,114.476 72.493,114.476 72.596,114.373 72.679,114.373 TP28.X@73.342,115.036 73.342,115.164 72.888,115.618 v6(72.888,115.746)
NetMODULE1_BC31: MODULE1.BC31
NetMODULE1_BC33: MODULE1.BC33
NetMODULE1_BC40: MODULE1.BC40
NetMODULE1_BD28: MODULE1.BD28 TP55.X U2.E3 | length 19.2
  TOP_L1 w0.1: MODULE1.BD28@73.482,113.836 74.142,113.176 v6(74.142,112.036)
  BOTTOM_L10 w0.1: U2.E3@58.737,113.036 59.537,112.236 59.729,112.044 64.351,112.044 65.693,113.386 71.236,113.386 71.527,113.676 72.162,113.676 TP55.X@73.342,112.496 73.514,112.324 73.854,112.324 v6(74.142,112.036)
NetMODULE1_BD29: MODULE1.BD29 R57.1 TP53.X U2.D4 | length 37.4
  TOP_L1 w0.1: v6(71.702,115.636) 71.702,114.495 71.761,114.436 72.882,114.436 MODULE1.BD29@73.482,115.036
  BOTTOM_L10 w0.1: U2.D4@57.737,114.036 57.237,114.536 56.302,114.536 55.902,114.936 55.902,117.956 56.302,118.356 58.602,118.356 61.765,121.519 61.765,122.982 61.985,123.201 62.213,123.201 63.137,122.278 63.137,119.875 64.061,118.951 66.463,118.951 66.466,118.948 71.19,118.948 71.702,118.436 71.702,116.936 70.802,116.036 TP53.X@70.802,115.036 72.002,115.036 72.302,115.336 72.302,115.801 R57.1@72.072,116.031 71.702,115.661 v6(71.702,115.636)
NetMODULE1_BD31: MODULE1.BD31
NetMODULE1_BD33: MODULE1.BD33
NetMODULE1_BD35: MODULE1.BD35
NetMODULE1_BD37: MODULE1.BD37
NetMODULE1_BD38: MODULE1.BD38
NetMODULE1_BD40: MODULE1.BD40
NetMODULE1_BD41: MODULE1.BD41 R60.1 TP26.X U2.A4 | length 31.6
  TOP_L1 w0.127: v1(62.099,122.926) 62.099,123.305 62.154,123.36 62.154,126.055 62.535,126.436 62.829,126.436 63.211,126.817 63.211,127.297 63.523,127.61 67.012,127.61 67.055,127.568 69.961,127.568 70.049,127.655 71.249,127.655 71.312,127.719 72.052,127.719 72.063,127.708 72.742,127.708 72.902,127.867 72.902,128.781 73.482,129.361 MODULE1.BD41@73.482,129.436
  BOTTOM_L10 w0.127: U2.A4@57.737,117.036 58.852,118.151 ; v1(62.099,122.926) 62.099,121.398 58.852,118.151 ; TP26.X@65.722,117.576 R60.1@64.452,117.576 59.427,117.576 58.852,118.151
  other v2: 62.099,122.926
  other v3: 62.099,122.926
  other v4: 62.099,122.926
  other v5: 62.099,122.926
NetMODULE1_BE28: MODULE1.BE28 TP56.X U2.E2 | length 19.8
  TOP_L1 w0.086: MODULE1.BE28@74.682,113.836 v6(75.282,113.236)
  BOTTOM_L10 w0.1: U2.E2@59.737,113.036 59.737,112.569 60.062,112.244 63.885,112.244 65.227,113.586 71.154,113.586 71.444,113.876 72.245,113.876 72.535,113.586 73.992,113.586 75.082,112.496 TP56.X@75.882,112.496 75.451,112.927 ; v6(75.282,113.236) 75.282,113.097 75.451,112.928
NetMODULE1_BE29: MODULE1.BE29 TP50.X U2.D3 | length 29.9
  TOP_L1 w0.086: v6(74.082,114.436) MODULE1.BE29@74.682,115.036
  BOTTOM_L10 w0.1: U2.D3@58.737,114.036 59.087,113.686 64.628,113.686 64.728,113.786 71.071,113.786 71.361,114.076 72.328,114.076 72.618,113.786 75.692,113.786 76.205,113.273 77.091,113.273 77.179,113.361 77.179,114.67 75.682,116.167 75.682,116.236 74.966,116.236 73.844,117.359 73.803,117.359 73.586,117.576 TP50.X@73.342,117.576 73.342,116.836 74.142,116.036 74.142,114.496 v6(74.082,114.436)
NetMODULE1_BE31: MODULE1.BE31
NetMODULE1_BE33: MODULE1.BE33
NetMODULE1_BE35: MODULE1.BE35
NetMODULE1_BE36: MODULE1.BE36 TP93.X | length 22.8
  TOP_L1 w0.127: MODULE1.BE36@74.682,123.436 74.759,123.513 74.759,123.592 75.253,123.592 75.626,123.965 75.762,123.965 75.905,124.108 76.101,124.108 76.759,124.766 76.759,127.306 80.266,130.813 89.062,130.813 90.356,129.52 TP93.X@92.38,129.52
NetMODULE1_BE38: MODULE1.BE38
NetMODULE1_BE40: MODULE1.BE40
NetMODULE1_BE41: MODULE1.BE41
NetMODULE1_BF28: MODULE1.BF28 TP51.X U2.D2 | length 20.8
  TOP_L1 w0.1: MODULE1.BF28@75.882,113.836 v6(76.729,113.836)
  BOTTOM_L10 w0.1: U2.D2@59.737,114.036 60.407,114.706 60.572,114.706 60.592,114.686 60.882,114.686 61.44,115.244 63.357,115.244 64.615,113.986 70.988,113.986 71.278,114.276 72.411,114.276 72.701,113.986 74.832,113.986 TP51.X@75.882,115.036 76.53,115.036 76.882,114.684 76.882,114.51 76.729,114.357 v6(76.729,113.836)
NetMODULE1_BF29: MODULE1.BF29 TP57.X U2.E1 | length 35
  TOP_L1 w0.1: v6(59.242,110.136) 59.242,111.836 59.442,112.036 61.842,112.036 v1(62.053,112.247) ; MODULE1.BF29@75.882,115.036 76.692,115.846 v6(77.088,115.846)
  L3 w0.1: v1(62.053,112.247) v5(62.053,112.644)
  L8 w0.1: v5(62.053,112.644) v4(62.053,113.146)
  BOTTOM_L10 w0.1: v6(59.242,110.136) 68.681,110.136 70.981,107.836 72.339,107.836 77.379,112.877 77.379,115.554 v6(77.088,115.846) 75.958,116.976 75.958,117.5 TP57.X@75.882,117.576 ; U2.E1@60.737,113.036 61.041,113.036 61.15,113.146 v4(62.053,113.146)
  other v2: 62.053,112.247
  other v3: 62.053,113.146
NetMODULE1_BF31: MODULE1.BF31
NetMODULE1_BF33: MODULE1.BF33
NetMODULE1_BF35: MODULE1.BF35
NetMODULE1_BF36: MODULE1.BF36 TP32.X | length 23.2
  TOP_L1 w0.127: MODULE1.BF36@75.882,123.436 77.059,124.613 77.059,127.285 80.287,130.513 88.938,130.513 90.751,128.7 91.9,128.7 92.38,128.22 TP32.X@92.38,126.98
NetMODULE1_BF38: MODULE1.BF38
NetMODULE1_BF39: MODULE1.BF39
NetMODULE1_BF41: MODULE1.BF41
NetMODULE1_D28: MODULE1.D28 R125.2 | length 1.6
  TOP_L1 w0.127: v2(25.034,113.974) 25.058,113.999 25.156,113.999 25.319,113.836 MODULE1.D28@25.482,113.836
  L3 w0.127: v5(25.017,113.995) 25.017,113.991 v2(25.034,113.974) ; v2(25.034,113.974) 25.005,113.945 25.005,113.913 25.034,113.942 v2(25.034,113.974)
  L8 w0.127: v5(25.017,113.995) 25.017,113.991 v2(25.034,113.974) ; v2(25.034,113.974) 25.005,113.945 25.005,113.913 25.034,113.942 v2(25.034,113.974)
  BOTTOM_L10 w0.127: R125.2@24.982,113.299 24.982,113.923 v2(25.034,113.974)
  other v1: 25.034,113.974
  other v3: 25.034,113.974
  other v4: 25.034,113.974
NetMODULE1_D32: MODULE1.D32
NetMODULE1_D33: MODULE1.D33
NetMODULE1_E29: MODULE1.E29
NetMODULE1_G16: MODULE1.G16
NetMODULE1_H16: MODULE1.H16
NetMODULE1_K46: MODULE1.K46
NetPB1_3: PB1.3 PB1.4 R188.1 R477.1 | length 15
  TOP_L1 w0.127: PB1.4@2.15,51.653 PB1.3@10.55,51.653 10.554,51.649 12.183,51.649 ; R188.1@12.682,51.649 12.183,51.649 ; R477.1@13.232,48.653 13.582,48.653 13.703,48.774 13.703,50.381 13.134,50.95 12.357,50.95 12.183,51.124 12.183,51.649
NetPB2_1: PB2.1 PB2.3 R401.2 | length 10.5
  TOP_L1 w0.127: PB2.1@12.892,2.549 12.892,3.449 13.018,3.574 15.175,3.574 15.3,3.449 15.3,2.591 17.518,2.591 18.167,3.241 R401.2@18.167,6.324
NetQ1_G: Q1.G R231.2 | length 7.6
  TOP_L1 w0.15: R231.2@8.858,141.793 8.858,141.204 9.9,140.162 9.9,139.7 10.2,139.4 13.6,139.4 14.003,139.803 14.308,139.803 Q1.G@14.308,140.193
NetQ1_S: Q1.S Q2.S U15.6 | length 1
  TOP_L1 w0.3: 12.4,141.585 U15.6@12.4,142.608
NetQ2_G: Q2.G R231.1 U15.5 | length 4.8
  TOP_L1 w0.2: R231.1@10.408,141.793 10.408,142.566 11.4,143.558 U15.5@12.4,143.558 ; Q2.G@10.608,140.193 R231.1@10.608,141.793
NetQ3_2: Q3.2 R249.1 R368.1 TP82.X | length 6.9
  BOTTOM_L10 w0.127: Q3.2@78.657,90.316 78.657,89.555 78.932,89.28 78.932,89.259 79.022,89.169 79.028,89.169 79.331,88.865 79.331,88.309 TP82.X@79.375,88.265 ; Q3.2@78.658,90.316 78.658,90.854 78.919,91.115 79.959,91.115 80.108,91.264 80.108,92.958 80.391,93.241 R368.1@80.672,93.241
NetQ3_3: Q3.3 R367.1 | length 9.2
  BOTTOM_L10 w0.127: Q3.3@77.907,90.528 77.907,88.305 78.644,87.567 79.814,87.567 80.143,87.896 80.143,90.915 80.54,91.312 R367.1@81.274,91.312
NetQ3_5: Q3.5 R230.2 R248.2 | length 2.2
  BOTTOM_L10 w0.127: R248.2@77.657,93.333 78.013,93.333 78.206,93.14 R230.2@78.657,93.14 ; Q3.5@78.66,92.016 R230.2@78.66,93.14
NetQ3_6: Q3.6 R245.2 U15.3 | length 190.5
  TOP_L1 w0.127: v2(8.791,154.749) v1(10.091,154.749) ; v5(70.491,109.649) 70.491,106.221 v2(70.727,105.985)
  TOP_L1 w0.2: U15.3@15,144.508 16.323,144.508 v1@16.357,144.541 ; R245.2@16.357,143.868 v2(16.357,144.508)
  L3 w0.127: v2(8.791,154.749) 8.791,156.949 11.255,159.413 55.88,159.413 56.448,158.844 76.45,158.844 77.387,157.907 84.065,157.907 85.672,156.301 v5(85.672,151.404) ; v1(10.091,154.749) 9.9,154.557 9.9,146.389 11.14,145.149 15.716,145.149 v2(16.357,144.508)
  L8 w0.127: v5(70.491,109.649) 70.491,113.315 69.973,113.834 69.973,116.424 71.198,117.649 74.789,117.649 76.79,119.65 85.96,119.65 88.192,121.881 88.192,124.231 92.926,128.965 92.926,144.15 v5(85.672,151.404)
  BOTTOM_L10 w0.127: v2(70.727,105.985) 71.177,105.535 71.177,105.377 71.603,104.952 74.435,104.952 74.914,104.473 74.914,101.222 75.749,100.386 75.749,99.249 79.807,95.192 79.807,93.407 79.3,92.9 79.3,92.222 Q3.6@79.407,92.115
  other v1: 70.727,105.985 70.491,109.649 16.357,144.508 8.791,154.749
  other v2: 70.491,109.649 10.091,154.749
  other v3: 70.727,105.985
  other v4: 70.727,105.985
  other v5: 70.727,105.985
NetQ4_2: Q4.2 R459.1 | length 3.1
  TOP_L1 w0.127: Q4.2@16.15,12 16.15,12.5 16.35,12.7 17.316,12.7 17.841,13.225 R459.1@18.45,13.225
NetQ4_3: Q4.3 R166.2 R174.2 | length 2.1
  TOP_L1 w0.127: Q4.3@15.4,12 15.4,12.45 15.725,12.775 R174.2@15.725,13.2 R166.2@16.475,13.2
NetQ4_5: Q4.5 R457.1 | length 3
  TOP_L1 w0.127: Q4.5@16.15,10.2 16.15,9.846 16.534,9.462 17.913,9.462 R457.1@18.45,8.925
NetQ4_6: Q4.6 R346.2 R458.2 | length 3.9
  TOP_L1 w0.127: R458.2@14.525,11.9 R346.2@14.525,11.1 16.658,11.1 16.9,10.858 Q4.6@16.9,10.2
NetQ5_G: Q5.G R214.2 | length 7.1
  TOP_L1 w0.15: Q5.G@3.392,134.307 3.392,134.612 3.495,134.716 3.698,134.716 4.065,135.082 7.518,135.082 7.991,134.609 7.991,132.86 R214.2@8.058,132.793
NetQ5_S: Q5.S Q6.S U29.6 | length 1.2
  TOP_L1 w0.3: U29.6@5.3,131.865 5.3,133.101
NetQ6_G: Q6.G R214.1 U29.5 | length 4.7
  TOP_L1 w0.2: U29.5@5.3,130.915 6.13,130.915 6.508,131.293 R214.1@6.508,132.862 ; R214.1@6.508,132.793 6.508,132.809 6.877,133.178 6.893,133.178 7.092,133.377 Q6.G@7.092,134.307
NetR6_1: R6.1 U34.L1 | length 2.8
  TOP_L1 w0.1: U34.L1@46.311,31.099 46.686,31.099 46.836,30.949 46.836,29.402 47.048,29.191 47.403,29.191 R6.1@47.411,29.199
NetR7_1: R7.1 U34.U1 | length 1.4
  TOP_L1 w0.1: U34.U1@46.311,32.599 46.702,32.599 46.921,32.38 46.921,32.234 47.156,31.999 R7.1@47.411,31.999
NetR8_2: R8.2 TP24.X U34.H34 | length 19.9
  TOP_L1 w0.1: 36.615,30.349 37.128,30.349
  TOP_L1 w0.127: R8.2@35.473,30.099 35.971,30.099 36.207,30.334 36.6,30.334 36.615,30.349 ; 37.128,30.349 U34.H34@37.421,30.349 v1(37.745,30.349)
  L3 w0.127: v3(29.186,32.92) 29.192,32.913 30.602,32.913 30.752,33.063 33.299,33.063 34.99,31.373 37.667,31.373 38.012,31.028 38.012,30.616 v1(37.745,30.349)
  BOTTOM_L10 w0.127: TP24.X@22.86,32.68 23.75,33.57 25.808,33.57 25.955,33.424 28.681,33.424 v3(29.186,32.92)
  other v2: 37.745,30.349
  other v4: 29.186,32.92
  other v5: 29.186,32.92
NetR9_2: R9.2 U34.AP20 | length 1.8
  TOP_L1 w0.1: U34.AP20@41.091,37.019 41.091,37.993 41.386,38.288 R9.2@41.386,38.674
NetR10_2: R10.2 U34.AE1 | length 1.9
  TOP_L1 w0.1: U34.AE1@46.311,34.599 46.594,34.599 46.906,34.912 46.906,35.096 47.036,35.226 47.036,35.509 47.411,35.884 R10.2@47.411,35.899
NetR11_2: R11.2 U34.V2 | length 3.4
  TOP_L1 w0.1: v2(45.43,32.837) 45.749,32.837 U34.V2@45.761,32.849
  L3 w0.1: v5(45.423,33.675) 45.427,33.671 45.427,32.84 v2(45.43,32.837)
  L8 w0.1: v3(45.123,33.975) v5(45.423,33.675)
  BOTTOM_L10 w0.1: v3(45.123,33.975) 45.448,33.65 45.448,32.979 45.695,32.732 R11.2@45.98,32.732
  other v1: 45.43,32.837
  other v4: 45.123,33.975
NetR23_1: R23.1 U12.30 U21_5.3 | length 21
  L3 w0.127: v3(29.134,31.319) 31.144,31.319 31.89,32.065 33.113,32.065 v5(33.782,31.396)
  BOTTOM_L10 w0.127: U12.30@27.5,26.66 28.4,26.66 ; v3(29.134,31.319) 29.11,31.295 29,31.295 29,30.743 29.398,30.345 29.398,29.793 28.4,28.795 28.4,26.66 ; U21_5.3@30.9,28.37 30.9,27.579 30.934,27.546 30.934,26.583 30.822,26.471 28.828,26.471 28.639,26.66 28.4,26.66 ; R23.1@33.15,27.307 33.771,27.307 33.86,27.396 33.86,27.511 33.882,27.533 33.882,28.08 34.169,28.366 34.169,30.919 33.901,31.186 33.901,31.244 33.8,31.345 v3@33.8,31.395
  other v3: 33.782,31.396
  other v4: 29.134,31.319 33.782,31.396
  other v5: 29.134,31.319
NetR24_2: R24.2 U21_5.8 | length 1.2
  BOTTOM_L10 w0.127: R24.2@30.3,30.895 30.3,30.506 30.5,30.306 U21_5.8@30.5,29.77
NetR25_1: R25.1 R473.2 | length 0.6
  BOTTOM_L10 w0.15: R473.2@96.075,29.2 96.075,29.775 R25.1@96.1,29.8
NetR25_2: R25.2 U27_6.4 | length 2
  BOTTOM_L10 w0.127: R25.2@96.1,30.3 96.531,30.3 96.865,29.967 97.285,29.967 97.415,30.097 U27_6.4@97.415,30.585
NetR26_1: R26.1 R474.2 | length 0.6
  BOTTOM_L10 w0.127: R26.1@98.298,54.521 R474.2@98.298,55.121
NetR26_2: R26.2 U27_5.4 | length 2.7
  BOTTOM_L10 w0.15: R26.2@98.298,53.971 98.686,53.582 98.686,52.053 98.571,51.937 U27_5.4@98.571,51.496
NetR61_1: R61.1 TP25.X U2.A5 | length 11.9
  BOTTOM_L10 w0.1: U2.A5@56.737,117.036 57.242,116.531 57.242,114.917 57.494,114.665 58.195,114.665 58.253,114.724 58.253,115.269 58.52,115.536 59.954,115.536 60.062,115.644 63.523,115.644 64.13,115.036 TP25.X@65.722,115.036
NetR62_1: R62.1 R77.2 TP45.X U1.26 | length 13.2
  TOP_L1 w0.127: R62.1@64.325,14.77 R77.2@64.925,14.77 ; U1.26@67.681,11.134 67.681,11.674 67.177,12.178 66.354,12.178 66.18,12.352 66.138,12.352 65.969,12.521 65.969,12.562 65.83,12.702 65.83,14.17 65.622,14.378 64.999,14.378 64.925,14.452 R77.2@64.925,14.77 ; v2(69.033,17.453) 66.701,17.453 64.925,15.676 R77.2@64.925,14.77
  L3 w0.127: v2(69.033,17.453) 69.037,17.453 69.279,17.694 v5(69.283,17.694)
  L8 w0.127: v5(69.283,17.694) 69.286,17.692 69.632,17.692 v4(69.635,17.689)
  BOTTOM_L10 w0.127: v4(69.635,17.689) 69.91,17.414 TP45.X@69.91,17.338
  other v1: 69.033,17.453
  other v3: 69.635,17.689
NetR63_1: R63.1 R78.2 TP44.X U1.27 | length 17.2
  TOP_L1 w0.127: U1.27@67.281,11.134 67.281,11.675 67.005,11.951 66.173,11.951 65.6,12.524 65.6,13.328 65.365,13.563 64.999,13.563 64.925,13.637 R78.2@64.925,13.97 R63.1@64.325,13.97 64.325,14.226 64.176,14.375 63.372,14.375 63.223,14.523 63.223,14.626 63.18,14.669 63.18,14.908 63.223,14.951 63.223,15.126 63.372,15.275 64.123,15.275 66.623,17.775 67.431,17.775 67.462,17.744 v1(68.303,17.744)
  L3 w0.127: v1(68.303,17.744) 68.336,17.744 68.533,17.941 v5(68.589,17.941)
  L8 w0.127: v5(68.589,17.941) 68.595,17.935 68.923,17.935 v3(68.929,17.929)
  BOTTOM_L10 w0.127: v3(68.929,17.929) 69.1,18.1 70.045,18.1 70.045,19.002 69.769,19.278 69.769,19.819 TP44.X@69.71,19.878
  other v2: 68.303,17.744
  other v4: 68.929,17.929
NetR64_1: R64.1 R79.2 TP46.X U1.45 | length 7.3
  TOP_L1 w0.1: v5(65.206,3.063) 65.206,2.651 64.965,2.41 64.965,2.009 65.294,1.68 R79.2@65.93,1.68 65.94,1.69 R64.1@65.94,2.33 66.3,2.69 66.3,3.379 66.505,3.584 67.111,3.584 67.112,3.585 67.481,3.585 67.681,3.785 U1.45@67.681,4.384
  L8 w0.127: v5(65.206,3.063) v5(65.206,3.063) 65.556,3.064 v3(65.558,3.066)
  BOTTOM_L10 w0.1: v3(65.558,3.066) 65.558,3.044 66.04,2.562 TP46.X@66.04,2.54
  other v1: 65.206,3.063
  other v2: 65.206,3.063
  other v4: 65.558,3.066
NetR65_1: R65.1 R80.2 TP47.X U1.29 | length 11
  TOP_L1 w0.127: R80.2@64.779,11.775 R65.1@64.779,11.129 65.076,11.129 v1(65.398,11.451) 65.566,11.451 66.106,10.911 U1.29@66.106,10.359
  L3 w0.127: v5(65.23,12.087) 65.23,12.013 65.398,11.846 v1(65.398,11.451)
  BOTTOM_L10 w0.127: v5(65.23,12.087) 65.23,9.44 65.112,9.322 65.112,7.423 66.04,6.495 TP47.X@66.04,5.08
  other v2: 65.398,11.451
  other v3: 65.23,12.087
  other v4: 65.23,12.087
NetR66_1: R66.1 R81.2 U1.49 U9.2 | length 48.8
  TOP_L1 w0.1: R66.1@69.14,1.68 R81.2@69.14,2.33 69.481,2.671 69.481,3.359 69.281,3.559 U1.49@69.281,4.384
  TOP_L1 w0.127: R66.1@69.14,1.68 69.393,1.68 69.725,2.011 70.011,2.011 70.229,2.23 70.566,2.23 70.796,2.46 78.809,2.46 79.27,2.921 87.806,2.921 88.616,3.731 88.616,5.095 88.616,5.759 90.024,7.168 90.495,7.168 90.823,7.496 90.823,10.923 94.14,14.24 97.294,14.24 97.755,14.702 97.755,20.352 97.904,20.501 v6(98.541,20.501)
  BOTTOM_L10 w0.127: U9.2@97.481,19.119 98.141,19.119 98.541,19.519 v6(98.541,20.501)
NetR67_1: R67.1 R82.2 U1.48 U8.2 | length 48
  TOP_L1 w0.1: R67.1@68.46,1.68 R82.2@68.46,2.33 68.8,2.67 68.8,3.285 68.881,3.366 U1.48@68.881,4.384
  TOP_L1 w0.127: R67.1@68.46,1.68 68.802,1.338 68.802,0.723 68.951,0.575 70.223,0.575 70.522,0.873 70.522,1.707 71.028,2.213 78.911,2.213 79.372,2.675 87.881,2.675 88.843,3.637 88.843,5.665 90.118,6.941 90.589,6.941 91.07,7.421 91.07,10.821 94.189,13.94 98.18,13.94 98.941,14.701 v6(98.941,17.219)
  BOTTOM_L10 w0.127: U8.2@97.481,16.519 98.241,16.519 v6(98.941,17.219)
NetR68_1: R68.1 R83.2 TP48.X U1.46 | length 6.6
  TOP_L1 w0.1: R68.1@66.62,1.68 R83.2@66.62,2.33 66.94,2.65 66.94,3.109 67.216,3.385 67.707,3.385 68.081,3.759 U1.46@68.081,4.384
  BOTTOM_L10 w0.1: v4(66.96,3.129) 67.663,3.129 68.58,4.047 TP48.X@68.58,5.08
  other v1: 66.96,3.129
  other v2: 66.96,3.129
  other v3: 66.96,3.129
  other v5: 66.96,3.129
NetR84_1: R84.1 U1.50 | length 1.6
  TOP_L1 w0.127: U1.50@69.681,4.384 69.681,3.559 69.82,3.42 R84.1@69.82,2.88
NetR86_1: R86.1
NetR86_2: R86.2 U5.21 | length 1.2
  BOTTOM_L10 w0.1: U5.21@85.103,91.697 85.103,92.297 85.303,92.497 R86.2@85.303,92.772
NetR87_1: R87.1
NetR87_2: R87.2 U5.22 | length 1.3
  BOTTOM_L10 w0.1: U5.22@85.503,91.697 85.503,92.322 R87.2@85.953,92.772
NetR91_2: R91.2 R92.1 U5.52 | length 4.2
  BOTTOM_L10 w0.104: R91.2@81.353,85.047 81.768,85.047 81.773,85.042 ; R92.1@81.353,85.747 81.653,85.747 81.77,85.63 81.77,85.047 81.77,84.23 82.203,83.797 U5.52@83.503,83.797
NetR93_2: R93.2 U6.1 | length 0.8
  TOP_L1 w0.109: U6.1@86.7,78.94 R93.2@86.7,79.69
NetR94_2: R94.2 U6.14 | length 0.9
  TOP_L1 w0.109: R94.2@81.3,79.766 81.3,79.459 81.5,79.259 U6.14@81.5,78.94
NetR95_2: R95.2 U6.35 | length 0.9
  TOP_L1 w0.15: U6.35@87.075,76.465 R95.2@87.925,76.465
NetR96_2: R96.2 U6.13 | length 0.8
  TOP_L1 w0.109: U6.13@81.9,78.94 R96.2@81.9,79.69
  TOP_L1 w0.127: R96.2@81.9,79.69 R96.2@81.9,79.766
NetR97_1: R97.1 R102.1 R406.2 | length 25.1
  TOP_L1 w0.1: R97.1@88.475,77.065 88.738,77.065 88.885,77.212 88.885,78.026 88.701,78.211 88.701,81.689 91.711,84.7 91.711,93.59 91.101,94.2 v1(89.611,94.2)
  L3 w0.1: v5(89.41,94.439) 89.41,94.401 v1(89.611,94.2)
  L8 w0.1: v3(87.627,95) 88.189,94.439 v5(89.41,94.439)
  BOTTOM_L10 w0.127: R102.1@87.253,93.322 87.253,93.941 87.634,94.322 R406.2@87.634,95.372
  other v2: 89.611,94.2
  other v4: 87.627,95
NetR97_2: R97.2 U6.36 | length 0.9
  TOP_L1 w0.15: U6.36@87.075,76.865 87.477,76.865 87.611,76.999 87.621,76.999 87.687,77.065 R97.2@87.925,77.065
NetR98_1: R98.1 R103.1 R407.2 | length 22.9
  TOP_L1 w0.1: R98.1@88.475,77.665 88.501,77.691 88.501,81.772 91.511,84.783 91.511,92.8 90.785,93.527 v1(89.576,93.527)
  L3 w0.1: v5(89.365,93.305) 89.367,93.305 89.576,93.514 v1(89.576,93.527)
  L8 w0.1: v3(87.903,93.785) 88.47,93.218 89.278,93.218 v5(89.365,93.305)
  BOTTOM_L10 w0.127: R103.1@87.903,93.322 87.903,94.782 88.284,95.163 R407.2@88.284,95.372
  other v2: 89.576,93.527
  other v4: 87.903,93.785
NetR98_2: R98.2 U6.38 | length 0.9
  TOP_L1 w0.15: U6.38@87.075,77.665 R98.2@87.925,77.665
NetR99_2: R99.2 U5.18 | length 3.2
  BOTTOM_L10 w0.1: R99.2@81.403,92.772 81.708,92.467 83.474,92.467 83.674,92.267 83.834,92.267 83.903,92.198 U5.18@83.903,91.697
NetR100_2: R100.2 U5.19 | length 1.7
  BOTTOM_L10 w0.1: R100.2@83.353,92.772 83.439,92.686 83.538,92.686 83.757,92.467 84.008,92.467 84.303,92.172 U5.19@84.303,91.697
NetR101_2: R101.2 U5.20 | length 1.1
  BOTTOM_L10 w0.1: R101.2@84.653,92.772 84.653,92.397 84.703,92.347 U5.20@84.703,91.697
NetR102_2: R102.2 U5.25 | length 1.4
  BOTTOM_L10 w0.1: U5.25@86.703,91.697 86.703,92.222 86.748,92.267 86.871,92.267 87.152,92.548 87.152,92.671 R102.2@87.253,92.772
NetR103_2: R103.2 U5.26 | length 1.7
  BOTTOM_L10 w0.1: U5.26@87.103,91.697 87.103,92.174 87.329,92.4 87.786,92.4 87.903,92.517 R103.2@87.903,92.772
NetR104_1: R104.1
NetR104_2: R104.2 U5.23 | length 1.4
  BOTTOM_L10 w0.1: U5.23@85.903,91.697 85.903,92.174 85.976,92.247 86.078,92.247 R104.2@86.603,92.772
NetR106_2: R106.2 U5.51 | length 32.7
  TOP_L1 w0.15: v2(91.911,63.2) 95.011,63.2 96.201,64.389 R106.2@96.201,65.909
  L3 w0.15: v5(91.411,63.5) 91.459,63.452 91.659,63.452 v2(91.911,63.2)
  L8 w0.15: v4(83.889,79.848) 84.578,80.537 84.578,82.587 v4(83.901,83.265) ; v3(91.011,63.8) 91.031,63.781 91.131,63.781 v5(91.411,63.5)
  BOTTOM_L10 w0.15: v4(83.889,79.848) 84.719,79.018 85.67,79.018 86.054,78.634 86.054,76.384 86.218,76.22 86.218,76.211 86.407,76.022 88.368,76.022 88.5,75.89 88.5,68.911 91.011,66.4 v3(91.011,63.8) ; v4(83.901,83.265) 83.903,83.267 U5.51@83.903,83.797
  other v1: 91.911,63.2
  other v3: 83.889,79.848 83.901,83.265
  other v4: 91.011,63.8
NetR110_2: R110.2 U8.4 | length 1.3
  BOTTOM_L10 w0.127: R110.2@94.741,16.194 95.327,16.194 95.502,16.019 U8.4@96.001,16.019
NetR111_2: R111.2 U9.4 | length 1.3
  BOTTOM_L10 w0.127: R111.2@94.741,18.794 95.327,18.794 95.502,18.619 U9.4@96.001,18.619
NetR112_1: R112.1 R269.2 U10_3.17 | length 129.2
  TOP_L1 w0.086: R112.1@89.127,64.525 v1(89.127,63.975) 89.632,63.975 89.902,64.245 R269.2@89.902,64.525
  TOP_L1 w0.127: U10_3.17@75.782,138.491 76.093,138.491 77.635,136.949 79.228,136.949 79.764,136.413 79.764,131.937 78.973,131.145 v2(78.955,131.145)
  L3 w0.127: v5@77.125,62.184 77.125,64.374 79.957,67.206 83.672,67.206 85.464,65.413 88.964,65.413 89.127,65.25 v1(89.127,63.975) ; v5(77.931,131.129) 77.939,131.137 78.947,131.137 v2(78.955,131.145)
  L8 w0.127: v3(72.721,62.855) 72.721,76.47 82.761,86.51 82.761,92.906 81.915,93.752 81.915,95.429 82.245,95.759 82.245,97.44 81.356,98.329 81.356,105.607 79.888,107.074 76.254,107.074 75.825,106.646 70.732,106.646 68.136,109.241 68.136,116.192 71.053,119.109 73.616,119.109 75.957,121.45 78.05,121.45 78.161,121.562 78.161,128.387 79.261,129.487 79.261,130.648 78.78,131.129 v5(77.931,131.129) ; v4(76.813,61.861) 76.813,61.886 77.091,62.164 v5(77.091,62.189)
  BOTTOM_L10 w0.127: v3(72.721,62.855) 72.721,62.343 73.304,61.76 73.344,61.76 73.464,61.64 74.21,61.64 74.211,61.642 75.585,61.642 75.703,61.76 76.679,61.76 76.78,61.861 v4(76.813,61.861)
  other v1: 78.955,131.145
  other v2: 89.127,63.975
  other v3: 76.813,61.861
  other v4: 72.721,62.855
NetR113_1: R113.1
NetR113_2: R113.2 U5.11 | length 0.9
  BOTTOM_L10 w0.1: R113.2@81.951,88.712 82.078,88.712 82.113,88.747 U5.11@82.853,88.747
NetR114_1: R114.1
NetR114_2: R114.2 U5.12 | length 1.1
  BOTTOM_L10 w0.1: R114.2@81.824,89.312 82.078,89.312 82.243,89.147 U5.12@82.853,89.147
NetR118_2: R118.2 R120.2 R403.1 R404.1 U11.22 | length 14.2
  TOP_L1 w0.127: v1(0.898,116.235) 0.903,116.24 R404.1@1.225,116.24 ; R403.1@1.7,106.69 v1(1.7,106.337) ; R118.2@1.975,105.865 1.975,105.922 1.723,106.173 1.723,106.313 v1(1.7,106.337) ; R120.2@2.4,106.665 U11.22@3.725,106.665 ; R120.2@2.4,106.69 2.053,106.69 v1(1.7,106.337)
  L3 w0.127: v1(0.898,116.235) v5(1.311,116.235) ; v5(1.452,106.872) 1.7,106.625 v1(1.7,106.337)
  L8 w0.127: v5(1.311,116.235) 1.084,116.008 1.084,107.146 1.174,107.056 1.212,107.056 1.397,106.872 v5(1.452,106.872)
  other v2: 1.7,106.337 0.898,116.235
NetR121_1: R121.1 R127.1 R238.2 | length 1.4
  TOP_L1 w0.127: R238.2@1,104.49 R127.1@2.4,104.49
NetR121_2: R121.2 R127.2 U11.23 | length 2.8
  TOP_L1 w0.127: R121.2@1.7,105.04 R127.2@2.4,105.04 2.8,105.44 2.8,106.028 2.937,106.165 U11.23@3.725,106.165
NetR123_1: R123.1 R128.1 R132.1 | length 2.2
  TOP_L1 w0.127: R128.1@2.1,113.94 2.815,113.94 3.025,114.15 R132.1@3.025,114.665 R123.1@3.025,115.365
NetR123_2: R123.2 R132.2 U13.1 U13.2 | length 2.1
  TOP_L1 w0.127: R132.2@3.575,114.665 R123.2@3.575,115.365 3.875,115.665 U13.1@3.875,116.615
NetR129_2: R129.2 R131.2 R405.1 U14.22 | length 3
  TOP_L1 w0.127: R129.2@1.975,91.666 1.975,91.691 1.7,91.966 1.7,92.391 R405.1@1.7,92.491 R131.2@2.4,92.491 ; R131.2@2.4,92.466 U14.22@3.725,92.466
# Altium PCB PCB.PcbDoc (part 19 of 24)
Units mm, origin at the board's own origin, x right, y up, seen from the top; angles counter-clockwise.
Board outline 100 x 160 mm, 10 copper layers (TOP_L1, L2, L3, L4, L5, L6, L7, L8, L9, BOTTOM_L10), stack 1.946 mm thick; 1358 components, 1149 nets, 6777 pads, 10914 vias.

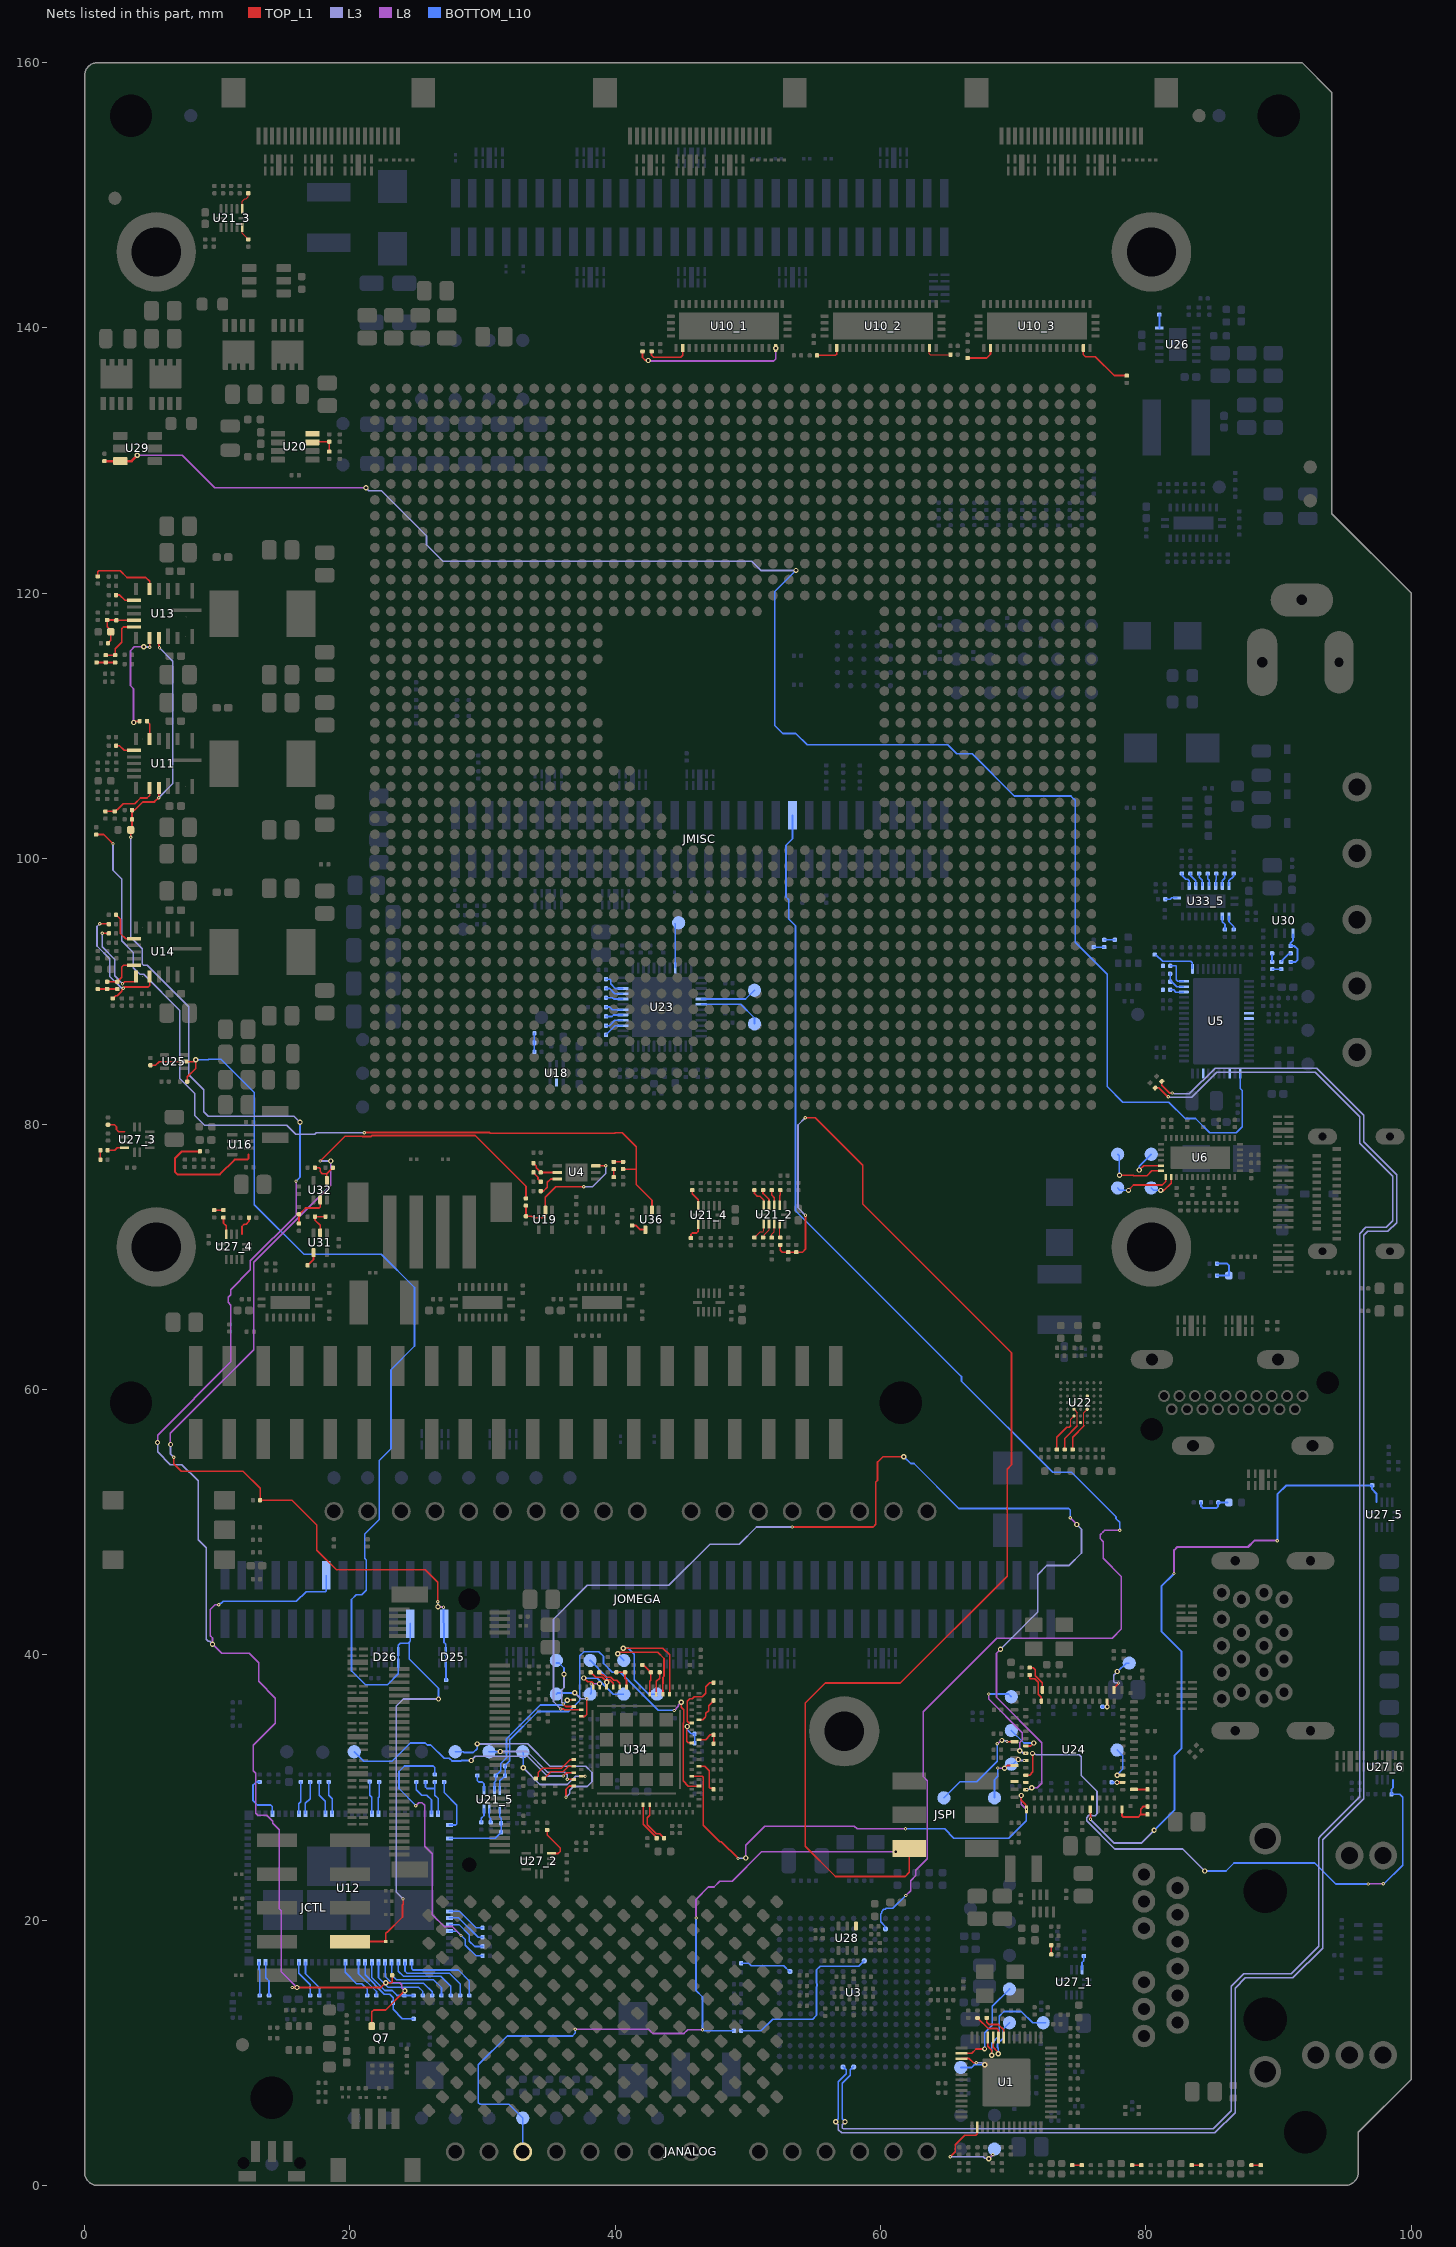
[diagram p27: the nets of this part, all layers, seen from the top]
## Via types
v1: diameter 0.25, hole 0.1, TOP_L1 to L2, tented both sides, 3439 vias
v2: diameter 0.25, hole 0.1, L2 to L3, tented both sides, 2256 vias
v3: diameter 0.25, hole 0.1, L9 to BOTTOM_L10, tented both sides, 1685 vias
v4: diameter 0.25, hole 0.1, L8 to L9, tented both sides, 1675 vias
v5: diameter 0.4, hole 0.2, L3 to L8, tented both sides, 1251 vias
v6: diameter 0.6, hole 0.3, TOP_L1 to BOTTOM_L10, tented both sides, 600 vias
v7: diameter 0.24, hole 0.1, TOP_L1 to L2, tented both sides, 8 vias

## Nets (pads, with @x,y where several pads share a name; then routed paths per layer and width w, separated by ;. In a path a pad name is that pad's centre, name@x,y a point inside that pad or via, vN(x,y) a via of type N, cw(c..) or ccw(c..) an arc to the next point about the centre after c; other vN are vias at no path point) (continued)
NetR133_1: R133.1 R359.2 U11.3 | length 4.4
  TOP_L1 w0.127: R359.2@1.575,103.566 2.299,103.566 2.426,103.693 2.474,103.693 2.924,104.142 3.786,104.142 4.216,104.573 4.708,104.573 4.9,104.765 U11.3@4.9,105.315
NetR135_1: R135.1 R242.1 R243.2 | length 1.5
  TOP_L1 w0.127: R243.2@1,90.172 R135.1@1.7,90.172 R242.1@2.469,90.172
NetR135_2: R135.2 R242.2 U14.23 | length 3
  TOP_L1 w0.127: R135.2@1.7,90.722 R242.2@2.469,90.722 2.475,90.722 2.611,90.858 2.611,90.864 2.8,91.053 2.8,91.828 2.937,91.966 U14.23@3.725,91.966
NetR136_1: R136.1 R293.2 U34.AP14 | length 2.6
  TOP_L1 w0.1: R136.1@42.036,39.224 42.136,39.224 R293.2@42.686,38.674 42.686,38.088 42.591,37.993 42.591,37.332 U34.AP14@42.591,37.019
NetR137_2: R137.2 R358.1 U14.3 | length 10.5
  TOP_L1 w0.127: v1(1.148,95.1) 1.165,95.083 1.808,95.083 R358.1@1.825,95.066 ; R137.2@2.119,89.466 2.149,89.466 2.345,89.662 2.468,89.662 2.802,89.996 2.802,90.085 2.913,90.196 v2(2.913,90.229) 3.011,90.328 4.788,90.328 4.9,90.439 U14.3@4.9,91.116
  L3 w0.127: v1(1.148,95.1) 0.939,94.891 0.939,93.413 1.906,92.446 1.906,91.115 2.792,90.229 v2(2.913,90.229)
  other v1: 2.913,90.229
  other v2: 1.148,95.1
NetR138_1: R138.1 R294.2 U34.Y2 | length 3.2
  TOP_L1 w0.1: v2(45.412,34.591) 45.389,34.568 45.389,33.466 45.506,33.349 U34.Y2@45.761,33.349
  BOTTOM_L10 w0.1: v2(45.412,34.591) 45.412,34.345 45.725,34.032 R294.2@45.98,34.032 R138.1@45.98,33.332
  other v1: 45.412,34.591
  other v3: 45.412,34.591
  other v4: 45.412,34.591
  other v5: 45.412,34.591
NetR139_1: R139.1 R148.1 R149.1 | length 1.4
  BOTTOM_L10 w0.127: R149.1@33.9,85.431 R139.1@33.9,86.831
NetR140_2: R140.2 U21_2.10 | length 1
  TOP_L1 w0.084: R140.2@52.389,71.44 U21_2.10@52.389,72.469
NetR143_1: R143.1 U34.N1 | length 2.5
  TOP_L1 w0.1: U34.N1@46.311,31.599 46.749,31.599 47.077,31.271 47.077,30.024 47.165,29.936 47.309,29.936 47.383,29.862 R143.1@47.383,29.849
NetR145_1: R145.1 R356.2 | length 0.7
  TOP_L1 w0.127: R356.2@72.856,17.409 R145.1@72.856,18.109
NetR150_2: R150.2 U16.1 | length 9.6
  TOP_L1 w0.15: R150.2@8.693,77.941 7.341,77.941 6.8,77.4 6.8,76.4 7,76.2 10.2,76.2 11.309,77.309 12.268,77.309 12.368,77.409 U16.1@12.368,77.691
NetR151_2: R151.2 U21_2.9 | length 1.1
  TOP_L1 w0.084: R151.2@51.789,71.44 51.789,71.694 51.989,71.894 U21_2.9@51.989,72.469
NetR152_2: R152.2 U21_2.8 | length 1.2
  TOP_L1 w0.084: R152.2@51.139,71.44 51.215,71.516 51.215,71.652 51.589,72.026 U21_2.8@51.589,72.469
NetR153_2: R153.2 U21_2.7 | length 1.4
  TOP_L1 w0.084: R153.2@50.489,71.44 50.944,71.895 51.14,71.895 51.189,71.944 U21_2.7@51.189,72.469
NetR154_2: R154.2 U24.A48 U27_5.1 | length 50.1
  TOP_L1 w0.15: U24.A48@75.791,28.349 75.801,28.339 75.801,27.61 v2(75.811,27.6)
  L3 w0.15: v2(75.811,27.6) 77.611,25.8 79.647,25.8 v4(80.609,26.762)
  L8 w0.15: v3(82.115,46.122) 82.115,47.888 82.347,48.12 87.689,48.12 88.169,48.6 v3(89.9,48.6)
  BOTTOM_L10 w0.15: v4(80.609,26.762) 82.132,28.285 82.132,32.377 82.669,32.913 82.669,40.261 81.162,41.768 81.162,45.169 v3(82.115,46.122) ; v3(89.9,48.6) 89.9,52.08 90.59,52.771 96.129,52.771 R154.2@97.048,52.771 97.048,52.471 97.371,52.148 U27_5.1@97.371,51.496
  other v1: 75.811,27.6
  other v3: 80.609,26.762
  other v4: 82.115,46.122 89.9,48.6
  other v5: 80.609,26.762
NetR156_2: R156.2 U4.3 | length 1.8
  TOP_L1 w0.127: R156.2@34.382,74.949 34.589,74.949 34.88,75.24 34.88,75.6 35.129,75.849 U4.3@35.632,75.849
NetR157_1: R157.1 R180.2 | length 0.9
  TOP_L1 w0.127: R157.1@33.832,76.349 33.832,76.334 34.171,75.995 34.171,75.86 R180.2@34.382,75.649
NetR157_2: R157.2 R220.1 U4.2 | length 2.2
  TOP_L1 w0.127: R220.1@33.832,77.049 34.043,76.838 34.043,76.703 34.382,76.364 R157.2@34.382,76.349 U4.2@35.632,76.349
NetR161_2: R161.2 U33_5.5 | length 1
  BOTTOM_L10 w0.1: R161.2@84.003,98.874 84.003,98.61 84.253,98.36 U33_5.5@84.253,97.945
NetR162_2: R162.2 U10_2.2 | length 2
  TOP_L1 w0.109: R162.2@55.206,137.926 56.573,137.926 56.682,138.035 56.682,138.088 U10_2.2@56.682,138.491
NetR167_2: R167.2 U22.C5 | length 3.5
  TOP_L1 w0.064: 75.324,57.249 75.324,58.249 U22.C5@75.575,58.5
  TOP_L1 w0.127: R167.2@74.475,55.465 74.475,56.4 75.324,57.249
NetR172_2: R172.2 U33_5.8 | length 1
  BOTTOM_L10 w0.1: U33_5.8@85.753,97.945 85.753,98.32 85.953,98.52 R172.2@85.953,98.874
NetR173_1: R173.1 U33_5.13 | length 1.1
  BOTTOM_L10 w0.127: U33_5.13@85.753,95.645 85.753,95.245 85.953,95.045 R173.1@85.953,94.647
NetR178_2: R178.2 U33_5.6 | length 1
  BOTTOM_L10 w0.1: R178.2@84.653,98.874 84.653,98.485 84.753,98.385 U33_5.6@84.753,97.945
NetR182_2: R182.2 U24.B34 U27_6.1 | length 45.9
  TOP_L1 w0.1: U24.B34@70.941,30.924 71.241,30.924 71.48,31.162 71.48,31.983 v2(71.48,32.582)
  L3 w0.1: v5(71.441,32.56) 71.463,32.582 v2(71.48,32.582)
  L3 w0.127: v5(71.441,32.56) 71.493,32.508 71.667,32.508 71.726,32.449 74.963,32.449 75.111,32.3 75.111,30.9 76.311,29.7 76.311,28.016 76.163,27.867 75.952,27.867 75.931,27.888 75.692,27.888 75.523,27.719 75.523,27.48 77.646,25.357 82.769,25.357 v4(84.426,23.7)
  L8 w0.127: v4(96.74,22.722) 96.751,22.733 v3(97.89,22.733)
  BOTTOM_L10 w0.127: v4(84.426,23.7) 86.03,23.7 86.63,24.3 92.73,24.3 94.308,22.722 v4(96.74,22.722) ; v3(97.89,22.733) 97.943,22.733 99.345,24.135 99.345,29.245 99.115,29.475 R182.2@98.5,29.475 98.5,29.855 98.615,29.97 U27_6.1@98.615,30.585
  other v1: 71.48,32.582
  other v3: 96.74,22.722 84.426,23.7
  other v4: 97.89,22.733
  other v5: 84.426,23.7
NetR183_2: R183.2 U27_2.4 | length 2.7
  TOP_L1 w0.127: R183.2@34.86,26.781 34.86,26.41 35.84,25.43 35.84,25.172 35.691,25.024 U27_2.4@35.191,25.024
NetR185_1: R185.1 U34.B14 | length 3.2
  TOP_L1 w0.1: U34.B14@42.591,28.679 42.591,27.892 42.424,27.725 42.424,27.172 43.085,26.511 43.337,26.511 R185.1@43.673,26.175
NetR185_2: R185.2 U34.B16 | length 2.9
  TOP_L1 w0.1: U34.B16@42.091,28.679 42.091,27.222 43.123,26.19 R185.2@43.123,26.175
NetR186_2: R186.2 U33_5.1 | length 0.9
  BOTTOM_L10 w0.1: R186.2@81.451,96.947 81.84,96.947 81.932,97.039 82.347,97.039 U33_5.1@82.353,97.045
NetR187_2: R187.2 U33_5.7 | length 0.9
  BOTTOM_L10 w0.1: U33_5.7@85.253,97.945 85.253,98.366 85.303,98.416 R187.2@85.303,98.874
NetR189_2: R189.2 U24.A2 | length 1
  TOP_L1 w0.15: U24.A2@79.091,29.849 R189.2@80.116,29.849
NetR190_1: R190.1 U24.A24 | length 2.2
  TOP_L1 w0.1: R190.1@71.226,39.024 71.488,39.024 71.644,38.868 71.644,38.432 72.191,37.884 U24.A24@72.191,37.349
NetR190_2: R190.2 U24.B23 | length 2.5
  TOP_L1 w0.1: R190.2@71.226,38.474 71.226,38.241 71.285,38.182 71.611,38.182 71.886,37.907 71.886,37.035 72.116,36.804 U24.B23@72.116,36.499
NetR191_1: R191.1 R192.1 U24.A52 | length 3.5
  TOP_L1 w0.15: U24.A52@78.191,28.349 78.191,27.876 78.304,27.763 79.408,27.763 79.604,27.959 ; R191.1@80.116,27.959 79.604,27.959 ; R192.1@80.116,28.559 79.8,28.559 79.604,28.363 79.604,27.959
NetR193_1: R193.1 U24.B14 | length 0.8
  TOP_L1 w0.2: v1(77.066,36.074) U24.B14@77.066,36.499
  BOTTOM_L10 w0.2: R193.1@76.716,36.074 v1(77.066,36.074)
  other v2: 77.066,36.074
  other v3: 77.066,36.074
  other v4: 77.066,36.074
  other v5: 77.066,36.074
NetR206_1_2: R206_1.2 R208_1.1 | length 0.7
  TOP_L1 w0.127: R206_1.2@87.95,1.525 R208_1.1@88.65,1.525
NetR206_2_2: R206_2.2 R208_2.1 | length 0.7
  TOP_L1 w0.127: R206_2.2@83.45,1.525 R208_2.1@84.15,1.525
NetR206_3_2: R206_3.2 R208_3.1 | length 0.7
  TOP_L1 w0.127: R206_3.2@78.95,1.525 R208_3.1@79.65,1.525
NetR206_4_2: R206_4.2 R208_4.1 | length 0.7
  TOP_L1 w0.127: R206_4.2@74.45,1.525 R208_4.1@75.15,1.525
NetR215_1: R215.1 U5.43 U29.3 | length 132.1
  TOP_L1 w0.2: R215.1@1.5,129.965 U29.3@2.7,129.965 3.538,129.965 v1(3.968,130.394)
  L3 w0.127: v5(21.209,127.944) 21.428,127.725 22.381,127.725 25.777,124.329 25.777,123.652 27.017,122.411 50.288,122.411 50.974,121.725 v5(53.623,121.725)
  L8 w0.127: v1(3.968,130.394) 7.354,130.394 9.804,127.944 v5(21.209,127.944)
  BOTTOM_L10 w0.127: v5(53.623,121.725) 52.029,120.13 52.029,110.03 52.624,109.435 53.613,109.435 54.475,108.573 65.065,108.573 65.743,107.895 66.911,107.895 70.081,104.725 74.341,104.725 74.67,104.395 74.67,93.69 77.075,91.285 77.075,82.825 78.25,81.65 81.707,81.65 82.948,80.41 83.735,80.41 84.805,79.34 86.794,79.34 87.259,79.805 87.259,82.521 87.103,82.676 U5.43@87.103,83.797
  other v2: 3.968,130.394
  other v3: 53.623,121.725
  other v4: 53.623,121.725
  other v5: 3.968,130.394
NetR217_2: R217.2 U14.1 U14.2 | length 6.4
  TOP_L1 w0.127: v2(1.323,94.375) 1.327,94.37 1.82,94.37 R217.2@1.825,94.366 ; v1(2.856,90.581) 2.878,90.581 3.026,90.729 3.789,90.729 3.875,90.816 U14.1@3.875,91.116
  L3 w0.127: v2(1.323,94.375) 1.323,93.351 2.275,92.399 2.275,91.162 v1(2.856,90.581)
  other v1: 1.323,94.375
  other v2: 2.856,90.581
NetR221_2: R221.2 U14.19 | length 2.7
  TOP_L1 w0.127: R221.2@2.375,95.766 2.375,95.751 2.706,95.42 2.706,94.36 3.1,93.966 U14.19@3.725,93.966
NetR222_1: R222.1 R223.2 | length 0.6
  TOP_L1 w0.127: R223.2@39.882,75.999 R222.1@39.882,76.599
NetR222_2: R222.2 R402.1 | length 0.7
  TOP_L1 w0.127: R222.2@39.882,77.149 R402.1@40.582,77.149
NetR227_1: R227.1 U22.E6 | length 3.2
  TOP_L1 w0.064: 74.329,57.254 74.329,57.754 U22.E6@74.575,58
  TOP_L1 w0.127: R227.1@73.275,55.465 73.275,56.4 74.026,57.151 74.226,57.151 74.329,57.254
NetR228_1: R228.1 U22.E5 | length 3.5
  TOP_L1 w0.064: U22.E5@74.575,58.5 74.821,58.254 74.821,57.246
  TOP_L1 w0.127: R228.1@73.875,55.465 73.875,56.3 74.821,57.246
NetR232_2: R232.2 R233.2 U20.7 | length 2
  TOP_L1 w0.127: U20.7@17.174,131.374 17.224,131.424 R233.2@18.439,131.424 R232.2@18.439,130.674
NetR234_1: R234.1 R236.2 | length 0.5
  BOTTOM_L10 w0.127: R236.2@89.503,92.272 R234.1@89.503,92.767
NetR235_2: R235.2 U33_5.3 | length 1.2
  BOTTOM_L10 w0.1: R235.2@82.703,98.747 83.006,98.444 83.157,98.444 83.253,98.347 U33_5.3@83.253,97.945
  BOTTOM_L10 w0.127: R235.2@82.703,98.829 R235.2@82.703,98.874
NetR236_1: R236.1 R244.2 | length 0.7
  BOTTOM_L10 w0.1: R236.1@89.503,91.672 R244.2@90.203,91.672
NetR237_2: R237.2 U33_5.4 | length 1
  BOTTOM_L10 w0.1: R237.2@83.353,98.747 83.564,98.536 83.753,98.347 U33_5.4@83.753,97.945
  BOTTOM_L10 w0.127: R237.2@83.353,98.829 R237.2@83.353,98.874
NetR239_1: R239.1 R240.1 R241.2 | length 1.4
  TOP_L1 w0.127: R241.2@0.9,114.79 R239.1@2.3,114.79
NetR239_2: R239.2 R240.2 U13.23 | length 3.9
  TOP_L1 w0.127: R240.2@1.6,115.34 R239.2@2.3,115.34 2.3,115.82 2.8,116.32 2.8,117.328 2.937,117.465 U13.23@3.725,117.465
NetR244_1: R244.1 R246.1 | length 0.9
  BOTTOM_L10 w0.127: R244.1@90.203,92.272 90.209,92.272 90.309,92.373 90.309,92.379 90.717,92.786 90.822,92.786 R246.1@90.903,92.867
NetR246_2: R246.2 R247.1 U30.4 | length 2.9
  BOTTOM_L10 w0.15: R247.1@90.903,92.222 91.275,92.222 91.407,92.354 91.407,93.195 91.185,93.417 R246.2@90.903,93.417 90.903,93.661 91.083,93.841 U30.4@91.083,94.268
NetR248_1: R248.1 R397.2 | length 0.8
  BOTTOM_L10 w0.127: R397.2@76.857,93.883 R248.1@77.657,93.883
NetR259_2: R259.2 R456.1 U31.2 | length 2.2
  TOP_L1 w0.127: U31.2@17.76,71.79 17.76,72.364 17.36,72.764 R456.1@17.36,73.02 R259.2@18.21,73.02
NetR260_2: R260.2 R263.1 U32.4 | length 2.4
  TOP_L1 w0.127: R263.1@17.36,76.71 17.686,76.71 17.76,76.636 17.76,76.42 17.92,76.26 18.26,76.26 ; U32.4@18.26,75.75 18.26,76.26 ; R260.2@18.71,76.71 18.26,76.26
NetR262_1: R262.1 U31.4 | length 1.1
  TOP_L1 w0.127: R262.1@16.81,69.35 17.26,69.8 U31.4@17.26,70.31
NetR264_1: R264.1 R455.1 U32.2 | length 3
  TOP_L1 w0.127: R264.1@16.16,72.521 R455.1@16.16,73.2 16.184,73.2 16.656,73.672 17.686,73.672 17.76,73.746 U32.2@17.76,74.27
NetR268_1: R268.1 U10_2.16 | length 2.1
  TOP_L1 w0.086: U10_2.16@63.682,138.491 63.682,138.05 63.741,137.991 R268.1@65.307,137.991
NetR271_1: R271.1 R367.2 U5.15 | length 1.8
  BOTTOM_L10 w0.1: R367.2@81.832,91.401 81.832,90.831 82.316,90.347 U5.15@82.853,90.347
NetR277_2: R277.2 U23.46 | length 1.7
  BOTTOM_L10 w0.127: R277.2@39.298,90.916 39.573,90.916 39.648,90.841 39.648,90.566 39.998,90.216 U23.46@40.573,90.216
NetR278_2: R278.2 U23.45 | length 1.4
  BOTTOM_L10 w0.127: R278.2@39.298,90.216 39.571,90.216 39.971,89.816 U23.45@40.573,89.816
NetR279_2: R279.2 U23.39 | length 1.6
  BOTTOM_L10 w0.127: R279.2@39.298,86.716 39.298,86.731 39.983,87.416 U23.39@40.573,87.416
NetR280_2: R280.2 U23.40 | length 1.4
  BOTTOM_L10 w0.127: R280.2@39.298,87.416 39.566,87.416 39.966,87.816 U23.40@40.573,87.816
NetR281_2: R281.2 U23.41 | length 1.3
  BOTTOM_L10 w0.127: R281.2@39.298,88.116 39.312,88.102 39.749,88.102 39.864,88.216 U23.41@40.573,88.216
NetR282_2: R282.2 U23.42 | length 1.4
  BOTTOM_L10 w0.127: R282.2@39.298,88.816 39.58,88.816 39.78,88.616 U23.42@40.573,88.616
NetR283_2: R283.2 U23.44 | length 1.3
  BOTTOM_L10 w0.127: R283.2@39.298,89.516 39.773,89.516 39.811,89.478 39.873,89.416 U23.44@40.573,89.416
NetR284_2: R284.2 U1.23 | length 2.5
  TOP_L1 w0.127: R284.2@67.3,12.625 67.306,12.625 67.407,12.524 67.407,12.518 68.099,11.826 68.764,11.826 68.881,11.71 U1.23@68.881,11.134
NetR285_2: R285.2 U1.22 | length 2.4
  TOP_L1 w0.127: R285.2@68,12.625 68,12.3 68.178,12.122 68.881,12.122 69.281,11.722 U1.22@69.281,11.134
NetR288_1: R288.1 U34.AR11 | length 2.3
  TOP_L1 w0.1: R288.1@38.136,38.674 38.522,38.289 39.011,38.289 39.189,38.11 39.566,38.11 39.832,37.844 39.832,37.578 U34.AR11@39.841,37.569
NetR289_1: R289.1 U34.AP12 | length 1.8
  TOP_L1 w0.1: U34.AP12@43.091,37.019 43.091,37.993 43.336,38.238 R289.1@43.336,38.674
NetR290_1: R290.1 U34.AR13 | length 2.2
  TOP_L1 w0.1: R290.1@38.786,38.674 38.801,38.674 38.987,38.489 39.093,38.489 39.272,38.31 39.649,38.31 39.885,38.075 40.111,38.075 40.341,37.844 U34.AR13@40.341,37.569
NetR291_2: R291.2 U34.N35 | length 2.6
  TOP_L1 w0.117: 36.058,31.183 36.473,31.599 U34.N35@36.871,31.599
  TOP_L1 w0.122: R291.2@34.623,30.666 34.638,30.666 35.155,31.183 36.058,31.183
NetR292_2: R292.2 U34.R35 | length 3.6
  TOP_L1 w0.117: 36.028,31.525 36.601,32.099 U34.R35@36.871,32.099
  TOP_L1 w0.122: R292.2@34.023,30.666 34.027,30.666 34.132,30.771 34.132,30.775 34.197,30.84 34.197,31.128 34.517,31.448 35.95,31.448 36.028,31.525
NetR303_1: R303.1 R308.2 U34.AR15 | length 1.8
  TOP_L1 w0.127: R308.2@40.086,38.674 R303.1@40.736,38.674 40.736,38.212 40.841,38.107 U34.AR15@40.841,37.569
NetR304_1: R304.1 R309.2 U34.AA1 | length 1.9
  TOP_L1 w0.1: U34.AA1@46.311,33.599 46.811,33.599 47.161,33.949 R304.1@47.411,33.949 R309.2@47.411,33.299
NetR310_1: R310.1 U34.AF2 | length 4.8
  TOP_L1 w0.1: U34.AF2@45.761,34.849 45.564,34.849 45.419,34.995 45.419,36.499 45.6,36.68 45.8,36.68 45.969,36.849 46.549,36.849 46.8,37.1 46.8,37.58 47.119,37.899 R310.1@47.411,37.899
NetR311_1: R311.1 U34.AG1 | length 2.1
  TOP_L1 w0.1: U34.AG1@46.311,35.099 46.586,35.099 46.764,35.276 46.764,35.281 46.836,35.354 46.836,35.592 47.034,35.789 47.034,36.156 47.411,36.534 R311.1@47.411,36.549
NetR312_2: R312.2 R471.1 U12.28 | length 3.6
  BOTTOM_L10 w0.127: R312.2@25.7,30.41 25.7,30.029 25.812,29.917 26.4,29.917 ; R471.1@26.4,30.41 26.4,29.917 ; U12.28@26.65,28.01 26.65,29.166 26.4,29.416 26.4,29.917
NetR313_2: R313.2 U12.63 | length 3.4
  BOTTOM_L10 w0.127: U12.63@19.65,16.81 19.65,16.06 20.5,15.21 20.9,15.21 21.3,14.81 R313.2@21.3,14.31
NetR315_2: R315.2 U21_4.5 | length 1.4
  TOP_L1 w0.127: R315.2@45.8,75.016 45.8,74.739 46.25,74.289 U21_4.5@46.25,73.841
NetR316_2: R316.2 U12.75 | length 2.6
  BOTTOM_L10 w0.127: U12.75@13.65,16.81 13.65,15.66 13.9,15.41 R316.2@13.9,14.31
NetR318_2: R318.2 U24.B2 | length 0.8
  TOP_L1 w0.2: v1(77.816,30.374) U24.B2@78.241,30.374
  BOTTOM_L10 w0.127: R318.2@77.416,30.374 v1(77.816,30.374)
  other v2: 77.816,30.374
  other v3: 77.816,30.374
  other v4: 77.816,30.374
  other v5: 77.816,30.374
NetR323_2: R323.2 U21_4.7 | length 1.4
  TOP_L1 w0.127: R323.2@45.7,71.412 45.7,71.674 45.814,71.788 46.119,71.788 46.25,71.919 U21_4.7@46.25,72.441
NetR324_2: R324.2 U33_5.9 | length 1.1
  BOTTOM_L10 w0.1: U33_5.9@86.253,97.945 86.253,98.322 86.603,98.672 R324.2@86.603,98.874
NetR325_1: R325.1 U33_5.12 | length 1.1
  BOTTOM_L10 w0.127: U33_5.12@86.253,95.645 86.253,95.239 86.603,94.889 R325.1@86.603,94.647
NetR336_2: R336.2 U27_4.1 | length 1.5
  TOP_L1 w0.127: U27_4.1@11.868,71.686 11.868,72.278 12.041,72.451 12.178,72.451 12.393,72.666 R336.2@12.393,72.936
NetR337_2: R337.2 U27_3.1 | length 1.6
  TOP_L1 w0.127: R337.2@1.765,79.944 2.251,79.944 2.4,79.795 2.4,79.584 2.565,79.419 U27_3.1@3.015,79.419
NetR338_2: R338.2 R339.1 | length 0.7
  TOP_L1 w0.127: R338.2@9.768,73.511 R339.1@10.468,73.511
NetR339_2: R339.2 U27_4.4 | length 1.4
  TOP_L1 w0.127: R339.2@10.468,72.961 10.468,72.523 10.668,72.323 U27_4.4@10.668,71.686
NetR340_2: R340.2 R341.1 | length 0.7
  TOP_L1 w0.127: R340.2@1.19,77.319 R341.1@1.19,78.019
NetR341_2: R341.2 U27_3.4 | length 1.4
  TOP_L1 w0.127: R341.2@1.74,78.019 2.272,78.019 2.472,78.219 U27_3.4@3.015,78.219
NetR342_2: R342.2 U27_1.4 | length 1.1
  BOTTOM_L10 w0.127: U27_1.4@75.181,16.259 75.181,16.798 75.316,16.933 R342.2@75.316,17.293
NetR343_2: R343.2 U12.58 | length 5.2
  BOTTOM_L10 w0.122: U12.58@22.15,16.81 22.15,15.66 22.86,14.95 25.16,14.95 25.5,14.61 R343.2@25.5,14.31
NetR344_2: R344.2 R348.2 U12.59 | length 4.9
  BOTTOM_L10 w0.127: U12.59@21.65,16.81 21.65,15.668 22.632,14.686 23.177,14.686 23.554,14.31 R348.2@24.1,14.31 R344.2@24.8,14.31
NetR345_2: R345.2 R347.2 U12.60 | length 6.5
  BOTTOM_L10 w0.109: U12.60@21.15,16.81 21.15,15.86 22.6,14.41 23,14.41 23.25,14.16 R345.2@23.25,13.76 23.25,13.26 23.95,12.56 R347.2@24.8,12.56
NetR349_2: R349.2 R402.2 U36.2 | length 65.4
  TOP_L1 w0.127: R349.2@0.875,101.816 1.443,101.816 v2(2.138,101.12) ; v1(21.08,79.34) 21.096,79.356 30.524,79.356 30.578,79.302 39.965,79.302 40.003,79.34 40.518,79.34 41.58,78.278 41.58,76.599 41.58,75.44 42.762,74.258 U36.2@42.762,73.513 ; R402.2@40.582,76.599 41.568,76.599 41.58,76.587
  L3 w0.127: v2(2.138,101.12) 2.138,99.117 2.794,98.461 2.794,93.806 3.671,92.929 3.671,91.98 3.671,91.779 4.173,91.278 4.373,91.278 4.451,91.278 7.178,88.55 7.178,88.473 7.181,88.47 7.181,83.424 8.305,82.3 8.305,80.635 9.044,79.897 15.244,79.897 15.908,79.234 17.343,79.234 17.45,79.34 v1(21.08,79.34)
  other v1: 2.138,101.12
  other v2: 21.08,79.34
NetR350_2: R350.2 R489.2 U4.6 U19.2 | length 10.3
  TOP_L1 w0.127: R489.2@33.266,73.048 33.713,73.048 33.833,72.928 34.655,72.928 34.73,73.002 34.73,73.511 U19.2@34.732,73.513 34.732,74.492 35.514,75.274 v2(37.634,75.274) ; R489.2@33.266,73.145 R350.2@33.266,73.848 ; U4.6@38.532,76.849 v1(39.271,76.849)
  L3 w0.127: v2(37.634,75.274) 38.277,75.274 39.271,76.269 v1(39.271,76.849)
  other v1: 37.634,75.274
  other v2: 39.271,76.849
NetR353_2: R353.2 U12.61 | length 3.1
  BOTTOM_L10 w0.127: U12.61@20.65,16.81 20.65,15.96 22,14.61 R353.2@22,14.31
NetR354_2: R354.2 U11.19 | length 1.5
  TOP_L1 w0.127: R354.2@2.375,108.515 2.637,108.515 2.987,108.165 U11.19@3.725,108.165
NetR355_2: R355.2 U13.19 | length 1.5
  TOP_L1 w0.127: R355.2@2.375,119.865 2.65,119.865 3.05,119.465 U13.19@3.725,119.465
NetR360_2: R360.2 U13.16 | length 5.2
  TOP_L1 w0.127: R360.2@1,121.278 1,121.629 1.063,121.693 2.688,121.693 3.193,121.188 4.609,121.188 4.9,120.897 U13.16@4.9,120.315
NetR361_1: R361.1 U21_2.2 | length 1.2
  TOP_L1 w0.127: U21_2.2@52.389,73.869 52.389,74.594 52.439,74.644 R361.1@52.439,75.016
NetR362_1: R362.1 U21_2.3 | length 1.2
  TOP_L1 w0.127: R362.1@51.789,75.016 51.789,74.644 51.989,74.444 U21_2.3@51.989,73.869
NetR363_1: R363.1 U21_2.4 | length 1.3
  TOP_L1 w0.127: R363.1@51.139,75.016 51.139,74.761 51.581,74.319 51.581,73.877 U21_2.4@51.589,73.869
NetR364_1: R364.1 U21_2.5 | length 1.6
  TOP_L1 w0.127: R364.1@50.489,75.016 50.489,74.926 50.489,74.761 50.695,74.555 50.911,74.555 51.189,74.277 U21_2.5@51.189,73.869
NetR368_2: R368.2 U5.17 | length 3.5
  BOTTOM_L10 w0.1: R368.2@80.753,92.772 81.258,92.267 83.391,92.267 83.503,92.156 U5.17@83.503,91.697
NetR369_1: R369.1
NetR369_2: R369.2 U5.14 | length 1.1
  BOTTOM_L10 w0.1: R369.2@81.824,90.112 81.825,90.111 82.078,90.111 82.242,89.947 U5.14@82.853,89.947
NetR370_1: R370.1
NetR370_2: R370.2 U5.16 | length 2.1
  BOTTOM_L10 w0.1: R370.2@81.824,91.912 82.256,91.912 82.266,91.902 82.266,90.856 82.375,90.747 U5.16@82.853,90.747
NetR377_2: R377.2 U12.55 | length 5.8
  BOTTOM_L10 w0.122: U12.55@23.65,16.81 23.65,16.148 24.032,15.766 26.844,15.766 27.6,15.01 R377.2@27.6,14.31
NetR378_2: R378.2 U12.56 | length 5.7
  BOTTOM_L10 w0.122: U12.56@23.15,16.81 23.15,15.86 23.52,15.49 26.32,15.49 26.9,14.91 R378.2@26.9,14.31
NetR379_2: R379.2 U12.54 | length 6.1
  BOTTOM_L10 w0.122: U12.54@24.15,16.81 24.15,16.16 24.308,16.002 27.508,16.002 28.3,15.21 R379.2@28.3,14.31
NetR380_2: R380.2 U12.57 | length 5.4
  BOTTOM_L10 w0.122: U12.57@22.65,16.81 22.65,15.76 23.185,15.225 25.565,15.225 26.2,14.59 R380.2@26.2,14.31
NetR381_2: R381.2 U12.53 | length 6.3
  BOTTOM_L10 w0.122: U12.53@24.65,16.81 24.65,16.339 24.757,16.232 28.178,16.232 29,15.41 R381.2@29,14.31
NetR382_2: R382.2 U3.G15 | length 138.2
  TOP_L1 w0.109: R382.2@81.189,83.211 81.188,82.933 81.79,82.33 v1@81.94,82.33
  L3 w0.104: v5(56.612,4.79) 56.612,4.779 56.81,4.581 56.81,4.2 57.053,3.957 57.301,3.957 85.187,3.957 86.714,5.484 86.714,14.868 87.488,15.642 91.069,15.642 93.314,17.888 93.314,26.053 96.414,29.153 96.414,71.614 96.7,71.9 98.231,71.9 98.896,72.565 98.896,76.18 96.416,78.66 96.416,80.667 92.878,84.205 85.206,84.205 83.265,82.264 82.075,82.264 82.007,82.332 v2(81.967,82.332)
  BOTTOM_L10 w0.109: v5(56.612,4.79) 56.612,4.819 56.81,5.017 56.81,7.816 57.41,8.416 57.41,8.731 U3.G15@57.162,8.979
  other v1: 81.967,82.332
  other v3: 56.612,4.79
  other v4: 56.612,4.79
NetR383_2: R383.2 U3.H15 | length 136.9
  TOP_L1 w0.109: R383.2@80.695,82.717 80.973,82.717 v1@81.662,82.027
  L3 w0.104: v4(57.312,4.79) 57.312,4.779 57.114,4.581 57.114,4.326 57.179,4.261 85.061,4.261 86.41,5.61 86.41,14.995 87.362,15.947 90.942,15.947 93.01,18.014 93.01,26.179 93.188,26.358 96.11,29.279 96.11,71.741 96.574,72.205 98.105,72.205 98.591,72.691 98.591,76.054 96.111,78.533 96.111,80.541 92.752,83.9 85.332,83.9 83.429,81.997 81.84,81.997 81.816,82.022 81.712,82.022 v1(81.684,82.049)
  BOTTOM_L10 w0.109: v4(57.312,4.79) 57.312,4.819 57.114,5.017 57.116,5.018 57.116,7.69 57.714,8.289 57.714,8.731 U3.H15@57.962,8.979
  other v2: 81.684,82.049
  other v3: 57.312,4.79
  other v5: 57.312,4.79
NetR384_2: R384.2 U3.J5 | length 13.5
  BOTTOM_L10 w0.127: R384.2@49.531,11.649 50.983,11.649 51.863,12.529 54.877,12.529 55.163,12.815 55.163,14.978 55.205,15.02 55.205,15.208 55.163,15.25 55.163,16.243 55.445,16.525 58.359,16.525 U3.J5@58.763,16.929
NetR385_2: R385.2 U3.B6 | length 3.9
  BOTTOM_L10 w0.127: R385.2@49.486,16.749 50.043,16.749 50.243,16.549 52.708,16.549 53.128,16.129 U3.B6@53.163,16.129
NetR386_2: R386.2 U10_1.2 | length 3.3
  TOP_L1 w0.127: R386.2@42.734,138.266 42.734,137.952 42.895,137.791 44.932,137.791 45.082,137.941 U10_1.2@45.082,138.491
NetR388_2: R388.2 U12.3 | length 4
  BOTTOM_L10 w0.127: R388.2@13.2,30.41 12.93,30.41 12.7,30.18 12.7,29 13.025,28.675 14.038,28.675 14.15,28.564 U12.3@14.15,28.01
NetR392_1: R392.1 U10_1.16 | length 11.5
  TOP_L1 w0.127: R392.1@42.051,138.234 42.051,137.774 42.259,137.567 42.455,137.567 v5(42.478,137.543)
  L8 w0.127: v5(42.478,137.543) 42.514,137.507 51.937,137.507 52.085,137.656 v5(52.085,138.458)
  other v1: 42.478,137.543 52.085,138.458
  other v2: 42.478,137.543 52.085,138.458
NetR393_1: R393.1 U10_3.2 | length 2.3
  TOP_L1 w0.127: R393.1@66.551,137.734 67.993,137.734 68.282,138.023 U10_3.2@68.282,138.491
NetR394_1: R394.1 U10_3.16 | length 4.4
  TOP_L1 w0.127: U10_3.16@75.282,138.491 75.282,137.994 75.44,137.836 76.177,137.836 77.604,136.409 R394.1@78.551,136.409
NetR395_1: R395.1 U21_3.7 | length 1.4
  TOP_L1 w0.084: U21_3.7@11.886,148.975 11.886,149.53 12.081,149.725 12.174,149.725 12.336,149.888 R395.1@12.336,150.15
NetR396_2: R396.2 U21_3.5 | length 1.1
  TOP_L1 w0.084: U21_3.5@11.886,147.575 11.886,147.123 R396.2@12.336,146.673
NetR397_1: R397.1 R472.2 | length 0.8
  BOTTOM_L10 w0.127: R472.2@76.057,93.333 R397.1@76.857,93.333
NetR404_2: R404.2 R420.2 R421.1 R426.2 U13.22 | length 4
  TOP_L1 w0.127: R404.2@1.775,116.24 1.775,116.259 1.975,116.459 1.975,117.165 1.975,117.191 1.7,117.466 R421.1@1.7,117.99 R426.2@2.4,117.99 ; R426.2@2.4,117.965 U13.22@3.725,117.965
NetR427_2: R427.2 U12.76 | length 2.5
  BOTTOM_L10 w0.127: U12.76@13.15,16.81 13.15,16.26 13.2,16.21 R427.2@13.2,14.31
NetR428_2: R428.2 U21_5.7 | length 1.5
  BOTTOM_L10 w0.127: R428.2@29.6,30.895 29.6,30.522 29.712,30.41 29.975,30.41 30.1,30.285 U21_5.7@30.1,29.77
NetR429_2: R429.2 U21_5.5 | length 1.1
  BOTTOM_L10 w0.127: R429.2@29.9,27.37 29.9,27.685 30.1,27.885 U21_5.5@30.1,28.37
NetR430_2: R430.2 U36.4 | length 1.1
  TOP_L1 w0.15: R430.2@41.262,72.363 41.55,72.363 41.88,72.033 U36.4@42.262,72.033
NetR438_2: R438.2 U12.44 | length 3.5
  BOTTOM_L10 w0.122: U12.44@27.5,19.66 28.216,19.66 29,18.876 29,18.41 29.4,18.01 R438.2@30,18.01
NetR439_2: R439.2 R471.2 U12.45 | length 22.2
  L8 w0.127: v4(24.969,28.615) 24.969,28.62 25.195,28.846 25.434,28.846 25.547,28.733 25.56,28.733 25.637,28.657 25.637,25.573 26.2,25.01 26.2,20.41 27.1,19.51 27.701,19.51 v4(28.373,18.838)
  BOTTOM_L10 w0.127: v4(24.969,28.615) 24.969,28.641 23.7,29.91 23.7,31.198 24.112,31.61 26.288,31.61 26.4,31.498 R471.2@26.4,30.96 ; U12.45@27.5,19.16 28.075,19.16 28.7,18.535 28.7,18.11 29.5,17.31 R439.2@30,17.31
  other v3: 28.373,18.838 24.969,28.615
NetR440_2: R440.2 U12.27 | length 3.1
  BOTTOM_L10 w0.127: R440.2@25,30.41 25,29.824 25.414,29.41 25.8,29.41 26.15,29.06 U12.27@26.15,28.01
NetR441_2: R441.2 U12.42 | length 3
  BOTTOM_L10 w0.122: U12.42@27.5,20.66 28.25,20.66 29.5,19.41 R441.2@30,19.41
NetR442_2: R442.2 U12.43 | length 3.1
  BOTTOM_L10 w0.122: U12.43@27.5,20.16 28.211,20.16 29.661,18.71 R442.2@30,18.71
NetR443_2: R443.2 U12.12 | length 2.5
  BOTTOM_L10 w0.1: R443.2@18.4,30.41 18.4,29.41 18.65,29.16 U12.12@18.65,28.01
NetR444_2: R444.2 U12.11 | length 2.6
  BOTTOM_L10 w0.1: R444.2@17.7,30.41 17.7,29.41 18.15,28.96 U12.11@18.15,28.01
NetR445_2: R445.2 U12.19 | length 2.4
  BOTTOM_L10 w0.1: U12.19@22.15,28.01 22.15,29.231 22.2,29.281 R445.2@22.2,30.41
NetR446_2: R446.2 U12.18 | length 2.5
  BOTTOM_L10 w0.1: R446.2@21.49,30.427 21.49,29.405 21.65,29.245 U12.18@21.65,28.01
NetR447_2: R447.2 U12.7 | length 2.5
  BOTTOM_L10 w0.1: U12.7@16.15,28.01 16.15,28.76 16.3,28.91 R447.2@16.3,30.41
NetR448_2: R448.2 U12.8 | length 2.5
  BOTTOM_L10 w0.1: U12.8@16.65,28.01 16.65,28.809 17,29.159 R448.2@17,30.41
NetR461_2: R461.2 U21_5.4 | length 1
  BOTTOM_L10 w0.127: U21_5.4@30.5,28.37 30.5,27.77 30.6,27.67 R461.2@30.6,27.37
NetR462_2: R462.2 U12.29 | length 4.1
  BOTTOM_L10 w0.127: R462.2@27.1,30.41 27.1,29.61 28.053,28.657 28.053,27.244 27.969,27.16 U12.29@27.5,27.16
NetR463_2: R463.2 U21_5.9 U34.AN35 | length 10.6
  TOP_L1 w0.127: v1(36.386,36.567) 36.417,36.599 U34.AN35@36.871,36.599
  BOTTOM_L10 w0.127: U21_5.9@30.9,29.77 30.9,30.393 31,30.493 R463.2@31,30.895 31.006,30.895 31.107,30.996 31.107,31.001 31.362,31.256 31.362,31.802 31.8,32.24 31.8,33.672 34.337,36.209 36.027,36.209 v1(36.386,36.567)
  other v2: 36.386,36.567
  other v3: 36.386,36.567
  other v4: 36.386,36.567
  other v5: 36.386,36.567
NetR464_2: R464.2 R467.2 U21_5.10 U34.G1 | length 31.6
  TOP_L1 w0.1: v5(44.964,36.413) 44.964,36.038 45.154,35.849 45.154,34.875 45.116,34.838 45.116,30.483 45.501,30.099 U34.G1@46.311,30.099
  L8 w0.1: v4(44.437,35.794) 44.749,36.105 44.749,36.198 v5(44.964,36.413)
  BOTTOM_L10 w0.127: U21_5.10@31.3,29.77 31.3,30.495 31.594,30.788 31.599,30.788 31.7,30.889 R464.2@31.7,31.595 ; R464.2@31.664,31.621 31.702,31.621 31.781,31.7 31.781,31.737 32.048,32.005 32.048,33.599 34.174,35.725 36.497,35.725 37.324,36.552 37.324,39.917 37.641,40.233 38.758,40.233 39.107,39.884 39.107,39.344 39.766,38.685 40.364,38.685 43.236,35.813 44.418,35.813 v4(44.437,35.794)
  other v1: 44.964,36.413
  other v2: 44.964,36.413
  other v3: 44.437,35.794
NetR465_1: R465.1 R466.2 U12.31 U21_5.2 | length 5.9
  BOTTOM_L10 w0.127: U12.31@27.5,26.16 30.953,26.16 31.304,26.511 31.31,26.511 31.4,26.601 R466.2@31.4,26.607 R465.1@31.4,27.307 31.4,27.67 31.3,27.77 U21_5.2@31.3,28.37
NetR469_1: R469.1 U12.69 | length 2.9
  BOTTOM_L10 w0.127: U12.69@16.65,16.81 16.65,15.96 17.7,14.91 R469.1@17.7,14.31
NetR470_1: R470.1 U12.70 | length 2.9
  BOTTOM_L10 w0.127: U12.70@16.15,16.81 16.15,15.981 17,15.131 R470.1@17,14.31
NetR480_1: R480.1 U13.3 | length 8.3
  TOP_L1 w0.127: v2(3.714,110.262) 3.747,110.262 3.85,110.365 R480.1@4.15,110.365 ; v2(4.9,115.935) U13.3@4.9,116.615
  L3 w0.127: v5(4.455,115.98) 4.478,115.957 4.878,115.957 v2(4.9,115.935)
  L8 w0.127: v2(3.714,110.262) 3.692,110.284 3.692,112.815 3.455,113.052 3.455,115.68 3.755,115.98 v5(4.455,115.98)
  other v1: 3.714,110.262 4.9,115.935
  other v5: 3.714,110.262
NetR480_2: R480.2 U11.16 | length 1.5
  TOP_L1 w0.127: R480.2@4.667,110.461 4.667,110.379 4.9,110.147 U11.16@4.9,109.015
NetR490_1: R490.1 R492.1 R493.1 | length 2.6
  BOTTOM_L10 w0.15: R492.1@85.345,68.575 R490.1@86.245,68.575 86.245,69.343 86.113,69.475 R493.1@85.345,69.475
NetR491_1: R491.1 R494.1 R495.1 | length 2.7
  BOTTOM_L10 w0.15: R495.1@84.145,51.475 84.145,51.207 84.277,51.075 85.322,51.075 85.445,51.198 R494.1@85.445,51.475 R491.1@86.145,51.475
NetR499_2: R499.2 U26.6 | length 1
  BOTTOM_L10 w0.15: U26.6@81,140 R499.2@81,141
NetTP2_X: TP2.X U6.22 | length 2.2
  TOP_L1 w0.127: v5(81.102,74.994) 81.348,74.994 81.9,75.545 U6.22@81.9,75.99
  BOTTOM_L10 w0.127: TP2.X@80.401,75.181 80.565,75.017 81.079,75.017 v5(81.102,74.994)
  other v1: 81.102,74.994
  other v2: 81.102,74.994
  other v3: 81.102,74.994
  other v4: 81.102,74.994
NetTP3_X: TP3.X U6.19 | length 3.3
  TOP_L1 w0.127: v5(79.501,76.536) 79.83,76.865 U6.19@81.125,76.865
  BOTTOM_L10 w0.127: v5(79.501,76.536) 79.501,76.821 TP3.X@80.401,77.721
  other v1: 79.501,76.536
  other v2: 79.501,76.536
  other v3: 79.501,76.536
  other v4: 79.501,76.536
NetTP4_X: TP4.X U6.21 | length 4.4
  TOP_L1 w0.127: v2(78.652,74.994) 79.06,75.402 81.237,75.402 81.5,75.665 U6.21@81.5,75.99
  L3 w0.127: v2(78.652,74.994) v5(78.676,74.994)
  BOTTOM_L10 w0.127: TP4.X@77.861,75.181 78.024,75.018 78.653,75.018 v5(78.676,74.994)
  other v1: 78.652,74.994
  other v3: 78.676,74.994
  other v4: 78.676,74.994
NetTP5_X: TP5.X U6.20 | length 4.9
  TOP_L1 w0.127: v5(78.001,76.136) 79.04,76.136 79.068,76.108 80.073,76.108 80.43,76.465 U6.20@81.125,76.465
  BOTTOM_L10 w0.127: TP5.X@77.861,77.721 77.978,77.605 77.978,76.16 v5(78.001,76.136)
  other v1: 78.001,76.136
  other v2: 78.001,76.136
  other v3: 78.001,76.136
  other v4: 78.001,76.136
NetTP6_X: TP6.X U24.A32 | length 7.9
  TOP_L1 w0.127: v2(69.522,33.46) 69.533,33.449 U24.A32@70.091,33.449
  L3 w0.127: v5(69.14,33.54) 69.171,33.509 69.44,33.509 69.488,33.46 v2(69.522,33.46)
  L8 w0.127: v4(68.793,33.299) 68.826,33.299 69.067,33.54 v5(69.14,33.54)
  BOTTOM_L10 w0.127: TP6.X@64.77,29.21 65.976,30.416 67.246,30.416 68.793,31.963 v4(68.793,33.299)
  other v1: 69.522,33.46
  other v3: 68.793,33.299
NetTP7_X: TP7.X U24.A35 | length 3.7
  TOP_L1 w0.127: v5(69.34,31.44) 69.549,31.649 U24.A35@70.091,31.649
  L8 w0.127: v4(68.828,31.462) 68.839,31.451 69.329,31.451 v5(69.34,31.44)
  BOTTOM_L10 w0.127: TP7.X@68.58,29.21 68.58,30.58 68.829,30.829 v3@68.829,31.461
  other v1: 69.34,31.44
  other v2: 69.34,31.44
  other v3: 68.828,31.462
NetTP8_X: TP8.X U24.B31 | length 7.7
  L3 w0.127: v5(70.493,32.758) 70.567,32.758 70.727,32.598 70.918,32.598 v1(70.941,32.574)
  L8 w0.127: v3(68.14,37.04) 68.14,36.661 70.677,34.124 70.677,33.57 70.493,33.386 v5(70.493,32.758)
  BOTTOM_L10 w0.127: v3(68.14,37.04) 69.64,37.04 TP8.X@69.85,36.83
  other v2: 70.941,32.574
  other v4: 68.14,37.04
NetTP9_X: TP9.X U24.B30 | length 2.8
  TOP_L1 w0.127: U24.B30@70.941,33.124 71.324,33.124 v5(71.54,33.34)
  BOTTOM_L10 w0.127: TP9.X@69.85,34.29 70.8,33.34 v5(71.54,33.34)
  other v1: 71.54,33.34
  other v2: 71.54,33.34
  other v3: 71.54,33.34
  other v4: 71.54,33.34
NetTP10_X: TP10.X U24.B32 | length 1.3
  TOP_L1 w0.127: v2(70.836,32.025) U24.B32@70.941,32.024
  L3 w0.127: v5(70.366,32.103) 70.44,32.103 70.518,32.025 v2(70.836,32.025)
  BOTTOM_L10 w0.127: TP10.X@69.85,31.75 69.98,31.75 70.333,32.103 v5(70.366,32.103)
  other v1: 70.836,32.025
  other v3: 70.366,32.103
  other v4: 70.366,32.103
NetTP11_X: TP11.X U24.A15 | length 3.1
  TOP_L1 w0.1: U24.A15@77.591,37.349 77.591,37.525 77.933,37.867 v1(77.933,37.869)
  L3 w0.1: v5(77.84,38.74) 77.84,38.709 77.581,38.451 77.581,37.958 77.671,37.869 v1(77.933,37.869)
  BOTTOM_L10 w0.1: v5(77.84,38.74) 77.881,38.74 78.511,39.37 TP11.X@78.74,39.37
  other v2: 77.933,37.869
  other v3: 77.84,38.74
  other v4: 77.84,38.74
NetTP12_X: TP12.X U24.B3 | length 2.7
  TOP_L1 w0.127: v2(77.82,30.92) v5(77.822,30.922) 78.24,30.922 U24.B3@78.241,30.924
  L3 w0.127: v2(77.82,30.92) v5(77.822,30.922)
  BOTTOM_L10 w0.127: v5(77.822,30.922) 77.822,30.953 78.254,31.385 78.254,32.385 TP12.X@77.823,32.816
  other v1: 77.82,30.92
  other v3: 77.822,30.922
  other v4: 77.822,30.922
NetTP13_X: TP13.X U34.AL35 | length 4.4
  TOP_L1 w0.127: v2(36.072,36.281) 36.078,36.281 36.26,36.099 U34.AL35@36.871,36.099
  L3 w0.127: v2(36.072,36.281) 36.072,36.314 35.96,36.426 35.96,37.357 36.128,37.526 v5(36.128,38.525)
  BOTTOM_L10 w0.127: TP13.X@35.56,39.37 35.76,39.37 36.128,39.002 v5(36.128,38.525)
  other v1: 36.072,36.281
  other v3: 36.128,38.525
  other v4: 36.128,38.525
NetTP14_X: TP14.X U34.AH34 | length 4.2
  TOP_L1 w0.127: U34.AH34@37.421,35.349 37.699,35.349 37.845,35.495 37.845,36.673 v2(37.841,36.676)
  L3 w0.127: v3(36.936,37.135) 37.394,36.676 v2(37.841,36.676)
  BOTTOM_L10 w0.127: TP14.X@35.56,37.03 35.641,37.111 36.912,37.111 v3(36.936,37.135)
  other v1: 37.841,36.676
  other v4: 36.936,37.135
  other v5: 36.936,37.135
NetTP15_X: TP15.X U34.J35 | length 7.5
  TOP_L1 w0.127: v2(36.387,30.623) 36.398,30.613 36.858,30.613 U34.J35@36.871,30.599
  L3 w0.127: v3(31.338,32.7) 33.342,32.7 34.896,31.146 36.198,31.146 36.387,30.956 v2(36.387,30.623)
  BOTTOM_L10 w0.127: TP15.X@30.48,32.68 30.49,32.69 31.328,32.69 v3(31.338,32.7)
  other v1: 36.387,30.623
  other v4: 31.338,32.7
  other v5: 31.338,32.7
NetTP16_X: TP16.X U34.K34 | length 7
  TOP_L1 w0.127: U34.K34@37.421,30.849 v1(37.724,30.849)
  L3 w0.127: v5(33.057,31.477) 34.317,30.217 36.389,30.217 37.022,30.849 v1(37.724,30.849)
  BOTTOM_L10 w0.127: TP16.X@33.02,32.68 33.057,32.643 v5(33.057,31.477)
  other v2: 37.724,30.849
  other v3: 33.057,31.477
  other v4: 33.057,31.477
NetTP17_X: TP17.X U34.L35 | length 18.8
  TOP_L1 w0.127: v2(36.079,30.857) 36.319,31.098 36.87,31.098 U34.L35@36.871,31.099
  L3 w0.127: v4(29.139,32.024) 29.451,32.335 33.386,32.335 34.863,30.857 v2(36.079,30.857)
  BOTTOM_L10 w0.127: TP17.X@20.32,32.68 21.031,31.969 23.169,31.969 24.543,33.343 25.675,33.343 25.821,33.197 26.098,33.197 27.1,32.195 27.487,32.195 27.687,31.995 28.364,31.995 28.393,32.024 v4(29.139,32.024)
  other v1: 36.079,30.857
  other v3: 29.139,32.024
  other v5: 29.139,32.024
NetTP18_X: TP18.X U34.G35 | length 16.3
  TOP_L1 w0.127: v2(36.281,29.247) 36.281,29.853 36.527,30.099 U34.G35@36.871,30.099
  L3 w0.127: v3(29.593,33.277) 30.644,33.277 30.658,33.29 33.394,33.29 35.084,31.6 37.761,31.6 38.239,31.122 38.239,30.435 37.864,30.061 36.842,30.061 36.574,29.793 36.574,29.54 v2(36.281,29.247)
  BOTTOM_L10 w0.127: TP18.X@27.94,32.68 28.55,32.68 28.598,32.631 29.305,32.631 29.593,32.92 v3(29.593,33.277)
  other v1: 36.281,29.247
  other v4: 29.593,33.277
  other v5: 29.593,33.277
NetTP19_X: TP19.X U34.AP8 | length 11.8
  TOP_L1 w0.1: v3(40.593,40.478) 43.592,40.478 44.091,39.979 U34.AP8@44.091,37.019
  L3 w0.1: v3(40.593,40.478) v5(40.602,40.487)
  L8 w0.1: v3(40.593,40.478) v5(40.602,40.487)
  BOTTOM_L10 w0.1: v3(40.593,40.478) 40.985,40.478 41.44,40.023 41.44,38.129 42.539,37.03 TP19.X@43.145,37.03
  other v1: 40.593,40.478
  other v2: 40.593,40.478
  other v4: 40.593,40.478
NetTP20_X: TP20.X U34.AR5 | length 4.7
  TOP_L1 w0.1: v5(37.633,38.241) 37.913,37.961 38.224,37.961 38.341,37.844 U34.AR5@38.341,37.569
  BOTTOM_L10 w0.1: v5(37.633,38.241) 37.636,38.244 38.636,38.244 39.85,37.03 TP20.X@40.64,37.03
  other v1: 37.633,38.241
  other v2: 37.633,38.241
  other v3: 37.633,38.241
  other v4: 37.633,38.241
NetTP21_X: TP21.X U34.AR7 | length 1.7
  TOP_L1 w0.1: v2(38.814,37.814) 38.841,37.786 U34.AR7@38.841,37.569
  L8 w0.1: v3(38.197,37.794) 38.207,37.804 38.804,37.804 v2(38.814,37.814)
  BOTTOM_L10 w0.1: TP21.X@38.1,37.03 38.197,37.127 v3(38.197,37.794)
  other v1: 38.814,37.814
  other v4: 38.197,37.794
  other v5: 38.814,37.814
NetTP22_X: TP22.X U34.AP10 | length 7.2
  TOP_L1 w0.1: 43.591,37.313 43.591,37.825
  TOP_L1 w0.127: v1(40.176,40.075) 40.281,40.18 43.2,40.18 43.67,39.71 43.67,38.386 43.591,38.308 43.591,37.825 ; U34.AP10@43.591,37.019 43.591,37.313
  BOTTOM_L10 w0.127: v1(40.176,40.075) 40.176,40.055 40.64,39.591 TP22.X@40.64,39.57
  other v2: 40.176,40.075
  other v3: 40.176,40.075
  other v4: 40.176,40.075
  other v5: 40.176,40.075
NetTP23_X: TP23.X U34.AR9 | length 2.4
  TOP_L1 w0.127: U34.AR9@39.341,37.569 39.344,37.571 39.344,37.833 v1(39.346,37.835)
  BOTTOM_L10 w0.127: TP23.X@38.1,39.57 39.357,38.313 v5(39.357,37.931)
  other v2: 39.346,37.835
  other v3: 39.357,37.931
  other v4: 39.357,37.931
NetTP40_X: TP40.X U1.44 | length 7
  TOP_L1 w0.1: v2(65.24,2.154) 65.62,2.534 65.62,3.05 66.354,3.784 67.028,3.784 67.029,3.785 67.164,3.785 67.281,3.902 U1.44@67.281,4.384
  L3 w0.1: v2(65.24,2.154) 67.74,2.154 67.84,2.054 68.102,2.054 v5(68.14,2.016)
  L8 w0.1: v5(68.14,2.016) 68.143,2.016 68.457,2.33 v3(68.46,2.33)
  other v1: 65.24,2.154
  other v4: 68.46,2.33
NetTP41_X: TP41.X U1.30 | length 7.2
  TOP_L1 w0.127: U1.30@66.106,9.959 66.856,9.959 67.184,10.288 v5(67.835,10.288)
  BOTTOM_L10 w0.127: v5(67.835,10.288) 67.851,10.304 67.851,11.502 68.423,12.075 68.423,13.512 TP41.X@69.71,14.798
  other v1: 67.835,10.288
  other v2: 67.835,10.288
  other v3: 67.835,10.288
  other v4: 67.835,10.288
NetTP42_X: TP42.X U1.24 | length 4.1
  TOP_L1 w0.127: U1.24@68.481,11.134 68.481,10.41 68.839,10.052 68.839,9.943 v5(68.862,9.919)
  BOTTOM_L10 w0.127: v5(68.862,9.919) 68.862,10.333 68.808,10.387 68.808,10.659 69.236,11.087 69.236,11.785 TP42.X@69.71,12.258
  other v1: 68.862,9.919
  other v2: 68.862,9.919
  other v3: 68.862,9.919
  other v4: 68.862,9.919
NetTP43_X: TP43.X U1.25 | length 8.6
  TOP_L1 w0.127: U1.25@68.081,11.134 68.081,10.489 68.37,10.2 v5(68.37,9.817)
  BOTTOM_L10 w0.127: v5(68.37,9.817) 68.37,10.722 68.95,11.301 68.95,12.757 69.299,13.106 70.605,13.106 71.452,12.258 TP43.X@72.45,12.258
  other v1: 68.37,9.817
  other v2: 68.37,9.817
  other v3: 68.37,9.817
  other v4: 68.37,9.817
NetTP49_X: TP49.X U1.31 | length 3.8
  TOP_L1 w0.127: U1.31@66.106,9.559 66.682,9.559 66.993,9.248 67.212,9.248 v2(67.218,9.242)
  L3 w0.127: v2(67.218,9.242) 67.629,9.242 67.782,9.09 v5(67.856,9.09)
  BOTTOM_L10 w0.127: TP49.X@66.04,8.89 66.855,8.89 67.06,9.095 67.851,9.095 v5(67.856,9.09)
  other v1: 67.218,9.242
  other v3: 67.856,9.09
  other v4: 67.856,9.09
NetTP89_X: TP89.X U23.17 | length 4.3
  BOTTOM_L10 w0.127: U23.17@46.473,89.416 49.819,89.416 TP89.X@50.489,90.086
NetTP94_X: TP94.X U23.18 | length 4.9
  BOTTOM_L10 w0.127: U23.18@46.473,89.016 48.686,89.016 48.98,89.016 49.458,89.016 50.489,87.984 TP94.X@50.489,87.546
NetTP95_X: TP95.X U23.9 | length 3.3
  BOTTOM_L10 w0.127: TP95.X@44.5,95.1 44.523,95.077 U23.9@44.523,91.766
NetU5_33: U5.33
NetU5_34: U5.34
NetU5_45: U5.45
NetU5_50: U5.50
NetU18_5: U18.5
NetU20_8: U20.8
NetU22_C3: U22.C3
NetU22_D7: U22.D7
NetU24_A37: U24.A37
NetU24_A40: U24.A40 U34.K2 | length 35.7
  TOP_L1 w0.1: U34.K2@45.761,30.849 46.549,30.849 46.636,30.761 46.636,27.162 47.883,25.915 47.976,25.915 v1(49.251,24.64) ; v5(70.607,29.393) 70.607,29.019 70.934,28.692 70.934,28.407 v4(70.991,28.349)
  L3 w0.1: v1(49.251,24.64) 49.268,24.657 49.806,24.657 v5(49.823,24.675)
  L8 w0.1: v5(49.823,24.675) 49.823,25.633 51.265,27.075 58.029,27.075 58.22,26.884 v3(61.867,26.884) ; v5(70.607,29.393) 70.605,29.392 70.605,28.735 v4(70.991,28.349)
  BOTTOM_L10 w0.1: v3(61.867,26.884) 64.815,26.884 65.523,26.175 69.672,26.175 70.991,27.494 v4(70.991,28.349)
  other v1: 70.607,29.393
  other v2: 49.251,24.64 70.607,29.393
  other v3: 70.991,28.349
  other v4: 61.867,26.884
NetU24_B35: U24.B35
NetU24_B36: U24.B36 U34.AK34 | length 84.3
  TOP_L1 w0.1: 36.615,35.849 37.128,35.849
  TOP_L1 w0.127: v2(35.896,35.913) 36.125,35.913 36.186,35.852 36.567,35.852 36.57,35.849 36.615,35.849 ; 37.128,35.849 U34.AK34@37.421,35.849 ; v1(53.34,49.63) 59.44,49.63 59.64,49.83 59.64,53.013 59.769,53.142 59.769,54.524 60.174,54.929 v2(61.735,54.929) ; U24.B36@70.941,29.824 71.012,29.824 v2(71.023,29.834)
  L3 w0.127: v2(35.896,35.913) 35.34,36.469 35.34,42.671 37.896,45.227 44.037,45.227 47.14,48.33 49.34,48.33 50.64,49.63 v1(53.34,49.63) ; v2(61.735,54.929) v5(61.744,54.929) ; v5(69.039,40.415) 71.84,43.216 71.84,46.03 72.54,46.73 74.204,46.73 75.14,47.666 75.14,49.449 v5(74.778,49.811) ; v2(71.023,29.834) 71.046,29.858 71.197,29.858 71.306,29.966 v5(71.379,29.966)
  L8 w0.127: v5(69.039,40.415) 68.736,40.113 68.736,36.782 72.151,33.367 72.151,30.322 71.795,29.966 v5(71.379,29.966) ; v4(74.295,50.327) 74.295,50.31 74.778,49.827 v5(74.778,49.811)
  BOTTOM_L10 w0.127: v5(61.744,54.929) 62.263,54.41 62.509,54.41 65.905,51.013 74.183,51.013 74.295,50.901 v4(74.295,50.327)
  other v1: 71.023,29.834 35.896,35.913 61.735,54.929
  other v2: 53.34,49.63
  other v3: 74.295,50.327 61.744,54.929
  other v4: 61.744,54.929
NetU24_B45: U24.B45
NetU28_1: U28.1
NRST: C270.2 JANALOG.3 JSPI.5 R140.1 R181.1 R384.1 TP35.X | length 151.6
  TOP_L1 w0.127: R140.1@52.439,70.89 52.439,70.489 52.589,70.34 54.111,70.34 54.33,70.559 v1(54.33,73.128) ; v2(54.323,80.479) 55.069,80.479 58.647,76.902 58.647,74.177 58.647,73.971 69.859,62.759 69.859,54.313 69.531,53.986 69.531,45.913 61.485,37.866 55.831,37.866 54.327,36.362 54.327,25.554 56.596,23.286 61.856,23.286 62.167,23.597 JSPI.5@62.167,25.4
  L3 w0.127: v2(54.323,80.479) 53.771,79.928 53.771,73.686 v1(54.33,73.128)
  L8 w0.127: v3(36.991,11.76) 42.519,11.76 42.825,11.454 45.172,11.454 45.461,11.742 v4(46.57,11.742) ; v4(46.09,20.149) 46.09,21.574 47.004,22.488 47.438,22.488 47.882,22.932 48.817,22.932 51.023,25.138 60.808,25.138 60.82,25.15 v2(61.145,25.15)
  BOTTOM_L10 w0.127: JANALOG.3@33.02,2.54 TP35.X@33.02,5.08 31.987,6.113 29.812,6.113 29.683,6.243 29.683,9.096 31.851,11.265 36.77,11.265 36.991,11.485 v3(36.991,11.76) ; v4(46.09,20.149) 46.09,14.679 46.57,14.199 46.57,11.799 v3@46.513,11.742 ; v4(46.57,11.742) 46.603,11.742 46.697,11.649 R384.1@48.891,11.649
  other v1: 61.145,25.15 54.323,80.479
  other v2: 54.33,73.128
  other v3: 46.57,11.742 46.09,20.149
  other v4: 36.991,11.76
  other v5: 61.145,25.15
P\M\_\R\E\S\I\N\_\N\_\3\V\3\_1: D26.1 D26.10 D67.2 JCTL.8 JOMEGA.78 R216.2 R487.1 U25.2 | length 103.9
  TOP_L1 w0.127: R216.2@4.965,84.427 5.347,84.427 5.622,84.702 U25.2@7.505,84.702 8.226,84.702 v2(8.368,84.844) 8.368,84.179 7.74,83.551 R487.1@7.74,83.202 ; JCTL.8@20.01,18.381 22.71,18.381 22.71,19.007 22.784,19.081 22.802,19.081 23.956,20.235 23.956,21.135 24.01,21.189 24.01,21.59 v1(24,21.6)
  L3 w0.127: v1(24,21.6) 23.48,22.12 23.48,36.13 24.017,36.667 v3(26.676,36.667)
  BOTTOM_L10 w0.127: v2(8.368,84.844) 9.317,84.844 9.363,84.89 10.279,84.89 12.799,82.37 12.799,73.916 16.543,70.171 22.365,70.171 24.865,67.671 24.865,63.265 23.089,61.489 23.089,55.514 22.211,54.635 22.211,50.192 21.116,49.097 21.116,47.262 21.235,47.142 21.235,44.857 20.894,44.517 20.473,44.517 20.122,44.165 20.122,38.778 21.173,37.727 22.826,37.727 23.651,38.553 D26.1@23.651,39.374 D26.10@23.651,40.249 23.651,40.723 23.799,40.871 24.399,40.871 24.478,40.95 ; JOMEGA.78@24.556,42.35 24.556,41.028 24.478,40.95 ; v3(26.676,36.667) 26.676,37.474 24.478,39.672 24.478,40.95
  other v1: 8.368,84.844
  other v2: 24,21.6
  other v3: 8.368,84.844
  other v4: 26.676,36.667 8.368,84.844
  other v5: 26.676,36.667 8.368,84.844
P\O\W\E\R\_\D\I\S\A\B\L\E\_\7\-\2\4\V\_1: JOMEGA.87 Q7.3 R117.2 R119.2 R357.2 R486.1 U11.4 U13.4 | length 154.4
  TOP_L1 w0.127: v2(3.481,101.607) 3.475,101.614 R117.2@3.475,102.165 3.575,102.265 R357.2@3.575,102.965 R119.2@3.575,103.665 3.791,103.665 4.402,104.276 5.263,104.276 v2(5.581,104.594) 5.59,104.603 5.59,105.305 U11.4@5.6,105.315 ; U13.4@5.6,116.615 5.6,116.065 5.631,116.034 5.631,115.904 v2(5.643,115.892) ; v1(15.648,14.915) 22.334,14.915 v5(22.705,15.286) 23.111,15.286 23.185,15.361 R486.1@23.185,15.841 ; Q7.3@21.65,12 21.65,13.082 21.789,13.221 22.694,13.221 v5(24.144,14.67)
  L3 w0.1: v5(5.5,56) 5.5,55.292 6.458,54.334 7.334,54.334 8.557,53.111 8.557,48.667 9.179,48.046 9.179,41.146 9.325,41 9.425,41 9.628,40.797 v5(9.646,40.797)
  L3 w0.127: v2(3.481,101.607) 3.481,94.081 4.352,93.211 4.352,92.061 4.455,91.959 4.733,91.959 7.859,88.832 7.859,88.755 7.862,88.752 7.862,83.706 8.986,82.582 8.986,80.917 9.326,80.578 15.782,80.578 v3(16.239,80.122) ; v2(5.581,104.594) 6.655,105.668 6.655,114.88 v2(5.643,115.892) ; v1(15.648,14.915) 15.65,14.918 16.007,14.918 v5(16.01,14.921)
  L8 w0.1: v5(5.5,56) 5.5,56.557 11.017,62.074 11.017,66.351 10.819,66.549 10.819,66.933 11.017,67.131 11.017,67.512 12.505,69 12.505,69.68 15.94,73.115 v4(15.94,75.684) ; v5(9.646,40.797) 10.329,40.113 12.394,40.113 13.116,39.391 13.116,37.981 14.362,36.736 14.362,34.853 12.696,33.187 12.696,31.372 12.7,31.368 12.7,31.262 12.903,31.059 12.903,28.061 13.046,27.919 13.72,27.919 14.199,27.44 14.199,27.282 14.678,26.803 14.678,20.853 14.814,20.718 14.814,16.118 v5(16.01,14.921) ; v5(22.705,15.286) 23.762,15.286 23.905,15.143 23.905,14.909 v5(24.144,14.67)
  L8 w0.127: v5(9.646,40.797) 9.646,41.256 9.465,41.436 9.465,43.411 9.825,43.771 v4(10.121,43.771)
  BOTTOM_L10 w0.1: v4(10.121,43.771) 10.224,43.874 10.297,43.874 10.448,44.024 15.972,44.024 16.689,44.741 18.136,44.741 18.201,44.806 18.201,45.994 JOMEGA.87@18.206,46
  BOTTOM_L10 w0.127: v4(15.94,75.684) 16.239,75.982 v3(16.239,80.122)
  other v1: 24.144,14.67 22.705,15.286 3.481,101.607 5.581,104.594 5.643,115.892
  other v2: 24.144,14.67 15.648,14.915 22.705,15.286
  other v3: 10.121,43.771 15.94,75.684
  other v4: 16.239,80.122
  other v5: 16.239,80.122
P\W\R\_\E\N\_\N\_\3\V\3\_1: D25.4 D25.7 JOMEGA.74 R188.2 R219.2 R350.1 | length 80.6
  TOP_L1 w0.127: v1(6.718,54.876) 6.718,54.403 7.287,53.834 11.941,53.834 13.232,52.543 R188.2@13.232,51.649 15.631,51.649 17.5,49.78 17.5,47.88 18.987,46.393 25.687,46.393 26.625,45.455 v1@26.625,44 ; v2(17.762,77.213) 19.625,79.077 20.935,79.077 20.961,79.051 21.583,79.051 21.661,79.129 29.447,79.129 33.266,75.309 R350.1@33.266,74.398
  L3 w0.127: v5(6.482,55.846) 6.482,55.113 v1(6.718,54.876) ; v2(17.762,77.213) v5(18.562,77.213) ; v2(26.625,43.985) 26.629,43.981 26.629,43.617 v5(26.633,43.614)
  L8 w0.127: v5(6.482,55.846) 6.458,55.871 6.458,56.693 12.762,62.997 12.762,69.579 18.562,75.379 v5(18.562,77.213) ; v5(26.633,43.614) 26.645,43.601 27.034,43.601 v4(27.047,43.588)
  BOTTOM_L10 w0.127: v4(27.047,43.588) 27.047,42.4 JOMEGA.74@27.096,42.35 27.096,40.917 27.231,40.782 D25.7@27.231,40.249 D25.4@27.231,39.374 27.244,39.361 R219.2@27.244,38.085
  other v1: 26.625,43.985 17.762,77.213
  other v2: 6.718,54.876
  other v3: 27.047,43.588
PA0: JMISC.20 U3.L2 | length 110.7
  L8 w0.127: v4(61.89,21.849) 62.263,22.222 62.263,22.972 62.652,23.361 62.652,23.75 63.517,24.615 63.517,30.511 63.207,30.821 63.207,35.7 68.75,41.243 77.45,41.243 78.141,41.934 78.141,45.897 76.777,47.261 76.777,48.522 76.542,48.756 76.542,49.032 76.757,49.247 76.881,49.371 v3(78.013,49.371)
  BOTTOM_L10 w0.127: JMISC.20@53.359,103.277 53.359,101.493 52.866,101 52.866,97.104 53.077,96.893 53.077,95.457 53.587,94.947 53.587,73.471 66.095,60.962 66.095,60.622 72.971,53.746 74.385,53.746 77.742,50.389 77.742,50.246 78.013,49.975 v3(78.013,49.371) ; U3.L2@60.363,19.329 60.311,19.381 60.311,19.555 60,19.866 60,20.459 60.075,20.534 60.075,20.648 60.244,20.817 60.358,20.817 60.423,20.882 60.923,20.882 v4(61.89,21.849)
  other v3: 61.89,21.849
  other v4: 78.013,49.371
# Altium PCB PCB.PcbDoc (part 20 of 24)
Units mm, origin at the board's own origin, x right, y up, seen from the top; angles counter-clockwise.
Board outline 100 x 160 mm, 10 copper layers (TOP_L1, L2, L3, L4, L5, L6, L7, L8, L9, BOTTOM_L10), stack 1.946 mm thick; 1358 components, 1149 nets, 6777 pads, 10914 vias.

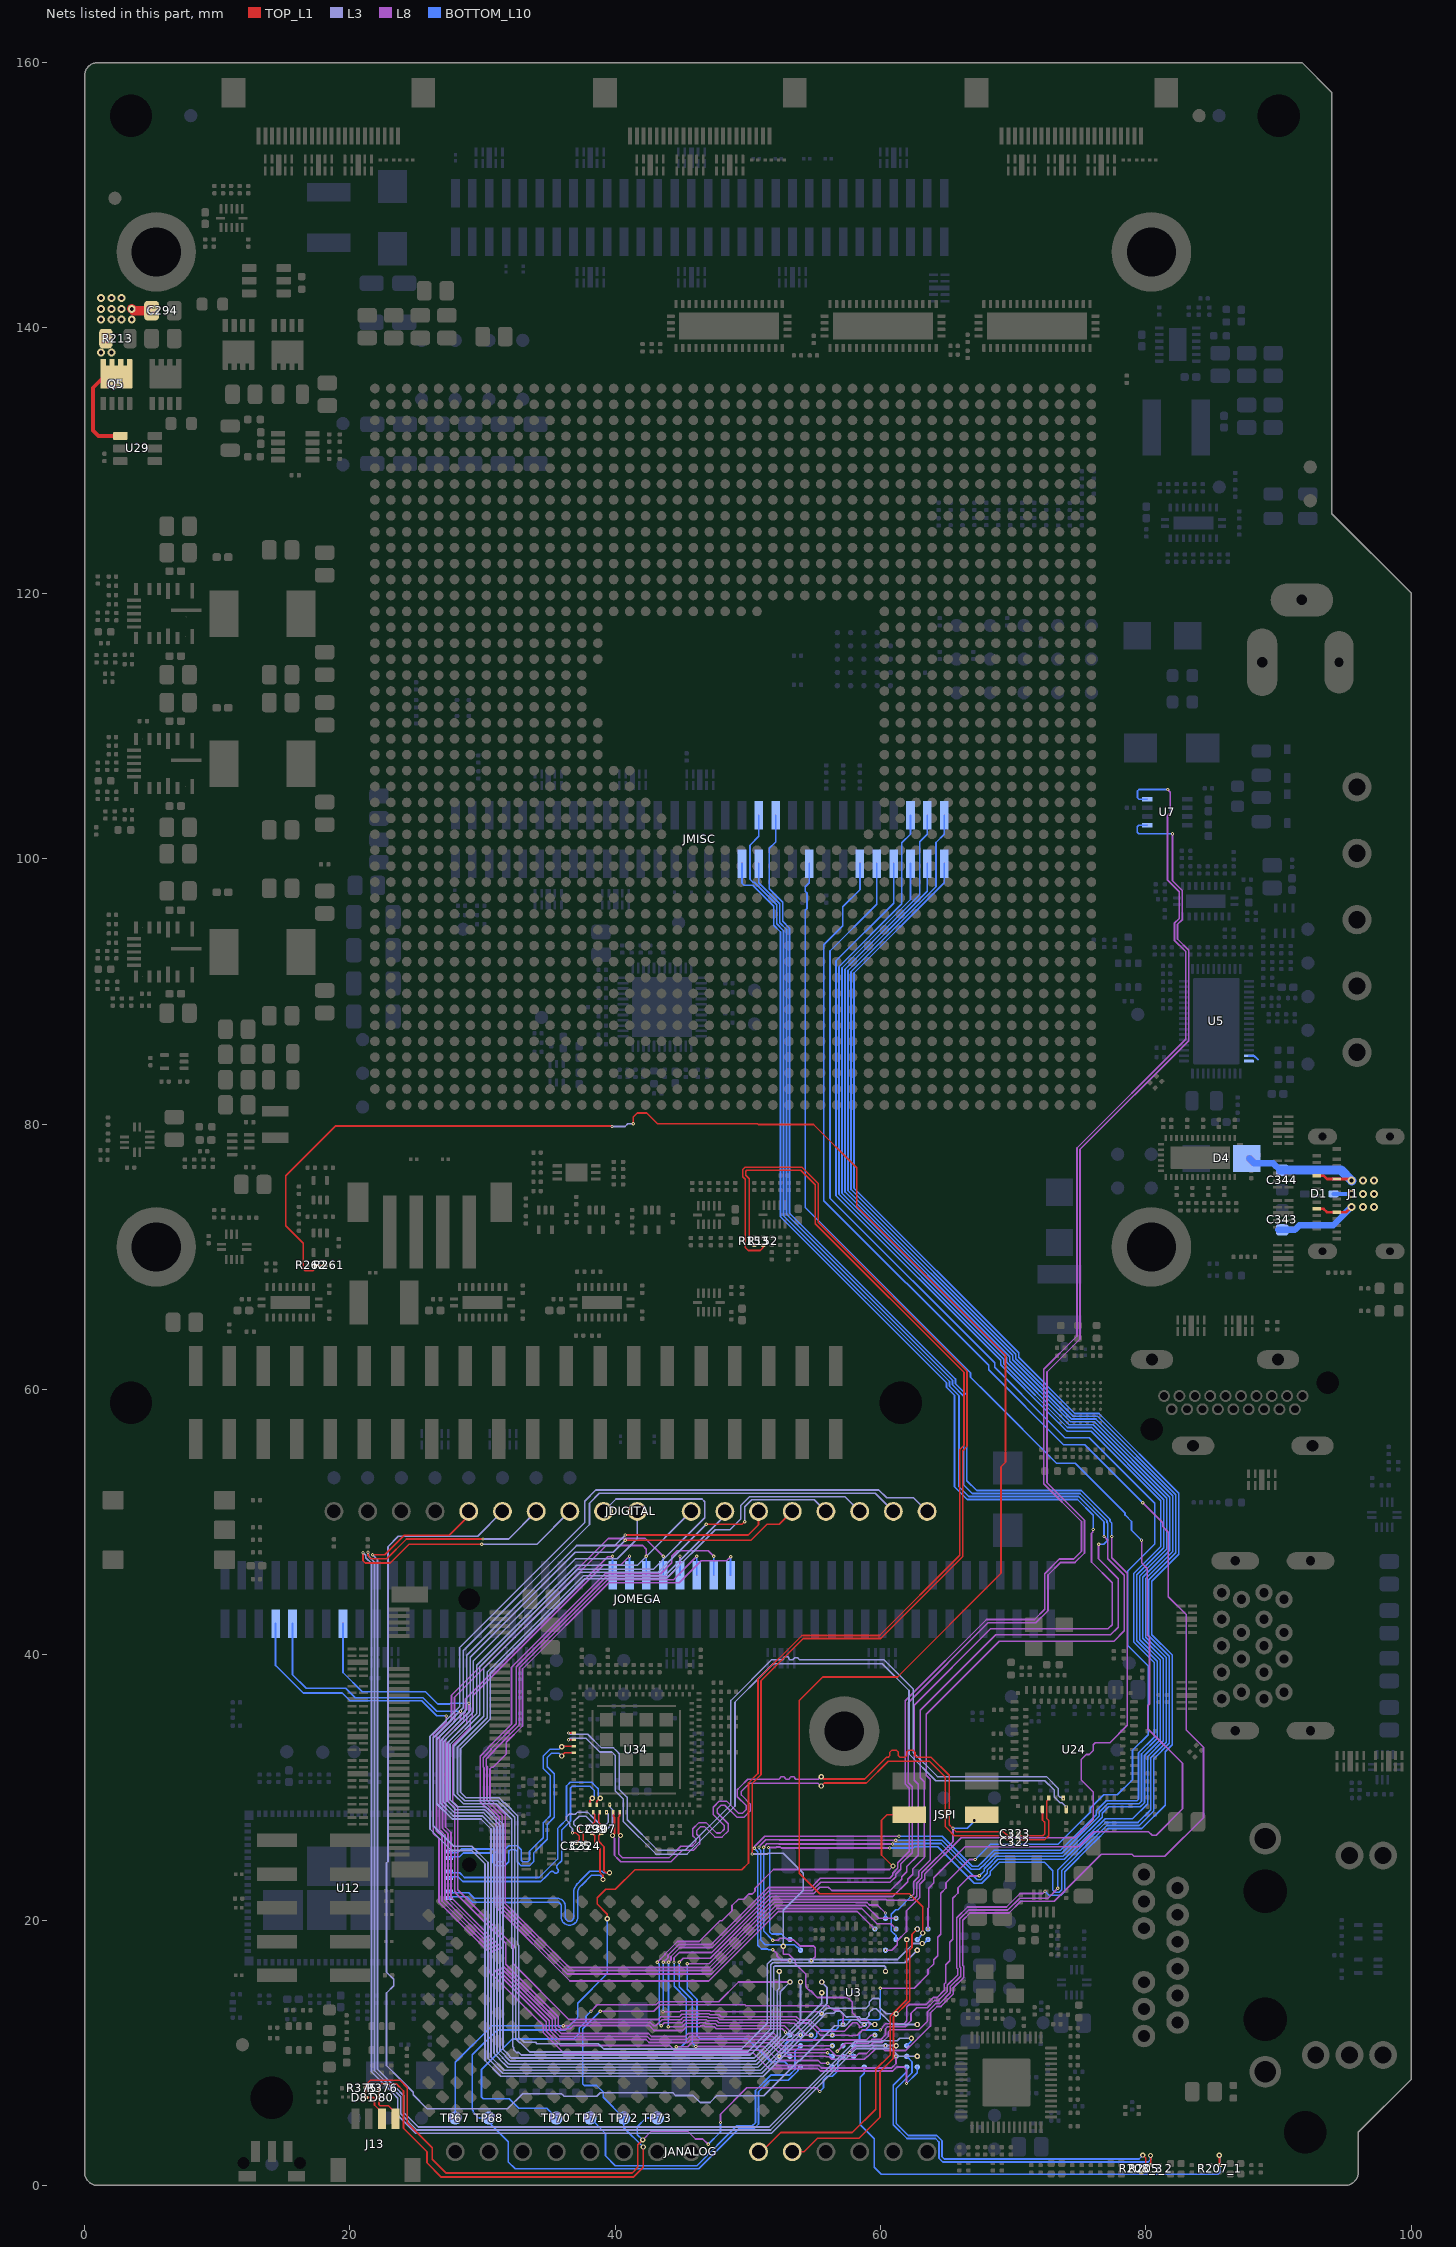
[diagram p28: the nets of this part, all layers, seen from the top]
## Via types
v1: diameter 0.25, hole 0.1, TOP_L1 to L2, tented both sides, 3439 vias
v2: diameter 0.25, hole 0.1, L2 to L3, tented both sides, 2256 vias
v3: diameter 0.25, hole 0.1, L9 to BOTTOM_L10, tented both sides, 1685 vias
v4: diameter 0.25, hole 0.1, L8 to L9, tented both sides, 1675 vias
v5: diameter 0.4, hole 0.2, L3 to L8, tented both sides, 1251 vias
v6: diameter 0.6, hole 0.3, TOP_L1 to BOTTOM_L10, tented both sides, 600 vias
v7: diameter 0.24, hole 0.1, TOP_L1 to L2, tented both sides, 8 vias

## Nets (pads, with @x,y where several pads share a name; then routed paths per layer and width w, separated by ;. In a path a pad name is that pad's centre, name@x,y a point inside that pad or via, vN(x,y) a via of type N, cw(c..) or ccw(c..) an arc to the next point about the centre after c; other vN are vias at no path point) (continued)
PA1: JMISC.22 U3.L4 | length 115.9
  L8 w0.127: v4(60.363,17.729) 60.847,17.729 61.247,18.129 61.247,18.44 61.946,19.139 61.946,20.697 62.944,21.695 62.944,22.689 63.333,23.078 63.333,23.468 66.076,26.211 74.654,26.211 76.023,27.581 76.023,29.654 75.123,30.554 75.123,32.075 75.128,32.079 75.128,32.1 75.503,32.475 75.723,32.475 76.023,32.775 76.023,33.226 76.172,33.375 77.286,33.375 78.595,34.684 78.595,46.143 77.423,47.316 v4(77.423,48.916)
  BOTTOM_L10 w0.127: JMISC.22@52.089,103.277 52.089,101.26 51.601,100.772 51.601,97.727 52.623,96.705 52.623,95.269 53.133,94.759 53.133,73.283 65.641,60.774 65.641,60.434 66.497,59.578 66.497,53.109 67.232,52.375 75.114,52.375 77.288,50.201 77.288,50.058 77.423,49.923 v4(77.423,48.916)
  other v3: 60.363,17.729 77.423,48.916
PA2: JMISC.24 U3.M3 | length 114.5
  L8 w0.127: v3(62.291,21.772) 62.49,21.97 62.49,22.877 62.879,23.267 62.879,23.656 63.744,24.521 63.744,30.605 63.434,30.915 63.434,35.513 68.937,41.016 77.587,41.016 78.368,41.797 78.368,45.991 77.123,47.237 77.123,48.627 v4(76.834,48.916)
  BOTTOM_L10 w0.127: JMISC.24@50.819,103.277 50.819,101.677 50.149,101.007 50.149,98.454 50.379,98.224 50.462,98.224 52.169,96.517 52.169,95.081 52.679,94.571 52.679,73.095 65.187,60.586 65.187,60.246 65.911,59.522 65.911,52.652 66.642,51.921 74.926,51.921 76.834,50.013 v4(76.834,48.916) ; U3.M3@61.163,18.529 61.163,18.833 61.031,18.965 61.013,18.965 60.8,19.178 60.8,20.438 61.151,20.789 61.308,20.789 v3(62.291,21.772)
  other v3: 76.834,48.916
  other v4: 62.291,21.772
PA4: JANALOG.9 U3.N3 | length 23.9
  TOP_L1 w0.127: JANALOG.9@50.8,2.54 51.016,2.54 52.46,3.983 57.867,3.983 59.637,5.753 59.637,8.749 60.713,9.825 60.713,12.756 61.963,14.006 v3(61.963,18.529)
  other v1: 61.963,18.529
  other v2: 61.963,18.529
  other v4: 61.963,18.529
  other v5: 61.963,18.529
PA5: JANALOG.10 U3.P2 | length 23
  TOP_L1 w0.127: JANALOG.10@53.34,2.54 54.224,2.54 55.241,3.557 58.37,3.557 59.947,5.134 59.947,8.559 60.966,9.577 60.966,12.688 62.196,13.918 62.196,17.771 62.363,17.937 62.363,18.929 v3(62.763,19.329)
  other v1: 62.763,19.329
  other v2: 62.763,19.329
  other v4: 62.763,19.329
  other v5: 62.763,19.329
PA6: JMISC.17 U3.R2 | length 109.3
  L8 w0.127: v3(63.563,19.329) 63.563,20.891 63.625,20.953 63.625,22.407 64.014,22.796 64.014,23.186 66.358,25.53 74.936,25.53 76.071,26.665 80.192,26.665 80.459,26.399 80.76,26.399 82.751,28.39 82.751,31.814 80.136,34.428 80.136,36.147 80.263,36.274 80.263,41.299 80.097,41.465 80.097,46.489 79.671,46.915 79.671,48.621 v4(79.663,48.629)
  BOTTOM_L10 w0.127: JMISC.17@54.629,99.629 54.629,98.191 54.315,97.877 54.315,97.531 54.443,97.404 54.443,96.719 54.443,96.225 54.315,96.098 54.315,73.705 66.776,61.244 66.776,60.904 68.175,59.506 73.253,54.427 74.667,54.427 78.423,50.671 78.423,50.528 78.911,50.04 78.911,49.381 v4(79.663,48.629)
  other v3: 79.663,48.629
  other v4: 63.563,19.329
PA7: R261.1 R262.2 U3.P3 | length 137.2
  TOP_L1 w0.127: R261.1@18.16,69.35 R262.2@17.36,69.35 17.36,69.078 17.211,68.929 16.626,68.929 16.477,69.078 16.477,71.023 15.173,72.327 15.173,76.096 18.932,79.855 39.627,79.855 39.641,79.841 39.728,79.841 v1(39.752,79.817) ; v1(41.363,80.029) 41.363,80.529 41.663,80.829 42.375,80.829 43.179,80.026 50.715,80.026 50.777,79.963 54.943,79.963 58.193,76.714 58.193,73.989 58.193,73.783 69.405,62.571 69.405,54.502 69.077,54.174 69.077,46.132 61.268,38.322 55.645,38.322 53.873,36.55 53.873,23.529 55.414,21.989 62.173,21.989 63.163,20.998 v1(63.163,19.029)
  L3 w0.127: v1(39.752,79.817) 40.73,79.817 40.942,80.029 v1(41.363,80.029)
  BOTTOM_L10 w0.127: U3.P3@62.763,18.529 62.978,18.744 62.978,18.79 63.163,18.975 v1(63.163,19.029)
  other v2: 63.163,19.029 39.752,79.817 41.363,80.029
  other v3: 63.163,19.029
  other v4: 63.163,19.029
  other v5: 63.163,19.029
PA8: D80.2 J13.4 R376.1 TP72.X U3.G11 | length 63
  TOP_L1 w0.127: J13.4@23.417,5.024 23.417,5.499 23.181,5.736 23.168,5.736 22.903,6 22.266,6 22.191,6.074 22.191,6.624 R376.1@22.191,7.324 22.272,7.405 22.272,7.535 22.395,7.658 23.493,7.658 24.033,7.117 24.033,4.316 25.812,2.537 25.812,1.697 26.882,0.628 41.362,0.628 42.1,1.366 v3(42.1,2.892)
  L8 w0.127: v4(38.863,13.129) 42.907,13.129 43.386,13.608 45.78,13.608 45.792,13.62 47.348,13.62 47.36,13.608 49.772,13.608 49.842,13.539 56.039,13.539 56.213,13.365 56.248,13.365 56.284,13.329 56.363,13.329 56.475,13.217 56.878,13.217 57.19,12.906 57.19,12.57 57.163,12.543 v3(57.163,12.129)
  BOTTOM_L10 w0.127: v4(38.863,13.129) 37.539,11.805 37.539,7.643 37.651,7.531 38.587,7.531 39.082,7.036 39.082,6.638 TP72.X@40.64,5.08 40.64,4.352 v3(42.1,2.892)
  other v1: 42.1,2.892
  other v2: 42.1,2.892
  other v3: 38.863,13.129
  other v4: 42.1,2.892 57.163,12.129
  other v5: 42.1,2.892
PA9: JMISC.1 U3.G13 | length 124.3
  L8 w0.127: v3(56.737,10.116) 57.337,10.716 59.073,10.716 59.349,10.992 59.999,10.992 60.363,11.356 60.363,11.819 60.512,11.968 61.851,11.968 62.287,12.403 62.287,12.967 62.723,13.402 63.514,13.402 64.054,13.943 64.354,13.943 65.027,14.616 65.027,15.087 65.804,15.864 65.804,16.32 65.743,16.382 65.743,20.182 66.543,20.982 69.488,20.982 70.508,22.002 72.221,22.002 v3(72.392,22.172)
  BOTTOM_L10 w0.127: v3(56.737,10.116) 56.75,10.116 U3.G13@57.163,10.529 ; JMISC.1@64.789,99.629 64.789,98.175 57.993,91.379 57.993,75.164 70.408,62.749 70.408,62.409 74.637,58.18 76.454,58.18 82.475,52.16 82.475,47.577 80.435,45.536 80.435,41.516 81.976,39.974 81.976,33.221 81.44,32.684 81.44,28.666 79.672,26.898 77.141,26.898 76.063,25.82 76.047,25.82 73.869,23.642 73.869,22.182 73.567,21.88 72.685,21.88 v3(72.392,22.172)
  other v4: 56.737,10.116 72.392,22.172
PA10: JOMEGA.92 U3.F13 | length 67.4
  L8 w0.127: v3(28.338,35.729) 28.338,35.072 26.972,33.706 26.972,26.92 27.11,26.783 27.388,26.504 27.388,21.625 31.283,17.73 31.283,16.475 35.246,12.512 35.246,11.811 35.83,11.227 42.41,11.227 42.637,11 45.36,11 45.587,11.227 51.859,11.227 52.557,10.529 v3(56.363,10.529)
  BOTTOM_L10 w0.127: JOMEGA.92@15.666,42.35 15.666,38.494 16.697,37.464 19.683,37.464 20.39,36.757 25.512,36.757 26.539,35.729 v3(28.338,35.729)
  other v4: 56.363,10.529 28.338,35.729
PA11: JMISC.23 U3.F15 | length 142.9
  L8 w0.127: v4(44.823,16.816) 45.126,17.119 47.146,17.119 51.801,21.773 57.922,21.773 57.928,21.779 60.919,21.779 62.036,22.896 62.036,23.066 62.425,23.455 62.425,23.844 63.29,24.709 63.29,30.417 62.98,30.727 62.98,35.805 68.669,41.494 77.329,41.494 77.914,42.079 77.914,45.737 76.423,47.228 76.423,48.3 v3(76.438,48.316) ; v3(46.055,10.474) 51.21,10.474 52.269,9.415 55.301,9.415 55.5,9.216 v3(56.023,9.216)
  BOTTOM_L10 w0.127: v4(44.823,16.816) 44.823,14.977 45.8,14 45.8,10.728 v3(46.055,10.474) ; JMISC.23@50.819,99.629 50.819,98.188 52.396,96.611 52.396,95.175 52.906,94.665 52.906,73.189 65.414,60.68 65.414,60.34 66.27,59.484 66.27,52.791 66.913,52.148 75.02,52.148 77.061,50.107 77.061,49.964 77.123,49.902 77.123,48.616 76.823,48.316 v3(76.438,48.316) ; v3(56.023,9.216) 56.056,9.216 56.128,9.144 56.148,9.144 U3.F15@56.363,8.929
  other v3: 44.823,16.816
  other v4: 56.023,9.216 46.055,10.474 76.438,48.316
PA12: JMISC.25 U3.F14 | length 145.2
  L8 w0.127: v4(44.423,16.816) 44.423,17.159 44.822,17.558 47.265,17.558 51.707,22 54.951,22 55.421,22.47 56.061,22.47 56.303,22.227 57.734,22.227 57.74,22.233 60.731,22.233 61.582,23.084 61.582,23.254 61.971,23.643 61.971,24.032 62.836,24.898 62.836,30.229 62.526,30.539 62.526,36.2 68.274,41.948 77.141,41.948 77.46,42.267 77.46,45.423 75.896,46.987 75.896,49.133 75.992,49.229 75.992,49.414 v3(76.015,49.438) ; v3(44.6,10.45) 45.452,10.45 45.765,10.762 51.576,10.762 52.321,10.017 52.483,10.017 52.507,9.993 v3(56.001,9.993)
  BOTTOM_L10 w0.127: v4(44.423,16.816) 44.441,16.797 44.441,15 45.347,14.094 45.347,10.823 44.974,10.45 v3(44.6,10.45) ; JMISC.25@49.549,99.629 49.549,98.151 49.703,97.997 50.368,97.997 51.942,96.423 51.942,94.987 52.452,94.477 52.452,73.001 64.96,60.492 64.96,60.152 65.56,59.552 65.56,52.662 66.529,51.694 74.832,51.694 76.015,50.511 v3(76.015,49.438) ; v3(56.001,9.993) 56.265,9.729 U3.F14@56.363,9.729
  other v3: 44.423,16.816
  other v4: 56.001,9.993 44.6,10.45 76.015,49.438
PA13: R152.1 TP67.X U3.F12 | length 138.5
  TOP_L1 w0.127: v1(50.323,24.975) 50.323,30.294 50.976,30.947 50.976,38.032 54.17,41.226 60.002,41.226 66.18,47.404 66.18,55.374 66.508,55.701 66.508,61.371 55.296,72.583 55.296,72.789 55.296,75.514 54.072,76.737 49.774,76.737 49.611,76.574 49.611,76.026 49.795,75.843 49.795,70.686 50.018,70.463 50.916,70.463 51.139,70.686 R152.1@51.139,70.89
  L3 w0.127: v1(50.323,24.975) 51.483,24.975 51.537,25.029 52.663,25.029 54.163,23.529 54.163,22.229 52.663,20.729 v5(52.663,18.029)
  L8 w0.127: v4(36.071,12.035) 36.514,12.035 36.754,12.275 42.646,12.275 42.892,12.029 43.055,12.029 43.521,12.495 44.929,12.495 45.106,12.671 46.128,12.671 46.168,12.712 46.972,12.712 47.053,12.631 47.744,12.631 47.881,12.495 53.552,12.495 53.804,12.243 54.55,12.243 55.463,11.329 v4(56.363,11.329) 57.584,11.329 57.644,11.269 57.883,11.269 57.942,11.329 58.249,11.329 58.613,11.692 58.827,11.692 59.163,12.029 59.163,12.28 58.989,12.455 58.438,12.455 57.863,13.029 57.863,13.829 57.527,14.166 55.227,14.166 54.728,14.664 54.652,14.664 54.439,14.877 54.439,14.953 54.363,15.029 54.363,15.929 53.573,16.719 53.573,16.927 53.071,17.429 52.663,17.429 v5(52.663,18.029)
  BOTTOM_L10 w0.127: TP67.X@27.94,5.08 27.94,9.273 30.709,12.042 36.065,12.042 v4(36.071,12.035)
  other v2: 50.323,24.975
  other v3: 56.363,11.329 36.071,12.035
PA14: R153.1 TP68.X U3.C15 | length 146
  TOP_L1 w0.127: v1(39.405,20.108) 39.405,20.444 38.641,21.208 38.641,21.684 39.271,22.314 39.996,22.314 41.484,23.802 49.536,23.802 50.035,24.301 50.035,30.327 50.749,31.041 50.749,38.126 54.076,41.453 59.908,41.453 65.953,47.499 65.953,55.468 66.281,55.796 66.281,61.277 55.069,72.489 55.069,72.695 55.069,75.42 53.978,76.51 49.912,76.51 49.838,76.436 49.838,76.125 50.095,75.868 50.095,70.955 50.169,70.881 R153.1@50.489,70.881
  BOTTOM_L10 w0.127: v1(39.405,20.108) 39.405,15.971 37.163,13.729 37.163,12.661 36.221,11.719 31.105,11.719 29.229,9.842 29.229,5.693 29.285,5.637 29.285,5.51 29.715,5.08 TP68.X@30.48,5.08 30.647,4.913 30.647,4.584 31.942,3.289 31.942,1.771 32.456,1.257 46.289,1.257 49.293,4.261 50.426,4.261 50.791,4.626 50.791,7.064 51.642,7.916 53.044,7.916 53.766,8.639 53.766,8.701 53.963,8.898 U3.C15@53.963,8.929
  other v2: 39.405,20.108
  other v3: 39.405,20.108
  other v4: 39.405,20.108
  other v5: 39.405,20.108
PA15_12: TP71.X U3.C13 | length 24.3
  BOTTOM_L10 w0.127: TP71.X@38.1,5.08 39.263,3.917 39.263,2.229 40.008,1.484 46.156,1.484 49.16,4.488 50.332,4.488 50.564,4.72 50.564,7.158 51.721,8.316 53.123,8.316 53.539,8.733 53.539,10.105 U3.C13@53.963,10.529
PA_VBUS: C294.2 C343.1 C344.1 D1.2 D4.A J1.A4 J1.A9 J1.B4 J1.B9 Q5.D R213.2 U5.41 U5.42 U29.1 | length 30.7
  TOP_L1 w0.2: J1.A4@92.876,73.604 93.381,73.604 93.631,73.354 93.801,73.354 ; J1.A9@92.876,76.104 93.395,76.104 93.645,75.854 J1.B4@94.376,75.854 v6@95.281,75.854 ; 93.807,73.348 95.08,73.348 95.401,73.67 v6@95.401,73.704 ; v6@95.344,75.854 v6@95.281,75.854 ; v6(95.501,75.729) 95.406,75.729 v6@95.281,75.854
  TOP_L1 w0.3: Q5.D@2.4,136.3 2.307,136.393 1.552,136.393 0.65,135.491 0.65,132.266 1.051,131.865 U29.1@2.7,131.865
  TOP_L1 w0.7: v6(3.555,141.442) 3.697,141.3 C294.2@5.05,141.3
  BOTTOM_L10 w0.15: U5.41@87.753,85.127 87.758,85.122 88.178,85.122 88.425,84.875
  BOTTOM_L10 w0.3: D1.2@94.135,74.729 v6@95.201,74.729
  BOTTOM_L10 w0.5: D4.A@87.8,77.4 88.171,77.029 89.594,77.029 C344.1@89.841,76.782 ; C343.1@89.965,72.029 91.22,72.029 91.563,72.372 94.108,72.372 v6@95.383,73.647
  BOTTOM_L10 w0.7: C344.1@90.165,76.529 94.701,76.529 v6(95.501,75.729)
  other v6: 95.501,73.729 96.351,73.729 97.201,73.729 95.501,74.729 96.351,74.729 97.201,74.729 96.351,75.729 97.201,75.729 1.245,138.142 2.015,138.142 1.245,140.642 2.015,140.642 2.785,140.642 3.555,140.642 1.245,141.442 2.015,141.442 2.785,141.442 1.245,142.242 2.015,142.242 2.785,142.242
PB0: JDIGITAL.3 U3.R3 | length 103.4
  L3 w0.127: JDIGITAL.3@58.42,50.8 57.307,51.913 50.112,51.913 49.45,51.251 49.45,50.225 48.65,49.425 47.522,49.425 43.822,45.725 37.696,45.725 30.575,38.604 30.575,35.151 28.328,32.903 28.328,29.63 28.746,29.212 31.23,29.212 31.605,28.837 31.66,28.837 32.652,27.845 32.652,18.16 32.727,18.085 32.727,11.146 32.9,10.973 32.95,10.973 33.143,10.779 33.999,10.779 34.089,10.689 38.709,10.689 39.119,10.279 49.517,10.279 51.459,12.221 51.459,16.694 51.786,17.021 61.263,17.021 62.481,18.239 v5(63.136,18.239)
  BOTTOM_L10 w0.127: v5(63.136,18.239) 63.16,18.262 63.296,18.262 U3.R3@63.563,18.529
  other v3: 63.136,18.239
  other v4: 63.136,18.239
PB1: JDIGITAL.4 U3.L6 | length 99.3
  TOP_L1 w0.127: v1(46.85,49.825) 49.55,49.825 v1(49.75,50.025)
  L3 w0.127: v1(46.85,49.825) 43.25,46.225 37.35,46.225 30.083,38.958 30.083,35.355 27.835,33.107 27.835,29.481 28.558,28.758 31.042,28.758 32.198,27.602 32.198,17.898 32.273,17.823 32.273,10.461 32.341,10.393 32.341,10.232 32.554,10.019 32.716,10.019 32.909,9.825 50.163,9.825 51.95,11.612 51.95,16.469 52.024,16.543 60.289,16.543 60.363,16.469 v3(60.363,16.129) ; v1(49.75,50.025) 49.75,51.152 50.273,51.675 55.005,51.675 JDIGITAL.4@55.88,50.8
  other v2: 46.85,49.825 49.75,50.025
  other v4: 60.363,16.129
  other v5: 60.363,16.129
PB2: JDIGITAL.7 U3.P4 | length 91.7
  L3 w0.127: JDIGITAL.7@48.26,50.8 48.26,50.484 43.728,45.952 37.602,45.952 30.348,38.698 30.348,35.245 28.101,32.997 28.101,29.536 28.652,28.985 31.136,28.985 31.511,28.61 31.566,28.61 32.425,27.75 32.425,25.496 32.425,17.992 32.5,17.917 32.5,11.052 32.806,10.746 32.856,10.746 33.549,10.052 49.99,10.052 51.723,11.785 51.723,16.637 51.88,16.794 61.828,16.794 v3(62.763,17.729)
  other v4: 62.763,17.729
  other v5: 62.763,17.729
PB3: JDIGITAL.8 TP70.X U3.B7 | length 115.3
  L3 w0.127: JDIGITAL.8@45.72,50.8 41.672,46.752 37.094,46.752 29.56,39.218 29.56,35.571 27.313,33.324 27.313,28.974 27.806,28.481 27.983,28.304 28.369,28.304 30.159,28.304 31.314,27.149 31.314,10.172 31.732,9.754 31.732,9.704 32.034,9.402 32.083,9.402 32.115,9.371 50.567,9.371 52.432,11.236 52.432,14.597 v5(53.163,15.329)
  L8 w0.127: v3(38.163,13.12) 38.651,13.608 43.065,13.608 43.292,13.835 45.686,13.835 45.698,13.847 47.442,13.847 47.454,13.835 47.79,13.835 49.284,15.329 v5(53.163,15.329)
  BOTTOM_L10 w0.127: TP70.X@35.56,5.08 34.826,5.814 33.148,5.814 33.147,5.815 32.723,5.815 32,6.538 30.045,6.538 29.91,6.674 29.91,8.723 32.224,11.038 36.864,11.038 37.279,11.453 37.279,11.866 37.787,12.374 37.787,12.745 v3(38.163,13.12)
  other v3: 53.163,15.329
  other v4: 38.163,13.12 53.163,15.329
PB4: JDIGITAL.9 U3.C7 | length 79.1
  L3 w0.127: 27.057,29.456 27.057,28.909 27.712,28.254 27.889,28.077 28.275,28.077 30.065,28.077 31.087,27.055 31.087,10.057 31.505,9.639 31.505,9.61 31.94,9.175 31.968,9.175 31.999,9.144 50.661,9.144 53.963,12.446 v5(53.963,15.329) ; 27.057,29.485 27.057,33.43 29.305,35.677 29.305,39.526 37.004,47.225 40.15,47.225 41.656,48.731 JDIGITAL.9@41.656,50.8
  other v3: 53.963,15.329
  other v4: 53.963,15.329
PB5: JDIGITAL.6 U3.E7 | length 90.8
  TOP_L1 w0.127: v2(40.75,49.025) 50.009,49.025 50.8,49.816 JDIGITAL.6@50.8,50.8
  L3 w0.127: v2(40.75,49.025) 40.742,49.025 39.942,48.225 37.071,48.225 28.802,39.956 28.802,35.885 26.555,33.638 26.555,28.769 27.701,27.623 29.877,27.623 30.633,26.867 30.633,9.681 31.624,8.69 50.948,8.69 55.667,13.409 55.669,13.409 55.95,13.69 55.95,14.942 v5(55.563,15.329)
  other v1: 40.75,49.025
  other v3: 55.563,15.329
  other v4: 55.563,15.329
PB6: JDIGITAL.5 U3.E8 | length 90.5
  TOP_L1 w0.127: v1(40.75,48.625) 50.234,48.625 51.434,49.825 52.365,49.825 JDIGITAL.5@53.34,50.8
  L3 w0.127: 26.83,29.362 26.83,28.815 27.618,28.027 27.795,27.85 28.181,27.85 29.971,27.85 30.86,26.961 30.86,9.963 31.278,9.545 31.278,9.516 31.846,8.948 31.874,8.948 31.905,8.917 50.755,8.917 55.563,13.725 v4(55.563,14.529) ; 26.83,29.391 26.83,33.524 29.078,35.771 29.078,39.81 36.984,47.716 39.841,47.716 v1(40.75,48.625)
  other v2: 40.75,48.625
  other v3: 55.563,14.529
  other v5: 55.563,14.529
PB7: JDIGITAL.10 U3.A6 | length 90.2
  L3 w0.127: JDIGITAL.10@39.116,50.8 40.051,51.735 46.54,51.735 46.75,51.525 46.75,50.325 42.877,46.452 37.149,46.452 29.79,39.093 29.79,35.476 27.542,33.229 27.542,29.066 28.077,28.531 28.464,28.531 30.253,28.531 31.541,27.243 31.541,10.266 31.959,9.848 31.959,9.798 32.128,9.629 32.177,9.629 32.209,9.598 50.473,9.598 52.205,11.33 52.205,14.692 52.363,14.85 v4(52.363,16.129)
  other v3: 52.363,16.129
  other v5: 52.363,16.129
PB10: JDIGITAL.2 U3.M10 | length 107.5
  L3 w0.127: JDIGITAL.2@60.96,50.8 59.589,52.171 38.796,52.171 38.05,51.425 38.05,49.814 28.531,40.295 28.531,35.998 26.284,33.75 26.284,27.109 27.835,25.557 29.188,25.557 30.406,24.339 30.406,9.587 31.53,8.463 51.042,8.463 55.762,13.182 55.763,13.182 55.927,13.346 58.894,13.346 59.143,13.595 59.143,13.823 59.413,14.092 59.86,14.092 59.934,14.018 59.934,13.408 60.413,12.929 v3(61.163,12.929)
  other v4: 61.163,12.929
  other v5: 61.163,12.929
PB11: JDIGITAL.1 U3.P11 | length 112.7
  L3 w0.127: v4(62.763,12.129) 60.877,12.129 59.681,13.325 59.445,13.325 59.127,13.007 59.127,12.778 58.914,12.565 58.518,12.565 58.38,12.703 57.579,12.703 57.565,12.689 57.407,12.689 56.977,13.119 56.604,13.119 56.471,12.985 55.905,12.985 55.876,12.955 55.856,12.955 55.643,12.742 55.643,12.722 51.157,8.236 31.356,8.236 30.179,9.413 30.179,24.245 29.177,25.247 27.653,25.247 26.034,26.866 26.034,33.854 28.281,36.101 28.281,40.545 37.696,49.961 37.696,51.571 38.538,52.413 59.862,52.413 60.45,51.825 62.475,51.825 JDIGITAL.1@63.5,50.8
  other v3: 62.763,12.129
  other v5: 62.763,12.129
PB12: JDIGITAL.11 U3.P14 | length 104
  TOP_L1 w0.127: v2(20.989,47.696) 20.989,47.087 21.161,46.914 23.039,46.914 24.45,48.325 v1@29.923,48.325
  L3 w0.127: v2(20.989,47.696) 21.192,47.493 21.192,47.317 21.623,46.886 21.623,8.564 23.246,6.941 23.607,6.58 23.607,5.277 24.951,3.933 51.769,3.933 58.155,10.319 60.779,10.319 61.37,9.729 v3(62.763,9.729) ; v2(29.923,48.325) 29.929,48.319 34.095,48.319 JDIGITAL.11@36.576,50.8
  other v1: 20.989,47.696 29.923,48.325
  other v4: 62.763,9.729
  other v5: 62.763,9.729
PB13: JDIGITAL.14 U3.N13 | length 94
  TOP_L1 w0.127: v1(21.707,47.53) 22.628,47.53 24.096,48.998 27.484,48.998 28.956,50.47 JDIGITAL.14@28.956,50.8
  L3 w0.127: v1(21.707,47.53) 22.077,47.161 22.077,8.752 23.434,7.395 24.061,6.768 24.061,5.493 25.147,4.407 51.601,4.407 58.039,10.845 60.048,10.845 60.095,10.892 61.241,10.892 61.445,11.097 v3(62.319,11.097)
  BOTTOM_L10 w0.127: U3.N13@61.963,10.529 62.306,10.872 62.306,11.084 v3(62.319,11.097)
  other v2: 21.707,47.53
  other v4: 62.319,11.097
  other v5: 62.319,11.097
PB14: JDIGITAL.13 U3.K11 | length 91.3
  L3 w0.127: JDIGITAL.13@31.496,50.8 29.621,48.925 23.65,48.925 22.866,48.141 22.866,24.41 22.758,24.302 22.758,16.069 23.296,15.531 23.296,15.042 22.758,14.504 22.758,9.034 23.716,8.076 24.762,7.031 24.762,6.822 25.807,5.777 31.879,5.777 33.022,6.92 35.945,6.92 36.149,6.717 38.601,6.717 38.858,6.974 44.344,6.974 44.543,6.775 45.871,6.775 46.397,6.249 47.135,6.249 47.633,6.747 51.18,6.747 53.821,9.389 53.905,9.389 56.547,12.031 57.351,12.031 57.797,12.476 58.286,12.476 58.511,12.251 59.172,12.251 59.263,12.16 59.532,12.16 v3(59.563,12.129)
  other v4: 59.563,12.129
  other v5: 59.563,12.129
PB15: JDIGITAL.12 U3.M13 | length 98.3
  TOP_L1 w0.127: v1(21.367,47.729) 21.367,47.462 21.588,47.242 22.786,47.242 24.269,48.725 v2(30.023,48.725)
  L3 w0.127: v1(21.367,47.729) 21.391,47.706 21.391,47.614 21.419,47.587 21.419,47.411 21.85,46.98 21.85,8.658 23.34,7.168 23.834,6.674 23.834,5.399 25.053,4.18 51.695,4.18 58.061,10.546 61.146,10.546 v4(61.163,10.529) ; v2(30.023,48.725) 31.961,48.725 JDIGITAL.12@34.036,50.8
  other v1: 30.023,48.725
  other v2: 21.367,47.729
  other v3: 61.163,10.529
  other v5: 61.163,10.529
PC0: JOMEGA.39 U3.L1 | length 73.2
  L8 w0.115: 51.702,21.033 51.995,21.325 58.116,21.325
  L8 w0.127: v4(48.691,47.39) 48.382,47.08 46.48,47.08 44.821,45.421 39.505,45.421 33.007,38.923 33.007,34.622 31.782,33.397 31.782,32.514 30.785,31.518 30.671,31.518 30.556,31.404 30.556,29.13 31.709,27.977 31.709,21.252 36.533,16.427 47.097,16.427 51.702,21.033 ; 58.116,21.325 58.974,21.325 59.17,21.129 59.763,21.129 v4(60.363,20.529)
  BOTTOM_L10 w0.127: JOMEGA.39@48.686,46 48.686,47.385 v4(48.691,47.39) ; U3.L1@60.363,20.129 v4(60.363,20.529)
  other v3: 60.363,20.529 48.691,47.39
PC1: JOMEGA.41 U3.K2 | length 73.9
  L8 w0.127: v3(47.416,47.41) 46.997,47.829 44.663,47.829 44.263,47.429 44.263,46.929 43.436,46.102 39.223,46.102 32.173,39.053 32.173,34.752 30.411,32.989 30.411,32.938 29.817,32.345 29.817,28.905 31.028,27.695 31.028,20.969 36.589,15.409 47.042,15.409 52.277,20.644 58.248,20.644 v3(59.563,19.329)
  BOTTOM_L10 w0.127: JOMEGA.41@47.416,46 v3(47.416,47.41)
  other v4: 59.563,19.329 47.416,47.41
PC2: JOMEGA.43 U3.M1 | length 71.8
  L8 w0.127: v4(46.146,47.41) 44.385,45.648 39.411,45.648 32.78,39.017 32.78,34.716 30.865,32.801 30.865,32.75 30.418,32.303 30.418,32.282 30.271,32.136 30.271,31.627 30.329,31.57 30.329,29.035 31.482,27.883 31.482,21.626 31.482,21.157 36.439,16.2 36.908,16.2 47.191,16.2 52.089,21.098 58.88,21.098 59.849,20.129 v4(61.163,20.129)
  BOTTOM_L10 w0.127: JOMEGA.43@46.146,46 v4(46.146,47.41)
  other v3: 61.163,20.129 46.146,47.41
PC3: JOMEGA.45 U3.M2 | length 71.8
  L8 w0.127: v3(44.876,47.41) 44.876,46.77 43.982,45.875 39.317,45.875 32.527,39.085 32.527,34.784 30.638,32.895 30.638,32.844 30.191,32.397 30.191,32.376 30.044,32.23 30.044,31.533 30.102,31.476 30.102,28.941 31.255,27.789 31.255,21.063 36.381,15.937 47.249,15.937 52.183,20.871 58.574,20.871 59.726,19.72 60.772,19.72 v4(61.163,19.329)
  BOTTOM_L10 w0.127: JOMEGA.45@44.876,46 v3(44.876,47.41)
  other v3: 61.163,19.329
  other v4: 44.876,47.41
PC6: R207_1.1 U3.J15 | length 36.5
  TOP_L1 w0.127: v1(85.531,2.272) 85.541,2.262 85.541,1.534 R207_1.1@85.55,1.525
  BOTTOM_L10 w0.127: U3.J15@58.763,8.929 58.763,8.45 58.467,8.154 58.467,4.572 59.522,3.517 59.522,1.367 60.039,0.85 85.426,0.85 85.55,0.975 85.55,2.253 v1(85.531,2.272)
  other v2: 85.531,2.272
  other v3: 85.531,2.272
  other v4: 85.531,2.272
  other v5: 85.531,2.272
PC7: JMISC.3 U3.H14 | length 121.9
  L8 w0.127: v3(57.676,10.016) 58.149,10.489 59.167,10.489 59.443,10.765 60.093,10.765 60.59,11.262 60.59,11.592 60.739,11.741 62.889,11.741 63.531,12.383 63.531,13.098 64.148,13.716 64.448,13.716 65.254,14.522 65.254,14.993 66.031,15.77 66.031,16.414 65.97,16.476 65.97,20.088 66.637,20.755 69.582,20.755 70.477,21.65 72.608,21.65 v4(73.354,22.395)
  BOTTOM_L10 w0.127: v3(57.676,10.016) U3.H14@57.963,9.729 ; JMISC.3@63.519,99.629 63.519,97.547 57.539,91.567 57.539,74.976 69.954,62.561 69.954,62.221 74.416,57.759 76.234,57.759 82.021,51.971 82.021,47.78 79.981,45.74 79.981,41.328 81.522,39.786 81.522,33.409 80.347,32.234 80.347,28.308 79.391,27.352 76.953,27.352 75.875,26.274 75.859,26.274 73.354,23.769 v4(73.354,22.395)
  other v3: 73.354,22.395
  other v4: 57.676,10.016
PC8: JMISC.5 U3.H13 | length 120.8
  L8 w0.127: v4(59.977,11.714) 60.136,11.873 60.136,11.965 60.365,12.195 61.757,12.195 61.97,12.407 61.97,13.45 62.15,13.629 63.42,13.629 63.96,14.17 64.26,14.17 64.8,14.71 64.8,15.181 64.899,15.28 64.899,16.626 65.214,16.94 65.214,18.324 65.441,18.551 65.441,21.655 65.83,22.044 65.83,22.433 66.714,23.318 67.428,23.318 v3(67.441,23.331)
  BOTTOM_L10 w0.127: U3.H13@57.963,10.529 58.4,10.966 58.4,11.48 58.634,11.714 v4(59.977,11.714) ; JMISC.5@62.249,99.629 62.249,96.919 57.085,91.755 57.085,74.788 69.5,62.373 69.5,62.033 74.196,57.337 76.014,57.337 81.567,51.783 81.567,47.968 79.527,45.928 79.527,41.14 81.068,39.598 81.068,33.597 79.893,32.422 79.893,28.864 79.561,28.533 77.192,28.533 76.703,28.044 76.703,27.743 75.687,26.728 75.671,26.728 73.744,24.801 68.736,24.801 68.1,24.164 68.1,24.159 67.812,23.872 67.812,23.702 v3(67.441,23.331)
  other v3: 59.977,11.714
  other v4: 67.441,23.331
PC9: D81.2 J13.3 R375.1 TP73.X U3.G14 | length 54.6
  TOP_L1 w0.127: J13.3@22.417,5.024 22.417,5.5 21.851,6.066 21.851,6.55 21.777,6.624 21.191,6.624 R375.1@21.191,7.324 21.191,7.557 21.552,7.918 23.774,7.918 24.319,7.373 24.319,4.73 26.212,2.837 26.212,1.973 27.256,0.929 41.263,0.929 41.702,1.368 41.702,3.068 v3(42.063,3.429)
  L8 w0.127: v3(42.063,3.429) 42.734,4.1 45.441,4.1 46.042,3.499 46.601,3.499 v3(47,3.1) ; v4(47.927,4.739) 47.927,5.369 49.911,7.353 55.136,7.353 v4(55.406,7.083)
  BOTTOM_L10 w0.127: v3(42.063,3.429) 41.663,3.829 41.663,4.429 42.314,5.08 TP73.X@43.18,5.08 ; v3(47,3.1) 47.927,4.027 v4(47.927,4.739) ; v4(55.406,7.083) 55.699,7.376 55.699,7.965 55.963,8.229 56.363,8.229 56.763,8.629 56.763,9.329 U3.G14@57.163,9.729
  other v1: 42.063,3.429
  other v2: 42.063,3.429
  other v3: 47.927,4.739 55.406,7.083
  other v4: 47,3.1 42.063,3.429
  other v5: 42.063,3.429
PC10: JSPI.3 U3.D12 | length 44.1
  TOP_L1 w0.127: v2(60.926,24.075) 60.895,24.075 60.063,24.907 60.063,27.529 60.474,27.94 JSPI.3@62.167,27.94
  L8 w0.127: v4(43.163,16.829) 43.742,17.408 43.742,17.441 44.688,18.387 46.339,18.387 47.897,19.945 48.04,19.945 48.8,20.705 48.8,21.094 49.283,21.577 49.672,21.577 50.061,21.965 50.314,21.965 50.527,22.178 50.527,22.41 51.93,23.813 60.664,23.813 v2(60.926,24.075) ; v3(43.463,12.029) 43.702,12.268 45.023,12.268 45.2,12.444 46.222,12.444 46.262,12.485 46.878,12.485 46.958,12.404 47.65,12.404 47.787,12.268 53.125,12.268 53.163,12.229 53.497,12.229 54.397,11.329 v4(54.763,11.329)
  BOTTOM_L10 w0.127: v4(43.163,16.829) 43.163,16.806 43.311,16.658 43.311,12.195 43.463,12.042 v3(43.463,12.029)
  other v1: 60.926,24.075
  other v3: 54.763,11.329 43.163,16.829
  other v4: 43.463,12.029
  other v5: 60.926,24.075
PC11: JMISC.9 U3.B14 | length 124.4
  L8 w0.127: v3(59.975,14.868) 62.531,14.868 63.569,15.906 63.569,16.272 63.991,16.694 63.991,17.002 64.306,17.316 64.306,18.7 64.533,18.927 64.533,22.031 64.922,22.42 64.922,22.81 66.673,24.561 v3(67.13,24.561)
  BOTTOM_L10 w0.127: U3.B14@53.163,9.729 52.8,10.093 52.8,10.68 53.049,10.929 54.877,10.929 55.181,11.233 55.181,11.461 55.44,11.72 56.604,11.72 56.793,11.909 56.793,12.409 56.833,12.449 56.969,12.449 56.996,12.476 57.047,12.476 57.064,12.492 58.914,12.492 59.863,12.492 59.975,12.604 v3(59.975,14.868) ; JMISC.9@59.709,99.629 59.709,96.569 56.177,93.037 56.177,74.412 68.592,61.996 68.592,61.657 72.676,57.573 73.249,57 73.893,56.356 75.711,56.356 80.659,51.407 80.659,48.344 78.619,46.304 78.619,40.69 80.16,39.149 80.16,33.973 78.985,32.798 78.985,30.585 77.841,29.441 76.816,29.441 75.795,28.42 75.795,28.12 75.311,27.636 75.294,27.636 73.368,25.709 68.278,25.709 v3(67.13,24.561)
  other v4: 59.975,14.868 67.13,24.561
PC12: JSPI.4 U3.B15 | length 41.3
  L8 w0.127: v4(45.423,16.716) 47.064,16.716 51.895,21.546 58.016,21.546 58.022,21.552 60.412,21.552 60.481,21.483 62.411,21.483 62.717,21.789 62.717,22.783 63.106,23.172 63.106,23.562 65.453,25.909 v4(65.453,26.926)
  BOTTOM_L10 w0.127: v4(45.423,16.716) 45.423,14.778 46.163,14.038 46.163,11.271 46.282,11.153 46.393,11.041 49.98,11.041 51.705,9.316 52.776,9.316 U3.B15@53.163,8.929 ; v4(65.453,26.926) 66.53,26.926 67.047,27.443 v3(67.047,27.51)
  other v1: 67.047,27.51
  other v2: 67.047,27.51
  other v3: 45.423,16.716 65.453,26.926
  other v4: 67.047,27.51
  other v5: 67.047,27.51
PCIE1_REFCLK0_N: U12.33 U34.W35 | length 20.2
  TOP_L1 w0.127: v4(35.955,33.07) 35.988,33.07 36.017,33.099 U34.W35@36.871,33.099
  BOTTOM_L10 w0.122: U12.33@27.5,25.16 27.589,25.071 27.788,25.071 27.796,25.062 28.112,25.062 28.406,25.356 29.77,25.356 30.733,25.356 31.037,25.052 31.037,24.513 31.163,24.387 31.541,24.387 31.667,24.513 31.667,25.306 31.972,25.611 32.602,25.611 32.907,25.306 32.907,24.513 33.033,24.387 33.41,24.387 33.536,24.513 33.536,25.186 34.022,25.672 34.56,26.21 34.56,27.325 34.738,27.504 35.1,27.866 35.1,30.903 34.572,31.43 34.572,32.371 34.751,32.55 34.895,32.693 35.073,32.872 35.757,32.872 v4(35.955,33.07)
  other v1: 35.955,33.07
  other v2: 35.955,33.07
  other v3: 35.955,33.07
  other v5: 35.955,33.07
PCIE1_REFCLK0_P: U12.34 U34.U35 | length 20.3
  TOP_L1 w0.127: v5(35.955,32.37) 36.184,32.599 U34.U35@36.871,32.599
  BOTTOM_L10 w0.122: U12.34@27.5,24.66 27.589,24.749 27.788,24.749 27.796,24.758 28.239,24.758 28.533,25.052 29.77,25.052 30.606,25.052 30.732,24.926 30.732,24.387 31.037,24.082 31.667,24.082 31.972,24.387 31.972,25.18 32.098,25.306 32.476,25.306 32.602,25.18 32.602,24.387 32.906,24.082 33.537,24.082 33.841,24.387 33.841,25.06 34.117,25.336 34.864,26.083 34.864,27.199 35.405,27.74 35.405,31.029 34.877,31.557 34.877,32.245 35.199,32.567 35.757,32.567 v5(35.955,32.37)
  other v1: 35.955,32.37
  other v2: 35.955,32.37
  other v3: 35.955,32.37
  other v4: 35.955,32.37
PCIE1_RX0_N: U12.36 U34.B30 | length 18.8
  TOP_L1 w0.127: U34.B30@38.591,28.679 38.591,28.954 38.795,29.157 38.836,29.157 v2(38.86,29.181)
  BOTTOM_L10 w0.122: U12.36@27.5,23.66 27.589,23.571 27.788,23.571 27.796,23.562 28.274,23.562 28.629,23.207 30.123,23.207 33.643,23.207 34.257,23.207 35.65,24.6 35.65,26.901 35.861,27.112 36.322,27.573 36.322,30.103 36.608,30.389 38.219,30.389 38.458,30.149 38.712,29.895 38.712,29.352 38.86,29.205 v2(38.86,29.181)
  other v1: 38.86,29.181
  other v3: 38.86,29.181
  other v4: 38.86,29.181
  other v5: 38.86,29.181
PCIE1_RX0_P: U12.37 U34.B32 | length 18.8
  TOP_L1 w0.127: U34.B32@38.091,28.679 38.091,29.012 v3(38.26,29.181)
  BOTTOM_L10 w0.122: U12.37@27.5,23.16 27.589,23.249 27.788,23.249 27.796,23.258 28.147,23.258 28.413,22.992 28.502,22.903 30.123,22.903 33.643,22.903 34.384,22.903 34.789,23.308 35.098,23.617 cw(c35.231,23.484) 35.364,23.617 35.395,23.587 ccw(c35.528,23.72) 35.66,23.587 ccw(c35.528,23.72) 35.66,23.853 35.63,23.883 cw(c35.763,24.016) 35.63,24.149 35.879,24.398 35.955,24.474 35.955,24.709 35.955,26.775 35.987,26.807 36.627,27.447 36.627,29.977 36.734,30.084 38.092,30.084 38.242,29.934 38.408,29.769 38.408,29.352 38.26,29.205 v3(38.26,29.181)
  other v1: 38.26,29.181
  other v2: 38.26,29.181
  other v4: 38.26,29.181
  other v5: 38.26,29.181
PCIE1_TX0_25_N: C307.2 U34.A29 | length 1.2
  TOP_L1 w0.122: U34.A29@38.841,28.129 38.841,28.054 38.744,27.956 38.744,27.366 38.849,27.261 38.849,27.194 38.942,27.102 C307.2@38.946,27.102
PCIE1_TX0_25_P: C299.2 U34.A31 | length 1.2
  TOP_L1 w0.122: C299.2@38.246,27.102 38.251,27.102 38.343,27.194 38.343,27.271 38.439,27.366 38.439,27.956 38.341,28.054 U34.A31@38.341,28.129
PCIE1_TX0_CAP_N: C307.1 U12.39 | length 20.1
  TOP_L1 w0.122: C307.1@38.946,26.552 38.942,26.552 38.749,26.358 38.749,25.932 39.151,25.53 39.151,23.719 39.313,23.557 v2(39.567,23.557)
  BOTTOM_L10 w0.122: U12.39@27.5,22.16 27.589,22.071 27.788,22.071 27.792,22.067 28.954,22.067 29.372,21.649 34.926,21.649 35.616,21.649 cw(c35.616,21.029) 36.236,21.029 36.236,20.224 ccw(c36.551,20.224) 36.551,19.909 ccw(c36.551,20.224) 36.866,20.224 36.866,22.072 cw(c37.816,22.072) 37.144,22.744 ; 37.145,22.745 37.465,23.065 38.081,23.681 38.992,23.681 39.116,23.557 v2(39.567,23.557)
  other v1: 39.567,23.557
  other v3: 39.567,23.557
  other v4: 39.567,23.557
  other v5: 39.567,23.557
PCIE1_TX0_CAP_P: C299.1 U12.40 | length 20.1
  TOP_L1 w0.122: C299.1@38.246,26.552 38.251,26.552 38.444,26.358 38.444,25.806 38.846,25.404 38.846,23.592 39.072,23.366 v4(39.072,23.062)
  BOTTOM_L10 w0.122: U12.40@27.5,21.66 27.589,21.749 27.788,21.749 27.8,21.762 28.827,21.762 29.245,21.344 31.197,21.344 31.888,21.344 31.888,21.323 32.518,21.323 32.518,21.344 33.15,21.344 34.926,21.344 35.616,21.344 cw(c35.616,21.029) 35.931,21.029 35.931,20.224 ccw(c36.551,20.224) 36.551,19.605 ccw(c36.551,20.224) 37.171,20.224 37.171,22.072 cw(c37.816,22.072) 37.36,22.529 37.465,22.634 38.207,23.376 38.866,23.376 39.048,23.193 39.048,23.086 v4(39.072,23.062)
  other v1: 39.072,23.062
  other v2: 39.072,23.062
  other v3: 39.072,23.062
  other v5: 39.072,23.062
PCIE2_REFCLK0_N: U24.B41 U34.AC35 | length 62.3
  TOP_L1 w0.122: v2(36.471,34.099) U34.AC35@36.871,34.099
  L3 w0.117: v2(36.471,34.099) 36.507,34.099 36.605,34.001 37.922,34.001 38.951,32.973 39.873,32.973 40.051,32.794 40.129,32.717 40.307,32.538 40.307,29.844 40.812,29.34 40.901,29.25 40.901,27.563 43.187,25.277 45.278,25.277 48.719,28.718 48.719,36.552 51.782,39.616 52.573,39.616 52.632,39.616 52.706,39.69 52.706,39.775 52.78,39.849 53.002,39.849 53.077,39.775 53.077,39.69 53.151,39.616 53.373,39.616 53.447,39.69 53.522,39.764 53.744,39.764 53.818,39.69 53.892,39.616 55.084,39.616 60.255,39.616 60.433,39.437 62.443,37.427 62.443,32.645 64.277,30.811 72.491,30.811 73.382,29.921 73.382,29.393 73.519,29.256 73.614,29.256 73.73,29.139 v2(73.766,29.139)
  other v1: 73.766,29.139 36.471,34.099
PCIE2_REFCLK0_P: U24.A45 U34.AA35 | length 62.3
  TOP_L1 w0.122: v2(36.471,33.599) U34.AA35@36.871,33.599
  L3 w0.117: v2(36.471,33.599) 36.507,33.599 36.605,33.697 37.796,33.697 38.825,32.668 39.746,32.668 40.003,32.412 40.003,29.718 40.092,29.629 40.596,29.124 40.596,27.436 43.061,24.972 45.404,24.972 49.024,28.592 49.024,36.426 51.122,38.524 51.909,39.311 60.129,39.311 62.139,37.301 62.139,32.519 64.151,30.507 72.365,30.507 73.077,29.795 73.077,29.266 73.509,28.834 73.676,28.834 v2(73.991,28.519)
  other v1: 73.991,28.519 36.471,33.599
PCIE2_RX0_N: C325.1 U34.A27 | length 7.2
  TOP_L1 w0.122: v1(36.775,26.575) 36.782,26.568 37.061,26.568 37.273,26.357 37.273,26.018 37.079,25.825 C325.1@37.075,25.825
  L3 w0.117: v1(36.775,26.575) 36.775,26.876 36.57,27.081 36.57,27.213 36.57,27.295 36.314,27.551 36.314,27.772 36.535,27.993 36.756,27.993 36.77,27.98 36.99,27.98 37.149,28.138 37.914,28.138 38.341,27.711 38.905,27.148 39.239,27.148 39.486,27.395 39.486,27.994 39.351,28.129 v2(39.341,28.129)
  other v1: 39.341,28.129
  other v2: 36.775,26.575
PCIE2_RX0_P: C324.1 U34.B26 | length 7.3
  TOP_L1 w0.122: v1(37.27,27.07) 37.277,27.063 37.277,26.784 37.577,26.483 37.577,26.018 37.771,25.825 C324.1@37.775,25.825
  L3 w0.117: v1(37.27,27.07) 37.012,27.07 36.875,27.207 36.875,27.433 37.275,27.833 37.788,27.833 38.778,26.843 39.365,26.843 39.791,27.269 39.791,28.327 39.611,28.507 39.611,28.66 v1(39.591,28.679)
  other v2: 37.27,27.07 39.591,28.679
PCIE2_TX0_25_N: C323.2 U34.A23 | length 49.2
  TOP_L1 w0.122: 40.333,27.843 40.319,27.829 ; U34.A23@40.341,28.129 40.319,28.107 40.319,27.829 ; v5(40.391,26.374) 40.244,26.521 40.244,27.753 40.319,27.829 ; v1(55.52,30.803) 55.69,30.633 58.802,30.633 60.449,32.28 60.51,32.28 60.571,32.28 60.697,32.406 60.697,32.659 60.823,32.785 61.201,32.785 61.327,32.659 61.327,32.406 61.453,32.28 61.831,32.28 61.957,32.406 61.957,32.659 62.083,32.785 62.461,32.785 62.587,32.659 62.587,32.406 62.713,32.28 63.783,32.28 63.801,32.28 65.175,30.906 65.175,27.175 65.375,26.975 65.682,26.668 69.248,26.668 69.569,26.348 69.698,26.348 69.856,26.506 C323.2@69.856,26.51
  L8 w0.117: v5(40.391,26.374) 40.391,26.311 40.244,26.164 40.244,24.995 40.423,24.816 40.53,24.709 43.503,24.709 44.078,24.709 44.938,25.569 45.477,25.569 45.763,25.569 46.049,25.855 46.049,26.141 45.842,26.347 45.842,26.886 46.307,27.35 46.845,27.35 47.634,26.561 47.92,26.561 48.206,26.847 48.206,27.133 47.377,27.962 47.377,28.501 47.842,28.965 48.38,28.965 49.292,28.053 49.578,28.053 49.864,28.339 49.864,28.625 49.198,29.291 49.198,29.829 49.392,30.023 49.975,30.606 52.287,30.606 52.345,30.606 52.419,30.68 52.419,30.736 52.493,30.81 52.716,30.81 52.79,30.736 52.79,30.68 52.864,30.606 53.087,30.606 53.161,30.68 53.161,30.736 53.235,30.81 53.458,30.81 53.532,30.736 53.532,30.68 53.606,30.606 54.284,30.606 55.293,30.606 55.491,30.803 v1(55.52,30.803)
  other v1: 40.391,26.374
  other v2: 40.391,26.374 55.52,30.803
  other v5: 55.52,30.803
PCIE2_TX0_25_P: C322.2 U34.A25 | length 47.8
  TOP_L1 w0.122: v1(39.791,26.374) 39.939,26.521 39.939,27.753 39.864,27.829 39.864,28.107 U34.A25@39.841,28.129 ; v2(55.52,30.103) 55.745,30.329 58.929,30.329 60.575,31.975 63.675,31.975 64.87,30.78 64.87,27.049 65.049,26.87 65.555,26.364 69.122,26.364 69.443,26.043 69.702,26.043 69.86,25.885 C322.2@69.86,25.881
  L8 w0.117: v1(39.791,26.374) 39.791,26.311 39.939,26.164 39.939,24.869 40.225,24.583 40.403,24.404 41.354,24.404 43.63,24.404 44.204,24.404 45.064,25.264 45.35,25.264 45.889,25.264 46.353,25.729 46.353,26.267 46.147,26.474 46.147,26.76 46.433,27.045 46.719,27.045 47.508,26.256 48.047,26.256 48.511,26.721 48.511,27.259 47.682,28.088 47.682,28.374 47.968,28.66 48.254,28.66 49.166,27.748 49.705,27.748 50.169,28.213 50.169,28.751 49.503,29.417 49.503,29.703 49.608,29.808 50.101,30.301 55.293,30.301 55.491,30.103 v2(55.52,30.103)
  other v1: 55.52,30.103
  other v2: 39.791,26.374
  other v5: 39.791,26.374 55.52,30.103
PCIE2_TX0_CAP_N: C323.1 U24.A42 | length 4
  TOP_L1 w0.122: C323.1@70.406,26.51 70.406,26.506 70.564,26.348 72.224,26.348 72.367,26.491 72.367,27.377 72.201,27.543 72.201,28.34 U24.A42@72.191,28.349
PCIE2_TX0_CAP_P: C322.1 U24.B39 | length 5.4
  TOP_L1 w0.122: C322.1@70.41,25.881 70.41,25.885 70.568,26.043 72.35,26.043 72.671,26.364 72.671,27.503 72.505,27.669 72.505,28.963 72.666,29.124 U24.B39@72.666,29.199
PD0: U3.E10 U7.4 | length 136.9
  L8 w0.127: v4(43.6,13.093) 43.608,13.085 44.877,13.085 44.946,13.154 45.969,13.154 45.98,13.166 47.16,13.166 47.2,13.125 47.892,13.125 47.933,13.085 55.401,13.085 55.556,12.929 v3(55.563,12.929) ; v3(43.623,16.816) 43.623,16.824 43.969,17.17 43.969,17.347 44.782,18.16 47.225,18.16 51.519,22.454 54.763,22.454 55.45,23.141 60.675,23.141 60.901,23.367 60.901,23.536 61.29,23.925 61.29,24.314 62.155,25.18 62.155,29.947 61.845,30.257 61.845,36.519 67.984,42.658 71.592,42.658 72.363,43.429 72.363,46.113 73.463,47.212 74.547,47.212 75.141,47.807 75.141,50.035 72.284,52.892 72.284,61.507 74.796,64.019 74.796,78.189 82.988,86.381 82.988,93 82.142,93.847 82.142,95.14 82.496,95.494 82.496,97.51 81.627,98.379 81.627,103.253 81.835,103.461 81.835,105.014 v3(81.644,105.205)
  BOTTOM_L10 w0.127: v4(43.6,13.093) 43.611,13.104 43.611,16.804 v3(43.623,16.816) ; U7.4@80.103,104.478 79.469,104.478 79.357,104.59 79.357,105.093 79.469,105.205 v3(81.644,105.205)
  other v3: 43.6,13.093
  other v4: 55.563,12.929 43.623,16.816 81.644,105.205
PD1: U3.C12 U7.1 | length 133.1
  L8 w0.127: v4(43.994,11.969) 45.046,11.969 45.294,12.217 46.316,12.217 46.357,12.258 46.784,12.258 46.864,12.177 47.556,12.177 47.693,12.041 52.753,12.041 53.465,11.329 v4(53.963,11.329) ; v3(44.023,16.816) 44.023,16.824 44.196,16.997 44.196,17.253 44.876,17.933 47.319,17.933 51.613,22.227 54.857,22.227 55.479,22.849 60.704,22.849 61.128,23.272 61.128,23.442 61.517,23.831 61.517,24.22 62.382,25.086 62.382,30.041 62.072,30.351 62.072,36.388 68.086,42.402 71.699,42.402 72.62,43.323 72.62,46.007 73.569,46.956 74.653,46.956 75.368,47.672 75.368,50.129 72.538,52.959 72.538,61.308 75.023,63.793 75.023,78.095 83.215,86.287 83.215,93.094 82.369,93.941 82.369,95.046 82.723,95.4 82.723,97.604 82.003,98.324 v3(82.003,101.878)
  BOTTOM_L10 w0.127: v4(43.994,11.969) 43.994,12.461 44.009,12.475 44.009,16.802 v3(44.023,16.816) ; U7.1@80.103,102.528 79.453,102.528 79.338,102.413 79.338,101.99 79.449,101.878 v3(82.003,101.878)
  other v3: 53.963,11.329 43.994,11.969
  other v4: 44.023,16.816 82.003,101.878
PD3: JMISC.11 U3.A14 | length 129.2
  L8 w0.127: v4(52.363,9.729) 55.857,9.729 55.882,9.705 56.121,9.705 56.325,9.5 58.77,9.5 58.983,9.712 59.033,9.712 59.631,10.311 60.173,10.311 60.319,10.165 61.902,10.165 63.758,12.022 63.758,13.004 64.242,13.489 64.542,13.489 65.481,14.428 65.481,14.899 66.258,15.676 66.258,16.508 66.197,16.57 66.197,19.994 66.731,20.528 69.676,20.528 70.571,21.423 73.076,21.423 76.616,24.963 78.94,24.963 79.094,24.81 81.418,24.81 84.34,27.732 84.34,33.004 83.024,34.32 83.024,43.031 81.686,44.369 81.686,49.24 81.265,49.66 81.265,49.94 v3(79.746,51.459)
  BOTTOM_L10 w0.127: JMISC.11@58.439,99.629 58.439,97.65 57.152,96.363 57.152,94.933 55.723,93.504 55.723,74.224 68.138,61.808 68.138,61.468 73.776,55.831 75.375,55.831 v3(79.746,51.459)
  other v3: 52.363,9.729
  other v4: 79.746,51.459
PD5: JOMEGA.86 U3.B12 | length 60.9
  L8 w0.127: v4(28.971,36.343) 28.971,35.633 28.8,35.462 28.8,34.8 27.426,33.426 27.426,28.927 27.892,28.462 27.892,22.18 27.98,22.091 27.98,22.02 31.737,18.263 31.737,16.663 35.7,12.7 35.7,11.999 35.952,11.747 36.249,11.747 36.302,11.8 36.6,11.8 36.848,12.048 42.552,12.048 42.919,11.681 45.078,11.681 45.367,11.969 46.389,11.969 46.451,12.031 46.69,12.031 46.77,11.95 47.462,11.95 47.612,11.8 52.586,11.8 v3(52.835,11.551)
  BOTTOM_L10 w0.127: JOMEGA.86@19.476,42.35 19.476,38.662 20.928,37.211 25.7,37.211 26.621,36.29 27.528,36.29 27.581,36.343 v4(28.971,36.343) ; v3(52.835,11.551) 53.057,11.329 U3.B12@53.163,11.329
  other v3: 28.971,36.343
  other v4: 52.835,11.551
PD9: JOMEGA.94 U3.P15 | length 76.7
  L8 w0.127: v3(27.248,35.378) 27.248,34.945 26.291,33.988 26.291,26.524 26.707,26.108 26.707,21.343 30.457,17.593 30.457,16.156 34.565,12.048 34.565,11.529 36.14,9.954 44.367,9.954 44.386,9.934 44.813,9.934 44.833,9.954 50.419,9.954 51.557,8.815 55.258,8.815 55.444,8.629 60.919,8.629 61.219,8.929 61.76,8.929 61.954,8.735 v4(61.954,7.682)
  BOTTOM_L10 w0.127: JOMEGA.94@14.396,42.35 14.396,39.192 16.476,37.112 19.427,37.112 20.009,36.53 25.418,36.53 26.551,35.396 27.23,35.396 v3(27.248,35.378) ; v4(61.954,7.682) 62.763,8.491 U3.P15@62.763,8.929
  other v3: 61.954,7.682
  other v4: 27.248,35.378
PD10: R208_3.2 U3.N14 | length 27.8
  TOP_L1 w0.127: R208_3.2@79.65,0.975 79.984,1.308 79.984,2.068 v2(79.765,2.286)
  BOTTOM_L10 w0.127: U3.N14@61.963,9.729 62.368,9.324 62.368,8.503 61.173,7.309 61.173,4.668 62.079,3.762 64.224,3.762 64.626,3.36 64.626,2.15 64.791,1.985 79.478,1.985 79.765,2.273 v2(79.765,2.286)
  other v1: 79.765,2.286
  other v3: 79.765,2.286
  other v4: 79.765,2.286
  other v5: 79.765,2.286
PD11: R205_2.2 U3.N15 | length 27.2
  TOP_L1 w0.127: v4(80.343,2.251) 80.347,2.247 80.347,1.528 R205_2.2@80.35,1.525
  BOTTOM_L10 w0.127: U3.N15@61.963,8.929 61.963,8.572 60.946,7.555 60.946,4.574 61.985,3.535 64.13,3.535 64.399,3.266 64.399,2.056 64.696,1.758 80.15,1.758 80.343,1.952 v4(80.343,2.251)
  other v1: 80.343,2.251
  other v2: 80.343,2.251
  other v3: 80.343,2.251
  other v5: 80.343,2.251
PD12: JOMEGA.47 U3.M14 | length 80.2
  L8 w0.127: v3(43.606,47.41) 42.256,48.76 39.476,48.76 27.659,36.943 27.659,35.035 26.518,33.894 26.518,26.732 26.934,26.316 26.934,21.437 30.829,17.542 30.829,16.287 34.792,12.324 34.792,11.623 35.869,10.546 44.096,10.546 44.48,10.161 44.719,10.161 44.739,10.181 51.012,10.181 52.15,9.042 55.352,9.042 55.538,8.856 60.825,8.856 61.163,9.195 v3(61.163,9.729)
  BOTTOM_L10 w0.127: JOMEGA.47@43.606,46 v3(43.606,47.41)
  other v4: 61.163,9.729 43.606,47.41
PD13: JOMEGA.49 U3.L13 | length 77
  L8 w0.127: v3(42.336,47.41) 42.336,47.956 42.063,48.229 39.315,48.229 27.886,36.8 27.886,34.941 26.745,33.8 26.745,26.826 26.883,26.689 27.161,26.41 27.161,21.531 31.056,17.636 31.056,16.381 35.019,12.418 35.019,11.717 35.736,11 42.316,11 42.543,10.773 45.454,10.773 45.681,11 51.765,11 52.521,10.244 52.577,10.244 52.581,10.24 55.841,10.24 55.882,10.282 56.121,10.282 56.639,9.763 57.521,9.763 57.557,9.727 58.142,9.727 58.354,9.939 58.939,9.939 59.537,10.538 60.354,10.538 v4(60.363,10.529)
  BOTTOM_L10 w0.127: JOMEGA.49@42.336,46 v3(42.336,47.41)
  other v3: 60.363,10.529
  other v4: 42.336,47.41
PD14: JOMEGA.51 U3.J11 | length 69.8
  L8 w0.127: v4(41.066,47.41) 40.433,46.776 39.139,46.776 29.26,36.897 29.26,36.005 29.218,35.963 29.218,35.309 29.079,35.17 29.079,34.493 27.75,33.164 27.75,28.925 28.119,28.556 28.119,22.274 32.312,18.08 32.312,16.698 36.5,12.511 43.216,12.511 43.427,12.722 44.835,12.722 45.012,12.898 46.034,12.898 46.074,12.939 47.066,12.939 47.147,12.858 47.838,12.858 47.975,12.722 53.646,12.722 53.898,12.47 54.68,12.47 55.518,11.631 57.272,11.631 57.891,12.249 58.192,12.249 58.405,12.036 58.405,11.906 58.418,11.919 58.554,11.919 v4(58.763,12.129)
  BOTTOM_L10 w0.127: JOMEGA.51@41.066,46 v4(41.066,47.41)
  other v3: 58.763,12.129 41.066,47.41
PD15: JOMEGA.53 U3.K12 | length 70.6
  L8 w0.127: v3(39.796,47.41) 39.773,47.386 39.428,47.386 28.683,36.641 28.683,35.666 28.573,35.556 28.573,34.986 27.199,33.612 27.199,27.014 27.615,26.598 27.615,21.719 31.51,17.824 31.51,16.569 35.473,12.606 35.473,11.905 35.924,11.454 42.504,11.454 42.731,11.227 45.266,11.227 45.493,11.454 51.959,11.454 52.448,10.966 58.914,10.966 59.277,11.329 v4(59.563,11.329)
  BOTTOM_L10 w0.127: JOMEGA.53@39.796,46 v3(39.796,47.41)
  other v3: 59.563,11.329
  other v4: 39.796,47.41
PE1: JMISC.7 U3.B5 | length 128.6
  L8 w0.127: v4(50.479,25.406) 50.502,25.43 50.502,25.553 51.266,26.317 v4(61.385,26.317) ; v3(51.877,17.762) 52.195,17.444 52.195,17.277 52.543,16.929 v3(53.163,16.929)
  BOTTOM_L10 w0.127: v4(50.479,25.406) 50.733,25.152 50.733,18.103 51.02,17.816 51.498,17.816 51.552,17.762 v3(51.877,17.762) ; JMISC.7@60.979,99.629 60.979,96.65 56.631,92.302 56.631,74.6 69.046,62.184 69.046,61.845 72.676,58.215 73.891,57 74.057,56.834 75.875,56.834 81.113,51.595 81.113,48.156 79.073,46.116 79.073,40.952 80.614,39.41 80.614,33.785 79.439,32.61 79.439,29.098 79.328,28.987 77.004,28.987 76.249,28.232 76.249,27.931 75.499,27.182 75.482,27.182 73.556,25.255 68.548,25.255 67.646,24.352 67.646,24.347 67.344,24.045 66.917,24.045 64.654,26.308 61.393,26.308 v4(61.385,26.317)
  other v3: 50.479,25.406 61.385,26.317
  other v4: 53.163,16.929 51.877,17.762
PE2: JMISC.2 U3.B3 | length 135.5
  L8 w0.127: v4(51.545,25.465) 52.112,25.465 52.151,25.504 52.439,25.504 52.516,25.427 v4(60.688,25.427)
  BOTTOM_L10 w0.127: v4(51.545,25.465) 51.545,25.434 51.649,25.33 51.649,19.098 51.798,18.949 52.525,18.949 52.905,18.569 53.123,18.569 U3.B3@53.163,18.529 ; v4(60.688,25.427) 62.467,25.427 62.556,25.516 64.302,25.516 67.047,22.771 67.61,22.771 68.266,23.427 68.266,23.66 68.954,24.347 72.346,24.347 72.98,23.713 72.98,22.26 73.133,22.107 73.473,22.107 73.642,22.276 73.642,23.736 75.953,26.047 75.969,26.047 77.047,27.125 79.485,27.125 80.574,28.214 80.574,32.14 81.749,33.315 81.749,39.88 80.208,41.422 80.208,45.646 82.248,47.686 82.248,52.066 76.344,57.97 74.526,57.97 70.181,62.315 70.181,62.655 57.766,75.07 57.766,91.473 64.173,97.88 64.173,101.222 64.789,101.838 JMISC.2@64.789,103.277
  other v3: 60.688,25.427 51.545,25.465
PE3: JMISC.4 U3.D5 | length 134.9
  L8 w0.127: v4(51.187,25.477) 51.187,25.51 51.256,25.58 51.256,25.585 51.425,25.754 52.32,25.754 52.342,25.731 v3(60.898,25.731) ; v3(51.868,18.489) 52.288,18.489 52.419,18.619 52.908,18.619 53.035,18.492 53.458,18.492 53.898,18.052 54.932,18.052 55.081,17.903 55.081,17.247 v4(54.763,16.929)
  BOTTOM_L10 w0.127: v4(51.187,25.477) 51.187,19.17 v3(51.868,18.489) ; v3(60.898,25.731) 62.45,25.731 62.485,25.765 64.555,25.765 67.278,23.042 67.56,23.042 68.039,23.521 68.039,23.778 68.327,24.065 68.327,24.07 68.83,24.574 73.838,24.574 75.765,26.501 75.781,26.501 76.916,27.636 78.985,27.636 80.12,28.77 80.12,32.328 81.295,33.503 81.295,39.692 79.754,41.234 79.754,45.834 81.794,47.874 81.794,51.877 76.124,57.548 74.306,57.548 69.727,62.127 69.727,62.467 57.312,74.882 57.312,91.661 62.944,97.293 62.944,101.263 63.519,101.838 JMISC.4@63.519,103.277
  other v3: 54.763,16.929 51.187,25.477
  other v4: 51.868,18.489 60.898,25.731
PE4: JMISC.6 U3.C4 | length 132.4
  L8 w0.127: v3(50.834,25.477) 50.834,25.51 50.898,25.574 50.898,25.596 51.345,26.043 52.351,26.043 52.362,26.031 56.51,26.031 56.52,26.021 v4(61.138,26.021)
  BOTTOM_L10 w0.127: v3(50.834,25.477) 50.858,25.453 50.858,25.348 50.96,25.246 50.96,18.492 51.303,18.149 53.508,18.149 53.719,17.938 53.754,17.938 U3.C4@53.963,17.729 ; v4(61.138,26.021) 64.62,26.021 66.823,23.818 67.438,23.818 67.873,24.253 67.873,24.258 68.642,25.028 73.65,25.028 75.576,26.955 75.593,26.955 76.476,27.837 76.476,28.138 77.098,28.76 79.467,28.76 79.666,28.958 79.666,32.516 80.841,33.691 80.841,39.504 79.3,41.046 79.3,46.022 81.34,48.062 81.34,51.689 75.903,57.126 74.086,57.126 69.273,61.939 69.273,62.278 56.858,74.694 56.858,91.849 61.601,96.592 61.601,101.19 62.249,101.838 JMISC.6@62.249,103.277
  other v3: 61.138,26.021
  other v4: 50.834,25.477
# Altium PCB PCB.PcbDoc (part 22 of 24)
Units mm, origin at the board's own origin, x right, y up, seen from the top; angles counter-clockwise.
Board outline 100 x 160 mm, 10 copper layers (TOP_L1, L2, L3, L4, L5, L6, L7, L8, L9, BOTTOM_L10), stack 1.946 mm thick; 1358 components, 1149 nets, 6777 pads, 10914 vias.

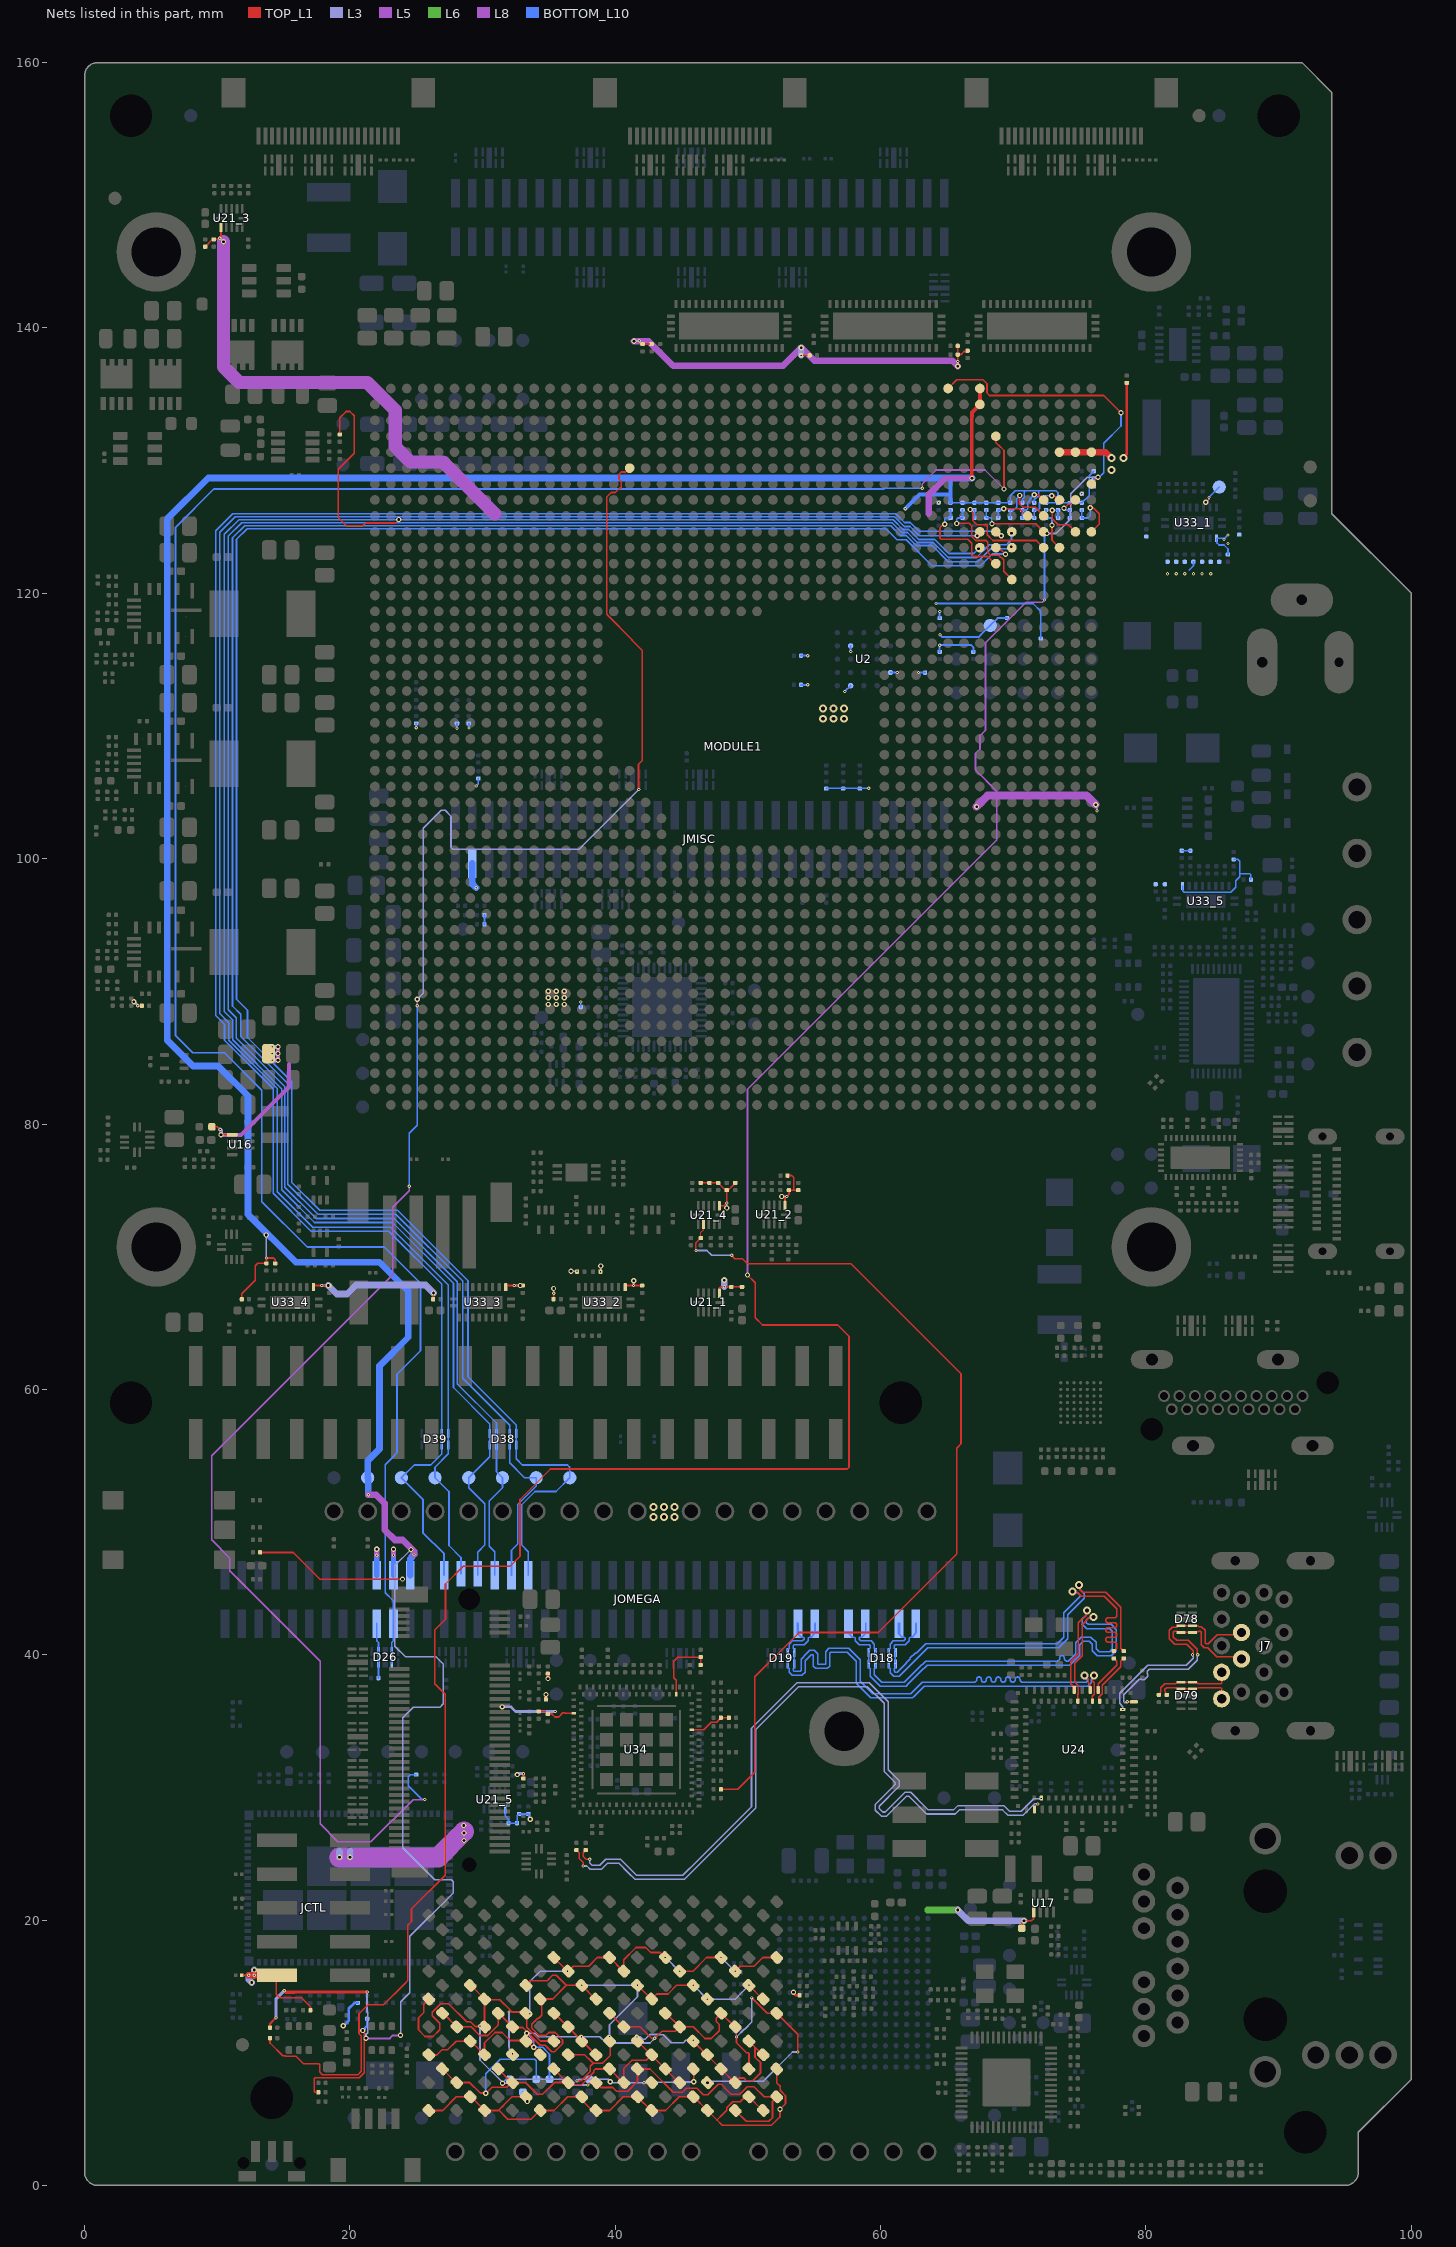
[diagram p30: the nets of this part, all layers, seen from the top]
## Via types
v1: diameter 0.25, hole 0.1, TOP_L1 to L2, tented both sides, 3439 vias
v2: diameter 0.25, hole 0.1, L2 to L3, tented both sides, 2256 vias
v3: diameter 0.25, hole 0.1, L9 to BOTTOM_L10, tented both sides, 1685 vias
v4: diameter 0.25, hole 0.1, L8 to L9, tented both sides, 1675 vias
v5: diameter 0.4, hole 0.2, L3 to L8, tented both sides, 1251 vias
v6: diameter 0.6, hole 0.3, TOP_L1 to BOTTOM_L10, tented both sides, 600 vias
v7: diameter 0.24, hole 0.1, TOP_L1 to L2, tented both sides, 8 vias

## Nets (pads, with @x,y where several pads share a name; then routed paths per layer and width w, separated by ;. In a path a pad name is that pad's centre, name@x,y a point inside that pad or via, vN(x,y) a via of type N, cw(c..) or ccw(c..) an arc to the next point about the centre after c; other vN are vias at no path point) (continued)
ROW6_15: LED31.C LED32.A LED33.C LED34.A LED35.C LED36.A LED37.C LED38.A LED39.C LED40.A LED41.C LED42.A LED55.A LED56.C LED69.A LED70.C LED85.A LED86.C LED103.A LED104.C R200.1 | length 87.8
  TOP_L1 w0.127: LED40.A@25.947,14.05 25.563,13.666 25.563,13.029 25.163,12.629 25.163,11.729 25.663,11.229 26.263,11.229 26.763,11.729 26.763,12.229 26.214,12.778 26.214,13.063 26.849,13.698 27.43,13.698 28.804,12.324 29.089,12.324 29.437,11.976 LED55.A@29.809,11.976 ; LED41.C@29.073,15.075 29.122,15.075 LED42.A@30.147,14.05 LED42.A@30.156,14.042 ; LED55.A@30.139,11.958 30.139,12.467 30.147,12.475 30.147,13.525 30.156,13.533 LED42.A@30.156,14.042 ; v1(31.985,13.073) 32.102,13.19 ; LED69.A@32.247,9.85 v1(32.247,9.918) ; LED56.C@33.326,12.975 33.517,12.975 v2(33.563,12.929) ; LED70.C@35.373,10.875 35.364,10.884 34.352,10.884 33.326,11.91 33.326,12.922 LED56.C@33.273,12.975 33.175,13.073 32.219,13.073 32.102,13.19 ; LED31.C@35.373,17.175 v1(36.398,16.15) ; LED32.A@36.447,16.15 36.822,16.524 37.989,16.524 38.64,17.175 39.047,17.175 39.056,17.184 39.564,17.184 LED33.C@39.573,17.175 40.598,16.15 LED34.A@40.647,16.15 40.639,16.158 40.639,16.667 40.647,16.675 40.647,17.013 41.563,17.929 42.291,17.929 42.664,17.556 43.392,17.556 v2(43.773,17.175) ; v1(37.924,7.566) 37.957,7.566 38.141,7.75 LED85.A@38.547,7.75 38.918,7.379 39.813,7.379 40.093,7.099 40.933,7.099 41.673,7.839 41.673,8.352 41.681,8.36 LED86.C@41.681,8.767 ; LED86.C@41.673,8.775 LED86.C@41.681,8.767 ; LED36.A@44.856,16.142 45.338,16.142 45.346,16.15 45.854,16.15 46.88,17.175 v1(47.973,17.175) ; LED103.A@49.047,5.65 49.868,4.829 51.563,4.829 51.845,5.111 51.845,6.347 LED104.C@52.173,6.675 52.164,6.684 51.758,6.684 51.749,6.675 51.217,6.675 50.449,7.443 49.946,7.443 49.375,6.872 48.72,6.872 48.252,7.34 48.252,7.377 48.006,7.623 47.756,7.623 46.974,6.84 46.642,6.84 46.155,7.326 45.361,7.326 45.063,7.029 44.363,7.029 42.617,8.775 42.198,8.775 42.19,8.767 LED86.C@41.681,8.767 ; v2(49.047,16.15) 49.422,16.524 50.458,16.524 51.109,17.175 LED39.C@52.173,17.175 ; LED42.A@30.156,14.042 30.2,13.997 31.295,13.997 32.102,13.19
  L3 w0.127: v1(29.809,11.998) 29.809,9.451 31.495,7.765 v3(31.495,7.712) 31.934,7.712 32.231,8.009 35.981,8.009 36.449,7.541 37.157,7.541 37.183,7.566 v1(37.924,7.566) ; v1(31.985,13.073) 31.985,10.429 32.014,10.4 32.014,10.152 v1(32.247,9.918) ; v2(33.563,12.929) 33.563,15.366 34.347,16.15 v1(36.398,16.15) ; v2(43.773,17.175) 43.797,17.175 44.823,16.15 v1(44.847,16.15) ; v1(47.973,17.175) 47.997,17.175 49.023,16.15 v2(49.047,16.15)
  BOTTOM_L10 w0.127: v3(31.495,7.712) 31.782,7.998 R200.1@32.239,7.998
  other v1: 33.563,12.929 49.047,16.15 43.773,17.175
  other v2: 37.924,7.566 32.247,9.918 29.809,11.998 31.985,13.073 36.398,16.15 44.847,16.15 47.973,17.175
  other v4: 31.495,7.712
  other v5: 31.495,7.712
ROW7_15: LED43.C LED44.A LED45.C LED46.A LED47.C LED48.A LED49.C LED50.A LED51.C LED52.A LED53.C LED54.A LED55.C LED56.A LED71.A LED72.C LED87.A LED88.C R201.1 | length 66.7
  TOP_L1 w0.127: LED53.C@26.973,12.975 27.022,12.975 28.056,11.942 28.564,11.942 28.573,11.95 29.142,11.95 29.793,11.299 30.384,11.299 31.173,12.087 31.173,12.552 31.181,12.56 LED55.C@31.181,12.967 ; LED55.C@31.173,12.975 LED55.C@31.181,12.967 ; LED43.C@33.273,15.075 33.626,15.429 34.863,15.429 35.263,15.829 35.556,15.829 36.309,15.075 ; LED44.A@34.347,14.05 LED44.A@34.356,14.042 ; LED71.A@36.447,9.85 36.456,9.842 36.964,9.842 36.973,9.85 37.677,9.85 38.329,9.199 ; v1(37.117,7.879) 37.423,7.879 38.124,8.58 38.124,8.994 38.329,9.199 ; LED46.A@38.547,14.05 38.498,14.05 37.464,15.084 36.956,15.084 36.947,15.075 36.309,15.075 ; v1(39.563,11.229) 39.563,10.885 39.626,10.822 39.626,9.792 39.033,9.199 38.329,9.199 ; v2(41.673,15.075) 42.698,14.05 LED48.A@42.747,14.05 43.122,14.424 43.968,14.424 44.619,15.075 v1(45.873,15.075) ; v2(42.167,7.749) 42.191,7.772 42.725,7.772 LED87.A@42.747,7.75 ; LED88.C@45.873,8.775 45.923,8.725 v2(45.922,7.803) ; v1(50.073,15.075) 51.098,14.05 LED52.A@51.147,14.05 ; LED55.C@31.181,12.967 31.206,12.967 32.223,11.95 LED56.A@32.247,11.95 32.3,11.897 33.018,11.897 34.35,10.565 34.728,10.565 35.218,10.075 35.419,10.075 36.024,10.68 36.024,10.965 35.462,11.526 34.974,11.526 34.746,11.299 34.258,11.299 33.696,11.861 33.696,12.145 34.152,12.601 34.235,12.601 34.463,12.829 34.463,13.515 34.445,13.533 34.445,13.952 LED44.A@34.356,14.042 ; LED44.A@34.356,14.042 34.864,14.042 34.873,14.05 35.284,14.05 36.309,15.075
  L3 w0.127: v1(37.117,7.879) 37.15,7.879 37.273,8.002 39.476,8.002 39.624,7.854 v5(39.624,7.811) 39.687,7.749 v2(42.167,7.749) 42.191,7.772 44.655,7.772 44.684,7.801 45.187,7.801 v5@45.921,7.801 ; v1(37.473,15.075) v2(41.673,15.075) 41.673,14.228 39.563,12.119 v1(39.563,11.229) ; v1(45.873,15.075) 45.895,15.075 v1(46.941,14.029) 49.026,14.029 v1(50.073,15.075)
  BOTTOM_L10 w0.127: R201.1@38.239,7.998 39.437,7.998 v5(39.624,7.811)
  other v1: 42.167,7.749 45.922,7.803 41.673,15.075
  other v2: 37.117,7.879 39.563,11.229 46.941,14.029 37.473,15.075 45.873,15.075 50.073,15.075
  other v3: 39.624,7.811
  other v4: 39.624,7.811
  other v5: 45.922,7.803
ROW8_15: LED57.C LED58.A LED59.C LED60.A LED61.C LED62.A LED63.C LED64.A LED65.C LED66.A LED67.C LED68.A LED69.C LED70.A LED71.C LED72.A LED89.A LED90.C R202.1 | length 66.3
  TOP_L1 w0.127: LED66.A@25.947,9.85 25.971,9.826 26.535,9.826 26.933,10.224 27.358,10.224 28.009,10.875 28.547,10.875 28.556,10.884 29.064,10.884 LED67.C@29.073,10.875 29.122,10.875 LED68.A@30.139,9.858 ; LED68.A@30.147,9.85 LED68.A@30.139,9.858 ; v1@33.827,10.37 33.322,10.875 LED69.C@33.273,10.875 33.23,10.919 32.074,10.919 31.466,11.526 30.933,11.526 30.147,10.741 30.147,10.375 30.139,10.367 LED68.A@30.139,9.858 ; v1@33.848,10.391 33.848,10.37 34.347,9.871 LED70.A@34.347,9.85 LED70.A@34.136,10.061 ; LED57.C@35.373,12.975 35.397,12.975 36.423,11.95 36.423,11.925 36.447,11.925 37.473,10.9 LED71.C@37.473,10.875 37.497,10.875 38.523,9.85 LED72.A@38.547,9.85 ; LED71.C@37.452,10.896 v2(37.452,11.204) ; LED59.C@39.573,12.975 40.598,11.95 LED60.A@40.647,11.95 41.863,11.95 42.726,11.087 v2(42.975,11.087) 43.518,11.629 44.526,11.629 LED62.A@44.847,11.95 ; LED61.C@43.773,12.975 43.822,12.975 LED62.A@44.847,11.95 ; LED90.C@50.073,8.775 50.073,9.94 50.015,9.997 49.889,9.997 49.135,10.752 v2(49.135,11.192) 49.118,11.21 49.118,11.88 LED64.A@49.047,11.95 48.998,11.95 LED63.C@47.973,12.975 47.599,12.601 47.599,12.36 47.826,12.133 47.826,11.661 47.237,11.072 46.764,11.072 45.886,11.95 LED62.A@44.847,11.95 ; v2(50.296,14.132) 51.453,12.975 LED65.C@52.173,12.975 53.754,11.395 v2(53.754,10.057)
  L3 w0.127: v5(33.318,11.474) 33.945,11.474 34.209,11.211 37.445,11.211 v2(37.452,11.204) ; v2@37.48,11.176 37.508,11.204 38.836,11.204 39.307,10.733 42.622,10.733 v2(42.975,11.087) ; v5(46.947,7.75) 47.06,7.863 51.164,7.863 53.358,10.057 v2(53.754,10.057) ; v2(49.135,11.192) 49.722,11.78 49.754,11.78 50.296,12.322 v2(50.296,14.132)
  L8 w0.127: v5(33.318,11.474) 33.848,10.944 v5(33.848,10.416)
  BOTTOM_L10 w0.127: v5(33.848,10.416) 34.521,10.416 35.039,9.898 R202.1@35.039,7.998
  other v1: 46.947,7.75 53.754,10.057 33.848,10.416 42.975,11.087 37.452,11.204 49.135,11.192 50.296,14.132
  other v2: 46.947,7.75 33.848,10.416
  other v3: 33.848,10.416
  other v4: 33.848,10.416
ROW9_15: LED73.C LED74.A LED75.C LED76.A LED77.C LED78.A LED79.C LED80.A LED81.C LED82.A LED83.C LED84.A LED85.C LED86.A LED87.C LED88.A LED89.C LED90.A R203.1 | length 50.1
  TOP_L1 w0.127: LED79.C@26.973,8.775 27.998,7.75 LED80.A@28.047,7.75 28.056,7.742 28.564,7.742 28.573,7.75 29.042,7.75 29.826,6.967 30.279,6.967 30.711,7.398 31.828,7.398 32.18,7.75 LED82.A@32.247,7.75 ; LED81.C@31.173,8.775 LED82.A@32.198,7.75 ; LED82.A@32.256,7.742 32.764,7.742 32.766,7.743 33.246,7.743 34.128,6.861 34.513,6.861 35.402,7.75 35.949,7.75 35.957,7.758 LED84.A@36.39,7.758 ; LED83.C@35.373,8.775 LED84.A@36.39,7.758 ; LED84.A@36.447,7.75 36.398,7.75 LED84.A@36.39,7.758 ; LED84.A@36.456,7.742 36.774,7.742 36.925,7.59 37.455,7.59 38.388,8.523 38.388,8.654 38.509,8.775 39.047,8.775 39.056,8.784 39.564,8.784 LED85.C@39.573,8.775 LED86.A@40.598,7.75 ; LED86.A@40.647,7.75 40.639,7.758 40.639,8.267 40.647,8.275 40.647,8.813 41.263,9.429 42.326,9.429 LED74.A@42.723,9.825 ; v2(41.634,11.185) 41.673,11.146 LED73.C@41.673,10.875 LED74.A@42.723,9.825 ; LED74.A@42.747,9.85 LED74.A@42.723,9.825 ; LED88.A@44.798,7.75 LED87.C@43.773,8.775 LED74.A@42.723,9.825 ; LED75.C@45.873,10.875 LED89.C@47.973,8.775 48.998,7.75 49.351,8.102 49.684,8.102 49.889,7.897 50.362,7.897 50.951,8.486 50.951,9.242 50.527,9.666 50.527,10.421 ; LED77.C@50.073,10.875 50.527,10.421 ; LED78.A@51.147,9.85 51.098,9.85 50.527,10.421
  L3 w0.127: v2(41.634,11.185) 41.911,11.185 42.086,11.009 42.243,11.009 42.61,11.375 43.229,11.375 43.246,11.358 43.621,11.358 44.217,10.762 45.145,10.762 45.32,10.937 v2(45.864,10.937)
  BOTTOM_L10 w0.127: v2(30.248,6.943) 30.248,8.408 31.338,9.498 33.928,9.498 34.039,9.386 R203.1@34.039,7.998
  other v1: 30.248,6.943 45.864,10.937 41.634,11.185
  other v3: 30.248,6.943
  other v4: 30.248,6.943
  other v5: 30.248,6.943
ROW10_15: LED91.C LED92.A LED93.C LED94.A LED95.C LED96.A LED97.C LED98.A LED99.C LED100.A LED101.C LED102.A LED103.C LED104.A R204.1 | length 43.4
  TOP_L1 w0.127: LED92.A@25.947,5.65 25.956,5.642 26.464,5.642 26.473,5.65 26.984,5.65 28.009,6.675 28.547,6.675 28.556,6.684 29.064,6.684 LED93.C@29.073,6.675 29.122,6.675 30.156,5.642 30.664,5.642 30.673,5.65 31.184,5.65 31.216,5.681 ; 31.587,6.053 31.216,5.681 ; 31.596,6.062 32.209,6.675 ; 32.222,6.675 32.435,6.675 32.435,6.684 LED95.C@33.089,6.684 ; LED104.A@51.147,5.65 51.098,5.65 LED103.C@50.073,6.675 49.802,6.675 49.428,6.301 48.852,6.301 48.396,5.845 48.396,5.654 48.102,5.36 48.101,5.36 47.669,4.928 ; LED91.C@52.173,8.775 52.173,7.719 52.428,7.464 52.428,7.16 52.824,6.765 52.824,6.145 v4(52.411,5.731) 52.411,5.164 51.776,4.529 48.068,4.529 47.669,4.928 ; 31.216,5.681 31.898,4.999 33.647,4.999 34.298,5.65 LED96.A@34.347,5.65 34.356,5.642 34.864,5.642 34.873,5.65 35.384,5.65 36.409,6.675 36.947,6.675 36.956,6.684 37.464,6.684 37.464,6.442 38.265,5.642 39.064,5.642 39.073,5.65 39.584,5.65 40.609,6.675 41.147,6.675 41.156,6.684 41.664,6.684 42.698,5.65 LED100.A@42.747,5.65 42.756,5.642 43.264,5.642 43.273,5.65 43.784,5.65 44.809,6.675 45.347,6.675 45.356,6.684 45.864,6.684 LED101.C@45.873,6.675 45.922,6.675 LED102.A@46.947,5.65 47.669,4.928
  BOTTOM_L10 w0.127: R204.1@33.039,7.048 33.039,6.652 v3(33.361,6.33) ; v4(52.411,5.731) 52.434,5.708 v3@52.434,5.617
  other v1: 52.411,5.731 33.361,6.33
  other v2: 52.411,5.731 33.361,6.33
  other v3: 52.411,5.731
  other v4: 33.361,6.33
  other v5: 52.411,5.731 33.361,6.33
RST_N_3V3_24: R143.2 R329.2 U21_4.8 | length 69.1
  TOP_L1 w0.084: R329.2@46.45,71.412 46.45,71.837 46.65,72.037 U21_4.8@46.65,72.441
  TOP_L1 w0.127: v2(46.089,70.465) 46.071,70.482 46.071,71.034 R329.2@46.45,71.412 ; R143.2@47.987,29.85 49.237,29.85 50.522,31.135 50.522,38.35 53.852,41.68 59.814,41.68 65.726,47.593 65.726,55.562 66.054,55.89 66.054,61.183 57.765,69.471 49.975,69.471 49.59,69.856 49.015,69.856 v1(48.771,70.099)
  L3 w0.127: v2(46.089,70.465) 46.905,70.465 47.271,70.099 v1(48.771,70.099)
  other v1: 46.089,70.465
  other v2: 48.771,70.099
RTSS_IO_4: MODULE1.BE39 R43.2 R56.2 | length 2.2
  TOP_L1 w0.127: v3(73.825,126.406) 74.121,126.702 74.348,126.702 MODULE1.BE39@74.682,127.036
  BOTTOM_L10 w0.127: v3(73.825,126.406) 73.825,126.404 73.961,126.268 R43.2@74.269,126.268 R56.2@74.269,125.673
  other v1: 73.825,126.406
  other v2: 73.825,126.406
  other v4: 73.825,126.406
  other v5: 73.825,126.406
RTSS_IO_6: MODULE1.BF37 R40.2 R53.2 | length 4.4
  TOP_L1 w0.127: v1(75.801,126.446) 75.807,126.44 76.026,126.44 76.472,125.993 76.472,125.226 MODULE1.BF37@75.882,124.636
  BOTTOM_L10 w0.127: R40.2@75.169,126.273 R53.2@75.169,125.678 75.627,125.678 75.801,125.851 v1(75.801,126.446)
  other v2: 75.801,126.446
  other v3: 75.801,126.446
  other v4: 75.801,126.446
  other v5: 75.801,126.446
RTSS_IO_7: MODULE1.BE37 R41.2 R54.2 | length 3.8
  TOP_L1 w0.127: v5(72.934,126.253) 72.934,125.621 73.391,125.165 74.154,125.165 MODULE1.BE37@74.682,124.636
  BOTTOM_L10 w0.127: v5(72.934,126.253) R41.2@73.369,126.253 ; R54.2@73.369,125.673 R41.2@73.369,126.268
  other v1: 72.934,126.253
  other v2: 72.934,126.253
  other v3: 72.934,126.253
  other v4: 72.934,126.253
RTSS_IO_10: MODULE1.BC36 R32.2 R45.2 | length 8.5
  TOP_L1 w0.127: v3(66.756,126.312) 66.954,126.114 66.954,125.488 67.264,125.178 68.032,125.178 68.032,124.415 68.469,123.978 71.74,123.978 MODULE1.BC36@72.282,123.436
  BOTTOM_L10 w0.127: v3(66.756,126.312) 66.773,126.295 67.052,126.295 R32.2@67.069,126.278 R45.2@67.069,125.683
  other v1: 66.756,126.312
  other v2: 66.756,126.312
  other v4: 66.756,126.312
  other v5: 66.756,126.312
RTSS_IO_11: MODULE1.BC37 R33.2 R46.2 | length 5.5
  TOP_L1 w0.127: v3(68.395,125.236) 71.682,125.236 MODULE1.BC37@72.282,124.636
  BOTTOM_L10 w0.127: R33.2@67.969,126.278 R46.2@67.969,125.683 68.301,125.683 68.375,125.608 68.375,125.256 v3(68.395,125.236)
  other v1: 68.395,125.236
  other v2: 68.395,125.236
  other v4: 68.395,125.236
  other v5: 68.395,125.236
RTSS_IO_12: MODULE1.BD36 R34.2 R47.2 | length 3.5
  TOP_L1 w0.127: v3(72.92,125.121) 72.92,123.998 MODULE1.BD36@73.482,123.436
  BOTTOM_L10 w0.127: R34.2@72.469,126.273 R47.2@72.469,125.678 72.846,125.678 72.92,125.603 v3(72.92,125.121)
  other v1: 72.92,125.121
  other v2: 72.92,125.121
  other v4: 72.92,125.121
  other v5: 72.92,125.121
RTSS_IO_14: MODULE1.BD39 R35.2 R48.2 | length 3.4
  TOP_L1 w0.127: v2(72.902,127.356) 72.926,127.333 73.121,127.333 73.417,127.036 MODULE1.BD39@73.482,127.036
  BOTTOM_L10 w0.127: R48.2@71.569,125.678 R35.2@71.569,126.273 71.869,126.273 71.969,126.373 71.969,126.873 72.452,127.356 v2(72.902,127.356)
  other v1: 72.902,127.356
  other v3: 72.902,127.356
  other v4: 72.902,127.356
  other v5: 72.902,127.356
RTSS_IO_15: MODULE1.BC38 R36.2 R49.2 | length 5
  TOP_L1 w0.127: v5(70.491,127.367) 70.469,127.345 70.469,126.736 70.728,126.478 71.64,126.478 MODULE1.BC38@72.282,125.836
  BOTTOM_L10 w0.127: R49.2@69.769,125.678 R36.2@69.769,126.273 70.039,126.273 70.253,126.487 70.253,127.129 v5(70.491,127.367)
  other v1: 70.491,127.367
  other v2: 70.491,127.367
  other v3: 70.491,127.367
  other v4: 70.491,127.367
RTSS_IO_16: MODULE1.BB38 R38.2 R51.2 | length 3.1
  TOP_L1 w0.127: v3(69.288,126.362) 69.277,126.373 69.274,126.373 69.269,126.378 70.455,126.378 71.004,125.829 MODULE1.BB38@71.075,125.829
  BOTTOM_L10 w0.127: R51.2@68.869,125.683 R38.2@68.869,126.278 69.17,126.278 69.254,126.362 v3(69.288,126.362)
  other v1: 69.288,126.362
  other v2: 69.288,126.362
  other v4: 69.288,126.362
  other v5: 69.288,126.362
RTSS_IO_17: MODULE1.BC39 R39.2 R52.2 | length 3.2
  TOP_L1 w0.127: v4(71.582,127.43) 71.888,127.43 MODULE1.BC39@72.282,127.036
  BOTTOM_L10 w0.127: R52.2@70.669,125.678 R39.2@70.669,126.273 71.013,126.273 71.087,126.347 71.087,126.833 71.234,126.979 71.234,127.082 v4(71.582,127.43)
  other v1: 71.582,127.43
  other v2: 71.582,127.43
  other v3: 71.582,127.43
  other v5: 71.582,127.43
RTSS_IO_18: MODULE1.AY35 R37.2 R50.2 | length 8.3
  TOP_L1 w0.127: v1(64.838,125.194) 64.814,125.171 64.693,125.171 64.469,124.947 64.469,124.173 64.564,124.078 66.569,124.078 66.869,123.778 66.869,122.878 66.969,122.778 68.064,122.778 68.606,122.236 MODULE1.AY35@68.682,122.236
  BOTTOM_L10 w0.127: v3@64.837,125.195 64.837,125.608 64.911,125.683 R50.2@65.269,125.683 R37.2@65.269,126.278
  other v2: 64.838,125.194
  other v3: 64.838,125.194
  other v4: 64.838,125.194
  other v5: 64.838,125.194
RTSS_IO_21: MODULE1.BA34 R42.2 R55.2 | length 8.7
  TOP_L1 w0.127: v4(65.735,125.257) 65.75,125.273 66.666,125.273 66.869,125.07 66.869,124.278 67.169,123.978 67.951,123.978 68.069,123.859 68.069,123.094 68.285,122.878 68.91,122.878 69.269,122.518 69.269,121.649 MODULE1.BA34@69.882,121.036
  BOTTOM_L10 w0.127: v4(65.735,125.257) 65.735,125.604 65.809,125.679 R55.2@66.165,125.679 ; R55.2@66.169,125.683 R42.2@66.169,126.278
  other v1: 65.735,125.257
  other v2: 65.735,125.257
  other v3: 65.735,125.257
  other v5: 65.735,125.257
RTSS_IO_51: MODULE1.AU46 R31.2 R44.2 | length 21.3
  TOP_L1 w0.127: MODULE1.AU46@65.082,135.436 65.747,136.101 67.71,136.101 68.011,135.8 68.011,135.107 68.21,134.908 76.809,134.908 v1(78.115,133.602)
  BOTTOM_L10 w0.127: R44.2@76.069,128.051 R31.2@76.069,128.651 76.379,128.651 76.807,129.078 76.807,131.297 78.115,132.606 v1(78.115,133.602)
  other v2: 78.115,133.602
  other v3: 78.115,133.602
  other v4: 78.115,133.602
  other v5: 78.115,133.602
RTSS_IO_58_FORCE_USB_BOOT_SPX3_1P8_1: MODULE1.BF40 R346.1 | length 181.7
  TOP_L1 w0.127: R346.1@13.975,11.094 13.975,10.729 14.936,9.768 15.124,9.768 15.155,9.737 15.938,9.737 16.501,9.174 17.647,9.174 17.722,9.099 17.722,8.552 17.922,8.351 20.613,8.351 20.856,8.594 20.856,11.265 20.679,11.441 20.679,12.933 21.359,13.613 22.534,13.613 24.086,15.165 24.363,15.442 24.363,19.614 24.637,19.888 24.637,20.853 27.173,23.389 27.173,37.032 26.383,37.822 26.383,41.863 27.2,42.68 27.2,45.332 28.533,46.666 32.061,46.666 32.823,47.428 32.823,51.704 35.117,53.998 57.48,53.998 57.614,54.131 57.614,63.998 56.76,64.852 51.096,64.852 50.544,65.404 50.544,68.046 v5(49.968,68.622) ; MODULE1.BF40@75.882,128.236 v1(76.382,128.736)
  L3 w0.127: v3(72.54,124.506) 73.233,124.506 74.34,125.612 74.34,127.501 75.575,128.736 v1(76.382,128.736)
  L8 w0.127: v5(49.968,68.622) 49.968,82.622 68.748,101.401 68.748,105.086 67.145,106.689 67.145,107.919 67.492,108.267 67.492,109.274 67.909,109.691 67.909,116.286 70.959,119.336 72.191,119.336 v4(72.348,119.493)
  BOTTOM_L10 w0.127: v4(72.348,119.493) 72.348,124.313 v3(72.54,124.506)
  other v1: 49.968,68.622
  other v2: 49.968,68.622 76.382,128.736
  other v3: 72.348,119.493
  other v4: 72.54,124.506
  other v5: 72.54,124.506 76.382,128.736
RTSS_PS_HOLD_SPX3_1P8_1: D26.4 D26.7 JOMEGA.82 R488.2 | length 4.2
  BOTTOM_L10 w0.127: JOMEGA.82@22.016,42.35 22.016,41.058 22.151,40.923 D26.7@22.151,40.249 D26.4@22.151,39.374 R488.2@22.152,38.243
RTSS_RESIN_1_N: D26.2 D26.9 JOMEGA.80 MODULE1.AY43 | length 168.7
  TOP_L1 w0.127: MODULE1.AY43@68.682,131.836 68.682,131.364 68.881,131.165 68.901,131.165 69.302,130.763 v5(69.302,127.856)
  L8 w0.127: v3(63.126,127.928) 63.126,128.243 64.171,129.288 67.87,129.288 v5(69.302,127.856)
  BOTTOM_L10 w0.127: D26.2@23.151,39.374 D26.9@23.151,40.249 23.151,40.923 23.286,41.058 JOMEGA.80@23.286,42.35 ; JOMEGA.80@23.286,42.35 23.286,44.048 22.665,44.669 22.665,54.313 23.352,55 23.352,55.031 23.543,55.222 23.543,61.143 25.319,62.919 25.319,68 22.594,70.725 16.772,70.725 13.352,74.145 13.352,82.551 10.544,85.359 8.163,85.359 6.859,86.663 6.859,124.981 9.734,127.856 60.247,127.856 60.319,127.928 v3(63.126,127.928)
  other v1: 69.302,127.856
  other v2: 69.302,127.856
  other v4: 63.126,127.928
RXPOLINV_DIS_25: R286.1 R301.2 U34.AD2 | length 3.2
  TOP_L1 w0.1: U34.AD2@45.761,34.349 46.672,34.349 47.242,34.919 47.631,34.919 R301.2@47.961,35.249 R286.1@48.561,35.249
SAIL_JTAG.SRST_1_N: D39.1 D39.10 JOMEGA.71 MODULE1.AW37 TP65.X | length 148.5
  BOTTOM_L10 w0.127: JOMEGA.71@28.366,46.1 28.366,47.32 27.461,48.225 27.461,52.295 TP65.X@26.416,53.34 26.416,54.137 27.416,55.138 D39.1@27.416,55.8 D39.10@27.416,56.675 27.416,67.87 23.059,72.227 17.187,72.227 14.513,74.901 14.513,82.674 10.868,86.319 10.868,87.641 10.177,88.332 10.177,124.588 11.367,125.778 61.038,125.778 61.784,125.032 62.213,125.032 62.908,124.336 v3(67.282,124.336)
  other v1: 67.282,124.336
  other v2: 67.282,124.336
  other v4: 67.282,124.336
  other v5: 67.282,124.336
SAIL_JTAG.TCK_1: D38.5 D38.6 JOMEGA.69 MODULE1.AW36 TP64.X | length 150.1
  BOTTOM_L10 w0.127: JOMEGA.69@29.636,46 29.636,47.73 30.172,48.266 30.172,51.373 28.956,52.589 TP64.X@28.956,53.34 30.541,54.925 D38.5@30.541,55.8 D38.6@30.541,56.675 30.541,57.393 27.8,60.134 27.8,67.986 23.205,72.581 17.334,72.581 14.867,75.048 14.867,82.641 11.168,86.34 11.168,87.841 10.531,88.478 10.531,124.442 11.64,125.551 60.944,125.551 61.69,124.805 62.119,124.805 62.865,124.058 64.069,124.058 65.124,123.003 67.017,123.003 v1(67.377,123.363)
  other v2: 67.377,123.363
  other v3: 67.377,123.363
  other v4: 67.377,123.363
  other v5: 67.377,123.363
SAIL_JTAG.TDI_1: D38.4 D38.7 JOMEGA.67 MODULE1.BA37 TP63.X | length 152.5
  BOTTOM_L10 w0.127: JOMEGA.67@30.906,46 30.906,47.769 30.5,48.175 30.5,51.58 31.496,52.576 TP63.X@31.496,53.34 31.041,53.795 D38.4@31.041,55.8 D38.7@31.041,56.675 31.041,57.467 28.1,60.409 28.1,68.11 23.33,72.881 17.458,72.881 15.096,75.243 15.096,82.828 11.437,86.487 11.437,88.007 10.831,88.612 10.831,124.318 11.837,125.324 60.85,125.324 61.596,124.578 62.025,124.578 62.771,123.831 63.975,123.831 65.103,122.703 67.221,122.703 68.174,123.656 69.482,123.656 69.482,123.662 69.695,123.874 69.721,123.874 69.864,124.018 v1(69.864,124.531)
  other v2: 69.864,124.531
  other v3: 69.864,124.531
  other v4: 69.864,124.531
  other v5: 69.864,124.531
SAIL_JTAG.TDO_1: D38.2 D38.9 JOMEGA.65 MODULE1.BA36 TP62.X | length 153.1
  BOTTOM_L10 w0.127: JOMEGA.65@32.176,46 32.176,47.876 32.65,48.35 32.65,51.324 34.036,52.71 TP62.X@34.036,53.34 33.16,53.34 32.041,54.459 D38.2@32.041,55.8 D38.9@32.041,56.675 32.041,57.307 28.5,60.848 28.5,68.162 23.462,73.2 17.59,73.2 15.323,75.467 15.323,83.053 11.78,86.595 11.78,88.261 11.15,88.891 11.15,124.185 12.062,125.097 60.756,125.097 61.502,124.351 61.931,124.351 62.677,123.604 63.881,123.604 65.101,122.384 67.32,122.384 68.292,123.356 69.691,123.356 v1(69.846,123.511)
  other v2: 69.846,123.511
  other v3: 69.846,123.511
  other v4: 69.846,123.511
  other v5: 69.846,123.511
SAIL_JTAG.TMS_1: D38.1 D38.10 JOMEGA.63 MODULE1.AY36 TP61.X | length 157.3
  TOP_L1 w0.127: MODULE1.AY36@68.682,123.436 68.908,123.436 v1(69.41,122.934)
  BOTTOM_L10 w0.127: JOMEGA.63@33.446,46 33.446,47.76 32.926,48.28 32.926,51.278 33.948,52.3 35.536,52.3 TP61.X@36.576,53.34 36.576,54.124 36.4,54.3 33,54.3 32.541,54.759 D38.1@32.541,55.8 D38.10@32.541,56.675 32.541,57.31 28.9,60.952 28.9,68.186 23.586,73.5 17.715,73.5 15.623,75.592 15.623,83.177 12.274,86.525 12.274,88.574 11.45,89.398 11.45,124.061 12.259,124.87 60.402,124.87 61.236,124.035 61.925,124.035 63.877,122.084 67.53,122.084 68.402,122.956 69.388,122.956 v1(69.41,122.934)
  other v2: 69.41,122.934
  other v3: 69.41,122.934
  other v4: 69.41,122.934
  other v5: 69.41,122.934
SAIL_JTAG.TRST_1_N: D39.2 D39.9 JOMEGA.73 MODULE1.AY37 TP66.X | length 153.5
  TOP_L1 w0.127: MODULE1.AY37@68.682,124.636 68.782,124.636 69.077,124.341 v1(69.082,124.341)
  BOTTOM_L10 w0.127: JOMEGA.73@27.096,46 27.096,47.599 25.5,49.196 25.5,51.716 TP66.X@23.876,53.34 24.836,54.3 26.091,54.3 26.916,55.125 D39.2@26.916,55.8 D39.9@26.916,56.675 26.916,67.945 22.935,71.927 17.063,71.927 14.213,74.777 14.213,82.653 10.542,86.324 10.542,87.512 9.877,88.177 9.877,124.713 11.17,126.005 61.132,126.005 61.802,125.335 62.23,125.335 62.9,124.665 68.758,124.665 v1(69.082,124.341)
  other v2: 69.082,124.341
  other v3: 69.082,124.341
  other v4: 69.082,124.341
  other v5: 69.082,124.341
SCAN_EN_25: R296.1 R305.2 U34.AJ35 | length 3
  TOP_L1 w0.127: R296.1@34.223,35.725 34.704,35.725 34.904,35.525 35.23,35.525 35.45,35.305 35.732,35.305 36.051,35.625 36.188,35.625 36.214,35.599 U34.AJ35@36.871,35.599
SLEEP_CLK_1: MODULE1.U41 R440.1 | length 145.8
  TOP_L1 w0.127: MODULE1.U41@41.082,129.436 40.748,129.102 40.724,129.102 40.689,129.137 40.45,129.137 40.281,128.968 40.281,128.585 40.44,128.426 40.44,127.94 40.333,127.94 39.991,127.597 39.696,127.597 39.354,127.255 39.354,118.417 41.261,116.51 41.261,116.461 41.981,115.74 42.043,115.678 42.043,107.403 41.754,107.115 41.754,105.221 v1(41.762,105.213)
  L3 w0.127: v5(25.062,89.413) 25.525,89.877 25.525,102.296 26.873,103.643 27.174,103.643 27.614,103.204 27.614,100.862 27.763,100.713 37.262,100.713 v1(41.762,105.213)
  L8 w0.1: v3(24.462,75.313) 24.462,74.961 23.222,73.721 23.222,68.633 9.577,54.988 9.577,48.658 10.959,47.277 10.959,46.311 17.754,39.516 17.754,27.249 19.094,25.908 21.58,25.908 24.754,29.083 v3(25.645,29.083)
  L8 w0.127: v4(25.062,88.913) v5(25.062,89.413)
  BOTTOM_L10 w0.1: R440.1@25,30.96 24.55,30.96 24.4,30.81 24.4,30.122 25.427,29.095 25.632,29.095 v3(25.645,29.083)
  BOTTOM_L10 w0.127: v3(24.462,75.313) 24.462,79.313 25.062,79.913 v4(25.062,88.913)
  other v2: 41.762,105.213
  other v3: 25.062,88.913
  other v4: 25.645,29.083 24.462,75.313
SLOTCLK_25: R210.1 R299.2 U34.AP6 | length 5.3
  TOP_L1 w0.1: U34.AP6@44.591,37.019 44.591,38.057 44.403,38.245 44.403,39.504 44.723,39.824 R210.1@46.436,39.824 R299.2@46.436,39.224
SOM_VCOIN: R399.1 R508.2 | length 0.7
  BOTTOM_L10 w0.15: R399.1@30.133,95.051 R508.2@30.133,95.751
SOM_VREG_MDPX3_1P8: C172_1.2 C172_2.2 C172_3.2 C172_4.2 C172_5.2 C173_1.2 C173_2.2 C173_3.2 C173_4.2 C173_5.2 D63.2 JCTL.9 JMISC.57 JOMEGA.79 JOMEGA.81 MODULE1.BD42 MODULE1.BE42 MODULE1.BF42 R1.1 R2.1 R3.1 R4.1 R5.1 R12.1 R13.1 R14.1 R15.1 R21.1 R23.2 R115.1 R146.1 R147.1 R162.1 R165.2 R166.1 R168_1.2 R168_2.2 R168_3.2 R168_4.2 R168_5.2 R224.1 R250.1 R251.1 R252.1 R253.1 R254.1 R255.1 R256.1 R257.1 R258.2 R268.2 R270.2 R314.1 R319.1 R320.1 R321.1 R322.2 R326_1.2 R326_2.2 R326_3.2 R326_4.2 R326_5.2 R330.1 R331.1 R332.1 R351.1 R386.1 R387.2 R392.2 R393.2 R394.2 R412.1 R414.2 R415.2 R416.2 R422.1 R423.1 R424.1 R425.1 R465.2 R478.2 R497.2 TP88.X U16.5 U17.5 U21_1.1 U21_2.1 U21_3.1 U21_4.1 U21_5.1 U33_1.2 U33_2.2 U33_3.2 U33_4.2 U33_5.2 | length 242.1
  TOP_L1 w0.1: v2(37.11,68.901) 37.119,68.892 R425.1@37.119,68.87 ; R424.1@38.875,68.87 38.88,68.865 v2(38.889,68.865) ; v1(54.008,137.928) R162.1@54.656,137.926 R162.1@54.656,137.926
  TOP_L1 w0.127: R326_3.2@9.086,146.123 9.636,146.673 C172_3.2@9.736,146.673 10.09,146.673 v2(10.188,146.771) 10.286,146.869 U21_3.1@10.286,147.575 ; R146.1@9.593,79.791 10.009,79.791 v2(10.216,79.584) 10.216,79.312 10.328,79.2 11.109,79.2 U16.5@11.118,79.191 ; D63.2@11.81,15.841 v2(12.377,15.841) ; R168_4.2@11.85,66.8 11.85,67.208 12.855,68.214 12.855,69.314 13.042,69.5 R423.1@13.71,69.5 v2(13.71,69.907) 14.215,69.907 14.36,69.762 R422.1@14.36,69.5 ; R478.2@13.232,47.709 15.728,47.709 17.744,45.692 23.952,45.692 v1(23.959,45.699) ; JCTL.9@14.51,15.841 14.45,15.781 14.45,14.4 14.71,14.14 16.355,14.14 17.025,13.47 R166.1@17.025,13.2 ; U33_4.2@17.25,67.75 17.25,67.769 17.306,67.825 v2(17.878,67.825) C173_4.2@18.45,67.825 ; R258.2@17.617,7.024 17.373,7.024 17.298,7.098 17.298,8.038 17.385,8.124 20.707,8.124 21.083,8.5 21.083,11.527 20.968,11.642 v3(20.968,11.676) ; R14.1@19.239,131.974 19.239,133.23 19.71,133.701 20.01,133.701 20.332,133.379 20.332,130.56 19.11,129.338 19.11,125.708 19.735,125.083 20.964,125.083 21.182,125.301 23.432,125.301 v2(23.69,125.559) ; R168_3.2@26.274,66.8 26.287,66.813 26.287,67.252 v5(26.3,67.265) ; U33_3.2@31.75,67.75 31.75,67.769 31.806,67.825 v2(32.378,67.825) C173_3.2@32.95,67.825 ; R168_2.2@35.35,66.8 v2(35.35,67.241) ; U33_2.2@40.75,67.75 40.75,67.769 40.806,67.825 v2(41.378,67.825) C173_2.2@41.95,67.825 ; v2(41.816,139.036) 41.816,139.019 R392.2@42.051,138.784 42.053,138.786 R386.1@42.734,138.786 ; R321.1@46.35,75.566 R321.1@46.45,75.566 R319.1@47.75,75.566 ; R319.1@47.756,75.566 47.857,75.465 47.857,75.46 48.219,75.097 48.319,75.097 C172_4.2@48.4,75.016 ; U21_1.1@47.85,67.25 47.85,67.639 47.956,67.745 v1@48.236,67.745 ; U21_4.1@47.85,73.841 48.2,73.841 v2(48.4,74.041) C172_4.2@48.4,75.016 ; v2(48.22,67.742) 48.228,67.733 48.742,67.733 C172_1.2@48.75,67.725 R326_1.2@49.55,67.725 ; R326_4.2@49.05,75.566 49.044,75.566 48.954,75.476 48.954,75.47 48.581,75.097 48.481,75.097 C172_4.2@48.4,75.016 ; U21_2.1@52.789,73.869 52.789,74.394 v2(52.934,74.539) 53.089,74.694 C172_2.2@53.089,75.016 ; R412.1@52.989,76.116 53.304,76.116 53.453,75.967 53.453,75.016 ; C172_2.2@53.117,75.016 53.453,75.016 ; R326_2.2@53.789,75.016 53.453,75.016 ; R165.2@65.812,138.641 R268.2@65.812,137.991 ; v2(65.815,137.474) 65.812,137.478 R268.2@65.812,137.991 ; R393.2@66.551,138.284 66.49,138.223 66.281,138.223 66.049,137.991 R268.2@65.812,137.991 ; R147.1@70.631,19.384 70.631,19.765 v2(70.807,19.941) 71.363,19.941 71.531,20.109 U17.5@71.531,20.609
  TOP_L1 w0.2: v1(4.019,88.916) R497.2@4.319,88.916 ; R224.1@33.078,30.666 v2(33.078,31.031) ; R416.2@34.773,36.625 v5(34.773,37) ; v5(34.923,38.2) R415.2@34.923,38.575 ; v1(53.437,14.553) 53.446,14.544 53.446,14.516 53.633,14.329 R351.1@53.888,14.329 ; v6(78.315,130.188) 78.315,130.282 78.551,130.518 R394.2@78.551,135.859
  TOP_L1 w0.5: v2(12.377,15.841) v1(12.777,15.841) JCTL.9@14.51,15.841 ; MODULE1.BD42@73.482,130.636 MODULE1.BE42@74.682,130.636 MODULE1.BF42@75.882,130.636 76.967,130.636 v6(77.415,130.188)
  L5 w0.3: v5(10.282,79.188) 11.788,79.188 15.4,82.8 15.4,84.5 ; 14.319,84.723 14.575,84.978 v5(14.575,85.314) v5(14.575,85.814)
  L5 w0.5: v5(41.407,138.993) 42.51,138.993 44.356,137.148 52.652,137.148 v5(54.018,138.514) 55.007,137.524 65.407,137.524 v5(65.815,137.115)
  L5 w0.6: v5(67.231,103.911) 68.069,104.749 75.525,104.749 v5(76.203,104.071)
  L5 w1.5: v5(19.21,24.726) v5(20.01,24.726) 26.653,24.726 v5@28.593,26.666
  L6 w0.5: 63.554,20.757 v5(65.804,20.757)
  L3 w0.1: v5(36.663,68.892) 36.672,68.901 v2(37.11,68.901) ; v2(38.889,68.865) 38.889,69.287 v5(38.899,69.298)
  L3 w0.127: v2(10.188,146.771) v5(10.47,146.489) ; v5(13.698,71.634) 13.704,71.627 13.704,69.913 v2(13.71,69.907) ; v2(17.878,67.825) v5(18.371,67.825) ; v2(32.378,67.825) v5(32.831,67.825) ; v2(35.35,67.241) v5(35.35,67.596) ; v2(41.378,67.825) 41.378,68.184 v5(41.382,68.187) ; v5(41.407,138.993) 41.45,139.036 v2(41.816,139.036) ; v5(48.392,73.671) 48.4,73.679 v2(48.4,74.041) ; v5(52.556,74.533) 52.562,74.539 v2(52.934,74.539) ; v5(65.815,137.115) v2(65.815,137.474)
  L3 w0.2: v5(3.719,89.216) v1(4.019,88.916) ; v5(31.491,36.065) 32.151,36.065 32.491,35.725 35.458,35.725 v2(35.467,35.716) ; v5(32.617,30.964) 32.636,30.983 32.636,31.041 33.068,31.041 v2(33.078,31.031)
  L3 w0.3: v2(10.216,79.584) 10.282,79.518 v5(10.282,79.188) ; v1(14.155,84.814) v5(14.575,84.814) ; v2(14.155,85.314) v5(14.575,85.314) ; v1(14.155,85.814) v5(14.575,85.814)
  L3 w0.5: v2(12.377,15.841) 12.377,15.514 v5(12.601,15.289) ; v1(12.777,15.841) v5(12.777,16.241) ; v5(18.371,67.825) 19.008,67.188 19.795,67.188 20.471,67.864 25.701,67.864 v5(26.3,67.265) ; v5(19.21,24.726) 19.21,25.183 ; v5(20.01,24.726) 20.01,25.183 ; v5(48.211,68.23) 48.211,67.75 v2(48.22,67.742) ; v1(54.008,137.928) 54.008,138.504 v5(54.018,138.514) ; v5(65.804,20.757) 66.62,19.941 v2(70.807,19.941)
  L8 w0.127: v5(76.203,104.071) 76.203,103.997 76.31,103.89 v4(76.31,103.608) ; v5(84.51,126.856) 84.75,127.096 v3(84.75,127.218)
  L8 w0.4: v4(22.016,47.5) v5(22.016,47.95) ; v3(23.286,47.5) v5(23.286,47.95)
  L8 w1: v5(10.47,146.489) 10.47,137.06 11.642,135.888 21.315,135.888 23.415,133.788 23.415,131.06 24.587,129.888 27.015,129.888 30.915,125.988
  BOTTOM_L10 w0.1: U33_5.2@82.753,97.945 82.753,97.594 82.87,97.476 86.399,97.476 86.766,97.844 86.766,98.329 87.061,98.624 87.061,98.872 ; R414.2@86.603,99.947 86.915,99.947 87.061,99.801 87.061,98.872 ; R168_5.2@87.886,98.409 87.886,98.813 87.827,98.872 87.061,98.872
  BOTTOM_L10 w0.127: R5.1@24.982,110.199 24.99,110.191 24.99,109.874 v3(24.997,109.867) ; v4(28.069,109.838) R115.1@28.069,110.199 ; v4(28.968,109.843) 28.969,109.844 R3.1@28.969,110.199 ; v4(29.514,105.478) 29.682,105.646 R4.1@29.682,106.036 ; U21_5.1@31.7,28.37 31.7,27.85 31.95,27.6 R465.2@31.95,27.307 R23.2@32.6,27.307 32.6,27.851 32.744,27.995 C172_5.2@32.75,27.995 33.456,27.995 33.493,27.958 33.493,27.732 33.587,27.638 v3(33.587,27.605) ; R270.2@37.4,88.816 v4(37.4,89.191) ; R12.1@55.899,105.278 55.922,105.301 v3(59.11,105.301) ; R331.1@82.703,100.597 R332.1@83.353,100.597 ; 83.265,121.758 83.575,122.068 R254.1@83.575,122.375 ; v3(84.75,127.218) 84.75,127.233 TP88.X@85.525,128.008 ; C173_1.2@86.175,122.925 86.175,123.343 85.883,123.635 85.499,123.635 85.325,123.809 U33_1.2@85.325,124.15 85.925,124.15 v4(86.175,124.4)
  BOTTOM_L10 w0.2: v4(19.506,12.029) 19.923,12.446 19.923,13.353 20.33,13.76 R314.1@20.6,13.76 ; v3(20.968,11.676) 21.3,12.008 R322.2@21.3,12.56
  BOTTOM_L10 w0.4: JOMEGA.81@22.016,46 v4(22.016,47.5) ; JOMEGA.79@23.286,46 v3(23.286,47.5)
  BOTTOM_L10 w0.5: JMISC.57@29.229,99.629 29.229,98.082 v3(29.51,97.801)
  other v1: 20.968,11.676 12.377,15.841 70.807,19.941 33.078,31.031 34.773,37 34.923,38.2 35.35,67.241 26.3,67.265 48.22,67.742 17.878,67.825 32.378,67.825 41.378,67.825 38.889,68.865 37.11,68.901 13.71,69.907 48.4,74.041 52.934,74.539 10.216,79.584 14.155,85.314 23.69,125.559 65.815,137.474 41.816,139.036 10.188,146.771
  other v2: 20.968,11.676 53.437,14.553 12.777,15.841 34.773,37 34.923,38.2 23.959,45.699 26.3,67.265 14.155,84.814 14.155,85.814 4.019,88.916 54.008,137.928
  other v3: 19.506,12.029 22.016,47.5 37.4,89.191 76.31,103.608 29.514,105.478 28.069,109.838 28.968,109.843 81.625,121.482 82.275,121.482 82.925,121.482 83.575,121.482 84.225,121.482 84.875,121.482 86.176,123.751 85.875,124.05 86.175,124.4 64.369,126.828 75.169,127.501
  other v4: 20.968,11.676 33.587,27.605 23.286,47.5 29.51,97.801 59.11,105.301 24.997,109.867 81.625,121.482 82.275,121.482 82.925,121.482 83.575,121.482 84.225,121.482 84.875,121.482 86.176,123.751 85.875,124.05 64.369,126.828 84.75,127.218 75.169,127.501
  other v5: 20.968,11.676 19.506,12.029 53.437,14.553 70.807,19.941 28.6,26 28.593,26.566 28.586,27.132 33.587,27.605 23.959,45.699 34.955,89.014 35.555,89.014 36.155,89.014 34.955,89.514 35.555,89.514 36.155,89.514 34.955,90.014 35.555,90.014 36.155,90.014 23.69,125.559
  other v6: 42.873,50.364 43.673,50.364 44.473,50.364 42.873,51.134 43.673,51.134 44.473,51.134 55.655,110.544 56.455,110.544 57.255,110.544 55.655,111.314 56.455,111.314 57.255,111.314 77.415,129.288
SOM_VREG_S5S_SPX3_1P8: C1.2 C2.2 C3.2 JOMEGA.77 MODULE1.AW45 MODULE1.AW46 R31.1 R32.1 R33.1 R34.1 R35.1 R36.1 R37.1 R38.1 R39.1 R40.1 R41.1 R42.1 R43.1 R57.2 R58.2 R59.2 R60.2 R61.2 R458.1 TP1.X TP_FLASH_SAIL_1V8.X U2.B4 U2.D1 U2.E4 | length 277.6
  TOP_L1 w0.15: R458.1@13.975,11.9 13.975,12.187 v2(14.424,12.635)
  TOP_L1 w0.25: v2(15.043,14.669) 15.146,14.565 15.793,14.565 15.804,14.577 v2(21.297,14.577)
  TOP_L1 w0.27: v1(66.882,128.678) 66.882,133.306
  TOP_L1 w0.3: 66.882,133.306 66.882,133.636 MODULE1.AW45@67.482,134.236 MODULE1.AW46@67.482,135.436
  L3 w0.127: v5(23.814,11.308) 23.819,11.312 23.819,13.831 24.507,14.52 24.507,18.768 27.784,22.045 27.784,22.896 27.636,23.045 26.384,23.045 23.984,25.445 23.984,35.245 24.784,36.045 26.784,36.045 27.04,36.3 27.04,39.296 26.491,39.845 24.184,39.845 23.384,40.645 23.384,46.722 v5(24.598,47.935)
  L3 w0.15: v5(21.206,11.089) 21.211,11.094 21.211,11.389 21.343,11.52 21.343,13.012 21.297,13.058 v2(21.297,14.577)
  L3 w0.25: v2(14.424,12.635) 14.421,12.638 14.421,14.046 v2(15.043,14.669)
  L8 w0.15: v5(21.206,11.089) 23.014,11.089 23.234,11.308 v5(23.814,11.308)
  L8 w0.4: 64.827,128.628 64.877,128.678 v1(66.882,128.678)
  L8 w0.5: v3(21.384,52.045) 21.989,52.045 22.613,51.42 22.613,49.416 23.384,48.645 23.984,48.645 24.826,47.804 v3(24.826,47.583) ; 63.615,125.988 63.615,127.416 64.827,128.628
  BOTTOM_L10 w0.1: R43.1@74.264,126.823 R40.1@75.169,126.823 75.71,127.364 75.71,128.842 R31.1@76.069,129.201
  BOTTOM_L10 w0.127: v3(64.174,119.226) 71.485,119.226 72.072,118.639 R57.2@72.072,116.581 ; R37.1@65.269,126.828 R42.1@66.169,126.828 R32.1@67.069,126.828 R33.1@67.969,126.828 R38.1@68.869,126.828 69.764,126.828 R36.1@69.769,126.823 69.769,127.351 70.137,127.719 70.909,127.719 ; R39.1@70.669,126.823 70.669,127.084 70.815,127.231 70.815,127.625 70.909,127.719 ; R35.1@71.569,126.823 71.569,127.084 71.626,127.142 71.702,127.142 71.914,127.354 71.914,127.705 71.9,127.719 ; R34.1@72.469,126.823 R41.1@73.369,126.823 ; R41.1@73.369,126.818 R41.1@73.369,126.823 ; R43.1@74.264,126.823 R41.1@73.369,126.823 ; 70.909,127.719 71.9,127.719 ; 71.9,127.719 73.22,127.719 73.369,127.57 R41.1@73.369,126.823
  BOTTOM_L10 w0.15: C1.2@54.006,113.101 v3(54.51,113.101) ; C3.2@54.006,115.301 v3(54.51,115.301) ; v4(57.302,112.601) U2.E4@57.737,113.036 ; U2.B4@57.737,116.036 57.737,115.619 v3(57.745,115.611) ; U2.D1@60.755,114.018 U2.D1@60.737,114.036 v3(61.241,114.036) ; v3(62.849,114.024) C2.2@63.353,114.024 ; R61.2@64.452,115.586 v3(64.452,116.09) 66.821,116.09 66.992,115.919 R59.2@66.992,115.586 ; R60.2@64.452,118.126 v3(64.452,118.63) ; v3(64.476,116.885) 64.659,116.701 65.176,116.701 67.387,116.701 67.521,116.835 TP_FLASH_SAIL_1V8.X@68.262,117.576 68.812,118.126 R58.2@69.532,118.126
  BOTTOM_L10 w0.3: v3(61.857,126.377) 62.921,127.441 65.269,127.441 ; R37.1@65.269,126.828 65.269,127.441 ; 65.282,128.688 65.269,128.675 65.269,127.441
  BOTTOM_L10 w0.5: v3(21.384,52.045) 21.384,53.292 TP1.X@21.336,53.34 21.336,54.608 22.231,55.503 22.231,61.766 24.393,63.928 24.393,67.411 22.215,69.588 15.915,69.588 12.315,73.188 12.315,82.129 10.068,84.376 9.123,84.376 9.116,84.369 8.171,84.369 6.218,86.321 6.218,125.591 9.315,128.688 65.282,128.688 v3@66.882,128.688 ; JOMEGA.77@24.556,46 24.556,47.21 24.664,47.317 24.664,47.421 v3(24.826,47.583)
  other v1: 14.424,12.635 21.297,14.577 15.043,14.669
  other v2: 66.882,128.678
  other v3: 57.302,112.601 66.882,128.678
  other v4: 24.826,47.583 21.384,52.045 54.51,113.101 62.849,114.024 61.241,114.036 54.51,115.301 57.745,115.611 64.452,116.09 64.476,116.885 64.452,118.63 64.174,119.226 61.857,126.377 66.882,128.678
  other v5: 66.882,128.678
TUSB_CAP_TX_26_N: C325.2 U24.A41 | length 58.7
  TOP_L1 w0.122: C325.2@37.075,25.275 37.079,25.275 37.27,25.084 37.27,24.669 37.573,24.366 37.573,24.087 v2(37.58,24.08) ; U24.A41@71.591,28.349 71.591,28.523 71.81,28.742 v1(71.84,28.742)
  L3 w0.117: v2(37.58,24.08) 37.584,24.076 37.864,24.076 38.109,23.83 38.962,23.83 39.409,24.278 40.272,24.278 40.975,23.575 41.48,23.07 45.219,23.07 49.879,27.73 50.481,28.332 50.57,28.421 50.57,34.34 53.817,37.587 59.015,37.587 60.266,36.336 60.266,31.199 60.323,31.142 61.085,30.38 61.085,30.203 59.595,28.713 59.595,28.284 60.038,27.84 60.468,27.84 61.958,29.33 62.134,29.33 63.171,28.294 63.186,28.279 63.275,28.189 63.471,27.994 65.623,27.994 65.928,28.298 69.188,28.298 69.591,27.895 70.725,27.895 70.904,28.074 71.61,28.78 71.707,28.78 71.72,28.767 71.814,28.767 v1(71.84,28.742)
  other v1: 37.58,24.08
  other v2: 71.84,28.742
TUSB_CAP_TX_26_P: C324.2 U24.B38 | length 57.9
  TOP_L1 w0.122: C324.2@37.775,25.275 37.771,25.275 37.575,25.079 37.575,24.796 37.789,24.582 38.068,24.582 v2(38.075,24.575)
  L3 w0.117: v2(38.075,24.575) 38.079,24.571 38.079,24.291 38.235,24.135 38.835,24.135 39.283,24.583 40.398,24.583 41.606,23.375 45.093,23.375 46.211,24.493 50.265,28.547 50.265,34.466 53.691,37.892 59.141,37.892 60.571,36.462 60.571,31.389 60.571,31.325 61.39,30.506 61.39,30.077 59.899,28.587 59.899,28.41 60.165,28.145 60.341,28.145 61.831,29.635 62.261,29.635 63.386,28.509 63.491,28.405 63.597,28.298 65.497,28.298 65.802,28.603 69.314,28.603 69.717,28.2 70.599,28.2 71.548,29.149 72.094,29.149 v1(72.108,29.163)
  other v1: 38.075,24.575
  other v2: 72.108,29.163
USB1_CAP_SSTX_N: C280.2 D18.2 D18.9 JOMEGA.20 | length 34.1
  TOP_L1 w0.109: v6(74.965,45.268) 75.044,45.189 75.044,44.91 75.233,44.722 76.962,44.722 78.102,43.581 78.102,40.483 78.31,40.275 C280.2@78.325,40.275
  BOTTOM_L10 w0.109: D18.9@60.575,40.306 60.575,40.358 60.714,40.498 60.714,40.8 60.957,41.043 61.726,41.043 61.859,41.175 61.859,41.266 61.795,41.33 61.647,41.33 61.345,41.632 JOMEGA.20@61.345,42.393 ; D18.2@60.616,39.288 60.616,39.05 60.714,38.952 60.714,38.649 60.975,38.388 61.387,38.388 63.538,40.539 73.441,40.539 73.926,41.025 74.105,41.203 74.105,43.03 75.343,44.268 75.343,44.611 75.059,44.895 75.059,45.174 75.044,45.189 v6(74.965,45.268) ; D18.2@60.616,39.389 D18.9@60.616,40.163 D18.9@60.616,40.238 ; D18.2@60.616,39.415 D18.9@60.616,40.264 ; JOMEGA.20@61.386,41.6 JOMEGA.20@61.386,42.35 ; JOMEGA.20@61.428,41.569 JOMEGA.20@61.428,42.393
USB1_CAP_SSTX_P: C113.2 D18.1 D18.10 JOMEGA.18 | length 35.1
  TOP_L1 w0.109: v6(74.47,44.773) 74.549,44.694 74.829,44.694 75.106,44.417 76.836,44.417 77.798,43.455 77.798,43.372 77.798,42.954 cw(c77.616,42.954) 77.616,42.772 77.143,42.772 ccw(c77.143,42.591) 77.143,42.409 77.616,42.409 cw(c77.616,42.228) 77.616,42.046 77.143,42.046 ccw(c77.143,41.864) 77.143,41.683 77.616,41.683 cw(c77.616,41.501) 77.616,41.32 77.143,41.32 ccw(c77.143,41.138) 77.143,40.956 77.616,40.956 cw(c77.616,40.775) 77.798,40.775 77.798,40.483 77.59,40.275 C113.2@77.575,40.275
  BOTTOM_L10 w0.109: D18.10@61.075,40.307 61.075,40.442 61.019,40.498 61.019,40.674 61.083,40.738 61.852,40.738 62.164,41.049 62.164,41.266 62.228,41.33 62.376,41.33 62.615,41.569 JOMEGA.18@62.615,41.643 ; D18.1@61.116,39.288 61.116,39.05 61.019,38.952 61.019,38.775 61.101,38.693 61.261,38.693 61.641,39.073 62.249,39.681 62.21,39.72 62.647,40.156 62.686,40.118 63.122,40.554 63.161,40.593 63.412,40.844 73.315,40.844 73.8,41.33 73.8,43.157 75.038,44.395 75.038,44.485 74.844,44.68 74.564,44.68 v6(74.47,44.773) ; D18.1@61.116,39.389 D18.10@61.116,40.163 D18.10@61.116,40.238 ; JOMEGA.18@62.656,41.6 62.656,41.643 JOMEGA.18@62.656,42.35 ; JOMEGA.18@62.698,41.632 62.698,42.35 JOMEGA.18@62.698,42.393
USB1_D_N: D18.5 D18.6 JOMEGA.26 U24.B18 | length 38.2
  TOP_L1 w0.109: U24.B18@74.866,36.499 74.866,37.017 74.912,37.062 74.912,37.661 74.626,37.947 74.626,39.358 75.197,39.928 75.197,42.275 75.696,42.774 75.975,42.774 v6(76.054,42.853)
  BOTTOM_L10 w0.109: JOMEGA.26@57.618,41.643 57.618,41.569 57.857,41.33 58.005,41.33 58.069,41.266 58.069,41.049 58.38,40.738 59.15,40.738 59.214,40.674 59.214,40.498 59.158,40.442 D18.6@59.158,40.307 ; D18.5@59.116,39.288 59.116,39.05 59.214,38.952 59.214,38.377 59.967,37.624 61.92,37.624 62.099,37.803 62.995,38.699 63.516,39.22 74.266,39.22 74.355,39.309 74.655,39.609 74.998,39.952 74.998,40.762 75.261,41.025 75.725,41.025 75.95,40.799 75.95,40.313 76.338,39.925 77.386,39.925 77.773,40.313 77.773,41.893 77.388,42.279 75.642,42.279 75.507,42.414 75.507,42.586 75.696,42.774 75.975,42.774 v6(76.054,42.853) ; D18.5@59.116,39.389 D18.6@59.116,40.163 D18.6@59.116,40.238
USB1_D_P: D18.4 D18.7 JOMEGA.24 U24.A20 | length 38.1
  TOP_L1 w0.109: U24.A20@74.591,37.349 74.526,37.415 74.526,37.616 74.321,37.82 74.321,39.484 74.892,40.055 74.892,42.401 75.48,42.99 75.48,43.269 v6(75.559,43.348)
  BOTTOM_L10 w0.109: JOMEGA.24@58.888,42.393 58.888,41.632 58.586,41.33 58.438,41.33 58.374,41.266 58.374,41.175 58.507,41.043 59.276,41.043 59.519,40.8 59.519,40.498 59.658,40.358 D18.7@59.658,40.306 ; D18.4@59.616,39.288 59.616,39.05 59.519,38.952 59.519,38.504 60.093,37.929 61.794,37.929 62.869,39.004 63.389,39.524 70.003,39.524 73.309,39.524 ccw(c73.309,39.706) 73.491,39.706 73.491,39.752 cw(c73.672,39.752) 73.854,39.752 73.854,39.706 ccw(c74.036,39.706) 74.036,39.524 74.139,39.524 74.363,39.748 74.693,40.078 74.693,40.888 75.135,41.33 75.851,41.33 76.255,40.926 76.255,40.439 76.464,40.23 77.259,40.23 77.469,40.439 77.469,41.767 77.261,41.974 75.516,41.974 75.203,42.288 75.203,42.712 75.48,42.99 75.48,43.269 v6(75.559,43.348) ; D18.4@59.616,39.415 D18.7@59.616,40.163 D18.7@59.616,40.264
USB1_SSRX_N: D19.2 D19.9 JOMEGA.32 U24.B16 | length 38
  TOP_L1 w0.109: U24.B16@75.966,36.499 75.966,36.883 76.112,37.028 76.112,37.875 75.959,38.028 75.959,38.119 75.971,38.131 75.971,38.334 v6(76.065,38.428)
  BOTTOM_L10 w0.109: D19.9@52.955,40.307 52.955,40.359 53.094,40.498 53.094,40.8 53.337,41.043 54.106,41.043 54.239,41.176 54.239,41.266 54.175,41.33 54.027,41.33 53.725,41.632 JOMEGA.32@53.725,42.393 ; D19.9@52.996,40.137 D19.2@52.996,39.288 52.996,39.05 53.094,38.953 53.094,38.693 53.337,38.45 54.072,38.45 54.315,38.693 54.315,39.547 54.44,39.672 54.782,40.014 54.873,40.014 54.937,39.95 54.937,39.141 55.115,38.962 55.985,38.962 56.163,39.141 56.163,40.111 56.227,40.175 56.371,40.175 57.464,40.175 58.143,39.497 58.143,37.863 58.321,37.685 59.014,36.992 59.173,36.833 59.262,36.744 62.388,36.744 62.477,36.833 62.636,36.992 63.27,37.625 75.609,37.625 75.867,37.884 75.867,38.119 76.065,38.316 v6(76.065,38.428) ; JOMEGA.32@53.766,41.6 JOMEGA.32@53.766,42.35 ; JOMEGA.32@53.808,41.569 JOMEGA.32@53.808,42.393
USB1_SSRX_P: D19.1 D19.10 JOMEGA.30 U24.A18 | length 37.9
  TOP_L1 w0.109: v6(75.365,38.428) 75.654,38.139 75.654,37.902 75.807,37.749 U24.A18@75.807,37.112
  BOTTOM_L10 w0.109: D19.10@53.455,40.307 53.455,40.442 53.399,40.498 53.399,40.674 53.463,40.738 54.232,40.738 54.544,41.049 54.544,41.266 54.608,41.33 54.756,41.33 54.995,41.569 JOMEGA.30@54.995,41.643 ; D19.10@53.496,40.137 D19.1@53.496,39.288 53.496,39.05 53.399,38.953 53.399,38.819 53.463,38.755 53.946,38.755 54.01,38.819 54.01,39.673 54.44,40.103 54.656,40.319 54.999,40.319 55.241,40.077 55.241,39.267 55.859,39.267 55.859,40.237 56.101,40.48 56.371,40.48 57.591,40.48 58.447,39.623 58.447,37.989 59.388,37.049 62.262,37.049 63.143,37.93 67,37.93 67.055,37.93 ccw(c67.055,38.112) 67.236,38.112 67.236,38.139 cw(c67.418,38.139) 67.599,38.139 67.599,38.112 ccw(c67.781,38.112) 67.963,38.112 67.963,38.139 cw(c68.144,38.139) 68.326,38.139 68.326,38.112 ccw(c68.508,38.112) 68.689,38.112 68.689,38.139 cw(c68.871,38.139) 69.052,38.139 69.052,38.112 ccw(c69.234,38.112) 69.416,38.112 69.416,38.139 cw(c69.597,38.139) 69.779,38.139 69.779,38.112 ccw(c69.96,38.112) 70.142,38.112 70.142,38.139 cw(c70.324,38.139) 70.505,38.139 70.505,38.112 ccw(c70.687,38.112) 70.687,37.93 73.835,37.93 75.483,37.93 75.562,38.01 75.562,38.119 75.365,38.316 v6(75.365,38.428) ; JOMEGA.30@55.036,41.6 55.036,41.643 JOMEGA.30@55.036,42.35 ; JOMEGA.30@55.078,41.632 55.078,42.35 JOMEGA.30@55.078,42.393
USB1_SSTX_26_N: C280.1 U24.B15 | length 4
  TOP_L1 w0.109: U24.B15@76.516,36.499 76.454,36.562 76.454,36.804 76.696,37.047 76.696,37.685 78.102,39.091 78.102,39.517 78.31,39.725 C280.1@78.325,39.725
USB1_SSTX_26_P: C113.1 U24.A17 | length 3.1
  TOP_L1 w0.109: U24.A17@76.391,37.349 76.391,37.811 77.798,39.217 77.798,39.517 77.59,39.725 C113.1@77.575,39.725
USB2_CAP_SSTX_N: C284.2 D79.5 D79.6 J7.17 | length 6.2
  TOP_L1 w0.109: C284.2@80.975,36.975 81.074,37.073 81.074,37.155 81.123,37.203 81.123,37.521 81.429,37.827 82.228,37.827 82.28,37.88 82.593,37.88 D79.6@82.638,37.925 D79.5@83.513,37.925 83.559,37.88 83.872,37.88 83.924,37.827 84.194,37.827 85.636,37.827 85.7,37.891 J7.17@85.7,38.675
USB2_CAP_SSTX_P: C283.2 D79.4 D79.7 J7.18 | length 5.7
  TOP_L1 w0.109: C283.2@81.575,36.975 81.476,37.073 81.476,37.155 81.427,37.203 81.427,37.395 81.555,37.523 82.228,37.523 82.28,37.47 82.593,37.47 D79.7@82.638,37.425 D79.4@83.513,37.425 83.559,37.47 83.872,37.47 83.924,37.523 84.32,37.523 85.636,37.523 85.7,37.459 J7.18@85.7,36.675
USB2_D_N: D78.1 D78.10 J7.11 U24.A13 | length 18.3
  TOP_L1 w0.109: v1(78.591,36.449) U24.A13@79.091,36.449 ; D78.1@83.392,41.675 D78.10@82.638,41.675 82.401,41.675 82.303,41.773 82.123,41.773 82.059,41.709 82.059,41.316 82.3,41.075 83.188,41.075 83.857,40.406 83.857,40.138 83.877,40.118 83.877,40.031 v1(83.904,40.004) ; D78.1@83.513,41.675 83.559,41.72 83.935,41.72 83.989,41.775 84.099,41.775 84.163,41.711 84.163,40.765 84.405,40.523 84.659,40.523 85.343,39.839 87.036,39.839 J7.11@87.2,39.675
  L3 w0.104: v1(78.591,36.449) 78.552,36.449 78.492,36.389 78.371,36.389 78.31,36.45 78.31,36.966 79.02,37.676 79.489,38.145 79.662,38.145 79.699,38.109 79.872,38.109 80.132,38.369 80.132,38.542 80.095,38.578 80.095,38.751 80.25,38.906 80.588,38.906 83.166,38.906 83.857,39.597 83.857,39.87 83.876,39.89 83.876,39.976 v1(83.904,40.004)
  other v2: 78.591,36.449 83.904,40.004
USB2_D_P: D78.2 D78.9 J7.12 U24.B12 | length 18.3
  TOP_L1 w0.109: D78.2@83.392,42.175 D78.9@82.638,42.175 82.401,42.175 82.303,42.077 81.997,42.077 81.754,41.835 81.754,41.19 82.174,40.77 83.062,40.77 83.552,40.28 83.552,40.138 83.531,40.118 83.531,40.031 v1(83.504,40.004) ; D78.2@83.513,42.175 83.921,42.175 83.972,42.124 84.181,42.124 84.467,41.837 84.467,40.891 84.531,40.827 84.691,40.827 85.375,41.511 87.036,41.511 J7.12@87.2,41.675
  L3 w0.104: v1(78.241,35.874) 78.254,35.886 78.254,36.076 78.005,36.324 78.005,37.093 80.124,39.211 83.04,39.211 83.552,39.723 83.552,39.87 83.532,39.89 83.532,39.976 v1(83.504,40.004)
  other v2: 78.241,35.874 83.504,40.004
